          <addressOffset>0x4ac</addressOffset>
          <size>0x20</size>
        </register>
        <register>
          <name>FGCLUT.44</name>
          <addressOffset>0x4b0</addressOffset>
          <size>0x20</size>
        </register>
        <register>
          <name>FGCLUT.45</name>
          <addressOffset>0x4b4</addressOffset>
          <size>0x20</size>
        </register>
        <register>
          <name>FGCLUT.46</name>
          <addressOffset>0x4b8</addressOffset>
          <size>0x20</size>
        </register>
        <register>
          <name>FGCLUT.47</name>
          <addressOffset>0x4bc</addressOffset>
          <size>0x20</size>
        </register>
        <register>
          <name>FGCLUT.48</name>
          <addressOffset>0x4c0</addressOffset>
          <size>0x20</size>
        </register>
        <register>
          <name>FGCLUT.49</name>
          <addressOffset>0x4c4</addressOffset>
          <size>0x20</size>
        </register>
        <register>
          <name>FGCLUT.50</name>
          <addressOffset>0x4c8</addressOffset>
          <size>0x20</size>
        </register>
        <register>
          <name>FGCLUT.51</name>
          <addressOffset>0x4cc</addressOffset>
          <size>0x20</size>
        </register>
        <register>
          <name>FGCLUT.52</name>
          <addressOffset>0x4d0</addressOffset>
          <size>0x20</size>
        </register>
        <register>
          <name>FGCLUT.53</name>
          <addressOffset>0x4d4</addressOffset>
          <size>0x20</size>
        </register>
        <register>
          <name>FGCLUT.54</name>
          <addressOffset>0x4d8</addressOffset>
          <size>0x20</size>
        </register>
        <register>
          <name>FGCLUT.55</name>
          <addressOffset>0x4dc</addressOffset>
          <size>0x20</size>
        </register>
        <register>
          <name>FGCLUT.56</name>
          <addressOffset>0x4e0</addressOffset>
          <size>0x20</size>
        </register>
        <register>
          <name>FGCLUT.57</name>
          <addressOffset>0x4e4</addressOffset>
          <size>0x20</size>
        </register>
        <register>
          <name>FGCLUT.58</name>
          <addressOffset>0x4e8</addressOffset>
          <size>0x20</size>
        </register>
        <register>
          <name>FGCLUT.59</name>
          <addressOffset>0x4ec</addressOffset>
          <size>0x20</size>
        </register>
        <register>
          <name>FGCLUT.60</name>
          <addressOffset>0x4f0</addressOffset>
          <size>0x20</size>
        </register>
        <register>
          <name>FGCLUT.61</name>
          <addressOffset>0x4f4</addressOffset>
          <size>0x20</size>
        </register>
        <register>
          <name>FGCLUT.62</name>
          <addressOffset>0x4f8</addressOffset>
          <size>0x20</size>
        </register>
        <register>
          <name>FGCLUT.63</name>
          <addressOffset>0x4fc</addressOffset>
          <size>0x20</size>
        </register>
        <register>
          <name>FGCLUT.64</name>
          <addressOffset>0x500</addressOffset>
          <size>0x20</size>
        </register>
        <register>
          <name>FGCLUT.65</name>
          <addressOffset>0x504</addressOffset>
          <size>0x20</size>
        </register>
        <register>
          <name>FGCLUT.66</name>
          <addressOffset>0x508</addressOffset>
          <size>0x20</size>
        </register>
        <register>
          <name>FGCLUT.67</name>
          <addressOffset>0x50c</addressOffset>
          <size>0x20</size>
        </register>
        <register>
          <name>FGCLUT.68</name>
          <addressOffset>0x510</addressOffset>
          <size>0x20</size>
        </register>
        <register>
          <name>FGCLUT.69</name>
          <addressOffset>0x514</addressOffset>
          <size>0x20</size>
        </register>
        <register>
          <name>FGCLUT.70</name>
          <addressOffset>0x518</addressOffset>
          <size>0x20</size>
        </register>
        <register>
          <name>FGCLUT.71</name>
          <addressOffset>0x51c</addressOffset>
          <size>0x20</size>
        </register>
        <register>
          <name>FGCLUT.72</name>
          <addressOffset>0x520</addressOffset>
          <size>0x20</size>
        </register>
        <register>
          <name>FGCLUT.73</name>
          <addressOffset>0x524</addressOffset>
          <size>0x20</size>
        </register>
        <register>
          <name>FGCLUT.74</name>
          <addressOffset>0x528</addressOffset>
          <size>0x20</size>
        </register>
        <register>
          <name>FGCLUT.75</name>
          <addressOffset>0x52c</addressOffset>
          <size>0x20</size>
        </register>
        <register>
          <name>FGCLUT.76</name>
          <addressOffset>0x530</addressOffset>
          <size>0x20</size>
        </register>
        <register>
          <name>FGCLUT.77</name>
          <addressOffset>0x534</addressOffset>
          <size>0x20</size>
        </register>
        <register>
          <name>FGCLUT.78</name>
          <addressOffset>0x538</addressOffset>
          <size>0x20</size>
        </register>
        <register>
          <name>FGCLUT.79</name>
          <addressOffset>0x53c</addressOffset>
          <size>0x20</size>
        </register>
        <register>
          <name>FGCLUT.80</name>
          <addressOffset>0x540</addressOffset>
          <size>0x20</size>
        </register>
        <register>
          <name>FGCLUT.81</name>
          <addressOffset>0x544</addressOffset>
          <size>0x20</size>
        </register>
        <register>
          <name>FGCLUT.82</name>
          <addressOffset>0x548</addressOffset>
          <size>0x20</size>
        </register>
        <register>
          <name>FGCLUT.83</name>
          <addressOffset>0x54c</addressOffset>
          <size>0x20</size>
        </register>
        <register>
          <name>FGCLUT.84</name>
          <addressOffset>0x550</addressOffset>
          <size>0x20</size>
        </register>
        <register>
          <name>FGCLUT.85</name>
          <addressOffset>0x554</addressOffset>
          <size>0x20</size>
        </register>
        <register>
          <name>FGCLUT.86</name>
          <addressOffset>0x558</addressOffset>
          <size>0x20</size>
        </register>
        <register>
          <name>FGCLUT.87</name>
          <addressOffset>0x55c</addressOffset>
          <size>0x20</size>
        </register>
        <register>
          <name>FGCLUT.88</name>
          <addressOffset>0x560</addressOffset>
          <size>0x20</size>
        </register>
        <register>
          <name>FGCLUT.89</name>
          <addressOffset>0x564</addressOffset>
          <size>0x20</size>
        </register>
        <register>
          <name>FGCLUT.90</name>
          <addressOffset>0x568</addressOffset>
          <size>0x20</size>
        </register>
        <register>
          <name>FGCLUT.91</name>
          <addressOffset>0x56c</addressOffset>
          <size>0x20</size>
        </register>
        <register>
          <name>FGCLUT.92</name>
          <addressOffset>0x570</addressOffset>
          <size>0x20</size>
        </register>
        <register>
          <name>FGCLUT.93</name>
          <addressOffset>0x574</addressOffset>
          <size>0x20</size>
        </register>
        <register>
          <name>FGCLUT.94</name>
          <addressOffset>0x578</addressOffset>
          <size>0x20</size>
        </register>
        <register>
          <name>FGCLUT.95</name>
          <addressOffset>0x57c</addressOffset>
          <size>0x20</size>
        </register>
        <register>
          <name>FGCLUT.96</name>
          <addressOffset>0x580</addressOffset>
          <size>0x20</size>
        </register>
        <register>
          <name>FGCLUT.97</name>
          <addressOffset>0x584</addressOffset>
          <size>0x20</size>
        </register>
        <register>
          <name>FGCLUT.98</name>
          <addressOffset>0x588</addressOffset>
          <size>0x20</size>
        </register>
        <register>
          <name>FGCLUT.99</name>
          <addressOffset>0x58c</addressOffset>
          <size>0x20</size>
        </register>
        <register>
          <name>FGCLUT.100</name>
          <addressOffset>0x590</addressOffset>
          <size>0x20</size>
        </register>
        <register>
          <name>FGCLUT.101</name>
          <addressOffset>0x594</addressOffset>
          <size>0x20</size>
        </register>
        <register>
          <name>FGCLUT.102</name>
          <addressOffset>0x598</addressOffset>
          <size>0x20</size>
        </register>
        <register>
          <name>FGCLUT.103</name>
          <addressOffset>0x59c</addressOffset>
          <size>0x20</size>
        </register>
        <register>
          <name>FGCLUT.104</name>
          <addressOffset>0x5a0</addressOffset>
          <size>0x20</size>
        </register>
        <register>
          <name>FGCLUT.105</name>
          <addressOffset>0x5a4</addressOffset>
          <size>0x20</size>
        </register>
        <register>
          <name>FGCLUT.106</name>
          <addressOffset>0x5a8</addressOffset>
          <size>0x20</size>
        </register>
        <register>
          <name>FGCLUT.107</name>
          <addressOffset>0x5ac</addressOffset>
          <size>0x20</size>
        </register>
        <register>
          <name>FGCLUT.108</name>
          <addressOffset>0x5b0</addressOffset>
          <size>0x20</size>
        </register>
        <register>
          <name>FGCLUT.109</name>
          <addressOffset>0x5b4</addressOffset>
          <size>0x20</size>
        </register>
        <register>
          <name>FGCLUT.110</name>
          <addressOffset>0x5b8</addressOffset>
          <size>0x20</size>
        </register>
        <register>
          <name>FGCLUT.111</name>
          <addressOffset>0x5bc</addressOffset>
          <size>0x20</size>
        </register>
        <register>
          <name>FGCLUT.112</name>
          <addressOffset>0x5c0</addressOffset>
          <size>0x20</size>
        </register>
        <register>
          <name>FGCLUT.113</name>
          <addressOffset>0x5c4</addressOffset>
          <size>0x20</size>
        </register>
        <register>
          <name>FGCLUT.114</name>
          <addressOffset>0x5c8</addressOffset>
          <size>0x20</size>
        </register>
        <register>
          <name>FGCLUT.115</name>
          <addressOffset>0x5cc</addressOffset>
          <size>0x20</size>
        </register>
        <register>
          <name>FGCLUT.116</name>
          <addressOffset>0x5d0</addressOffset>
          <size>0x20</size>
        </register>
        <register>
          <name>FGCLUT.117</name>
          <addressOffset>0x5d4</addressOffset>
          <size>0x20</size>
        </register>
        <register>
          <name>FGCLUT.118</name>
          <addressOffset>0x5d8</addressOffset>
          <size>0x20</size>
        </register>
        <register>
          <name>FGCLUT.119</name>
          <addressOffset>0x5dc</addressOffset>
          <size>0x20</size>
        </register>
        <register>
          <name>FGCLUT.120</name>
          <addressOffset>0x5e0</addressOffset>
          <size>0x20</size>
        </register>
        <register>
          <name>FGCLUT.121</name>
          <addressOffset>0x5e4</addressOffset>
          <size>0x20</size>
        </register>
        <register>
          <name>FGCLUT.122</name>
          <addressOffset>0x5e8</addressOffset>
          <size>0x20</size>
        </register>
        <register>
          <name>FGCLUT.123</name>
          <addressOffset>0x5ec</addressOffset>
          <size>0x20</size>
        </register>
        <register>
          <name>FGCLUT.124</name>
          <addressOffset>0x5f0</addressOffset>
          <size>0x20</size>
        </register>
        <register>
          <name>FGCLUT.125</name>
          <addressOffset>0x5f4</addressOffset>
          <size>0x20</size>
        </register>
        <register>
          <name>FGCLUT.126</name>
          <addressOffset>0x5f8</addressOffset>
          <size>0x20</size>
        </register>
        <register>
          <name>FGCLUT.127</name>
          <addressOffset>0x5fc</addressOffset>
          <size>0x20</size>
        </register>
        <register>
          <name>FGCLUT.128</name>
          <addressOffset>0x600</addressOffset>
          <size>0x20</size>
        </register>
        <register>
          <name>FGCLUT.129</name>
          <addressOffset>0x604</addressOffset>
          <size>0x20</size>
        </register>
        <register>
          <name>FGCLUT.130</name>
          <addressOffset>0x608</addressOffset>
          <size>0x20</size>
        </register>
        <register>
          <name>FGCLUT.131</name>
          <addressOffset>0x60c</addressOffset>
          <size>0x20</size>
        </register>
        <register>
          <name>FGCLUT.132</name>
          <addressOffset>0x610</addressOffset>
          <size>0x20</size>
        </register>
        <register>
          <name>FGCLUT.133</name>
          <addressOffset>0x614</addressOffset>
          <size>0x20</size>
        </register>
        <register>
          <name>FGCLUT.134</name>
          <addressOffset>0x618</addressOffset>
          <size>0x20</size>
        </register>
        <register>
          <name>FGCLUT.135</name>
          <addressOffset>0x61c</addressOffset>
          <size>0x20</size>
        </register>
        <register>
          <name>FGCLUT.136</name>
          <addressOffset>0x620</addressOffset>
          <size>0x20</size>
        </register>
        <register>
          <name>FGCLUT.137</name>
          <addressOffset>0x624</addressOffset>
          <size>0x20</size>
        </register>
        <register>
          <name>FGCLUT.138</name>
          <addressOffset>0x628</addressOffset>
          <size>0x20</size>
        </register>
        <register>
          <name>FGCLUT.139</name>
          <addressOffset>0x62c</addressOffset>
          <size>0x20</size>
        </register>
        <register>
          <name>FGCLUT.140</name>
          <addressOffset>0x630</addressOffset>
          <size>0x20</size>
        </register>
        <register>
          <name>FGCLUT.141</name>
          <addressOffset>0x634</addressOffset>
          <size>0x20</size>
        </register>
        <register>
          <name>FGCLUT.142</name>
          <addressOffset>0x638</addressOffset>
          <size>0x20</size>
        </register>
        <register>
          <name>FGCLUT.143</name>
          <addressOffset>0x63c</addressOffset>
          <size>0x20</size>
        </register>
        <register>
          <name>FGCLUT.144</name>
          <addressOffset>0x640</addressOffset>
          <size>0x20</size>
        </register>
        <register>
          <name>FGCLUT.145</name>
          <addressOffset>0x644</addressOffset>
          <size>0x20</size>
        </register>
        <register>
          <name>FGCLUT.146</name>
          <addressOffset>0x648</addressOffset>
          <size>0x20</size>
        </register>
        <register>
          <name>FGCLUT.147</name>
          <addressOffset>0x64c</addressOffset>
          <size>0x20</size>
        </register>
        <register>
          <name>FGCLUT.148</name>
          <addressOffset>0x650</addressOffset>
          <size>0x20</size>
        </register>
        <register>
          <name>FGCLUT.149</name>
          <addressOffset>0x654</addressOffset>
          <size>0x20</size>
        </register>
        <register>
          <name>FGCLUT.150</name>
          <addressOffset>0x658</addressOffset>
          <size>0x20</size>
        </register>
        <register>
          <name>FGCLUT.151</name>
          <addressOffset>0x65c</addressOffset>
          <size>0x20</size>
        </register>
        <register>
          <name>FGCLUT.152</name>
          <addressOffset>0x660</addressOffset>
          <size>0x20</size>
        </register>
        <register>
          <name>FGCLUT.153</name>
          <addressOffset>0x664</addressOffset>
          <size>0x20</size>
        </register>
        <register>
          <name>FGCLUT.154</name>
          <addressOffset>0x668</addressOffset>
          <size>0x20</size>
        </register>
        <register>
          <name>FGCLUT.155</name>
          <addressOffset>0x66c</addressOffset>
          <size>0x20</size>
        </register>
        <register>
          <name>FGCLUT.156</name>
          <addressOffset>0x670</addressOffset>
          <size>0x20</size>
        </register>
        <register>
          <name>FGCLUT.157</name>
          <addressOffset>0x674</addressOffset>
          <size>0x20</size>
        </register>
        <register>
          <name>FGCLUT.158</name>
          <addressOffset>0x678</addressOffset>
          <size>0x20</size>
        </register>
        <register>
          <name>FGCLUT.159</name>
          <addressOffset>0x67c</addressOffset>
          <size>0x20</size>
        </register>
        <register>
          <name>FGCLUT.160</name>
          <addressOffset>0x680</addressOffset>
          <size>0x20</size>
        </register>
        <register>
          <name>FGCLUT.161</name>
          <addressOffset>0x684</addressOffset>
          <size>0x20</size>
        </register>
        <register>
          <name>FGCLUT.162</name>
          <addressOffset>0x688</addressOffset>
          <size>0x20</size>
        </register>
        <register>
          <name>FGCLUT.163</name>
          <addressOffset>0x68c</addressOffset>
          <size>0x20</size>
        </register>
        <register>
          <name>FGCLUT.164</name>
          <addressOffset>0x690</addressOffset>
          <size>0x20</size>
        </register>
        <register>
          <name>FGCLUT.165</name>
          <addressOffset>0x694</addressOffset>
          <size>0x20</size>
        </register>
        <register>
          <name>FGCLUT.166</name>
          <addressOffset>0x698</addressOffset>
          <size>0x20</size>
        </register>
        <register>
          <name>FGCLUT.167</name>
          <addressOffset>0x69c</addressOffset>
          <size>0x20</size>
        </register>
        <register>
          <name>FGCLUT.168</name>
          <addressOffset>0x6a0</addressOffset>
          <size>0x20</size>
        </register>
        <register>
          <name>FGCLUT.169</name>
          <addressOffset>0x6a4</addressOffset>
          <size>0x20</size>
        </register>
        <register>
          <name>FGCLUT.170</name>
          <addressOffset>0x6a8</addressOffset>
          <size>0x20</size>
        </register>
        <register>
          <name>FGCLUT.171</name>
          <addressOffset>0x6ac</addressOffset>
          <size>0x20</size>
        </register>
        <register>
          <name>FGCLUT.172</name>
          <addressOffset>0x6b0</addressOffset>
          <size>0x20</size>
        </register>
        <register>
          <name>FGCLUT.173</name>
          <addressOffset>0x6b4</addressOffset>
          <size>0x20</size>
        </register>
        <register>
          <name>FGCLUT.174</name>
          <addressOffset>0x6b8</addressOffset>
          <size>0x20</size>
        </register>
        <register>
          <name>FGCLUT.175</name>
          <addressOffset>0x6bc</addressOffset>
          <size>0x20</size>
        </register>
        <register>
          <name>FGCLUT.176</name>
          <addressOffset>0x6c0</addressOffset>
          <size>0x20</size>
        </register>
        <register>
          <name>FGCLUT.177</name>
          <addressOffset>0x6c4</addressOffset>
          <size>0x20</size>
        </register>
        <register>
          <name>FGCLUT.178</name>
          <addressOffset>0x6c8</addressOffset>
          <size>0x20</size>
        </register>
        <register>
          <name>FGCLUT.179</name>
          <addressOffset>0x6cc</addressOffset>
          <size>0x20</size>
        </register>
        <register>
          <name>FGCLUT.180</name>
          <addressOffset>0x6d0</addressOffset>
          <size>0x20</size>
        </register>
        <register>
          <name>FGCLUT.181</name>
          <addressOffset>0x6d4</addressOffset>
          <size>0x20</size>
        </register>
        <register>
          <name>FGCLUT.182</name>
          <addressOffset>0x6d8</addressOffset>
          <size>0x20</size>
        </register>
        <register>
          <name>FGCLUT.183</name>
          <addressOffset>0x6dc</addressOffset>
          <size>0x20</size>
        </register>
        <register>
          <name>FGCLUT.184</name>
          <addressOffset>0x6e0</addressOffset>
          <size>0x20</size>
        </register>
        <register>
          <name>FGCLUT.185</name>
          <addressOffset>0x6e4</addressOffset>
          <size>0x20</size>
        </register>
        <register>
          <name>FGCLUT.186</name>
          <addressOffset>0x6e8</addressOffset>
          <size>0x20</size>
        </register>
        <register>
          <name>FGCLUT.187</name>
          <addressOffset>0x6ec</addressOffset>
          <size>0x20</size>
        </register>
        <register>
          <name>FGCLUT.188</name>
          <addressOffset>0x6f0</addressOffset>
          <size>0x20</size>
        </register>
        <register>
          <name>FGCLUT.189</name>
          <addressOffset>0x6f4</addressOffset>
          <size>0x20</size>
        </register>
        <register>
          <name>FGCLUT.190</name>
          <addressOffset>0x6f8</addressOffset>
          <size>0x20</size>
        </register>
        <register>
          <name>FGCLUT.191</name>
          <addressOffset>0x6fc</addressOffset>
          <size>0x20</size>
        </register>
        <register>
          <name>FGCLUT.192</name>
          <addressOffset>0x700</addressOffset>
          <size>0x20</size>
        </register>
        <register>
          <name>FGCLUT.193</name>
          <addressOffset>0x704</addressOffset>
          <size>0x20</size>
        </register>
        <register>
          <name>FGCLUT.194</name>
          <addressOffset>0x708</addressOffset>
          <size>0x20</size>
        </register>
        <register>
          <name>FGCLUT.195</name>
          <addressOffset>0x70c</addressOffset>
          <size>0x20</size>
        </register>
        <register>
          <name>FGCLUT.196</name>
          <addressOffset>0x710</addressOffset>
          <size>0x20</size>
        </register>
        <register>
          <name>FGCLUT.197</name>
          <addressOffset>0x714</addressOffset>
          <size>0x20</size>
        </register>
        <register>
          <name>FGCLUT.198</name>
          <addressOffset>0x718</addressOffset>
          <size>0x20</size>
        </register>
        <register>
          <name>FGCLUT.199</name>
          <addressOffset>0x71c</addressOffset>
          <size>0x20</size>
        </register>
        <register>
          <name>FGCLUT.200</name>
          <addressOffset>0x720</addressOffset>
          <size>0x20</size>
        </register>
        <register>
          <name>FGCLUT.201</name>
          <addressOffset>0x724</addressOffset>
          <size>0x20</size>
        </register>
        <register>
          <name>FGCLUT.202</name>
          <addressOffset>0x728</addressOffset>
          <size>0x20</size>
        </register>
        <register>
          <name>FGCLUT.203</name>
          <addressOffset>0x72c</addressOffset>
          <size>0x20</size>
        </register>
        <register>
          <name>FGCLUT.204</name>
          <addressOffset>0x730</addressOffset>
          <size>0x20</size>
        </register>
        <register>
          <name>FGCLUT.205</name>
          <addressOffset>0x734</addressOffset>
          <size>0x20</size>
        </register>
        <register>
          <name>FGCLUT.206</name>
          <addressOffset>0x738</addressOffset>
          <size>0x20</size>
        </register>
        <register>
          <name>FGCLUT.207</name>
          <addressOffset>0x73c</addressOffset>
          <size>0x20</size>
        </register>
        <register>
          <name>FGCLUT.208</name>
          <addressOffset>0x740</addressOffset>
          <size>0x20</size>
        </register>
        <register>
          <name>FGCLUT.209</name>
          <addressOffset>0x744</addressOffset>
          <size>0x20</size>
        </register>
        <register>
          <name>FGCLUT.210</name>
          <addressOffset>0x748</addressOffset>
          <size>0x20</size>
        </register>
        <register>
          <name>FGCLUT.211</name>
          <addressOffset>0x74c</addressOffset>
          <size>0x20</size>
        </register>
        <register>
          <name>FGCLUT.212</name>
          <addressOffset>0x750</addressOffset>
          <size>0x20</size>
        </register>
        <register>
          <name>FGCLUT.213</name>
          <addressOffset>0x754</addressOffset>
          <size>0x20</size>
        </register>
        <register>
          <name>FGCLUT.214</name>
          <addressOffset>0x758</addressOffset>
          <size>0x20</size>
        </register>
        <register>
          <name>FGCLUT.215</name>
          <addressOffset>0x75c</addressOffset>
          <size>0x20</size>
        </register>
        <register>
          <name>FGCLUT.216</name>
          <addressOffset>0x760</addressOffset>
          <size>0x20</size>
        </register>
        <register>
          <name>FGCLUT.217</name>
          <addressOffset>0x764</addressOffset>
          <size>0x20</size>
        </register>
        <register>
          <name>FGCLUT.218</name>
          <addressOffset>0x768</addressOffset>
          <size>0x20</size>
        </register>
        <register>
          <name>FGCLUT.219</name>
          <addressOffset>0x76c</addressOffset>
          <size>0x20</size>
        </register>
        <register>
          <name>FGCLUT.220</name>
          <addressOffset>0x770</addressOffset>
          <size>0x20</size>
        </register>
        <register>
          <name>FGCLUT.221</name>
          <addressOffset>0x774</addressOffset>
          <size>0x20</size>
        </register>
        <register>
          <name>FGCLUT.222</name>
          <addressOffset>0x778</addressOffset>
          <size>0x20</size>
        </register>
        <register>
          <name>FGCLUT.223</name>
          <addressOffset>0x77c</addressOffset>
          <size>0x20</size>
        </register>
        <register>
          <name>FGCLUT.224</name>
          <addressOffset>0x780</addressOffset>
          <size>0x20</size>
        </register>
        <register>
          <name>FGCLUT.225</name>
          <addressOffset>0x784</addressOffset>
          <size>0x20</size>
        </register>
        <register>
          <name>FGCLUT.226</name>
          <addressOffset>0x788</addressOffset>
          <size>0x20</size>
        </register>
        <register>
          <name>FGCLUT.227</name>
          <addressOffset>0x78c</addressOffset>
          <size>0x20</size>
        </register>
        <register>
          <name>FGCLUT.228</name>
          <addressOffset>0x790</addressOffset>
          <size>0x20</size>
        </register>
        <register>
          <name>FGCLUT.229</name>
          <addressOffset>0x794</addressOffset>
          <size>0x20</size>
        </register>
        <register>
          <name>FGCLUT.230</name>
          <addressOffset>0x798</addressOffset>
          <size>0x20</size>
        </register>
        <register>
          <name>FGCLUT.231</name>
          <addressOffset>0x79c</addressOffset>
          <size>0x20</size>
        </register>
        <register>
          <name>FGCLUT.232</name>
          <addressOffset>0x7a0</addressOffset>
          <size>0x20</size>
        </register>
        <register>
          <name>FGCLUT.233</name>
          <addressOffset>0x7a4</addressOffset>
          <size>0x20</size>
        </register>
        <register>
          <name>FGCLUT.234</name>
          <addressOffset>0x7a8</addressOffset>
          <size>0x20</size>
        </register>
        <register>
          <name>FGCLUT.235</name>
          <addressOffset>0x7ac</addressOffset>
          <size>0x20</size>
        </register>
        <register>
          <name>FGCLUT.236</name>
          <addressOffset>0x7b0</addressOffset>
          <size>0x20</size>
        </register>
        <register>
          <name>FGCLUT.237</name>
          <addressOffset>0x7b4</addressOffset>
          <size>0x20</size>
        </register>
        <register>
          <name>FGCLUT.238</name>
          <addressOffset>0x7b8</addressOffset>
          <size>0x20</size>
        </register>
        <register>
          <name>FGCLUT.239</name>
          <addressOffset>0x7bc</addressOffset>
          <size>0x20</size>
        </register>
        <register>
          <name>FGCLUT.240</name>
          <addressOffset>0x7c0</addressOffset>
          <size>0x20</size>
        </register>
        <register>
          <name>FGCLUT.241</name>
          <addressOffset>0x7c4</addressOffset>
          <size>0x20</size>
        </register>
        <register>
          <name>FGCLUT.242</name>
          <addressOffset>0x7c8</addressOffset>
          <size>0x20</size>
        </register>
        <register>
          <name>FGCLUT.243</name>
          <addressOffset>0x7cc</addressOffset>
          <size>0x20</size>
        </register>
        <register>
          <name>FGCLUT.244</name>
          <addressOffset>0x7d0</addressOffset>
          <size>0x20</size>
        </register>
        <register>
          <name>FGCLUT.245</name>
          <addressOffset>0x7d4</addressOffset>
          <size>0x20</size>
        </register>
        <register>
          <name>FGCLUT.246</name>
          <addressOffset>0x7d8</addressOffset>
          <size>0x20</size>
        </register>
        <register>
          <name>FGCLUT.247</name>
          <addressOffset>0x7dc</addressOffset>
          <size>0x20</size>
        </register>
        <register>
          <name>FGCLUT.248</name>
          <addressOffset>0x7e0</addressOffset>
          <size>0x20</size>
        </register>
        <register>
          <name>FGCLUT.249</name>
          <addressOffset>0x7e4</addressOffset>
          <size>0x20</size>
        </register>
        <register>
          <name>FGCLUT.250</name>
          <addressOffset>0x7e8</addressOffset>
          <size>0x20</size>
        </register>
        <register>
          <name>FGCLUT.251</name>
          <addressOffset>0x7ec</addressOffset>
          <size>0x20</size>
        </register>
        <register>
          <name>FGCLUT.252</name>
          <addressOffset>0x7f0</addressOffset>
          <size>0x20</size>
        </register>
        <register>
          <name>FGCLUT.253</name>
          <addressOffset>0x7f4</addressOffset>
          <size>0x20</size>
        </register>
        <register>
          <name>FGCLUT.254</name>
          <addressOffset>0x7f8</addressOffset>
          <size>0x20</size>
        </register>
        <register>
          <name>FGCLUT.255</name>
          <addressOffset>0x7fc</addressOffset>
          <size>0x20</size>
        </register>
        <register>
          <name>BGCLUT.0</name>
          <addressOffset>0x800</addressOffset>
          <size>0x20</size>
        </register>
        <register>
          <name>BGCLUT.1</name>
          <addressOffset>0x804</addressOffset>
          <size>0x20</size>
        </register>
        <register>
          <name>BGCLUT.2</name>
          <addressOffset>0x808</addressOffset>
          <size>0x20</size>
        </register>
        <register>
          <name>BGCLUT.3</name>
          <addressOffset>0x80c</addressOffset>
          <size>0x20</size>
        </register>
        <register>
          <name>BGCLUT.4</name>
          <addressOffset>0x810</addressOffset>
          <size>0x20</size>
        </register>
        <register>
          <name>BGCLUT.5</name>
          <addressOffset>0x814</addressOffset>
          <size>0x20</size>
        </register>
        <register>
          <name>BGCLUT.6</name>
          <addressOffset>0x818</addressOffset>
          <size>0x20</size>
        </register>
        <register>
          <name>BGCLUT.7</name>
          <addressOffset>0x81c</addressOffset>
          <size>0x20</size>
        </register>
        <register>
          <name>BGCLUT.8</name>
          <addressOffset>0x820</addressOffset>
          <size>0x20</size>
        </register>
        <register>
          <name>BGCLUT.9</name>
          <addressOffset>0x824</addressOffset>
          <size>0x20</size>
        </register>
        <register>
          <name>BGCLUT.10</name>
          <addressOffset>0x828</addressOffset>
          <size>0x20</size>
        </register>
        <register>
          <name>BGCLUT.11</name>
          <addressOffset>0x82c</addressOffset>
          <size>0x20</size>
        </register>
        <register>
          <name>BGCLUT.12</name>
          <addressOffset>0x830</addressOffset>
          <size>0x20</size>
        </register>
        <register>
          <name>BGCLUT.13</name>
          <addressOffset>0x834</addressOffset>
          <size>0x20</size>
        </register>
        <register>
          <name>BGCLUT.14</name>
          <addressOffset>0x838</addressOffset>
          <size>0x20</size>
        </register>
        <register>
          <name>BGCLUT.15</name>
          <addressOffset>0x83c</addressOffset>
          <size>0x20</size>
        </register>
        <register>
          <name>BGCLUT.16</name>
          <addressOffset>0x840</addressOffset>
          <size>0x20</size>
        </register>
        <register>
          <name>BGCLUT.17</name>
          <addressOffset>0x844</addressOffset>
          <size>0x20</size>
        </register>
        <register>
          <name>BGCLUT.18</name>
          <addressOffset>0x848</addressOffset>
          <size>0x20</size>
        </register>
        <register>
          <name>BGCLUT.19</name>
          <addressOffset>0x84c</addressOffset>
          <size>0x20</size>
        </register>
        <register>
          <name>BGCLUT.20</name>
          <addressOffset>0x850</addressOffset>
          <size>0x20</size>
        </register>
        <register>
          <name>BGCLUT.21</name>
          <addressOffset>0x854</addressOffset>
          <size>0x20</size>
        </register>
        <register>
          <name>BGCLUT.22</name>
          <addressOffset>0x858</addressOffset>
          <size>0x20</size>
        </register>
        <register>
          <name>BGCLUT.23</name>
          <addressOffset>0x85c</addressOffset>
          <size>0x20</size>
        </register>
        <register>
          <name>BGCLUT.24</name>
          <addressOffset>0x860</addressOffset>
          <size>0x20</size>
        </register>
        <register>
          <name>BGCLUT.25</name>
          <addressOffset>0x864</addressOffset>
          <size>0x20</size>
        </register>
        <register>
          <name>BGCLUT.26</name>
          <addressOffset>0x868</addressOffset>
          <size>0x20</size>
        </register>
        <register>
          <name>BGCLUT.27</name>
          <addressOffset>0x86c</addressOffset>
          <size>0x20</size>
        </register>
        <register>
          <name>BGCLUT.28</name>
          <addressOffset>0x870</addressOffset>
          <size>0x20</size>
        </register>
        <register>
          <name>BGCLUT.29</name>
          <addressOffset>0x874</addressOffset>
          <size>0x20</size>
        </register>
        <register>
          <name>BGCLUT.30</name>
          <addressOffset>0x878</addressOffset>
          <size>0x20</size>
        </register>
        <register>
          <name>BGCLUT.31</name>
          <addressOffset>0x87c</addressOffset>
          <size>0x20</size>
        </register>
        <register>
          <name>BGCLUT.32</name>
          <addressOffset>0x880</addressOffset>
          <size>0x20</size>
        </register>
        <register>
          <name>BGCLUT.33</name>
          <addressOffset>0x884</addressOffset>
          <size>0x20</size>
        </register>
        <register>
          <name>BGCLUT.34</name>
          <addressOffset>0x888</addressOffset>
          <size>0x20</size>
        </register>
        <register>
          <name>BGCLUT.35</name>
          <addressOffset>0x88c</addressOffset>
          <size>0x20</size>
        </register>
        <register>
          <name>BGCLUT.36</name>
          <addressOffset>0x890</addressOffset>
          <size>0x20</size>
        </register>
        <register>
          <name>BGCLUT.37</name>
          <addressOffset>0x894</addressOffset>
          <size>0x20</size>
        </register>
        <register>
          <name>BGCLUT.38</name>
          <addressOffset>0x898</addressOffset>
          <size>0x20</size>
        </register>
        <register>
          <name>BGCLUT.39</name>
          <addressOffset>0x89c</addressOffset>
          <size>0x20</size>
        </register>
        <register>
          <name>BGCLUT.40</name>
          <addressOffset>0x8a0</addressOffset>
          <size>0x20</size>
        </register>
        <register>
          <name>BGCLUT.41</name>
          <addressOffset>0x8a4</addressOffset>
          <size>0x20</size>
        </register>
        <register>
          <name>BGCLUT.42</name>
          <addressOffset>0x8a8</addressOffset>
          <size>0x20</size>
        </register>
        <register>
          <name>BGCLUT.43</name>
          <addressOffset>0x8ac</addressOffset>
          <size>0x20</size>
        </register>
        <register>
          <name>BGCLUT.44</name>
          <addressOffset>0x8b0</addressOffset>
          <size>0x20</size>
        </register>
        <register>
          <name>BGCLUT.45</name>
          <addressOffset>0x8b4</addressOffset>
          <size>0x20</size>
        </register>
        <register>
          <name>BGCLUT.46</name>
          <addressOffset>0x8b8</addressOffset>
          <size>0x20</size>
        </register>
        <register>
          <name>BGCLUT.47</name>
          <addressOffset>0x8bc</addressOffset>
          <size>0x20</size>
        </register>
        <register>
          <name>BGCLUT.48</name>
          <addressOffset>0x8c0</addressOffset>
          <size>0x20</size>
        </register>
        <register>
          <name>BGCLUT.49</name>
          <addressOffset>0x8c4</addressOffset>
          <size>0x20</size>
        </register>
        <register>
          <name>BGCLUT.50</name>
          <addressOffset>0x8c8</addressOffset>
          <size>0x20</size>
        </register>
        <register>
          <name>BGCLUT.51</name>
          <addressOffset>0x8cc</addressOffset>
          <size>0x20</size>
        </register>
        <register>
          <name>BGCLUT.52</name>
          <addressOffset>0x8d0</addressOffset>
          <size>0x20</size>
        </register>
        <register>
          <name>BGCLUT.53</name>
          <addressOffset>0x8d4</addressOffset>
          <size>0x20</size>
        </register>
        <register>
          <name>BGCLUT.54</name>
          <addressOffset>0x8d8</addressOffset>
          <size>0x20</size>
        </register>
        <register>
          <name>BGCLUT.55</name>
          <addressOffset>0x8dc</addressOffset>
          <size>0x20</size>
        </register>
        <register>
          <name>BGCLUT.56</name>
          <addressOffset>0x8e0</addressOffset>
          <size>0x20</size>
        </register>
        <register>
          <name>BGCLUT.57</name>
          <addressOffset>0x8e4</addressOffset>
          <size>0x20</size>
        </register>
        <register>
          <name>BGCLUT.58</name>
          <addressOffset>0x8e8</addressOffset>
          <size>0x20</size>
        </register>
        <register>
          <name>BGCLUT.59</name>
          <addressOffset>0x8ec</addressOffset>
          <size>0x20</size>
        </register>
        <register>
          <name>BGCLUT.60</name>
          <addressOffset>0x8f0</addressOffset>
          <size>0x20</size>
        </register>
        <register>
          <name>BGCLUT.61</name>
          <addressOffset>0x8f4</addressOffset>
          <size>0x20</size>
        </register>
        <register>
          <name>BGCLUT.62</name>
          <addressOffset>0x8f8</addressOffset>
          <size>0x20</size>
        </register>
        <register>
          <name>BGCLUT.63</name>
          <addressOffset>0x8fc</addressOffset>
          <size>0x20</size>
        </register>
        <register>
          <name>BGCLUT.64</name>
          <addressOffset>0x900</addressOffset>
          <size>0x20</size>
        </register>
        <register>
          <name>BGCLUT.65</name>
          <addressOffset>0x904</addressOffset>
          <size>0x20</size>
        </register>
        <register>
          <name>BGCLUT.66</name>
          <addressOffset>0x908</addressOffset>
          <size>0x20</size>
        </register>
        <register>
          <name>BGCLUT.67</name>
          <addressOffset>0x90c</addressOffset>
          <size>0x20</size>
        </register>
        <register>
          <name>BGCLUT.68</name>
          <addressOffset>0x910</addressOffset>
          <size>0x20</size>
        </register>
        <register>
          <name>BGCLUT.69</name>
          <addressOffset>0x914</addressOffset>
          <size>0x20</size>
        </register>
        <register>
          <name>BGCLUT.70</name>
          <addressOffset>0x918</addressOffset>
          <size>0x20</size>
        </register>
        <register>
          <name>BGCLUT.71</name>
          <addressOffset>0x91c</addressOffset>
          <size>0x20</size>
        </register>
        <register>
          <name>BGCLUT.72</name>
          <addressOffset>0x920</addressOffset>
          <size>0x20</size>
        </register>
        <register>
          <name>BGCLUT.73</name>
          <addressOffset>0x924</addressOffset>
          <size>0x20</size>
        </register>
        <register>
          <name>BGCLUT.74</name>
          <addressOffset>0x928</addressOffset>
          <size>0x20</size>
        </register>
        <register>
          <name>BGCLUT.75</name>
          <addressOffset>0x92c</addressOffset>
          <size>0x20</size>
        </register>
        <register>
          <name>BGCLUT.76</name>
          <addressOffset>0x930</addressOffset>
          <size>0x20</size>
        </register>
        <register>
          <name>BGCLUT.77</name>
          <addressOffset>0x934</addressOffset>
          <size>0x20</size>
        </register>
        <register>
          <name>BGCLUT.78</name>
          <addressOffset>0x938</addressOffset>
          <size>0x20</size>
        </register>
        <register>
          <name>BGCLUT.79</name>
          <addressOffset>0x93c</addressOffset>
          <size>0x20</size>
        </register>
        <register>
          <name>BGCLUT.80</name>
          <addressOffset>0x940</addressOffset>
          <size>0x20</size>
        </register>
        <register>
          <name>BGCLUT.81</name>
          <addressOffset>0x944</addressOffset>
          <size>0x20</size>
        </register>
        <register>
          <name>BGCLUT.82</name>
          <addressOffset>0x948</addressOffset>
          <size>0x20</size>
        </register>
        <register>
          <name>BGCLUT.83</name>
          <addressOffset>0x94c</addressOffset>
          <size>0x20</size>
        </register>
        <register>
          <name>BGCLUT.84</name>
          <addressOffset>0x950</addressOffset>
          <size>0x20</size>
        </register>
        <register>
          <name>BGCLUT.85</name>
          <addressOffset>0x954</addressOffset>
          <size>0x20</size>
        </register>
        <register>
          <name>BGCLUT.86</name>
          <addressOffset>0x958</addressOffset>
          <size>0x20</size>
        </register>
        <register>
          <name>BGCLUT.87</name>
          <addressOffset>0x95c</addressOffset>
          <size>0x20</size>
        </register>
        <register>
          <name>BGCLUT.88</name>
          <addressOffset>0x960</addressOffset>
          <size>0x20</size>
        </register>
        <register>
          <name>BGCLUT.89</name>
          <addressOffset>0x964</addressOffset>
          <size>0x20</size>
        </register>
        <register>
          <name>BGCLUT.90</name>
          <addressOffset>0x968</addressOffset>
          <size>0x20</size>
        </register>
        <register>
          <name>BGCLUT.91</name>
          <addressOffset>0x96c</addressOffset>
          <size>0x20</size>
        </register>
        <register>
          <name>BGCLUT.92</name>
          <addressOffset>0x970</addressOffset>
          <size>0x20</size>
        </register>
        <register>
          <name>BGCLUT.93</name>
          <addressOffset>0x974</addressOffset>
          <size>0x20</size>
        </register>
        <register>
          <name>BGCLUT.94</name>
          <addressOffset>0x978</addressOffset>
          <size>0x20</size>
        </register>
        <register>
          <name>BGCLUT.95</name>
          <addressOffset>0x97c</addressOffset>
          <size>0x20</size>
        </register>
        <register>
          <name>BGCLUT.96</name>
          <addressOffset>0x980</addressOffset>
          <size>0x20</size>
        </register>
        <register>
          <name>BGCLUT.97</name>
          <addressOffset>0x984</addressOffset>
          <size>0x20</size>
        </register>
        <register>
          <name>BGCLUT.98</name>
          <addressOffset>0x988</addressOffset>
          <size>0x20</size>
        </register>
        <register>
          <name>BGCLUT.99</name>
          <addressOffset>0x98c</addressOffset>
          <size>0x20</size>
        </register>
        <register>
          <name>BGCLUT.100</name>
          <addressOffset>0x990</addressOffset>
          <size>0x20</size>
        </register>
        <register>
          <name>BGCLUT.101</name>
          <addressOffset>0x994</addressOffset>
          <size>0x20</size>
        </register>
        <register>
          <name>BGCLUT.102</name>
          <addressOffset>0x998</addressOffset>
          <size>0x20</size>
        </register>
        <register>
          <name>BGCLUT.103</name>
          <addressOffset>0x99c</addressOffset>
          <size>0x20</size>
        </register>
        <register>
          <name>BGCLUT.104</name>
          <addressOffset>0x9a0</addressOffset>
          <size>0x20</size>
        </register>
        <register>
          <name>BGCLUT.105</name>
          <addressOffset>0x9a4</addressOffset>
          <size>0x20</size>
        </register>
        <register>
          <name>BGCLUT.106</name>
          <addressOffset>0x9a8</addressOffset>
          <size>0x20</size>
        </register>
        <register>
          <name>BGCLUT.107</name>
          <addressOffset>0x9ac</addressOffset>
          <size>0x20</size>
        </register>
        <register>
          <name>BGCLUT.108</name>
          <addressOffset>0x9b0</addressOffset>
          <size>0x20</size>
        </register>
        <register>
          <name>BGCLUT.109</name>
          <addressOffset>0x9b4</addressOffset>
          <size>0x20</size>
        </register>
        <register>
          <name>BGCLUT.110</name>
          <addressOffset>0x9b8</addressOffset>
          <size>0x20</size>
        </register>
        <register>
          <name>BGCLUT.111</name>
          <addressOffset>0x9bc</addressOffset>
          <size>0x20</size>
        </register>
        <register>
          <name>BGCLUT.112</name>
          <addressOffset>0x9c0</addressOffset>
          <size>0x20</size>
        </register>
        <register>
          <name>BGCLUT.113</name>
          <addressOffset>0x9c4</addressOffset>
          <size>0x20</size>
        </register>
        <register>
          <name>BGCLUT.114</name>
          <addressOffset>0x9c8</addressOffset>
          <size>0x20</size>
        </register>
        <register>
          <name>BGCLUT.115</name>
          <addressOffset>0x9cc</addressOffset>
          <size>0x20</size>
        </register>
        <register>
          <name>BGCLUT.116</name>
          <addressOffset>0x9d0</addressOffset>
          <size>0x20</size>
        </register>
        <register>
          <name>BGCLUT.117</name>
          <addressOffset>0x9d4</addressOffset>
          <size>0x20</size>
        </register>
        <register>
          <name>BGCLUT.118</name>
          <addressOffset>0x9d8</addressOffset>
          <size>0x20</size>
        </register>
        <register>
          <name>BGCLUT.119</name>
          <addressOffset>0x9dc</addressOffset>
          <size>0x20</size>
        </register>
        <register>
          <name>BGCLUT.120</name>
          <addressOffset>0x9e0</addressOffset>
          <size>0x20</size>
        </register>
        <register>
          <name>BGCLUT.121</name>
          <addressOffset>0x9e4</addressOffset>
          <size>0x20</size>
        </register>
        <register>
          <name>BGCLUT.122</name>
          <addressOffset>0x9e8</addressOffset>
          <size>0x20</size>
        </register>
        <register>
          <name>BGCLUT.123</name>
          <addressOffset>0x9ec</addressOffset>
          <size>0x20</size>
        </register>
        <register>
          <name>BGCLUT.124</name>
          <addressOffset>0x9f0</addressOffset>
          <size>0x20</size>
        </register>
        <register>
          <name>BGCLUT.125</name>
          <addressOffset>0x9f4</addressOffset>
          <size>0x20</size>
        </register>
        <register>
          <name>BGCLUT.126</name>
          <addressOffset>0x9f8</addressOffset>
          <size>0x20</size>
        </register>
        <register>
          <name>BGCLUT.127</name>
          <addressOffset>0x9fc</addressOffset>
          <size>0x20</size>
        </register>
        <register>
          <name>BGCLUT.128</name>
          <addressOffset>0xa00</addressOffset>
          <size>0x20</size>
        </register>
        <register>
          <name>BGCLUT.129</name>
          <addressOffset>0xa04</addressOffset>
          <size>0x20</size>
        </register>
        <register>
          <name>BGCLUT.130</name>
          <addressOffset>0xa08</addressOffset>
          <size>0x20</size>
        </register>
        <register>
          <name>BGCLUT.131</name>
          <addressOffset>0xa0c</addressOffset>
          <size>0x20</size>
        </register>
        <register>
          <name>BGCLUT.132</name>
          <addressOffset>0xa10</addressOffset>
          <size>0x20</size>
        </register>
        <register>
          <name>BGCLUT.133</name>
          <addressOffset>0xa14</addressOffset>
          <size>0x20</size>
        </register>
        <register>
          <name>BGCLUT.134</name>
          <addressOffset>0xa18</addressOffset>
          <size>0x20</size>
        </register>
        <register>
          <name>BGCLUT.135</name>
          <addressOffset>0xa1c</addressOffset>
          <size>0x20</size>
        </register>
        <register>
          <name>BGCLUT.136</name>
          <addressOffset>0xa20</addressOffset>
          <size>0x20</size>
        </register>
        <register>
          <name>BGCLUT.137</name>
          <addressOffset>0xa24</addressOffset>
          <size>0x20</size>
        </register>
        <register>
          <name>BGCLUT.138</name>
          <addressOffset>0xa28</addressOffset>
          <size>0x20</size>
        </register>
        <register>
          <name>BGCLUT.139</name>
          <addressOffset>0xa2c</addressOffset>
          <size>0x20</size>
        </register>
        <register>
          <name>BGCLUT.140</name>
          <addressOffset>0xa30</addressOffset>
          <size>0x20</size>
        </register>
        <register>
          <name>BGCLUT.141</name>
          <addressOffset>0xa34</addressOffset>
          <size>0x20</size>
        </register>
        <register>
          <name>BGCLUT.142</name>
          <addressOffset>0xa38</addressOffset>
          <size>0x20</size>
        </register>
        <register>
          <name>BGCLUT.143</name>
          <addressOffset>0xa3c</addressOffset>
          <size>0x20</size>
        </register>
        <register>
          <name>BGCLUT.144</name>
          <addressOffset>0xa40</addressOffset>
          <size>0x20</size>
        </register>
        <register>
          <name>BGCLUT.145</name>
          <addressOffset>0xa44</addressOffset>
          <size>0x20</size>
        </register>
        <register>
          <name>BGCLUT.146</name>
          <addressOffset>0xa48</addressOffset>
          <size>0x20</size>
        </register>
        <register>
          <name>BGCLUT.147</name>
          <addressOffset>0xa4c</addressOffset>
          <size>0x20</size>
        </register>
        <register>
          <name>BGCLUT.148</name>
          <addressOffset>0xa50</addressOffset>
          <size>0x20</size>
        </register>
        <register>
          <name>BGCLUT.149</name>
          <addressOffset>0xa54</addressOffset>
          <size>0x20</size>
        </register>
        <register>
          <name>BGCLUT.150</name>
          <addressOffset>0xa58</addressOffset>
          <size>0x20</size>
        </register>
        <register>
          <name>BGCLUT.151</name>
          <addressOffset>0xa5c</addressOffset>
          <size>0x20</size>
        </register>
        <register>
          <name>BGCLUT.152</name>
          <addressOffset>0xa60</addressOffset>
          <size>0x20</size>
        </register>
        <register>
          <name>BGCLUT.153</name>
          <addressOffset>0xa64</addressOffset>
          <size>0x20</size>
        </register>
        <register>
          <name>BGCLUT.154</name>
          <addressOffset>0xa68</addressOffset>
          <size>0x20</size>
        </register>
        <register>
          <name>BGCLUT.155</name>
          <addressOffset>0xa6c</addressOffset>
          <size>0x20</size>
        </register>
        <register>
          <name>BGCLUT.156</name>
          <addressOffset>0xa70</addressOffset>
          <size>0x20</size>
        </register>
        <register>
          <name>BGCLUT.157</name>
          <addressOffset>0xa74</addressOffset>
          <size>0x20</size>
        </register>
        <register>
          <name>BGCLUT.158</name>
          <addressOffset>0xa78</addressOffset>
          <size>0x20</size>
        </register>
        <register>
          <name>BGCLUT.159</name>
          <addressOffset>0xa7c</addressOffset>
          <size>0x20</size>
        </register>
        <register>
          <name>BGCLUT.160</name>
          <addressOffset>0xa80</addressOffset>
          <size>0x20</size>
        </register>
        <register>
          <name>BGCLUT.161</name>
          <addressOffset>0xa84</addressOffset>
          <size>0x20</size>
        </register>
        <register>
          <name>BGCLUT.162</name>
          <addressOffset>0xa88</addressOffset>
          <size>0x20</size>
        </register>
        <register>
          <name>BGCLUT.163</name>
          <addressOffset>0xa8c</addressOffset>
          <size>0x20</size>
        </register>
        <register>
          <name>BGCLUT.164</name>
          <addressOffset>0xa90</addressOffset>
          <size>0x20</size>
        </register>
        <register>
          <name>BGCLUT.165</name>
          <addressOffset>0xa94</addressOffset>
          <size>0x20</size>
        </register>
        <register>
          <name>BGCLUT.166</name>
          <addressOffset>0xa98</addressOffset>
          <size>0x20</size>
        </register>
        <register>
          <name>BGCLUT.167</name>
          <addressOffset>0xa9c</addressOffset>
          <size>0x20</size>
        </register>
        <register>
          <name>BGCLUT.168</name>
          <addressOffset>0xaa0</addressOffset>
          <size>0x20</size>
        </register>
        <register>
          <name>BGCLUT.169</name>
          <addressOffset>0xaa4</addressOffset>
          <size>0x20</size>
        </register>
        <register>
          <name>BGCLUT.170</name>
          <addressOffset>0xaa8</addressOffset>
          <size>0x20</size>
        </register>
        <register>
          <name>BGCLUT.171</name>
          <addressOffset>0xaac</addressOffset>
          <size>0x20</size>
        </register>
        <register>
          <name>BGCLUT.172</name>
          <addressOffset>0xab0</addressOffset>
          <size>0x20</size>
        </register>
        <register>
          <name>BGCLUT.173</name>
          <addressOffset>0xab4</addressOffset>
          <size>0x20</size>
        </register>
        <register>
          <name>BGCLUT.174</name>
          <addressOffset>0xab8</addressOffset>
          <size>0x20</size>
        </register>
        <register>
          <name>BGCLUT.175</name>
          <addressOffset>0xabc</addressOffset>
          <size>0x20</size>
        </register>
        <register>
          <name>BGCLUT.176</name>
          <addressOffset>0xac0</addressOffset>
          <size>0x20</size>
        </register>
        <register>
          <name>BGCLUT.177</name>
          <addressOffset>0xac4</addressOffset>
          <size>0x20</size>
        </register>
        <register>
          <name>BGCLUT.178</name>
          <addressOffset>0xac8</addressOffset>
          <size>0x20</size>
        </register>
        <register>
          <name>BGCLUT.179</name>
          <addressOffset>0xacc</addressOffset>
          <size>0x20</size>
        </register>
        <register>
          <name>BGCLUT.180</name>
          <addressOffset>0xad0</addressOffset>
          <size>0x20</size>
        </register>
        <register>
          <name>BGCLUT.181</name>
          <addressOffset>0xad4</addressOffset>
          <size>0x20</size>
        </register>
        <register>
          <name>BGCLUT.182</name>
          <addressOffset>0xad8</addressOffset>
          <size>0x20</size>
        </register>
        <register>
          <name>BGCLUT.183</name>
          <addressOffset>0xadc</addressOffset>
          <size>0x20</size>
        </register>
        <register>
          <name>BGCLUT.184</name>
          <addressOffset>0xae0</addressOffset>
          <size>0x20</size>
        </register>
        <register>
          <name>BGCLUT.185</name>
          <addressOffset>0xae4</addressOffset>
          <size>0x20</size>
        </register>
        <register>
          <name>BGCLUT.186</name>
          <addressOffset>0xae8</addressOffset>
          <size>0x20</size>
        </register>
        <register>
          <name>BGCLUT.187</name>
          <addressOffset>0xaec</addressOffset>
          <size>0x20</size>
        </register>
        <register>
          <name>BGCLUT.188</name>
          <addressOffset>0xaf0</addressOffset>
          <size>0x20</size>
        </register>
        <register>
          <name>BGCLUT.189</name>
          <addressOffset>0xaf4</addressOffset>
          <size>0x20</size>
        </register>
        <register>
          <name>BGCLUT.190</name>
          <addressOffset>0xaf8</addressOffset>
          <size>0x20</size>
        </register>
        <register>
          <name>BGCLUT.191</name>
          <addressOffset>0xafc</addressOffset>
          <size>0x20</size>
        </register>
        <register>
          <name>BGCLUT.192</name>
          <addressOffset>0xb00</addressOffset>
          <size>0x20</size>
        </register>
        <register>
          <name>BGCLUT.193</name>
          <addressOffset>0xb04</addressOffset>
          <size>0x20</size>
        </register>
        <register>
          <name>BGCLUT.194</name>
          <addressOffset>0xb08</addressOffset>
          <size>0x20</size>
        </register>
        <register>
          <name>BGCLUT.195</name>
          <addressOffset>0xb0c</addressOffset>
          <size>0x20</size>
        </register>
        <register>
          <name>BGCLUT.196</name>
          <addressOffset>0xb10</addressOffset>
          <size>0x20</size>
        </register>
        <register>
          <name>BGCLUT.197</name>
          <addressOffset>0xb14</addressOffset>
          <size>0x20</size>
        </register>
        <register>
          <name>BGCLUT.198</name>
          <addressOffset>0xb18</addressOffset>
          <size>0x20</size>
        </register>
        <register>
          <name>BGCLUT.199</name>
          <addressOffset>0xb1c</addressOffset>
          <size>0x20</size>
        </register>
        <register>
          <name>BGCLUT.200</name>
          <addressOffset>0xb20</addressOffset>
          <size>0x20</size>
        </register>
        <register>
          <name>BGCLUT.201</name>
          <addressOffset>0xb24</addressOffset>
          <size>0x20</size>
        </register>
        <register>
          <name>BGCLUT.202</name>
          <addressOffset>0xb28</addressOffset>
          <size>0x20</size>
        </register>
        <register>
          <name>BGCLUT.203</name>
          <addressOffset>0xb2c</addressOffset>
          <size>0x20</size>
        </register>
        <register>
          <name>BGCLUT.204</name>
          <addressOffset>0xb30</addressOffset>
          <size>0x20</size>
        </register>
        <register>
          <name>BGCLUT.205</name>
          <addressOffset>0xb34</addressOffset>
          <size>0x20</size>
        </register>
        <register>
          <name>BGCLUT.206</name>
          <addressOffset>0xb38</addressOffset>
          <size>0x20</size>
        </register>
        <register>
          <name>BGCLUT.207</name>
          <addressOffset>0xb3c</addressOffset>
          <size>0x20</size>
        </register>
        <register>
          <name>BGCLUT.208</name>
          <addressOffset>0xb40</addressOffset>
          <size>0x20</size>
        </register>
        <register>
          <name>BGCLUT.209</name>
          <addressOffset>0xb44</addressOffset>
          <size>0x20</size>
        </register>
        <register>
          <name>BGCLUT.210</name>
          <addressOffset>0xb48</addressOffset>
          <size>0x20</size>
        </register>
        <register>
          <name>BGCLUT.211</name>
          <addressOffset>0xb4c</addressOffset>
          <size>0x20</size>
        </register>
        <register>
          <name>BGCLUT.212</name>
          <addressOffset>0xb50</addressOffset>
          <size>0x20</size>
        </register>
        <register>
          <name>BGCLUT.213</name>
          <addressOffset>0xb54</addressOffset>
          <size>0x20</size>
        </register>
        <register>
          <name>BGCLUT.214</name>
          <addressOffset>0xb58</addressOffset>
          <size>0x20</size>
        </register>
        <register>
          <name>BGCLUT.215</name>
          <addressOffset>0xb5c</addressOffset>
          <size>0x20</size>
        </register>
        <register>
          <name>BGCLUT.216</name>
          <addressOffset>0xb60</addressOffset>
          <size>0x20</size>
        </register>
        <register>
          <name>BGCLUT.217</name>
          <addressOffset>0xb64</addressOffset>
          <size>0x20</size>
        </register>
        <register>
          <name>BGCLUT.218</name>
          <addressOffset>0xb68</addressOffset>
          <size>0x20</size>
        </register>
        <register>
          <name>BGCLUT.219</name>
          <addressOffset>0xb6c</addressOffset>
          <size>0x20</size>
        </register>
        <register>
          <name>BGCLUT.220</name>
          <addressOffset>0xb70</addressOffset>
          <size>0x20</size>
        </register>
        <register>
          <name>BGCLUT.221</name>
          <addressOffset>0xb74</addressOffset>
          <size>0x20</size>
        </register>
        <register>
          <name>BGCLUT.222</name>
          <addressOffset>0xb78</addressOffset>
          <size>0x20</size>
        </register>
        <register>
          <name>BGCLUT.223</name>
          <addressOffset>0xb7c</addressOffset>
          <size>0x20</size>
        </register>
        <register>
          <name>BGCLUT.224</name>
          <addressOffset>0xb80</addressOffset>
          <size>0x20</size>
        </register>
        <register>
          <name>BGCLUT.225</name>
          <addressOffset>0xb84</addressOffset>
          <size>0x20</size>
        </register>
        <register>
          <name>BGCLUT.226</name>
          <addressOffset>0xb88</addressOffset>
          <size>0x20</size>
        </register>
        <register>
          <name>BGCLUT.227</name>
          <addressOffset>0xb8c</addressOffset>
          <size>0x20</size>
        </register>
        <register>
          <name>BGCLUT.228</name>
          <addressOffset>0xb90</addressOffset>
          <size>0x20</size>
        </register>
        <register>
          <name>BGCLUT.229</name>
          <addressOffset>0xb94</addressOffset>
          <size>0x20</size>
        </register>
        <register>
          <name>BGCLUT.230</name>
          <addressOffset>0xb98</addressOffset>
          <size>0x20</size>
        </register>
        <register>
          <name>BGCLUT.231</name>
          <addressOffset>0xb9c</addressOffset>
          <size>0x20</size>
        </register>
        <register>
          <name>BGCLUT.232</name>
          <addressOffset>0xba0</addressOffset>
          <size>0x20</size>
        </register>
        <register>
          <name>BGCLUT.233</name>
          <addressOffset>0xba4</addressOffset>
          <size>0x20</size>
        </register>
        <register>
          <name>BGCLUT.234</name>
          <addressOffset>0xba8</addressOffset>
          <size>0x20</size>
        </register>
        <register>
          <name>BGCLUT.235</name>
          <addressOffset>0xbac</addressOffset>
          <size>0x20</size>
        </register>
        <register>
          <name>BGCLUT.236</name>
          <addressOffset>0xbb0</addressOffset>
          <size>0x20</size>
        </register>
        <register>
          <name>BGCLUT.237</name>
          <addressOffset>0xbb4</addressOffset>
          <size>0x20</size>
        </register>
        <register>
          <name>BGCLUT.238</name>
          <addressOffset>0xbb8</addressOffset>
          <size>0x20</size>
        </register>
        <register>
          <name>BGCLUT.239</name>
          <addressOffset>0xbbc</addressOffset>
          <size>0x20</size>
        </register>
        <register>
          <name>BGCLUT.240</name>
          <addressOffset>0xbc0</addressOffset>
          <size>0x20</size>
        </register>
        <register>
          <name>BGCLUT.241</name>
          <addressOffset>0xbc4</addressOffset>
          <size>0x20</size>
        </register>
        <register>
          <name>BGCLUT.242</name>
          <addressOffset>0xbc8</addressOffset>
          <size>0x20</size>
        </register>
        <register>
          <name>BGCLUT.243</name>
          <addressOffset>0xbcc</addressOffset>
          <size>0x20</size>
        </register>
        <register>
          <name>BGCLUT.244</name>
          <addressOffset>0xbd0</addressOffset>
          <size>0x20</size>
        </register>
        <register>
          <name>BGCLUT.245</name>
          <addressOffset>0xbd4</addressOffset>
          <size>0x20</size>
        </register>
        <register>
          <name>BGCLUT.246</name>
          <addressOffset>0xbd8</addressOffset>
          <size>0x20</size>
        </register>
        <register>
          <name>BGCLUT.247</name>
          <addressOffset>0xbdc</addressOffset>
          <size>0x20</size>
        </register>
        <register>
          <name>BGCLUT.248</name>
          <addressOffset>0xbe0</addressOffset>
          <size>0x20</size>
        </register>
        <register>
          <name>BGCLUT.249</name>
          <addressOffset>0xbe4</addressOffset>
          <size>0x20</size>
        </register>
        <register>
          <name>BGCLUT.250</name>
          <addressOffset>0xbe8</addressOffset>
          <size>0x20</size>
        </register>
        <register>
          <name>BGCLUT.251</name>
          <addressOffset>0xbec</addressOffset>
          <size>0x20</size>
        </register>
        <register>
          <name>BGCLUT.252</name>
          <addressOffset>0xbf0</addressOffset>
          <size>0x20</size>
        </register>
        <register>
          <name>BGCLUT.253</name>
          <addressOffset>0xbf4</addressOffset>
          <size>0x20</size>
        </register>
        <register>
          <name>BGCLUT.254</name>
          <addressOffset>0xbf8</addressOffset>
          <size>0x20</size>
        </register>
        <register>
          <name>BGCLUT.255</name>
          <addressOffset>0xbfc</addressOffset>
          <size>0x20</size>
        </register>
      </registers>
    </peripheral>
    <peripheral>
      <name>FLASH</name>
      <baseAddress>0x52002000</baseAddress>
      <registers>
        <register>
          <name>ACR</name>
          <addressOffset>0x0</addressOffset>
          <size>0x20</size>
          <fields>
            <field>
              <name>WRHIGHFREQ</name>
              <bitOffset>4</bitOffset>
              <bitWidth>2</bitWidth>
            </field>
          </fields>
        </register>
        <register>
          <name>KEYR1</name>
          <addressOffset>0x4</addressOffset>
          <size>0x20</size>
        </register>
        <register>
          <name>OPTKEYR</name>
          <addressOffset>0x8</addressOffset>
          <size>0x20</size>
        </register>
        <register>
          <name>CR1</name>
          <addressOffset>0xc</addressOffset>
          <size>0x20</size>
        </register>
        <register>
          <name>SR1</name>
          <addressOffset>0x10</addressOffset>
          <size>0x20</size>
        </register>
        <register>
          <name>CCR1</name>
          <addressOffset>0x14</addressOffset>
          <size>0x20</size>
        </register>
        <register>
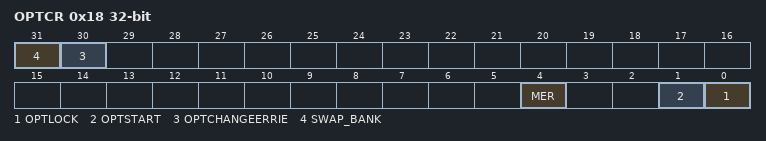
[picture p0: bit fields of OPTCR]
          <name>OPTCR</name>
          <addressOffset>0x18</addressOffset>
          <size>0x20</size>
          <fields>
            <field>
              <name>OPTLOCK</name>
              <bitOffset>0</bitOffset>
              <bitWidth>1</bitWidth>
            </field>
            <field>
              <name>OPTSTART</name>
              <bitOffset>1</bitOffset>
              <bitWidth>1</bitWidth>
            </field>
            <field>
              <name>MER</name>
              <bitOffset>4</bitOffset>
              <bitWidth>1</bitWidth>
            </field>
            <field>
              <name>OPTCHANGEERRIE</name>
              <bitOffset>30</bitOffset>
              <bitWidth>1</bitWidth>
            </field>
            <field>
              <name>SWAP_BANK</name>
              <bitOffset>31</bitOffset>
              <bitWidth>1</bitWidth>
            </field>
          </fields>
        </register>
        <register>
          <name>OPTSR_CUR</name>
          <addressOffset>0x1c</addressOffset>
          <size>0x20</size>
        </register>
        <register>
          <name>OPTSR_PRG</name>
          <addressOffset>0x20</addressOffset>
          <size>0x20</size>
        </register>
        <register>
          <name>OPTCCR</name>
          <addressOffset>0x24</addressOffset>
          <size>0x20</size>
          <fields>
            <field>
              <name>CLR_OPTCHANGEERR</name>
              <bitOffset>30</bitOffset>
              <bitWidth>1</bitWidth>
            </field>
          </fields>
        </register>
        <register>
          <name>PRAR_CUR1</name>
          <addressOffset>0x28</addressOffset>
          <size>0x20</size>
        </register>
        <register>
          <name>PRAR_PRG1</name>
          <addressOffset>0x2c</addressOffset>
          <size>0x20</size>
        </register>
        <register>
          <name>SCAR_CUR1</name>
          <addressOffset>0x30</addressOffset>
          <size>0x20</size>
        </register>
        <register>
          <name>SCAR_PRG1</name>
          <addressOffset>0x34</addressOffset>
          <size>0x20</size>
        </register>
        <register>
          <name>WPSN_CUR1</name>
          <addressOffset>0x38</addressOffset>
          <size>0x20</size>
        </register>
        <register>
          <name>WPSN_PRG1</name>
          <addressOffset>0x3c</addressOffset>
          <size>0x20</size>
        </register>
        <register>
          <name>BOOT7_CUR</name>
          <addressOffset>0x40</addressOffset>
          <size>0x20</size>
        </register>
        <register>
          <name>BOOT7_PRG</name>
          <addressOffset>0x44</addressOffset>
          <size>0x20</size>
        </register>
        <register>
          <name>BOOT4_CUR</name>
          <addressOffset>0x48</addressOffset>
          <size>0x20</size>
        </register>
        <register>
          <name>BOOT4_PRG</name>
          <addressOffset>0x4c</addressOffset>
          <size>0x20</size>
        </register>
        <register>
          <name>CRCCR1</name>
          <addressOffset>0x50</addressOffset>
          <size>0x20</size>
        </register>
        <register>
          <name>CRCSADD1</name>
          <addressOffset>0x54</addressOffset>
          <size>0x20</size>
        </register>
        <register>
          <name>CRCEADD1</name>
          <addressOffset>0x58</addressOffset>
          <size>0x20</size>
        </register>
        <register>
          <name>CRCDATA</name>
          <addressOffset>0x5c</addressOffset>
          <size>0x20</size>
          <fields>
            <field>
              <name>CRC_DATA</name>
              <bitOffset>0</bitOffset>
              <bitWidth>32</bitWidth>
            </field>
          </fields>
        </register>
        <register>
          <name>ECC_FA1</name>
          <addressOffset>0x60</addressOffset>
          <size>0x20</size>
        </register>
        <register>
          <name>KEYR2</name>
          <addressOffset>0x104</addressOffset>
          <size>0x20</size>
        </register>
        <register>
          <name>CR2</name>
          <addressOffset>0x10c</addressOffset>
          <size>0x20</size>
        </register>
        <register>
          <name>SR2</name>
          <addressOffset>0x110</addressOffset>
          <size>0x20</size>
        </register>
        <register>
          <name>CCR2</name>
          <addressOffset>0x114</addressOffset>
          <size>0x20</size>
        </register>
        <register>
          <name>PRAR_CUR2</name>
          <addressOffset>0x128</addressOffset>
          <size>0x20</size>
        </register>
        <register>
          <name>PRAR_PRG2</name>
          <addressOffset>0x12c</addressOffset>
          <size>0x20</size>
        </register>
        <register>
          <name>SCAR_CUR2</name>
          <addressOffset>0x130</addressOffset>
          <size>0x20</size>
        </register>
        <register>
          <name>SCAR_PRG2</name>
          <addressOffset>0x134</addressOffset>
          <size>0x20</size>
        </register>
        <register>
          <name>WPSN_CUR2</name>
          <addressOffset>0x138</addressOffset>
          <size>0x20</size>
        </register>
        <register>
          <name>WPSN_PRG2</name>
          <addressOffset>0x13c</addressOffset>
          <size>0x20</size>
        </register>
        <register>
          <name>CRCCR2</name>
          <addressOffset>0x150</addressOffset>
          <size>0x20</size>
        </register>
        <register>
          <name>CRCSADD2</name>
          <addressOffset>0x154</addressOffset>
          <size>0x20</size>
        </register>
        <register>
          <name>CRCEADD2</name>
          <addressOffset>0x158</addressOffset>
          <size>0x20</size>
        </register>
        <register>
          <name>CRCDATA2</name>
          <addressOffset>0x15c</addressOffset>
          <size>0x20</size>
        </register>
        <register>
          <name>ECC_FA2</name>
          <addressOffset>0x160</addressOffset>
          <size>0x20</size>
        </register>
      </registers>
    </peripheral>
    <peripheral>
      <name>JPEG</name>
      <baseAddress>0x52003000</baseAddress>
      <registers>
        <register>
          <name>CONFR0</name>
          <addressOffset>0x0</addressOffset>
          <size>0x20</size>
          <fields>
            <field>
              <name>START</name>
              <bitOffset>0</bitOffset>
              <bitWidth>1</bitWidth>
            </field>
          </fields>
        </register>
        <register>
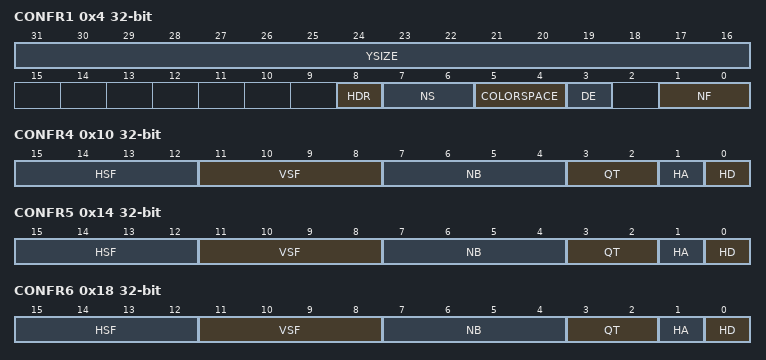
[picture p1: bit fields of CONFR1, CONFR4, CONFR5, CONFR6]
          <name>CONFR1</name>
          <addressOffset>0x4</addressOffset>
          <size>0x20</size>
          <fields>
            <field>
              <name>NF</name>
              <bitOffset>0</bitOffset>
              <bitWidth>2</bitWidth>
            </field>
            <field>
              <name>DE</name>
              <bitOffset>3</bitOffset>
              <bitWidth>1</bitWidth>
            </field>
            <field>
              <name>COLORSPACE</name>
              <bitOffset>4</bitOffset>
              <bitWidth>2</bitWidth>
            </field>
            <field>
              <name>NS</name>
              <bitOffset>6</bitOffset>
              <bitWidth>2</bitWidth>
            </field>
            <field>
              <name>HDR</name>
              <bitOffset>8</bitOffset>
              <bitWidth>1</bitWidth>
            </field>
            <field>
              <name>YSIZE</name>
              <bitOffset>16</bitOffset>
              <bitWidth>16</bitWidth>
            </field>
          </fields>
        </register>
        <register>
          <name>CONFR2</name>
          <addressOffset>0x8</addressOffset>
          <size>0x20</size>
          <fields>
            <field>
              <name>NMCU</name>
              <bitOffset>0</bitOffset>
              <bitWidth>26</bitWidth>
            </field>
          </fields>
        </register>
        <register>
          <name>CONFR3</name>
          <addressOffset>0xc</addressOffset>
          <size>0x20</size>
          <fields>
            <field>
              <name>XSIZE</name>
              <bitOffset>16</bitOffset>
              <bitWidth>16</bitWidth>
            </field>
          </fields>
        </register>
        <register>
          <name>CONFR4</name>
          <addressOffset>0x10</addressOffset>
          <size>0x20</size>
          <fields>
            <field>
              <name>HD</name>
              <bitOffset>0</bitOffset>
              <bitWidth>1</bitWidth>
            </field>
            <field>
              <name>HA</name>
              <bitOffset>1</bitOffset>
              <bitWidth>1</bitWidth>
            </field>
            <field>
              <name>QT</name>
              <bitOffset>2</bitOffset>
              <bitWidth>2</bitWidth>
            </field>
            <field>
              <name>NB</name>
              <bitOffset>4</bitOffset>
              <bitWidth>4</bitWidth>
            </field>
            <field>
              <name>VSF</name>
              <bitOffset>8</bitOffset>
              <bitWidth>4</bitWidth>
            </field>
            <field>
              <name>HSF</name>
              <bitOffset>12</bitOffset>
              <bitWidth>4</bitWidth>
            </field>
          </fields>
        </register>
        <register>
          <name>CONFR5</name>
          <addressOffset>0x14</addressOffset>
          <size>0x20</size>
          <fields>
            <field>
              <name>HD</name>
              <bitOffset>0</bitOffset>
              <bitWidth>1</bitWidth>
            </field>
            <field>
              <name>HA</name>
              <bitOffset>1</bitOffset>
              <bitWidth>1</bitWidth>
            </field>
            <field>
              <name>QT</name>
              <bitOffset>2</bitOffset>
              <bitWidth>2</bitWidth>
            </field>
            <field>
              <name>NB</name>
              <bitOffset>4</bitOffset>
              <bitWidth>4</bitWidth>
            </field>
            <field>
              <name>VSF</name>
              <bitOffset>8</bitOffset>
              <bitWidth>4</bitWidth>
            </field>
            <field>
              <name>HSF</name>
              <bitOffset>12</bitOffset>
              <bitWidth>4</bitWidth>
            </field>
          </fields>
        </register>
        <register>
          <name>CONFR6</name>
          <addressOffset>0x18</addressOffset>
          <size>0x20</size>
          <fields>
            <field>
              <name>HD</name>
              <bitOffset>0</bitOffset>
              <bitWidth>1</bitWidth>
            </field>
            <field>
              <name>HA</name>
              <bitOffset>1</bitOffset>
              <bitWidth>1</bitWidth>
            </field>
            <field>
              <name>QT</name>
              <bitOffset>2</bitOffset>
              <bitWidth>2</bitWidth>
            </field>
            <field>
              <name>NB</name>
              <bitOffset>4</bitOffset>
              <bitWidth>4</bitWidth>
            </field>
            <field>
              <name>VSF</name>
              <bitOffset>8</bitOffset>
              <bitWidth>4</bitWidth>
            </field>
            <field>
              <name>HSF</name>
              <bitOffset>12</bitOffset>
              <bitWidth>4</bitWidth>
            </field>
          </fields>
        </register>
        <register>
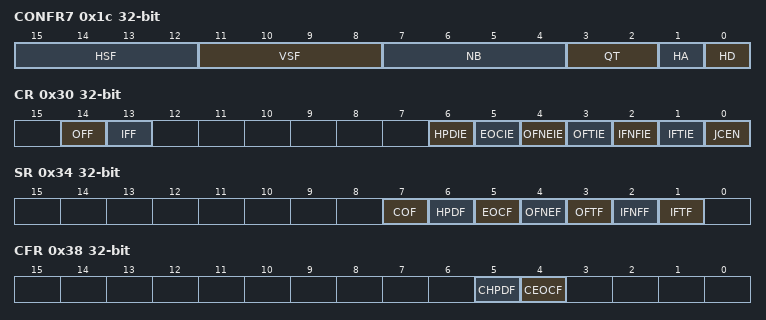
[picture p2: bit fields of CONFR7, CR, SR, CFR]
          <name>CONFR7</name>
          <addressOffset>0x1c</addressOffset>
          <size>0x20</size>
          <fields>
            <field>
              <name>HD</name>
              <bitOffset>0</bitOffset>
              <bitWidth>1</bitWidth>
            </field>
            <field>
              <name>HA</name>
              <bitOffset>1</bitOffset>
              <bitWidth>1</bitWidth>
            </field>
            <field>
              <name>QT</name>
              <bitOffset>2</bitOffset>
              <bitWidth>2</bitWidth>
            </field>
            <field>
              <name>NB</name>
              <bitOffset>4</bitOffset>
              <bitWidth>4</bitWidth>
            </field>
            <field>
              <name>VSF</name>
              <bitOffset>8</bitOffset>
              <bitWidth>4</bitWidth>
            </field>
            <field>
              <name>HSF</name>
              <bitOffset>12</bitOffset>
              <bitWidth>4</bitWidth>
            </field>
          </fields>
        </register>
        <register>
          <name>CR</name>
          <addressOffset>0x30</addressOffset>
          <size>0x20</size>
          <fields>
            <field>
              <name>JCEN</name>
              <bitOffset>0</bitOffset>
              <bitWidth>1</bitWidth>
            </field>
            <field>
              <name>IFTIE</name>
              <bitOffset>1</bitOffset>
              <bitWidth>1</bitWidth>
            </field>
            <field>
              <name>IFNFIE</name>
              <bitOffset>2</bitOffset>
              <bitWidth>1</bitWidth>
            </field>
            <field>
              <name>OFTIE</name>
              <bitOffset>3</bitOffset>
              <bitWidth>1</bitWidth>
            </field>
            <field>
              <name>OFNEIE</name>
              <bitOffset>4</bitOffset>
              <bitWidth>1</bitWidth>
            </field>
            <field>
              <name>EOCIE</name>
              <bitOffset>5</bitOffset>
              <bitWidth>1</bitWidth>
            </field>
            <field>
              <name>HPDIE</name>
              <bitOffset>6</bitOffset>
              <bitWidth>1</bitWidth>
            </field>
            <field>
              <name>IFF</name>
              <bitOffset>13</bitOffset>
              <bitWidth>1</bitWidth>
            </field>
            <field>
              <name>OFF</name>
              <bitOffset>14</bitOffset>
              <bitWidth>1</bitWidth>
            </field>
          </fields>
        </register>
        <register>
          <name>SR</name>
          <addressOffset>0x34</addressOffset>
          <size>0x20</size>
          <fields>
            <field>
              <name>IFTF</name>
              <bitOffset>1</bitOffset>
              <bitWidth>1</bitWidth>
            </field>
            <field>
              <name>IFNFF</name>
              <bitOffset>2</bitOffset>
              <bitWidth>1</bitWidth>
            </field>
            <field>
              <name>OFTF</name>
              <bitOffset>3</bitOffset>
              <bitWidth>1</bitWidth>
            </field>
            <field>
              <name>OFNEF</name>
              <bitOffset>4</bitOffset>
              <bitWidth>1</bitWidth>
            </field>
            <field>
              <name>EOCF</name>
              <bitOffset>5</bitOffset>
              <bitWidth>1</bitWidth>
            </field>
            <field>
              <name>HPDF</name>
              <bitOffset>6</bitOffset>
              <bitWidth>1</bitWidth>
            </field>
            <field>
              <name>COF</name>
              <bitOffset>7</bitOffset>
              <bitWidth>1</bitWidth>
            </field>
          </fields>
        </register>
        <register>
          <name>CFR</name>
          <addressOffset>0x38</addressOffset>
          <size>0x20</size>
          <fields>
            <field>
              <name>CEOCF</name>
              <bitOffset>4</bitOffset>
              <bitWidth>1</bitWidth>
            </field>
            <field>
              <name>CHPDF</name>
              <bitOffset>5</bitOffset>
              <bitWidth>1</bitWidth>
            </field>
          </fields>
        </register>
        <register>
          <name>DIR</name>
          <addressOffset>0x40</addressOffset>
          <size>0x20</size>
          <fields>
            <field>
              <name>DATAIN</name>
              <bitOffset>0</bitOffset>
              <bitWidth>32</bitWidth>
            </field>
          </fields>
        </register>
        <register>
          <name>DOR</name>
          <addressOffset>0x44</addressOffset>
          <size>0x20</size>
          <fields>
            <field>
              <name>DATAOUT</name>
              <bitOffset>0</bitOffset>
              <bitWidth>32</bitWidth>
            </field>
          </fields>
        </register>
        <register>
          <name>QMEM0.0</name>
          <addressOffset>0x50</addressOffset>
          <size>0x20</size>
        </register>
        <register>
          <name>QMEM0.1</name>
          <addressOffset>0x54</addressOffset>
          <size>0x20</size>
        </register>
        <register>
          <name>QMEM0.2</name>
          <addressOffset>0x58</addressOffset>
          <size>0x20</size>
        </register>
        <register>
          <name>QMEM0.3</name>
          <addressOffset>0x5c</addressOffset>
          <size>0x20</size>
        </register>
        <register>
          <name>QMEM0.4</name>
          <addressOffset>0x60</addressOffset>
          <size>0x20</size>
        </register>
        <register>
          <name>QMEM0.5</name>
          <addressOffset>0x64</addressOffset>
          <size>0x20</size>
        </register>
        <register>
          <name>QMEM0.6</name>
          <addressOffset>0x68</addressOffset>
          <size>0x20</size>
        </register>
        <register>
          <name>QMEM0.7</name>
          <addressOffset>0x6c</addressOffset>
          <size>0x20</size>
        </register>
        <register>
          <name>QMEM0.8</name>
          <addressOffset>0x70</addressOffset>
          <size>0x20</size>
        </register>
        <register>
          <name>QMEM0.9</name>
          <addressOffset>0x74</addressOffset>
          <size>0x20</size>
        </register>
        <register>
          <name>QMEM0.10</name>
          <addressOffset>0x78</addressOffset>
          <size>0x20</size>
        </register>
        <register>
          <name>QMEM0.11</name>
          <addressOffset>0x7c</addressOffset>
          <size>0x20</size>
        </register>
        <register>
          <name>QMEM0.12</name>
          <addressOffset>0x80</addressOffset>
          <size>0x20</size>
        </register>
        <register>
          <name>QMEM0.13</name>
          <addressOffset>0x84</addressOffset>
          <size>0x20</size>
        </register>
        <register>
          <name>QMEM0.14</name>
          <addressOffset>0x88</addressOffset>
          <size>0x20</size>
        </register>
        <register>
          <name>QMEM0.15</name>
          <addressOffset>0x8c</addressOffset>
          <size>0x20</size>
        </register>
        <register>
          <name>QMEM1.0</name>
          <addressOffset>0x90</addressOffset>
          <size>0x20</size>
        </register>
        <register>
          <name>QMEM1.1</name>
          <addressOffset>0x94</addressOffset>
          <size>0x20</size>
        </register>
        <register>
          <name>QMEM1.2</name>
          <addressOffset>0x98</addressOffset>
          <size>0x20</size>
        </register>
        <register>
          <name>QMEM1.3</name>
          <addressOffset>0x9c</addressOffset>
          <size>0x20</size>
        </register>
        <register>
          <name>QMEM1.4</name>
          <addressOffset>0xa0</addressOffset>
          <size>0x20</size>
        </register>
        <register>
          <name>QMEM1.5</name>
          <addressOffset>0xa4</addressOffset>
          <size>0x20</size>
        </register>
        <register>
          <name>QMEM1.6</name>
          <addressOffset>0xa8</addressOffset>
          <size>0x20</size>
        </register>
        <register>
          <name>QMEM1.7</name>
          <addressOffset>0xac</addressOffset>
          <size>0x20</size>
        </register>
        <register>
          <name>QMEM1.8</name>
          <addressOffset>0xb0</addressOffset>
          <size>0x20</size>
        </register>
        <register>
          <name>QMEM1.9</name>
          <addressOffset>0xb4</addressOffset>
          <size>0x20</size>
        </register>
        <register>
          <name>QMEM1.10</name>
          <addressOffset>0xb8</addressOffset>
          <size>0x20</size>
        </register>
        <register>
          <name>QMEM1.11</name>
          <addressOffset>0xbc</addressOffset>
          <size>0x20</size>
        </register>
        <register>
          <name>QMEM1.12</name>
          <addressOffset>0xc0</addressOffset>
          <size>0x20</size>
        </register>
        <register>
          <name>QMEM1.13</name>
          <addressOffset>0xc4</addressOffset>
          <size>0x20</size>
        </register>
        <register>
          <name>QMEM1.14</name>
          <addressOffset>0xc8</addressOffset>
          <size>0x20</size>
        </register>
        <register>
          <name>QMEM1.15</name>
          <addressOffset>0xcc</addressOffset>
          <size>0x20</size>
        </register>
        <register>
          <name>QMEM2.0</name>
          <addressOffset>0xd0</addressOffset>
          <size>0x20</size>
        </register>
        <register>
          <name>QMEM2.1</name>
          <addressOffset>0xd4</addressOffset>
          <size>0x20</size>
        </register>
        <register>
          <name>QMEM2.2</name>
          <addressOffset>0xd8</addressOffset>
          <size>0x20</size>
        </register>
        <register>
          <name>QMEM2.3</name>
          <addressOffset>0xdc</addressOffset>
          <size>0x20</size>
        </register>
        <register>
          <name>QMEM2.4</name>
          <addressOffset>0xe0</addressOffset>
          <size>0x20</size>
        </register>
        <register>
          <name>QMEM2.5</name>
          <addressOffset>0xe4</addressOffset>
          <size>0x20</size>
        </register>
        <register>
          <name>QMEM2.6</name>
          <addressOffset>0xe8</addressOffset>
          <size>0x20</size>
        </register>
        <register>
          <name>QMEM2.7</name>
          <addressOffset>0xec</addressOffset>
          <size>0x20</size>
        </register>
        <register>
          <name>QMEM2.8</name>
          <addressOffset>0xf0</addressOffset>
          <size>0x20</size>
        </register>
        <register>
          <name>QMEM2.9</name>
          <addressOffset>0xf4</addressOffset>
          <size>0x20</size>
        </register>
        <register>
          <name>QMEM2.10</name>
          <addressOffset>0xf8</addressOffset>
          <size>0x20</size>
        </register>
        <register>
          <name>QMEM2.11</name>
          <addressOffset>0xfc</addressOffset>
          <size>0x20</size>
        </register>
        <register>
          <name>QMEM2.12</name>
          <addressOffset>0x100</addressOffset>
          <size>0x20</size>
        </register>
        <register>
          <name>QMEM2.13</name>
          <addressOffset>0x104</addressOffset>
          <size>0x20</size>
        </register>
        <register>
          <name>QMEM2.14</name>
          <addressOffset>0x108</addressOffset>
          <size>0x20</size>
        </register>
        <register>
          <name>QMEM2.15</name>
          <addressOffset>0x10c</addressOffset>
          <size>0x20</size>
        </register>
        <register>
          <name>QMEM3.0</name>
          <addressOffset>0x110</addressOffset>
          <size>0x20</size>
        </register>
        <register>
          <name>QMEM3.1</name>
          <addressOffset>0x114</addressOffset>
          <size>0x20</size>
        </register>
        <register>
          <name>QMEM3.2</name>
          <addressOffset>0x118</addressOffset>
          <size>0x20</size>
        </register>
        <register>
          <name>QMEM3.3</name>
          <addressOffset>0x11c</addressOffset>
          <size>0x20</size>
        </register>
        <register>
          <name>QMEM3.4</name>
          <addressOffset>0x120</addressOffset>
          <size>0x20</size>
        </register>
        <register>
          <name>QMEM3.5</name>
          <addressOffset>0x124</addressOffset>
          <size>0x20</size>
        </register>
        <register>
          <name>QMEM3.6</name>
          <addressOffset>0x128</addressOffset>
          <size>0x20</size>
        </register>
        <register>
          <name>QMEM3.7</name>
          <addressOffset>0x12c</addressOffset>
          <size>0x20</size>
        </register>
        <register>
          <name>QMEM3.8</name>
          <addressOffset>0x130</addressOffset>
          <size>0x20</size>
        </register>
        <register>
          <name>QMEM3.9</name>
          <addressOffset>0x134</addressOffset>
          <size>0x20</size>
        </register>
        <register>
          <name>QMEM3.10</name>
          <addressOffset>0x138</addressOffset>
          <size>0x20</size>
        </register>
        <register>
          <name>QMEM3.11</name>
          <addressOffset>0x13c</addressOffset>
          <size>0x20</size>
        </register>
        <register>
          <name>QMEM3.12</name>
          <addressOffset>0x140</addressOffset>
          <size>0x20</size>
        </register>
        <register>
          <name>QMEM3.13</name>
          <addressOffset>0x144</addressOffset>
          <size>0x20</size>
        </register>
        <register>
          <name>QMEM3.14</name>
          <addressOffset>0x148</addressOffset>
          <size>0x20</size>
        </register>
        <register>
          <name>QMEM3.15</name>
          <addressOffset>0x14c</addressOffset>
          <size>0x20</size>
        </register>
        <register>
          <name>HUFFMIN.0</name>
          <addressOffset>0x150</addressOffset>
          <size>0x20</size>
        </register>
        <register>
          <name>HUFFMIN.1</name>
          <addressOffset>0x154</addressOffset>
          <size>0x20</size>
        </register>
        <register>
          <name>HUFFMIN.2</name>
          <addressOffset>0x158</addressOffset>
          <size>0x20</size>
        </register>
        <register>
          <name>HUFFMIN.3</name>
          <addressOffset>0x15c</addressOffset>
          <size>0x20</size>
        </register>
        <register>
          <name>HUFFMIN.4</name>
          <addressOffset>0x160</addressOffset>
          <size>0x20</size>
        </register>
        <register>
          <name>HUFFMIN.5</name>
          <addressOffset>0x164</addressOffset>
          <size>0x20</size>
        </register>
        <register>
          <name>HUFFMIN.6</name>
          <addressOffset>0x168</addressOffset>
          <size>0x20</size>
        </register>
        <register>
          <name>HUFFMIN.7</name>
          <addressOffset>0x16c</addressOffset>
          <size>0x20</size>
        </register>
        <register>
          <name>HUFFMIN.8</name>
          <addressOffset>0x170</addressOffset>
          <size>0x20</size>
        </register>
        <register>
          <name>HUFFMIN.9</name>
          <addressOffset>0x174</addressOffset>
          <size>0x20</size>
        </register>
        <register>
          <name>HUFFMIN.10</name>
          <addressOffset>0x178</addressOffset>
          <size>0x20</size>
        </register>
        <register>
          <name>HUFFMIN.11</name>
          <addressOffset>0x17c</addressOffset>
          <size>0x20</size>
        </register>
        <register>
          <name>HUFFMIN.12</name>
          <addressOffset>0x180</addressOffset>
          <size>0x20</size>
        </register>
        <register>
          <name>HUFFMIN.13</name>
          <addressOffset>0x184</addressOffset>
          <size>0x20</size>
        </register>
        <register>
          <name>HUFFMIN.14</name>
          <addressOffset>0x188</addressOffset>
          <size>0x20</size>
        </register>
        <register>
          <name>HUFFMIN.15</name>
          <addressOffset>0x18c</addressOffset>
          <size>0x20</size>
        </register>
        <register>
          <name>HUFFBASE.0</name>
          <addressOffset>0x190</addressOffset>
          <size>0x20</size>
        </register>
        <register>
          <name>HUFFBASE.1</name>
          <addressOffset>0x194</addressOffset>
          <size>0x20</size>
        </register>
        <register>
          <name>HUFFBASE.2</name>
          <addressOffset>0x198</addressOffset>
          <size>0x20</size>
        </register>
        <register>
          <name>HUFFBASE.3</name>
          <addressOffset>0x19c</addressOffset>
          <size>0x20</size>
        </register>
        <register>
          <name>HUFFBASE.4</name>
          <addressOffset>0x1a0</addressOffset>
          <size>0x20</size>
        </register>
        <register>
          <name>HUFFBASE.5</name>
          <addressOffset>0x1a4</addressOffset>
          <size>0x20</size>
        </register>
        <register>
          <name>HUFFBASE.6</name>
          <addressOffset>0x1a8</addressOffset>
          <size>0x20</size>
        </register>
        <register>
          <name>HUFFBASE.7</name>
          <addressOffset>0x1ac</addressOffset>
          <size>0x20</size>
        </register>
        <register>
          <name>HUFFBASE.8</name>
          <addressOffset>0x1b0</addressOffset>
          <size>0x20</size>
        </register>
        <register>
          <name>HUFFBASE.9</name>
          <addressOffset>0x1b4</addressOffset>
          <size>0x20</size>
        </register>
        <register>
          <name>HUFFBASE.10</name>
          <addressOffset>0x1b8</addressOffset>
          <size>0x20</size>
        </register>
        <register>
          <name>HUFFBASE.11</name>
          <addressOffset>0x1bc</addressOffset>
          <size>0x20</size>
        </register>
        <register>
          <name>HUFFBASE.12</name>
          <addressOffset>0x1c0</addressOffset>
          <size>0x20</size>
        </register>
        <register>
          <name>HUFFBASE.13</name>
          <addressOffset>0x1c4</addressOffset>
          <size>0x20</size>
        </register>
        <register>
          <name>HUFFBASE.14</name>
          <addressOffset>0x1c8</addressOffset>
          <size>0x20</size>
        </register>
        <register>
          <name>HUFFBASE.15</name>
          <addressOffset>0x1cc</addressOffset>
          <size>0x20</size>
        </register>
        <register>
          <name>HUFFBASE.16</name>
          <addressOffset>0x1d0</addressOffset>
          <size>0x20</size>
        </register>
        <register>
          <name>HUFFBASE.17</name>
          <addressOffset>0x1d4</addressOffset>
          <size>0x20</size>
        </register>
        <register>
          <name>HUFFBASE.18</name>
          <addressOffset>0x1d8</addressOffset>
          <size>0x20</size>
        </register>
        <register>
          <name>HUFFBASE.19</name>
          <addressOffset>0x1dc</addressOffset>
          <size>0x20</size>
        </register>
        <register>
          <name>HUFFBASE.20</name>
          <addressOffset>0x1e0</addressOffset>
          <size>0x20</size>
        </register>
        <register>
          <name>HUFFBASE.21</name>
          <addressOffset>0x1e4</addressOffset>
          <size>0x20</size>
        </register>
        <register>
          <name>HUFFBASE.22</name>
          <addressOffset>0x1e8</addressOffset>
          <size>0x20</size>
        </register>
        <register>
          <name>HUFFBASE.23</name>
          <addressOffset>0x1ec</addressOffset>
          <size>0x20</size>
        </register>
        <register>
          <name>HUFFBASE.24</name>
          <addressOffset>0x1f0</addressOffset>
          <size>0x20</size>
        </register>
        <register>
          <name>HUFFBASE.25</name>
          <addressOffset>0x1f4</addressOffset>
          <size>0x20</size>
        </register>
        <register>
          <name>HUFFBASE.26</name>
          <addressOffset>0x1f8</addressOffset>
          <size>0x20</size>
        </register>
        <register>
          <name>HUFFBASE.27</name>
          <addressOffset>0x1fc</addressOffset>
          <size>0x20</size>
        </register>
        <register>
          <name>HUFFBASE.28</name>
          <addressOffset>0x200</addressOffset>
          <size>0x20</size>
        </register>
        <register>
          <name>HUFFBASE.29</name>
          <addressOffset>0x204</addressOffset>
          <size>0x20</size>
        </register>
        <register>
          <name>HUFFBASE.30</name>
          <addressOffset>0x208</addressOffset>
          <size>0x20</size>
        </register>
        <register>
          <name>HUFFBASE.31</name>
          <addressOffset>0x20c</addressOffset>
          <size>0x20</size>
        </register>
        <register>
          <name>HUFFSYMB.0</name>
          <addressOffset>0x210</addressOffset>
          <size>0x20</size>
        </register>
        <register>
          <name>HUFFSYMB.1</name>
          <addressOffset>0x214</addressOffset>
          <size>0x20</size>
        </register>
        <register>
          <name>HUFFSYMB.2</name>
          <addressOffset>0x218</addressOffset>
          <size>0x20</size>
        </register>
        <register>
          <name>HUFFSYMB.3</name>
          <addressOffset>0x21c</addressOffset>
          <size>0x20</size>
        </register>
        <register>
          <name>HUFFSYMB.4</name>
          <addressOffset>0x220</addressOffset>
          <size>0x20</size>
        </register>
        <register>
          <name>HUFFSYMB.5</name>
          <addressOffset>0x224</addressOffset>
          <size>0x20</size>
        </register>
        <register>
          <name>HUFFSYMB.6</name>
          <addressOffset>0x228</addressOffset>
          <size>0x20</size>
        </register>
        <register>
          <name>HUFFSYMB.7</name>
          <addressOffset>0x22c</addressOffset>
          <size>0x20</size>
        </register>
        <register>
          <name>HUFFSYMB.8</name>
          <addressOffset>0x230</addressOffset>
          <size>0x20</size>
        </register>
        <register>
          <name>HUFFSYMB.9</name>
          <addressOffset>0x234</addressOffset>
          <size>0x20</size>
        </register>
        <register>
          <name>HUFFSYMB.10</name>
          <addressOffset>0x238</addressOffset>
          <size>0x20</size>
        </register>
        <register>
          <name>HUFFSYMB.11</name>
          <addressOffset>0x23c</addressOffset>
          <size>0x20</size>
        </register>
        <register>
          <name>HUFFSYMB.12</name>
          <addressOffset>0x240</addressOffset>
          <size>0x20</size>
        </register>
        <register>
          <name>HUFFSYMB.13</name>
          <addressOffset>0x244</addressOffset>
          <size>0x20</size>
        </register>
        <register>
          <name>HUFFSYMB.14</name>
          <addressOffset>0x248</addressOffset>
          <size>0x20</size>
        </register>
        <register>
          <name>HUFFSYMB.15</name>
          <addressOffset>0x24c</addressOffset>
          <size>0x20</size>
        </register>
        <register>
          <name>HUFFSYMB.16</name>
          <addressOffset>0x250</addressOffset>
          <size>0x20</size>
        </register>
        <register>
          <name>HUFFSYMB.17</name>
          <addressOffset>0x254</addressOffset>
          <size>0x20</size>
        </register>
        <register>
          <name>HUFFSYMB.18</name>
          <addressOffset>0x258</addressOffset>
          <size>0x20</size>
        </register>
        <register>
          <name>HUFFSYMB.19</name>
          <addressOffset>0x25c</addressOffset>
          <size>0x20</size>
        </register>
        <register>
          <name>HUFFSYMB.20</name>
          <addressOffset>0x260</addressOffset>
          <size>0x20</size>
        </register>
        <register>
          <name>HUFFSYMB.21</name>
          <addressOffset>0x264</addressOffset>
          <size>0x20</size>
        </register>
        <register>
          <name>HUFFSYMB.22</name>
          <addressOffset>0x268</addressOffset>
          <size>0x20</size>
        </register>
        <register>
          <name>HUFFSYMB.23</name>
          <addressOffset>0x26c</addressOffset>
          <size>0x20</size>
        </register>
        <register>
          <name>HUFFSYMB.24</name>
          <addressOffset>0x270</addressOffset>
          <size>0x20</size>
        </register>
        <register>
          <name>HUFFSYMB.25</name>
          <addressOffset>0x274</addressOffset>
          <size>0x20</size>
        </register>
        <register>
          <name>HUFFSYMB.26</name>
          <addressOffset>0x278</addressOffset>
          <size>0x20</size>
        </register>
        <register>
          <name>HUFFSYMB.27</name>
          <addressOffset>0x27c</addressOffset>
          <size>0x20</size>
        </register>
        <register>
          <name>HUFFSYMB.28</name>
          <addressOffset>0x280</addressOffset>
          <size>0x20</size>
        </register>
        <register>
          <name>HUFFSYMB.29</name>
          <addressOffset>0x284</addressOffset>
          <size>0x20</size>
        </register>
        <register>
          <name>HUFFSYMB.30</name>
          <addressOffset>0x288</addressOffset>
          <size>0x20</size>
        </register>
        <register>
          <name>HUFFSYMB.31</name>
          <addressOffset>0x28c</addressOffset>
          <size>0x20</size>
        </register>
        <register>
          <name>HUFFSYMB.32</name>
          <addressOffset>0x290</addressOffset>
          <size>0x20</size>
        </register>
        <register>
          <name>HUFFSYMB.33</name>
          <addressOffset>0x294</addressOffset>
          <size>0x20</size>
        </register>
        <register>
          <name>HUFFSYMB.34</name>
          <addressOffset>0x298</addressOffset>
          <size>0x20</size>
        </register>
        <register>
          <name>HUFFSYMB.35</name>
          <addressOffset>0x29c</addressOffset>
          <size>0x20</size>
        </register>
        <register>
          <name>HUFFSYMB.36</name>
          <addressOffset>0x2a0</addressOffset>
          <size>0x20</size>
        </register>
        <register>
          <name>HUFFSYMB.37</name>
          <addressOffset>0x2a4</addressOffset>
          <size>0x20</size>
        </register>
        <register>
          <name>HUFFSYMB.38</name>
          <addressOffset>0x2a8</addressOffset>
          <size>0x20</size>
        </register>
        <register>
          <name>HUFFSYMB.39</name>
          <addressOffset>0x2ac</addressOffset>
          <size>0x20</size>
        </register>
        <register>
          <name>HUFFSYMB.40</name>
          <addressOffset>0x2b0</addressOffset>
          <size>0x20</size>
        </register>
        <register>
          <name>HUFFSYMB.41</name>
          <addressOffset>0x2b4</addressOffset>
          <size>0x20</size>
        </register>
        <register>
          <name>HUFFSYMB.42</name>
          <addressOffset>0x2b8</addressOffset>
          <size>0x20</size>
        </register>
        <register>
          <name>HUFFSYMB.43</name>
          <addressOffset>0x2bc</addressOffset>
          <size>0x20</size>
        </register>
        <register>
          <name>HUFFSYMB.44</name>
          <addressOffset>0x2c0</addressOffset>
          <size>0x20</size>
        </register>
        <register>
          <name>HUFFSYMB.45</name>
          <addressOffset>0x2c4</addressOffset>
          <size>0x20</size>
        </register>
        <register>
          <name>HUFFSYMB.46</name>
          <addressOffset>0x2c8</addressOffset>
          <size>0x20</size>
        </register>
        <register>
          <name>HUFFSYMB.47</name>
          <addressOffset>0x2cc</addressOffset>
          <size>0x20</size>
        </register>
        <register>
          <name>HUFFSYMB.48</name>
          <addressOffset>0x2d0</addressOffset>
          <size>0x20</size>
        </register>
        <register>
          <name>HUFFSYMB.49</name>
          <addressOffset>0x2d4</addressOffset>
          <size>0x20</size>
        </register>
        <register>
          <name>HUFFSYMB.50</name>
          <addressOffset>0x2d8</addressOffset>
          <size>0x20</size>
        </register>
        <register>
          <name>HUFFSYMB.51</name>
          <addressOffset>0x2dc</addressOffset>
          <size>0x20</size>
        </register>
        <register>
          <name>HUFFSYMB.52</name>
          <addressOffset>0x2e0</addressOffset>
          <size>0x20</size>
        </register>
        <register>
          <name>HUFFSYMB.53</name>
          <addressOffset>0x2e4</addressOffset>
          <size>0x20</size>
        </register>
        <register>
          <name>HUFFSYMB.54</name>
          <addressOffset>0x2e8</addressOffset>
          <size>0x20</size>
        </register>
        <register>
          <name>HUFFSYMB.55</name>
          <addressOffset>0x2ec</addressOffset>
          <size>0x20</size>
        </register>
        <register>
          <name>HUFFSYMB.56</name>
          <addressOffset>0x2f0</addressOffset>
          <size>0x20</size>
        </register>
        <register>
          <name>HUFFSYMB.57</name>
          <addressOffset>0x2f4</addressOffset>
          <size>0x20</size>
        </register>
        <register>
          <name>HUFFSYMB.58</name>
          <addressOffset>0x2f8</addressOffset>
          <size>0x20</size>
        </register>
        <register>
          <name>HUFFSYMB.59</name>
          <addressOffset>0x2fc</addressOffset>
          <size>0x20</size>
        </register>
        <register>
          <name>HUFFSYMB.60</name>
          <addressOffset>0x300</addressOffset>
          <size>0x20</size>
        </register>
        <register>
          <name>HUFFSYMB.61</name>
          <addressOffset>0x304</addressOffset>
          <size>0x20</size>
        </register>
        <register>
          <name>HUFFSYMB.62</name>
          <addressOffset>0x308</addressOffset>
          <size>0x20</size>
        </register>
        <register>
          <name>HUFFSYMB.63</name>
          <addressOffset>0x30c</addressOffset>
          <size>0x20</size>
        </register>
        <register>
          <name>HUFFSYMB.64</name>
          <addressOffset>0x310</addressOffset>
          <size>0x20</size>
        </register>
        <register>
          <name>HUFFSYMB.65</name>
          <addressOffset>0x314</addressOffset>
          <size>0x20</size>
        </register>
        <register>
          <name>HUFFSYMB.66</name>
          <addressOffset>0x318</addressOffset>
          <size>0x20</size>
        </register>
        <register>
          <name>HUFFSYMB.67</name>
          <addressOffset>0x31c</addressOffset>
          <size>0x20</size>
        </register>
        <register>
          <name>HUFFSYMB.68</name>
          <addressOffset>0x320</addressOffset>
          <size>0x20</size>
        </register>
        <register>
          <name>HUFFSYMB.69</name>
          <addressOffset>0x324</addressOffset>
          <size>0x20</size>
        </register>
        <register>
          <name>HUFFSYMB.70</name>
          <addressOffset>0x328</addressOffset>
          <size>0x20</size>
        </register>
        <register>
          <name>HUFFSYMB.71</name>
          <addressOffset>0x32c</addressOffset>
          <size>0x20</size>
        </register>
        <register>
          <name>HUFFSYMB.72</name>
          <addressOffset>0x330</addressOffset>
          <size>0x20</size>
        </register>
        <register>
          <name>HUFFSYMB.73</name>
          <addressOffset>0x334</addressOffset>
          <size>0x20</size>
        </register>
        <register>
          <name>HUFFSYMB.74</name>
          <addressOffset>0x338</addressOffset>
          <size>0x20</size>
        </register>
        <register>
          <name>HUFFSYMB.75</name>
          <addressOffset>0x33c</addressOffset>
          <size>0x20</size>
        </register>
        <register>
          <name>HUFFSYMB.76</name>
          <addressOffset>0x340</addressOffset>
          <size>0x20</size>
        </register>
        <register>
          <name>HUFFSYMB.77</name>
          <addressOffset>0x344</addressOffset>
          <size>0x20</size>
        </register>
        <register>
          <name>HUFFSYMB.78</name>
          <addressOffset>0x348</addressOffset>
          <size>0x20</size>
        </register>
        <register>
          <name>HUFFSYMB.79</name>
          <addressOffset>0x34c</addressOffset>
          <size>0x20</size>
        </register>
        <register>
          <name>HUFFSYMB.80</name>
          <addressOffset>0x350</addressOffset>
          <size>0x20</size>
        </register>
        <register>
          <name>HUFFSYMB.81</name>
          <addressOffset>0x354</addressOffset>
          <size>0x20</size>
        </register>
        <register>
          <name>HUFFSYMB.82</name>
          <addressOffset>0x358</addressOffset>
          <size>0x20</size>
        </register>
        <register>
          <name>HUFFSYMB.83</name>
          <addressOffset>0x35c</addressOffset>
          <size>0x20</size>
        </register>
        <register>
          <name>DHTMEM.0</name>
          <addressOffset>0x360</addressOffset>
          <size>0x20</size>
        </register>
        <register>
          <name>DHTMEM.1</name>
          <addressOffset>0x364</addressOffset>
          <size>0x20</size>
        </register>
        <register>
          <name>DHTMEM.2</name>
          <addressOffset>0x368</addressOffset>
          <size>0x20</size>
        </register>
        <register>
          <name>DHTMEM.3</name>
          <addressOffset>0x36c</addressOffset>
          <size>0x20</size>
        </register>
        <register>
          <name>DHTMEM.4</name>
          <addressOffset>0x370</addressOffset>
          <size>0x20</size>
        </register>
        <register>
          <name>DHTMEM.5</name>
          <addressOffset>0x374</addressOffset>
          <size>0x20</size>
        </register>
        <register>
          <name>DHTMEM.6</name>
          <addressOffset>0x378</addressOffset>
          <size>0x20</size>
        </register>
        <register>
          <name>DHTMEM.7</name>
          <addressOffset>0x37c</addressOffset>
          <size>0x20</size>
        </register>
        <register>
          <name>DHTMEM.8</name>
          <addressOffset>0x380</addressOffset>
          <size>0x20</size>
        </register>
        <register>
          <name>DHTMEM.9</name>
          <addressOffset>0x384</addressOffset>
          <size>0x20</size>
        </register>
        <register>
          <name>DHTMEM.10</name>
          <addressOffset>0x388</addressOffset>
          <size>0x20</size>
        </register>
        <register>
          <name>DHTMEM.11</name>
          <addressOffset>0x38c</addressOffset>
          <size>0x20</size>
        </register>
        <register>
          <name>DHTMEM.12</name>
          <addressOffset>0x390</addressOffset>
          <size>0x20</size>
        </register>
        <register>
          <name>DHTMEM.13</name>
          <addressOffset>0x394</addressOffset>
          <size>0x20</size>
        </register>
        <register>
          <name>DHTMEM.14</name>
          <addressOffset>0x398</addressOffset>
          <size>0x20</size>
        </register>
        <register>
          <name>DHTMEM.15</name>
          <addressOffset>0x39c</addressOffset>
          <size>0x20</size>
        </register>
        <register>
          <name>DHTMEM.16</name>
          <addressOffset>0x3a0</addressOffset>
          <size>0x20</size>
        </register>
        <register>
          <name>DHTMEM.17</name>
          <addressOffset>0x3a4</addressOffset>
          <size>0x20</size>
        </register>
        <register>
          <name>DHTMEM.18</name>
          <addressOffset>0x3a8</addressOffset>
          <size>0x20</size>
        </register>
        <register>
          <name>DHTMEM.19</name>
          <addressOffset>0x3ac</addressOffset>
          <size>0x20</size>
        </register>
        <register>
          <name>DHTMEM.20</name>
          <addressOffset>0x3b0</addressOffset>
          <size>0x20</size>
        </register>
        <register>
          <name>DHTMEM.21</name>
          <addressOffset>0x3b4</addressOffset>
          <size>0x20</size>
        </register>
        <register>
          <name>DHTMEM.22</name>
          <addressOffset>0x3b8</addressOffset>
          <size>0x20</size>
        </register>
        <register>
          <name>DHTMEM.23</name>
          <addressOffset>0x3bc</addressOffset>
          <size>0x20</size>
        </register>
        <register>
          <name>DHTMEM.24</name>
          <addressOffset>0x3c0</addressOffset>
          <size>0x20</size>
        </register>
        <register>
          <name>DHTMEM.25</name>
          <addressOffset>0x3c4</addressOffset>
          <size>0x20</size>
        </register>
        <register>
          <name>DHTMEM.26</name>
          <addressOffset>0x3c8</addressOffset>
          <size>0x20</size>
        </register>
        <register>
          <name>DHTMEM.27</name>
          <addressOffset>0x3cc</addressOffset>
          <size>0x20</size>
        </register>
        <register>
          <name>DHTMEM.28</name>
          <addressOffset>0x3d0</addressOffset>
          <size>0x20</size>
        </register>
        <register>
          <name>DHTMEM.29</name>
          <addressOffset>0x3d4</addressOffset>
          <size>0x20</size>
        </register>
        <register>
          <name>DHTMEM.30</name>
          <addressOffset>0x3d8</addressOffset>
          <size>0x20</size>
        </register>
        <register>
          <name>DHTMEM.31</name>
          <addressOffset>0x3dc</addressOffset>
          <size>0x20</size>
        </register>
        <register>
          <name>DHTMEM.32</name>
          <addressOffset>0x3e0</addressOffset>
          <size>0x20</size>
        </register>
        <register>
          <name>DHTMEM.33</name>
          <addressOffset>0x3e4</addressOffset>
          <size>0x20</size>
        </register>
        <register>
          <name>DHTMEM.34</name>
          <addressOffset>0x3e8</addressOffset>
          <size>0x20</size>
        </register>
        <register>
          <name>DHTMEM.35</name>
          <addressOffset>0x3ec</addressOffset>
          <size>0x20</size>
        </register>
        <register>
          <name>DHTMEM.36</name>
          <addressOffset>0x3f0</addressOffset>
          <size>0x20</size>
        </register>
        <register>
          <name>DHTMEM.37</name>
          <addressOffset>0x3f4</addressOffset>
          <size>0x20</size>
        </register>
        <register>
          <name>DHTMEM.38</name>
          <addressOffset>0x3f8</addressOffset>
          <size>0x20</size>
        </register>
        <register>
          <name>DHTMEM.39</name>
          <addressOffset>0x3fc</addressOffset>
          <size>0x20</size>
        </register>
        <register>
          <name>DHTMEM.40</name>
          <addressOffset>0x400</addressOffset>
          <size>0x20</size>
        </register>
        <register>
          <name>DHTMEM.41</name>
          <addressOffset>0x404</addressOffset>
          <size>0x20</size>
        </register>
        <register>
          <name>DHTMEM.42</name>
          <addressOffset>0x408</addressOffset>
          <size>0x20</size>
        </register>
        <register>
          <name>DHTMEM.43</name>
          <addressOffset>0x40c</addressOffset>
          <size>0x20</size>
        </register>
        <register>
          <name>DHTMEM.44</name>
          <addressOffset>0x410</addressOffset>
          <size>0x20</size>
        </register>
        <register>
          <name>DHTMEM.45</name>
          <addressOffset>0x414</addressOffset>
          <size>0x20</size>
        </register>
        <register>
          <name>DHTMEM.46</name>
          <addressOffset>0x418</addressOffset>
          <size>0x20</size>
        </register>
        <register>
          <name>DHTMEM.47</name>
          <addressOffset>0x41c</addressOffset>
          <size>0x20</size>
        </register>
        <register>
          <name>DHTMEM.48</name>
          <addressOffset>0x420</addressOffset>
          <size>0x20</size>
        </register>
        <register>
          <name>DHTMEM.49</name>
          <addressOffset>0x424</addressOffset>
          <size>0x20</size>
        </register>
        <register>
          <name>DHTMEM.50</name>
          <addressOffset>0x428</addressOffset>
          <size>0x20</size>
        </register>
        <register>
          <name>DHTMEM.51</name>
          <addressOffset>0x42c</addressOffset>
          <size>0x20</size>
        </register>
        <register>
          <name>DHTMEM.52</name>
          <addressOffset>0x430</addressOffset>
          <size>0x20</size>
        </register>
        <register>
          <name>DHTMEM.53</name>
          <addressOffset>0x434</addressOffset>
          <size>0x20</size>
        </register>
        <register>
          <name>DHTMEM.54</name>
          <addressOffset>0x438</addressOffset>
          <size>0x20</size>
        </register>
        <register>
          <name>DHTMEM.55</name>
          <addressOffset>0x43c</addressOffset>
          <size>0x20</size>
        </register>
        <register>
          <name>DHTMEM.56</name>
          <addressOffset>0x440</addressOffset>
          <size>0x20</size>
        </register>
        <register>
          <name>DHTMEM.57</name>
          <addressOffset>0x444</addressOffset>
          <size>0x20</size>
        </register>
        <register>
          <name>DHTMEM.58</name>
          <addressOffset>0x448</addressOffset>
          <size>0x20</size>
        </register>
        <register>
          <name>DHTMEM.59</name>
          <addressOffset>0x44c</addressOffset>
          <size>0x20</size>
        </register>
        <register>
          <name>DHTMEM.60</name>
          <addressOffset>0x450</addressOffset>
          <size>0x20</size>
        </register>
        <register>
          <name>DHTMEM.61</name>
          <addressOffset>0x454</addressOffset>
          <size>0x20</size>
        </register>
        <register>
          <name>DHTMEM.62</name>
          <addressOffset>0x458</addressOffset>
          <size>0x20</size>
        </register>
        <register>
          <name>DHTMEM.63</name>
          <addressOffset>0x45c</addressOffset>
          <size>0x20</size>
        </register>
        <register>
          <name>DHTMEM.64</name>
          <addressOffset>0x460</addressOffset>
          <size>0x20</size>
        </register>
        <register>
          <name>DHTMEM.65</name>
          <addressOffset>0x464</addressOffset>
          <size>0x20</size>
        </register>
        <register>
          <name>DHTMEM.66</name>
          <addressOffset>0x468</addressOffset>
          <size>0x20</size>
        </register>
        <register>
          <name>DHTMEM.67</name>
          <addressOffset>0x46c</addressOffset>
          <size>0x20</size>
        </register>
        <register>
          <name>DHTMEM.68</name>
          <addressOffset>0x470</addressOffset>
          <size>0x20</size>
        </register>
        <register>
          <name>DHTMEM.69</name>
          <addressOffset>0x474</addressOffset>
          <size>0x20</size>
        </register>
        <register>
          <name>DHTMEM.70</name>
          <addressOffset>0x478</addressOffset>
          <size>0x20</size>
        </register>
        <register>
          <name>DHTMEM.71</name>
          <addressOffset>0x47c</addressOffset>
          <size>0x20</size>
        </register>
        <register>
          <name>DHTMEM.72</name>
          <addressOffset>0x480</addressOffset>
          <size>0x20</size>
        </register>
        <register>
          <name>DHTMEM.73</name>
          <addressOffset>0x484</addressOffset>
          <size>0x20</size>
        </register>
        <register>
          <name>DHTMEM.74</name>
          <addressOffset>0x488</addressOffset>
          <size>0x20</size>
        </register>
        <register>
          <name>DHTMEM.75</name>
          <addressOffset>0x48c</addressOffset>
          <size>0x20</size>
        </register>
        <register>
          <name>DHTMEM.76</name>
          <addressOffset>0x490</addressOffset>
          <size>0x20</size>
        </register>
        <register>
          <name>DHTMEM.77</name>
          <addressOffset>0x494</addressOffset>
          <size>0x20</size>
        </register>
        <register>
          <name>DHTMEM.78</name>
          <addressOffset>0x498</addressOffset>
          <size>0x20</size>
        </register>
        <register>
          <name>DHTMEM.79</name>
          <addressOffset>0x49c</addressOffset>
          <size>0x20</size>
        </register>
        <register>
          <name>DHTMEM.80</name>
          <addressOffset>0x4a0</addressOffset>
          <size>0x20</size>
        </register>
        <register>
          <name>DHTMEM.81</name>
          <addressOffset>0x4a4</addressOffset>
          <size>0x20</size>
        </register>
        <register>
          <name>DHTMEM.82</name>
          <addressOffset>0x4a8</addressOffset>
          <size>0x20</size>
        </register>
        <register>
          <name>DHTMEM.83</name>
          <addressOffset>0x4ac</addressOffset>
          <size>0x20</size>
        </register>
        <register>
          <name>DHTMEM.84</name>
          <addressOffset>0x4b0</addressOffset>
          <size>0x20</size>
        </register>
        <register>
          <name>DHTMEM.85</name>
          <addressOffset>0x4b4</addressOffset>
          <size>0x20</size>
        </register>
        <register>
          <name>DHTMEM.86</name>
          <addressOffset>0x4b8</addressOffset>
          <size>0x20</size>
        </register>
        <register>
          <name>DHTMEM.87</name>
          <addressOffset>0x4bc</addressOffset>
          <size>0x20</size>
        </register>
        <register>
          <name>DHTMEM.88</name>
          <addressOffset>0x4c0</addressOffset>
          <size>0x20</size>
        </register>
        <register>
          <name>DHTMEM.89</name>
          <addressOffset>0x4c4</addressOffset>
          <size>0x20</size>
        </register>
        <register>
          <name>DHTMEM.90</name>
          <addressOffset>0x4c8</addressOffset>
          <size>0x20</size>
        </register>
        <register>
          <name>DHTMEM.91</name>
          <addressOffset>0x4cc</addressOffset>
          <size>0x20</size>
        </register>
        <register>
          <name>DHTMEM.92</name>
          <addressOffset>0x4d0</addressOffset>
          <size>0x20</size>
        </register>
        <register>
          <name>DHTMEM.93</name>
          <addressOffset>0x4d4</addressOffset>
          <size>0x20</size>
        </register>
        <register>
          <name>DHTMEM.94</name>
          <addressOffset>0x4d8</addressOffset>
          <size>0x20</size>
        </register>
        <register>
          <name>DHTMEM.95</name>
          <addressOffset>0x4dc</addressOffset>
          <size>0x20</size>
        </register>
        <register>
          <name>DHTMEM.96</name>
          <addressOffset>0x4e0</addressOffset>
          <size>0x20</size>
        </register>
        <register>
          <name>DHTMEM.97</name>
          <addressOffset>0x4e4</addressOffset>
          <size>0x20</size>
        </register>
        <register>
          <name>DHTMEM.98</name>
          <addressOffset>0x4e8</addressOffset>
          <size>0x20</size>
        </register>
        <register>
          <name>DHTMEM.99</name>
          <addressOffset>0x4ec</addressOffset>
          <size>0x20</size>
        </register>
        <register>
          <name>DHTMEM.100</name>
          <addressOffset>0x4f0</addressOffset>
          <size>0x20</size>
        </register>
        <register>
          <name>DHTMEM.101</name>
          <addressOffset>0x4f4</addressOffset>
          <size>0x20</size>
        </register>
        <register>
          <name>DHTMEM.102</name>
          <addressOffset>0x4f8</addressOffset>
          <size>0x20</size>
        </register>
        <register>
          <name>HUFFENC_AC0.0</name>
          <addressOffset>0x500</addressOffset>
          <size>0x20</size>
        </register>
        <register>
          <name>HUFFENC_AC0.1</name>
          <addressOffset>0x504</addressOffset>
          <size>0x20</size>
        </register>
        <register>
          <name>HUFFENC_AC0.2</name>
          <addressOffset>0x508</addressOffset>
          <size>0x20</size>
        </register>
        <register>
          <name>HUFFENC_AC0.3</name>
          <addressOffset>0x50c</addressOffset>
          <size>0x20</size>
        </register>
        <register>
          <name>HUFFENC_AC0.4</name>
          <addressOffset>0x510</addressOffset>
          <size>0x20</size>
        </register>
        <register>
          <name>HUFFENC_AC0.5</name>
          <addressOffset>0x514</addressOffset>
          <size>0x20</size>
        </register>
        <register>
          <name>HUFFENC_AC0.6</name>
          <addressOffset>0x518</addressOffset>
          <size>0x20</size>
        </register>
        <register>
          <name>HUFFENC_AC0.7</name>
          <addressOffset>0x51c</addressOffset>
          <size>0x20</size>
        </register>
        <register>
          <name>HUFFENC_AC0.8</name>
          <addressOffset>0x520</addressOffset>
          <size>0x20</size>
        </register>
        <register>
          <name>HUFFENC_AC0.9</name>
          <addressOffset>0x524</addressOffset>
          <size>0x20</size>
        </register>
        <register>
          <name>HUFFENC_AC0.10</name>
          <addressOffset>0x528</addressOffset>
          <size>0x20</size>
        </register>
        <register>
          <name>HUFFENC_AC0.11</name>
          <addressOffset>0x52c</addressOffset>
          <size>0x20</size>
        </register>
        <register>
          <name>HUFFENC_AC0.12</name>
          <addressOffset>0x530</addressOffset>
          <size>0x20</size>
        </register>
        <register>
          <name>HUFFENC_AC0.13</name>
          <addressOffset>0x534</addressOffset>
          <size>0x20</size>
        </register>
        <register>
          <name>HUFFENC_AC0.14</name>
          <addressOffset>0x538</addressOffset>
          <size>0x20</size>
        </register>
        <register>
          <name>HUFFENC_AC0.15</name>
          <addressOffset>0x53c</addressOffset>
          <size>0x20</size>
        </register>
        <register>
          <name>HUFFENC_AC0.16</name>
          <addressOffset>0x540</addressOffset>
          <size>0x20</size>
        </register>
        <register>
          <name>HUFFENC_AC0.17</name>
          <addressOffset>0x544</addressOffset>
          <size>0x20</size>
        </register>
        <register>
          <name>HUFFENC_AC0.18</name>
          <addressOffset>0x548</addressOffset>
          <size>0x20</size>
        </register>
        <register>
          <name>HUFFENC_AC0.19</name>
          <addressOffset>0x54c</addressOffset>
          <size>0x20</size>
        </register>
        <register>
          <name>HUFFENC_AC0.20</name>
          <addressOffset>0x550</addressOffset>
          <size>0x20</size>
        </register>
        <register>
          <name>HUFFENC_AC0.21</name>
          <addressOffset>0x554</addressOffset>
          <size>0x20</size>
        </register>
        <register>
          <name>HUFFENC_AC0.22</name>
          <addressOffset>0x558</addressOffset>
          <size>0x20</size>
        </register>
        <register>
          <name>HUFFENC_AC0.23</name>
          <addressOffset>0x55c</addressOffset>
          <size>0x20</size>
        </register>
        <register>
          <name>HUFFENC_AC0.24</name>
          <addressOffset>0x560</addressOffset>
          <size>0x20</size>
        </register>
        <register>
          <name>HUFFENC_AC0.25</name>
          <addressOffset>0x564</addressOffset>
          <size>0x20</size>
        </register>
        <register>
          <name>HUFFENC_AC0.26</name>
          <addressOffset>0x568</addressOffset>
          <size>0x20</size>
        </register>
        <register>
          <name>HUFFENC_AC0.27</name>
          <addressOffset>0x56c</addressOffset>
          <size>0x20</size>
        </register>
        <register>
          <name>HUFFENC_AC0.28</name>
          <addressOffset>0x570</addressOffset>
          <size>0x20</size>
        </register>
        <register>
          <name>HUFFENC_AC0.29</name>
          <addressOffset>0x574</addressOffset>
          <size>0x20</size>
        </register>
        <register>
          <name>HUFFENC_AC0.30</name>
          <addressOffset>0x578</addressOffset>
          <size>0x20</size>
        </register>
        <register>
          <name>HUFFENC_AC0.31</name>
          <addressOffset>0x57c</addressOffset>
          <size>0x20</size>
        </register>
        <register>
          <name>HUFFENC_AC0.32</name>
          <addressOffset>0x580</addressOffset>
          <size>0x20</size>
        </register>
        <register>
          <name>HUFFENC_AC0.33</name>
          <addressOffset>0x584</addressOffset>
          <size>0x20</size>
        </register>
        <register>
          <name>HUFFENC_AC0.34</name>
          <addressOffset>0x588</addressOffset>
          <size>0x20</size>
        </register>
        <register>
          <name>HUFFENC_AC0.35</name>
          <addressOffset>0x58c</addressOffset>
          <size>0x20</size>
        </register>
        <register>
          <name>HUFFENC_AC0.36</name>
          <addressOffset>0x590</addressOffset>
          <size>0x20</size>
        </register>
        <register>
          <name>HUFFENC_AC0.37</name>
          <addressOffset>0x594</addressOffset>
          <size>0x20</size>
        </register>
        <register>
          <name>HUFFENC_AC0.38</name>
          <addressOffset>0x598</addressOffset>
          <size>0x20</size>
        </register>
        <register>
          <name>HUFFENC_AC0.39</name>
          <addressOffset>0x59c</addressOffset>
          <size>0x20</size>
        </register>
        <register>
          <name>HUFFENC_AC0.40</name>
          <addressOffset>0x5a0</addressOffset>
          <size>0x20</size>
        </register>
        <register>
          <name>HUFFENC_AC0.41</name>
          <addressOffset>0x5a4</addressOffset>
          <size>0x20</size>
        </register>
        <register>
          <name>HUFFENC_AC0.42</name>
          <addressOffset>0x5a8</addressOffset>
          <size>0x20</size>
        </register>
        <register>
          <name>HUFFENC_AC0.43</name>
          <addressOffset>0x5ac</addressOffset>
          <size>0x20</size>
        </register>
        <register>
          <name>HUFFENC_AC0.44</name>
          <addressOffset>0x5b0</addressOffset>
          <size>0x20</size>
        </register>
        <register>
          <name>HUFFENC_AC0.45</name>
          <addressOffset>0x5b4</addressOffset>
          <size>0x20</size>
        </register>
        <register>
          <name>HUFFENC_AC0.46</name>
          <addressOffset>0x5b8</addressOffset>
          <size>0x20</size>
        </register>
        <register>
          <name>HUFFENC_AC0.47</name>
          <addressOffset>0x5bc</addressOffset>
          <size>0x20</size>
        </register>
        <register>
          <name>HUFFENC_AC0.48</name>
          <addressOffset>0x5c0</addressOffset>
          <size>0x20</size>
        </register>
        <register>
          <name>HUFFENC_AC0.49</name>
          <addressOffset>0x5c4</addressOffset>
          <size>0x20</size>
        </register>
        <register>
          <name>HUFFENC_AC0.50</name>
          <addressOffset>0x5c8</addressOffset>
          <size>0x20</size>
        </register>
        <register>
          <name>HUFFENC_AC0.51</name>
          <addressOffset>0x5cc</addressOffset>
          <size>0x20</size>
        </register>
        <register>
          <name>HUFFENC_AC0.52</name>
          <addressOffset>0x5d0</addressOffset>
          <size>0x20</size>
        </register>
        <register>
          <name>HUFFENC_AC0.53</name>
          <addressOffset>0x5d4</addressOffset>
          <size>0x20</size>
        </register>
        <register>
          <name>HUFFENC_AC0.54</name>
          <addressOffset>0x5d8</addressOffset>
          <size>0x20</size>
        </register>
        <register>
          <name>HUFFENC_AC0.55</name>
          <addressOffset>0x5dc</addressOffset>
          <size>0x20</size>
        </register>
        <register>
          <name>HUFFENC_AC0.56</name>
          <addressOffset>0x5e0</addressOffset>
          <size>0x20</size>
        </register>
        <register>
          <name>HUFFENC_AC0.57</name>
          <addressOffset>0x5e4</addressOffset>
          <size>0x20</size>
        </register>
        <register>
          <name>HUFFENC_AC0.58</name>
          <addressOffset>0x5e8</addressOffset>
          <size>0x20</size>
        </register>
        <register>
          <name>HUFFENC_AC0.59</name>
          <addressOffset>0x5ec</addressOffset>
          <size>0x20</size>
        </register>
        <register>
          <name>HUFFENC_AC0.60</name>
          <addressOffset>0x5f0</addressOffset>
          <size>0x20</size>
        </register>
        <register>
          <name>HUFFENC_AC0.61</name>
          <addressOffset>0x5f4</addressOffset>
          <size>0x20</size>
        </register>
        <register>
          <name>HUFFENC_AC0.62</name>
          <addressOffset>0x5f8</addressOffset>
          <size>0x20</size>
        </register>
        <register>
          <name>HUFFENC_AC0.63</name>
          <addressOffset>0x5fc</addressOffset>
          <size>0x20</size>
        </register>
        <register>
          <name>HUFFENC_AC0.64</name>
          <addressOffset>0x600</addressOffset>
          <size>0x20</size>
        </register>
        <register>
          <name>HUFFENC_AC0.65</name>
          <addressOffset>0x604</addressOffset>
          <size>0x20</size>
        </register>
        <register>
          <name>HUFFENC_AC0.66</name>
          <addressOffset>0x608</addressOffset>
          <size>0x20</size>
        </register>
        <register>
          <name>HUFFENC_AC0.67</name>
          <addressOffset>0x60c</addressOffset>
          <size>0x20</size>
        </register>
        <register>
          <name>HUFFENC_AC0.68</name>
          <addressOffset>0x610</addressOffset>
          <size>0x20</size>
        </register>
        <register>
          <name>HUFFENC_AC0.69</name>
          <addressOffset>0x614</addressOffset>
          <size>0x20</size>
        </register>
        <register>
          <name>HUFFENC_AC0.70</name>
          <addressOffset>0x618</addressOffset>
          <size>0x20</size>
        </register>
        <register>
          <name>HUFFENC_AC0.71</name>
          <addressOffset>0x61c</addressOffset>
          <size>0x20</size>
        </register>
        <register>
          <name>HUFFENC_AC0.72</name>
          <addressOffset>0x620</addressOffset>
          <size>0x20</size>
        </register>
        <register>
          <name>HUFFENC_AC0.73</name>
          <addressOffset>0x624</addressOffset>
          <size>0x20</size>
        </register>
        <register>
          <name>HUFFENC_AC0.74</name>
          <addressOffset>0x628</addressOffset>
          <size>0x20</size>
        </register>
        <register>
          <name>HUFFENC_AC0.75</name>
          <addressOffset>0x62c</addressOffset>
          <size>0x20</size>
        </register>
        <register>
          <name>HUFFENC_AC0.76</name>
          <addressOffset>0x630</addressOffset>
          <size>0x20</size>
        </register>
        <register>
          <name>HUFFENC_AC0.77</name>
          <addressOffset>0x634</addressOffset>
          <size>0x20</size>
        </register>
        <register>
          <name>HUFFENC_AC0.78</name>
          <addressOffset>0x638</addressOffset>
          <size>0x20</size>
        </register>
        <register>
          <name>HUFFENC_AC0.79</name>
          <addressOffset>0x63c</addressOffset>
          <size>0x20</size>
        </register>
        <register>
          <name>HUFFENC_AC0.80</name>
          <addressOffset>0x640</addressOffset>
          <size>0x20</size>
        </register>
        <register>
          <name>HUFFENC_AC0.81</name>
          <addressOffset>0x644</addressOffset>
          <size>0x20</size>
        </register>
        <register>
          <name>HUFFENC_AC0.82</name>
          <addressOffset>0x648</addressOffset>
          <size>0x20</size>
        </register>
        <register>
          <name>HUFFENC_AC0.83</name>
          <addressOffset>0x64c</addressOffset>
          <size>0x20</size>
        </register>
        <register>
          <name>HUFFENC_AC0.84</name>
          <addressOffset>0x650</addressOffset>
          <size>0x20</size>
        </register>
        <register>
          <name>HUFFENC_AC0.85</name>
          <addressOffset>0x654</addressOffset>
          <size>0x20</size>
        </register>
        <register>
          <name>HUFFENC_AC0.86</name>
          <addressOffset>0x658</addressOffset>
          <size>0x20</size>
        </register>
        <register>
          <name>HUFFENC_AC0.87</name>
          <addressOffset>0x65c</addressOffset>
          <size>0x20</size>
        </register>
        <register>
          <name>HUFFENC_AC1.0</name>
          <addressOffset>0x660</addressOffset>
          <size>0x20</size>
        </register>
        <register>
          <name>HUFFENC_AC1.1</name>
          <addressOffset>0x664</addressOffset>
          <size>0x20</size>
        </register>
        <register>
          <name>HUFFENC_AC1.2</name>
          <addressOffset>0x668</addressOffset>
          <size>0x20</size>
        </register>
        <register>
          <name>HUFFENC_AC1.3</name>
          <addressOffset>0x66c</addressOffset>
          <size>0x20</size>
        </register>
        <register>
          <name>HUFFENC_AC1.4</name>
          <addressOffset>0x670</addressOffset>
          <size>0x20</size>
        </register>
        <register>
          <name>HUFFENC_AC1.5</name>
          <addressOffset>0x674</addressOffset>
          <size>0x20</size>
        </register>
        <register>
          <name>HUFFENC_AC1.6</name>
          <addressOffset>0x678</addressOffset>
          <size>0x20</size>
        </register>
        <register>
          <name>HUFFENC_AC1.7</name>
          <addressOffset>0x67c</addressOffset>
          <size>0x20</size>
        </register>
        <register>
          <name>HUFFENC_AC1.8</name>
          <addressOffset>0x680</addressOffset>
          <size>0x20</size>
        </register>
        <register>
          <name>HUFFENC_AC1.9</name>
          <addressOffset>0x684</addressOffset>
          <size>0x20</size>
        </register>
        <register>
          <name>HUFFENC_AC1.10</name>
          <addressOffset>0x688</addressOffset>
          <size>0x20</size>
        </register>
        <register>
          <name>HUFFENC_AC1.11</name>
          <addressOffset>0x68c</addressOffset>
          <size>0x20</size>
        </register>
        <register>
          <name>HUFFENC_AC1.12</name>
          <addressOffset>0x690</addressOffset>
          <size>0x20</size>
        </register>
        <register>
          <name>HUFFENC_AC1.13</name>
          <addressOffset>0x694</addressOffset>
          <size>0x20</size>
        </register>
        <register>
          <name>HUFFENC_AC1.14</name>
          <addressOffset>0x698</addressOffset>
          <size>0x20</size>
        </register>
        <register>
          <name>HUFFENC_AC1.15</name>
          <addressOffset>0x69c</addressOffset>
          <size>0x20</size>
        </register>
        <register>
          <name>HUFFENC_AC1.16</name>
          <addressOffset>0x6a0</addressOffset>
          <size>0x20</size>
        </register>
        <register>
          <name>HUFFENC_AC1.17</name>
          <addressOffset>0x6a4</addressOffset>
          <size>0x20</size>
        </register>
        <register>
          <name>HUFFENC_AC1.18</name>
          <addressOffset>0x6a8</addressOffset>
          <size>0x20</size>
        </register>
        <register>
          <name>HUFFENC_AC1.19</name>
          <addressOffset>0x6ac</addressOffset>
          <size>0x20</size>
        </register>
        <register>
          <name>HUFFENC_AC1.20</name>
          <addressOffset>0x6b0</addressOffset>
          <size>0x20</size>
        </register>
        <register>
          <name>HUFFENC_AC1.21</name>
          <addressOffset>0x6b4</addressOffset>
          <size>0x20</size>
        </register>
        <register>
          <name>HUFFENC_AC1.22</name>
          <addressOffset>0x6b8</addressOffset>
          <size>0x20</size>
        </register>
        <register>
          <name>HUFFENC_AC1.23</name>
          <addressOffset>0x6bc</addressOffset>
          <size>0x20</size>
        </register>
        <register>
          <name>HUFFENC_AC1.24</name>
          <addressOffset>0x6c0</addressOffset>
          <size>0x20</size>
        </register>
        <register>
          <name>HUFFENC_AC1.25</name>
          <addressOffset>0x6c4</addressOffset>
          <size>0x20</size>
        </register>
        <register>
          <name>HUFFENC_AC1.26</name>
          <addressOffset>0x6c8</addressOffset>
          <size>0x20</size>
        </register>
        <register>
          <name>HUFFENC_AC1.27</name>
          <addressOffset>0x6cc</addressOffset>
          <size>0x20</size>
        </register>
        <register>
          <name>HUFFENC_AC1.28</name>
          <addressOffset>0x6d0</addressOffset>
          <size>0x20</size>
        </register>
        <register>
          <name>HUFFENC_AC1.29</name>
          <addressOffset>0x6d4</addressOffset>
          <size>0x20</size>
        </register>
        <register>
          <name>HUFFENC_AC1.30</name>
          <addressOffset>0x6d8</addressOffset>
          <size>0x20</size>
        </register>
        <register>
          <name>HUFFENC_AC1.31</name>
          <addressOffset>0x6dc</addressOffset>
          <size>0x20</size>
        </register>
        <register>
          <name>HUFFENC_AC1.32</name>
          <addressOffset>0x6e0</addressOffset>
          <size>0x20</size>
        </register>
        <register>
          <name>HUFFENC_AC1.33</name>
          <addressOffset>0x6e4</addressOffset>
          <size>0x20</size>
        </register>
        <register>
          <name>HUFFENC_AC1.34</name>
          <addressOffset>0x6e8</addressOffset>
          <size>0x20</size>
        </register>
        <register>
          <name>HUFFENC_AC1.35</name>
          <addressOffset>0x6ec</addressOffset>
          <size>0x20</size>
        </register>
        <register>
          <name>HUFFENC_AC1.36</name>
          <addressOffset>0x6f0</addressOffset>
          <size>0x20</size>
        </register>
        <register>
          <name>HUFFENC_AC1.37</name>
          <addressOffset>0x6f4</addressOffset>
          <size>0x20</size>
        </register>
        <register>
          <name>HUFFENC_AC1.38</name>
          <addressOffset>0x6f8</addressOffset>
          <size>0x20</size>
        </register>
        <register>
          <name>HUFFENC_AC1.39</name>
          <addressOffset>0x6fc</addressOffset>
          <size>0x20</size>
        </register>
        <register>
          <name>HUFFENC_AC1.40</name>
          <addressOffset>0x700</addressOffset>
          <size>0x20</size>
        </register>
        <register>
          <name>HUFFENC_AC1.41</name>
          <addressOffset>0x704</addressOffset>
          <size>0x20</size>
        </register>
        <register>
          <name>HUFFENC_AC1.42</name>
          <addressOffset>0x708</addressOffset>
          <size>0x20</size>
        </register>
        <register>
          <name>HUFFENC_AC1.43</name>
          <addressOffset>0x70c</addressOffset>
          <size>0x20</size>
        </register>
        <register>
          <name>HUFFENC_AC1.44</name>
          <addressOffset>0x710</addressOffset>
          <size>0x20</size>
        </register>
        <register>
          <name>HUFFENC_AC1.45</name>
          <addressOffset>0x714</addressOffset>
          <size>0x20</size>
        </register>
        <register>
          <name>HUFFENC_AC1.46</name>
          <addressOffset>0x718</addressOffset>
          <size>0x20</size>
        </register>
        <register>
          <name>HUFFENC_AC1.47</name>
          <addressOffset>0x71c</addressOffset>
          <size>0x20</size>
        </register>
        <register>
          <name>HUFFENC_AC1.48</name>
          <addressOffset>0x720</addressOffset>
          <size>0x20</size>
        </register>
        <register>
          <name>HUFFENC_AC1.49</name>
          <addressOffset>0x724</addressOffset>
          <size>0x20</size>
        </register>
        <register>
          <name>HUFFENC_AC1.50</name>
          <addressOffset>0x728</addressOffset>
          <size>0x20</size>
        </register>
        <register>
          <name>HUFFENC_AC1.51</name>
          <addressOffset>0x72c</addressOffset>
          <size>0x20</size>
        </register>
        <register>
          <name>HUFFENC_AC1.52</name>
          <addressOffset>0x730</addressOffset>
          <size>0x20</size>
        </register>
        <register>
          <name>HUFFENC_AC1.53</name>
          <addressOffset>0x734</addressOffset>
          <size>0x20</size>
        </register>
        <register>
          <name>HUFFENC_AC1.54</name>
          <addressOffset>0x738</addressOffset>
          <size>0x20</size>
        </register>
        <register>
          <name>HUFFENC_AC1.55</name>
          <addressOffset>0x73c</addressOffset>
          <size>0x20</size>
        </register>
        <register>
          <name>HUFFENC_AC1.56</name>
          <addressOffset>0x740</addressOffset>
          <size>0x20</size>
        </register>
        <register>
          <name>HUFFENC_AC1.57</name>
          <addressOffset>0x744</addressOffset>
          <size>0x20</size>
        </register>
        <register>
          <name>HUFFENC_AC1.58</name>
          <addressOffset>0x748</addressOffset>
          <size>0x20</size>
        </register>
        <register>
          <name>HUFFENC_AC1.59</name>
          <addressOffset>0x74c</addressOffset>
          <size>0x20</size>
        </register>
        <register>
          <name>HUFFENC_AC1.60</name>
          <addressOffset>0x750</addressOffset>
          <size>0x20</size>
        </register>
        <register>
          <name>HUFFENC_AC1.61</name>
          <addressOffset>0x754</addressOffset>
          <size>0x20</size>
        </register>
        <register>
          <name>HUFFENC_AC1.62</name>
          <addressOffset>0x758</addressOffset>
          <size>0x20</size>
        </register>
        <register>
          <name>HUFFENC_AC1.63</name>
          <addressOffset>0x75c</addressOffset>
          <size>0x20</size>
        </register>
        <register>
          <name>HUFFENC_AC1.64</name>
          <addressOffset>0x760</addressOffset>
          <size>0x20</size>
        </register>
        <register>
          <name>HUFFENC_AC1.65</name>
          <addressOffset>0x764</addressOffset>
          <size>0x20</size>
        </register>
        <register>
          <name>HUFFENC_AC1.66</name>
          <addressOffset>0x768</addressOffset>
          <size>0x20</size>
        </register>
        <register>
          <name>HUFFENC_AC1.67</name>
          <addressOffset>0x76c</addressOffset>
          <size>0x20</size>
        </register>
        <register>
          <name>HUFFENC_AC1.68</name>
          <addressOffset>0x770</addressOffset>
          <size>0x20</size>
        </register>
        <register>
          <name>HUFFENC_AC1.69</name>
          <addressOffset>0x774</addressOffset>
          <size>0x20</size>
        </register>
        <register>
          <name>HUFFENC_AC1.70</name>
          <addressOffset>0x778</addressOffset>
          <size>0x20</size>
        </register>
        <register>
          <name>HUFFENC_AC1.71</name>
          <addressOffset>0x77c</addressOffset>
          <size>0x20</size>
        </register>
        <register>
          <name>HUFFENC_AC1.72</name>
          <addressOffset>0x780</addressOffset>
          <size>0x20</size>
        </register>
        <register>
          <name>HUFFENC_AC1.73</name>
          <addressOffset>0x784</addressOffset>
          <size>0x20</size>
        </register>
        <register>
          <name>HUFFENC_AC1.74</name>
          <addressOffset>0x788</addressOffset>
          <size>0x20</size>
        </register>
        <register>
          <name>HUFFENC_AC1.75</name>
          <addressOffset>0x78c</addressOffset>
          <size>0x20</size>
        </register>
        <register>
          <name>HUFFENC_AC1.76</name>
          <addressOffset>0x790</addressOffset>
          <size>0x20</size>
        </register>
        <register>
          <name>HUFFENC_AC1.77</name>
          <addressOffset>0x794</addressOffset>
          <size>0x20</size>
        </register>
        <register>
          <name>HUFFENC_AC1.78</name>
          <addressOffset>0x798</addressOffset>
          <size>0x20</size>
        </register>
        <register>
          <name>HUFFENC_AC1.79</name>
          <addressOffset>0x79c</addressOffset>
          <size>0x20</size>
        </register>
        <register>
          <name>HUFFENC_AC1.80</name>
          <addressOffset>0x7a0</addressOffset>
          <size>0x20</size>
        </register>
        <register>
          <name>HUFFENC_AC1.81</name>
          <addressOffset>0x7a4</addressOffset>
          <size>0x20</size>
        </register>
        <register>
          <name>HUFFENC_AC1.82</name>
          <addressOffset>0x7a8</addressOffset>
          <size>0x20</size>
        </register>
        <register>
          <name>HUFFENC_AC1.83</name>
          <addressOffset>0x7ac</addressOffset>
          <size>0x20</size>
        </register>
        <register>
          <name>HUFFENC_AC1.84</name>
          <addressOffset>0x7b0</addressOffset>
          <size>0x20</size>
        </register>
        <register>
          <name>HUFFENC_AC1.85</name>
          <addressOffset>0x7b4</addressOffset>
          <size>0x20</size>
        </register>
        <register>
          <name>HUFFENC_AC1.86</name>
          <addressOffset>0x7b8</addressOffset>
          <size>0x20</size>
        </register>
        <register>
          <name>HUFFENC_AC1.87</name>
          <addressOffset>0x7bc</addressOffset>
          <size>0x20</size>
        </register>
        <register>
          <name>HUFFENC_DC0.0</name>
          <addressOffset>0x7c0</addressOffset>
          <size>0x20</size>
        </register>
        <register>
          <name>HUFFENC_DC0.1</name>
          <addressOffset>0x7c4</addressOffset>
          <size>0x20</size>
        </register>
        <register>
          <name>HUFFENC_DC0.2</name>
          <addressOffset>0x7c8</addressOffset>
          <size>0x20</size>
        </register>
        <register>
          <name>HUFFENC_DC0.3</name>
          <addressOffset>0x7cc</addressOffset>
          <size>0x20</size>
        </register>
        <register>
          <name>HUFFENC_DC0.4</name>
          <addressOffset>0x7d0</addressOffset>
          <size>0x20</size>
        </register>
        <register>
          <name>HUFFENC_DC0.5</name>
          <addressOffset>0x7d4</addressOffset>
          <size>0x20</size>
        </register>
        <register>
          <name>HUFFENC_DC0.6</name>
          <addressOffset>0x7d8</addressOffset>
          <size>0x20</size>
        </register>
        <register>
          <name>HUFFENC_DC0.7</name>
          <addressOffset>0x7dc</addressOffset>
          <size>0x20</size>
        </register>
        <register>
          <name>HUFFENC_DC1.0</name>
          <addressOffset>0x7e0</addressOffset>
          <size>0x20</size>
        </register>
        <register>
          <name>HUFFENC_DC1.1</name>
          <addressOffset>0x7e4</addressOffset>
          <size>0x20</size>
        </register>
        <register>
          <name>HUFFENC_DC1.2</name>
          <addressOffset>0x7e8</addressOffset>
          <size>0x20</size>
        </register>
        <register>
          <name>HUFFENC_DC1.3</name>
          <addressOffset>0x7ec</addressOffset>
          <size>0x20</size>
        </register>
        <register>
          <name>HUFFENC_DC1.4</name>
          <addressOffset>0x7f0</addressOffset>
          <size>0x20</size>
        </register>
        <register>
          <name>HUFFENC_DC1.5</name>
          <addressOffset>0x7f4</addressOffset>
          <size>0x20</size>
        </register>
        <register>
          <name>HUFFENC_DC1.6</name>
          <addressOffset>0x7f8</addressOffset>
          <size>0x20</size>
        </register>
        <register>
          <name>HUFFENC_DC1.7</name>
          <addressOffset>0x7fc</addressOffset>
          <size>0x20</size>
        </register>
      </registers>
    </peripheral>
    <peripheral>
      <name>FMC_Bank1_R</name>
      <baseAddress>0x52004000</baseAddress>
      <registers>
        <register>
          <name>BTCR.0</name>
          <addressOffset>0x0</addressOffset>
          <size>0x20</size>
        </register>
        <register>
          <name>BTCR.1</name>
          <addressOffset>0x4</addressOffset>
          <size>0x20</size>
        </register>
        <register>
          <name>BTCR.2</name>
          <addressOffset>0x8</addressOffset>
          <size>0x20</size>
        </register>
        <register>
          <name>BTCR.3</name>
          <addressOffset>0xc</addressOffset>
          <size>0x20</size>
        </register>
        <register>
          <name>BTCR.4</name>
          <addressOffset>0x10</addressOffset>
          <size>0x20</size>
        </register>
        <register>
          <name>BTCR.5</name>
          <addressOffset>0x14</addressOffset>
          <size>0x20</size>
        </register>
        <register>
          <name>BTCR.6</name>
          <addressOffset>0x18</addressOffset>
          <size>0x20</size>
        </register>
        <register>
          <name>BTCR.7</name>
          <addressOffset>0x1c</addressOffset>
          <size>0x20</size>
        </register>
      </registers>
    </peripheral>
    <peripheral>
      <name>FMC_Bank2_R</name>
      <baseAddress>0x52004060</baseAddress>
      <registers>
        <register>
          <name>PCR2</name>
          <addressOffset>0x0</addressOffset>
          <size>0x20</size>
        </register>
        <register>
          <name>SR2</name>
          <addressOffset>0x4</addressOffset>
          <size>0x20</size>
        </register>
        <register>
          <name>PMEM2</name>
          <addressOffset>0x8</addressOffset>
          <size>0x20</size>
        </register>
        <register>
          <name>PATT2</name>
          <addressOffset>0xc</addressOffset>
          <size>0x20</size>
        </register>
        <register>
          <name>ECCR2</name>
          <addressOffset>0x14</addressOffset>
          <size>0x20</size>
        </register>
      </registers>
    </peripheral>
    <peripheral>
      <name>FMC_Bank3_R</name>
      <baseAddress>0x52004080</baseAddress>
      <registers>
        <register>
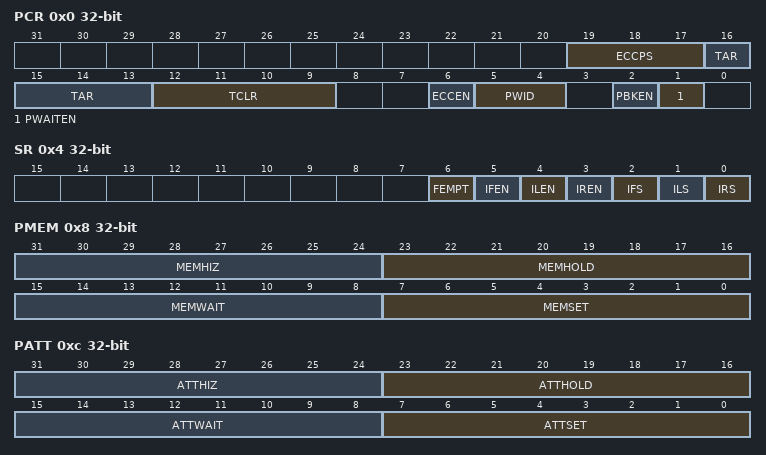
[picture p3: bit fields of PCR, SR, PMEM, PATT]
          <name>PCR</name>
          <addressOffset>0x0</addressOffset>
          <size>0x20</size>
          <fields>
            <field>
              <name>PWAITEN</name>
              <bitOffset>1</bitOffset>
              <bitWidth>1</bitWidth>
            </field>
            <field>
              <name>PBKEN</name>
              <bitOffset>2</bitOffset>
              <bitWidth>1</bitWidth>
            </field>
            <field>
              <name>PWID</name>
              <bitOffset>4</bitOffset>
              <bitWidth>2</bitWidth>
            </field>
            <field>
              <name>ECCEN</name>
              <bitOffset>6</bitOffset>
              <bitWidth>1</bitWidth>
            </field>
            <field>
              <name>TCLR</name>
              <bitOffset>9</bitOffset>
              <bitWidth>4</bitWidth>
            </field>
            <field>
              <name>TAR</name>
              <bitOffset>13</bitOffset>
              <bitWidth>4</bitWidth>
            </field>
            <field>
              <name>ECCPS</name>
              <bitOffset>17</bitOffset>
              <bitWidth>3</bitWidth>
            </field>
          </fields>
        </register>
        <register>
          <name>SR</name>
          <addressOffset>0x4</addressOffset>
          <size>0x20</size>
          <fields>
            <field>
              <name>IRS</name>
              <bitOffset>0</bitOffset>
              <bitWidth>1</bitWidth>
            </field>
            <field>
              <name>ILS</name>
              <bitOffset>1</bitOffset>
              <bitWidth>1</bitWidth>
            </field>
            <field>
              <name>IFS</name>
              <bitOffset>2</bitOffset>
              <bitWidth>1</bitWidth>
            </field>
            <field>
              <name>IREN</name>
              <bitOffset>3</bitOffset>
              <bitWidth>1</bitWidth>
            </field>
            <field>
              <name>ILEN</name>
              <bitOffset>4</bitOffset>
              <bitWidth>1</bitWidth>
            </field>
            <field>
              <name>IFEN</name>
              <bitOffset>5</bitOffset>
              <bitWidth>1</bitWidth>
            </field>
            <field>
              <name>FEMPT</name>
              <bitOffset>6</bitOffset>
              <bitWidth>1</bitWidth>
            </field>
          </fields>
        </register>
        <register>
          <name>PMEM</name>
          <addressOffset>0x8</addressOffset>
          <size>0x20</size>
          <fields>
            <field>
              <name>MEMSET</name>
              <bitOffset>0</bitOffset>
              <bitWidth>8</bitWidth>
            </field>
            <field>
              <name>MEMWAIT</name>
              <bitOffset>8</bitOffset>
              <bitWidth>8</bitWidth>
            </field>
            <field>
              <name>MEMHOLD</name>
              <bitOffset>16</bitOffset>
              <bitWidth>8</bitWidth>
            </field>
            <field>
              <name>MEMHIZ</name>
              <bitOffset>24</bitOffset>
              <bitWidth>8</bitWidth>
            </field>
          </fields>
        </register>
        <register>
          <name>PATT</name>
          <addressOffset>0xc</addressOffset>
          <size>0x20</size>
          <fields>
            <field>
              <name>ATTSET</name>
              <bitOffset>0</bitOffset>
              <bitWidth>8</bitWidth>
            </field>
            <field>
              <name>ATTWAIT</name>
              <bitOffset>8</bitOffset>
              <bitWidth>8</bitWidth>
            </field>
            <field>
              <name>ATTHOLD</name>
              <bitOffset>16</bitOffset>
              <bitWidth>8</bitWidth>
            </field>
            <field>
              <name>ATTHIZ</name>
              <bitOffset>24</bitOffset>
              <bitWidth>8</bitWidth>
            </field>
          </fields>
        </register>
        <register>
          <name>ECCR</name>
          <addressOffset>0x14</addressOffset>
          <size>0x20</size>
        </register>
      </registers>
    </peripheral>
    <peripheral>
      <name>FMC_Bank1E_R</name>
      <baseAddress>0x52004104</baseAddress>
      <registers>
        <register>
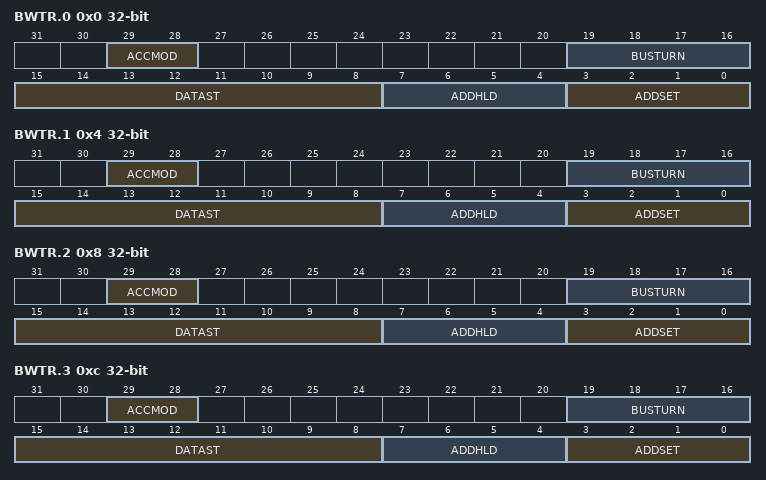
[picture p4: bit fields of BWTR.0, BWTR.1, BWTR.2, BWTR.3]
          <name>BWTR.0</name>
          <addressOffset>0x0</addressOffset>
          <size>0x20</size>
          <fields>
            <field>
              <name>ADDSET</name>
              <bitOffset>0</bitOffset>
              <bitWidth>4</bitWidth>
            </field>
            <field>
              <name>ADDHLD</name>
              <bitOffset>4</bitOffset>
              <bitWidth>4</bitWidth>
            </field>
            <field>
              <name>DATAST</name>
              <bitOffset>8</bitOffset>
              <bitWidth>8</bitWidth>
            </field>
            <field>
              <name>BUSTURN</name>
              <bitOffset>16</bitOffset>
              <bitWidth>4</bitWidth>
            </field>
            <field>
              <name>ACCMOD</name>
              <bitOffset>28</bitOffset>
              <bitWidth>2</bitWidth>
            </field>
          </fields>
        </register>
        <register>
          <name>BWTR.1</name>
          <addressOffset>0x4</addressOffset>
          <size>0x20</size>
          <fields>
            <field>
              <name>ADDSET</name>
              <bitOffset>0</bitOffset>
              <bitWidth>4</bitWidth>
            </field>
            <field>
              <name>ADDHLD</name>
              <bitOffset>4</bitOffset>
              <bitWidth>4</bitWidth>
            </field>
            <field>
              <name>DATAST</name>
              <bitOffset>8</bitOffset>
              <bitWidth>8</bitWidth>
            </field>
            <field>
              <name>BUSTURN</name>
              <bitOffset>16</bitOffset>
              <bitWidth>4</bitWidth>
            </field>
            <field>
              <name>ACCMOD</name>
              <bitOffset>28</bitOffset>
              <bitWidth>2</bitWidth>
            </field>
          </fields>
        </register>
        <register>
          <name>BWTR.2</name>
          <addressOffset>0x8</addressOffset>
          <size>0x20</size>
          <fields>
            <field>
              <name>ADDSET</name>
              <bitOffset>0</bitOffset>
              <bitWidth>4</bitWidth>
            </field>
            <field>
              <name>ADDHLD</name>
              <bitOffset>4</bitOffset>
              <bitWidth>4</bitWidth>
            </field>
            <field>
              <name>DATAST</name>
              <bitOffset>8</bitOffset>
              <bitWidth>8</bitWidth>
            </field>
            <field>
              <name>BUSTURN</name>
              <bitOffset>16</bitOffset>
              <bitWidth>4</bitWidth>
            </field>
            <field>
              <name>ACCMOD</name>
              <bitOffset>28</bitOffset>
              <bitWidth>2</bitWidth>
            </field>
          </fields>
        </register>
        <register>
          <name>BWTR.3</name>
          <addressOffset>0xc</addressOffset>
          <size>0x20</size>
          <fields>
            <field>
              <name>ADDSET</name>
              <bitOffset>0</bitOffset>
              <bitWidth>4</bitWidth>
            </field>
            <field>
              <name>ADDHLD</name>
              <bitOffset>4</bitOffset>
              <bitWidth>4</bitWidth>
            </field>
            <field>
              <name>DATAST</name>
              <bitOffset>8</bitOffset>
              <bitWidth>8</bitWidth>
            </field>
            <field>
              <name>BUSTURN</name>
              <bitOffset>16</bitOffset>
              <bitWidth>4</bitWidth>
            </field>
            <field>
              <name>ACCMOD</name>
              <bitOffset>28</bitOffset>
              <bitWidth>2</bitWidth>
            </field>
          </fields>
        </register>
        <register>
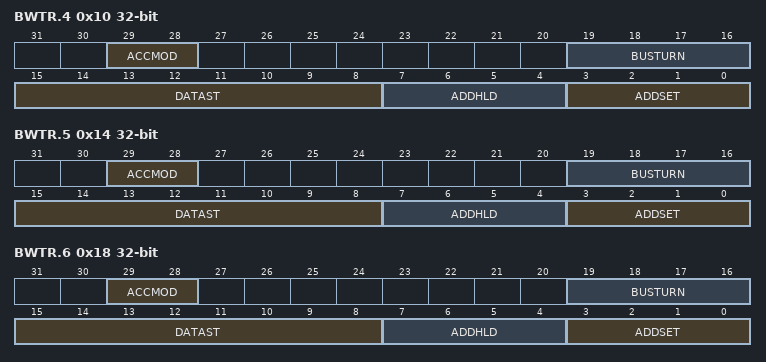
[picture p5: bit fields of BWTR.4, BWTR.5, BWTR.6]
          <name>BWTR.4</name>
          <addressOffset>0x10</addressOffset>
          <size>0x20</size>
          <fields>
            <field>
              <name>ADDSET</name>
              <bitOffset>0</bitOffset>
              <bitWidth>4</bitWidth>
            </field>
            <field>
              <name>ADDHLD</name>
              <bitOffset>4</bitOffset>
              <bitWidth>4</bitWidth>
            </field>
            <field>
              <name>DATAST</name>
              <bitOffset>8</bitOffset>
              <bitWidth>8</bitWidth>
            </field>
            <field>
              <name>BUSTURN</name>
              <bitOffset>16</bitOffset>
              <bitWidth>4</bitWidth>
            </field>
            <field>
              <name>ACCMOD</name>
              <bitOffset>28</bitOffset>
              <bitWidth>2</bitWidth>
            </field>
          </fields>
        </register>
        <register>
          <name>BWTR.5</name>
          <addressOffset>0x14</addressOffset>
          <size>0x20</size>
          <fields>
            <field>
              <name>ADDSET</name>
              <bitOffset>0</bitOffset>
              <bitWidth>4</bitWidth>
            </field>
            <field>
              <name>ADDHLD</name>
              <bitOffset>4</bitOffset>
              <bitWidth>4</bitWidth>
            </field>
            <field>
              <name>DATAST</name>
              <bitOffset>8</bitOffset>
              <bitWidth>8</bitWidth>
            </field>
            <field>
              <name>BUSTURN</name>
              <bitOffset>16</bitOffset>
              <bitWidth>4</bitWidth>
            </field>
            <field>
              <name>ACCMOD</name>
              <bitOffset>28</bitOffset>
              <bitWidth>2</bitWidth>
            </field>
          </fields>
        </register>
        <register>
          <name>BWTR.6</name>
          <addressOffset>0x18</addressOffset>
          <size>0x20</size>
          <fields>
            <field>
              <name>ADDSET</name>
              <bitOffset>0</bitOffset>
              <bitWidth>4</bitWidth>
            </field>
            <field>
              <name>ADDHLD</name>
              <bitOffset>4</bitOffset>
              <bitWidth>4</bitWidth>
            </field>
            <field>
              <name>DATAST</name>
              <bitOffset>8</bitOffset>
              <bitWidth>8</bitWidth>
            </field>
            <field>
              <name>BUSTURN</name>
              <bitOffset>16</bitOffset>
              <bitWidth>4</bitWidth>
            </field>
            <field>
              <name>ACCMOD</name>
              <bitOffset>28</bitOffset>
              <bitWidth>2</bitWidth>
            </field>
          </fields>
        </register>
      </registers>
    </peripheral>
    <peripheral>
      <name>FMC_Bank5_6_R</name>
      <baseAddress>0x52004140</baseAddress>
      <registers>
        <register>
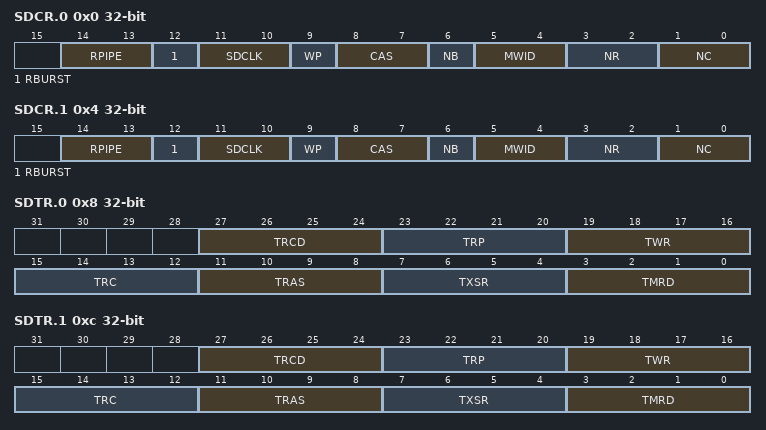
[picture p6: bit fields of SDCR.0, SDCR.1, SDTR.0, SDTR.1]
          <name>SDCR.0</name>
          <addressOffset>0x0</addressOffset>
          <size>0x20</size>
          <fields>
            <field>
              <name>NC</name>
              <bitOffset>0</bitOffset>
              <bitWidth>2</bitWidth>
            </field>
            <field>
              <name>NR</name>
              <bitOffset>2</bitOffset>
              <bitWidth>2</bitWidth>
            </field>
            <field>
              <name>MWID</name>
              <bitOffset>4</bitOffset>
              <bitWidth>2</bitWidth>
            </field>
            <field>
              <name>NB</name>
              <bitOffset>6</bitOffset>
              <bitWidth>1</bitWidth>
            </field>
            <field>
              <name>CAS</name>
              <bitOffset>7</bitOffset>
              <bitWidth>2</bitWidth>
            </field>
            <field>
              <name>WP</name>
              <bitOffset>9</bitOffset>
              <bitWidth>1</bitWidth>
            </field>
            <field>
              <name>SDCLK</name>
              <bitOffset>10</bitOffset>
              <bitWidth>2</bitWidth>
            </field>
            <field>
              <name>RBURST</name>
              <bitOffset>12</bitOffset>
              <bitWidth>1</bitWidth>
            </field>
            <field>
              <name>RPIPE</name>
              <bitOffset>13</bitOffset>
              <bitWidth>2</bitWidth>
            </field>
          </fields>
        </register>
        <register>
          <name>SDCR.1</name>
          <addressOffset>0x4</addressOffset>
          <size>0x20</size>
          <fields>
            <field>
              <name>NC</name>
              <bitOffset>0</bitOffset>
              <bitWidth>2</bitWidth>
            </field>
            <field>
              <name>NR</name>
              <bitOffset>2</bitOffset>
              <bitWidth>2</bitWidth>
            </field>
            <field>
              <name>MWID</name>
              <bitOffset>4</bitOffset>
              <bitWidth>2</bitWidth>
            </field>
            <field>
              <name>NB</name>
              <bitOffset>6</bitOffset>
              <bitWidth>1</bitWidth>
            </field>
            <field>
              <name>CAS</name>
              <bitOffset>7</bitOffset>
              <bitWidth>2</bitWidth>
            </field>
            <field>
              <name>WP</name>
              <bitOffset>9</bitOffset>
              <bitWidth>1</bitWidth>
            </field>
            <field>
              <name>SDCLK</name>
              <bitOffset>10</bitOffset>
              <bitWidth>2</bitWidth>
            </field>
            <field>
              <name>RBURST</name>
              <bitOffset>12</bitOffset>
              <bitWidth>1</bitWidth>
            </field>
            <field>
              <name>RPIPE</name>
              <bitOffset>13</bitOffset>
              <bitWidth>2</bitWidth>
            </field>
          </fields>
        </register>
        <register>
          <name>SDTR.0</name>
          <addressOffset>0x8</addressOffset>
          <size>0x20</size>
          <fields>
            <field>
              <name>TMRD</name>
              <bitOffset>0</bitOffset>
              <bitWidth>4</bitWidth>
            </field>
            <field>
              <name>TXSR</name>
              <bitOffset>4</bitOffset>
              <bitWidth>4</bitWidth>
            </field>
            <field>
              <name>TRAS</name>
              <bitOffset>8</bitOffset>
              <bitWidth>4</bitWidth>
            </field>
            <field>
              <name>TRC</name>
              <bitOffset>12</bitOffset>
              <bitWidth>4</bitWidth>
            </field>
            <field>
              <name>TWR</name>
              <bitOffset>16</bitOffset>
              <bitWidth>4</bitWidth>
            </field>
            <field>
              <name>TRP</name>
              <bitOffset>20</bitOffset>
              <bitWidth>4</bitWidth>
            </field>
            <field>
              <name>TRCD</name>
              <bitOffset>24</bitOffset>
              <bitWidth>4</bitWidth>
            </field>
          </fields>
        </register>
        <register>
          <name>SDTR.1</name>
          <addressOffset>0xc</addressOffset>
          <size>0x20</size>
          <fields>
            <field>
              <name>TMRD</name>
              <bitOffset>0</bitOffset>
              <bitWidth>4</bitWidth>
            </field>
            <field>
              <name>TXSR</name>
              <bitOffset>4</bitOffset>
              <bitWidth>4</bitWidth>
            </field>
            <field>
              <name>TRAS</name>
              <bitOffset>8</bitOffset>
              <bitWidth>4</bitWidth>
            </field>
            <field>
              <name>TRC</name>
              <bitOffset>12</bitOffset>
              <bitWidth>4</bitWidth>
            </field>
            <field>
              <name>TWR</name>
              <bitOffset>16</bitOffset>
              <bitWidth>4</bitWidth>
            </field>
            <field>
              <name>TRP</name>
              <bitOffset>20</bitOffset>
              <bitWidth>4</bitWidth>
            </field>
            <field>
              <name>TRCD</name>
              <bitOffset>24</bitOffset>
              <bitWidth>4</bitWidth>
            </field>
          </fields>
        </register>
        <register>
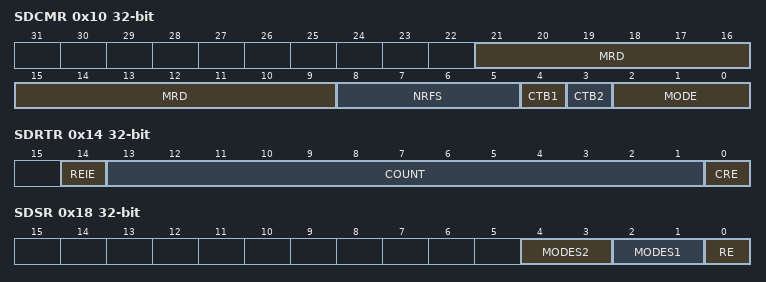
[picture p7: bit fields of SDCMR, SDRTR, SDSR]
          <name>SDCMR</name>
          <addressOffset>0x10</addressOffset>
          <size>0x20</size>
          <fields>
            <field>
              <name>MODE</name>
              <bitOffset>0</bitOffset>
              <bitWidth>3</bitWidth>
            </field>
            <field>
              <name>CTB2</name>
              <bitOffset>3</bitOffset>
              <bitWidth>1</bitWidth>
            </field>
            <field>
              <name>CTB1</name>
              <bitOffset>4</bitOffset>
              <bitWidth>1</bitWidth>
            </field>
            <field>
              <name>NRFS</name>
              <bitOffset>5</bitOffset>
              <bitWidth>4</bitWidth>
            </field>
            <field>
              <name>MRD</name>
              <bitOffset>9</bitOffset>
              <bitWidth>13</bitWidth>
            </field>
          </fields>
        </register>
        <register>
          <name>SDRTR</name>
          <addressOffset>0x14</addressOffset>
          <size>0x20</size>
          <fields>
            <field>
              <name>CRE</name>
              <bitOffset>0</bitOffset>
              <bitWidth>1</bitWidth>
            </field>
            <field>
              <name>COUNT</name>
              <bitOffset>1</bitOffset>
              <bitWidth>13</bitWidth>
            </field>
            <field>
              <name>REIE</name>
              <bitOffset>14</bitOffset>
              <bitWidth>1</bitWidth>
            </field>
          </fields>
        </register>
        <register>
          <name>SDSR</name>
          <addressOffset>0x18</addressOffset>
          <size>0x20</size>
          <fields>
            <field>
              <name>RE</name>
              <bitOffset>0</bitOffset>
              <bitWidth>1</bitWidth>
            </field>
            <field>
              <name>MODES1</name>
              <bitOffset>1</bitOffset>
              <bitWidth>2</bitWidth>
            </field>
            <field>
              <name>MODES2</name>
              <bitOffset>3</bitOffset>
              <bitWidth>2</bitWidth>
            </field>
          </fields>
        </register>
      </registers>
    </peripheral>
    <peripheral>
      <name>QUADSPI</name>
      <baseAddress>0x52005000</baseAddress>
      <registers>
        <register>
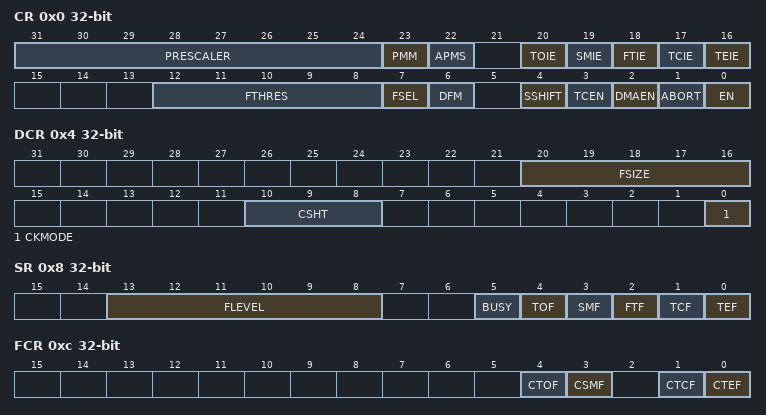
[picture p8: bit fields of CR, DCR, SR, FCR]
          <name>CR</name>
          <addressOffset>0x0</addressOffset>
          <size>0x20</size>
          <fields>
            <field>
              <name>EN</name>
              <bitOffset>0</bitOffset>
              <bitWidth>1</bitWidth>
            </field>
            <field>
              <name>ABORT</name>
              <bitOffset>1</bitOffset>
              <bitWidth>1</bitWidth>
            </field>
            <field>
              <name>DMAEN</name>
              <bitOffset>2</bitOffset>
              <bitWidth>1</bitWidth>
            </field>
            <field>
              <name>TCEN</name>
              <bitOffset>3</bitOffset>
              <bitWidth>1</bitWidth>
            </field>
            <field>
              <name>SSHIFT</name>
              <bitOffset>4</bitOffset>
              <bitWidth>1</bitWidth>
            </field>
            <field>
              <name>DFM</name>
              <bitOffset>6</bitOffset>
              <bitWidth>1</bitWidth>
            </field>
            <field>
              <name>FSEL</name>
              <bitOffset>7</bitOffset>
              <bitWidth>1</bitWidth>
            </field>
            <field>
              <name>FTHRES</name>
              <bitOffset>8</bitOffset>
              <bitWidth>5</bitWidth>
            </field>
            <field>
              <name>TEIE</name>
              <bitOffset>16</bitOffset>
              <bitWidth>1</bitWidth>
            </field>
            <field>
              <name>TCIE</name>
              <bitOffset>17</bitOffset>
              <bitWidth>1</bitWidth>
            </field>
            <field>
              <name>FTIE</name>
              <bitOffset>18</bitOffset>
              <bitWidth>1</bitWidth>
            </field>
            <field>
              <name>SMIE</name>
              <bitOffset>19</bitOffset>
              <bitWidth>1</bitWidth>
            </field>
            <field>
              <name>TOIE</name>
              <bitOffset>20</bitOffset>
              <bitWidth>1</bitWidth>
            </field>
            <field>
              <name>APMS</name>
              <bitOffset>22</bitOffset>
              <bitWidth>1</bitWidth>
            </field>
            <field>
              <name>PMM</name>
              <bitOffset>23</bitOffset>
              <bitWidth>1</bitWidth>
            </field>
            <field>
              <name>PRESCALER</name>
              <bitOffset>24</bitOffset>
              <bitWidth>8</bitWidth>
            </field>
          </fields>
        </register>
        <register>
          <name>DCR</name>
          <addressOffset>0x4</addressOffset>
          <size>0x20</size>
          <fields>
            <field>
              <name>CKMODE</name>
              <bitOffset>0</bitOffset>
              <bitWidth>1</bitWidth>
            </field>
            <field>
              <name>CSHT</name>
              <bitOffset>8</bitOffset>
              <bitWidth>3</bitWidth>
            </field>
            <field>
              <name>FSIZE</name>
              <bitOffset>16</bitOffset>
              <bitWidth>5</bitWidth>
            </field>
          </fields>
        </register>
        <register>
          <name>SR</name>
          <addressOffset>0x8</addressOffset>
          <size>0x20</size>
          <fields>
            <field>
              <name>TEF</name>
              <bitOffset>0</bitOffset>
              <bitWidth>1</bitWidth>
            </field>
            <field>
              <name>TCF</name>
              <bitOffset>1</bitOffset>
              <bitWidth>1</bitWidth>
            </field>
            <field>
              <name>FTF</name>
              <bitOffset>2</bitOffset>
              <bitWidth>1</bitWidth>
            </field>
            <field>
              <name>SMF</name>
              <bitOffset>3</bitOffset>
              <bitWidth>1</bitWidth>
            </field>
            <field>
              <name>TOF</name>
              <bitOffset>4</bitOffset>
              <bitWidth>1</bitWidth>
            </field>
            <field>
              <name>BUSY</name>
              <bitOffset>5</bitOffset>
              <bitWidth>1</bitWidth>
            </field>
            <field>
              <name>FLEVEL</name>
              <bitOffset>8</bitOffset>
              <bitWidth>6</bitWidth>
            </field>
          </fields>
        </register>
        <register>
          <name>FCR</name>
          <addressOffset>0xc</addressOffset>
          <size>0x20</size>
          <fields>
            <field>
              <name>CTEF</name>
              <bitOffset>0</bitOffset>
              <bitWidth>1</bitWidth>
            </field>
            <field>
              <name>CTCF</name>
              <bitOffset>1</bitOffset>
              <bitWidth>1</bitWidth>
            </field>
            <field>
              <name>CSMF</name>
              <bitOffset>3</bitOffset>
              <bitWidth>1</bitWidth>
            </field>
            <field>
              <name>CTOF</name>
              <bitOffset>4</bitOffset>
              <bitWidth>1</bitWidth>
            </field>
          </fields>
        </register>
        <register>
          <name>DLR</name>
          <addressOffset>0x10</addressOffset>
          <size>0x20</size>
          <fields>
            <field>
              <name>DL</name>
              <bitOffset>0</bitOffset>
              <bitWidth>32</bitWidth>
            </field>
          </fields>
        </register>
        <register>
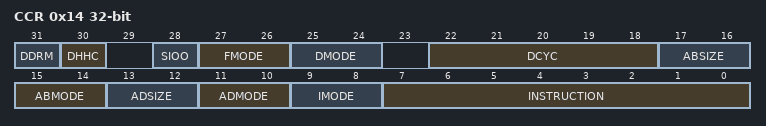
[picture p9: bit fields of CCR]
          <name>CCR</name>
          <addressOffset>0x14</addressOffset>
          <size>0x20</size>
          <fields>
            <field>
              <name>INSTRUCTION</name>
              <bitOffset>0</bitOffset>
              <bitWidth>8</bitWidth>
            </field>
            <field>
              <name>IMODE</name>
              <bitOffset>8</bitOffset>
              <bitWidth>2</bitWidth>
            </field>
            <field>
              <name>ADMODE</name>
              <bitOffset>10</bitOffset>
              <bitWidth>2</bitWidth>
            </field>
            <field>
              <name>ADSIZE</name>
              <bitOffset>12</bitOffset>
              <bitWidth>2</bitWidth>
            </field>
            <field>
              <name>ABMODE</name>
              <bitOffset>14</bitOffset>
              <bitWidth>2</bitWidth>
            </field>
            <field>
              <name>ABSIZE</name>
              <bitOffset>16</bitOffset>
              <bitWidth>2</bitWidth>
            </field>
            <field>
              <name>DCYC</name>
              <bitOffset>18</bitOffset>
              <bitWidth>5</bitWidth>
            </field>
            <field>
              <name>DMODE</name>
              <bitOffset>24</bitOffset>
              <bitWidth>2</bitWidth>
            </field>
            <field>
              <name>FMODE</name>
              <bitOffset>26</bitOffset>
              <bitWidth>2</bitWidth>
            </field>
            <field>
              <name>SIOO</name>
              <bitOffset>28</bitOffset>
              <bitWidth>1</bitWidth>
            </field>
            <field>
              <name>DHHC</name>
              <bitOffset>30</bitOffset>
              <bitWidth>1</bitWidth>
            </field>
            <field>
              <name>DDRM</name>
              <bitOffset>31</bitOffset>
              <bitWidth>1</bitWidth>
            </field>
          </fields>
        </register>
        <register>
          <name>AR</name>
          <addressOffset>0x18</addressOffset>
          <size>0x20</size>
          <fields>
            <field>
              <name>ADDRESS</name>
              <bitOffset>0</bitOffset>
              <bitWidth>32</bitWidth>
            </field>
          </fields>
        </register>
        <register>
          <name>ABR</name>
          <addressOffset>0x1c</addressOffset>
          <size>0x20</size>
          <fields>
            <field>
              <name>ALTERNATE</name>
              <bitOffset>0</bitOffset>
              <bitWidth>32</bitWidth>
            </field>
          </fields>
        </register>
        <register>
          <name>DR</name>
          <addressOffset>0x20</addressOffset>
          <size>0x20</size>
          <fields>
            <field>
              <name>DATA</name>
              <bitOffset>0</bitOffset>
              <bitWidth>32</bitWidth>
            </field>
          </fields>
        </register>
        <register>
          <name>PSMKR</name>
          <addressOffset>0x24</addressOffset>
          <size>0x20</size>
          <fields>
            <field>
              <name>MASK</name>
              <bitOffset>0</bitOffset>
              <bitWidth>32</bitWidth>
            </field>
          </fields>
        </register>
        <register>
          <name>PSMAR</name>
          <addressOffset>0x28</addressOffset>
          <size>0x20</size>
          <fields>
            <field>
              <name>MATCH</name>
              <bitOffset>0</bitOffset>
              <bitWidth>32</bitWidth>
            </field>
          </fields>
        </register>
        <register>
          <name>PIR</name>
          <addressOffset>0x2c</addressOffset>
          <size>0x20</size>
          <fields>
            <field>
              <name>INTERVAL</name>
              <bitOffset>0</bitOffset>
              <bitWidth>16</bitWidth>
            </field>
          </fields>
        </register>
        <register>
          <name>LPTR</name>
          <addressOffset>0x30</addressOffset>
          <size>0x20</size>
          <fields>
            <field>
              <name>TIMEOUT</name>
              <bitOffset>0</bitOffset>
              <bitWidth>16</bitWidth>
            </field>
          </fields>
        </register>
      </registers>
    </peripheral>
    <peripheral>
      <name>DLYB_QUADSPI</name>
      <baseAddress>0x52006000</baseAddress>
      <registers>
        <register>
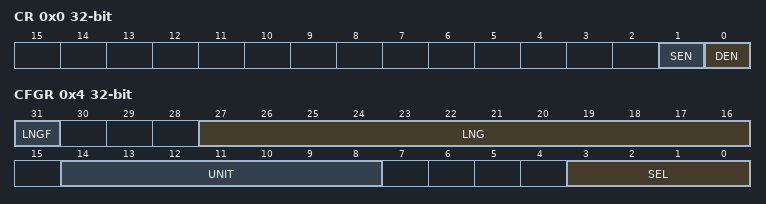
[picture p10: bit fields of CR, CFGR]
          <name>CR</name>
          <addressOffset>0x0</addressOffset>
          <size>0x20</size>
          <fields>
            <field>
              <name>DEN</name>
              <bitOffset>0</bitOffset>
              <bitWidth>1</bitWidth>
            </field>
            <field>
              <name>SEN</name>
              <bitOffset>1</bitOffset>
              <bitWidth>1</bitWidth>
            </field>
          </fields>
        </register>
        <register>
          <name>CFGR</name>
          <addressOffset>0x4</addressOffset>
          <size>0x20</size>
          <fields>
            <field>
              <name>SEL</name>
              <bitOffset>0</bitOffset>
              <bitWidth>4</bitWidth>
            </field>
            <field>
              <name>UNIT</name>
              <bitOffset>8</bitOffset>
              <bitWidth>7</bitWidth>
            </field>
            <field>
              <name>LNG</name>
              <bitOffset>16</bitOffset>
              <bitWidth>12</bitWidth>
            </field>
            <field>
              <name>LNGF</name>
              <bitOffset>31</bitOffset>
              <bitWidth>1</bitWidth>
            </field>
          </fields>
        </register>
      </registers>
    </peripheral>
    <peripheral>
      <name>SDMMC1</name>
      <baseAddress>0x52007000</baseAddress>
      <registers>
        <register>
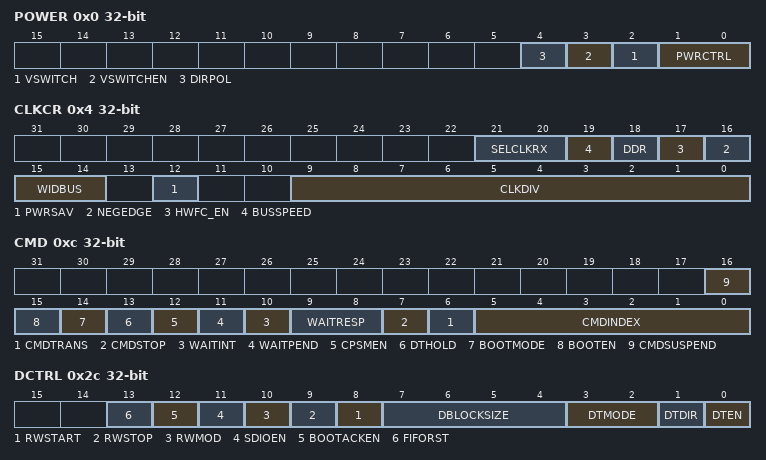
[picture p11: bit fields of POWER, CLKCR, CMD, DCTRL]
          <name>POWER</name>
          <addressOffset>0x0</addressOffset>
          <size>0x20</size>
          <fields>
            <field>
              <name>PWRCTRL</name>
              <bitOffset>0</bitOffset>
              <bitWidth>2</bitWidth>
            </field>
            <field>
              <name>VSWITCH</name>
              <bitOffset>2</bitOffset>
              <bitWidth>1</bitWidth>
            </field>
            <field>
              <name>VSWITCHEN</name>
              <bitOffset>3</bitOffset>
              <bitWidth>1</bitWidth>
            </field>
            <field>
              <name>DIRPOL</name>
              <bitOffset>4</bitOffset>
              <bitWidth>1</bitWidth>
            </field>
          </fields>
        </register>
        <register>
          <name>CLKCR</name>
          <addressOffset>0x4</addressOffset>
          <size>0x20</size>
          <fields>
            <field>
              <name>CLKDIV</name>
              <bitOffset>0</bitOffset>
              <bitWidth>10</bitWidth>
            </field>
            <field>
              <name>PWRSAV</name>
              <bitOffset>12</bitOffset>
              <bitWidth>1</bitWidth>
            </field>
            <field>
              <name>WIDBUS</name>
              <bitOffset>14</bitOffset>
              <bitWidth>2</bitWidth>
            </field>
            <field>
              <name>NEGEDGE</name>
              <bitOffset>16</bitOffset>
              <bitWidth>1</bitWidth>
            </field>
            <field>
              <name>HWFC_EN</name>
              <bitOffset>17</bitOffset>
              <bitWidth>1</bitWidth>
            </field>
            <field>
              <name>DDR</name>
              <bitOffset>18</bitOffset>
              <bitWidth>1</bitWidth>
            </field>
            <field>
              <name>BUSSPEED</name>
              <bitOffset>19</bitOffset>
              <bitWidth>1</bitWidth>
            </field>
            <field>
              <name>SELCLKRX</name>
              <bitOffset>20</bitOffset>
              <bitWidth>2</bitWidth>
            </field>
          </fields>
        </register>
        <register>
          <name>ARG</name>
          <addressOffset>0x8</addressOffset>
          <size>0x20</size>
          <fields>
            <field>
              <name>CMDARG</name>
              <bitOffset>0</bitOffset>
              <bitWidth>32</bitWidth>
            </field>
          </fields>
        </register>
        <register>
          <name>CMD</name>
          <addressOffset>0xc</addressOffset>
          <size>0x20</size>
          <fields>
            <field>
              <name>CMDINDEX</name>
              <bitOffset>0</bitOffset>
              <bitWidth>6</bitWidth>
            </field>
            <field>
              <name>CMDTRANS</name>
              <bitOffset>6</bitOffset>
              <bitWidth>1</bitWidth>
            </field>
            <field>
              <name>CMDSTOP</name>
              <bitOffset>7</bitOffset>
              <bitWidth>1</bitWidth>
            </field>
            <field>
              <name>WAITRESP</name>
              <bitOffset>8</bitOffset>
              <bitWidth>2</bitWidth>
            </field>
            <field>
              <name>WAITINT</name>
              <bitOffset>10</bitOffset>
              <bitWidth>1</bitWidth>
            </field>
            <field>
              <name>WAITPEND</name>
              <bitOffset>11</bitOffset>
              <bitWidth>1</bitWidth>
            </field>
            <field>
              <name>CPSMEN</name>
              <bitOffset>12</bitOffset>
              <bitWidth>1</bitWidth>
            </field>
            <field>
              <name>DTHOLD</name>
              <bitOffset>13</bitOffset>
              <bitWidth>1</bitWidth>
            </field>
            <field>
              <name>BOOTMODE</name>
              <bitOffset>14</bitOffset>
              <bitWidth>1</bitWidth>
            </field>
            <field>
              <name>BOOTEN</name>
              <bitOffset>15</bitOffset>
              <bitWidth>1</bitWidth>
            </field>
            <field>
              <name>CMDSUSPEND</name>
              <bitOffset>16</bitOffset>
              <bitWidth>1</bitWidth>
            </field>
          </fields>
        </register>
        <register>
          <name>RESPCMD</name>
          <addressOffset>0x10</addressOffset>
          <size>0x20</size>
          <fields>
            <field>
              <name>RESPCMD</name>
              <bitOffset>0</bitOffset>
              <bitWidth>6</bitWidth>
            </field>
          </fields>
        </register>
        <register>
          <name>RESP1</name>
          <addressOffset>0x14</addressOffset>
          <size>0x20</size>
          <fields>
            <field>
              <name>CARDSTATUS1</name>
              <bitOffset>0</bitOffset>
              <bitWidth>32</bitWidth>
            </field>
          </fields>
        </register>
        <register>
          <name>RESP2</name>
          <addressOffset>0x18</addressOffset>
          <size>0x20</size>
          <fields>
            <field>
              <name>CARDSTATUS2</name>
              <bitOffset>0</bitOffset>
              <bitWidth>32</bitWidth>
            </field>
          </fields>
        </register>
        <register>
          <name>RESP3</name>
          <addressOffset>0x1c</addressOffset>
          <size>0x20</size>
          <fields>
            <field>
              <name>CARDSTATUS3</name>
              <bitOffset>0</bitOffset>
              <bitWidth>32</bitWidth>
            </field>
          </fields>
        </register>
        <register>
          <name>RESP4</name>
          <addressOffset>0x20</addressOffset>
          <size>0x20</size>
          <fields>
            <field>
              <name>CARDSTATUS4</name>
              <bitOffset>0</bitOffset>
              <bitWidth>32</bitWidth>
            </field>
          </fields>
        </register>
        <register>
          <name>DTIMER</name>
          <addressOffset>0x24</addressOffset>
          <size>0x20</size>
          <fields>
            <field>
              <name>DATATIME</name>
              <bitOffset>0</bitOffset>
              <bitWidth>32</bitWidth>
            </field>
          </fields>
        </register>
        <register>
          <name>DLEN</name>
          <addressOffset>0x28</addressOffset>
          <size>0x20</size>
          <fields>
            <field>
              <name>DATALENGTH</name>
              <bitOffset>0</bitOffset>
              <bitWidth>25</bitWidth>
            </field>
          </fields>
        </register>
        <register>
          <name>DCTRL</name>
          <addressOffset>0x2c</addressOffset>
          <size>0x20</size>
          <fields>
            <field>
              <name>DTEN</name>
              <bitOffset>0</bitOffset>
              <bitWidth>1</bitWidth>
            </field>
            <field>
              <name>DTDIR</name>
              <bitOffset>1</bitOffset>
              <bitWidth>1</bitWidth>
            </field>
            <field>
              <name>DTMODE</name>
              <bitOffset>2</bitOffset>
              <bitWidth>2</bitWidth>
            </field>
            <field>
              <name>DBLOCKSIZE</name>
              <bitOffset>4</bitOffset>
              <bitWidth>4</bitWidth>
            </field>
            <field>
              <name>RWSTART</name>
              <bitOffset>8</bitOffset>
              <bitWidth>1</bitWidth>
            </field>
            <field>
              <name>RWSTOP</name>
              <bitOffset>9</bitOffset>
              <bitWidth>1</bitWidth>
            </field>
            <field>
              <name>RWMOD</name>
              <bitOffset>10</bitOffset>
              <bitWidth>1</bitWidth>
            </field>
            <field>
              <name>SDIOEN</name>
              <bitOffset>11</bitOffset>
              <bitWidth>1</bitWidth>
            </field>
            <field>
              <name>BOOTACKEN</name>
              <bitOffset>12</bitOffset>
              <bitWidth>1</bitWidth>
            </field>
            <field>
              <name>FIFORST</name>
              <bitOffset>13</bitOffset>
              <bitWidth>1</bitWidth>
            </field>
          </fields>
        </register>
        <register>
          <name>DCOUNT</name>
          <addressOffset>0x30</addressOffset>
          <size>0x20</size>
          <fields>
            <field>
              <name>DATACOUNT</name>
              <bitOffset>0</bitOffset>
              <bitWidth>25</bitWidth>
            </field>
          </fields>
        </register>
        <register>
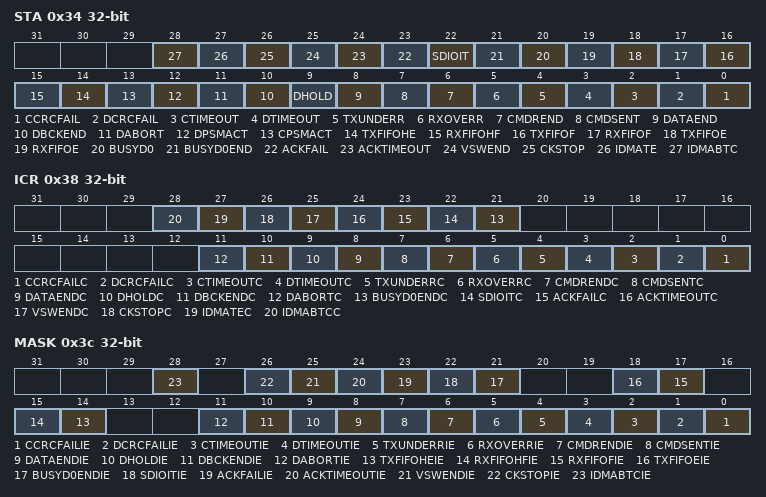
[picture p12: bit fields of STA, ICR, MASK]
          <name>STA</name>
          <addressOffset>0x34</addressOffset>
          <size>0x20</size>
          <fields>
            <field>
              <name>CCRCFAIL</name>
              <bitOffset>0</bitOffset>
              <bitWidth>1</bitWidth>
            </field>
            <field>
              <name>DCRCFAIL</name>
              <bitOffset>1</bitOffset>
              <bitWidth>1</bitWidth>
            </field>
            <field>
              <name>CTIMEOUT</name>
              <bitOffset>2</bitOffset>
              <bitWidth>1</bitWidth>
            </field>
            <field>
              <name>DTIMEOUT</name>
              <bitOffset>3</bitOffset>
              <bitWidth>1</bitWidth>
            </field>
            <field>
              <name>TXUNDERR</name>
              <bitOffset>4</bitOffset>
              <bitWidth>1</bitWidth>
            </field>
            <field>
              <name>RXOVERR</name>
              <bitOffset>5</bitOffset>
              <bitWidth>1</bitWidth>
            </field>
            <field>
              <name>CMDREND</name>
              <bitOffset>6</bitOffset>
              <bitWidth>1</bitWidth>
            </field>
            <field>
              <name>CMDSENT</name>
              <bitOffset>7</bitOffset>
              <bitWidth>1</bitWidth>
            </field>
            <field>
              <name>DATAEND</name>
              <bitOffset>8</bitOffset>
              <bitWidth>1</bitWidth>
            </field>
            <field>
              <name>DHOLD</name>
              <bitOffset>9</bitOffset>
              <bitWidth>1</bitWidth>
            </field>
            <field>
              <name>DBCKEND</name>
              <bitOffset>10</bitOffset>
              <bitWidth>1</bitWidth>
            </field>
            <field>
              <name>DABORT</name>
              <bitOffset>11</bitOffset>
              <bitWidth>1</bitWidth>
            </field>
            <field>
              <name>DPSMACT</name>
              <bitOffset>12</bitOffset>
              <bitWidth>1</bitWidth>
            </field>
            <field>
              <name>CPSMACT</name>
              <bitOffset>13</bitOffset>
              <bitWidth>1</bitWidth>
            </field>
            <field>
              <name>TXFIFOHE</name>
              <bitOffset>14</bitOffset>
              <bitWidth>1</bitWidth>
            </field>
            <field>
              <name>RXFIFOHF</name>
              <bitOffset>15</bitOffset>
              <bitWidth>1</bitWidth>
            </field>
            <field>
              <name>TXFIFOF</name>
              <bitOffset>16</bitOffset>
              <bitWidth>1</bitWidth>
            </field>
            <field>
              <name>RXFIFOF</name>
              <bitOffset>17</bitOffset>
              <bitWidth>1</bitWidth>
            </field>
            <field>
              <name>TXFIFOE</name>
              <bitOffset>18</bitOffset>
              <bitWidth>1</bitWidth>
            </field>
            <field>
              <name>RXFIFOE</name>
              <bitOffset>19</bitOffset>
              <bitWidth>1</bitWidth>
            </field>
            <field>
              <name>BUSYD0</name>
              <bitOffset>20</bitOffset>
              <bitWidth>1</bitWidth>
            </field>
            <field>
              <name>BUSYD0END</name>
              <bitOffset>21</bitOffset>
              <bitWidth>1</bitWidth>
            </field>
            <field>
              <name>SDIOIT</name>
              <bitOffset>22</bitOffset>
              <bitWidth>1</bitWidth>
            </field>
            <field>
              <name>ACKFAIL</name>
              <bitOffset>23</bitOffset>
              <bitWidth>1</bitWidth>
            </field>
            <field>
              <name>ACKTIMEOUT</name>
              <bitOffset>24</bitOffset>
              <bitWidth>1</bitWidth>
            </field>
            <field>
              <name>VSWEND</name>
              <bitOffset>25</bitOffset>
              <bitWidth>1</bitWidth>
            </field>
            <field>
              <name>CKSTOP</name>
              <bitOffset>26</bitOffset>
              <bitWidth>1</bitWidth>
            </field>
            <field>
              <name>IDMATE</name>
              <bitOffset>27</bitOffset>
              <bitWidth>1</bitWidth>
            </field>
            <field>
              <name>IDMABTC</name>
              <bitOffset>28</bitOffset>
              <bitWidth>1</bitWidth>
            </field>
          </fields>
        </register>
        <register>
          <name>ICR</name>
          <addressOffset>0x38</addressOffset>
          <size>0x20</size>
          <fields>
            <field>
              <name>CCRCFAILC</name>
              <bitOffset>0</bitOffset>
              <bitWidth>1</bitWidth>
            </field>
            <field>
              <name>DCRCFAILC</name>
              <bitOffset>1</bitOffset>
              <bitWidth>1</bitWidth>
            </field>
            <field>
              <name>CTIMEOUTC</name>
              <bitOffset>2</bitOffset>
              <bitWidth>1</bitWidth>
            </field>
            <field>
              <name>DTIMEOUTC</name>
              <bitOffset>3</bitOffset>
              <bitWidth>1</bitWidth>
            </field>
            <field>
              <name>TXUNDERRC</name>
              <bitOffset>4</bitOffset>
              <bitWidth>1</bitWidth>
            </field>
            <field>
              <name>RXOVERRC</name>
              <bitOffset>5</bitOffset>
              <bitWidth>1</bitWidth>
            </field>
            <field>
              <name>CMDRENDC</name>
              <bitOffset>6</bitOffset>
              <bitWidth>1</bitWidth>
            </field>
            <field>
              <name>CMDSENTC</name>
              <bitOffset>7</bitOffset>
              <bitWidth>1</bitWidth>
            </field>
            <field>
              <name>DATAENDC</name>
              <bitOffset>8</bitOffset>
              <bitWidth>1</bitWidth>
            </field>
            <field>
              <name>DHOLDC</name>
              <bitOffset>9</bitOffset>
              <bitWidth>1</bitWidth>
            </field>
            <field>
              <name>DBCKENDC</name>
              <bitOffset>10</bitOffset>
              <bitWidth>1</bitWidth>
            </field>
            <field>
              <name>DABORTC</name>
              <bitOffset>11</bitOffset>
              <bitWidth>1</bitWidth>
            </field>
            <field>
              <name>BUSYD0ENDC</name>
              <bitOffset>21</bitOffset>
              <bitWidth>1</bitWidth>
            </field>
            <field>
              <name>SDIOITC</name>
              <bitOffset>22</bitOffset>
              <bitWidth>1</bitWidth>
            </field>
            <field>
              <name>ACKFAILC</name>
              <bitOffset>23</bitOffset>
              <bitWidth>1</bitWidth>
            </field>
            <field>
              <name>ACKTIMEOUTC</name>
              <bitOffset>24</bitOffset>
              <bitWidth>1</bitWidth>
            </field>
            <field>
              <name>VSWENDC</name>
              <bitOffset>25</bitOffset>
              <bitWidth>1</bitWidth>
            </field>
            <field>
              <name>CKSTOPC</name>
              <bitOffset>26</bitOffset>
              <bitWidth>1</bitWidth>
            </field>
            <field>
              <name>IDMATEC</name>
              <bitOffset>27</bitOffset>
              <bitWidth>1</bitWidth>
            </field>
            <field>
              <name>IDMABTCC</name>
              <bitOffset>28</bitOffset>
              <bitWidth>1</bitWidth>
            </field>
          </fields>
        </register>
        <register>
          <name>MASK</name>
          <addressOffset>0x3c</addressOffset>
          <size>0x20</size>
          <fields>
            <field>
              <name>CCRCFAILIE</name>
              <bitOffset>0</bitOffset>
              <bitWidth>1</bitWidth>
            </field>
            <field>
              <name>DCRCFAILIE</name>
              <bitOffset>1</bitOffset>
              <bitWidth>1</bitWidth>
            </field>
            <field>
              <name>CTIMEOUTIE</name>
              <bitOffset>2</bitOffset>
              <bitWidth>1</bitWidth>
            </field>
            <field>
              <name>DTIMEOUTIE</name>
              <bitOffset>3</bitOffset>
              <bitWidth>1</bitWidth>
            </field>
            <field>
              <name>TXUNDERRIE</name>
              <bitOffset>4</bitOffset>
              <bitWidth>1</bitWidth>
            </field>
            <field>
              <name>RXOVERRIE</name>
              <bitOffset>5</bitOffset>
              <bitWidth>1</bitWidth>
            </field>
            <field>
              <name>CMDRENDIE</name>
              <bitOffset>6</bitOffset>
              <bitWidth>1</bitWidth>
            </field>
            <field>
              <name>CMDSENTIE</name>
              <bitOffset>7</bitOffset>
              <bitWidth>1</bitWidth>
            </field>
            <field>
              <name>DATAENDIE</name>
              <bitOffset>8</bitOffset>
              <bitWidth>1</bitWidth>
            </field>
            <field>
              <name>DHOLDIE</name>
              <bitOffset>9</bitOffset>
              <bitWidth>1</bitWidth>
            </field>
            <field>
              <name>DBCKENDIE</name>
              <bitOffset>10</bitOffset>
              <bitWidth>1</bitWidth>
            </field>
            <field>
              <name>DABORTIE</name>
              <bitOffset>11</bitOffset>
              <bitWidth>1</bitWidth>
            </field>
            <field>
              <name>TXFIFOHEIE</name>
              <bitOffset>14</bitOffset>
              <bitWidth>1</bitWidth>
            </field>
            <field>
              <name>RXFIFOHFIE</name>
              <bitOffset>15</bitOffset>
              <bitWidth>1</bitWidth>
            </field>
            <field>
              <name>RXFIFOFIE</name>
              <bitOffset>17</bitOffset>
              <bitWidth>1</bitWidth>
            </field>
            <field>
              <name>TXFIFOEIE</name>
              <bitOffset>18</bitOffset>
              <bitWidth>1</bitWidth>
            </field>
            <field>
              <name>BUSYD0ENDIE</name>
              <bitOffset>21</bitOffset>
              <bitWidth>1</bitWidth>
            </field>
            <field>
              <name>SDIOITIE</name>
              <bitOffset>22</bitOffset>
              <bitWidth>1</bitWidth>
            </field>
            <field>
              <name>ACKFAILIE</name>
              <bitOffset>23</bitOffset>
              <bitWidth>1</bitWidth>
            </field>
            <field>
              <name>ACKTIMEOUTIE</name>
              <bitOffset>24</bitOffset>
              <bitWidth>1</bitWidth>
            </field>
            <field>
              <name>VSWENDIE</name>
              <bitOffset>25</bitOffset>
              <bitWidth>1</bitWidth>
            </field>
            <field>
              <name>CKSTOPIE</name>
              <bitOffset>26</bitOffset>
              <bitWidth>1</bitWidth>
            </field>
            <field>
              <name>IDMABTCIE</name>
              <bitOffset>28</bitOffset>
              <bitWidth>1</bitWidth>
            </field>
          </fields>
        </register>
        <register>
          <name>ACKTIME</name>
          <addressOffset>0x40</addressOffset>
          <size>0x20</size>
          <fields>
            <field>
              <name>ACKTIME</name>
              <bitOffset>0</bitOffset>
              <bitWidth>25</bitWidth>
            </field>
          </fields>
        </register>
        <register>
          <name>IDMACTRL</name>
          <addressOffset>0x50</addressOffset>
          <size>0x20</size>
        </register>
        <register>
          <name>IDMABSIZE</name>
          <addressOffset>0x54</addressOffset>
          <size>0x20</size>
          <fields>
            <field>
              <name>IDMABNDT</name>
              <bitOffset>5</bitOffset>
              <bitWidth>8</bitWidth>
            </field>
          </fields>
        </register>
        <register>
          <name>IDMABASE0</name>
          <addressOffset>0x58</addressOffset>
          <size>0x20</size>
        </register>
        <register>
          <name>IDMABASE1</name>
          <addressOffset>0x5c</addressOffset>
          <size>0x20</size>
        </register>
        <register>
          <name>FIFO</name>
          <addressOffset>0x80</addressOffset>
          <size>0x20</size>
          <fields>
            <field>
              <name>FIFODATA</name>
              <bitOffset>0</bitOffset>
              <bitWidth>32</bitWidth>
            </field>
          </fields>
        </register>
        <register>
          <name>IPVR</name>
          <addressOffset>0x3fc</addressOffset>
          <size>0x20</size>
        </register>
      </registers>
    </peripheral>
    <peripheral>
      <name>DLYB_SDMMC1</name>
      <baseAddress>0x52008000</baseAddress>
      <registers>
        <register>
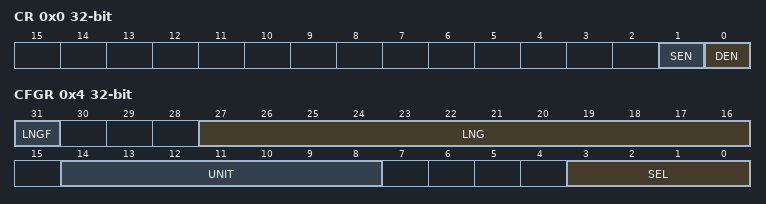
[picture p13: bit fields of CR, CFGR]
          <name>CR</name>
          <addressOffset>0x0</addressOffset>
          <size>0x20</size>
          <fields>
            <field>
              <name>DEN</name>
              <bitOffset>0</bitOffset>
              <bitWidth>1</bitWidth>
            </field>
            <field>
              <name>SEN</name>
              <bitOffset>1</bitOffset>
              <bitWidth>1</bitWidth>
            </field>
          </fields>
        </register>
        <register>
          <name>CFGR</name>
          <addressOffset>0x4</addressOffset>
          <size>0x20</size>
          <fields>
            <field>
              <name>SEL</name>
              <bitOffset>0</bitOffset>
              <bitWidth>4</bitWidth>
            </field>
            <field>
              <name>UNIT</name>
              <bitOffset>8</bitOffset>
              <bitWidth>7</bitWidth>
            </field>
            <field>
              <name>LNG</name>
              <bitOffset>16</bitOffset>
              <bitWidth>12</bitWidth>
            </field>
            <field>
              <name>LNGF</name>
              <bitOffset>31</bitOffset>
              <bitWidth>1</bitWidth>
            </field>
          </fields>
        </register>
      </registers>
    </peripheral>
    <peripheral>
      <name>RAMECC1</name>
      <baseAddress>0x52009000</baseAddress>
      <registers>
        <register>
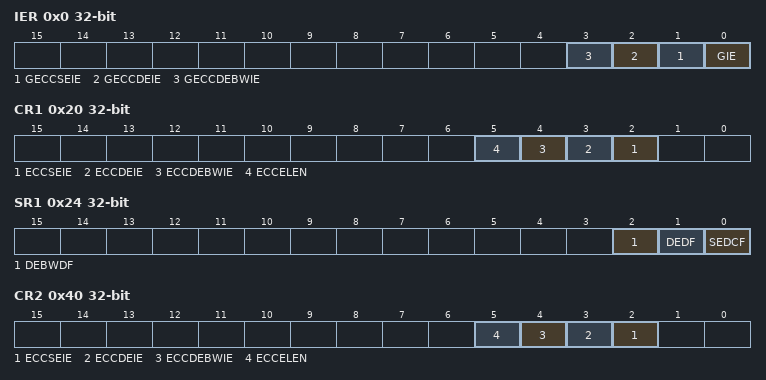
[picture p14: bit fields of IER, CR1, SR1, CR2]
          <name>IER</name>
          <addressOffset>0x0</addressOffset>
          <size>0x20</size>
          <fields>
            <field>
              <name>GIE</name>
              <bitOffset>0</bitOffset>
              <bitWidth>1</bitWidth>
            </field>
            <field>
              <name>GECCSEIE</name>
              <bitOffset>1</bitOffset>
              <bitWidth>1</bitWidth>
            </field>
            <field>
              <name>GECCDEIE</name>
              <bitOffset>2</bitOffset>
              <bitWidth>1</bitWidth>
            </field>
            <field>
              <name>GECCDEBWIE</name>
              <bitOffset>3</bitOffset>
              <bitWidth>1</bitWidth>
            </field>
          </fields>
        </register>
        <register>
          <name>CR1</name>
          <addressOffset>0x20</addressOffset>
          <size>0x20</size>
          <fields>
            <field>
              <name>ECCSEIE</name>
              <bitOffset>2</bitOffset>
              <bitWidth>1</bitWidth>
            </field>
            <field>
              <name>ECCDEIE</name>
              <bitOffset>3</bitOffset>
              <bitWidth>1</bitWidth>
            </field>
            <field>
              <name>ECCDEBWIE</name>
              <bitOffset>4</bitOffset>
              <bitWidth>1</bitWidth>
            </field>
            <field>
              <name>ECCELEN</name>
              <bitOffset>5</bitOffset>
              <bitWidth>1</bitWidth>
            </field>
          </fields>
        </register>
        <register>
          <name>CR1</name>
          <addressOffset>0x20</addressOffset>
          <size>0x20</size>
          <fields>
            <field>
              <name>ECCSEIE</name>
              <bitOffset>2</bitOffset>
              <bitWidth>1</bitWidth>
            </field>
            <field>
              <name>ECCDEIE</name>
              <bitOffset>3</bitOffset>
              <bitWidth>1</bitWidth>
            </field>
            <field>
              <name>ECCDEBWIE</name>
              <bitOffset>4</bitOffset>
              <bitWidth>1</bitWidth>
            </field>
            <field>
              <name>ECCELEN</name>
              <bitOffset>5</bitOffset>
              <bitWidth>1</bitWidth>
            </field>
          </fields>
        </register>
        <register>
          <name>CR1</name>
          <addressOffset>0x20</addressOffset>
          <size>0x20</size>
          <fields>
            <field>
              <name>ECCSEIE</name>
              <bitOffset>2</bitOffset>
              <bitWidth>1</bitWidth>
            </field>
            <field>
              <name>ECCDEIE</name>
              <bitOffset>3</bitOffset>
              <bitWidth>1</bitWidth>
            </field>
            <field>
              <name>ECCDEBWIE</name>
              <bitOffset>4</bitOffset>
              <bitWidth>1</bitWidth>
            </field>
            <field>
              <name>ECCELEN</name>
              <bitOffset>5</bitOffset>
              <bitWidth>1</bitWidth>
            </field>
          </fields>
        </register>
        <register>
          <name>SR1</name>
          <addressOffset>0x24</addressOffset>
          <size>0x20</size>
          <fields>
            <field>
              <name>SEDCF</name>
              <bitOffset>0</bitOffset>
              <bitWidth>1</bitWidth>
            </field>
            <field>
              <name>DEDF</name>
              <bitOffset>1</bitOffset>
              <bitWidth>1</bitWidth>
            </field>
            <field>
              <name>DEBWDF</name>
              <bitOffset>2</bitOffset>
              <bitWidth>1</bitWidth>
            </field>
          </fields>
        </register>
        <register>
          <name>SR1</name>
          <addressOffset>0x24</addressOffset>
          <size>0x20</size>
          <fields>
            <field>
              <name>SEDCF</name>
              <bitOffset>0</bitOffset>
              <bitWidth>1</bitWidth>
            </field>
            <field>
              <name>DEDF</name>
              <bitOffset>1</bitOffset>
              <bitWidth>1</bitWidth>
            </field>
            <field>
              <name>DEBWDF</name>
              <bitOffset>2</bitOffset>
              <bitWidth>1</bitWidth>
            </field>
          </fields>
        </register>
        <register>
          <name>SR1</name>
          <addressOffset>0x24</addressOffset>
          <size>0x20</size>
          <fields>
            <field>
              <name>SEDCF</name>
              <bitOffset>0</bitOffset>
              <bitWidth>1</bitWidth>
            </field>
            <field>
              <name>DEDF</name>
              <bitOffset>1</bitOffset>
              <bitWidth>1</bitWidth>
            </field>
            <field>
              <name>DEBWDF</name>
              <bitOffset>2</bitOffset>
              <bitWidth>1</bitWidth>
            </field>
          </fields>
        </register>
        <register>
          <name>FAR1</name>
          <addressOffset>0x28</addressOffset>
          <size>0x20</size>
          <fields>
            <field>
              <name>FDATAL</name>
              <bitOffset>0</bitOffset>
              <bitWidth>32</bitWidth>
            </field>
          </fields>
        </register>
        <register>
          <name>FAR1</name>
          <addressOffset>0x28</addressOffset>
          <size>0x20</size>
          <fields>
            <field>
              <name>FDATAL</name>
              <bitOffset>0</bitOffset>
              <bitWidth>32</bitWidth>
            </field>
          </fields>
        </register>
        <register>
          <name>FAR1</name>
          <addressOffset>0x28</addressOffset>
          <size>0x20</size>
          <fields>
            <field>
              <name>FDATAL</name>
              <bitOffset>0</bitOffset>
              <bitWidth>32</bitWidth>
            </field>
          </fields>
        </register>
        <register>
          <name>FDRL1</name>
          <addressOffset>0x2c</addressOffset>
          <size>0x20</size>
        </register>
        <register>
          <name>FDRL1</name>
          <addressOffset>0x2c</addressOffset>
          <size>0x20</size>
        </register>
        <register>
          <name>FDRL1</name>
          <addressOffset>0x2c</addressOffset>
          <size>0x20</size>
        </register>
        <register>
          <name>FDRH1</name>
          <addressOffset>0x30</addressOffset>
          <size>0x20</size>
        </register>
        <register>
          <name>FDRH1</name>
          <addressOffset>0x30</addressOffset>
          <size>0x20</size>
        </register>
        <register>
          <name>FDRH1</name>
          <addressOffset>0x30</addressOffset>
          <size>0x20</size>
        </register>
        <register>
          <name>FECR1</name>
          <addressOffset>0x34</addressOffset>
          <size>0x20</size>
          <fields>
            <field>
              <name>FEC</name>
              <bitOffset>0</bitOffset>
              <bitWidth>32</bitWidth>
            </field>
          </fields>
        </register>
        <register>
          <name>FECR1</name>
          <addressOffset>0x34</addressOffset>
          <size>0x20</size>
          <fields>
            <field>
              <name>FEC</name>
              <bitOffset>0</bitOffset>
              <bitWidth>32</bitWidth>
            </field>
          </fields>
        </register>
        <register>
          <name>FECR1</name>
          <addressOffset>0x34</addressOffset>
          <size>0x20</size>
          <fields>
            <field>
              <name>FEC</name>
              <bitOffset>0</bitOffset>
              <bitWidth>32</bitWidth>
            </field>
          </fields>
        </register>
        <register>
          <name>CR2</name>
          <addressOffset>0x40</addressOffset>
          <size>0x20</size>
          <fields>
            <field>
              <name>ECCSEIE</name>
              <bitOffset>2</bitOffset>
              <bitWidth>1</bitWidth>
            </field>
            <field>
              <name>ECCDEIE</name>
              <bitOffset>3</bitOffset>
              <bitWidth>1</bitWidth>
            </field>
            <field>
              <name>ECCDEBWIE</name>
              <bitOffset>4</bitOffset>
              <bitWidth>1</bitWidth>
            </field>
            <field>
              <name>ECCELEN</name>
              <bitOffset>5</bitOffset>
              <bitWidth>1</bitWidth>
            </field>
          </fields>
        </register>
        <register>
          <name>CR2</name>
          <addressOffset>0x40</addressOffset>
          <size>0x20</size>
          <fields>
            <field>
              <name>ECCSEIE</name>
              <bitOffset>2</bitOffset>
              <bitWidth>1</bitWidth>
            </field>
            <field>
              <name>ECCDEIE</name>
              <bitOffset>3</bitOffset>
              <bitWidth>1</bitWidth>
            </field>
            <field>
              <name>ECCDEBWIE</name>
              <bitOffset>4</bitOffset>
              <bitWidth>1</bitWidth>
            </field>
            <field>
              <name>ECCELEN</name>
              <bitOffset>5</bitOffset>
              <bitWidth>1</bitWidth>
            </field>
          </fields>
        </register>
        <register>
          <name>CR2</name>
          <addressOffset>0x40</addressOffset>
          <size>0x20</size>
          <fields>
            <field>
              <name>ECCSEIE</name>
              <bitOffset>2</bitOffset>
              <bitWidth>1</bitWidth>
            </field>
            <field>
              <name>ECCDEIE</name>
              <bitOffset>3</bitOffset>
              <bitWidth>1</bitWidth>
            </field>
            <field>
              <name>ECCDEBWIE</name>
              <bitOffset>4</bitOffset>
              <bitWidth>1</bitWidth>
            </field>
            <field>
              <name>ECCELEN</name>
              <bitOffset>5</bitOffset>
              <bitWidth>1</bitWidth>
            </field>
          </fields>
        </register>
        <register>
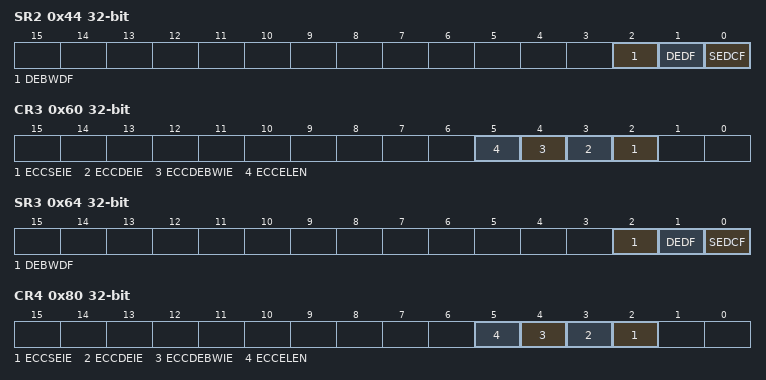
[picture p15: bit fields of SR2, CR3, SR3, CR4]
          <name>SR2</name>
          <addressOffset>0x44</addressOffset>
          <size>0x20</size>
          <fields>
            <field>
              <name>SEDCF</name>
              <bitOffset>0</bitOffset>
              <bitWidth>1</bitWidth>
            </field>
            <field>
              <name>DEDF</name>
              <bitOffset>1</bitOffset>
              <bitWidth>1</bitWidth>
            </field>
            <field>
              <name>DEBWDF</name>
              <bitOffset>2</bitOffset>
              <bitWidth>1</bitWidth>
            </field>
          </fields>
        </register>
        <register>
          <name>SR2</name>
          <addressOffset>0x44</addressOffset>
          <size>0x20</size>
          <fields>
            <field>
              <name>SEDCF</name>
              <bitOffset>0</bitOffset>
              <bitWidth>1</bitWidth>
            </field>
            <field>
              <name>DEDF</name>
              <bitOffset>1</bitOffset>
              <bitWidth>1</bitWidth>
            </field>
            <field>
              <name>DEBWDF</name>
              <bitOffset>2</bitOffset>
              <bitWidth>1</bitWidth>
            </field>
          </fields>
        </register>
        <register>
          <name>SR2</name>
          <addressOffset>0x44</addressOffset>
          <size>0x20</size>
          <fields>
            <field>
              <name>SEDCF</name>
              <bitOffset>0</bitOffset>
              <bitWidth>1</bitWidth>
            </field>
            <field>
              <name>DEDF</name>
              <bitOffset>1</bitOffset>
              <bitWidth>1</bitWidth>
            </field>
            <field>
              <name>DEBWDF</name>
              <bitOffset>2</bitOffset>
              <bitWidth>1</bitWidth>
            </field>
          </fields>
        </register>
        <register>
          <name>FAR2</name>
          <addressOffset>0x48</addressOffset>
          <size>0x20</size>
          <fields>
            <field>
              <name>FDATAL</name>
              <bitOffset>0</bitOffset>
              <bitWidth>32</bitWidth>
            </field>
          </fields>
        </register>
        <register>
          <name>FAR2</name>
          <addressOffset>0x48</addressOffset>
          <size>0x20</size>
          <fields>
            <field>
              <name>FDATAL</name>
              <bitOffset>0</bitOffset>
              <bitWidth>32</bitWidth>
            </field>
          </fields>
        </register>
        <register>
          <name>FAR2</name>
          <addressOffset>0x48</addressOffset>
          <size>0x20</size>
          <fields>
            <field>
              <name>FDATAL</name>
              <bitOffset>0</bitOffset>
              <bitWidth>32</bitWidth>
            </field>
          </fields>
        </register>
        <register>
          <name>FDRL2</name>
          <addressOffset>0x4c</addressOffset>
          <size>0x20</size>
        </register>
        <register>
          <name>FDRL2</name>
          <addressOffset>0x4c</addressOffset>
          <size>0x20</size>
        </register>
        <register>
          <name>FDRL2</name>
          <addressOffset>0x4c</addressOffset>
          <size>0x20</size>
        </register>
        <register>
          <name>FDRH2</name>
          <addressOffset>0x50</addressOffset>
          <size>0x20</size>
        </register>
        <register>
          <name>FDRH2</name>
          <addressOffset>0x50</addressOffset>
          <size>0x20</size>
        </register>
        <register>
          <name>FDRH2</name>
          <addressOffset>0x50</addressOffset>
          <size>0x20</size>
        </register>
        <register>
          <name>FECR2</name>
          <addressOffset>0x54</addressOffset>
          <size>0x20</size>
          <fields>
            <field>
              <name>FEC</name>
              <bitOffset>0</bitOffset>
              <bitWidth>32</bitWidth>
            </field>
          </fields>
        </register>
        <register>
          <name>FECR2</name>
          <addressOffset>0x54</addressOffset>
          <size>0x20</size>
          <fields>
            <field>
              <name>FEC</name>
              <bitOffset>0</bitOffset>
              <bitWidth>32</bitWidth>
            </field>
          </fields>
        </register>
        <register>
          <name>FECR2</name>
          <addressOffset>0x54</addressOffset>
          <size>0x20</size>
          <fields>
            <field>
              <name>FEC</name>
              <bitOffset>0</bitOffset>
              <bitWidth>32</bitWidth>
            </field>
          </fields>
        </register>
        <register>
          <name>CR3</name>
          <addressOffset>0x60</addressOffset>
          <size>0x20</size>
          <fields>
            <field>
              <name>ECCSEIE</name>
              <bitOffset>2</bitOffset>
              <bitWidth>1</bitWidth>
            </field>
            <field>
              <name>ECCDEIE</name>
              <bitOffset>3</bitOffset>
              <bitWidth>1</bitWidth>
            </field>
            <field>
              <name>ECCDEBWIE</name>
              <bitOffset>4</bitOffset>
              <bitWidth>1</bitWidth>
            </field>
            <field>
              <name>ECCELEN</name>
              <bitOffset>5</bitOffset>
              <bitWidth>1</bitWidth>
            </field>
          </fields>
        </register>
        <register>
          <name>CR3</name>
          <addressOffset>0x60</addressOffset>
          <size>0x20</size>
          <fields>
            <field>
              <name>ECCSEIE</name>
              <bitOffset>2</bitOffset>
              <bitWidth>1</bitWidth>
            </field>
            <field>
              <name>ECCDEIE</name>
              <bitOffset>3</bitOffset>
              <bitWidth>1</bitWidth>
            </field>
            <field>
              <name>ECCDEBWIE</name>
              <bitOffset>4</bitOffset>
              <bitWidth>1</bitWidth>
            </field>
            <field>
              <name>ECCELEN</name>
              <bitOffset>5</bitOffset>
              <bitWidth>1</bitWidth>
            </field>
          </fields>
        </register>
        <register>
          <name>SR3</name>
          <addressOffset>0x64</addressOffset>
          <size>0x20</size>
          <fields>
            <field>
              <name>SEDCF</name>
              <bitOffset>0</bitOffset>
              <bitWidth>1</bitWidth>
            </field>
            <field>
              <name>DEDF</name>
              <bitOffset>1</bitOffset>
              <bitWidth>1</bitWidth>
            </field>
            <field>
              <name>DEBWDF</name>
              <bitOffset>2</bitOffset>
              <bitWidth>1</bitWidth>
            </field>
          </fields>
        </register>
        <register>
          <name>SR3</name>
          <addressOffset>0x64</addressOffset>
          <size>0x20</size>
          <fields>
            <field>
              <name>SEDCF</name>
              <bitOffset>0</bitOffset>
              <bitWidth>1</bitWidth>
            </field>
            <field>
              <name>DEDF</name>
              <bitOffset>1</bitOffset>
              <bitWidth>1</bitWidth>
            </field>
            <field>
              <name>DEBWDF</name>
              <bitOffset>2</bitOffset>
              <bitWidth>1</bitWidth>
            </field>
          </fields>
        </register>
        <register>
          <name>FAR3</name>
          <addressOffset>0x68</addressOffset>
          <size>0x20</size>
          <fields>
            <field>
              <name>FDATAL</name>
              <bitOffset>0</bitOffset>
              <bitWidth>32</bitWidth>
            </field>
          </fields>
        </register>
        <register>
          <name>FAR3</name>
          <addressOffset>0x68</addressOffset>
          <size>0x20</size>
          <fields>
            <field>
              <name>FDATAL</name>
              <bitOffset>0</bitOffset>
              <bitWidth>32</bitWidth>
            </field>
          </fields>
        </register>
        <register>
          <name>FDRL3</name>
          <addressOffset>0x6c</addressOffset>
          <size>0x20</size>
        </register>
        <register>
          <name>FDRL3</name>
          <addressOffset>0x6c</addressOffset>
          <size>0x20</size>
        </register>
        <register>
          <name>FDRH3</name>
          <addressOffset>0x70</addressOffset>
          <size>0x20</size>
        </register>
        <register>
          <name>FDRH3</name>
          <addressOffset>0x70</addressOffset>
          <size>0x20</size>
        </register>
        <register>
          <name>FECR3</name>
          <addressOffset>0x74</addressOffset>
          <size>0x20</size>
          <fields>
            <field>
              <name>FEC</name>
              <bitOffset>0</bitOffset>
              <bitWidth>32</bitWidth>
            </field>
          </fields>
        </register>
        <register>
          <name>FECR3</name>
          <addressOffset>0x74</addressOffset>
          <size>0x20</size>
          <fields>
            <field>
              <name>FEC</name>
              <bitOffset>0</bitOffset>
              <bitWidth>32</bitWidth>
            </field>
          </fields>
        </register>
        <register>
          <name>CR4</name>
          <addressOffset>0x80</addressOffset>
          <size>0x20</size>
          <fields>
            <field>
              <name>ECCSEIE</name>
              <bitOffset>2</bitOffset>
              <bitWidth>1</bitWidth>
            </field>
            <field>
              <name>ECCDEIE</name>
              <bitOffset>3</bitOffset>
              <bitWidth>1</bitWidth>
            </field>
            <field>
              <name>ECCDEBWIE</name>
              <bitOffset>4</bitOffset>
              <bitWidth>1</bitWidth>
            </field>
            <field>
              <name>ECCELEN</name>
              <bitOffset>5</bitOffset>
              <bitWidth>1</bitWidth>
            </field>
          </fields>
        </register>
        <register>
          <name>CR4</name>
          <addressOffset>0x80</addressOffset>
          <size>0x20</size>
          <fields>
            <field>
              <name>ECCSEIE</name>
              <bitOffset>2</bitOffset>
              <bitWidth>1</bitWidth>
            </field>
            <field>
              <name>ECCDEIE</name>
              <bitOffset>3</bitOffset>
              <bitWidth>1</bitWidth>
            </field>
            <field>
              <name>ECCDEBWIE</name>
              <bitOffset>4</bitOffset>
              <bitWidth>1</bitWidth>
            </field>
            <field>
              <name>ECCELEN</name>
              <bitOffset>5</bitOffset>
              <bitWidth>1</bitWidth>
            </field>
          </fields>
        </register>
        <register>
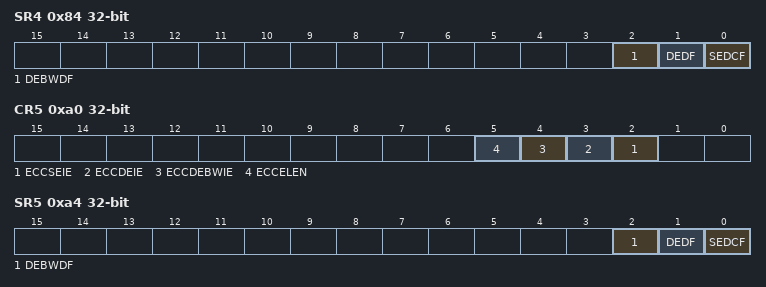
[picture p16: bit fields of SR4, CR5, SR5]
          <name>SR4</name>
          <addressOffset>0x84</addressOffset>
          <size>0x20</size>
          <fields>
            <field>
              <name>SEDCF</name>
              <bitOffset>0</bitOffset>
              <bitWidth>1</bitWidth>
            </field>
            <field>
              <name>DEDF</name>
              <bitOffset>1</bitOffset>
              <bitWidth>1</bitWidth>
            </field>
            <field>
              <name>DEBWDF</name>
              <bitOffset>2</bitOffset>
              <bitWidth>1</bitWidth>
            </field>
          </fields>
        </register>
        <register>
          <name>SR4</name>
          <addressOffset>0x84</addressOffset>
          <size>0x20</size>
          <fields>
            <field>
              <name>SEDCF</name>
              <bitOffset>0</bitOffset>
              <bitWidth>1</bitWidth>
            </field>
            <field>
              <name>DEDF</name>
              <bitOffset>1</bitOffset>
              <bitWidth>1</bitWidth>
            </field>
            <field>
              <name>DEBWDF</name>
              <bitOffset>2</bitOffset>
              <bitWidth>1</bitWidth>
            </field>
          </fields>
        </register>
        <register>
          <name>FAR4</name>
          <addressOffset>0x88</addressOffset>
          <size>0x20</size>
          <fields>
            <field>
              <name>FDATAL</name>
              <bitOffset>0</bitOffset>
              <bitWidth>32</bitWidth>
            </field>
          </fields>
        </register>
        <register>
          <name>FAR4</name>
          <addressOffset>0x88</addressOffset>
          <size>0x20</size>
          <fields>
            <field>
              <name>FDATAL</name>
              <bitOffset>0</bitOffset>
              <bitWidth>32</bitWidth>
            </field>
          </fields>
        </register>
        <register>
          <name>FDRL4</name>
          <addressOffset>0x8c</addressOffset>
          <size>0x20</size>
        </register>
        <register>
          <name>FDRL4</name>
          <addressOffset>0x8c</addressOffset>
          <size>0x20</size>
        </register>
        <register>
          <name>FDRH4</name>
          <addressOffset>0x90</addressOffset>
          <size>0x20</size>
        </register>
        <register>
          <name>FDRH4</name>
          <addressOffset>0x90</addressOffset>
          <size>0x20</size>
        </register>
        <register>
          <name>FECR4</name>
          <addressOffset>0x94</addressOffset>
          <size>0x20</size>
          <fields>
            <field>
              <name>FEC</name>
              <bitOffset>0</bitOffset>
              <bitWidth>32</bitWidth>
            </field>
          </fields>
        </register>
        <register>
          <name>FECR4</name>
          <addressOffset>0x94</addressOffset>
          <size>0x20</size>
          <fields>
            <field>
              <name>FEC</name>
              <bitOffset>0</bitOffset>
              <bitWidth>32</bitWidth>
            </field>
          </fields>
        </register>
        <register>
          <name>CR5</name>
          <addressOffset>0xa0</addressOffset>
          <size>0x20</size>
          <fields>
            <field>
              <name>ECCSEIE</name>
              <bitOffset>2</bitOffset>
              <bitWidth>1</bitWidth>
            </field>
            <field>
              <name>ECCDEIE</name>
              <bitOffset>3</bitOffset>
              <bitWidth>1</bitWidth>
            </field>
            <field>
              <name>ECCDEBWIE</name>
              <bitOffset>4</bitOffset>
              <bitWidth>1</bitWidth>
            </field>
            <field>
              <name>ECCELEN</name>
              <bitOffset>5</bitOffset>
              <bitWidth>1</bitWidth>
            </field>
          </fields>
        </register>
        <register>
          <name>CR5</name>
          <addressOffset>0xa0</addressOffset>
          <size>0x20</size>
          <fields>
            <field>
              <name>ECCSEIE</name>
              <bitOffset>2</bitOffset>
              <bitWidth>1</bitWidth>
            </field>
            <field>
              <name>ECCDEIE</name>
              <bitOffset>3</bitOffset>
              <bitWidth>1</bitWidth>
            </field>
            <field>
              <name>ECCDEBWIE</name>
              <bitOffset>4</bitOffset>
              <bitWidth>1</bitWidth>
            </field>
            <field>
              <name>ECCELEN</name>
              <bitOffset>5</bitOffset>
              <bitWidth>1</bitWidth>
            </field>
          </fields>
        </register>
        <register>
          <name>SR5</name>
          <addressOffset>0xa4</addressOffset>
          <size>0x20</size>
          <fields>
            <field>
              <name>SEDCF</name>
              <bitOffset>0</bitOffset>
              <bitWidth>1</bitWidth>
            </field>
            <field>
              <name>DEDF</name>
              <bitOffset>1</bitOffset>
              <bitWidth>1</bitWidth>
            </field>
            <field>
              <name>DEBWDF</name>
              <bitOffset>2</bitOffset>
              <bitWidth>1</bitWidth>
            </field>
          </fields>
        </register>
        <register>
          <name>SR5</name>
          <addressOffset>0xa4</addressOffset>
          <size>0x20</size>
          <fields>
            <field>
              <name>SEDCF</name>
              <bitOffset>0</bitOffset>
              <bitWidth>1</bitWidth>
            </field>
            <field>
              <name>DEDF</name>
              <bitOffset>1</bitOffset>
              <bitWidth>1</bitWidth>
            </field>
            <field>
              <name>DEBWDF</name>
              <bitOffset>2</bitOffset>
              <bitWidth>1</bitWidth>
            </field>
          </fields>
        </register>
        <register>
          <name>FAR5</name>
          <addressOffset>0xa8</addressOffset>
          <size>0x20</size>
          <fields>
            <field>
              <name>FDATAL</name>
              <bitOffset>0</bitOffset>
              <bitWidth>32</bitWidth>
            </field>
          </fields>
        </register>
        <register>
          <name>FAR5</name>
          <addressOffset>0xa8</addressOffset>
          <size>0x20</size>
          <fields>
            <field>
              <name>FDATAL</name>
              <bitOffset>0</bitOffset>
              <bitWidth>32</bitWidth>
            </field>
          </fields>
        </register>
        <register>
          <name>FDRL5</name>
          <addressOffset>0xac</addressOffset>
          <size>0x20</size>
        </register>
        <register>
          <name>FDRL5</name>
          <addressOffset>0xac</addressOffset>
          <size>0x20</size>
        </register>
        <register>
          <name>FDRH5</name>
          <addressOffset>0xb0</addressOffset>
          <size>0x20</size>
        </register>
        <register>
          <name>FDRH5</name>
          <addressOffset>0xb0</addressOffset>
          <size>0x20</size>
        </register>
        <register>
          <name>FECR5</name>
          <addressOffset>0xb4</addressOffset>
          <size>0x20</size>
          <fields>
            <field>
              <name>FEC</name>
              <bitOffset>0</bitOffset>
              <bitWidth>32</bitWidth>
            </field>
          </fields>
        </register>
        <register>
          <name>FECR5</name>
          <addressOffset>0xb4</addressOffset>
          <size>0x20</size>
          <fields>
            <field>
              <name>FEC</name>
              <bitOffset>0</bitOffset>
              <bitWidth>32</bitWidth>
            </field>
          </fields>
        </register>
      </registers>
    </peripheral>
    <peripheral>
      <name>EXTI</name>
      <baseAddress>0x58000000</baseAddress>
      <registers>
        <register>
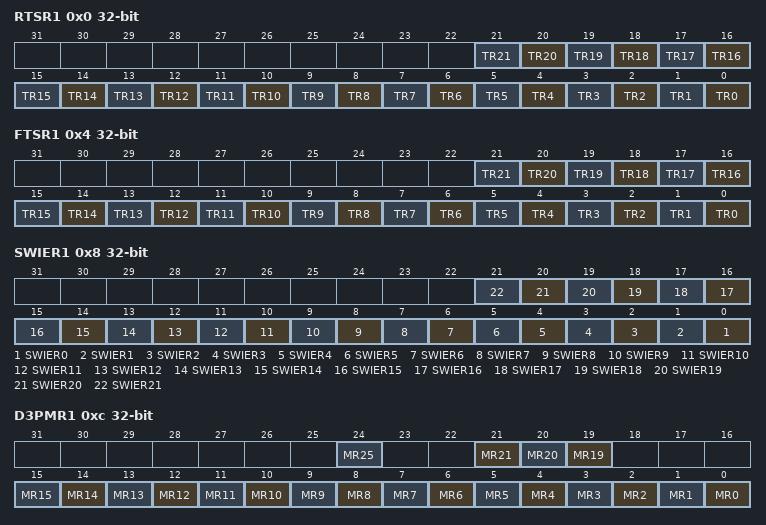
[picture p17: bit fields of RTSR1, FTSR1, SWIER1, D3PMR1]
          <name>RTSR1</name>
          <addressOffset>0x0</addressOffset>
          <size>0x20</size>
          <fields>
            <field>
              <name>TR0</name>
              <bitOffset>0</bitOffset>
              <bitWidth>1</bitWidth>
            </field>
            <field>
              <name>TR1</name>
              <bitOffset>1</bitOffset>
              <bitWidth>1</bitWidth>
            </field>
            <field>
              <name>TR2</name>
              <bitOffset>2</bitOffset>
              <bitWidth>1</bitWidth>
            </field>
            <field>
              <name>TR3</name>
              <bitOffset>3</bitOffset>
              <bitWidth>1</bitWidth>
            </field>
            <field>
              <name>TR4</name>
              <bitOffset>4</bitOffset>
              <bitWidth>1</bitWidth>
            </field>
            <field>
              <name>TR5</name>
              <bitOffset>5</bitOffset>
              <bitWidth>1</bitWidth>
            </field>
            <field>
              <name>TR6</name>
              <bitOffset>6</bitOffset>
              <bitWidth>1</bitWidth>
            </field>
            <field>
              <name>TR7</name>
              <bitOffset>7</bitOffset>
              <bitWidth>1</bitWidth>
            </field>
            <field>
              <name>TR8</name>
              <bitOffset>8</bitOffset>
              <bitWidth>1</bitWidth>
            </field>
            <field>
              <name>TR9</name>
              <bitOffset>9</bitOffset>
              <bitWidth>1</bitWidth>
            </field>
            <field>
              <name>TR10</name>
              <bitOffset>10</bitOffset>
              <bitWidth>1</bitWidth>
            </field>
            <field>
              <name>TR11</name>
              <bitOffset>11</bitOffset>
              <bitWidth>1</bitWidth>
            </field>
            <field>
              <name>TR12</name>
              <bitOffset>12</bitOffset>
              <bitWidth>1</bitWidth>
            </field>
            <field>
              <name>TR13</name>
              <bitOffset>13</bitOffset>
              <bitWidth>1</bitWidth>
            </field>
            <field>
              <name>TR14</name>
              <bitOffset>14</bitOffset>
              <bitWidth>1</bitWidth>
            </field>
            <field>
              <name>TR15</name>
              <bitOffset>15</bitOffset>
              <bitWidth>1</bitWidth>
            </field>
            <field>
              <name>TR16</name>
              <bitOffset>16</bitOffset>
              <bitWidth>1</bitWidth>
            </field>
            <field>
              <name>TR17</name>
              <bitOffset>17</bitOffset>
              <bitWidth>1</bitWidth>
            </field>
            <field>
              <name>TR18</name>
              <bitOffset>18</bitOffset>
              <bitWidth>1</bitWidth>
            </field>
            <field>
              <name>TR19</name>
              <bitOffset>19</bitOffset>
              <bitWidth>1</bitWidth>
            </field>
            <field>
              <name>TR20</name>
              <bitOffset>20</bitOffset>
              <bitWidth>1</bitWidth>
            </field>
            <field>
              <name>TR21</name>
              <bitOffset>21</bitOffset>
              <bitWidth>1</bitWidth>
            </field>
          </fields>
        </register>
        <register>
          <name>FTSR1</name>
          <addressOffset>0x4</addressOffset>
          <size>0x20</size>
          <fields>
            <field>
              <name>TR0</name>
              <bitOffset>0</bitOffset>
              <bitWidth>1</bitWidth>
            </field>
            <field>
              <name>TR1</name>
              <bitOffset>1</bitOffset>
              <bitWidth>1</bitWidth>
            </field>
            <field>
              <name>TR2</name>
              <bitOffset>2</bitOffset>
              <bitWidth>1</bitWidth>
            </field>
            <field>
              <name>TR3</name>
              <bitOffset>3</bitOffset>
              <bitWidth>1</bitWidth>
            </field>
            <field>
              <name>TR4</name>
              <bitOffset>4</bitOffset>
              <bitWidth>1</bitWidth>
            </field>
            <field>
              <name>TR5</name>
              <bitOffset>5</bitOffset>
              <bitWidth>1</bitWidth>
            </field>
            <field>
              <name>TR6</name>
              <bitOffset>6</bitOffset>
              <bitWidth>1</bitWidth>
            </field>
            <field>
              <name>TR7</name>
              <bitOffset>7</bitOffset>
              <bitWidth>1</bitWidth>
            </field>
            <field>
              <name>TR8</name>
              <bitOffset>8</bitOffset>
              <bitWidth>1</bitWidth>
            </field>
            <field>
              <name>TR9</name>
              <bitOffset>9</bitOffset>
              <bitWidth>1</bitWidth>
            </field>
            <field>
              <name>TR10</name>
              <bitOffset>10</bitOffset>
              <bitWidth>1</bitWidth>
            </field>
            <field>
              <name>TR11</name>
              <bitOffset>11</bitOffset>
              <bitWidth>1</bitWidth>
            </field>
            <field>
              <name>TR12</name>
              <bitOffset>12</bitOffset>
              <bitWidth>1</bitWidth>
            </field>
            <field>
              <name>TR13</name>
              <bitOffset>13</bitOffset>
              <bitWidth>1</bitWidth>
            </field>
            <field>
              <name>TR14</name>
              <bitOffset>14</bitOffset>
              <bitWidth>1</bitWidth>
            </field>
            <field>
              <name>TR15</name>
              <bitOffset>15</bitOffset>
              <bitWidth>1</bitWidth>
            </field>
            <field>
              <name>TR16</name>
              <bitOffset>16</bitOffset>
              <bitWidth>1</bitWidth>
            </field>
            <field>
              <name>TR17</name>
              <bitOffset>17</bitOffset>
              <bitWidth>1</bitWidth>
            </field>
            <field>
              <name>TR18</name>
              <bitOffset>18</bitOffset>
              <bitWidth>1</bitWidth>
            </field>
            <field>
              <name>TR19</name>
              <bitOffset>19</bitOffset>
              <bitWidth>1</bitWidth>
            </field>
            <field>
              <name>TR20</name>
              <bitOffset>20</bitOffset>
              <bitWidth>1</bitWidth>
            </field>
            <field>
              <name>TR21</name>
              <bitOffset>21</bitOffset>
              <bitWidth>1</bitWidth>
            </field>
          </fields>
        </register>
        <register>
          <name>SWIER1</name>
          <addressOffset>0x8</addressOffset>
          <size>0x20</size>
          <fields>
            <field>
              <name>SWIER0</name>
              <bitOffset>0</bitOffset>
              <bitWidth>1</bitWidth>
            </field>
            <field>
              <name>SWIER1</name>
              <bitOffset>1</bitOffset>
              <bitWidth>1</bitWidth>
            </field>
            <field>
              <name>SWIER2</name>
              <bitOffset>2</bitOffset>
              <bitWidth>1</bitWidth>
            </field>
            <field>
              <name>SWIER3</name>
              <bitOffset>3</bitOffset>
              <bitWidth>1</bitWidth>
            </field>
            <field>
              <name>SWIER4</name>
              <bitOffset>4</bitOffset>
              <bitWidth>1</bitWidth>
            </field>
            <field>
              <name>SWIER5</name>
              <bitOffset>5</bitOffset>
              <bitWidth>1</bitWidth>
            </field>
            <field>
              <name>SWIER6</name>
              <bitOffset>6</bitOffset>
              <bitWidth>1</bitWidth>
            </field>
            <field>
              <name>SWIER7</name>
              <bitOffset>7</bitOffset>
              <bitWidth>1</bitWidth>
            </field>
            <field>
              <name>SWIER8</name>
              <bitOffset>8</bitOffset>
              <bitWidth>1</bitWidth>
            </field>
            <field>
              <name>SWIER9</name>
              <bitOffset>9</bitOffset>
              <bitWidth>1</bitWidth>
            </field>
            <field>
              <name>SWIER10</name>
              <bitOffset>10</bitOffset>
              <bitWidth>1</bitWidth>
            </field>
            <field>
              <name>SWIER11</name>
              <bitOffset>11</bitOffset>
              <bitWidth>1</bitWidth>
            </field>
            <field>
              <name>SWIER12</name>
              <bitOffset>12</bitOffset>
              <bitWidth>1</bitWidth>
            </field>
            <field>
              <name>SWIER13</name>
              <bitOffset>13</bitOffset>
              <bitWidth>1</bitWidth>
            </field>
            <field>
              <name>SWIER14</name>
              <bitOffset>14</bitOffset>
              <bitWidth>1</bitWidth>
            </field>
            <field>
              <name>SWIER15</name>
              <bitOffset>15</bitOffset>
              <bitWidth>1</bitWidth>
            </field>
            <field>
              <name>SWIER16</name>
              <bitOffset>16</bitOffset>
              <bitWidth>1</bitWidth>
            </field>
            <field>
              <name>SWIER17</name>
              <bitOffset>17</bitOffset>
              <bitWidth>1</bitWidth>
            </field>
            <field>
              <name>SWIER18</name>
              <bitOffset>18</bitOffset>
              <bitWidth>1</bitWidth>
            </field>
            <field>
              <name>SWIER19</name>
              <bitOffset>19</bitOffset>
              <bitWidth>1</bitWidth>
            </field>
            <field>
              <name>SWIER20</name>
              <bitOffset>20</bitOffset>
              <bitWidth>1</bitWidth>
            </field>
            <field>
              <name>SWIER21</name>
              <bitOffset>21</bitOffset>
              <bitWidth>1</bitWidth>
            </field>
          </fields>
        </register>
        <register>
          <name>D3PMR1</name>
          <addressOffset>0xc</addressOffset>
          <size>0x20</size>
          <fields>
            <field>
              <name>MR0</name>
              <bitOffset>0</bitOffset>
              <bitWidth>1</bitWidth>
            </field>
            <field>
              <name>MR1</name>
              <bitOffset>1</bitOffset>
              <bitWidth>1</bitWidth>
            </field>
            <field>
              <name>MR2</name>
              <bitOffset>2</bitOffset>
              <bitWidth>1</bitWidth>
            </field>
            <field>
              <name>MR3</name>
              <bitOffset>3</bitOffset>
              <bitWidth>1</bitWidth>
            </field>
            <field>
              <name>MR4</name>
              <bitOffset>4</bitOffset>
              <bitWidth>1</bitWidth>
            </field>
            <field>
              <name>MR5</name>
              <bitOffset>5</bitOffset>
              <bitWidth>1</bitWidth>
            </field>
            <field>
              <name>MR6</name>
              <bitOffset>6</bitOffset>
              <bitWidth>1</bitWidth>
            </field>
            <field>
              <name>MR7</name>
              <bitOffset>7</bitOffset>
              <bitWidth>1</bitWidth>
            </field>
            <field>
              <name>MR8</name>
              <bitOffset>8</bitOffset>
              <bitWidth>1</bitWidth>
            </field>
            <field>
              <name>MR9</name>
              <bitOffset>9</bitOffset>
              <bitWidth>1</bitWidth>
            </field>
            <field>
              <name>MR10</name>
              <bitOffset>10</bitOffset>
              <bitWidth>1</bitWidth>
            </field>
            <field>
              <name>MR11</name>
              <bitOffset>11</bitOffset>
              <bitWidth>1</bitWidth>
            </field>
            <field>
              <name>MR12</name>
              <bitOffset>12</bitOffset>
              <bitWidth>1</bitWidth>
            </field>
            <field>
              <name>MR13</name>
              <bitOffset>13</bitOffset>
              <bitWidth>1</bitWidth>
            </field>
            <field>
              <name>MR14</name>
              <bitOffset>14</bitOffset>
              <bitWidth>1</bitWidth>
            </field>
            <field>
              <name>MR15</name>
              <bitOffset>15</bitOffset>
              <bitWidth>1</bitWidth>
            </field>
            <field>
              <name>MR19</name>
              <bitOffset>19</bitOffset>
              <bitWidth>1</bitWidth>
            </field>
            <field>
              <name>MR20</name>
              <bitOffset>20</bitOffset>
              <bitWidth>1</bitWidth>
            </field>
            <field>
              <name>MR21</name>
              <bitOffset>21</bitOffset>
              <bitWidth>1</bitWidth>
            </field>
            <field>
              <name>MR25</name>
              <bitOffset>24</bitOffset>
              <bitWidth>1</bitWidth>
            </field>
          </fields>
        </register>
        <register>
          <name>D3PCR1L</name>
          <addressOffset>0x10</addressOffset>
          <size>0x20</size>
          <fields>
            <field>
              <name>PCS0</name>
              <bitOffset>0</bitOffset>
              <bitWidth>2</bitWidth>
            </field>
            <field>
              <name>PCS1</name>
              <bitOffset>2</bitOffset>
              <bitWidth>2</bitWidth>
            </field>
            <field>
              <name>PCS2</name>
              <bitOffset>4</bitOffset>
              <bitWidth>2</bitWidth>
            </field>
            <field>
              <name>PCS3</name>
              <bitOffset>6</bitOffset>
              <bitWidth>2</bitWidth>
            </field>
            <field>
              <name>PCS4</name>
              <bitOffset>8</bitOffset>
              <bitWidth>2</bitWidth>
            </field>
            <field>
              <name>PCS5</name>
              <bitOffset>10</bitOffset>
              <bitWidth>2</bitWidth>
            </field>
            <field>
              <name>PCS6</name>
              <bitOffset>12</bitOffset>
              <bitWidth>2</bitWidth>
            </field>
            <field>
              <name>PCS7</name>
              <bitOffset>14</bitOffset>
              <bitWidth>2</bitWidth>
            </field>
            <field>
              <name>PCS8</name>
              <bitOffset>16</bitOffset>
              <bitWidth>2</bitWidth>
            </field>
            <field>
              <name>PCS9</name>
              <bitOffset>18</bitOffset>
              <bitWidth>2</bitWidth>
            </field>
            <field>
              <name>PCS10</name>
              <bitOffset>20</bitOffset>
              <bitWidth>2</bitWidth>
            </field>
            <field>
              <name>PCS11</name>
              <bitOffset>22</bitOffset>
              <bitWidth>2</bitWidth>
            </field>
            <field>
              <name>PCS12</name>
              <bitOffset>24</bitOffset>
              <bitWidth>2</bitWidth>
            </field>
            <field>
              <name>PCS13</name>
              <bitOffset>26</bitOffset>
              <bitWidth>2</bitWidth>
            </field>
            <field>
              <name>PCS14</name>
              <bitOffset>28</bitOffset>
              <bitWidth>2</bitWidth>
            </field>
            <field>
              <name>PCS15</name>
              <bitOffset>30</bitOffset>
              <bitWidth>2</bitWidth>
            </field>
          </fields>
        </register>
        <register>
          <name>D3PCR1H</name>
          <addressOffset>0x14</addressOffset>
          <size>0x20</size>
          <fields>
            <field>
              <name>PCS19</name>
              <bitOffset>6</bitOffset>
              <bitWidth>2</bitWidth>
            </field>
            <field>
              <name>PCS20</name>
              <bitOffset>8</bitOffset>
              <bitWidth>2</bitWidth>
            </field>
            <field>
              <name>PCS21</name>
              <bitOffset>10</bitOffset>
              <bitWidth>2</bitWidth>
            </field>
            <field>
              <name>PCS25</name>
              <bitOffset>18</bitOffset>
              <bitWidth>2</bitWidth>
            </field>
          </fields>
        </register>
        <register>
          <name>RTSR2</name>
          <addressOffset>0x20</addressOffset>
          <size>0x20</size>
          <fields>
            <field>
              <name>TR49</name>
              <bitOffset>17</bitOffset>
              <bitWidth>1</bitWidth>
            </field>
            <field>
              <name>TR51</name>
              <bitOffset>19</bitOffset>
              <bitWidth>1</bitWidth>
            </field>
          </fields>
        </register>
        <register>
          <name>FTSR2</name>
          <addressOffset>0x24</addressOffset>
          <size>0x20</size>
          <fields>
            <field>
              <name>TR49</name>
              <bitOffset>17</bitOffset>
              <bitWidth>1</bitWidth>
            </field>
            <field>
              <name>TR51</name>
              <bitOffset>19</bitOffset>
              <bitWidth>1</bitWidth>
            </field>
          </fields>
        </register>
        <register>
          <name>SWIER2</name>
          <addressOffset>0x28</addressOffset>
          <size>0x20</size>
          <fields>
            <field>
              <name>SWIER49</name>
              <bitOffset>17</bitOffset>
              <bitWidth>1</bitWidth>
            </field>
            <field>
              <name>SWIER51</name>
              <bitOffset>19</bitOffset>
              <bitWidth>1</bitWidth>
            </field>
          </fields>
        </register>
        <register>
          <name>D3PMR2</name>
          <addressOffset>0x2c</addressOffset>
          <size>0x20</size>
          <fields>
            <field>
              <name>MR34</name>
              <bitOffset>2</bitOffset>
              <bitWidth>1</bitWidth>
            </field>
            <field>
              <name>MR35</name>
              <bitOffset>3</bitOffset>
              <bitWidth>1</bitWidth>
            </field>
            <field>
              <name>MR41</name>
              <bitOffset>9</bitOffset>
              <bitWidth>1</bitWidth>
            </field>
            <field>
              <name>MR48</name>
              <bitOffset>16</bitOffset>
              <bitWidth>1</bitWidth>
            </field>
            <field>
              <name>MR49</name>
              <bitOffset>17</bitOffset>
              <bitWidth>1</bitWidth>
            </field>
            <field>
              <name>MR50</name>
              <bitOffset>18</bitOffset>
              <bitWidth>1</bitWidth>
            </field>
            <field>
              <name>MR51</name>
              <bitOffset>19</bitOffset>
              <bitWidth>1</bitWidth>
            </field>
            <field>
              <name>MR52</name>
              <bitOffset>20</bitOffset>
              <bitWidth>1</bitWidth>
            </field>
            <field>
              <name>MR53</name>
              <bitOffset>21</bitOffset>
              <bitWidth>1</bitWidth>
            </field>
          </fields>
        </register>
        <register>
          <name>D3PCR2L</name>
          <addressOffset>0x30</addressOffset>
          <size>0x20</size>
          <fields>
            <field>
              <name>PCS34</name>
              <bitOffset>4</bitOffset>
              <bitWidth>2</bitWidth>
            </field>
            <field>
              <name>PCS35</name>
              <bitOffset>6</bitOffset>
              <bitWidth>2</bitWidth>
            </field>
            <field>
              <name>PCS41</name>
              <bitOffset>18</bitOffset>
              <bitWidth>2</bitWidth>
            </field>
          </fields>
        </register>
        <register>
          <name>D3PCR2H</name>
          <addressOffset>0x34</addressOffset>
          <size>0x20</size>
          <fields>
            <field>
              <name>PCS48</name>
              <bitOffset>0</bitOffset>
              <bitWidth>2</bitWidth>
            </field>
            <field>
              <name>PCS49</name>
              <bitOffset>2</bitOffset>
              <bitWidth>2</bitWidth>
            </field>
            <field>
              <name>PCS50</name>
              <bitOffset>4</bitOffset>
              <bitWidth>2</bitWidth>
            </field>
            <field>
              <name>PCS51</name>
              <bitOffset>6</bitOffset>
              <bitWidth>2</bitWidth>
            </field>
            <field>
              <name>PCS52</name>
              <bitOffset>8</bitOffset>
              <bitWidth>2</bitWidth>
            </field>
            <field>
              <name>PCS53</name>
              <bitOffset>10</bitOffset>
              <bitWidth>2</bitWidth>
            </field>
          </fields>
        </register>
        <register>
          <name>RTSR3</name>
          <addressOffset>0x40</addressOffset>
          <size>0x20</size>
          <fields>
            <field>
              <name>TR82</name>
              <bitOffset>18</bitOffset>
              <bitWidth>1</bitWidth>
            </field>
            <field>
              <name>TR84</name>
              <bitOffset>20</bitOffset>
              <bitWidth>1</bitWidth>
            </field>
            <field>
              <name>TR85</name>
              <bitOffset>21</bitOffset>
              <bitWidth>1</bitWidth>
            </field>
            <field>
              <name>TR86</name>
              <bitOffset>22</bitOffset>
              <bitWidth>1</bitWidth>
            </field>
          </fields>
        </register>
        <register>
          <name>FTSR3</name>
          <addressOffset>0x44</addressOffset>
          <size>0x20</size>
          <fields>
            <field>
              <name>TR82</name>
              <bitOffset>18</bitOffset>
              <bitWidth>1</bitWidth>
            </field>
            <field>
              <name>TR84</name>
              <bitOffset>20</bitOffset>
              <bitWidth>1</bitWidth>
            </field>
            <field>
              <name>TR85</name>
              <bitOffset>21</bitOffset>
              <bitWidth>1</bitWidth>
            </field>
            <field>
              <name>TR86</name>
              <bitOffset>22</bitOffset>
              <bitWidth>1</bitWidth>
            </field>
          </fields>
        </register>
        <register>
          <name>SWIER3</name>
          <addressOffset>0x48</addressOffset>
          <size>0x20</size>
          <fields>
            <field>
              <name>SWIER82</name>
              <bitOffset>18</bitOffset>
              <bitWidth>1</bitWidth>
            </field>
            <field>
              <name>SWIER84</name>
              <bitOffset>20</bitOffset>
              <bitWidth>1</bitWidth>
            </field>
            <field>
              <name>SWIER85</name>
              <bitOffset>21</bitOffset>
              <bitWidth>1</bitWidth>
            </field>
            <field>
              <name>SWIER86</name>
              <bitOffset>22</bitOffset>
              <bitWidth>1</bitWidth>
            </field>
          </fields>
        </register>
        <register>
          <name>D3PMR3</name>
          <addressOffset>0x4c</addressOffset>
          <size>0x20</size>
        </register>
        <register>
          <name>D3PCR3L</name>
          <addressOffset>0x50</addressOffset>
          <size>0x20</size>
        </register>
        <register>
          <name>D3PCR3H</name>
          <addressOffset>0x54</addressOffset>
          <size>0x20</size>
        </register>
        <register>
          <name>IMR1</name>
          <addressOffset>0x80</addressOffset>
          <size>0x20</size>
          <fields>
            <field>
              <name>IM0</name>
              <bitOffset>0</bitOffset>
              <bitWidth>1</bitWidth>
            </field>
            <field>
              <name>IM1</name>
              <bitOffset>1</bitOffset>
              <bitWidth>1</bitWidth>
            </field>
            <field>
              <name>IM2</name>
              <bitOffset>2</bitOffset>
              <bitWidth>1</bitWidth>
            </field>
            <field>
              <name>IM3</name>
              <bitOffset>3</bitOffset>
              <bitWidth>1</bitWidth>
            </field>
            <field>
              <name>IM4</name>
              <bitOffset>4</bitOffset>
              <bitWidth>1</bitWidth>
            </field>
            <field>
              <name>IM5</name>
              <bitOffset>5</bitOffset>
              <bitWidth>1</bitWidth>
            </field>
            <field>
              <name>IM6</name>
              <bitOffset>6</bitOffset>
              <bitWidth>1</bitWidth>
            </field>
            <field>
              <name>IM7</name>
              <bitOffset>7</bitOffset>
              <bitWidth>1</bitWidth>
            </field>
            <field>
              <name>IM8</name>
              <bitOffset>8</bitOffset>
              <bitWidth>1</bitWidth>
            </field>
            <field>
              <name>IM9</name>
              <bitOffset>9</bitOffset>
              <bitWidth>1</bitWidth>
            </field>
            <field>
              <name>IM10</name>
              <bitOffset>10</bitOffset>
              <bitWidth>1</bitWidth>
            </field>
            <field>
              <name>IM11</name>
              <bitOffset>11</bitOffset>
              <bitWidth>1</bitWidth>
            </field>
            <field>
              <name>IM12</name>
              <bitOffset>12</bitOffset>
              <bitWidth>1</bitWidth>
            </field>
            <field>
              <name>IM13</name>
              <bitOffset>13</bitOffset>
              <bitWidth>1</bitWidth>
            </field>
            <field>
              <name>IM14</name>
              <bitOffset>14</bitOffset>
              <bitWidth>1</bitWidth>
            </field>
            <field>
              <name>IM15</name>
              <bitOffset>15</bitOffset>
              <bitWidth>1</bitWidth>
            </field>
            <field>
              <name>IM16</name>
              <bitOffset>16</bitOffset>
              <bitWidth>1</bitWidth>
            </field>
            <field>
              <name>IM17</name>
              <bitOffset>17</bitOffset>
              <bitWidth>1</bitWidth>
            </field>
            <field>
              <name>IM18</name>
              <bitOffset>18</bitOffset>
              <bitWidth>1</bitWidth>
            </field>
            <field>
              <name>IM19</name>
              <bitOffset>19</bitOffset>
              <bitWidth>1</bitWidth>
            </field>
            <field>
              <name>IM20</name>
              <bitOffset>20</bitOffset>
              <bitWidth>1</bitWidth>
            </field>
            <field>
              <name>IM21</name>
              <bitOffset>21</bitOffset>
              <bitWidth>1</bitWidth>
            </field>
            <field>
              <name>IM22</name>
              <bitOffset>22</bitOffset>
              <bitWidth>1</bitWidth>
            </field>
            <field>
              <name>IM23</name>
              <bitOffset>23</bitOffset>
              <bitWidth>1</bitWidth>
            </field>
            <field>
              <name>IM24</name>
              <bitOffset>24</bitOffset>
              <bitWidth>1</bitWidth>
            </field>
            <field>
              <name>IM25</name>
              <bitOffset>25</bitOffset>
              <bitWidth>1</bitWidth>
            </field>
            <field>
              <name>IM26</name>
              <bitOffset>26</bitOffset>
              <bitWidth>1</bitWidth>
            </field>
            <field>
              <name>IM27</name>
              <bitOffset>27</bitOffset>
              <bitWidth>1</bitWidth>
            </field>
            <field>
              <name>IM28</name>
              <bitOffset>28</bitOffset>
              <bitWidth>1</bitWidth>
            </field>
            <field>
              <name>IM29</name>
              <bitOffset>29</bitOffset>
              <bitWidth>1</bitWidth>
            </field>
            <field>
              <name>IM30</name>
              <bitOffset>30</bitOffset>
              <bitWidth>1</bitWidth>
            </field>
            <field>
              <name>IM31</name>
              <bitOffset>31</bitOffset>
              <bitWidth>1</bitWidth>
            </field>
          </fields>
        </register>
        <register>
          <name>EMR1</name>
          <addressOffset>0x84</addressOffset>
          <size>0x20</size>
          <fields>
            <field>
              <name>EM0</name>
              <bitOffset>0</bitOffset>
              <bitWidth>1</bitWidth>
            </field>
            <field>
              <name>EM1</name>
              <bitOffset>1</bitOffset>
              <bitWidth>1</bitWidth>
            </field>
            <field>
              <name>EM2</name>
              <bitOffset>2</bitOffset>
              <bitWidth>1</bitWidth>
            </field>
            <field>
              <name>EM3</name>
              <bitOffset>3</bitOffset>
              <bitWidth>1</bitWidth>
            </field>
            <field>
              <name>EM4</name>
              <bitOffset>4</bitOffset>
              <bitWidth>1</bitWidth>
            </field>
            <field>
              <name>EM5</name>
              <bitOffset>5</bitOffset>
              <bitWidth>1</bitWidth>
            </field>
            <field>
              <name>EM6</name>
              <bitOffset>6</bitOffset>
              <bitWidth>1</bitWidth>
            </field>
            <field>
              <name>EM7</name>
              <bitOffset>7</bitOffset>
              <bitWidth>1</bitWidth>
            </field>
            <field>
              <name>EM8</name>
              <bitOffset>8</bitOffset>
              <bitWidth>1</bitWidth>
            </field>
            <field>
              <name>EM9</name>
              <bitOffset>9</bitOffset>
              <bitWidth>1</bitWidth>
            </field>
            <field>
              <name>EM10</name>
              <bitOffset>10</bitOffset>
              <bitWidth>1</bitWidth>
            </field>
            <field>
              <name>EM11</name>
              <bitOffset>11</bitOffset>
              <bitWidth>1</bitWidth>
            </field>
            <field>
              <name>EM12</name>
              <bitOffset>12</bitOffset>
              <bitWidth>1</bitWidth>
            </field>
            <field>
              <name>EM13</name>
              <bitOffset>13</bitOffset>
              <bitWidth>1</bitWidth>
            </field>
            <field>
              <name>EM14</name>
              <bitOffset>14</bitOffset>
              <bitWidth>1</bitWidth>
            </field>
            <field>
              <name>EM15</name>
              <bitOffset>15</bitOffset>
              <bitWidth>1</bitWidth>
            </field>
            <field>
              <name>EM16</name>
              <bitOffset>16</bitOffset>
              <bitWidth>1</bitWidth>
            </field>
            <field>
              <name>EM17</name>
              <bitOffset>17</bitOffset>
              <bitWidth>1</bitWidth>
            </field>
            <field>
              <name>EM18</name>
              <bitOffset>18</bitOffset>
              <bitWidth>1</bitWidth>
            </field>
            <field>
              <name>EM20</name>
              <bitOffset>20</bitOffset>
              <bitWidth>1</bitWidth>
            </field>
            <field>
              <name>EM21</name>
              <bitOffset>21</bitOffset>
              <bitWidth>1</bitWidth>
            </field>
            <field>
              <name>EM22</name>
              <bitOffset>22</bitOffset>
              <bitWidth>1</bitWidth>
            </field>
            <field>
              <name>EM23</name>
              <bitOffset>23</bitOffset>
              <bitWidth>1</bitWidth>
            </field>
            <field>
              <name>EM24</name>
              <bitOffset>24</bitOffset>
              <bitWidth>1</bitWidth>
            </field>
            <field>
              <name>EM25</name>
              <bitOffset>25</bitOffset>
              <bitWidth>1</bitWidth>
            </field>
            <field>
              <name>EM26</name>
              <bitOffset>26</bitOffset>
              <bitWidth>1</bitWidth>
            </field>
            <field>
              <name>EM27</name>
              <bitOffset>27</bitOffset>
              <bitWidth>1</bitWidth>
            </field>
            <field>
              <name>EM28</name>
              <bitOffset>28</bitOffset>
              <bitWidth>1</bitWidth>
            </field>
            <field>
              <name>EM29</name>
              <bitOffset>29</bitOffset>
              <bitWidth>1</bitWidth>
            </field>
            <field>
              <name>EM30</name>
              <bitOffset>30</bitOffset>
              <bitWidth>1</bitWidth>
            </field>
            <field>
              <name>EM31</name>
              <bitOffset>31</bitOffset>
              <bitWidth>1</bitWidth>
            </field>
          </fields>
        </register>
        <register>
          <name>PR1</name>
          <addressOffset>0x88</addressOffset>
          <size>0x20</size>
          <fields>
            <field>
              <name>PR0</name>
              <bitOffset>0</bitOffset>
              <bitWidth>1</bitWidth>
            </field>
            <field>
              <name>PR1</name>
              <bitOffset>1</bitOffset>
              <bitWidth>1</bitWidth>
            </field>
            <field>
              <name>PR2</name>
              <bitOffset>2</bitOffset>
              <bitWidth>1</bitWidth>
            </field>
            <field>
              <name>PR3</name>
              <bitOffset>3</bitOffset>
              <bitWidth>1</bitWidth>
            </field>
            <field>
              <name>PR4</name>
              <bitOffset>4</bitOffset>
              <bitWidth>1</bitWidth>
            </field>
            <field>
              <name>PR5</name>
              <bitOffset>5</bitOffset>
              <bitWidth>1</bitWidth>
            </field>
            <field>
              <name>PR6</name>
              <bitOffset>6</bitOffset>
              <bitWidth>1</bitWidth>
            </field>
            <field>
              <name>PR7</name>
              <bitOffset>7</bitOffset>
              <bitWidth>1</bitWidth>
            </field>
            <field>
              <name>PR8</name>
              <bitOffset>8</bitOffset>
              <bitWidth>1</bitWidth>
            </field>
            <field>
              <name>PR9</name>
              <bitOffset>9</bitOffset>
              <bitWidth>1</bitWidth>
            </field>
            <field>
              <name>PR10</name>
              <bitOffset>10</bitOffset>
              <bitWidth>1</bitWidth>
            </field>
            <field>
              <name>PR11</name>
              <bitOffset>11</bitOffset>
              <bitWidth>1</bitWidth>
            </field>
            <field>
              <name>PR12</name>
              <bitOffset>12</bitOffset>
              <bitWidth>1</bitWidth>
            </field>
            <field>
              <name>PR13</name>
              <bitOffset>13</bitOffset>
              <bitWidth>1</bitWidth>
            </field>
            <field>
              <name>PR14</name>
              <bitOffset>14</bitOffset>
              <bitWidth>1</bitWidth>
            </field>
            <field>
              <name>PR15</name>
              <bitOffset>15</bitOffset>
              <bitWidth>1</bitWidth>
            </field>
            <field>
              <name>PR16</name>
              <bitOffset>16</bitOffset>
              <bitWidth>1</bitWidth>
            </field>
            <field>
              <name>PR17</name>
              <bitOffset>17</bitOffset>
              <bitWidth>1</bitWidth>
            </field>
            <field>
              <name>PR18</name>
              <bitOffset>18</bitOffset>
              <bitWidth>1</bitWidth>
            </field>
            <field>
              <name>PR19</name>
              <bitOffset>19</bitOffset>
              <bitWidth>1</bitWidth>
            </field>
            <field>
              <name>PR20</name>
              <bitOffset>20</bitOffset>
              <bitWidth>1</bitWidth>
            </field>
            <field>
              <name>PR21</name>
              <bitOffset>21</bitOffset>
              <bitWidth>1</bitWidth>
            </field>
          </fields>
        </register>
        <register>
          <name>IMR2</name>
          <addressOffset>0x90</addressOffset>
          <size>0x20</size>
          <fields>
            <field>
              <name>IM32</name>
              <bitOffset>0</bitOffset>
              <bitWidth>1</bitWidth>
            </field>
            <field>
              <name>IM33</name>
              <bitOffset>1</bitOffset>
              <bitWidth>1</bitWidth>
            </field>
            <field>
              <name>IM34</name>
              <bitOffset>2</bitOffset>
              <bitWidth>1</bitWidth>
            </field>
            <field>
              <name>IM35</name>
              <bitOffset>3</bitOffset>
              <bitWidth>1</bitWidth>
            </field>
            <field>
              <name>IM36</name>
              <bitOffset>4</bitOffset>
              <bitWidth>1</bitWidth>
            </field>
            <field>
              <name>IM37</name>
              <bitOffset>5</bitOffset>
              <bitWidth>1</bitWidth>
            </field>
            <field>
              <name>IM38</name>
              <bitOffset>6</bitOffset>
              <bitWidth>1</bitWidth>
            </field>
            <field>
              <name>IM39</name>
              <bitOffset>7</bitOffset>
              <bitWidth>1</bitWidth>
            </field>
            <field>
              <name>IM40</name>
              <bitOffset>8</bitOffset>
              <bitWidth>1</bitWidth>
            </field>
            <field>
              <name>IM41</name>
              <bitOffset>9</bitOffset>
              <bitWidth>1</bitWidth>
            </field>
            <field>
              <name>IM42</name>
              <bitOffset>10</bitOffset>
              <bitWidth>1</bitWidth>
            </field>
            <field>
              <name>IM43</name>
              <bitOffset>11</bitOffset>
              <bitWidth>1</bitWidth>
            </field>
            <field>
              <name>IM44</name>
              <bitOffset>12</bitOffset>
              <bitWidth>1</bitWidth>
            </field>
            <field>
              <name>IM46</name>
              <bitOffset>14</bitOffset>
              <bitWidth>1</bitWidth>
            </field>
            <field>
              <name>IM47</name>
              <bitOffset>15</bitOffset>
              <bitWidth>1</bitWidth>
            </field>
            <field>
              <name>IM48</name>
              <bitOffset>16</bitOffset>
              <bitWidth>1</bitWidth>
            </field>
            <field>
              <name>IM49</name>
              <bitOffset>17</bitOffset>
              <bitWidth>1</bitWidth>
            </field>
            <field>
              <name>IM50</name>
              <bitOffset>18</bitOffset>
              <bitWidth>1</bitWidth>
            </field>
            <field>
              <name>IM51</name>
              <bitOffset>19</bitOffset>
              <bitWidth>1</bitWidth>
            </field>
            <field>
              <name>IM52</name>
              <bitOffset>20</bitOffset>
              <bitWidth>1</bitWidth>
            </field>
            <field>
              <name>IM53</name>
              <bitOffset>21</bitOffset>
              <bitWidth>1</bitWidth>
            </field>
            <field>
              <name>IM54</name>
              <bitOffset>22</bitOffset>
              <bitWidth>1</bitWidth>
            </field>
            <field>
              <name>IM55</name>
              <bitOffset>23</bitOffset>
              <bitWidth>1</bitWidth>
            </field>
            <field>
              <name>IM56</name>
              <bitOffset>24</bitOffset>
              <bitWidth>1</bitWidth>
            </field>
            <field>
              <name>IM57</name>
              <bitOffset>25</bitOffset>
              <bitWidth>1</bitWidth>
            </field>
            <field>
              <name>IM58</name>
              <bitOffset>26</bitOffset>
              <bitWidth>1</bitWidth>
            </field>
            <field>
              <name>IM59</name>
              <bitOffset>27</bitOffset>
              <bitWidth>1</bitWidth>
            </field>
            <field>
              <name>IM60</name>
              <bitOffset>28</bitOffset>
              <bitWidth>1</bitWidth>
            </field>
            <field>
              <name>IM61</name>
              <bitOffset>29</bitOffset>
              <bitWidth>1</bitWidth>
            </field>
            <field>
              <name>IM62</name>
              <bitOffset>30</bitOffset>
              <bitWidth>1</bitWidth>
            </field>
            <field>
              <name>IM63</name>
              <bitOffset>31</bitOffset>
              <bitWidth>1</bitWidth>
            </field>
          </fields>
        </register>
        <register>
          <name>EMR2</name>
          <addressOffset>0x94</addressOffset>
          <size>0x20</size>
          <fields>
            <field>
              <name>EM32</name>
              <bitOffset>0</bitOffset>
              <bitWidth>1</bitWidth>
            </field>
            <field>
              <name>EM33</name>
              <bitOffset>1</bitOffset>
              <bitWidth>1</bitWidth>
            </field>
            <field>
              <name>EM34</name>
              <bitOffset>2</bitOffset>
              <bitWidth>1</bitWidth>
            </field>
            <field>
              <name>EM35</name>
              <bitOffset>3</bitOffset>
              <bitWidth>1</bitWidth>
            </field>
            <field>
              <name>EM36</name>
              <bitOffset>4</bitOffset>
              <bitWidth>1</bitWidth>
            </field>
            <field>
              <name>EM37</name>
              <bitOffset>5</bitOffset>
              <bitWidth>1</bitWidth>
            </field>
            <field>
              <name>EM38</name>
              <bitOffset>6</bitOffset>
              <bitWidth>1</bitWidth>
            </field>
            <field>
              <name>EM39</name>
              <bitOffset>7</bitOffset>
              <bitWidth>1</bitWidth>
            </field>
            <field>
              <name>EM40</name>
              <bitOffset>8</bitOffset>
              <bitWidth>1</bitWidth>
            </field>
            <field>
              <name>EM41</name>
              <bitOffset>9</bitOffset>
              <bitWidth>1</bitWidth>
            </field>
            <field>
              <name>EM42</name>
              <bitOffset>10</bitOffset>
              <bitWidth>1</bitWidth>
            </field>
            <field>
              <name>EM43</name>
              <bitOffset>11</bitOffset>
              <bitWidth>1</bitWidth>
            </field>
            <field>
              <name>EM44</name>
              <bitOffset>12</bitOffset>
              <bitWidth>1</bitWidth>
            </field>
            <field>
              <name>EM46</name>
              <bitOffset>14</bitOffset>
              <bitWidth>1</bitWidth>
            </field>
            <field>
              <name>EM47</name>
              <bitOffset>15</bitOffset>
              <bitWidth>1</bitWidth>
            </field>
            <field>
              <name>EM48</name>
              <bitOffset>16</bitOffset>
              <bitWidth>1</bitWidth>
            </field>
            <field>
              <name>EM49</name>
              <bitOffset>17</bitOffset>
              <bitWidth>1</bitWidth>
            </field>
            <field>
              <name>EM50</name>
              <bitOffset>18</bitOffset>
              <bitWidth>1</bitWidth>
            </field>
            <field>
              <name>EM51</name>
              <bitOffset>19</bitOffset>
              <bitWidth>1</bitWidth>
            </field>
            <field>
              <name>EM52</name>
              <bitOffset>20</bitOffset>
              <bitWidth>1</bitWidth>
            </field>
            <field>
              <name>EM53</name>
              <bitOffset>21</bitOffset>
              <bitWidth>1</bitWidth>
            </field>
            <field>
              <name>EM54</name>
              <bitOffset>22</bitOffset>
              <bitWidth>1</bitWidth>
            </field>
            <field>
              <name>EM55</name>
              <bitOffset>23</bitOffset>
              <bitWidth>1</bitWidth>
            </field>
            <field>
              <name>EM56</name>
              <bitOffset>24</bitOffset>
              <bitWidth>1</bitWidth>
            </field>
            <field>
              <name>EM57</name>
              <bitOffset>25</bitOffset>
              <bitWidth>1</bitWidth>
            </field>
            <field>
              <name>EM58</name>
              <bitOffset>26</bitOffset>
              <bitWidth>1</bitWidth>
            </field>
            <field>
              <name>EM59</name>
              <bitOffset>27</bitOffset>
              <bitWidth>1</bitWidth>
            </field>
            <field>
              <name>EM60</name>
              <bitOffset>28</bitOffset>
              <bitWidth>1</bitWidth>
            </field>
            <field>
              <name>EM61</name>
              <bitOffset>29</bitOffset>
              <bitWidth>1</bitWidth>
            </field>
            <field>
              <name>EM62</name>
              <bitOffset>30</bitOffset>
              <bitWidth>1</bitWidth>
            </field>
            <field>
              <name>EM63</name>
              <bitOffset>31</bitOffset>
              <bitWidth>1</bitWidth>
            </field>
          </fields>
        </register>
        <register>
          <name>PR2</name>
          <addressOffset>0x98</addressOffset>
          <size>0x20</size>
          <fields>
            <field>
              <name>PR49</name>
              <bitOffset>17</bitOffset>
              <bitWidth>1</bitWidth>
            </field>
            <field>
              <name>PR51</name>
              <bitOffset>19</bitOffset>
              <bitWidth>1</bitWidth>
            </field>
          </fields>
        </register>
        <register>
          <name>IMR3</name>
          <addressOffset>0xa0</addressOffset>
          <size>0x20</size>
          <fields>
            <field>
              <name>IM64</name>
              <bitOffset>0</bitOffset>
              <bitWidth>1</bitWidth>
            </field>
            <field>
              <name>IM65</name>
              <bitOffset>1</bitOffset>
              <bitWidth>1</bitWidth>
            </field>
            <field>
              <name>IM66</name>
              <bitOffset>2</bitOffset>
              <bitWidth>1</bitWidth>
            </field>
            <field>
              <name>IM67</name>
              <bitOffset>3</bitOffset>
              <bitWidth>1</bitWidth>
            </field>
            <field>
              <name>IM68</name>
              <bitOffset>4</bitOffset>
              <bitWidth>1</bitWidth>
            </field>
            <field>
              <name>IM69</name>
              <bitOffset>5</bitOffset>
              <bitWidth>1</bitWidth>
            </field>
            <field>
              <name>IM70</name>
              <bitOffset>6</bitOffset>
              <bitWidth>1</bitWidth>
            </field>
            <field>
              <name>IM71</name>
              <bitOffset>7</bitOffset>
              <bitWidth>1</bitWidth>
            </field>
            <field>
              <name>IM72</name>
              <bitOffset>8</bitOffset>
              <bitWidth>1</bitWidth>
            </field>
            <field>
              <name>IM73</name>
              <bitOffset>9</bitOffset>
              <bitWidth>1</bitWidth>
            </field>
            <field>
              <name>IM74</name>
              <bitOffset>10</bitOffset>
              <bitWidth>1</bitWidth>
            </field>
            <field>
              <name>IM75</name>
              <bitOffset>11</bitOffset>
              <bitWidth>1</bitWidth>
            </field>
            <field>
              <name>IM76</name>
              <bitOffset>12</bitOffset>
              <bitWidth>1</bitWidth>
            </field>
            <field>
              <name>IM77</name>
              <bitOffset>13</bitOffset>
              <bitWidth>1</bitWidth>
            </field>
            <field>
              <name>IM78</name>
              <bitOffset>14</bitOffset>
              <bitWidth>1</bitWidth>
            </field>
            <field>
              <name>IM79</name>
              <bitOffset>15</bitOffset>
              <bitWidth>1</bitWidth>
            </field>
            <field>
              <name>IM80</name>
              <bitOffset>16</bitOffset>
              <bitWidth>1</bitWidth>
            </field>
            <field>
              <name>IM82</name>
              <bitOffset>18</bitOffset>
              <bitWidth>1</bitWidth>
            </field>
            <field>
              <name>IM84</name>
              <bitOffset>20</bitOffset>
              <bitWidth>1</bitWidth>
            </field>
            <field>
              <name>IM85</name>
              <bitOffset>21</bitOffset>
              <bitWidth>1</bitWidth>
            </field>
            <field>
              <name>IM86</name>
              <bitOffset>22</bitOffset>
              <bitWidth>1</bitWidth>
            </field>
            <field>
              <name>IM87</name>
              <bitOffset>23</bitOffset>
              <bitWidth>1</bitWidth>
            </field>
          </fields>
        </register>
        <register>
          <name>EMR3</name>
          <addressOffset>0xa4</addressOffset>
          <size>0x20</size>
          <fields>
            <field>
              <name>EM64</name>
              <bitOffset>0</bitOffset>
              <bitWidth>1</bitWidth>
            </field>
            <field>
              <name>EM65</name>
              <bitOffset>1</bitOffset>
              <bitWidth>1</bitWidth>
            </field>
            <field>
              <name>EM66</name>
              <bitOffset>2</bitOffset>
              <bitWidth>1</bitWidth>
            </field>
            <field>
              <name>EM67</name>
              <bitOffset>3</bitOffset>
              <bitWidth>1</bitWidth>
            </field>
            <field>
              <name>EM68</name>
              <bitOffset>4</bitOffset>
              <bitWidth>1</bitWidth>
            </field>
            <field>
              <name>EM69</name>
              <bitOffset>5</bitOffset>
              <bitWidth>1</bitWidth>
            </field>
            <field>
              <name>EM70</name>
              <bitOffset>6</bitOffset>
              <bitWidth>1</bitWidth>
            </field>
            <field>
              <name>EM71</name>
              <bitOffset>7</bitOffset>
              <bitWidth>1</bitWidth>
            </field>
            <field>
              <name>EM72</name>
              <bitOffset>8</bitOffset>
              <bitWidth>1</bitWidth>
            </field>
            <field>
              <name>EM73</name>
              <bitOffset>9</bitOffset>
              <bitWidth>1</bitWidth>
            </field>
            <field>
              <name>EM74</name>
              <bitOffset>10</bitOffset>
              <bitWidth>1</bitWidth>
            </field>
            <field>
              <name>EM75</name>
              <bitOffset>11</bitOffset>
              <bitWidth>1</bitWidth>
            </field>
            <field>
              <name>EM76</name>
              <bitOffset>12</bitOffset>
              <bitWidth>1</bitWidth>
            </field>
            <field>
              <name>EM77</name>
              <bitOffset>13</bitOffset>
              <bitWidth>1</bitWidth>
            </field>
            <field>
              <name>EM78</name>
              <bitOffset>14</bitOffset>
              <bitWidth>1</bitWidth>
            </field>
            <field>
              <name>EM79</name>
              <bitOffset>15</bitOffset>
              <bitWidth>1</bitWidth>
            </field>
            <field>
              <name>EM80</name>
              <bitOffset>16</bitOffset>
              <bitWidth>1</bitWidth>
            </field>
            <field>
              <name>EM81</name>
              <bitOffset>17</bitOffset>
              <bitWidth>1</bitWidth>
            </field>
            <field>
              <name>EM82</name>
              <bitOffset>18</bitOffset>
              <bitWidth>1</bitWidth>
            </field>
            <field>
              <name>EM84</name>
              <bitOffset>20</bitOffset>
              <bitWidth>1</bitWidth>
            </field>
            <field>
              <name>EM85</name>
              <bitOffset>21</bitOffset>
              <bitWidth>1</bitWidth>
            </field>
            <field>
              <name>EM86</name>
              <bitOffset>22</bitOffset>
              <bitWidth>1</bitWidth>
            </field>
            <field>
              <name>EM87</name>
              <bitOffset>23</bitOffset>
              <bitWidth>1</bitWidth>
            </field>
          </fields>
        </register>
        <register>
          <name>PR3</name>
          <addressOffset>0xa8</addressOffset>
          <size>0x20</size>
          <fields>
            <field>
              <name>PR82</name>
              <bitOffset>18</bitOffset>
              <bitWidth>1</bitWidth>
            </field>
            <field>
              <name>PR84</name>
              <bitOffset>20</bitOffset>
              <bitWidth>1</bitWidth>
            </field>
            <field>
              <name>PR85</name>
              <bitOffset>21</bitOffset>
              <bitWidth>1</bitWidth>
            </field>
            <field>
              <name>PR86</name>
              <bitOffset>22</bitOffset>
              <bitWidth>1</bitWidth>
            </field>
          </fields>
        </register>
        <register>
          <name>C2IMR1</name>
          <addressOffset>0xc0</addressOffset>
          <size>0x20</size>
        </register>
        <register>
          <name>C2EMR1</name>
          <addressOffset>0xc4</addressOffset>
          <size>0x20</size>
        </register>
        <register>
          <name>C2PR1</name>
          <addressOffset>0xc8</addressOffset>
          <size>0x20</size>
        </register>
        <register>
          <name>C2IMR2</name>
          <addressOffset>0xd0</addressOffset>
          <size>0x20</size>
        </register>
        <register>
          <name>C2EMR2</name>
          <addressOffset>0xd4</addressOffset>
          <size>0x20</size>
        </register>
        <register>
          <name>C2PR2</name>
          <addressOffset>0xd8</addressOffset>
          <size>0x20</size>
        </register>
        <register>
          <name>C2IMR3</name>
          <addressOffset>0xe0</addressOffset>
          <size>0x20</size>
        </register>
        <register>
          <name>C2EMR3</name>
          <addressOffset>0xe4</addressOffset>
          <size>0x20</size>
        </register>
        <register>
          <name>C2PR3</name>
          <addressOffset>0xe8</addressOffset>
          <size>0x20</size>
        </register>
      </registers>
    </peripheral>
    <peripheral>
      <name>EXTI_D1</name>
      <baseAddress>0x58000080</baseAddress>
      <registers>
        <register>
          <name>IMR1</name>
          <addressOffset>0x0</addressOffset>
          <size>0x20</size>
          <fields>
            <field>
              <name>IM0</name>
              <bitOffset>0</bitOffset>
              <bitWidth>1</bitWidth>
            </field>
            <field>
              <name>IM1</name>
              <bitOffset>1</bitOffset>
              <bitWidth>1</bitWidth>
            </field>
            <field>
              <name>IM2</name>
              <bitOffset>2</bitOffset>
              <bitWidth>1</bitWidth>
            </field>
            <field>
              <name>IM3</name>
              <bitOffset>3</bitOffset>
              <bitWidth>1</bitWidth>
            </field>
            <field>
              <name>IM4</name>
              <bitOffset>4</bitOffset>
              <bitWidth>1</bitWidth>
            </field>
            <field>
              <name>IM5</name>
              <bitOffset>5</bitOffset>
              <bitWidth>1</bitWidth>
            </field>
            <field>
              <name>IM6</name>
              <bitOffset>6</bitOffset>
              <bitWidth>1</bitWidth>
            </field>
            <field>
              <name>IM7</name>
              <bitOffset>7</bitOffset>
              <bitWidth>1</bitWidth>
            </field>
            <field>
              <name>IM8</name>
              <bitOffset>8</bitOffset>
              <bitWidth>1</bitWidth>
            </field>
            <field>
              <name>IM9</name>
              <bitOffset>9</bitOffset>
              <bitWidth>1</bitWidth>
            </field>
            <field>
              <name>IM10</name>
              <bitOffset>10</bitOffset>
              <bitWidth>1</bitWidth>
            </field>
            <field>
              <name>IM11</name>
              <bitOffset>11</bitOffset>
              <bitWidth>1</bitWidth>
            </field>
            <field>
              <name>IM12</name>
              <bitOffset>12</bitOffset>
              <bitWidth>1</bitWidth>
            </field>
            <field>
              <name>IM13</name>
              <bitOffset>13</bitOffset>
              <bitWidth>1</bitWidth>
            </field>
            <field>
              <name>IM14</name>
              <bitOffset>14</bitOffset>
              <bitWidth>1</bitWidth>
            </field>
            <field>
              <name>IM15</name>
              <bitOffset>15</bitOffset>
              <bitWidth>1</bitWidth>
            </field>
            <field>
              <name>IM16</name>
              <bitOffset>16</bitOffset>
              <bitWidth>1</bitWidth>
            </field>
            <field>
              <name>IM17</name>
              <bitOffset>17</bitOffset>
              <bitWidth>1</bitWidth>
            </field>
            <field>
              <name>IM18</name>
              <bitOffset>18</bitOffset>
              <bitWidth>1</bitWidth>
            </field>
            <field>
              <name>IM19</name>
              <bitOffset>19</bitOffset>
              <bitWidth>1</bitWidth>
            </field>
            <field>
              <name>IM20</name>
              <bitOffset>20</bitOffset>
              <bitWidth>1</bitWidth>
            </field>
            <field>
              <name>IM21</name>
              <bitOffset>21</bitOffset>
              <bitWidth>1</bitWidth>
            </field>
            <field>
              <name>IM22</name>
              <bitOffset>22</bitOffset>
              <bitWidth>1</bitWidth>
            </field>
            <field>
              <name>IM23</name>
              <bitOffset>23</bitOffset>
              <bitWidth>1</bitWidth>
            </field>
            <field>
              <name>IM24</name>
              <bitOffset>24</bitOffset>
              <bitWidth>1</bitWidth>
            </field>
            <field>
              <name>IM25</name>
              <bitOffset>25</bitOffset>
              <bitWidth>1</bitWidth>
            </field>
            <field>
              <name>IM26</name>
              <bitOffset>26</bitOffset>
              <bitWidth>1</bitWidth>
            </field>
            <field>
              <name>IM27</name>
              <bitOffset>27</bitOffset>
              <bitWidth>1</bitWidth>
            </field>
            <field>
              <name>IM28</name>
              <bitOffset>28</bitOffset>
              <bitWidth>1</bitWidth>
            </field>
            <field>
              <name>IM29</name>
              <bitOffset>29</bitOffset>
              <bitWidth>1</bitWidth>
            </field>
            <field>
              <name>IM30</name>
              <bitOffset>30</bitOffset>
              <bitWidth>1</bitWidth>
            </field>
            <field>
              <name>IM31</name>
              <bitOffset>31</bitOffset>
              <bitWidth>1</bitWidth>
            </field>
          </fields>
        </register>
        <register>
          <name>EMR1</name>
          <addressOffset>0x4</addressOffset>
          <size>0x20</size>
          <fields>
            <field>
              <name>EM0</name>
              <bitOffset>0</bitOffset>
              <bitWidth>1</bitWidth>
            </field>
            <field>
              <name>EM1</name>
              <bitOffset>1</bitOffset>
              <bitWidth>1</bitWidth>
            </field>
            <field>
              <name>EM2</name>
              <bitOffset>2</bitOffset>
              <bitWidth>1</bitWidth>
            </field>
            <field>
              <name>EM3</name>
              <bitOffset>3</bitOffset>
              <bitWidth>1</bitWidth>
            </field>
            <field>
              <name>EM4</name>
              <bitOffset>4</bitOffset>
              <bitWidth>1</bitWidth>
            </field>
            <field>
              <name>EM5</name>
              <bitOffset>5</bitOffset>
              <bitWidth>1</bitWidth>
            </field>
            <field>
              <name>EM6</name>
              <bitOffset>6</bitOffset>
              <bitWidth>1</bitWidth>
            </field>
            <field>
              <name>EM7</name>
              <bitOffset>7</bitOffset>
              <bitWidth>1</bitWidth>
            </field>
            <field>
              <name>EM8</name>
              <bitOffset>8</bitOffset>
              <bitWidth>1</bitWidth>
            </field>
            <field>
              <name>EM9</name>
              <bitOffset>9</bitOffset>
              <bitWidth>1</bitWidth>
            </field>
            <field>
              <name>EM10</name>
              <bitOffset>10</bitOffset>
              <bitWidth>1</bitWidth>
            </field>
            <field>
              <name>EM11</name>
              <bitOffset>11</bitOffset>
              <bitWidth>1</bitWidth>
            </field>
            <field>
              <name>EM12</name>
              <bitOffset>12</bitOffset>
              <bitWidth>1</bitWidth>
            </field>
            <field>
              <name>EM13</name>
              <bitOffset>13</bitOffset>
              <bitWidth>1</bitWidth>
            </field>
            <field>
              <name>EM14</name>
              <bitOffset>14</bitOffset>
              <bitWidth>1</bitWidth>
            </field>
            <field>
              <name>EM15</name>
              <bitOffset>15</bitOffset>
              <bitWidth>1</bitWidth>
            </field>
            <field>
              <name>EM16</name>
              <bitOffset>16</bitOffset>
              <bitWidth>1</bitWidth>
            </field>
            <field>
              <name>EM17</name>
              <bitOffset>17</bitOffset>
              <bitWidth>1</bitWidth>
            </field>
            <field>
              <name>EM18</name>
              <bitOffset>18</bitOffset>
              <bitWidth>1</bitWidth>
            </field>
            <field>
              <name>EM20</name>
              <bitOffset>20</bitOffset>
              <bitWidth>1</bitWidth>
            </field>
            <field>
              <name>EM21</name>
              <bitOffset>21</bitOffset>
              <bitWidth>1</bitWidth>
            </field>
            <field>
              <name>EM22</name>
              <bitOffset>22</bitOffset>
              <bitWidth>1</bitWidth>
            </field>
            <field>
              <name>EM23</name>
              <bitOffset>23</bitOffset>
              <bitWidth>1</bitWidth>
            </field>
            <field>
              <name>EM24</name>
              <bitOffset>24</bitOffset>
              <bitWidth>1</bitWidth>
            </field>
            <field>
              <name>EM25</name>
              <bitOffset>25</bitOffset>
              <bitWidth>1</bitWidth>
            </field>
            <field>
              <name>EM26</name>
              <bitOffset>26</bitOffset>
              <bitWidth>1</bitWidth>
            </field>
            <field>
              <name>EM27</name>
              <bitOffset>27</bitOffset>
              <bitWidth>1</bitWidth>
            </field>
            <field>
              <name>EM28</name>
              <bitOffset>28</bitOffset>
              <bitWidth>1</bitWidth>
            </field>
            <field>
              <name>EM29</name>
              <bitOffset>29</bitOffset>
              <bitWidth>1</bitWidth>
            </field>
            <field>
              <name>EM30</name>
              <bitOffset>30</bitOffset>
              <bitWidth>1</bitWidth>
            </field>
            <field>
              <name>EM31</name>
              <bitOffset>31</bitOffset>
              <bitWidth>1</bitWidth>
            </field>
          </fields>
        </register>
        <register>
          <name>PR1</name>
          <addressOffset>0x8</addressOffset>
          <size>0x20</size>
          <fields>
            <field>
              <name>PR0</name>
              <bitOffset>0</bitOffset>
              <bitWidth>1</bitWidth>
            </field>
            <field>
              <name>PR1</name>
              <bitOffset>1</bitOffset>
              <bitWidth>1</bitWidth>
            </field>
            <field>
              <name>PR2</name>
              <bitOffset>2</bitOffset>
              <bitWidth>1</bitWidth>
            </field>
            <field>
              <name>PR3</name>
              <bitOffset>3</bitOffset>
              <bitWidth>1</bitWidth>
            </field>
            <field>
              <name>PR4</name>
              <bitOffset>4</bitOffset>
              <bitWidth>1</bitWidth>
            </field>
            <field>
              <name>PR5</name>
              <bitOffset>5</bitOffset>
              <bitWidth>1</bitWidth>
            </field>
            <field>
              <name>PR6</name>
              <bitOffset>6</bitOffset>
              <bitWidth>1</bitWidth>
            </field>
            <field>
              <name>PR7</name>
              <bitOffset>7</bitOffset>
              <bitWidth>1</bitWidth>
            </field>
            <field>
              <name>PR8</name>
              <bitOffset>8</bitOffset>
              <bitWidth>1</bitWidth>
            </field>
            <field>
              <name>PR9</name>
              <bitOffset>9</bitOffset>
              <bitWidth>1</bitWidth>
            </field>
            <field>
              <name>PR10</name>
              <bitOffset>10</bitOffset>
              <bitWidth>1</bitWidth>
            </field>
            <field>
              <name>PR11</name>
              <bitOffset>11</bitOffset>
              <bitWidth>1</bitWidth>
            </field>
            <field>
              <name>PR12</name>
              <bitOffset>12</bitOffset>
              <bitWidth>1</bitWidth>
            </field>
            <field>
              <name>PR13</name>
              <bitOffset>13</bitOffset>
              <bitWidth>1</bitWidth>
            </field>
            <field>
              <name>PR14</name>
              <bitOffset>14</bitOffset>
              <bitWidth>1</bitWidth>
            </field>
            <field>
              <name>PR15</name>
              <bitOffset>15</bitOffset>
              <bitWidth>1</bitWidth>
            </field>
            <field>
              <name>PR16</name>
              <bitOffset>16</bitOffset>
              <bitWidth>1</bitWidth>
            </field>
            <field>
              <name>PR17</name>
              <bitOffset>17</bitOffset>
              <bitWidth>1</bitWidth>
            </field>
            <field>
              <name>PR18</name>
              <bitOffset>18</bitOffset>
              <bitWidth>1</bitWidth>
            </field>
            <field>
              <name>PR19</name>
              <bitOffset>19</bitOffset>
              <bitWidth>1</bitWidth>
            </field>
            <field>
              <name>PR20</name>
              <bitOffset>20</bitOffset>
              <bitWidth>1</bitWidth>
            </field>
            <field>
              <name>PR21</name>
              <bitOffset>21</bitOffset>
              <bitWidth>1</bitWidth>
            </field>
          </fields>
        </register>
        <register>
          <name>IMR2</name>
          <addressOffset>0x10</addressOffset>
          <size>0x20</size>
          <fields>
            <field>
              <name>IM32</name>
              <bitOffset>0</bitOffset>
              <bitWidth>1</bitWidth>
            </field>
            <field>
              <name>IM33</name>
              <bitOffset>1</bitOffset>
              <bitWidth>1</bitWidth>
            </field>
            <field>
              <name>IM34</name>
              <bitOffset>2</bitOffset>
              <bitWidth>1</bitWidth>
            </field>
            <field>
              <name>IM35</name>
              <bitOffset>3</bitOffset>
              <bitWidth>1</bitWidth>
            </field>
            <field>
              <name>IM36</name>
              <bitOffset>4</bitOffset>
              <bitWidth>1</bitWidth>
            </field>
            <field>
              <name>IM37</name>
              <bitOffset>5</bitOffset>
              <bitWidth>1</bitWidth>
            </field>
            <field>
              <name>IM38</name>
              <bitOffset>6</bitOffset>
              <bitWidth>1</bitWidth>
            </field>
            <field>
              <name>IM39</name>
              <bitOffset>7</bitOffset>
              <bitWidth>1</bitWidth>
            </field>
            <field>
              <name>IM40</name>
              <bitOffset>8</bitOffset>
              <bitWidth>1</bitWidth>
            </field>
            <field>
              <name>IM41</name>
              <bitOffset>9</bitOffset>
              <bitWidth>1</bitWidth>
            </field>
            <field>
              <name>IM42</name>
              <bitOffset>10</bitOffset>
              <bitWidth>1</bitWidth>
            </field>
            <field>
              <name>IM43</name>
              <bitOffset>11</bitOffset>
              <bitWidth>1</bitWidth>
            </field>
            <field>
              <name>IM44</name>
              <bitOffset>12</bitOffset>
              <bitWidth>1</bitWidth>
            </field>
            <field>
              <name>IM46</name>
              <bitOffset>14</bitOffset>
              <bitWidth>1</bitWidth>
            </field>
            <field>
              <name>IM47</name>
              <bitOffset>15</bitOffset>
              <bitWidth>1</bitWidth>
            </field>
            <field>
              <name>IM48</name>
              <bitOffset>16</bitOffset>
              <bitWidth>1</bitWidth>
            </field>
            <field>
              <name>IM49</name>
              <bitOffset>17</bitOffset>
              <bitWidth>1</bitWidth>
            </field>
            <field>
              <name>IM50</name>
              <bitOffset>18</bitOffset>
              <bitWidth>1</bitWidth>
            </field>
            <field>
              <name>IM51</name>
              <bitOffset>19</bitOffset>
              <bitWidth>1</bitWidth>
            </field>
            <field>
              <name>IM52</name>
              <bitOffset>20</bitOffset>
              <bitWidth>1</bitWidth>
            </field>
            <field>
              <name>IM53</name>
              <bitOffset>21</bitOffset>
              <bitWidth>1</bitWidth>
            </field>
            <field>
              <name>IM54</name>
              <bitOffset>22</bitOffset>
              <bitWidth>1</bitWidth>
            </field>
            <field>
              <name>IM55</name>
              <bitOffset>23</bitOffset>
              <bitWidth>1</bitWidth>
            </field>
            <field>
              <name>IM56</name>
              <bitOffset>24</bitOffset>
              <bitWidth>1</bitWidth>
            </field>
            <field>
              <name>IM57</name>
              <bitOffset>25</bitOffset>
              <bitWidth>1</bitWidth>
            </field>
            <field>
              <name>IM58</name>
              <bitOffset>26</bitOffset>
              <bitWidth>1</bitWidth>
            </field>
            <field>
              <name>IM59</name>
              <bitOffset>27</bitOffset>
              <bitWidth>1</bitWidth>
            </field>
            <field>
              <name>IM60</name>
              <bitOffset>28</bitOffset>
              <bitWidth>1</bitWidth>
            </field>
            <field>
              <name>IM61</name>
              <bitOffset>29</bitOffset>
              <bitWidth>1</bitWidth>
            </field>
            <field>
              <name>IM62</name>
              <bitOffset>30</bitOffset>
              <bitWidth>1</bitWidth>
            </field>
            <field>
              <name>IM63</name>
              <bitOffset>31</bitOffset>
              <bitWidth>1</bitWidth>
            </field>
          </fields>
        </register>
        <register>
          <name>EMR2</name>
          <addressOffset>0x14</addressOffset>
          <size>0x20</size>
          <fields>
            <field>
              <name>EM32</name>
              <bitOffset>0</bitOffset>
              <bitWidth>1</bitWidth>
            </field>
            <field>
              <name>EM33</name>
              <bitOffset>1</bitOffset>
              <bitWidth>1</bitWidth>
            </field>
            <field>
              <name>EM34</name>
              <bitOffset>2</bitOffset>
              <bitWidth>1</bitWidth>
            </field>
            <field>
              <name>EM35</name>
              <bitOffset>3</bitOffset>
              <bitWidth>1</bitWidth>
            </field>
            <field>
              <name>EM36</name>
              <bitOffset>4</bitOffset>
              <bitWidth>1</bitWidth>
            </field>
            <field>
              <name>EM37</name>
              <bitOffset>5</bitOffset>
              <bitWidth>1</bitWidth>
            </field>
            <field>
              <name>EM38</name>
              <bitOffset>6</bitOffset>
              <bitWidth>1</bitWidth>
            </field>
            <field>
              <name>EM39</name>
              <bitOffset>7</bitOffset>
              <bitWidth>1</bitWidth>
            </field>
            <field>
              <name>EM40</name>
              <bitOffset>8</bitOffset>
              <bitWidth>1</bitWidth>
            </field>
            <field>
              <name>EM41</name>
              <bitOffset>9</bitOffset>
              <bitWidth>1</bitWidth>
            </field>
            <field>
              <name>EM42</name>
              <bitOffset>10</bitOffset>
              <bitWidth>1</bitWidth>
            </field>
            <field>
              <name>EM43</name>
              <bitOffset>11</bitOffset>
              <bitWidth>1</bitWidth>
            </field>
            <field>
              <name>EM44</name>
              <bitOffset>12</bitOffset>
              <bitWidth>1</bitWidth>
            </field>
            <field>
              <name>EM46</name>
              <bitOffset>14</bitOffset>
              <bitWidth>1</bitWidth>
            </field>
            <field>
              <name>EM47</name>
              <bitOffset>15</bitOffset>
              <bitWidth>1</bitWidth>
            </field>
            <field>
              <name>EM48</name>
              <bitOffset>16</bitOffset>
              <bitWidth>1</bitWidth>
            </field>
            <field>
              <name>EM49</name>
              <bitOffset>17</bitOffset>
              <bitWidth>1</bitWidth>
            </field>
            <field>
              <name>EM50</name>
              <bitOffset>18</bitOffset>
              <bitWidth>1</bitWidth>
            </field>
            <field>
              <name>EM51</name>
              <bitOffset>19</bitOffset>
              <bitWidth>1</bitWidth>
            </field>
            <field>
              <name>EM52</name>
              <bitOffset>20</bitOffset>
              <bitWidth>1</bitWidth>
            </field>
            <field>
              <name>EM53</name>
              <bitOffset>21</bitOffset>
              <bitWidth>1</bitWidth>
            </field>
            <field>
              <name>EM54</name>
              <bitOffset>22</bitOffset>
              <bitWidth>1</bitWidth>
            </field>
            <field>
              <name>EM55</name>
              <bitOffset>23</bitOffset>
              <bitWidth>1</bitWidth>
            </field>
            <field>
              <name>EM56</name>
              <bitOffset>24</bitOffset>
              <bitWidth>1</bitWidth>
            </field>
            <field>
              <name>EM57</name>
              <bitOffset>25</bitOffset>
              <bitWidth>1</bitWidth>
            </field>
            <field>
              <name>EM58</name>
              <bitOffset>26</bitOffset>
              <bitWidth>1</bitWidth>
            </field>
            <field>
              <name>EM59</name>
              <bitOffset>27</bitOffset>
              <bitWidth>1</bitWidth>
            </field>
            <field>
              <name>EM60</name>
              <bitOffset>28</bitOffset>
              <bitWidth>1</bitWidth>
            </field>
            <field>
              <name>EM61</name>
              <bitOffset>29</bitOffset>
              <bitWidth>1</bitWidth>
            </field>
            <field>
              <name>EM62</name>
              <bitOffset>30</bitOffset>
              <bitWidth>1</bitWidth>
            </field>
            <field>
              <name>EM63</name>
              <bitOffset>31</bitOffset>
              <bitWidth>1</bitWidth>
            </field>
          </fields>
        </register>
        <register>
          <name>PR2</name>
          <addressOffset>0x18</addressOffset>
          <size>0x20</size>
          <fields>
            <field>
              <name>PR49</name>
              <bitOffset>17</bitOffset>
              <bitWidth>1</bitWidth>
            </field>
            <field>
              <name>PR51</name>
              <bitOffset>19</bitOffset>
              <bitWidth>1</bitWidth>
            </field>
          </fields>
        </register>
        <register>
          <name>IMR3</name>
          <addressOffset>0x20</addressOffset>
          <size>0x20</size>
          <fields>
            <field>
              <name>IM64</name>
              <bitOffset>0</bitOffset>
              <bitWidth>1</bitWidth>
            </field>
            <field>
              <name>IM65</name>
              <bitOffset>1</bitOffset>
              <bitWidth>1</bitWidth>
            </field>
            <field>
              <name>IM66</name>
              <bitOffset>2</bitOffset>
              <bitWidth>1</bitWidth>
            </field>
            <field>
              <name>IM67</name>
              <bitOffset>3</bitOffset>
              <bitWidth>1</bitWidth>
            </field>
            <field>
              <name>IM68</name>
              <bitOffset>4</bitOffset>
              <bitWidth>1</bitWidth>
            </field>
            <field>
              <name>IM69</name>
              <bitOffset>5</bitOffset>
              <bitWidth>1</bitWidth>
            </field>
            <field>
              <name>IM70</name>
              <bitOffset>6</bitOffset>
              <bitWidth>1</bitWidth>
            </field>
            <field>
              <name>IM71</name>
              <bitOffset>7</bitOffset>
              <bitWidth>1</bitWidth>
            </field>
            <field>
              <name>IM72</name>
              <bitOffset>8</bitOffset>
              <bitWidth>1</bitWidth>
            </field>
            <field>
              <name>IM73</name>
              <bitOffset>9</bitOffset>
              <bitWidth>1</bitWidth>
            </field>
            <field>
              <name>IM74</name>
              <bitOffset>10</bitOffset>
              <bitWidth>1</bitWidth>
            </field>
            <field>
              <name>IM75</name>
              <bitOffset>11</bitOffset>
              <bitWidth>1</bitWidth>
            </field>
            <field>
              <name>IM76</name>
              <bitOffset>12</bitOffset>
              <bitWidth>1</bitWidth>
            </field>
            <field>
              <name>IM77</name>
              <bitOffset>13</bitOffset>
              <bitWidth>1</bitWidth>
            </field>
            <field>
              <name>IM78</name>
              <bitOffset>14</bitOffset>
              <bitWidth>1</bitWidth>
            </field>
            <field>
              <name>IM79</name>
              <bitOffset>15</bitOffset>
              <bitWidth>1</bitWidth>
            </field>
            <field>
              <name>IM80</name>
              <bitOffset>16</bitOffset>
              <bitWidth>1</bitWidth>
            </field>
            <field>
              <name>IM82</name>
              <bitOffset>18</bitOffset>
              <bitWidth>1</bitWidth>
            </field>
            <field>
              <name>IM84</name>
              <bitOffset>20</bitOffset>
              <bitWidth>1</bitWidth>
            </field>
            <field>
              <name>IM85</name>
              <bitOffset>21</bitOffset>
              <bitWidth>1</bitWidth>
            </field>
            <field>
              <name>IM86</name>
              <bitOffset>22</bitOffset>
              <bitWidth>1</bitWidth>
            </field>
            <field>
              <name>IM87</name>
              <bitOffset>23</bitOffset>
              <bitWidth>1</bitWidth>
            </field>
          </fields>
        </register>
        <register>
          <name>EMR3</name>
          <addressOffset>0x24</addressOffset>
          <size>0x20</size>
          <fields>
            <field>
              <name>EM64</name>
              <bitOffset>0</bitOffset>
              <bitWidth>1</bitWidth>
            </field>
            <field>
              <name>EM65</name>
              <bitOffset>1</bitOffset>
              <bitWidth>1</bitWidth>
            </field>
            <field>
              <name>EM66</name>
              <bitOffset>2</bitOffset>
              <bitWidth>1</bitWidth>
            </field>
            <field>
              <name>EM67</name>
              <bitOffset>3</bitOffset>
              <bitWidth>1</bitWidth>
            </field>
            <field>
              <name>EM68</name>
              <bitOffset>4</bitOffset>
              <bitWidth>1</bitWidth>
            </field>
            <field>
              <name>EM69</name>
              <bitOffset>5</bitOffset>
              <bitWidth>1</bitWidth>
            </field>
            <field>
              <name>EM70</name>
              <bitOffset>6</bitOffset>
              <bitWidth>1</bitWidth>
            </field>
            <field>
              <name>EM71</name>
              <bitOffset>7</bitOffset>
              <bitWidth>1</bitWidth>
            </field>
            <field>
              <name>EM72</name>
              <bitOffset>8</bitOffset>
              <bitWidth>1</bitWidth>
            </field>
            <field>
              <name>EM73</name>
              <bitOffset>9</bitOffset>
              <bitWidth>1</bitWidth>
            </field>
            <field>
              <name>EM74</name>
              <bitOffset>10</bitOffset>
              <bitWidth>1</bitWidth>
            </field>
            <field>
              <name>EM75</name>
              <bitOffset>11</bitOffset>
              <bitWidth>1</bitWidth>
            </field>
            <field>
              <name>EM76</name>
              <bitOffset>12</bitOffset>
              <bitWidth>1</bitWidth>
            </field>
            <field>
              <name>EM77</name>
              <bitOffset>13</bitOffset>
              <bitWidth>1</bitWidth>
            </field>
            <field>
              <name>EM78</name>
              <bitOffset>14</bitOffset>
              <bitWidth>1</bitWidth>
            </field>
            <field>
              <name>EM79</name>
              <bitOffset>15</bitOffset>
              <bitWidth>1</bitWidth>
            </field>
            <field>
              <name>EM80</name>
              <bitOffset>16</bitOffset>
              <bitWidth>1</bitWidth>
            </field>
            <field>
              <name>EM81</name>
              <bitOffset>17</bitOffset>
              <bitWidth>1</bitWidth>
            </field>
            <field>
              <name>EM82</name>
              <bitOffset>18</bitOffset>
              <bitWidth>1</bitWidth>
            </field>
            <field>
              <name>EM84</name>
              <bitOffset>20</bitOffset>
              <bitWidth>1</bitWidth>
            </field>
            <field>
              <name>EM85</name>
              <bitOffset>21</bitOffset>
              <bitWidth>1</bitWidth>
            </field>
            <field>
              <name>EM86</name>
              <bitOffset>22</bitOffset>
              <bitWidth>1</bitWidth>
            </field>
            <field>
              <name>EM87</name>
              <bitOffset>23</bitOffset>
              <bitWidth>1</bitWidth>
            </field>
          </fields>
        </register>
        <register>
          <name>PR3</name>
          <addressOffset>0x28</addressOffset>
          <size>0x20</size>
          <fields>
            <field>
              <name>PR82</name>
              <bitOffset>18</bitOffset>
              <bitWidth>1</bitWidth>
            </field>
            <field>
              <name>PR84</name>
              <bitOffset>20</bitOffset>
              <bitWidth>1</bitWidth>
            </field>
            <field>
              <name>PR85</name>
              <bitOffset>21</bitOffset>
              <bitWidth>1</bitWidth>
            </field>
            <field>
              <name>PR86</name>
              <bitOffset>22</bitOffset>
              <bitWidth>1</bitWidth>
            </field>
          </fields>
        </register>
      </registers>
    </peripheral>
    <peripheral>
      <name>EXTI_D2</name>
      <baseAddress>0x580000c0</baseAddress>
      <registers>
        <register>
          <name>IMR1</name>
          <addressOffset>0x0</addressOffset>
          <size>0x20</size>
          <fields>
            <field>
              <name>IM0</name>
              <bitOffset>0</bitOffset>
              <bitWidth>1</bitWidth>
            </field>
            <field>
              <name>IM1</name>
              <bitOffset>1</bitOffset>
              <bitWidth>1</bitWidth>
            </field>
            <field>
              <name>IM2</name>
              <bitOffset>2</bitOffset>
              <bitWidth>1</bitWidth>
            </field>
            <field>
              <name>IM3</name>
              <bitOffset>3</bitOffset>
              <bitWidth>1</bitWidth>
            </field>
            <field>
              <name>IM4</name>
              <bitOffset>4</bitOffset>
              <bitWidth>1</bitWidth>
            </field>
            <field>
              <name>IM5</name>
              <bitOffset>5</bitOffset>
              <bitWidth>1</bitWidth>
            </field>
            <field>
              <name>IM6</name>
              <bitOffset>6</bitOffset>
              <bitWidth>1</bitWidth>
            </field>
            <field>
              <name>IM7</name>
              <bitOffset>7</bitOffset>
              <bitWidth>1</bitWidth>
            </field>
            <field>
              <name>IM8</name>
              <bitOffset>8</bitOffset>
              <bitWidth>1</bitWidth>
            </field>
            <field>
              <name>IM9</name>
              <bitOffset>9</bitOffset>
              <bitWidth>1</bitWidth>
            </field>
            <field>
              <name>IM10</name>
              <bitOffset>10</bitOffset>
              <bitWidth>1</bitWidth>
            </field>
            <field>
              <name>IM11</name>
              <bitOffset>11</bitOffset>
              <bitWidth>1</bitWidth>
            </field>
            <field>
              <name>IM12</name>
              <bitOffset>12</bitOffset>
              <bitWidth>1</bitWidth>
            </field>
            <field>
              <name>IM13</name>
              <bitOffset>13</bitOffset>
              <bitWidth>1</bitWidth>
            </field>
            <field>
              <name>IM14</name>
              <bitOffset>14</bitOffset>
              <bitWidth>1</bitWidth>
            </field>
            <field>
              <name>IM15</name>
              <bitOffset>15</bitOffset>
              <bitWidth>1</bitWidth>
            </field>
            <field>
              <name>IM16</name>
              <bitOffset>16</bitOffset>
              <bitWidth>1</bitWidth>
            </field>
            <field>
              <name>IM17</name>
              <bitOffset>17</bitOffset>
              <bitWidth>1</bitWidth>
            </field>
            <field>
              <name>IM18</name>
              <bitOffset>18</bitOffset>
              <bitWidth>1</bitWidth>
            </field>
            <field>
              <name>IM19</name>
              <bitOffset>19</bitOffset>
              <bitWidth>1</bitWidth>
            </field>
            <field>
              <name>IM20</name>
              <bitOffset>20</bitOffset>
              <bitWidth>1</bitWidth>
            </field>
            <field>
              <name>IM21</name>
              <bitOffset>21</bitOffset>
              <bitWidth>1</bitWidth>
            </field>
            <field>
              <name>IM22</name>
              <bitOffset>22</bitOffset>
              <bitWidth>1</bitWidth>
            </field>
            <field>
              <name>IM23</name>
              <bitOffset>23</bitOffset>
              <bitWidth>1</bitWidth>
            </field>
            <field>
              <name>IM24</name>
              <bitOffset>24</bitOffset>
              <bitWidth>1</bitWidth>
            </field>
            <field>
              <name>IM25</name>
              <bitOffset>25</bitOffset>
              <bitWidth>1</bitWidth>
            </field>
            <field>
              <name>IM26</name>
              <bitOffset>26</bitOffset>
              <bitWidth>1</bitWidth>
            </field>
            <field>
              <name>IM27</name>
              <bitOffset>27</bitOffset>
              <bitWidth>1</bitWidth>
            </field>
            <field>
              <name>IM28</name>
              <bitOffset>28</bitOffset>
              <bitWidth>1</bitWidth>
            </field>
            <field>
              <name>IM29</name>
              <bitOffset>29</bitOffset>
              <bitWidth>1</bitWidth>
            </field>
            <field>
              <name>IM30</name>
              <bitOffset>30</bitOffset>
              <bitWidth>1</bitWidth>
            </field>
            <field>
              <name>IM31</name>
              <bitOffset>31</bitOffset>
              <bitWidth>1</bitWidth>
            </field>
          </fields>
        </register>
        <register>
          <name>EMR1</name>
          <addressOffset>0x4</addressOffset>
          <size>0x20</size>
          <fields>
            <field>
              <name>EM0</name>
              <bitOffset>0</bitOffset>
              <bitWidth>1</bitWidth>
            </field>
            <field>
              <name>EM1</name>
              <bitOffset>1</bitOffset>
              <bitWidth>1</bitWidth>
            </field>
            <field>
              <name>EM2</name>
              <bitOffset>2</bitOffset>
              <bitWidth>1</bitWidth>
            </field>
            <field>
              <name>EM3</name>
              <bitOffset>3</bitOffset>
              <bitWidth>1</bitWidth>
            </field>
            <field>
              <name>EM4</name>
              <bitOffset>4</bitOffset>
              <bitWidth>1</bitWidth>
            </field>
            <field>
              <name>EM5</name>
              <bitOffset>5</bitOffset>
              <bitWidth>1</bitWidth>
            </field>
            <field>
              <name>EM6</name>
              <bitOffset>6</bitOffset>
              <bitWidth>1</bitWidth>
            </field>
            <field>
              <name>EM7</name>
              <bitOffset>7</bitOffset>
              <bitWidth>1</bitWidth>
            </field>
            <field>
              <name>EM8</name>
              <bitOffset>8</bitOffset>
              <bitWidth>1</bitWidth>
            </field>
            <field>
              <name>EM9</name>
              <bitOffset>9</bitOffset>
              <bitWidth>1</bitWidth>
            </field>
            <field>
              <name>EM10</name>
              <bitOffset>10</bitOffset>
              <bitWidth>1</bitWidth>
            </field>
            <field>
              <name>EM11</name>
              <bitOffset>11</bitOffset>
              <bitWidth>1</bitWidth>
            </field>
            <field>
              <name>EM12</name>
              <bitOffset>12</bitOffset>
              <bitWidth>1</bitWidth>
            </field>
            <field>
              <name>EM13</name>
              <bitOffset>13</bitOffset>
              <bitWidth>1</bitWidth>
            </field>
            <field>
              <name>EM14</name>
              <bitOffset>14</bitOffset>
              <bitWidth>1</bitWidth>
            </field>
            <field>
              <name>EM15</name>
              <bitOffset>15</bitOffset>
              <bitWidth>1</bitWidth>
            </field>
            <field>
              <name>EM16</name>
              <bitOffset>16</bitOffset>
              <bitWidth>1</bitWidth>
            </field>
            <field>
              <name>EM17</name>
              <bitOffset>17</bitOffset>
              <bitWidth>1</bitWidth>
            </field>
            <field>
              <name>EM18</name>
              <bitOffset>18</bitOffset>
              <bitWidth>1</bitWidth>
            </field>
            <field>
              <name>EM20</name>
              <bitOffset>20</bitOffset>
              <bitWidth>1</bitWidth>
            </field>
            <field>
              <name>EM21</name>
              <bitOffset>21</bitOffset>
              <bitWidth>1</bitWidth>
            </field>
            <field>
              <name>EM22</name>
              <bitOffset>22</bitOffset>
              <bitWidth>1</bitWidth>
            </field>
            <field>
              <name>EM23</name>
              <bitOffset>23</bitOffset>
              <bitWidth>1</bitWidth>
            </field>
            <field>
              <name>EM24</name>
              <bitOffset>24</bitOffset>
              <bitWidth>1</bitWidth>
            </field>
            <field>
              <name>EM25</name>
              <bitOffset>25</bitOffset>
              <bitWidth>1</bitWidth>
            </field>
            <field>
              <name>EM26</name>
              <bitOffset>26</bitOffset>
              <bitWidth>1</bitWidth>
            </field>
            <field>
              <name>EM27</name>
              <bitOffset>27</bitOffset>
              <bitWidth>1</bitWidth>
            </field>
            <field>
              <name>EM28</name>
              <bitOffset>28</bitOffset>
              <bitWidth>1</bitWidth>
            </field>
            <field>
              <name>EM29</name>
              <bitOffset>29</bitOffset>
              <bitWidth>1</bitWidth>
            </field>
            <field>
              <name>EM30</name>
              <bitOffset>30</bitOffset>
              <bitWidth>1</bitWidth>
            </field>
            <field>
              <name>EM31</name>
              <bitOffset>31</bitOffset>
              <bitWidth>1</bitWidth>
            </field>
          </fields>
        </register>
        <register>
          <name>PR1</name>
          <addressOffset>0x8</addressOffset>
          <size>0x20</size>
          <fields>
            <field>
              <name>PR0</name>
              <bitOffset>0</bitOffset>
              <bitWidth>1</bitWidth>
            </field>
            <field>
              <name>PR1</name>
              <bitOffset>1</bitOffset>
              <bitWidth>1</bitWidth>
            </field>
            <field>
              <name>PR2</name>
              <bitOffset>2</bitOffset>
              <bitWidth>1</bitWidth>
            </field>
            <field>
              <name>PR3</name>
              <bitOffset>3</bitOffset>
              <bitWidth>1</bitWidth>
            </field>
            <field>
              <name>PR4</name>
              <bitOffset>4</bitOffset>
              <bitWidth>1</bitWidth>
            </field>
            <field>
              <name>PR5</name>
              <bitOffset>5</bitOffset>
              <bitWidth>1</bitWidth>
            </field>
            <field>
              <name>PR6</name>
              <bitOffset>6</bitOffset>
              <bitWidth>1</bitWidth>
            </field>
            <field>
              <name>PR7</name>
              <bitOffset>7</bitOffset>
              <bitWidth>1</bitWidth>
            </field>
            <field>
              <name>PR8</name>
              <bitOffset>8</bitOffset>
              <bitWidth>1</bitWidth>
            </field>
            <field>
              <name>PR9</name>
              <bitOffset>9</bitOffset>
              <bitWidth>1</bitWidth>
            </field>
            <field>
              <name>PR10</name>
              <bitOffset>10</bitOffset>
              <bitWidth>1</bitWidth>
            </field>
            <field>
              <name>PR11</name>
              <bitOffset>11</bitOffset>
              <bitWidth>1</bitWidth>
            </field>
            <field>
              <name>PR12</name>
              <bitOffset>12</bitOffset>
              <bitWidth>1</bitWidth>
            </field>
            <field>
              <name>PR13</name>
              <bitOffset>13</bitOffset>
              <bitWidth>1</bitWidth>
            </field>
            <field>
              <name>PR14</name>
              <bitOffset>14</bitOffset>
              <bitWidth>1</bitWidth>
            </field>
            <field>
              <name>PR15</name>
              <bitOffset>15</bitOffset>
              <bitWidth>1</bitWidth>
            </field>
            <field>
              <name>PR16</name>
              <bitOffset>16</bitOffset>
              <bitWidth>1</bitWidth>
            </field>
            <field>
              <name>PR17</name>
              <bitOffset>17</bitOffset>
              <bitWidth>1</bitWidth>
            </field>
            <field>
              <name>PR18</name>
              <bitOffset>18</bitOffset>
              <bitWidth>1</bitWidth>
            </field>
            <field>
              <name>PR19</name>
              <bitOffset>19</bitOffset>
              <bitWidth>1</bitWidth>
            </field>
            <field>
              <name>PR20</name>
              <bitOffset>20</bitOffset>
              <bitWidth>1</bitWidth>
            </field>
            <field>
              <name>PR21</name>
              <bitOffset>21</bitOffset>
              <bitWidth>1</bitWidth>
            </field>
          </fields>
        </register>
        <register>
          <name>IMR2</name>
          <addressOffset>0x10</addressOffset>
          <size>0x20</size>
          <fields>
            <field>
              <name>IM32</name>
              <bitOffset>0</bitOffset>
              <bitWidth>1</bitWidth>
            </field>
            <field>
              <name>IM33</name>
              <bitOffset>1</bitOffset>
              <bitWidth>1</bitWidth>
            </field>
            <field>
              <name>IM34</name>
              <bitOffset>2</bitOffset>
              <bitWidth>1</bitWidth>
            </field>
            <field>
              <name>IM35</name>
              <bitOffset>3</bitOffset>
              <bitWidth>1</bitWidth>
            </field>
            <field>
              <name>IM36</name>
              <bitOffset>4</bitOffset>
              <bitWidth>1</bitWidth>
            </field>
            <field>
              <name>IM37</name>
              <bitOffset>5</bitOffset>
              <bitWidth>1</bitWidth>
            </field>
            <field>
              <name>IM38</name>
              <bitOffset>6</bitOffset>
              <bitWidth>1</bitWidth>
            </field>
            <field>
              <name>IM39</name>
              <bitOffset>7</bitOffset>
              <bitWidth>1</bitWidth>
            </field>
            <field>
              <name>IM40</name>
              <bitOffset>8</bitOffset>
              <bitWidth>1</bitWidth>
            </field>
            <field>
              <name>IM41</name>
              <bitOffset>9</bitOffset>
              <bitWidth>1</bitWidth>
            </field>
            <field>
              <name>IM42</name>
              <bitOffset>10</bitOffset>
              <bitWidth>1</bitWidth>
            </field>
            <field>
              <name>IM43</name>
              <bitOffset>11</bitOffset>
              <bitWidth>1</bitWidth>
            </field>
            <field>
              <name>IM44</name>
              <bitOffset>12</bitOffset>
              <bitWidth>1</bitWidth>
            </field>
            <field>
              <name>IM46</name>
              <bitOffset>14</bitOffset>
              <bitWidth>1</bitWidth>
            </field>
            <field>
              <name>IM47</name>
              <bitOffset>15</bitOffset>
              <bitWidth>1</bitWidth>
            </field>
            <field>
              <name>IM48</name>
              <bitOffset>16</bitOffset>
              <bitWidth>1</bitWidth>
            </field>
            <field>
              <name>IM49</name>
              <bitOffset>17</bitOffset>
              <bitWidth>1</bitWidth>
            </field>
            <field>
              <name>IM50</name>
              <bitOffset>18</bitOffset>
              <bitWidth>1</bitWidth>
            </field>
            <field>
              <name>IM51</name>
              <bitOffset>19</bitOffset>
              <bitWidth>1</bitWidth>
            </field>
            <field>
              <name>IM52</name>
              <bitOffset>20</bitOffset>
              <bitWidth>1</bitWidth>
            </field>
            <field>
              <name>IM53</name>
              <bitOffset>21</bitOffset>
              <bitWidth>1</bitWidth>
            </field>
            <field>
              <name>IM54</name>
              <bitOffset>22</bitOffset>
              <bitWidth>1</bitWidth>
            </field>
            <field>
              <name>IM55</name>
              <bitOffset>23</bitOffset>
              <bitWidth>1</bitWidth>
            </field>
            <field>
              <name>IM56</name>
              <bitOffset>24</bitOffset>
              <bitWidth>1</bitWidth>
            </field>
            <field>
              <name>IM57</name>
              <bitOffset>25</bitOffset>
              <bitWidth>1</bitWidth>
            </field>
            <field>
              <name>IM58</name>
              <bitOffset>26</bitOffset>
              <bitWidth>1</bitWidth>
            </field>
            <field>
              <name>IM59</name>
              <bitOffset>27</bitOffset>
              <bitWidth>1</bitWidth>
            </field>
            <field>
              <name>IM60</name>
              <bitOffset>28</bitOffset>
              <bitWidth>1</bitWidth>
            </field>
            <field>
              <name>IM61</name>
              <bitOffset>29</bitOffset>
              <bitWidth>1</bitWidth>
            </field>
            <field>
              <name>IM62</name>
              <bitOffset>30</bitOffset>
              <bitWidth>1</bitWidth>
            </field>
            <field>
              <name>IM63</name>
              <bitOffset>31</bitOffset>
              <bitWidth>1</bitWidth>
            </field>
          </fields>
        </register>
        <register>
          <name>EMR2</name>
          <addressOffset>0x14</addressOffset>
          <size>0x20</size>
          <fields>
            <field>
              <name>EM32</name>
              <bitOffset>0</bitOffset>
              <bitWidth>1</bitWidth>
            </field>
            <field>
              <name>EM33</name>
              <bitOffset>1</bitOffset>
              <bitWidth>1</bitWidth>
            </field>
            <field>
              <name>EM34</name>
              <bitOffset>2</bitOffset>
              <bitWidth>1</bitWidth>
            </field>
            <field>
              <name>EM35</name>
              <bitOffset>3</bitOffset>
              <bitWidth>1</bitWidth>
            </field>
            <field>
              <name>EM36</name>
              <bitOffset>4</bitOffset>
              <bitWidth>1</bitWidth>
            </field>
            <field>
              <name>EM37</name>
              <bitOffset>5</bitOffset>
              <bitWidth>1</bitWidth>
            </field>
            <field>
              <name>EM38</name>
              <bitOffset>6</bitOffset>
              <bitWidth>1</bitWidth>
            </field>
            <field>
              <name>EM39</name>
              <bitOffset>7</bitOffset>
              <bitWidth>1</bitWidth>
            </field>
            <field>
              <name>EM40</name>
              <bitOffset>8</bitOffset>
              <bitWidth>1</bitWidth>
            </field>
            <field>
              <name>EM41</name>
              <bitOffset>9</bitOffset>
              <bitWidth>1</bitWidth>
            </field>
            <field>
              <name>EM42</name>
              <bitOffset>10</bitOffset>
              <bitWidth>1</bitWidth>
            </field>
            <field>
              <name>EM43</name>
              <bitOffset>11</bitOffset>
              <bitWidth>1</bitWidth>
            </field>
            <field>
              <name>EM44</name>
              <bitOffset>12</bitOffset>
              <bitWidth>1</bitWidth>
            </field>
            <field>
              <name>EM46</name>
              <bitOffset>14</bitOffset>
              <bitWidth>1</bitWidth>
            </field>
            <field>
              <name>EM47</name>
              <bitOffset>15</bitOffset>
              <bitWidth>1</bitWidth>
            </field>
            <field>
              <name>EM48</name>
              <bitOffset>16</bitOffset>
              <bitWidth>1</bitWidth>
            </field>
            <field>
              <name>EM49</name>
              <bitOffset>17</bitOffset>
              <bitWidth>1</bitWidth>
            </field>
            <field>
              <name>EM50</name>
              <bitOffset>18</bitOffset>
              <bitWidth>1</bitWidth>
            </field>
            <field>
              <name>EM51</name>
              <bitOffset>19</bitOffset>
              <bitWidth>1</bitWidth>
            </field>
            <field>
              <name>EM52</name>
              <bitOffset>20</bitOffset>
              <bitWidth>1</bitWidth>
            </field>
            <field>
              <name>EM53</name>
              <bitOffset>21</bitOffset>
              <bitWidth>1</bitWidth>
            </field>
            <field>
              <name>EM54</name>
              <bitOffset>22</bitOffset>
              <bitWidth>1</bitWidth>
            </field>
            <field>
              <name>EM55</name>
              <bitOffset>23</bitOffset>
              <bitWidth>1</bitWidth>
            </field>
            <field>
              <name>EM56</name>
              <bitOffset>24</bitOffset>
              <bitWidth>1</bitWidth>
            </field>
            <field>
              <name>EM57</name>
              <bitOffset>25</bitOffset>
              <bitWidth>1</bitWidth>
            </field>
            <field>
              <name>EM58</name>
              <bitOffset>26</bitOffset>
              <bitWidth>1</bitWidth>
            </field>
            <field>
              <name>EM59</name>
              <bitOffset>27</bitOffset>
              <bitWidth>1</bitWidth>
            </field>
            <field>
              <name>EM60</name>
              <bitOffset>28</bitOffset>
              <bitWidth>1</bitWidth>
            </field>
            <field>
              <name>EM61</name>
              <bitOffset>29</bitOffset>
              <bitWidth>1</bitWidth>
            </field>
            <field>
              <name>EM62</name>
              <bitOffset>30</bitOffset>
              <bitWidth>1</bitWidth>
            </field>
            <field>
              <name>EM63</name>
              <bitOffset>31</bitOffset>
              <bitWidth>1</bitWidth>
            </field>
          </fields>
        </register>
        <register>
          <name>PR2</name>
          <addressOffset>0x18</addressOffset>
          <size>0x20</size>
          <fields>
            <field>
              <name>PR49</name>
              <bitOffset>17</bitOffset>
              <bitWidth>1</bitWidth>
            </field>
            <field>
              <name>PR51</name>
              <bitOffset>19</bitOffset>
              <bitWidth>1</bitWidth>
            </field>
          </fields>
        </register>
        <register>
          <name>IMR3</name>
          <addressOffset>0x20</addressOffset>
          <size>0x20</size>
          <fields>
            <field>
              <name>IM64</name>
              <bitOffset>0</bitOffset>
              <bitWidth>1</bitWidth>
            </field>
            <field>
              <name>IM65</name>
              <bitOffset>1</bitOffset>
              <bitWidth>1</bitWidth>
            </field>
            <field>
              <name>IM66</name>
              <bitOffset>2</bitOffset>
              <bitWidth>1</bitWidth>
            </field>
            <field>
              <name>IM67</name>
              <bitOffset>3</bitOffset>
              <bitWidth>1</bitWidth>
            </field>
            <field>
              <name>IM68</name>
              <bitOffset>4</bitOffset>
              <bitWidth>1</bitWidth>
            </field>
            <field>
              <name>IM69</name>
              <bitOffset>5</bitOffset>
              <bitWidth>1</bitWidth>
            </field>
            <field>
              <name>IM70</name>
              <bitOffset>6</bitOffset>
              <bitWidth>1</bitWidth>
            </field>
            <field>
              <name>IM71</name>
              <bitOffset>7</bitOffset>
              <bitWidth>1</bitWidth>
            </field>
            <field>
              <name>IM72</name>
              <bitOffset>8</bitOffset>
              <bitWidth>1</bitWidth>
            </field>
            <field>
              <name>IM73</name>
              <bitOffset>9</bitOffset>
              <bitWidth>1</bitWidth>
            </field>
            <field>
              <name>IM74</name>
              <bitOffset>10</bitOffset>
              <bitWidth>1</bitWidth>
            </field>
            <field>
              <name>IM75</name>
              <bitOffset>11</bitOffset>
              <bitWidth>1</bitWidth>
            </field>
            <field>
              <name>IM76</name>
              <bitOffset>12</bitOffset>
              <bitWidth>1</bitWidth>
            </field>
            <field>
              <name>IM77</name>
              <bitOffset>13</bitOffset>
              <bitWidth>1</bitWidth>
            </field>
            <field>
              <name>IM78</name>
              <bitOffset>14</bitOffset>
              <bitWidth>1</bitWidth>
            </field>
            <field>
              <name>IM79</name>
              <bitOffset>15</bitOffset>
              <bitWidth>1</bitWidth>
            </field>
            <field>
              <name>IM80</name>
              <bitOffset>16</bitOffset>
              <bitWidth>1</bitWidth>
            </field>
            <field>
              <name>IM82</name>
              <bitOffset>18</bitOffset>
              <bitWidth>1</bitWidth>
            </field>
            <field>
              <name>IM84</name>
              <bitOffset>20</bitOffset>
              <bitWidth>1</bitWidth>
            </field>
            <field>
              <name>IM85</name>
              <bitOffset>21</bitOffset>
              <bitWidth>1</bitWidth>
            </field>
            <field>
              <name>IM86</name>
              <bitOffset>22</bitOffset>
              <bitWidth>1</bitWidth>
            </field>
            <field>
              <name>IM87</name>
              <bitOffset>23</bitOffset>
              <bitWidth>1</bitWidth>
            </field>
          </fields>
        </register>
        <register>
          <name>EMR3</name>
          <addressOffset>0x24</addressOffset>
          <size>0x20</size>
          <fields>
            <field>
              <name>EM64</name>
              <bitOffset>0</bitOffset>
              <bitWidth>1</bitWidth>
            </field>
            <field>
              <name>EM65</name>
              <bitOffset>1</bitOffset>
              <bitWidth>1</bitWidth>
            </field>
            <field>
              <name>EM66</name>
              <bitOffset>2</bitOffset>
              <bitWidth>1</bitWidth>
            </field>
            <field>
              <name>EM67</name>
              <bitOffset>3</bitOffset>
              <bitWidth>1</bitWidth>
            </field>
            <field>
              <name>EM68</name>
              <bitOffset>4</bitOffset>
              <bitWidth>1</bitWidth>
            </field>
            <field>
              <name>EM69</name>
              <bitOffset>5</bitOffset>
              <bitWidth>1</bitWidth>
            </field>
            <field>
              <name>EM70</name>
              <bitOffset>6</bitOffset>
              <bitWidth>1</bitWidth>
            </field>
            <field>
              <name>EM71</name>
              <bitOffset>7</bitOffset>
              <bitWidth>1</bitWidth>
            </field>
            <field>
              <name>EM72</name>
              <bitOffset>8</bitOffset>
              <bitWidth>1</bitWidth>
            </field>
            <field>
              <name>EM73</name>
              <bitOffset>9</bitOffset>
              <bitWidth>1</bitWidth>
            </field>
            <field>
              <name>EM74</name>
              <bitOffset>10</bitOffset>
              <bitWidth>1</bitWidth>
            </field>
            <field>
              <name>EM75</name>
              <bitOffset>11</bitOffset>
              <bitWidth>1</bitWidth>
            </field>
            <field>
              <name>EM76</name>
              <bitOffset>12</bitOffset>
              <bitWidth>1</bitWidth>
            </field>
            <field>
              <name>EM77</name>
              <bitOffset>13</bitOffset>
              <bitWidth>1</bitWidth>
            </field>
            <field>
              <name>EM78</name>
              <bitOffset>14</bitOffset>
              <bitWidth>1</bitWidth>
            </field>
            <field>
              <name>EM79</name>
              <bitOffset>15</bitOffset>
              <bitWidth>1</bitWidth>
            </field>
            <field>
              <name>EM80</name>
              <bitOffset>16</bitOffset>
              <bitWidth>1</bitWidth>
            </field>
            <field>
              <name>EM81</name>
              <bitOffset>17</bitOffset>
              <bitWidth>1</bitWidth>
            </field>
            <field>
              <name>EM82</name>
              <bitOffset>18</bitOffset>
              <bitWidth>1</bitWidth>
            </field>
            <field>
              <name>EM84</name>
              <bitOffset>20</bitOffset>
              <bitWidth>1</bitWidth>
            </field>
            <field>
              <name>EM85</name>
              <bitOffset>21</bitOffset>
              <bitWidth>1</bitWidth>
            </field>
            <field>
              <name>EM86</name>
              <bitOffset>22</bitOffset>
              <bitWidth>1</bitWidth>
            </field>
            <field>
              <name>EM87</name>
              <bitOffset>23</bitOffset>
              <bitWidth>1</bitWidth>
            </field>
          </fields>
        </register>
        <register>
          <name>PR3</name>
          <addressOffset>0x28</addressOffset>
          <size>0x20</size>
          <fields>
            <field>
              <name>PR82</name>
              <bitOffset>18</bitOffset>
              <bitWidth>1</bitWidth>
            </field>
            <field>
              <name>PR84</name>
              <bitOffset>20</bitOffset>
              <bitWidth>1</bitWidth>
            </field>
            <field>
              <name>PR85</name>
              <bitOffset>21</bitOffset>
              <bitWidth>1</bitWidth>
            </field>
            <field>
              <name>PR86</name>
              <bitOffset>22</bitOffset>
              <bitWidth>1</bitWidth>
            </field>
          </fields>
        </register>
      </registers>
    </peripheral>
    <peripheral>
      <name>SYSCFG</name>
      <baseAddress>0x58000400</baseAddress>
      <registers>
        <register>
          <name>PMCR</name>
          <addressOffset>0x4</addressOffset>
          <size>0x20</size>
          <fields>
            <field>
              <name>I2C1_FMP</name>
              <bitOffset>0</bitOffset>
              <bitWidth>1</bitWidth>
            </field>
            <field>
              <name>I2C2_FMP</name>
              <bitOffset>1</bitOffset>
              <bitWidth>1</bitWidth>
            </field>
            <field>
              <name>I2C3_FMP</name>
              <bitOffset>2</bitOffset>
              <bitWidth>1</bitWidth>
            </field>
            <field>
              <name>I2C4_FMP</name>
              <bitOffset>3</bitOffset>
              <bitWidth>1</bitWidth>
            </field>
            <field>
              <name>I2C_PB6_FMP</name>
              <bitOffset>4</bitOffset>
              <bitWidth>1</bitWidth>
            </field>
            <field>
              <name>I2C_PB7_FMP</name>
              <bitOffset>5</bitOffset>
              <bitWidth>1</bitWidth>
            </field>
            <field>
              <name>I2C_PB8_FMP</name>
              <bitOffset>6</bitOffset>
              <bitWidth>1</bitWidth>
            </field>
            <field>
              <name>I2C_PB9_FMP</name>
              <bitOffset>7</bitOffset>
              <bitWidth>1</bitWidth>
            </field>
            <field>
              <name>BOOSTEN</name>
              <bitOffset>8</bitOffset>
              <bitWidth>1</bitWidth>
            </field>
            <field>
              <name>BOOSTVDDSEL</name>
              <bitOffset>9</bitOffset>
              <bitWidth>1</bitWidth>
            </field>
            <field>
              <name>EPIS_SEL</name>
              <bitOffset>21</bitOffset>
              <bitWidth>3</bitWidth>
            </field>
            <field>
              <name>PA0SO</name>
              <bitOffset>24</bitOffset>
              <bitWidth>1</bitWidth>
            </field>
            <field>
              <name>PA1SO</name>
              <bitOffset>25</bitOffset>
              <bitWidth>1</bitWidth>
            </field>
            <field>
              <name>PC2SO</name>
              <bitOffset>26</bitOffset>
              <bitWidth>1</bitWidth>
            </field>
            <field>
              <name>PC3SO</name>
              <bitOffset>27</bitOffset>
              <bitWidth>1</bitWidth>
            </field>
          </fields>
        </register>
        <register>
          <name>EXTICR.0</name>
          <addressOffset>0x8</addressOffset>
          <size>0x20</size>
          <fields>
            <field>
              <name>EXTI0</name>
              <bitOffset>0</bitOffset>
              <bitWidth>4</bitWidth>
            </field>
            <field>
              <name>EXTI1</name>
              <bitOffset>4</bitOffset>
              <bitWidth>4</bitWidth>
            </field>
            <field>
              <name>EXTI2</name>
              <bitOffset>8</bitOffset>
              <bitWidth>4</bitWidth>
            </field>
            <field>
              <name>EXTI3</name>
              <bitOffset>12</bitOffset>
              <bitWidth>4</bitWidth>
            </field>
          </fields>
        </register>
        <register>
          <name>EXTICR.1</name>
          <addressOffset>0xc</addressOffset>
          <size>0x20</size>
          <fields>
            <field>
              <name>EXTI4</name>
              <bitOffset>0</bitOffset>
              <bitWidth>4</bitWidth>
            </field>
            <field>
              <name>EXTI5</name>
              <bitOffset>4</bitOffset>
              <bitWidth>4</bitWidth>
            </field>
            <field>
              <name>EXTI6</name>
              <bitOffset>8</bitOffset>
              <bitWidth>4</bitWidth>
            </field>
            <field>
              <name>EXTI7</name>
              <bitOffset>12</bitOffset>
              <bitWidth>4</bitWidth>
            </field>
          </fields>
        </register>
        <register>
          <name>EXTICR.2</name>
          <addressOffset>0x10</addressOffset>
          <size>0x20</size>
          <fields>
            <field>
              <name>EXTI8</name>
              <bitOffset>0</bitOffset>
              <bitWidth>4</bitWidth>
            </field>
            <field>
              <name>EXTI9</name>
              <bitOffset>4</bitOffset>
              <bitWidth>4</bitWidth>
            </field>
            <field>
              <name>EXTI10</name>
              <bitOffset>8</bitOffset>
              <bitWidth>4</bitWidth>
            </field>
            <field>
              <name>EXTI11</name>
              <bitOffset>12</bitOffset>
              <bitWidth>4</bitWidth>
            </field>
          </fields>
        </register>
        <register>
          <name>EXTICR.3</name>
          <addressOffset>0x14</addressOffset>
          <size>0x20</size>
          <fields>
            <field>
              <name>EXTI12</name>
              <bitOffset>0</bitOffset>
              <bitWidth>4</bitWidth>
            </field>
            <field>
              <name>EXTI13</name>
              <bitOffset>4</bitOffset>
              <bitWidth>4</bitWidth>
            </field>
            <field>
              <name>EXTI14</name>
              <bitOffset>8</bitOffset>
              <bitWidth>4</bitWidth>
            </field>
            <field>
              <name>EXTI15</name>
              <bitOffset>12</bitOffset>
              <bitWidth>4</bitWidth>
            </field>
          </fields>
        </register>
        <register>
          <name>CFGR</name>
          <addressOffset>0x18</addressOffset>
          <size>0x20</size>
          <fields>
            <field>
              <name>CM4L</name>
              <bitOffset>0</bitOffset>
              <bitWidth>1</bitWidth>
            </field>
            <field>
              <name>PVDL</name>
              <bitOffset>2</bitOffset>
              <bitWidth>1</bitWidth>
            </field>
            <field>
              <name>FLASHL</name>
              <bitOffset>3</bitOffset>
              <bitWidth>1</bitWidth>
            </field>
            <field>
              <name>CM7L</name>
              <bitOffset>6</bitOffset>
              <bitWidth>1</bitWidth>
            </field>
            <field>
              <name>BKRAML</name>
              <bitOffset>7</bitOffset>
              <bitWidth>1</bitWidth>
            </field>
            <field>
              <name>SRAM4L</name>
              <bitOffset>9</bitOffset>
              <bitWidth>1</bitWidth>
            </field>
            <field>
              <name>SRAM3L</name>
              <bitOffset>10</bitOffset>
              <bitWidth>1</bitWidth>
            </field>
            <field>
              <name>SRAM2L</name>
              <bitOffset>11</bitOffset>
              <bitWidth>1</bitWidth>
            </field>
            <field>
              <name>SRAM1L</name>
              <bitOffset>12</bitOffset>
              <bitWidth>1</bitWidth>
            </field>
            <field>
              <name>DTCML</name>
              <bitOffset>13</bitOffset>
              <bitWidth>1</bitWidth>
            </field>
            <field>
              <name>ITCML</name>
              <bitOffset>14</bitOffset>
              <bitWidth>1</bitWidth>
            </field>
            <field>
              <name>AXISRAML</name>
              <bitOffset>15</bitOffset>
              <bitWidth>1</bitWidth>
            </field>
          </fields>
        </register>
        <register>
          <name>CCCSR</name>
          <addressOffset>0x20</addressOffset>
          <size>0x20</size>
          <fields>
            <field>
              <name>EN</name>
              <bitOffset>0</bitOffset>
              <bitWidth>1</bitWidth>
            </field>
            <field>
              <name>CS</name>
              <bitOffset>1</bitOffset>
              <bitWidth>1</bitWidth>
            </field>
            <field>
              <name>READY</name>
              <bitOffset>8</bitOffset>
              <bitWidth>1</bitWidth>
            </field>
            <field>
              <name>HSLV</name>
              <bitOffset>16</bitOffset>
              <bitWidth>1</bitWidth>
            </field>
          </fields>
        </register>
        <register>
          <name>CCVR</name>
          <addressOffset>0x24</addressOffset>
          <size>0x20</size>
          <fields>
            <field>
              <name>NCV</name>
              <bitOffset>0</bitOffset>
              <bitWidth>4</bitWidth>
            </field>
            <field>
              <name>PCV</name>
              <bitOffset>4</bitOffset>
              <bitWidth>4</bitWidth>
            </field>
          </fields>
        </register>
        <register>
          <name>CCCR</name>
          <addressOffset>0x28</addressOffset>
          <size>0x20</size>
          <fields>
            <field>
              <name>NCC</name>
              <bitOffset>0</bitOffset>
              <bitWidth>4</bitWidth>
            </field>
            <field>
              <name>PCC</name>
              <bitOffset>4</bitOffset>
              <bitWidth>4</bitWidth>
            </field>
          </fields>
        </register>
        <register>
          <name>PWRCR</name>
          <addressOffset>0x2c</addressOffset>
          <size>0x20</size>
          <fields>
            <field>
              <name>ODEN</name>
              <bitOffset>0</bitOffset>
              <bitWidth>1</bitWidth>
            </field>
          </fields>
        </register>
        <register>
          <name>PKGR</name>
          <addressOffset>0x124</addressOffset>
          <size>0x20</size>
          <fields>
            <field>
              <name>PKG</name>
              <bitOffset>0</bitOffset>
              <bitWidth>4</bitWidth>
            </field>
          </fields>
        </register>
        <register>
          <name>UR0</name>
          <addressOffset>0x300</addressOffset>
          <size>0x20</size>
          <fields>
            <field>
              <name>BKS</name>
              <bitOffset>0</bitOffset>
              <bitWidth>1</bitWidth>
            </field>
            <field>
              <name>RDP</name>
              <bitOffset>16</bitOffset>
              <bitWidth>8</bitWidth>
            </field>
          </fields>
        </register>
        <register>
          <name>UR1</name>
          <addressOffset>0x304</addressOffset>
          <size>0x20</size>
          <fields>
            <field>
              <name>BCM4</name>
              <bitOffset>0</bitOffset>
              <bitWidth>1</bitWidth>
            </field>
            <field>
              <name>BCM7</name>
              <bitOffset>16</bitOffset>
              <bitWidth>1</bitWidth>
            </field>
          </fields>
        </register>
        <register>
          <name>UR2</name>
          <addressOffset>0x308</addressOffset>
          <size>0x20</size>
          <fields>
            <field>
              <name>BORH</name>
              <bitOffset>0</bitOffset>
              <bitWidth>2</bitWidth>
            </field>
            <field>
              <name>BCM7_ADD0</name>
              <bitOffset>16</bitOffset>
              <bitWidth>16</bitWidth>
            </field>
          </fields>
        </register>
        <register>
          <name>UR3</name>
          <addressOffset>0x30c</addressOffset>
          <size>0x20</size>
          <fields>
            <field>
              <name>BCM7_ADD1</name>
              <bitOffset>0</bitOffset>
              <bitWidth>16</bitWidth>
            </field>
            <field>
              <name>BCM4_ADD0</name>
              <bitOffset>16</bitOffset>
              <bitWidth>16</bitWidth>
            </field>
          </fields>
        </register>
        <register>
          <name>UR4</name>
          <addressOffset>0x310</addressOffset>
          <size>0x20</size>
          <fields>
            <field>
              <name>BCM4_ADD1</name>
              <bitOffset>0</bitOffset>
              <bitWidth>16</bitWidth>
            </field>
            <field>
              <name>MEPAD_BANK1</name>
              <bitOffset>16</bitOffset>
              <bitWidth>1</bitWidth>
            </field>
          </fields>
        </register>
        <register>
          <name>UR5</name>
          <addressOffset>0x314</addressOffset>
          <size>0x20</size>
          <fields>
            <field>
              <name>MESAD_BANK1</name>
              <bitOffset>0</bitOffset>
              <bitWidth>1</bitWidth>
            </field>
            <field>
              <name>WRPN_BANK1</name>
              <bitOffset>16</bitOffset>
              <bitWidth>8</bitWidth>
            </field>
          </fields>
        </register>
        <register>
          <name>UR6</name>
          <addressOffset>0x318</addressOffset>
          <size>0x20</size>
          <fields>
            <field>
              <name>PABEG_BANK1</name>
              <bitOffset>0</bitOffset>
              <bitWidth>12</bitWidth>
            </field>
            <field>
              <name>PAEND_BANK1</name>
              <bitOffset>16</bitOffset>
              <bitWidth>12</bitWidth>
            </field>
          </fields>
        </register>
        <register>
          <name>UR7</name>
          <addressOffset>0x31c</addressOffset>
          <size>0x20</size>
          <fields>
            <field>
              <name>SABEG_BANK1</name>
              <bitOffset>0</bitOffset>
              <bitWidth>12</bitWidth>
            </field>
            <field>
              <name>SAEND_BANK1</name>
              <bitOffset>16</bitOffset>
              <bitWidth>12</bitWidth>
            </field>
          </fields>
        </register>
        <register>
          <name>UR8</name>
          <addressOffset>0x320</addressOffset>
          <size>0x20</size>
          <fields>
            <field>
              <name>MEPAD_BANK2</name>
              <bitOffset>0</bitOffset>
              <bitWidth>1</bitWidth>
            </field>
            <field>
              <name>MESAD_BANK2</name>
              <bitOffset>16</bitOffset>
              <bitWidth>1</bitWidth>
            </field>
          </fields>
        </register>
        <register>
          <name>UR9</name>
          <addressOffset>0x324</addressOffset>
          <size>0x20</size>
          <fields>
            <field>
              <name>WRPN_BANK2</name>
              <bitOffset>0</bitOffset>
              <bitWidth>8</bitWidth>
            </field>
            <field>
              <name>PABEG_BANK2</name>
              <bitOffset>16</bitOffset>
              <bitWidth>12</bitWidth>
            </field>
          </fields>
        </register>
        <register>
          <name>UR10</name>
          <addressOffset>0x328</addressOffset>
          <size>0x20</size>
          <fields>
            <field>
              <name>PAEND_BANK2</name>
              <bitOffset>0</bitOffset>
              <bitWidth>12</bitWidth>
            </field>
            <field>
              <name>SABEG_BANK2</name>
              <bitOffset>16</bitOffset>
              <bitWidth>12</bitWidth>
            </field>
          </fields>
        </register>
        <register>
          <name>UR11</name>
          <addressOffset>0x32c</addressOffset>
          <size>0x20</size>
          <fields>
            <field>
              <name>SAEND_BANK2</name>
              <bitOffset>0</bitOffset>
              <bitWidth>12</bitWidth>
            </field>
            <field>
              <name>IWDG1M</name>
              <bitOffset>16</bitOffset>
              <bitWidth>1</bitWidth>
            </field>
          </fields>
        </register>
        <register>
          <name>UR12</name>
          <addressOffset>0x330</addressOffset>
          <size>0x20</size>
          <fields>
            <field>
              <name>IWDG2M</name>
              <bitOffset>0</bitOffset>
              <bitWidth>1</bitWidth>
            </field>
            <field>
              <name>SECURE</name>
              <bitOffset>16</bitOffset>
              <bitWidth>1</bitWidth>
            </field>
          </fields>
        </register>
        <register>
          <name>UR13</name>
          <addressOffset>0x334</addressOffset>
          <size>0x20</size>
          <fields>
            <field>
              <name>SDRS</name>
              <bitOffset>0</bitOffset>
              <bitWidth>2</bitWidth>
            </field>
            <field>
              <name>D1SBRST</name>
              <bitOffset>16</bitOffset>
              <bitWidth>1</bitWidth>
            </field>
          </fields>
        </register>
        <register>
          <name>UR14</name>
          <addressOffset>0x338</addressOffset>
          <size>0x20</size>
          <fields>
            <field>
              <name>D1STPRST</name>
              <bitOffset>0</bitOffset>
              <bitWidth>1</bitWidth>
            </field>
            <field>
              <name>D2SBRST</name>
              <bitOffset>16</bitOffset>
              <bitWidth>1</bitWidth>
            </field>
          </fields>
        </register>
        <register>
          <name>UR15</name>
          <addressOffset>0x33c</addressOffset>
          <size>0x20</size>
          <fields>
            <field>
              <name>D2STPRST</name>
              <bitOffset>0</bitOffset>
              <bitWidth>1</bitWidth>
            </field>
            <field>
              <name>FZIWDGSTB</name>
              <bitOffset>16</bitOffset>
              <bitWidth>1</bitWidth>
            </field>
          </fields>
        </register>
        <register>
          <name>UR16</name>
          <addressOffset>0x340</addressOffset>
          <size>0x20</size>
          <fields>
            <field>
              <name>FZIWDGSTP</name>
              <bitOffset>0</bitOffset>
              <bitWidth>1</bitWidth>
            </field>
            <field>
              <name>PKP</name>
              <bitOffset>16</bitOffset>
              <bitWidth>1</bitWidth>
            </field>
          </fields>
        </register>
        <register>
          <name>UR17</name>
          <addressOffset>0x344</addressOffset>
          <size>0x20</size>
          <fields>
            <field>
              <name>IOHSLV</name>
              <bitOffset>0</bitOffset>
              <bitWidth>1</bitWidth>
            </field>
          </fields>
        </register>
      </registers>
    </peripheral>
    <peripheral>
      <name>LPUART1</name>
      <baseAddress>0x58000c00</baseAddress>
      <registers>
        <register>
          <name>CR1</name>
          <addressOffset>0x0</addressOffset>
          <size>0x20</size>
          <fields>
            <field>
              <name>UE</name>
              <bitOffset>0</bitOffset>
              <bitWidth>1</bitWidth>
            </field>
            <field>
              <name>UESM</name>
              <bitOffset>1</bitOffset>
              <bitWidth>1</bitWidth>
            </field>
            <field>
              <name>RE</name>
              <bitOffset>2</bitOffset>
              <bitWidth>1</bitWidth>
            </field>
            <field>
              <name>TE</name>
              <bitOffset>3</bitOffset>
              <bitWidth>1</bitWidth>
            </field>
            <field>
              <name>IDLEIE</name>
              <bitOffset>4</bitOffset>
              <bitWidth>1</bitWidth>
            </field>
            <field>
              <name>RXNEIE_RXFNEIE</name>
              <bitOffset>5</bitOffset>
              <bitWidth>1</bitWidth>
            </field>
            <field>
              <name>TCIE</name>
              <bitOffset>6</bitOffset>
              <bitWidth>1</bitWidth>
            </field>
            <field>
              <name>TXEIE_TXFNFIE</name>
              <bitOffset>7</bitOffset>
              <bitWidth>1</bitWidth>
            </field>
            <field>
              <name>PEIE</name>
              <bitOffset>8</bitOffset>
              <bitWidth>1</bitWidth>
            </field>
            <field>
              <name>PS</name>
              <bitOffset>9</bitOffset>
              <bitWidth>1</bitWidth>
            </field>
            <field>
              <name>PCE</name>
              <bitOffset>10</bitOffset>
              <bitWidth>1</bitWidth>
            </field>
            <field>
              <name>WAKE</name>
              <bitOffset>11</bitOffset>
              <bitWidth>1</bitWidth>
            </field>
            <field>
              <name>M0</name>
              <bitOffset>12</bitOffset>
              <bitWidth>1</bitWidth>
            </field>
            <field>
              <name>MME</name>
              <bitOffset>13</bitOffset>
              <bitWidth>1</bitWidth>
            </field>
            <field>
              <name>CMIE</name>
              <bitOffset>14</bitOffset>
              <bitWidth>1</bitWidth>
            </field>
            <field>
              <name>OVER8</name>
              <bitOffset>15</bitOffset>
              <bitWidth>1</bitWidth>
            </field>
            <field>
              <name>DEDT</name>
              <bitOffset>16</bitOffset>
              <bitWidth>5</bitWidth>
            </field>
            <field>
              <name>DEAT</name>
              <bitOffset>21</bitOffset>
              <bitWidth>5</bitWidth>
            </field>
            <field>
              <name>RTOIE</name>
              <bitOffset>26</bitOffset>
              <bitWidth>1</bitWidth>
            </field>
            <field>
              <name>EOBIE</name>
              <bitOffset>27</bitOffset>
              <bitWidth>1</bitWidth>
            </field>
            <field>
              <name>M1</name>
              <bitOffset>28</bitOffset>
              <bitWidth>1</bitWidth>
            </field>
            <field>
              <name>FIFOEN</name>
              <bitOffset>29</bitOffset>
              <bitWidth>1</bitWidth>
            </field>
            <field>
              <name>TXFEIE</name>
              <bitOffset>30</bitOffset>
              <bitWidth>1</bitWidth>
            </field>
            <field>
              <name>RXFFIE</name>
              <bitOffset>31</bitOffset>
              <bitWidth>1</bitWidth>
            </field>
          </fields>
        </register>
        <register>
          <name>CR2</name>
          <addressOffset>0x4</addressOffset>
          <size>0x20</size>
          <fields>
            <field>
              <name>SLVEN</name>
              <bitOffset>0</bitOffset>
              <bitWidth>1</bitWidth>
            </field>
            <field>
              <name>DIS_NSS</name>
              <bitOffset>3</bitOffset>
              <bitWidth>1</bitWidth>
            </field>
            <field>
              <name>ADDM7</name>
              <bitOffset>4</bitOffset>
              <bitWidth>1</bitWidth>
            </field>
            <field>
              <name>LBDL</name>
              <bitOffset>5</bitOffset>
              <bitWidth>1</bitWidth>
            </field>
            <field>
              <name>LBDIE</name>
              <bitOffset>6</bitOffset>
              <bitWidth>1</bitWidth>
            </field>
            <field>
              <name>LBCL</name>
              <bitOffset>8</bitOffset>
              <bitWidth>1</bitWidth>
            </field>
            <field>
              <name>CPHA</name>
              <bitOffset>9</bitOffset>
              <bitWidth>1</bitWidth>
            </field>
            <field>
              <name>CPOL</name>
              <bitOffset>10</bitOffset>
              <bitWidth>1</bitWidth>
            </field>
            <field>
              <name>CLKEN</name>
              <bitOffset>11</bitOffset>
              <bitWidth>1</bitWidth>
            </field>
            <field>
              <name>STOP</name>
              <bitOffset>12</bitOffset>
              <bitWidth>2</bitWidth>
            </field>
            <field>
              <name>LINEN</name>
              <bitOffset>14</bitOffset>
              <bitWidth>1</bitWidth>
            </field>
            <field>
              <name>SWAP</name>
              <bitOffset>15</bitOffset>
              <bitWidth>1</bitWidth>
            </field>
            <field>
              <name>RXINV</name>
              <bitOffset>16</bitOffset>
              <bitWidth>1</bitWidth>
            </field>
            <field>
              <name>TXINV</name>
              <bitOffset>17</bitOffset>
              <bitWidth>1</bitWidth>
            </field>
            <field>
              <name>DATAINV</name>
              <bitOffset>18</bitOffset>
              <bitWidth>1</bitWidth>
            </field>
            <field>
              <name>MSBFIRST</name>
              <bitOffset>19</bitOffset>
              <bitWidth>1</bitWidth>
            </field>
            <field>
              <name>ABREN</name>
              <bitOffset>20</bitOffset>
              <bitWidth>1</bitWidth>
            </field>
            <field>
              <name>ABRMODE</name>
              <bitOffset>21</bitOffset>
              <bitWidth>2</bitWidth>
            </field>
            <field>
              <name>RTOEN</name>
              <bitOffset>23</bitOffset>
              <bitWidth>1</bitWidth>
            </field>
            <field>
              <name>ADD</name>
              <bitOffset>24</bitOffset>
              <bitWidth>8</bitWidth>
            </field>
          </fields>
        </register>
        <register>
          <name>CR3</name>
          <addressOffset>0x8</addressOffset>
          <size>0x20</size>
          <fields>
            <field>
              <name>EIE</name>
              <bitOffset>0</bitOffset>
              <bitWidth>1</bitWidth>
            </field>
            <field>
              <name>IREN</name>
              <bitOffset>1</bitOffset>
              <bitWidth>1</bitWidth>
            </field>
            <field>
              <name>IRLP</name>
              <bitOffset>2</bitOffset>
              <bitWidth>1</bitWidth>
            </field>
            <field>
              <name>HDSEL</name>
              <bitOffset>3</bitOffset>
              <bitWidth>1</bitWidth>
            </field>
            <field>
              <name>NACK</name>
              <bitOffset>4</bitOffset>
              <bitWidth>1</bitWidth>
            </field>
            <field>
              <name>SCEN</name>
              <bitOffset>5</bitOffset>
              <bitWidth>1</bitWidth>
            </field>
            <field>
              <name>DMAR</name>
              <bitOffset>6</bitOffset>
              <bitWidth>1</bitWidth>
            </field>
            <field>
              <name>DMAT</name>
              <bitOffset>7</bitOffset>
              <bitWidth>1</bitWidth>
            </field>
            <field>
              <name>RTSE</name>
              <bitOffset>8</bitOffset>
              <bitWidth>1</bitWidth>
            </field>
            <field>
              <name>CTSE</name>
              <bitOffset>9</bitOffset>
              <bitWidth>1</bitWidth>
            </field>
            <field>
              <name>CTSIE</name>
              <bitOffset>10</bitOffset>
              <bitWidth>1</bitWidth>
            </field>
            <field>
              <name>ONEBIT</name>
              <bitOffset>11</bitOffset>
              <bitWidth>1</bitWidth>
            </field>
            <field>
              <name>OVRDIS</name>
              <bitOffset>12</bitOffset>
              <bitWidth>1</bitWidth>
            </field>
            <field>
              <name>DDRE</name>
              <bitOffset>13</bitOffset>
              <bitWidth>1</bitWidth>
            </field>
            <field>
              <name>DEM</name>
              <bitOffset>14</bitOffset>
              <bitWidth>1</bitWidth>
            </field>
            <field>
              <name>DEP</name>
              <bitOffset>15</bitOffset>
              <bitWidth>1</bitWidth>
            </field>
            <field>
              <name>SCARCNT</name>
              <bitOffset>17</bitOffset>
              <bitWidth>3</bitWidth>
            </field>
            <field>
              <name>WUS</name>
              <bitOffset>20</bitOffset>
              <bitWidth>2</bitWidth>
            </field>
            <field>
              <name>WUFIE</name>
              <bitOffset>22</bitOffset>
              <bitWidth>1</bitWidth>
            </field>
            <field>
              <name>TXFTIE</name>
              <bitOffset>23</bitOffset>
              <bitWidth>1</bitWidth>
            </field>
            <field>
              <name>TCBGTIE</name>
              <bitOffset>24</bitOffset>
              <bitWidth>1</bitWidth>
            </field>
            <field>
              <name>RXFTCFG</name>
              <bitOffset>25</bitOffset>
              <bitWidth>3</bitWidth>
            </field>
            <field>
              <name>RXFTIE</name>
              <bitOffset>28</bitOffset>
              <bitWidth>1</bitWidth>
            </field>
            <field>
              <name>TXFTCFG</name>
              <bitOffset>29</bitOffset>
              <bitWidth>3</bitWidth>
            </field>
          </fields>
        </register>
        <register>
          <name>BRR</name>
          <addressOffset>0xc</addressOffset>
          <size>0x20</size>
          <fields>
            <field>
              <name>DIV_FRACTION</name>
              <bitOffset>0</bitOffset>
              <bitWidth>4</bitWidth>
            </field>
            <field>
              <name>DIV_MANTISSA</name>
              <bitOffset>4</bitOffset>
              <bitWidth>12</bitWidth>
            </field>
          </fields>
        </register>
        <register>
          <name>GTPR</name>
          <addressOffset>0x10</addressOffset>
          <size>0x20</size>
          <fields>
            <field>
              <name>PSC</name>
              <bitOffset>0</bitOffset>
              <bitWidth>8</bitWidth>
            </field>
            <field>
              <name>GT</name>
              <bitOffset>8</bitOffset>
              <bitWidth>8</bitWidth>
            </field>
          </fields>
        </register>
        <register>
          <name>RTOR</name>
          <addressOffset>0x14</addressOffset>
          <size>0x20</size>
          <fields>
            <field>
              <name>RTO</name>
              <bitOffset>0</bitOffset>
              <bitWidth>24</bitWidth>
            </field>
            <field>
              <name>BLEN</name>
              <bitOffset>24</bitOffset>
              <bitWidth>8</bitWidth>
            </field>
          </fields>
        </register>
        <register>
          <name>RQR</name>
          <addressOffset>0x18</addressOffset>
          <size>0x20</size>
          <fields>
            <field>
              <name>ABRRQ</name>
              <bitOffset>0</bitOffset>
              <bitWidth>1</bitWidth>
            </field>
            <field>
              <name>SBKRQ</name>
              <bitOffset>1</bitOffset>
              <bitWidth>1</bitWidth>
            </field>
            <field>
              <name>MMRQ</name>
              <bitOffset>2</bitOffset>
              <bitWidth>1</bitWidth>
            </field>
            <field>
              <name>RXFRQ</name>
              <bitOffset>3</bitOffset>
              <bitWidth>1</bitWidth>
            </field>
            <field>
              <name>TXFRQ</name>
              <bitOffset>4</bitOffset>
              <bitWidth>1</bitWidth>
            </field>
          </fields>
        </register>
        <register>
          <name>ISR</name>
          <addressOffset>0x1c</addressOffset>
          <size>0x20</size>
          <fields>
            <field>
              <name>PE</name>
              <bitOffset>0</bitOffset>
              <bitWidth>1</bitWidth>
            </field>
            <field>
              <name>FE</name>
              <bitOffset>1</bitOffset>
              <bitWidth>1</bitWidth>
            </field>
            <field>
              <name>NE</name>
              <bitOffset>2</bitOffset>
              <bitWidth>1</bitWidth>
            </field>
            <field>
              <name>ORE</name>
              <bitOffset>3</bitOffset>
              <bitWidth>1</bitWidth>
            </field>
            <field>
              <name>IDLE</name>
              <bitOffset>4</bitOffset>
              <bitWidth>1</bitWidth>
            </field>
            <field>
              <name>RXNE_RXFNE</name>
              <bitOffset>5</bitOffset>
              <bitWidth>1</bitWidth>
            </field>
            <field>
              <name>TC</name>
              <bitOffset>6</bitOffset>
              <bitWidth>1</bitWidth>
            </field>
            <field>
              <name>TXE_TXFNF</name>
              <bitOffset>7</bitOffset>
              <bitWidth>1</bitWidth>
            </field>
            <field>
              <name>LBDF</name>
              <bitOffset>8</bitOffset>
              <bitWidth>1</bitWidth>
            </field>
            <field>
              <name>CTSIF</name>
              <bitOffset>9</bitOffset>
              <bitWidth>1</bitWidth>
            </field>
            <field>
              <name>CTS</name>
              <bitOffset>10</bitOffset>
              <bitWidth>1</bitWidth>
            </field>
            <field>
              <name>RTOF</name>
              <bitOffset>11</bitOffset>
              <bitWidth>1</bitWidth>
            </field>
            <field>
              <name>EOBF</name>
              <bitOffset>12</bitOffset>
              <bitWidth>1</bitWidth>
            </field>
            <field>
              <name>UDR</name>
              <bitOffset>13</bitOffset>
              <bitWidth>1</bitWidth>
            </field>
            <field>
              <name>ABRE</name>
              <bitOffset>14</bitOffset>
              <bitWidth>1</bitWidth>
            </field>
            <field>
              <name>ABRF</name>
              <bitOffset>15</bitOffset>
              <bitWidth>1</bitWidth>
            </field>
            <field>
              <name>BUSY</name>
              <bitOffset>16</bitOffset>
              <bitWidth>1</bitWidth>
            </field>
            <field>
              <name>CMF</name>
              <bitOffset>17</bitOffset>
              <bitWidth>1</bitWidth>
            </field>
            <field>
              <name>SBKF</name>
              <bitOffset>18</bitOffset>
              <bitWidth>1</bitWidth>
            </field>
            <field>
              <name>RWU</name>
              <bitOffset>19</bitOffset>
              <bitWidth>1</bitWidth>
            </field>
            <field>
              <name>WUF</name>
              <bitOffset>20</bitOffset>
              <bitWidth>1</bitWidth>
            </field>
            <field>
              <name>TEACK</name>
              <bitOffset>21</bitOffset>
              <bitWidth>1</bitWidth>
            </field>
            <field>
              <name>REACK</name>
              <bitOffset>22</bitOffset>
              <bitWidth>1</bitWidth>
            </field>
            <field>
              <name>TXFE</name>
              <bitOffset>23</bitOffset>
              <bitWidth>1</bitWidth>
            </field>
            <field>
              <name>RXFF</name>
              <bitOffset>24</bitOffset>
              <bitWidth>1</bitWidth>
            </field>
            <field>
              <name>TCBGT</name>
              <bitOffset>25</bitOffset>
              <bitWidth>1</bitWidth>
            </field>
            <field>
              <name>RXFT</name>
              <bitOffset>26</bitOffset>
              <bitWidth>1</bitWidth>
            </field>
            <field>
              <name>TXFT</name>
              <bitOffset>27</bitOffset>
              <bitWidth>1</bitWidth>
            </field>
          </fields>
        </register>
        <register>
          <name>ICR</name>
          <addressOffset>0x20</addressOffset>
          <size>0x20</size>
          <fields>
            <field>
              <name>PECF</name>
              <bitOffset>0</bitOffset>
              <bitWidth>1</bitWidth>
            </field>
            <field>
              <name>FECF</name>
              <bitOffset>1</bitOffset>
              <bitWidth>1</bitWidth>
            </field>
            <field>
              <name>NECF</name>
              <bitOffset>2</bitOffset>
              <bitWidth>1</bitWidth>
            </field>
            <field>
              <name>ORECF</name>
              <bitOffset>3</bitOffset>
              <bitWidth>1</bitWidth>
            </field>
            <field>
              <name>IDLECF</name>
              <bitOffset>4</bitOffset>
              <bitWidth>1</bitWidth>
            </field>
            <field>
              <name>TXFECF</name>
              <bitOffset>5</bitOffset>
              <bitWidth>1</bitWidth>
            </field>
            <field>
              <name>TCCF</name>
              <bitOffset>6</bitOffset>
              <bitWidth>1</bitWidth>
            </field>
            <field>
              <name>TCBGTCF</name>
              <bitOffset>7</bitOffset>
              <bitWidth>1</bitWidth>
            </field>
            <field>
              <name>LBDCF</name>
              <bitOffset>8</bitOffset>
              <bitWidth>1</bitWidth>
            </field>
            <field>
              <name>CTSCF</name>
              <bitOffset>9</bitOffset>
              <bitWidth>1</bitWidth>
            </field>
            <field>
              <name>RTOCF</name>
              <bitOffset>11</bitOffset>
              <bitWidth>1</bitWidth>
            </field>
            <field>
              <name>EOBCF</name>
              <bitOffset>12</bitOffset>
              <bitWidth>1</bitWidth>
            </field>
            <field>
              <name>UDRCF</name>
              <bitOffset>13</bitOffset>
              <bitWidth>1</bitWidth>
            </field>
            <field>
              <name>CMCF</name>
              <bitOffset>17</bitOffset>
              <bitWidth>1</bitWidth>
            </field>
            <field>
              <name>WUCF</name>
              <bitOffset>20</bitOffset>
              <bitWidth>1</bitWidth>
            </field>
          </fields>
        </register>
        <register>
          <name>RDR</name>
          <addressOffset>0x24</addressOffset>
          <size>0x20</size>
          <fields>
            <field>
              <name>RDR</name>
              <bitOffset>0</bitOffset>
              <bitWidth>9</bitWidth>
            </field>
          </fields>
        </register>
        <register>
          <name>TDR</name>
          <addressOffset>0x28</addressOffset>
          <size>0x20</size>
          <fields>
            <field>
              <name>TDR</name>
              <bitOffset>0</bitOffset>
              <bitWidth>9</bitWidth>
            </field>
          </fields>
        </register>
        <register>
          <name>PRESC</name>
          <addressOffset>0x2c</addressOffset>
          <size>0x20</size>
          <fields>
            <field>
              <name>PRESCALER</name>
              <bitOffset>0</bitOffset>
              <bitWidth>4</bitWidth>
            </field>
          </fields>
        </register>
      </registers>
    </peripheral>
    <peripheral>
      <name>SPI6</name>
      <baseAddress>0x58001400</baseAddress>
      <registers>
        <register>
          <name>CR1</name>
          <addressOffset>0x0</addressOffset>
          <size>0x20</size>
          <fields>
            <field>
              <name>SPE</name>
              <bitOffset>0</bitOffset>
              <bitWidth>1</bitWidth>
            </field>
            <field>
              <name>MASRX</name>
              <bitOffset>8</bitOffset>
              <bitWidth>1</bitWidth>
            </field>
            <field>
              <name>CSTART</name>
              <bitOffset>9</bitOffset>
              <bitWidth>1</bitWidth>
            </field>
            <field>
              <name>CSUSP</name>
              <bitOffset>10</bitOffset>
              <bitWidth>1</bitWidth>
            </field>
            <field>
              <name>HDDIR</name>
              <bitOffset>11</bitOffset>
              <bitWidth>1</bitWidth>
            </field>
            <field>
              <name>SSI</name>
              <bitOffset>12</bitOffset>
              <bitWidth>1</bitWidth>
            </field>
            <field>
              <name>CRC33_17</name>
              <bitOffset>13</bitOffset>
              <bitWidth>1</bitWidth>
            </field>
            <field>
              <name>RCRCINI</name>
              <bitOffset>14</bitOffset>
              <bitWidth>1</bitWidth>
            </field>
            <field>
              <name>TCRCINI</name>
              <bitOffset>15</bitOffset>
              <bitWidth>1</bitWidth>
            </field>
            <field>
              <name>IOLOCK</name>
              <bitOffset>16</bitOffset>
              <bitWidth>1</bitWidth>
            </field>
          </fields>
        </register>
        <register>
          <name>CR2</name>
          <addressOffset>0x4</addressOffset>
          <size>0x20</size>
          <fields>
            <field>
              <name>TSIZE</name>
              <bitOffset>0</bitOffset>
              <bitWidth>16</bitWidth>
            </field>
            <field>
              <name>TSER</name>
              <bitOffset>16</bitOffset>
              <bitWidth>16</bitWidth>
            </field>
          </fields>
        </register>
        <register>
          <name>CFG1</name>
          <addressOffset>0x8</addressOffset>
          <size>0x20</size>
          <fields>
            <field>
              <name>DSIZE</name>
              <bitOffset>0</bitOffset>
              <bitWidth>5</bitWidth>
            </field>
            <field>
              <name>FTHLV</name>
              <bitOffset>5</bitOffset>
              <bitWidth>4</bitWidth>
            </field>
            <field>
              <name>UDRCFG</name>
              <bitOffset>9</bitOffset>
              <bitWidth>2</bitWidth>
            </field>
            <field>
              <name>UDRDET</name>
              <bitOffset>11</bitOffset>
              <bitWidth>2</bitWidth>
            </field>
            <field>
              <name>RXDMAEN</name>
              <bitOffset>14</bitOffset>
              <bitWidth>1</bitWidth>
            </field>
            <field>
              <name>TXDMAEN</name>
              <bitOffset>15</bitOffset>
              <bitWidth>1</bitWidth>
            </field>
            <field>
              <name>CRCSIZE</name>
              <bitOffset>16</bitOffset>
              <bitWidth>5</bitWidth>
            </field>
            <field>
              <name>CRCEN</name>
              <bitOffset>22</bitOffset>
              <bitWidth>1</bitWidth>
            </field>
            <field>
              <name>MBR</name>
              <bitOffset>28</bitOffset>
              <bitWidth>3</bitWidth>
            </field>
          </fields>
        </register>
        <register>
          <name>CFG2</name>
          <addressOffset>0xc</addressOffset>
          <size>0x20</size>
          <fields>
            <field>
              <name>MSSI</name>
              <bitOffset>0</bitOffset>
              <bitWidth>4</bitWidth>
            </field>
            <field>
              <name>MIDI</name>
              <bitOffset>4</bitOffset>
              <bitWidth>4</bitWidth>
            </field>
            <field>
              <name>IOSWP</name>
              <bitOffset>15</bitOffset>
              <bitWidth>1</bitWidth>
            </field>
            <field>
              <name>COMM</name>
              <bitOffset>17</bitOffset>
              <bitWidth>2</bitWidth>
            </field>
            <field>
              <name>SP</name>
              <bitOffset>19</bitOffset>
              <bitWidth>3</bitWidth>
            </field>
            <field>
              <name>MASTER</name>
              <bitOffset>22</bitOffset>
              <bitWidth>1</bitWidth>
            </field>
            <field>
              <name>LSBFRST</name>
              <bitOffset>23</bitOffset>
              <bitWidth>1</bitWidth>
            </field>
            <field>
              <name>CPHA</name>
              <bitOffset>24</bitOffset>
              <bitWidth>1</bitWidth>
            </field>
            <field>
              <name>CPOL</name>
              <bitOffset>25</bitOffset>
              <bitWidth>1</bitWidth>
            </field>
            <field>
              <name>SSM</name>
              <bitOffset>26</bitOffset>
              <bitWidth>1</bitWidth>
            </field>
            <field>
              <name>SSIOP</name>
              <bitOffset>28</bitOffset>
              <bitWidth>1</bitWidth>
            </field>
            <field>
              <name>SSOE</name>
              <bitOffset>29</bitOffset>
              <bitWidth>1</bitWidth>
            </field>
            <field>
              <name>SSOM</name>
              <bitOffset>30</bitOffset>
              <bitWidth>1</bitWidth>
            </field>
            <field>
              <name>AFCNTR</name>
              <bitOffset>31</bitOffset>
              <bitWidth>1</bitWidth>
            </field>
          </fields>
        </register>
        <register>
          <name>IER</name>
          <addressOffset>0x10</addressOffset>
          <size>0x20</size>
          <fields>
            <field>
              <name>RXPIE</name>
              <bitOffset>0</bitOffset>
              <bitWidth>1</bitWidth>
            </field>
            <field>
              <name>TXPIE</name>
              <bitOffset>1</bitOffset>
              <bitWidth>1</bitWidth>
            </field>
            <field>
              <name>DXPIE</name>
              <bitOffset>2</bitOffset>
              <bitWidth>1</bitWidth>
            </field>
            <field>
              <name>EOTIE</name>
              <bitOffset>3</bitOffset>
              <bitWidth>1</bitWidth>
            </field>
            <field>
              <name>TXTFIE</name>
              <bitOffset>4</bitOffset>
              <bitWidth>1</bitWidth>
            </field>
            <field>
              <name>UDRIE</name>
              <bitOffset>5</bitOffset>
              <bitWidth>1</bitWidth>
            </field>
            <field>
              <name>OVRIE</name>
              <bitOffset>6</bitOffset>
              <bitWidth>1</bitWidth>
            </field>
            <field>
              <name>CRCEIE</name>
              <bitOffset>7</bitOffset>
              <bitWidth>1</bitWidth>
            </field>
            <field>
              <name>TIFREIE</name>
              <bitOffset>8</bitOffset>
              <bitWidth>1</bitWidth>
            </field>
            <field>
              <name>MODFIE</name>
              <bitOffset>9</bitOffset>
              <bitWidth>1</bitWidth>
            </field>
            <field>
              <name>TSERFIE</name>
              <bitOffset>10</bitOffset>
              <bitWidth>1</bitWidth>
            </field>
          </fields>
        </register>
        <register>
          <name>SR</name>
          <addressOffset>0x14</addressOffset>
          <size>0x20</size>
          <fields>
            <field>
              <name>RXP</name>
              <bitOffset>0</bitOffset>
              <bitWidth>1</bitWidth>
            </field>
            <field>
              <name>TXP</name>
              <bitOffset>1</bitOffset>
              <bitWidth>1</bitWidth>
            </field>
            <field>
              <name>DXP</name>
              <bitOffset>2</bitOffset>
              <bitWidth>1</bitWidth>
            </field>
            <field>
              <name>EOT</name>
              <bitOffset>3</bitOffset>
              <bitWidth>1</bitWidth>
            </field>
            <field>
              <name>TXTF</name>
              <bitOffset>4</bitOffset>
              <bitWidth>1</bitWidth>
            </field>
            <field>
              <name>UDR</name>
              <bitOffset>5</bitOffset>
              <bitWidth>1</bitWidth>
            </field>
            <field>
              <name>OVR</name>
              <bitOffset>6</bitOffset>
              <bitWidth>1</bitWidth>
            </field>
            <field>
              <name>CRCE</name>
              <bitOffset>7</bitOffset>
              <bitWidth>1</bitWidth>
            </field>
            <field>
              <name>TIFRE</name>
              <bitOffset>8</bitOffset>
              <bitWidth>1</bitWidth>
            </field>
            <field>
              <name>MODF</name>
              <bitOffset>9</bitOffset>
              <bitWidth>1</bitWidth>
            </field>
            <field>
              <name>TSERF</name>
              <bitOffset>10</bitOffset>
              <bitWidth>1</bitWidth>
            </field>
            <field>
              <name>SUSP</name>
              <bitOffset>11</bitOffset>
              <bitWidth>1</bitWidth>
            </field>
            <field>
              <name>TXC</name>
              <bitOffset>12</bitOffset>
              <bitWidth>1</bitWidth>
            </field>
            <field>
              <name>RXPLVL</name>
              <bitOffset>13</bitOffset>
              <bitWidth>2</bitWidth>
            </field>
            <field>
              <name>RXWNE</name>
              <bitOffset>15</bitOffset>
              <bitWidth>1</bitWidth>
            </field>
            <field>
              <name>CTSIZE</name>
              <bitOffset>16</bitOffset>
              <bitWidth>16</bitWidth>
            </field>
          </fields>
        </register>
        <register>
          <name>IFCR</name>
          <addressOffset>0x18</addressOffset>
          <size>0x20</size>
          <fields>
            <field>
              <name>EOTC</name>
              <bitOffset>3</bitOffset>
              <bitWidth>1</bitWidth>
            </field>
            <field>
              <name>TXTFC</name>
              <bitOffset>4</bitOffset>
              <bitWidth>1</bitWidth>
            </field>
            <field>
              <name>UDRC</name>
              <bitOffset>5</bitOffset>
              <bitWidth>1</bitWidth>
            </field>
            <field>
              <name>OVRC</name>
              <bitOffset>6</bitOffset>
              <bitWidth>1</bitWidth>
            </field>
            <field>
              <name>CRCEC</name>
              <bitOffset>7</bitOffset>
              <bitWidth>1</bitWidth>
            </field>
            <field>
              <name>TIFREC</name>
              <bitOffset>8</bitOffset>
              <bitWidth>1</bitWidth>
            </field>
            <field>
              <name>MODFC</name>
              <bitOffset>9</bitOffset>
              <bitWidth>1</bitWidth>
            </field>
            <field>
              <name>TSERFC</name>
              <bitOffset>10</bitOffset>
              <bitWidth>1</bitWidth>
            </field>
            <field>
              <name>SUSPC</name>
              <bitOffset>11</bitOffset>
              <bitWidth>1</bitWidth>
            </field>
          </fields>
        </register>
        <register>
          <name>TXDR</name>
          <addressOffset>0x20</addressOffset>
          <size>0x20</size>
          <fields>
            <field>
              <name>TXDR</name>
              <bitOffset>0</bitOffset>
              <bitWidth>32</bitWidth>
            </field>
          </fields>
        </register>
        <register>
          <name>RXDR</name>
          <addressOffset>0x30</addressOffset>
          <size>0x20</size>
          <fields>
            <field>
              <name>RXDR</name>
              <bitOffset>0</bitOffset>
              <bitWidth>32</bitWidth>
            </field>
          </fields>
        </register>
        <register>
          <name>CRCPOLY</name>
          <addressOffset>0x40</addressOffset>
          <size>0x20</size>
          <fields>
            <field>
              <name>CRCPOLY</name>
              <bitOffset>0</bitOffset>
              <bitWidth>32</bitWidth>
            </field>
          </fields>
        </register>
        <register>
          <name>TXCRC</name>
          <addressOffset>0x44</addressOffset>
          <size>0x20</size>
          <fields>
            <field>
              <name>TXCRC</name>
              <bitOffset>0</bitOffset>
              <bitWidth>32</bitWidth>
            </field>
          </fields>
        </register>
        <register>
          <name>RXCRC</name>
          <addressOffset>0x48</addressOffset>
          <size>0x20</size>
          <fields>
            <field>
              <name>RXCRC</name>
              <bitOffset>0</bitOffset>
              <bitWidth>32</bitWidth>
            </field>
          </fields>
        </register>
        <register>
          <name>UDRDR</name>
          <addressOffset>0x4c</addressOffset>
          <size>0x20</size>
          <fields>
            <field>
              <name>UDRDR</name>
              <bitOffset>0</bitOffset>
              <bitWidth>32</bitWidth>
            </field>
          </fields>
        </register>
        <register>
          <name>I2SCFGR</name>
          <addressOffset>0x50</addressOffset>
          <size>0x20</size>
          <fields>
            <field>
              <name>I2SMOD</name>
              <bitOffset>0</bitOffset>
              <bitWidth>1</bitWidth>
            </field>
            <field>
              <name>I2SCFG</name>
              <bitOffset>1</bitOffset>
              <bitWidth>3</bitWidth>
            </field>
            <field>
              <name>I2SSTD</name>
              <bitOffset>4</bitOffset>
              <bitWidth>2</bitWidth>
            </field>
            <field>
              <name>PCMSYNC</name>
              <bitOffset>7</bitOffset>
              <bitWidth>1</bitWidth>
            </field>
            <field>
              <name>DATLEN</name>
              <bitOffset>8</bitOffset>
              <bitWidth>2</bitWidth>
            </field>
            <field>
              <name>CHLEN</name>
              <bitOffset>10</bitOffset>
              <bitWidth>1</bitWidth>
            </field>
            <field>
              <name>CKPOL</name>
              <bitOffset>11</bitOffset>
              <bitWidth>1</bitWidth>
            </field>
            <field>
              <name>FIXCH</name>
              <bitOffset>12</bitOffset>
              <bitWidth>1</bitWidth>
            </field>
            <field>
              <name>WSINV</name>
              <bitOffset>13</bitOffset>
              <bitWidth>1</bitWidth>
            </field>
            <field>
              <name>DATFMT</name>
              <bitOffset>14</bitOffset>
              <bitWidth>1</bitWidth>
            </field>
            <field>
              <name>I2SDIV</name>
              <bitOffset>16</bitOffset>
              <bitWidth>8</bitWidth>
            </field>
            <field>
              <name>ODD</name>
              <bitOffset>24</bitOffset>
              <bitWidth>1</bitWidth>
            </field>
            <field>
              <name>MCKOE</name>
              <bitOffset>25</bitOffset>
              <bitWidth>1</bitWidth>
            </field>
          </fields>
        </register>
      </registers>
    </peripheral>
    <peripheral>
      <name>I2C4</name>
      <baseAddress>0x58001c00</baseAddress>
      <registers>
        <register>
          <name>CR1</name>
          <addressOffset>0x0</addressOffset>
          <size>0x20</size>
          <fields>
            <field>
              <name>PE</name>
              <bitOffset>0</bitOffset>
              <bitWidth>1</bitWidth>
            </field>
            <field>
              <name>TXIE</name>
              <bitOffset>1</bitOffset>
              <bitWidth>1</bitWidth>
            </field>
            <field>
              <name>RXIE</name>
              <bitOffset>2</bitOffset>
              <bitWidth>1</bitWidth>
            </field>
            <field>
              <name>ADDRIE</name>
              <bitOffset>3</bitOffset>
              <bitWidth>1</bitWidth>
            </field>
            <field>
              <name>NACKIE</name>
              <bitOffset>4</bitOffset>
              <bitWidth>1</bitWidth>
            </field>
            <field>
              <name>STOPIE</name>
              <bitOffset>5</bitOffset>
              <bitWidth>1</bitWidth>
            </field>
            <field>
              <name>TCIE</name>
              <bitOffset>6</bitOffset>
              <bitWidth>1</bitWidth>
            </field>
            <field>
              <name>ERRIE</name>
              <bitOffset>7</bitOffset>
              <bitWidth>1</bitWidth>
            </field>
            <field>
              <name>DNF</name>
              <bitOffset>8</bitOffset>
              <bitWidth>4</bitWidth>
            </field>
            <field>
              <name>ANFOFF</name>
              <bitOffset>12</bitOffset>
              <bitWidth>1</bitWidth>
            </field>
            <field>
              <name>TXDMAEN</name>
              <bitOffset>14</bitOffset>
              <bitWidth>1</bitWidth>
            </field>
            <field>
              <name>RXDMAEN</name>
              <bitOffset>15</bitOffset>
              <bitWidth>1</bitWidth>
            </field>
            <field>
              <name>SBC</name>
              <bitOffset>16</bitOffset>
              <bitWidth>1</bitWidth>
            </field>
            <field>
              <name>NOSTRETCH</name>
              <bitOffset>17</bitOffset>
              <bitWidth>1</bitWidth>
            </field>
            <field>
              <name>WUPEN</name>
              <bitOffset>18</bitOffset>
              <bitWidth>1</bitWidth>
            </field>
            <field>
              <name>GCEN</name>
              <bitOffset>19</bitOffset>
              <bitWidth>1</bitWidth>
            </field>
            <field>
              <name>SMBHEN</name>
              <bitOffset>20</bitOffset>
              <bitWidth>1</bitWidth>
            </field>
            <field>
              <name>SMBDEN</name>
              <bitOffset>21</bitOffset>
              <bitWidth>1</bitWidth>
            </field>
            <field>
              <name>ALERTEN</name>
              <bitOffset>22</bitOffset>
              <bitWidth>1</bitWidth>
            </field>
            <field>
              <name>PECEN</name>
              <bitOffset>23</bitOffset>
              <bitWidth>1</bitWidth>
            </field>
          </fields>
        </register>
        <register>
          <name>CR2</name>
          <addressOffset>0x4</addressOffset>
          <size>0x20</size>
          <fields>
            <field>
              <name>SADD</name>
              <bitOffset>0</bitOffset>
              <bitWidth>10</bitWidth>
            </field>
            <field>
              <name>RD_WRN</name>
              <bitOffset>10</bitOffset>
              <bitWidth>1</bitWidth>
            </field>
            <field>
              <name>ADD10</name>
              <bitOffset>11</bitOffset>
              <bitWidth>1</bitWidth>
            </field>
            <field>
              <name>HEAD10R</name>
              <bitOffset>12</bitOffset>
              <bitWidth>1</bitWidth>
            </field>
            <field>
              <name>START</name>
              <bitOffset>13</bitOffset>
              <bitWidth>1</bitWidth>
            </field>
            <field>
              <name>STOP</name>
              <bitOffset>14</bitOffset>
              <bitWidth>1</bitWidth>
            </field>
            <field>
              <name>NACK</name>
              <bitOffset>15</bitOffset>
              <bitWidth>1</bitWidth>
            </field>
            <field>
              <name>NBYTES</name>
              <bitOffset>16</bitOffset>
              <bitWidth>8</bitWidth>
            </field>
            <field>
              <name>RELOAD</name>
              <bitOffset>24</bitOffset>
              <bitWidth>1</bitWidth>
            </field>
            <field>
              <name>AUTOEND</name>
              <bitOffset>25</bitOffset>
              <bitWidth>1</bitWidth>
            </field>
            <field>
              <name>PECBYTE</name>
              <bitOffset>26</bitOffset>
              <bitWidth>1</bitWidth>
            </field>
          </fields>
        </register>
        <register>
          <name>OAR1</name>
          <addressOffset>0x8</addressOffset>
          <size>0x20</size>
          <fields>
            <field>
              <name>OA1</name>
              <bitOffset>0</bitOffset>
              <bitWidth>10</bitWidth>
            </field>
            <field>
              <name>OA1MODE</name>
              <bitOffset>10</bitOffset>
              <bitWidth>1</bitWidth>
            </field>
            <field>
              <name>OA1EN</name>
              <bitOffset>15</bitOffset>
              <bitWidth>1</bitWidth>
            </field>
          </fields>
        </register>
        <register>
          <name>OAR2</name>
          <addressOffset>0xc</addressOffset>
          <size>0x20</size>
          <fields>
            <field>
              <name>OA2</name>
              <bitOffset>1</bitOffset>
              <bitWidth>7</bitWidth>
            </field>
            <field>
              <name>OA2MSK</name>
              <bitOffset>8</bitOffset>
              <bitWidth>3</bitWidth>
            </field>
            <field>
              <name>OA2MASK06</name>
              <bitOffset>9</bitOffset>
              <bitWidth>2</bitWidth>
            </field>
            <field>
              <name>OA2MASK04</name>
              <bitOffset>10</bitOffset>
              <bitWidth>1</bitWidth>
            </field>
            <field>
              <name>OA2EN</name>
              <bitOffset>15</bitOffset>
              <bitWidth>1</bitWidth>
            </field>
          </fields>
        </register>
        <register>
          <name>TIMINGR</name>
          <addressOffset>0x10</addressOffset>
          <size>0x20</size>
          <fields>
            <field>
              <name>SCLL</name>
              <bitOffset>0</bitOffset>
              <bitWidth>8</bitWidth>
            </field>
            <field>
              <name>SCLH</name>
              <bitOffset>8</bitOffset>
              <bitWidth>8</bitWidth>
            </field>
            <field>
              <name>SDADEL</name>
              <bitOffset>16</bitOffset>
              <bitWidth>4</bitWidth>
            </field>
            <field>
              <name>SCLDEL</name>
              <bitOffset>20</bitOffset>
              <bitWidth>4</bitWidth>
            </field>
            <field>
              <name>PRESC</name>
              <bitOffset>28</bitOffset>
              <bitWidth>4</bitWidth>
            </field>
          </fields>
        </register>
        <register>
          <name>TIMEOUTR</name>
          <addressOffset>0x14</addressOffset>
          <size>0x20</size>
          <fields>
            <field>
              <name>TIMEOUTA</name>
              <bitOffset>0</bitOffset>
              <bitWidth>12</bitWidth>
            </field>
            <field>
              <name>TIDLE</name>
              <bitOffset>12</bitOffset>
              <bitWidth>1</bitWidth>
            </field>
            <field>
              <name>TIMOUTEN</name>
              <bitOffset>15</bitOffset>
              <bitWidth>1</bitWidth>
            </field>
            <field>
              <name>TIMEOUTB</name>
              <bitOffset>16</bitOffset>
              <bitWidth>12</bitWidth>
            </field>
            <field>
              <name>TEXTEN</name>
              <bitOffset>31</bitOffset>
              <bitWidth>1</bitWidth>
            </field>
          </fields>
        </register>
        <register>
          <name>ISR</name>
          <addressOffset>0x18</addressOffset>
          <size>0x20</size>
          <fields>
            <field>
              <name>TXE</name>
              <bitOffset>0</bitOffset>
              <bitWidth>1</bitWidth>
            </field>
            <field>
              <name>TXIS</name>
              <bitOffset>1</bitOffset>
              <bitWidth>1</bitWidth>
            </field>
            <field>
              <name>RXNE</name>
              <bitOffset>2</bitOffset>
              <bitWidth>1</bitWidth>
            </field>
            <field>
              <name>ADDR</name>
              <bitOffset>3</bitOffset>
              <bitWidth>1</bitWidth>
            </field>
            <field>
              <name>NACKF</name>
              <bitOffset>4</bitOffset>
              <bitWidth>1</bitWidth>
            </field>
            <field>
              <name>STOPF</name>
              <bitOffset>5</bitOffset>
              <bitWidth>1</bitWidth>
            </field>
            <field>
              <name>TC</name>
              <bitOffset>6</bitOffset>
              <bitWidth>1</bitWidth>
            </field>
            <field>
              <name>TCR</name>
              <bitOffset>7</bitOffset>
              <bitWidth>1</bitWidth>
            </field>
            <field>
              <name>BERR</name>
              <bitOffset>8</bitOffset>
              <bitWidth>1</bitWidth>
            </field>
            <field>
              <name>ARLO</name>
              <bitOffset>9</bitOffset>
              <bitWidth>1</bitWidth>
            </field>
            <field>
              <name>OVR</name>
              <bitOffset>10</bitOffset>
              <bitWidth>1</bitWidth>
            </field>
            <field>
              <name>PECERR</name>
              <bitOffset>11</bitOffset>
              <bitWidth>1</bitWidth>
            </field>
            <field>
              <name>TIMEOUT</name>
              <bitOffset>12</bitOffset>
              <bitWidth>1</bitWidth>
            </field>
            <field>
              <name>ALERT</name>
              <bitOffset>13</bitOffset>
              <bitWidth>1</bitWidth>
            </field>
            <field>
              <name>BUSY</name>
              <bitOffset>15</bitOffset>
              <bitWidth>1</bitWidth>
            </field>
            <field>
              <name>DIR</name>
              <bitOffset>16</bitOffset>
              <bitWidth>1</bitWidth>
            </field>
            <field>
              <name>ADDCODE</name>
              <bitOffset>17</bitOffset>
              <bitWidth>7</bitWidth>
            </field>
          </fields>
        </register>
        <register>
          <name>ICR</name>
          <addressOffset>0x1c</addressOffset>
          <size>0x20</size>
          <fields>
            <field>
              <name>ADDRCF</name>
              <bitOffset>3</bitOffset>
              <bitWidth>1</bitWidth>
            </field>
            <field>
              <name>NACKCF</name>
              <bitOffset>4</bitOffset>
              <bitWidth>1</bitWidth>
            </field>
            <field>
              <name>STOPCF</name>
              <bitOffset>5</bitOffset>
              <bitWidth>1</bitWidth>
            </field>
            <field>
              <name>BERRCF</name>
              <bitOffset>8</bitOffset>
              <bitWidth>1</bitWidth>
            </field>
            <field>
              <name>ARLOCF</name>
              <bitOffset>9</bitOffset>
              <bitWidth>1</bitWidth>
            </field>
            <field>
              <name>OVRCF</name>
              <bitOffset>10</bitOffset>
              <bitWidth>1</bitWidth>
            </field>
            <field>
              <name>PECCF</name>
              <bitOffset>11</bitOffset>
              <bitWidth>1</bitWidth>
            </field>
            <field>
              <name>TIMOUTCF</name>
              <bitOffset>12</bitOffset>
              <bitWidth>1</bitWidth>
            </field>
            <field>
              <name>ALERTCF</name>
              <bitOffset>13</bitOffset>
              <bitWidth>1</bitWidth>
            </field>
          </fields>
        </register>
        <register>
          <name>PECR</name>
          <addressOffset>0x20</addressOffset>
          <size>0x20</size>
          <fields>
            <field>
              <name>PEC</name>
              <bitOffset>0</bitOffset>
              <bitWidth>8</bitWidth>
            </field>
          </fields>
        </register>
        <register>
          <name>RXDR</name>
          <addressOffset>0x24</addressOffset>
          <size>0x20</size>
          <fields>
            <field>
              <name>RXDATA</name>
              <bitOffset>0</bitOffset>
              <bitWidth>8</bitWidth>
            </field>
          </fields>
        </register>
        <register>
          <name>TXDR</name>
          <addressOffset>0x28</addressOffset>
          <size>0x20</size>
          <fields>
            <field>
              <name>TXDATA</name>
              <bitOffset>0</bitOffset>
              <bitWidth>8</bitWidth>
            </field>
          </fields>
        </register>
      </registers>
    </peripheral>
    <peripheral>
      <name>LPTIM2</name>
      <baseAddress>0x58002400</baseAddress>
      <registers>
        <register>
          <name>ISR</name>
          <addressOffset>0x0</addressOffset>
          <size>0x20</size>
          <fields>
            <field>
              <name>CMPM</name>
              <bitOffset>0</bitOffset>
              <bitWidth>1</bitWidth>
            </field>
            <field>
              <name>ARRM</name>
              <bitOffset>1</bitOffset>
              <bitWidth>1</bitWidth>
            </field>
            <field>
              <name>EXTTRIG</name>
              <bitOffset>2</bitOffset>
              <bitWidth>1</bitWidth>
            </field>
            <field>
              <name>CMPOK</name>
              <bitOffset>3</bitOffset>
              <bitWidth>1</bitWidth>
            </field>
            <field>
              <name>ARROK</name>
              <bitOffset>4</bitOffset>
              <bitWidth>1</bitWidth>
            </field>
            <field>
              <name>UP</name>
              <bitOffset>5</bitOffset>
              <bitWidth>1</bitWidth>
            </field>
            <field>
              <name>DOWN</name>
              <bitOffset>6</bitOffset>
              <bitWidth>1</bitWidth>
            </field>
          </fields>
        </register>
        <register>
          <name>ICR</name>
          <addressOffset>0x4</addressOffset>
          <size>0x20</size>
          <fields>
            <field>
              <name>CMPMCF</name>
              <bitOffset>0</bitOffset>
              <bitWidth>1</bitWidth>
            </field>
            <field>
              <name>ARRMCF</name>
              <bitOffset>1</bitOffset>
              <bitWidth>1</bitWidth>
            </field>
            <field>
              <name>EXTTRIGCF</name>
              <bitOffset>2</bitOffset>
              <bitWidth>1</bitWidth>
            </field>
            <field>
              <name>CMPOKCF</name>
              <bitOffset>3</bitOffset>
              <bitWidth>1</bitWidth>
            </field>
            <field>
              <name>ARROKCF</name>
              <bitOffset>4</bitOffset>
              <bitWidth>1</bitWidth>
            </field>
            <field>
              <name>UPCF</name>
              <bitOffset>5</bitOffset>
              <bitWidth>1</bitWidth>
            </field>
            <field>
              <name>DOWNCF</name>
              <bitOffset>6</bitOffset>
              <bitWidth>1</bitWidth>
            </field>
          </fields>
        </register>
        <register>
          <name>IER</name>
          <addressOffset>0x8</addressOffset>
          <size>0x20</size>
          <fields>
            <field>
              <name>CMPMIE</name>
              <bitOffset>0</bitOffset>
              <bitWidth>1</bitWidth>
            </field>
            <field>
              <name>ARRMIE</name>
              <bitOffset>1</bitOffset>
              <bitWidth>1</bitWidth>
            </field>
            <field>
              <name>EXTTRIGIE</name>
              <bitOffset>2</bitOffset>
              <bitWidth>1</bitWidth>
            </field>
            <field>
              <name>CMPOKIE</name>
              <bitOffset>3</bitOffset>
              <bitWidth>1</bitWidth>
            </field>
            <field>
              <name>ARROKIE</name>
              <bitOffset>4</bitOffset>
              <bitWidth>1</bitWidth>
            </field>
            <field>
              <name>UPIE</name>
              <bitOffset>5</bitOffset>
              <bitWidth>1</bitWidth>
            </field>
            <field>
              <name>DOWNIE</name>
              <bitOffset>6</bitOffset>
              <bitWidth>1</bitWidth>
            </field>
          </fields>
        </register>
        <register>
          <name>CFGR</name>
          <addressOffset>0xc</addressOffset>
          <size>0x20</size>
          <fields>
            <field>
              <name>CKSEL</name>
              <bitOffset>0</bitOffset>
              <bitWidth>1</bitWidth>
            </field>
            <field>
              <name>CKPOL</name>
              <bitOffset>1</bitOffset>
              <bitWidth>2</bitWidth>
            </field>
            <field>
              <name>CKFLT</name>
              <bitOffset>3</bitOffset>
              <bitWidth>2</bitWidth>
            </field>
            <field>
              <name>TRGFLT</name>
              <bitOffset>6</bitOffset>
              <bitWidth>2</bitWidth>
            </field>
            <field>
              <name>PRESC</name>
              <bitOffset>9</bitOffset>
              <bitWidth>3</bitWidth>
            </field>
            <field>
              <name>TRIGSEL</name>
              <bitOffset>13</bitOffset>
              <bitWidth>3</bitWidth>
            </field>
            <field>
              <name>TRIGEN</name>
              <bitOffset>17</bitOffset>
              <bitWidth>2</bitWidth>
            </field>
            <field>
              <name>TIMOUT</name>
              <bitOffset>19</bitOffset>
              <bitWidth>1</bitWidth>
            </field>
            <field>
              <name>WAVE</name>
              <bitOffset>20</bitOffset>
              <bitWidth>1</bitWidth>
            </field>
            <field>
              <name>WAVPOL</name>
              <bitOffset>21</bitOffset>
              <bitWidth>1</bitWidth>
            </field>
            <field>
              <name>PRELOAD</name>
              <bitOffset>22</bitOffset>
              <bitWidth>1</bitWidth>
            </field>
            <field>
              <name>COUNTMODE</name>
              <bitOffset>23</bitOffset>
              <bitWidth>1</bitWidth>
            </field>
            <field>
              <name>ENC</name>
              <bitOffset>24</bitOffset>
              <bitWidth>1</bitWidth>
            </field>
          </fields>
        </register>
        <register>
          <name>CR</name>
          <addressOffset>0x10</addressOffset>
          <size>0x20</size>
          <fields>
            <field>
              <name>ENABLE</name>
              <bitOffset>0</bitOffset>
              <bitWidth>1</bitWidth>
            </field>
            <field>
              <name>SNGSTRT</name>
              <bitOffset>1</bitOffset>
              <bitWidth>19</bitWidth>
            </field>
            <field>
              <name>CNTSTRT</name>
              <bitOffset>2</bitOffset>
              <bitWidth>1</bitWidth>
            </field>
            <field>
              <name>COUNTRST</name>
              <bitOffset>3</bitOffset>
              <bitWidth>1</bitWidth>
            </field>
            <field>
              <name>RSTARE</name>
              <bitOffset>4</bitOffset>
              <bitWidth>1</bitWidth>
            </field>
          </fields>
        </register>
        <register>
          <name>CMP</name>
          <addressOffset>0x14</addressOffset>
          <size>0x20</size>
          <fields>
            <field>
              <name>CMP</name>
              <bitOffset>0</bitOffset>
              <bitWidth>16</bitWidth>
            </field>
          </fields>
        </register>
        <register>
          <name>ARR</name>
          <addressOffset>0x18</addressOffset>
          <size>0x20</size>
          <fields>
            <field>
              <name>ARR</name>
              <bitOffset>0</bitOffset>
              <bitWidth>16</bitWidth>
            </field>
          </fields>
        </register>
        <register>
          <name>CNT</name>
          <addressOffset>0x1c</addressOffset>
          <size>0x20</size>
          <fields>
            <field>
              <name>CNT</name>
              <bitOffset>0</bitOffset>
              <bitWidth>16</bitWidth>
            </field>
          </fields>
        </register>
        <register>
          <name>CFGR2</name>
          <addressOffset>0x24</addressOffset>
          <size>0x20</size>
          <fields>
            <field>
              <name>IN1SEL</name>
              <bitOffset>0</bitOffset>
              <bitWidth>2</bitWidth>
            </field>
            <field>
              <name>IN2SEL</name>
              <bitOffset>4</bitOffset>
              <bitWidth>2</bitWidth>
            </field>
          </fields>
        </register>
      </registers>
    </peripheral>
    <peripheral>
      <name>LPTIM3</name>
      <baseAddress>0x58002800</baseAddress>
      <registers>
        <register>
          <name>ISR</name>
          <addressOffset>0x0</addressOffset>
          <size>0x20</size>
          <fields>
            <field>
              <name>CMPM</name>
              <bitOffset>0</bitOffset>
              <bitWidth>1</bitWidth>
            </field>
            <field>
              <name>ARRM</name>
              <bitOffset>1</bitOffset>
              <bitWidth>1</bitWidth>
            </field>
            <field>
              <name>EXTTRIG</name>
              <bitOffset>2</bitOffset>
              <bitWidth>1</bitWidth>
            </field>
            <field>
              <name>CMPOK</name>
              <bitOffset>3</bitOffset>
              <bitWidth>1</bitWidth>
            </field>
            <field>
              <name>ARROK</name>
              <bitOffset>4</bitOffset>
              <bitWidth>1</bitWidth>
            </field>
            <field>
              <name>UP</name>
              <bitOffset>5</bitOffset>
              <bitWidth>1</bitWidth>
            </field>
            <field>
              <name>DOWN</name>
              <bitOffset>6</bitOffset>
              <bitWidth>1</bitWidth>
            </field>
          </fields>
        </register>
        <register>
          <name>ICR</name>
          <addressOffset>0x4</addressOffset>
          <size>0x20</size>
          <fields>
            <field>
              <name>CMPMCF</name>
              <bitOffset>0</bitOffset>
              <bitWidth>1</bitWidth>
            </field>
            <field>
              <name>ARRMCF</name>
              <bitOffset>1</bitOffset>
              <bitWidth>1</bitWidth>
            </field>
            <field>
              <name>EXTTRIGCF</name>
              <bitOffset>2</bitOffset>
              <bitWidth>1</bitWidth>
            </field>
            <field>
              <name>CMPOKCF</name>
              <bitOffset>3</bitOffset>
              <bitWidth>1</bitWidth>
            </field>
            <field>
              <name>ARROKCF</name>
              <bitOffset>4</bitOffset>
              <bitWidth>1</bitWidth>
            </field>
            <field>
              <name>UPCF</name>
              <bitOffset>5</bitOffset>
              <bitWidth>1</bitWidth>
            </field>
            <field>
              <name>DOWNCF</name>
              <bitOffset>6</bitOffset>
              <bitWidth>1</bitWidth>
            </field>
          </fields>
        </register>
        <register>
          <name>IER</name>
          <addressOffset>0x8</addressOffset>
          <size>0x20</size>
          <fields>
            <field>
              <name>CMPMIE</name>
              <bitOffset>0</bitOffset>
              <bitWidth>1</bitWidth>
            </field>
            <field>
              <name>ARRMIE</name>
              <bitOffset>1</bitOffset>
              <bitWidth>1</bitWidth>
            </field>
            <field>
              <name>EXTTRIGIE</name>
              <bitOffset>2</bitOffset>
              <bitWidth>1</bitWidth>
            </field>
            <field>
              <name>CMPOKIE</name>
              <bitOffset>3</bitOffset>
              <bitWidth>1</bitWidth>
            </field>
            <field>
              <name>ARROKIE</name>
              <bitOffset>4</bitOffset>
              <bitWidth>1</bitWidth>
            </field>
            <field>
              <name>UPIE</name>
              <bitOffset>5</bitOffset>
              <bitWidth>1</bitWidth>
            </field>
            <field>
              <name>DOWNIE</name>
              <bitOffset>6</bitOffset>
              <bitWidth>1</bitWidth>
            </field>
          </fields>
        </register>
        <register>
          <name>CFGR</name>
          <addressOffset>0xc</addressOffset>
          <size>0x20</size>
          <fields>
            <field>
              <name>CKSEL</name>
              <bitOffset>0</bitOffset>
              <bitWidth>1</bitWidth>
            </field>
            <field>
              <name>CKPOL</name>
              <bitOffset>1</bitOffset>
              <bitWidth>2</bitWidth>
            </field>
            <field>
              <name>CKFLT</name>
              <bitOffset>3</bitOffset>
              <bitWidth>2</bitWidth>
            </field>
            <field>
              <name>TRGFLT</name>
              <bitOffset>6</bitOffset>
              <bitWidth>2</bitWidth>
            </field>
            <field>
              <name>PRESC</name>
              <bitOffset>9</bitOffset>
              <bitWidth>3</bitWidth>
            </field>
            <field>
              <name>TRIGSEL</name>
              <bitOffset>13</bitOffset>
              <bitWidth>3</bitWidth>
            </field>
            <field>
              <name>TRIGEN</name>
              <bitOffset>17</bitOffset>
              <bitWidth>2</bitWidth>
            </field>
            <field>
              <name>TIMOUT</name>
              <bitOffset>19</bitOffset>
              <bitWidth>1</bitWidth>
            </field>
            <field>
              <name>WAVE</name>
              <bitOffset>20</bitOffset>
              <bitWidth>1</bitWidth>
            </field>
            <field>
              <name>WAVPOL</name>
              <bitOffset>21</bitOffset>
              <bitWidth>1</bitWidth>
            </field>
            <field>
              <name>PRELOAD</name>
              <bitOffset>22</bitOffset>
              <bitWidth>1</bitWidth>
            </field>
            <field>
              <name>COUNTMODE</name>
              <bitOffset>23</bitOffset>
              <bitWidth>1</bitWidth>
            </field>
            <field>
              <name>ENC</name>
              <bitOffset>24</bitOffset>
              <bitWidth>1</bitWidth>
            </field>
          </fields>
        </register>
        <register>
          <name>CR</name>
          <addressOffset>0x10</addressOffset>
          <size>0x20</size>
          <fields>
            <field>
              <name>ENABLE</name>
              <bitOffset>0</bitOffset>
              <bitWidth>1</bitWidth>
            </field>
            <field>
              <name>SNGSTRT</name>
              <bitOffset>1</bitOffset>
              <bitWidth>19</bitWidth>
            </field>
            <field>
              <name>CNTSTRT</name>
              <bitOffset>2</bitOffset>
              <bitWidth>1</bitWidth>
            </field>
            <field>
              <name>COUNTRST</name>
              <bitOffset>3</bitOffset>
              <bitWidth>1</bitWidth>
            </field>
            <field>
              <name>RSTARE</name>
              <bitOffset>4</bitOffset>
              <bitWidth>1</bitWidth>
            </field>
          </fields>
        </register>
        <register>
          <name>CMP</name>
          <addressOffset>0x14</addressOffset>
          <size>0x20</size>
          <fields>
            <field>
              <name>CMP</name>
              <bitOffset>0</bitOffset>
              <bitWidth>16</bitWidth>
            </field>
          </fields>
        </register>
        <register>
          <name>ARR</name>
          <addressOffset>0x18</addressOffset>
          <size>0x20</size>
          <fields>
            <field>
              <name>ARR</name>
              <bitOffset>0</bitOffset>
              <bitWidth>16</bitWidth>
            </field>
          </fields>
        </register>
        <register>
          <name>CNT</name>
          <addressOffset>0x1c</addressOffset>
          <size>0x20</size>
          <fields>
            <field>
              <name>CNT</name>
              <bitOffset>0</bitOffset>
              <bitWidth>16</bitWidth>
            </field>
          </fields>
        </register>
        <register>
          <name>CFGR2</name>
          <addressOffset>0x24</addressOffset>
          <size>0x20</size>
          <fields>
            <field>
              <name>IN1SEL</name>
              <bitOffset>0</bitOffset>
              <bitWidth>2</bitWidth>
            </field>
            <field>
              <name>IN2SEL</name>
              <bitOffset>4</bitOffset>
              <bitWidth>2</bitWidth>
            </field>
          </fields>
        </register>
      </registers>
    </peripheral>
    <peripheral>
      <name>LPTIM4</name>
      <baseAddress>0x58002c00</baseAddress>
      <registers>
        <register>
          <name>ISR</name>
          <addressOffset>0x0</addressOffset>
          <size>0x20</size>
          <fields>
            <field>
              <name>CMPM</name>
              <bitOffset>0</bitOffset>
              <bitWidth>1</bitWidth>
            </field>
            <field>
              <name>ARRM</name>
              <bitOffset>1</bitOffset>
              <bitWidth>1</bitWidth>
            </field>
            <field>
              <name>EXTTRIG</name>
              <bitOffset>2</bitOffset>
              <bitWidth>1</bitWidth>
            </field>
            <field>
              <name>CMPOK</name>
              <bitOffset>3</bitOffset>
              <bitWidth>1</bitWidth>
            </field>
            <field>
              <name>ARROK</name>
              <bitOffset>4</bitOffset>
              <bitWidth>1</bitWidth>
            </field>
            <field>
              <name>UP</name>
              <bitOffset>5</bitOffset>
              <bitWidth>1</bitWidth>
            </field>
            <field>
              <name>DOWN</name>
              <bitOffset>6</bitOffset>
              <bitWidth>1</bitWidth>
            </field>
          </fields>
        </register>
        <register>
          <name>ICR</name>
          <addressOffset>0x4</addressOffset>
          <size>0x20</size>
          <fields>
            <field>
              <name>CMPMCF</name>
              <bitOffset>0</bitOffset>
              <bitWidth>1</bitWidth>
            </field>
            <field>
              <name>ARRMCF</name>
              <bitOffset>1</bitOffset>
              <bitWidth>1</bitWidth>
            </field>
            <field>
              <name>EXTTRIGCF</name>
              <bitOffset>2</bitOffset>
              <bitWidth>1</bitWidth>
            </field>
            <field>
              <name>CMPOKCF</name>
              <bitOffset>3</bitOffset>
              <bitWidth>1</bitWidth>
            </field>
            <field>
              <name>ARROKCF</name>
              <bitOffset>4</bitOffset>
              <bitWidth>1</bitWidth>
            </field>
            <field>
              <name>UPCF</name>
              <bitOffset>5</bitOffset>
              <bitWidth>1</bitWidth>
            </field>
            <field>
              <name>DOWNCF</name>
              <bitOffset>6</bitOffset>
              <bitWidth>1</bitWidth>
            </field>
          </fields>
        </register>
        <register>
          <name>IER</name>
          <addressOffset>0x8</addressOffset>
          <size>0x20</size>
          <fields>
            <field>
              <name>CMPMIE</name>
              <bitOffset>0</bitOffset>
              <bitWidth>1</bitWidth>
            </field>
            <field>
              <name>ARRMIE</name>
              <bitOffset>1</bitOffset>
              <bitWidth>1</bitWidth>
            </field>
            <field>
              <name>EXTTRIGIE</name>
              <bitOffset>2</bitOffset>
              <bitWidth>1</bitWidth>
            </field>
            <field>
              <name>CMPOKIE</name>
              <bitOffset>3</bitOffset>
              <bitWidth>1</bitWidth>
            </field>
            <field>
              <name>ARROKIE</name>
              <bitOffset>4</bitOffset>
              <bitWidth>1</bitWidth>
            </field>
            <field>
              <name>UPIE</name>
              <bitOffset>5</bitOffset>
              <bitWidth>1</bitWidth>
            </field>
            <field>
              <name>DOWNIE</name>
              <bitOffset>6</bitOffset>
              <bitWidth>1</bitWidth>
            </field>
          </fields>
        </register>
        <register>
          <name>CFGR</name>
          <addressOffset>0xc</addressOffset>
          <size>0x20</size>
          <fields>
            <field>
              <name>CKSEL</name>
              <bitOffset>0</bitOffset>
              <bitWidth>1</bitWidth>
            </field>
            <field>
              <name>CKPOL</name>
              <bitOffset>1</bitOffset>
              <bitWidth>2</bitWidth>
            </field>
            <field>
              <name>CKFLT</name>
              <bitOffset>3</bitOffset>
              <bitWidth>2</bitWidth>
            </field>
            <field>
              <name>TRGFLT</name>
              <bitOffset>6</bitOffset>
              <bitWidth>2</bitWidth>
            </field>
            <field>
              <name>PRESC</name>
              <bitOffset>9</bitOffset>
              <bitWidth>3</bitWidth>
            </field>
            <field>
              <name>TRIGSEL</name>
              <bitOffset>13</bitOffset>
              <bitWidth>3</bitWidth>
            </field>
            <field>
              <name>TRIGEN</name>
              <bitOffset>17</bitOffset>
              <bitWidth>2</bitWidth>
            </field>
            <field>
              <name>TIMOUT</name>
              <bitOffset>19</bitOffset>
              <bitWidth>1</bitWidth>
            </field>
            <field>
              <name>WAVE</name>
              <bitOffset>20</bitOffset>
              <bitWidth>1</bitWidth>
            </field>
            <field>
              <name>WAVPOL</name>
              <bitOffset>21</bitOffset>
              <bitWidth>1</bitWidth>
            </field>
            <field>
              <name>PRELOAD</name>
              <bitOffset>22</bitOffset>
              <bitWidth>1</bitWidth>
            </field>
            <field>
              <name>COUNTMODE</name>
              <bitOffset>23</bitOffset>
              <bitWidth>1</bitWidth>
            </field>
            <field>
              <name>ENC</name>
              <bitOffset>24</bitOffset>
              <bitWidth>1</bitWidth>
            </field>
          </fields>
        </register>
        <register>
          <name>CR</name>
          <addressOffset>0x10</addressOffset>
          <size>0x20</size>
          <fields>
            <field>
              <name>ENABLE</name>
              <bitOffset>0</bitOffset>
              <bitWidth>1</bitWidth>
            </field>
            <field>
              <name>SNGSTRT</name>
              <bitOffset>1</bitOffset>
              <bitWidth>19</bitWidth>
            </field>
            <field>
              <name>CNTSTRT</name>
              <bitOffset>2</bitOffset>
              <bitWidth>1</bitWidth>
            </field>
            <field>
              <name>COUNTRST</name>
              <bitOffset>3</bitOffset>
              <bitWidth>1</bitWidth>
            </field>
            <field>
              <name>RSTARE</name>
              <bitOffset>4</bitOffset>
              <bitWidth>1</bitWidth>
            </field>
          </fields>
        </register>
        <register>
          <name>CMP</name>
          <addressOffset>0x14</addressOffset>
          <size>0x20</size>
          <fields>
            <field>
              <name>CMP</name>
              <bitOffset>0</bitOffset>
              <bitWidth>16</bitWidth>
            </field>
          </fields>
        </register>
        <register>
          <name>ARR</name>
          <addressOffset>0x18</addressOffset>
          <size>0x20</size>
          <fields>
            <field>
              <name>ARR</name>
              <bitOffset>0</bitOffset>
              <bitWidth>16</bitWidth>
            </field>
          </fields>
        </register>
        <register>
          <name>CNT</name>
          <addressOffset>0x1c</addressOffset>
          <size>0x20</size>
          <fields>
            <field>
              <name>CNT</name>
              <bitOffset>0</bitOffset>
              <bitWidth>16</bitWidth>
            </field>
          </fields>
        </register>
        <register>
          <name>CFGR2</name>
          <addressOffset>0x24</addressOffset>
          <size>0x20</size>
          <fields>
            <field>
              <name>IN1SEL</name>
              <bitOffset>0</bitOffset>
              <bitWidth>2</bitWidth>
            </field>
            <field>
              <name>IN2SEL</name>
              <bitOffset>4</bitOffset>
              <bitWidth>2</bitWidth>
            </field>
          </fields>
        </register>
      </registers>
    </peripheral>
    <peripheral>
      <name>LPTIM5</name>
      <baseAddress>0x58003000</baseAddress>
      <registers>
        <register>
          <name>ISR</name>
          <addressOffset>0x0</addressOffset>
          <size>0x20</size>
          <fields>
            <field>
              <name>CMPM</name>
              <bitOffset>0</bitOffset>
              <bitWidth>1</bitWidth>
            </field>
            <field>
              <name>ARRM</name>
              <bitOffset>1</bitOffset>
              <bitWidth>1</bitWidth>
            </field>
            <field>
              <name>EXTTRIG</name>
              <bitOffset>2</bitOffset>
              <bitWidth>1</bitWidth>
            </field>
            <field>
              <name>CMPOK</name>
              <bitOffset>3</bitOffset>
              <bitWidth>1</bitWidth>
            </field>
            <field>
              <name>ARROK</name>
              <bitOffset>4</bitOffset>
              <bitWidth>1</bitWidth>
            </field>
            <field>
              <name>UP</name>
              <bitOffset>5</bitOffset>
              <bitWidth>1</bitWidth>
            </field>
            <field>
              <name>DOWN</name>
              <bitOffset>6</bitOffset>
              <bitWidth>1</bitWidth>
            </field>
          </fields>
        </register>
        <register>
          <name>ICR</name>
          <addressOffset>0x4</addressOffset>
          <size>0x20</size>
          <fields>
            <field>
              <name>CMPMCF</name>
              <bitOffset>0</bitOffset>
              <bitWidth>1</bitWidth>
            </field>
            <field>
              <name>ARRMCF</name>
              <bitOffset>1</bitOffset>
              <bitWidth>1</bitWidth>
            </field>
            <field>
              <name>EXTTRIGCF</name>
              <bitOffset>2</bitOffset>
              <bitWidth>1</bitWidth>
            </field>
            <field>
              <name>CMPOKCF</name>
              <bitOffset>3</bitOffset>
              <bitWidth>1</bitWidth>
            </field>
            <field>
              <name>ARROKCF</name>
              <bitOffset>4</bitOffset>
              <bitWidth>1</bitWidth>
            </field>
            <field>
              <name>UPCF</name>
              <bitOffset>5</bitOffset>
              <bitWidth>1</bitWidth>
            </field>
            <field>
              <name>DOWNCF</name>
              <bitOffset>6</bitOffset>
              <bitWidth>1</bitWidth>
            </field>
          </fields>
        </register>
        <register>
          <name>IER</name>
          <addressOffset>0x8</addressOffset>
          <size>0x20</size>
          <fields>
            <field>
              <name>CMPMIE</name>
              <bitOffset>0</bitOffset>
              <bitWidth>1</bitWidth>
            </field>
            <field>
              <name>ARRMIE</name>
              <bitOffset>1</bitOffset>
              <bitWidth>1</bitWidth>
            </field>
            <field>
              <name>EXTTRIGIE</name>
              <bitOffset>2</bitOffset>
              <bitWidth>1</bitWidth>
            </field>
            <field>
              <name>CMPOKIE</name>
              <bitOffset>3</bitOffset>
              <bitWidth>1</bitWidth>
            </field>
            <field>
              <name>ARROKIE</name>
              <bitOffset>4</bitOffset>
              <bitWidth>1</bitWidth>
            </field>
            <field>
              <name>UPIE</name>
              <bitOffset>5</bitOffset>
              <bitWidth>1</bitWidth>
            </field>
            <field>
              <name>DOWNIE</name>
              <bitOffset>6</bitOffset>
              <bitWidth>1</bitWidth>
            </field>
          </fields>
        </register>
        <register>
          <name>CFGR</name>
          <addressOffset>0xc</addressOffset>
          <size>0x20</size>
          <fields>
            <field>
              <name>CKSEL</name>
              <bitOffset>0</bitOffset>
              <bitWidth>1</bitWidth>
            </field>
            <field>
              <name>CKPOL</name>
              <bitOffset>1</bitOffset>
              <bitWidth>2</bitWidth>
            </field>
            <field>
              <name>CKFLT</name>
              <bitOffset>3</bitOffset>
              <bitWidth>2</bitWidth>
            </field>
            <field>
              <name>TRGFLT</name>
              <bitOffset>6</bitOffset>
              <bitWidth>2</bitWidth>
            </field>
            <field>
              <name>PRESC</name>
              <bitOffset>9</bitOffset>
              <bitWidth>3</bitWidth>
            </field>
            <field>
              <name>TRIGSEL</name>
              <bitOffset>13</bitOffset>
              <bitWidth>3</bitWidth>
            </field>
            <field>
              <name>TRIGEN</name>
              <bitOffset>17</bitOffset>
              <bitWidth>2</bitWidth>
            </field>
            <field>
              <name>TIMOUT</name>
              <bitOffset>19</bitOffset>
              <bitWidth>1</bitWidth>
            </field>
            <field>
              <name>WAVE</name>
              <bitOffset>20</bitOffset>
              <bitWidth>1</bitWidth>
            </field>
            <field>
              <name>WAVPOL</name>
              <bitOffset>21</bitOffset>
              <bitWidth>1</bitWidth>
            </field>
            <field>
              <name>PRELOAD</name>
              <bitOffset>22</bitOffset>
              <bitWidth>1</bitWidth>
            </field>
            <field>
              <name>COUNTMODE</name>
              <bitOffset>23</bitOffset>
              <bitWidth>1</bitWidth>
            </field>
            <field>
              <name>ENC</name>
              <bitOffset>24</bitOffset>
              <bitWidth>1</bitWidth>
            </field>
          </fields>
        </register>
        <register>
          <name>CR</name>
          <addressOffset>0x10</addressOffset>
          <size>0x20</size>
          <fields>
            <field>
              <name>ENABLE</name>
              <bitOffset>0</bitOffset>
              <bitWidth>1</bitWidth>
            </field>
            <field>
              <name>SNGSTRT</name>
              <bitOffset>1</bitOffset>
              <bitWidth>19</bitWidth>
            </field>
            <field>
              <name>CNTSTRT</name>
              <bitOffset>2</bitOffset>
              <bitWidth>1</bitWidth>
            </field>
            <field>
              <name>COUNTRST</name>
              <bitOffset>3</bitOffset>
              <bitWidth>1</bitWidth>
            </field>
            <field>
              <name>RSTARE</name>
              <bitOffset>4</bitOffset>
              <bitWidth>1</bitWidth>
            </field>
          </fields>
        </register>
        <register>
          <name>CMP</name>
          <addressOffset>0x14</addressOffset>
          <size>0x20</size>
          <fields>
            <field>
              <name>CMP</name>
              <bitOffset>0</bitOffset>
              <bitWidth>16</bitWidth>
            </field>
          </fields>
        </register>
        <register>
          <name>ARR</name>
          <addressOffset>0x18</addressOffset>
          <size>0x20</size>
          <fields>
            <field>
              <name>ARR</name>
              <bitOffset>0</bitOffset>
              <bitWidth>16</bitWidth>
            </field>
          </fields>
        </register>
        <register>
          <name>CNT</name>
          <addressOffset>0x1c</addressOffset>
          <size>0x20</size>
          <fields>
            <field>
              <name>CNT</name>
              <bitOffset>0</bitOffset>
              <bitWidth>16</bitWidth>
            </field>
          </fields>
        </register>
        <register>
          <name>CFGR2</name>
          <addressOffset>0x24</addressOffset>
          <size>0x20</size>
          <fields>
            <field>
              <name>IN1SEL</name>
              <bitOffset>0</bitOffset>
              <bitWidth>2</bitWidth>
            </field>
            <field>
              <name>IN2SEL</name>
              <bitOffset>4</bitOffset>
              <bitWidth>2</bitWidth>
            </field>
          </fields>
        </register>
      </registers>
    </peripheral>
    <peripheral>
      <name>COMP12</name>
      <baseAddress>0x58003800</baseAddress>
      <registers>
        <register>
          <name>SR</name>
          <addressOffset>0x0</addressOffset>
          <size>0x20</size>
        </register>
        <register>
          <name>ICFR</name>
          <addressOffset>0x4</addressOffset>
          <size>0x20</size>
        </register>
        <register>
          <name>OR</name>
          <addressOffset>0x8</addressOffset>
          <size>0x20</size>
        </register>
      </registers>
    </peripheral>
    <peripheral>
      <name>COMP1</name>
      <baseAddress>0x5800380c</baseAddress>
      <registers>
        <register>
          <name>CFGR</name>
          <addressOffset>0x0</addressOffset>
          <size>0x20</size>
        </register>
      </registers>
    </peripheral>
    <peripheral>
      <name>COMP2</name>
      <baseAddress>0x58003810</baseAddress>
      <registers>
        <register>
          <name>CFGR</name>
          <addressOffset>0x0</addressOffset>
          <size>0x20</size>
        </register>
      </registers>
    </peripheral>
    <peripheral>
      <name>COMP12_COMMON</name>
      <baseAddress>0x58003810</baseAddress>
      <registers>
        <register>
          <name>CFGR</name>
          <addressOffset>0x0</addressOffset>
          <size>0x20</size>
        </register>
      </registers>
    </peripheral>
    <peripheral>
      <name>VREFBUF</name>
      <baseAddress>0x58003c00</baseAddress>
      <registers>
        <register>
          <name>CSR</name>
          <addressOffset>0x0</addressOffset>
          <size>0x20</size>
          <fields>
            <field>
              <name>ENVR</name>
              <bitOffset>0</bitOffset>
              <bitWidth>1</bitWidth>
            </field>
            <field>
              <name>HIZ</name>
              <bitOffset>1</bitOffset>
              <bitWidth>1</bitWidth>
            </field>
            <field>
              <name>VRR</name>
              <bitOffset>3</bitOffset>
              <bitWidth>1</bitWidth>
            </field>
            <field>
              <name>VRS_OUT4</name>
              <bitOffset>4</bitOffset>
              <bitWidth>2</bitWidth>
            </field>
            <field>
              <name>VRS_OUT3</name>
              <bitOffset>5</bitOffset>
              <bitWidth>1</bitWidth>
            </field>
          </fields>
        </register>
        <register>
          <name>CCR</name>
          <addressOffset>0x4</addressOffset>
          <size>0x20</size>
          <fields>
            <field>
              <name>TRIM</name>
              <bitOffset>0</bitOffset>
              <bitWidth>6</bitWidth>
            </field>
          </fields>
        </register>
      </registers>
    </peripheral>
    <peripheral>
      <name>RTC</name>
      <baseAddress>0x58004000</baseAddress>
      <registers>
        <register>
          <name>TR</name>
          <addressOffset>0x0</addressOffset>
          <size>0x20</size>
          <fields>
            <field>
              <name>SU</name>
              <bitOffset>0</bitOffset>
              <bitWidth>4</bitWidth>
            </field>
            <field>
              <name>ST</name>
              <bitOffset>4</bitOffset>
              <bitWidth>3</bitWidth>
            </field>
            <field>
              <name>MNU</name>
              <bitOffset>8</bitOffset>
              <bitWidth>4</bitWidth>
            </field>
            <field>
              <name>MNT</name>
              <bitOffset>12</bitOffset>
              <bitWidth>3</bitWidth>
            </field>
            <field>
              <name>HU</name>
              <bitOffset>16</bitOffset>
              <bitWidth>4</bitWidth>
            </field>
            <field>
              <name>HT</name>
              <bitOffset>20</bitOffset>
              <bitWidth>2</bitWidth>
            </field>
            <field>
              <name>PM</name>
              <bitOffset>22</bitOffset>
              <bitWidth>1</bitWidth>
            </field>
          </fields>
        </register>
        <register>
          <name>DR</name>
          <addressOffset>0x4</addressOffset>
          <size>0x20</size>
          <fields>
            <field>
              <name>DU</name>
              <bitOffset>0</bitOffset>
              <bitWidth>4</bitWidth>
            </field>
            <field>
              <name>DT</name>
              <bitOffset>4</bitOffset>
              <bitWidth>2</bitWidth>
            </field>
            <field>
              <name>MU</name>
              <bitOffset>8</bitOffset>
              <bitWidth>4</bitWidth>
            </field>
            <field>
              <name>MT</name>
              <bitOffset>12</bitOffset>
              <bitWidth>1</bitWidth>
            </field>
            <field>
              <name>WDU</name>
              <bitOffset>13</bitOffset>
              <bitWidth>3</bitWidth>
            </field>
            <field>
              <name>YU</name>
              <bitOffset>16</bitOffset>
              <bitWidth>4</bitWidth>
            </field>
            <field>
              <name>YT</name>
              <bitOffset>20</bitOffset>
              <bitWidth>4</bitWidth>
            </field>
          </fields>
        </register>
        <register>
          <name>CR</name>
          <addressOffset>0x8</addressOffset>
          <size>0x20</size>
          <fields>
            <field>
              <name>WUCKSEL</name>
              <bitOffset>0</bitOffset>
              <bitWidth>3</bitWidth>
            </field>
            <field>
              <name>TSEDGE</name>
              <bitOffset>3</bitOffset>
              <bitWidth>1</bitWidth>
            </field>
            <field>
              <name>REFCKON</name>
              <bitOffset>4</bitOffset>
              <bitWidth>1</bitWidth>
            </field>
            <field>
              <name>BYPSHAD</name>
              <bitOffset>5</bitOffset>
              <bitWidth>1</bitWidth>
            </field>
            <field>
              <name>FMT</name>
              <bitOffset>6</bitOffset>
              <bitWidth>1</bitWidth>
            </field>
            <field>
              <name>ALRAE</name>
              <bitOffset>8</bitOffset>
              <bitWidth>1</bitWidth>
            </field>
            <field>
              <name>ALRBE</name>
              <bitOffset>9</bitOffset>
              <bitWidth>1</bitWidth>
            </field>
            <field>
              <name>WUTE</name>
              <bitOffset>10</bitOffset>
              <bitWidth>1</bitWidth>
            </field>
            <field>
              <name>TSE</name>
              <bitOffset>11</bitOffset>
              <bitWidth>1</bitWidth>
            </field>
            <field>
              <name>ALRAIE</name>
              <bitOffset>12</bitOffset>
              <bitWidth>1</bitWidth>
            </field>
            <field>
              <name>ALRBIE</name>
              <bitOffset>13</bitOffset>
              <bitWidth>1</bitWidth>
            </field>
            <field>
              <name>WUTIE</name>
              <bitOffset>14</bitOffset>
              <bitWidth>1</bitWidth>
            </field>
            <field>
              <name>TSIE</name>
              <bitOffset>15</bitOffset>
              <bitWidth>1</bitWidth>
            </field>
            <field>
              <name>ADD1H</name>
              <bitOffset>16</bitOffset>
              <bitWidth>1</bitWidth>
            </field>
            <field>
              <name>SUB1H</name>
              <bitOffset>17</bitOffset>
              <bitWidth>1</bitWidth>
            </field>
            <field>
              <name>BKP</name>
              <bitOffset>18</bitOffset>
              <bitWidth>1</bitWidth>
            </field>
            <field>
              <name>COSEL</name>
              <bitOffset>19</bitOffset>
              <bitWidth>1</bitWidth>
            </field>
            <field>
              <name>POL</name>
              <bitOffset>20</bitOffset>
              <bitWidth>1</bitWidth>
            </field>
            <field>
              <name>OSEL</name>
              <bitOffset>21</bitOffset>
              <bitWidth>2</bitWidth>
            </field>
            <field>
              <name>COE</name>
              <bitOffset>23</bitOffset>
              <bitWidth>1</bitWidth>
            </field>
            <field>
              <name>ITSE</name>
              <bitOffset>24</bitOffset>
              <bitWidth>1</bitWidth>
            </field>
          </fields>
        </register>
        <register>
          <name>ISR</name>
          <addressOffset>0xc</addressOffset>
          <size>0x20</size>
          <fields>
            <field>
              <name>ALRAWF</name>
              <bitOffset>0</bitOffset>
              <bitWidth>1</bitWidth>
            </field>
            <field>
              <name>ALRBWF</name>
              <bitOffset>1</bitOffset>
              <bitWidth>1</bitWidth>
            </field>
            <field>
              <name>WUTWF</name>
              <bitOffset>2</bitOffset>
              <bitWidth>1</bitWidth>
            </field>
            <field>
              <name>SHPF</name>
              <bitOffset>3</bitOffset>
              <bitWidth>1</bitWidth>
            </field>
            <field>
              <name>INITS</name>
              <bitOffset>4</bitOffset>
              <bitWidth>1</bitWidth>
            </field>
            <field>
              <name>RSF</name>
              <bitOffset>5</bitOffset>
              <bitWidth>1</bitWidth>
            </field>
            <field>
              <name>INITF</name>
              <bitOffset>6</bitOffset>
              <bitWidth>1</bitWidth>
            </field>
            <field>
              <name>INIT</name>
              <bitOffset>7</bitOffset>
              <bitWidth>1</bitWidth>
            </field>
            <field>
              <name>ALRAF</name>
              <bitOffset>8</bitOffset>
              <bitWidth>1</bitWidth>
            </field>
            <field>
              <name>ALRBF</name>
              <bitOffset>9</bitOffset>
              <bitWidth>1</bitWidth>
            </field>
            <field>
              <name>WUTF</name>
              <bitOffset>10</bitOffset>
              <bitWidth>1</bitWidth>
            </field>
            <field>
              <name>TSF</name>
              <bitOffset>11</bitOffset>
              <bitWidth>1</bitWidth>
            </field>
            <field>
              <name>TSOVF</name>
              <bitOffset>12</bitOffset>
              <bitWidth>1</bitWidth>
            </field>
            <field>
              <name>TAMP1F</name>
              <bitOffset>13</bitOffset>
              <bitWidth>1</bitWidth>
            </field>
            <field>
              <name>TAMP2F</name>
              <bitOffset>14</bitOffset>
              <bitWidth>1</bitWidth>
            </field>
            <field>
              <name>TAMP3F</name>
              <bitOffset>15</bitOffset>
              <bitWidth>1</bitWidth>
            </field>
            <field>
              <name>RECALPF</name>
              <bitOffset>16</bitOffset>
              <bitWidth>1</bitWidth>
            </field>
            <field>
              <name>ITSF</name>
              <bitOffset>17</bitOffset>
              <bitWidth>1</bitWidth>
            </field>
          </fields>
        </register>
        <register>
          <name>PRER</name>
          <addressOffset>0x10</addressOffset>
          <size>0x20</size>
          <fields>
            <field>
              <name>PREDIV_S</name>
              <bitOffset>0</bitOffset>
              <bitWidth>15</bitWidth>
            </field>
            <field>
              <name>PREDIV_A</name>
              <bitOffset>16</bitOffset>
              <bitWidth>7</bitWidth>
            </field>
          </fields>
        </register>
        <register>
          <name>WUTR</name>
          <addressOffset>0x14</addressOffset>
          <size>0x20</size>
          <fields>
            <field>
              <name>WUT</name>
              <bitOffset>0</bitOffset>
              <bitWidth>16</bitWidth>
            </field>
          </fields>
        </register>
        <register>
          <name>ALRMAR</name>
          <addressOffset>0x1c</addressOffset>
          <size>0x20</size>
          <fields>
            <field>
              <name>SU</name>
              <bitOffset>0</bitOffset>
              <bitWidth>4</bitWidth>
            </field>
            <field>
              <name>ST</name>
              <bitOffset>4</bitOffset>
              <bitWidth>3</bitWidth>
            </field>
            <field>
              <name>MSK1</name>
              <bitOffset>7</bitOffset>
              <bitWidth>1</bitWidth>
            </field>
            <field>
              <name>MNU</name>
              <bitOffset>8</bitOffset>
              <bitWidth>4</bitWidth>
            </field>
            <field>
              <name>MNT</name>
              <bitOffset>12</bitOffset>
              <bitWidth>3</bitWidth>
            </field>
            <field>
              <name>MSK2</name>
              <bitOffset>15</bitOffset>
              <bitWidth>1</bitWidth>
            </field>
            <field>
              <name>HU</name>
              <bitOffset>16</bitOffset>
              <bitWidth>4</bitWidth>
            </field>
            <field>
              <name>HT</name>
              <bitOffset>20</bitOffset>
              <bitWidth>2</bitWidth>
            </field>
            <field>
              <name>PM</name>
              <bitOffset>22</bitOffset>
              <bitWidth>1</bitWidth>
            </field>
            <field>
              <name>MSK3</name>
              <bitOffset>23</bitOffset>
              <bitWidth>1</bitWidth>
            </field>
            <field>
              <name>DU</name>
              <bitOffset>24</bitOffset>
              <bitWidth>4</bitWidth>
            </field>
            <field>
              <name>DT</name>
              <bitOffset>28</bitOffset>
              <bitWidth>2</bitWidth>
            </field>
            <field>
              <name>WDSEL</name>
              <bitOffset>30</bitOffset>
              <bitWidth>1</bitWidth>
            </field>
            <field>
              <name>MSK4</name>
              <bitOffset>31</bitOffset>
              <bitWidth>1</bitWidth>
            </field>
          </fields>
        </register>
        <register>
          <name>ALRMBR</name>
          <addressOffset>0x20</addressOffset>
          <size>0x20</size>
          <fields>
            <field>
              <name>SU</name>
              <bitOffset>0</bitOffset>
              <bitWidth>4</bitWidth>
            </field>
            <field>
              <name>ST</name>
              <bitOffset>4</bitOffset>
              <bitWidth>3</bitWidth>
            </field>
            <field>
              <name>MSK1</name>
              <bitOffset>7</bitOffset>
              <bitWidth>1</bitWidth>
            </field>
            <field>
              <name>MNU</name>
              <bitOffset>8</bitOffset>
              <bitWidth>4</bitWidth>
            </field>
            <field>
              <name>MNT</name>
              <bitOffset>12</bitOffset>
              <bitWidth>3</bitWidth>
            </field>
            <field>
              <name>MSK2</name>
              <bitOffset>15</bitOffset>
              <bitWidth>1</bitWidth>
            </field>
            <field>
              <name>HU</name>
              <bitOffset>16</bitOffset>
              <bitWidth>4</bitWidth>
            </field>
            <field>
              <name>HT</name>
              <bitOffset>20</bitOffset>
              <bitWidth>2</bitWidth>
            </field>
            <field>
              <name>PM</name>
              <bitOffset>22</bitOffset>
              <bitWidth>1</bitWidth>
            </field>
            <field>
              <name>MSK3</name>
              <bitOffset>23</bitOffset>
              <bitWidth>1</bitWidth>
            </field>
            <field>
              <name>DU</name>
              <bitOffset>24</bitOffset>
              <bitWidth>4</bitWidth>
            </field>
            <field>
              <name>DT</name>
              <bitOffset>28</bitOffset>
              <bitWidth>2</bitWidth>
            </field>
            <field>
              <name>WDSEL</name>
              <bitOffset>30</bitOffset>
              <bitWidth>1</bitWidth>
            </field>
            <field>
              <name>MSK4</name>
              <bitOffset>31</bitOffset>
              <bitWidth>1</bitWidth>
            </field>
          </fields>
        </register>
        <register>
          <name>WPR</name>
          <addressOffset>0x24</addressOffset>
          <size>0x20</size>
          <fields>
            <field>
              <name>KEY</name>
              <bitOffset>0</bitOffset>
              <bitWidth>8</bitWidth>
            </field>
          </fields>
        </register>
        <register>
          <name>SSR</name>
          <addressOffset>0x28</addressOffset>
          <size>0x20</size>
          <fields>
            <field>
              <name>SS</name>
              <bitOffset>0</bitOffset>
              <bitWidth>16</bitWidth>
            </field>
          </fields>
        </register>
        <register>
          <name>SHIFTR</name>
          <addressOffset>0x2c</addressOffset>
          <size>0x20</size>
          <fields>
            <field>
              <name>SUBFS</name>
              <bitOffset>0</bitOffset>
              <bitWidth>15</bitWidth>
            </field>
            <field>
              <name>ADD1S</name>
              <bitOffset>31</bitOffset>
              <bitWidth>1</bitWidth>
            </field>
          </fields>
        </register>
        <register>
          <name>TSTR</name>
          <addressOffset>0x30</addressOffset>
          <size>0x20</size>
          <fields>
            <field>
              <name>SU</name>
              <bitOffset>0</bitOffset>
              <bitWidth>4</bitWidth>
            </field>
            <field>
              <name>ST</name>
              <bitOffset>4</bitOffset>
              <bitWidth>3</bitWidth>
            </field>
            <field>
              <name>MNU</name>
              <bitOffset>8</bitOffset>
              <bitWidth>4</bitWidth>
            </field>
            <field>
              <name>MNT</name>
              <bitOffset>12</bitOffset>
              <bitWidth>3</bitWidth>
            </field>
            <field>
              <name>HU</name>
              <bitOffset>16</bitOffset>
              <bitWidth>4</bitWidth>
            </field>
            <field>
              <name>HT</name>
              <bitOffset>20</bitOffset>
              <bitWidth>2</bitWidth>
            </field>
            <field>
              <name>PM</name>
              <bitOffset>22</bitOffset>
              <bitWidth>1</bitWidth>
            </field>
          </fields>
        </register>
        <register>
          <name>TSDR</name>
          <addressOffset>0x34</addressOffset>
          <size>0x20</size>
          <fields>
            <field>
              <name>DU</name>
              <bitOffset>0</bitOffset>
              <bitWidth>4</bitWidth>
            </field>
            <field>
              <name>DT</name>
              <bitOffset>4</bitOffset>
              <bitWidth>2</bitWidth>
            </field>
            <field>
              <name>MU</name>
              <bitOffset>8</bitOffset>
              <bitWidth>4</bitWidth>
            </field>
            <field>
              <name>MT</name>
              <bitOffset>12</bitOffset>
              <bitWidth>1</bitWidth>
            </field>
            <field>
              <name>WDU</name>
              <bitOffset>13</bitOffset>
              <bitWidth>3</bitWidth>
            </field>
          </fields>
        </register>
        <register>
          <name>TSSSR</name>
          <addressOffset>0x38</addressOffset>
          <size>0x20</size>
          <fields>
            <field>
              <name>SS</name>
              <bitOffset>0</bitOffset>
              <bitWidth>16</bitWidth>
            </field>
          </fields>
        </register>
        <register>
          <name>CALR</name>
          <addressOffset>0x3c</addressOffset>
          <size>0x20</size>
          <fields>
            <field>
              <name>CALM</name>
              <bitOffset>0</bitOffset>
              <bitWidth>9</bitWidth>
            </field>
            <field>
              <name>CALW16</name>
              <bitOffset>13</bitOffset>
              <bitWidth>1</bitWidth>
            </field>
            <field>
              <name>CALW8</name>
              <bitOffset>14</bitOffset>
              <bitWidth>1</bitWidth>
            </field>
            <field>
              <name>CALP</name>
              <bitOffset>15</bitOffset>
              <bitWidth>1</bitWidth>
            </field>
          </fields>
        </register>
        <register>
          <name>TAMPCR</name>
          <addressOffset>0x40</addressOffset>
          <size>0x20</size>
          <fields>
            <field>
              <name>TAMP1E</name>
              <bitOffset>0</bitOffset>
              <bitWidth>1</bitWidth>
            </field>
            <field>
              <name>TAMP1TRG</name>
              <bitOffset>1</bitOffset>
              <bitWidth>1</bitWidth>
            </field>
            <field>
              <name>TAMPIE</name>
              <bitOffset>2</bitOffset>
              <bitWidth>1</bitWidth>
            </field>
            <field>
              <name>TAMP2E</name>
              <bitOffset>3</bitOffset>
              <bitWidth>1</bitWidth>
            </field>
            <field>
              <name>TAMP2TRG</name>
              <bitOffset>4</bitOffset>
              <bitWidth>1</bitWidth>
            </field>
            <field>
              <name>TAMP3E</name>
              <bitOffset>5</bitOffset>
              <bitWidth>1</bitWidth>
            </field>
            <field>
              <name>TAMP3TRG</name>
              <bitOffset>6</bitOffset>
              <bitWidth>1</bitWidth>
            </field>
            <field>
              <name>TAMPTS</name>
              <bitOffset>7</bitOffset>
              <bitWidth>1</bitWidth>
            </field>
            <field>
              <name>TAMPFREQ</name>
              <bitOffset>8</bitOffset>
              <bitWidth>3</bitWidth>
            </field>
            <field>
              <name>TAMPFLT</name>
              <bitOffset>11</bitOffset>
              <bitWidth>2</bitWidth>
            </field>
            <field>
              <name>TAMPPRCH</name>
              <bitOffset>13</bitOffset>
              <bitWidth>2</bitWidth>
            </field>
            <field>
              <name>TAMPPUDIS</name>
              <bitOffset>15</bitOffset>
              <bitWidth>1</bitWidth>
            </field>
            <field>
              <name>TAMP1IE</name>
              <bitOffset>16</bitOffset>
              <bitWidth>1</bitWidth>
            </field>
            <field>
              <name>TAMP1NOERASE</name>
              <bitOffset>17</bitOffset>
              <bitWidth>1</bitWidth>
            </field>
            <field>
              <name>TAMP1MF</name>
              <bitOffset>18</bitOffset>
              <bitWidth>1</bitWidth>
            </field>
            <field>
              <name>TAMP2IE</name>
              <bitOffset>19</bitOffset>
              <bitWidth>1</bitWidth>
            </field>
            <field>
              <name>TAMP2NOERASE</name>
              <bitOffset>20</bitOffset>
              <bitWidth>1</bitWidth>
            </field>
            <field>
              <name>TAMP2MF</name>
              <bitOffset>21</bitOffset>
              <bitWidth>1</bitWidth>
            </field>
            <field>
              <name>TAMP3IE</name>
              <bitOffset>22</bitOffset>
              <bitWidth>1</bitWidth>
            </field>
            <field>
              <name>TAMP3NOERASE</name>
              <bitOffset>23</bitOffset>
              <bitWidth>1</bitWidth>
            </field>
            <field>
              <name>TAMP3MF</name>
              <bitOffset>24</bitOffset>
              <bitWidth>1</bitWidth>
            </field>
          </fields>
        </register>
        <register>
          <name>ALRMASSR</name>
          <addressOffset>0x44</addressOffset>
          <size>0x20</size>
          <fields>
            <field>
              <name>SS</name>
              <bitOffset>0</bitOffset>
              <bitWidth>15</bitWidth>
            </field>
            <field>
              <name>MASKSS</name>
              <bitOffset>24</bitOffset>
              <bitWidth>4</bitWidth>
            </field>
          </fields>
        </register>
        <register>
          <name>ALRMBSSR</name>
          <addressOffset>0x48</addressOffset>
          <size>0x20</size>
          <fields>
            <field>
              <name>SS</name>
              <bitOffset>0</bitOffset>
              <bitWidth>15</bitWidth>
            </field>
            <field>
              <name>MASKSS</name>
              <bitOffset>24</bitOffset>
              <bitWidth>4</bitWidth>
            </field>
          </fields>
        </register>
        <register>
          <name>OR</name>
          <addressOffset>0x4c</addressOffset>
          <size>0x20</size>
          <fields>
            <field>
              <name>ALARMOUTTYPE</name>
              <bitOffset>0</bitOffset>
              <bitWidth>1</bitWidth>
            </field>
            <field>
              <name>OUT_RMP</name>
              <bitOffset>1</bitOffset>
              <bitWidth>1</bitWidth>
            </field>
          </fields>
        </register>
        <register>
          <name>BKP0R</name>
          <addressOffset>0x50</addressOffset>
          <size>0x20</size>
        </register>
        <register>
          <name>BKP1R</name>
          <addressOffset>0x54</addressOffset>
          <size>0x20</size>
        </register>
        <register>
          <name>BKP2R</name>
          <addressOffset>0x58</addressOffset>
          <size>0x20</size>
        </register>
        <register>
          <name>BKP3R</name>
          <addressOffset>0x5c</addressOffset>
          <size>0x20</size>
        </register>
        <register>
          <name>BKP4R</name>
          <addressOffset>0x60</addressOffset>
          <size>0x20</size>
        </register>
        <register>
          <name>BKP5R</name>
          <addressOffset>0x64</addressOffset>
          <size>0x20</size>
        </register>
        <register>
          <name>BKP6R</name>
          <addressOffset>0x68</addressOffset>
          <size>0x20</size>
        </register>
        <register>
          <name>BKP7R</name>
          <addressOffset>0x6c</addressOffset>
          <size>0x20</size>
        </register>
        <register>
          <name>BKP8R</name>
          <addressOffset>0x70</addressOffset>
          <size>0x20</size>
        </register>
        <register>
          <name>BKP9R</name>
          <addressOffset>0x74</addressOffset>
          <size>0x20</size>
        </register>
        <register>
          <name>BKP10R</name>
          <addressOffset>0x78</addressOffset>
          <size>0x20</size>
        </register>
        <register>
          <name>BKP11R</name>
          <addressOffset>0x7c</addressOffset>
          <size>0x20</size>
        </register>
        <register>
          <name>BKP12R</name>
          <addressOffset>0x80</addressOffset>
          <size>0x20</size>
        </register>
        <register>
          <name>BKP13R</name>
          <addressOffset>0x84</addressOffset>
          <size>0x20</size>
        </register>
        <register>
          <name>BKP14R</name>
          <addressOffset>0x88</addressOffset>
          <size>0x20</size>
        </register>
        <register>
          <name>BKP15R</name>
          <addressOffset>0x8c</addressOffset>
          <size>0x20</size>
        </register>
        <register>
          <name>BKP16R</name>
          <addressOffset>0x90</addressOffset>
          <size>0x20</size>
        </register>
        <register>
          <name>BKP17R</name>
          <addressOffset>0x94</addressOffset>
          <size>0x20</size>
        </register>
        <register>
          <name>BKP18R</name>
          <addressOffset>0x98</addressOffset>
          <size>0x20</size>
        </register>
        <register>
          <name>BKP19R</name>
          <addressOffset>0x9c</addressOffset>
          <size>0x20</size>
        </register>
        <register>
          <name>BKP20R</name>
          <addressOffset>0xa0</addressOffset>
          <size>0x20</size>
        </register>
        <register>
          <name>BKP21R</name>
          <addressOffset>0xa4</addressOffset>
          <size>0x20</size>
        </register>
        <register>
          <name>BKP22R</name>
          <addressOffset>0xa8</addressOffset>
          <size>0x20</size>
        </register>
        <register>
          <name>BKP23R</name>
          <addressOffset>0xac</addressOffset>
          <size>0x20</size>
        </register>
        <register>
          <name>BKP24R</name>
          <addressOffset>0xb0</addressOffset>
          <size>0x20</size>
        </register>
        <register>
          <name>BKP25R</name>
          <addressOffset>0xb4</addressOffset>
          <size>0x20</size>
        </register>
        <register>
          <name>BKP26R</name>
          <addressOffset>0xb8</addressOffset>
          <size>0x20</size>
        </register>
        <register>
          <name>BKP27R</name>
          <addressOffset>0xbc</addressOffset>
          <size>0x20</size>
        </register>
        <register>
          <name>BKP28R</name>
          <addressOffset>0xc0</addressOffset>
          <size>0x20</size>
        </register>
        <register>
          <name>BKP29R</name>
          <addressOffset>0xc4</addressOffset>
          <size>0x20</size>
        </register>
        <register>
          <name>BKP30R</name>
          <addressOffset>0xc8</addressOffset>
          <size>0x20</size>
        </register>
        <register>
          <name>BKP31R</name>
          <addressOffset>0xcc</addressOffset>
          <size>0x20</size>
        </register>
      </registers>
    </peripheral>
    <peripheral>
      <name>IWDG1</name>
      <baseAddress>0x58004800</baseAddress>
      <registers>
        <register>
          <name>KR</name>
          <addressOffset>0x0</addressOffset>
          <size>0x20</size>
          <fields>
            <field>
              <name>KEY</name>
              <bitOffset>0</bitOffset>
              <bitWidth>16</bitWidth>
            </field>
          </fields>
        </register>
        <register>
          <name>PR</name>
          <addressOffset>0x4</addressOffset>
          <size>0x20</size>
          <fields>
            <field>
              <name>PR</name>
              <bitOffset>0</bitOffset>
              <bitWidth>3</bitWidth>
            </field>
          </fields>
        </register>
        <register>
          <name>RLR</name>
          <addressOffset>0x8</addressOffset>
          <size>0x20</size>
          <fields>
            <field>
              <name>RL</name>
              <bitOffset>0</bitOffset>
              <bitWidth>12</bitWidth>
            </field>
          </fields>
        </register>
        <register>
          <name>SR</name>
          <addressOffset>0xc</addressOffset>
          <size>0x20</size>
          <fields>
            <field>
              <name>PVU</name>
              <bitOffset>0</bitOffset>
              <bitWidth>1</bitWidth>
            </field>
            <field>
              <name>RVU</name>
              <bitOffset>1</bitOffset>
              <bitWidth>1</bitWidth>
            </field>
            <field>
              <name>WVU</name>
              <bitOffset>2</bitOffset>
              <bitWidth>1</bitWidth>
            </field>
          </fields>
        </register>
        <register>
          <name>WINR</name>
          <addressOffset>0x10</addressOffset>
          <size>0x20</size>
          <fields>
            <field>
              <name>WIN</name>
              <bitOffset>0</bitOffset>
              <bitWidth>12</bitWidth>
            </field>
          </fields>
        </register>
      </registers>
    </peripheral>
    <peripheral>
      <name>IWDG2</name>
      <baseAddress>0x58004c00</baseAddress>
      <registers>
        <register>
          <name>KR</name>
          <addressOffset>0x0</addressOffset>
          <size>0x20</size>
          <fields>
            <field>
              <name>KEY</name>
              <bitOffset>0</bitOffset>
              <bitWidth>16</bitWidth>
            </field>
          </fields>
        </register>
        <register>
          <name>PR</name>
          <addressOffset>0x4</addressOffset>
          <size>0x20</size>
          <fields>
            <field>
              <name>PR</name>
              <bitOffset>0</bitOffset>
              <bitWidth>3</bitWidth>
            </field>
          </fields>
        </register>
        <register>
          <name>RLR</name>
          <addressOffset>0x8</addressOffset>
          <size>0x20</size>
          <fields>
            <field>
              <name>RL</name>
              <bitOffset>0</bitOffset>
              <bitWidth>12</bitWidth>
            </field>
          </fields>
        </register>
        <register>
          <name>SR</name>
          <addressOffset>0xc</addressOffset>
          <size>0x20</size>
          <fields>
            <field>
              <name>PVU</name>
              <bitOffset>0</bitOffset>
              <bitWidth>1</bitWidth>
            </field>
            <field>
              <name>RVU</name>
              <bitOffset>1</bitOffset>
              <bitWidth>1</bitWidth>
            </field>
            <field>
              <name>WVU</name>
              <bitOffset>2</bitOffset>
              <bitWidth>1</bitWidth>
            </field>
          </fields>
        </register>
        <register>
          <name>WINR</name>
          <addressOffset>0x10</addressOffset>
          <size>0x20</size>
          <fields>
            <field>
              <name>WIN</name>
              <bitOffset>0</bitOffset>
              <bitWidth>12</bitWidth>
            </field>
          </fields>
        </register>
      </registers>
    </peripheral>
    <peripheral>
      <name>SAI4</name>
      <baseAddress>0x58005400</baseAddress>
      <registers>
        <register>
          <name>GCR</name>
          <addressOffset>0x0</addressOffset>
          <size>0x20</size>
          <fields>
            <field>
              <name>SYNCIN</name>
              <bitOffset>0</bitOffset>
              <bitWidth>2</bitWidth>
            </field>
            <field>
              <name>SYNCOUT</name>
              <bitOffset>4</bitOffset>
              <bitWidth>2</bitWidth>
            </field>
          </fields>
        </register>
        <register>
          <name>CR1A</name>
          <addressOffset>0x4</addressOffset>
          <size>0x20</size>
          <fields>
            <field>
              <name>MODE</name>
              <bitOffset>0</bitOffset>
              <bitWidth>2</bitWidth>
            </field>
            <field>
              <name>PRTCFG</name>
              <bitOffset>2</bitOffset>
              <bitWidth>2</bitWidth>
            </field>
            <field>
              <name>DS</name>
              <bitOffset>5</bitOffset>
              <bitWidth>3</bitWidth>
            </field>
            <field>
              <name>LSBFIRST</name>
              <bitOffset>8</bitOffset>
              <bitWidth>1</bitWidth>
            </field>
            <field>
              <name>CKSTR</name>
              <bitOffset>9</bitOffset>
              <bitWidth>1</bitWidth>
            </field>
            <field>
              <name>SYNCEN</name>
              <bitOffset>10</bitOffset>
              <bitWidth>2</bitWidth>
            </field>
            <field>
              <name>MONO</name>
              <bitOffset>12</bitOffset>
              <bitWidth>1</bitWidth>
            </field>
            <field>
              <name>OUTDRIV</name>
              <bitOffset>13</bitOffset>
              <bitWidth>1</bitWidth>
            </field>
            <field>
              <name>SAIEN</name>
              <bitOffset>16</bitOffset>
              <bitWidth>1</bitWidth>
            </field>
            <field>
              <name>DMAEN</name>
              <bitOffset>17</bitOffset>
              <bitWidth>1</bitWidth>
            </field>
            <field>
              <name>NODIV</name>
              <bitOffset>19</bitOffset>
              <bitWidth>1</bitWidth>
            </field>
            <field>
              <name>MCKDIV</name>
              <bitOffset>20</bitOffset>
              <bitWidth>6</bitWidth>
            </field>
            <field>
              <name>OSR</name>
              <bitOffset>26</bitOffset>
              <bitWidth>1</bitWidth>
            </field>
            <field>
              <name>MCKEN</name>
              <bitOffset>27</bitOffset>
              <bitWidth>1</bitWidth>
            </field>
          </fields>
        </register>
        <register>
          <name>CR1A</name>
          <addressOffset>0x4</addressOffset>
          <size>0x20</size>
          <fields>
            <field>
              <name>MODE</name>
              <bitOffset>0</bitOffset>
              <bitWidth>2</bitWidth>
            </field>
            <field>
              <name>PRTCFG</name>
              <bitOffset>2</bitOffset>
              <bitWidth>2</bitWidth>
            </field>
            <field>
              <name>DS</name>
              <bitOffset>5</bitOffset>
              <bitWidth>3</bitWidth>
            </field>
            <field>
              <name>LSBFIRST</name>
              <bitOffset>8</bitOffset>
              <bitWidth>1</bitWidth>
            </field>
            <field>
              <name>CKSTR</name>
              <bitOffset>9</bitOffset>
              <bitWidth>1</bitWidth>
            </field>
            <field>
              <name>SYNCEN</name>
              <bitOffset>10</bitOffset>
              <bitWidth>2</bitWidth>
            </field>
            <field>
              <name>MONO</name>
              <bitOffset>12</bitOffset>
              <bitWidth>1</bitWidth>
            </field>
            <field>
              <name>OUTDRIV</name>
              <bitOffset>13</bitOffset>
              <bitWidth>1</bitWidth>
            </field>
            <field>
              <name>SAIEN</name>
              <bitOffset>16</bitOffset>
              <bitWidth>1</bitWidth>
            </field>
            <field>
              <name>DMAEN</name>
              <bitOffset>17</bitOffset>
              <bitWidth>1</bitWidth>
            </field>
            <field>
              <name>NODIV</name>
              <bitOffset>19</bitOffset>
              <bitWidth>1</bitWidth>
            </field>
            <field>
              <name>MCKDIV</name>
              <bitOffset>20</bitOffset>
              <bitWidth>6</bitWidth>
            </field>
            <field>
              <name>OSR</name>
              <bitOffset>26</bitOffset>
              <bitWidth>1</bitWidth>
            </field>
            <field>
              <name>MCKEN</name>
              <bitOffset>27</bitOffset>
              <bitWidth>1</bitWidth>
            </field>
          </fields>
        </register>
        <register>
          <name>CR1A</name>
          <addressOffset>0x4</addressOffset>
          <size>0x20</size>
          <fields>
            <field>
              <name>MODE</name>
              <bitOffset>0</bitOffset>
              <bitWidth>2</bitWidth>
            </field>
            <field>
              <name>PRTCFG</name>
              <bitOffset>2</bitOffset>
              <bitWidth>2</bitWidth>
            </field>
            <field>
              <name>DS</name>
              <bitOffset>5</bitOffset>
              <bitWidth>3</bitWidth>
            </field>
            <field>
              <name>LSBFIRST</name>
              <bitOffset>8</bitOffset>
              <bitWidth>1</bitWidth>
            </field>
            <field>
              <name>CKSTR</name>
              <bitOffset>9</bitOffset>
              <bitWidth>1</bitWidth>
            </field>
            <field>
              <name>SYNCEN</name>
              <bitOffset>10</bitOffset>
              <bitWidth>2</bitWidth>
            </field>
            <field>
              <name>MONO</name>
              <bitOffset>12</bitOffset>
              <bitWidth>1</bitWidth>
            </field>
            <field>
              <name>OUTDRIV</name>
              <bitOffset>13</bitOffset>
              <bitWidth>1</bitWidth>
            </field>
            <field>
              <name>SAIEN</name>
              <bitOffset>16</bitOffset>
              <bitWidth>1</bitWidth>
            </field>
            <field>
              <name>DMAEN</name>
              <bitOffset>17</bitOffset>
              <bitWidth>1</bitWidth>
            </field>
            <field>
              <name>NODIV</name>
              <bitOffset>19</bitOffset>
              <bitWidth>1</bitWidth>
            </field>
            <field>
              <name>MCKDIV</name>
              <bitOffset>20</bitOffset>
              <bitWidth>6</bitWidth>
            </field>
            <field>
              <name>OSR</name>
              <bitOffset>26</bitOffset>
              <bitWidth>1</bitWidth>
            </field>
            <field>
              <name>MCKEN</name>
              <bitOffset>27</bitOffset>
              <bitWidth>1</bitWidth>
            </field>
          </fields>
        </register>
        <register>
          <name>CR1A</name>
          <addressOffset>0x4</addressOffset>
          <size>0x20</size>
          <fields>
            <field>
              <name>MODE</name>
              <bitOffset>0</bitOffset>
              <bitWidth>2</bitWidth>
            </field>
            <field>
              <name>PRTCFG</name>
              <bitOffset>2</bitOffset>
              <bitWidth>2</bitWidth>
            </field>
            <field>
              <name>DS</name>
              <bitOffset>5</bitOffset>
              <bitWidth>3</bitWidth>
            </field>
            <field>
              <name>LSBFIRST</name>
              <bitOffset>8</bitOffset>
              <bitWidth>1</bitWidth>
            </field>
            <field>
              <name>CKSTR</name>
              <bitOffset>9</bitOffset>
              <bitWidth>1</bitWidth>
            </field>
            <field>
              <name>SYNCEN</name>
              <bitOffset>10</bitOffset>
              <bitWidth>2</bitWidth>
            </field>
            <field>
              <name>MONO</name>
              <bitOffset>12</bitOffset>
              <bitWidth>1</bitWidth>
            </field>
            <field>
              <name>OUTDRIV</name>
              <bitOffset>13</bitOffset>
              <bitWidth>1</bitWidth>
            </field>
            <field>
              <name>SAIEN</name>
              <bitOffset>16</bitOffset>
              <bitWidth>1</bitWidth>
            </field>
            <field>
              <name>DMAEN</name>
              <bitOffset>17</bitOffset>
              <bitWidth>1</bitWidth>
            </field>
            <field>
              <name>NODIV</name>
              <bitOffset>19</bitOffset>
              <bitWidth>1</bitWidth>
            </field>
            <field>
              <name>MCKDIV</name>
              <bitOffset>20</bitOffset>
              <bitWidth>6</bitWidth>
            </field>
            <field>
              <name>OSR</name>
              <bitOffset>26</bitOffset>
              <bitWidth>1</bitWidth>
            </field>
            <field>
              <name>MCKEN</name>
              <bitOffset>27</bitOffset>
              <bitWidth>1</bitWidth>
            </field>
          </fields>
        </register>
        <register>
          <name>CR2A</name>
          <addressOffset>0x8</addressOffset>
          <size>0x20</size>
          <fields>
            <field>
              <name>FTH</name>
              <bitOffset>0</bitOffset>
              <bitWidth>3</bitWidth>
            </field>
            <field>
              <name>FFLUSH</name>
              <bitOffset>3</bitOffset>
              <bitWidth>1</bitWidth>
            </field>
            <field>
              <name>TRIS</name>
              <bitOffset>4</bitOffset>
              <bitWidth>1</bitWidth>
            </field>
            <field>
              <name>MUTE</name>
              <bitOffset>5</bitOffset>
              <bitWidth>1</bitWidth>
            </field>
            <field>
              <name>MUTEVAL</name>
              <bitOffset>6</bitOffset>
              <bitWidth>1</bitWidth>
            </field>
            <field>
              <name>MUTECNT</name>
              <bitOffset>7</bitOffset>
              <bitWidth>6</bitWidth>
            </field>
            <field>
              <name>CPL</name>
              <bitOffset>13</bitOffset>
              <bitWidth>1</bitWidth>
            </field>
            <field>
              <name>COMP</name>
              <bitOffset>14</bitOffset>
              <bitWidth>2</bitWidth>
            </field>
          </fields>
        </register>
        <register>
          <name>CR2A</name>
          <addressOffset>0x8</addressOffset>
          <size>0x20</size>
          <fields>
            <field>
              <name>FTH</name>
              <bitOffset>0</bitOffset>
              <bitWidth>3</bitWidth>
            </field>
            <field>
              <name>FFLUSH</name>
              <bitOffset>3</bitOffset>
              <bitWidth>1</bitWidth>
            </field>
            <field>
              <name>TRIS</name>
              <bitOffset>4</bitOffset>
              <bitWidth>1</bitWidth>
            </field>
            <field>
              <name>MUTE</name>
              <bitOffset>5</bitOffset>
              <bitWidth>1</bitWidth>
            </field>
            <field>
              <name>MUTEVAL</name>
              <bitOffset>6</bitOffset>
              <bitWidth>1</bitWidth>
            </field>
            <field>
              <name>MUTECNT</name>
              <bitOffset>7</bitOffset>
              <bitWidth>6</bitWidth>
            </field>
            <field>
              <name>CPL</name>
              <bitOffset>13</bitOffset>
              <bitWidth>1</bitWidth>
            </field>
            <field>
              <name>COMP</name>
              <bitOffset>14</bitOffset>
              <bitWidth>2</bitWidth>
            </field>
          </fields>
        </register>
        <register>
          <name>CR2A</name>
          <addressOffset>0x8</addressOffset>
          <size>0x20</size>
          <fields>
            <field>
              <name>FTH</name>
              <bitOffset>0</bitOffset>
              <bitWidth>3</bitWidth>
            </field>
            <field>
              <name>FFLUSH</name>
              <bitOffset>3</bitOffset>
              <bitWidth>1</bitWidth>
            </field>
            <field>
              <name>TRIS</name>
              <bitOffset>4</bitOffset>
              <bitWidth>1</bitWidth>
            </field>
            <field>
              <name>MUTE</name>
              <bitOffset>5</bitOffset>
              <bitWidth>1</bitWidth>
            </field>
            <field>
              <name>MUTEVAL</name>
              <bitOffset>6</bitOffset>
              <bitWidth>1</bitWidth>
            </field>
            <field>
              <name>MUTECNT</name>
              <bitOffset>7</bitOffset>
              <bitWidth>6</bitWidth>
            </field>
            <field>
              <name>CPL</name>
              <bitOffset>13</bitOffset>
              <bitWidth>1</bitWidth>
            </field>
            <field>
              <name>COMP</name>
              <bitOffset>14</bitOffset>
              <bitWidth>2</bitWidth>
            </field>
          </fields>
        </register>
        <register>
          <name>CR2A</name>
          <addressOffset>0x8</addressOffset>
          <size>0x20</size>
          <fields>
            <field>
              <name>FTH</name>
              <bitOffset>0</bitOffset>
              <bitWidth>3</bitWidth>
            </field>
            <field>
              <name>FFLUSH</name>
              <bitOffset>3</bitOffset>
              <bitWidth>1</bitWidth>
            </field>
            <field>
              <name>TRIS</name>
              <bitOffset>4</bitOffset>
              <bitWidth>1</bitWidth>
            </field>
            <field>
              <name>MUTE</name>
              <bitOffset>5</bitOffset>
              <bitWidth>1</bitWidth>
            </field>
            <field>
              <name>MUTEVAL</name>
              <bitOffset>6</bitOffset>
              <bitWidth>1</bitWidth>
            </field>
            <field>
              <name>MUTECNT</name>
              <bitOffset>7</bitOffset>
              <bitWidth>6</bitWidth>
            </field>
            <field>
              <name>CPL</name>
              <bitOffset>13</bitOffset>
              <bitWidth>1</bitWidth>
            </field>
            <field>
              <name>COMP</name>
              <bitOffset>14</bitOffset>
              <bitWidth>2</bitWidth>
            </field>
          </fields>
        </register>
        <register>
          <name>FRCRA</name>
          <addressOffset>0xc</addressOffset>
          <size>0x20</size>
          <fields>
            <field>
              <name>FRL</name>
              <bitOffset>0</bitOffset>
              <bitWidth>8</bitWidth>
            </field>
            <field>
              <name>FSALL</name>
              <bitOffset>8</bitOffset>
              <bitWidth>7</bitWidth>
            </field>
            <field>
              <name>FSDEF</name>
              <bitOffset>16</bitOffset>
              <bitWidth>1</bitWidth>
            </field>
            <field>
              <name>FSPOL</name>
              <bitOffset>17</bitOffset>
              <bitWidth>1</bitWidth>
            </field>
            <field>
              <name>FSOFF</name>
              <bitOffset>18</bitOffset>
              <bitWidth>1</bitWidth>
            </field>
          </fields>
        </register>
        <register>
          <name>FRCRA</name>
          <addressOffset>0xc</addressOffset>
          <size>0x20</size>
          <fields>
            <field>
              <name>FRL</name>
              <bitOffset>0</bitOffset>
              <bitWidth>8</bitWidth>
            </field>
            <field>
              <name>FSALL</name>
              <bitOffset>8</bitOffset>
              <bitWidth>7</bitWidth>
            </field>
            <field>
              <name>FSDEF</name>
              <bitOffset>16</bitOffset>
              <bitWidth>1</bitWidth>
            </field>
            <field>
              <name>FSPOL</name>
              <bitOffset>17</bitOffset>
              <bitWidth>1</bitWidth>
            </field>
            <field>
              <name>FSOFF</name>
              <bitOffset>18</bitOffset>
              <bitWidth>1</bitWidth>
            </field>
          </fields>
        </register>
        <register>
          <name>FRCRA</name>
          <addressOffset>0xc</addressOffset>
          <size>0x20</size>
          <fields>
            <field>
              <name>FRL</name>
              <bitOffset>0</bitOffset>
              <bitWidth>8</bitWidth>
            </field>
            <field>
              <name>FSALL</name>
              <bitOffset>8</bitOffset>
              <bitWidth>7</bitWidth>
            </field>
            <field>
              <name>FSDEF</name>
              <bitOffset>16</bitOffset>
              <bitWidth>1</bitWidth>
            </field>
            <field>
              <name>FSPOL</name>
              <bitOffset>17</bitOffset>
              <bitWidth>1</bitWidth>
            </field>
            <field>
              <name>FSOFF</name>
              <bitOffset>18</bitOffset>
              <bitWidth>1</bitWidth>
            </field>
          </fields>
        </register>
        <register>
          <name>FRCRA</name>
          <addressOffset>0xc</addressOffset>
          <size>0x20</size>
          <fields>
            <field>
              <name>FRL</name>
              <bitOffset>0</bitOffset>
              <bitWidth>8</bitWidth>
            </field>
            <field>
              <name>FSALL</name>
              <bitOffset>8</bitOffset>
              <bitWidth>7</bitWidth>
            </field>
            <field>
              <name>FSDEF</name>
              <bitOffset>16</bitOffset>
              <bitWidth>1</bitWidth>
            </field>
            <field>
              <name>FSPOL</name>
              <bitOffset>17</bitOffset>
              <bitWidth>1</bitWidth>
            </field>
            <field>
              <name>FSOFF</name>
              <bitOffset>18</bitOffset>
              <bitWidth>1</bitWidth>
            </field>
          </fields>
        </register>
        <register>
          <name>SLOTRA</name>
          <addressOffset>0x10</addressOffset>
          <size>0x20</size>
          <fields>
            <field>
              <name>FBOFF</name>
              <bitOffset>0</bitOffset>
              <bitWidth>5</bitWidth>
            </field>
            <field>
              <name>SLOTSZ</name>
              <bitOffset>6</bitOffset>
              <bitWidth>2</bitWidth>
            </field>
            <field>
              <name>NBSLOT</name>
              <bitOffset>8</bitOffset>
              <bitWidth>4</bitWidth>
            </field>
            <field>
              <name>SLOTEN</name>
              <bitOffset>16</bitOffset>
              <bitWidth>16</bitWidth>
            </field>
          </fields>
        </register>
        <register>
          <name>SLOTRA</name>
          <addressOffset>0x10</addressOffset>
          <size>0x20</size>
          <fields>
            <field>
              <name>FBOFF</name>
              <bitOffset>0</bitOffset>
              <bitWidth>5</bitWidth>
            </field>
            <field>
              <name>SLOTSZ</name>
              <bitOffset>6</bitOffset>
              <bitWidth>2</bitWidth>
            </field>
            <field>
              <name>NBSLOT</name>
              <bitOffset>8</bitOffset>
              <bitWidth>4</bitWidth>
            </field>
            <field>
              <name>SLOTEN</name>
              <bitOffset>16</bitOffset>
              <bitWidth>16</bitWidth>
            </field>
          </fields>
        </register>
        <register>
          <name>SLOTRA</name>
          <addressOffset>0x10</addressOffset>
          <size>0x20</size>
          <fields>
            <field>
              <name>FBOFF</name>
              <bitOffset>0</bitOffset>
              <bitWidth>5</bitWidth>
            </field>
            <field>
              <name>SLOTSZ</name>
              <bitOffset>6</bitOffset>
              <bitWidth>2</bitWidth>
            </field>
            <field>
              <name>NBSLOT</name>
              <bitOffset>8</bitOffset>
              <bitWidth>4</bitWidth>
            </field>
            <field>
              <name>SLOTEN</name>
              <bitOffset>16</bitOffset>
              <bitWidth>16</bitWidth>
            </field>
          </fields>
        </register>
        <register>
          <name>SLOTRA</name>
          <addressOffset>0x10</addressOffset>
          <size>0x20</size>
          <fields>
            <field>
              <name>FBOFF</name>
              <bitOffset>0</bitOffset>
              <bitWidth>5</bitWidth>
            </field>
            <field>
              <name>SLOTSZ</name>
              <bitOffset>6</bitOffset>
              <bitWidth>2</bitWidth>
            </field>
            <field>
              <name>NBSLOT</name>
              <bitOffset>8</bitOffset>
              <bitWidth>4</bitWidth>
            </field>
            <field>
              <name>SLOTEN</name>
              <bitOffset>16</bitOffset>
              <bitWidth>16</bitWidth>
            </field>
          </fields>
        </register>
        <register>
          <name>IMRA</name>
          <addressOffset>0x14</addressOffset>
          <size>0x20</size>
          <fields>
            <field>
              <name>OVRUDRIE</name>
              <bitOffset>0</bitOffset>
              <bitWidth>1</bitWidth>
            </field>
            <field>
              <name>MUTEDETIE</name>
              <bitOffset>1</bitOffset>
              <bitWidth>1</bitWidth>
            </field>
            <field>
              <name>WCKCFGIE</name>
              <bitOffset>2</bitOffset>
              <bitWidth>1</bitWidth>
            </field>
            <field>
              <name>FREQIE</name>
              <bitOffset>3</bitOffset>
              <bitWidth>1</bitWidth>
            </field>
            <field>
              <name>CNRDYIE</name>
              <bitOffset>4</bitOffset>
              <bitWidth>1</bitWidth>
            </field>
            <field>
              <name>AFSDETIE</name>
              <bitOffset>5</bitOffset>
              <bitWidth>1</bitWidth>
            </field>
            <field>
              <name>LFSDETIE</name>
              <bitOffset>6</bitOffset>
              <bitWidth>1</bitWidth>
            </field>
          </fields>
        </register>
        <register>
          <name>IMRA</name>
          <addressOffset>0x14</addressOffset>
          <size>0x20</size>
          <fields>
            <field>
              <name>OVRUDRIE</name>
              <bitOffset>0</bitOffset>
              <bitWidth>1</bitWidth>
            </field>
            <field>
              <name>MUTEDETIE</name>
              <bitOffset>1</bitOffset>
              <bitWidth>1</bitWidth>
            </field>
            <field>
              <name>WCKCFGIE</name>
              <bitOffset>2</bitOffset>
              <bitWidth>1</bitWidth>
            </field>
            <field>
              <name>FREQIE</name>
              <bitOffset>3</bitOffset>
              <bitWidth>1</bitWidth>
            </field>
            <field>
              <name>CNRDYIE</name>
              <bitOffset>4</bitOffset>
              <bitWidth>1</bitWidth>
            </field>
            <field>
              <name>AFSDETIE</name>
              <bitOffset>5</bitOffset>
              <bitWidth>1</bitWidth>
            </field>
            <field>
              <name>LFSDETIE</name>
              <bitOffset>6</bitOffset>
              <bitWidth>1</bitWidth>
            </field>
          </fields>
        </register>
        <register>
          <name>IMRA</name>
          <addressOffset>0x14</addressOffset>
          <size>0x20</size>
          <fields>
            <field>
              <name>OVRUDRIE</name>
              <bitOffset>0</bitOffset>
              <bitWidth>1</bitWidth>
            </field>
            <field>
              <name>MUTEDETIE</name>
              <bitOffset>1</bitOffset>
              <bitWidth>1</bitWidth>
            </field>
            <field>
              <name>WCKCFGIE</name>
              <bitOffset>2</bitOffset>
              <bitWidth>1</bitWidth>
            </field>
            <field>
              <name>FREQIE</name>
              <bitOffset>3</bitOffset>
              <bitWidth>1</bitWidth>
            </field>
            <field>
              <name>CNRDYIE</name>
              <bitOffset>4</bitOffset>
              <bitWidth>1</bitWidth>
            </field>
            <field>
              <name>AFSDETIE</name>
              <bitOffset>5</bitOffset>
              <bitWidth>1</bitWidth>
            </field>
            <field>
              <name>LFSDETIE</name>
              <bitOffset>6</bitOffset>
              <bitWidth>1</bitWidth>
            </field>
          </fields>
        </register>
        <register>
          <name>IMRA</name>
          <addressOffset>0x14</addressOffset>
          <size>0x20</size>
          <fields>
            <field>
              <name>OVRUDRIE</name>
              <bitOffset>0</bitOffset>
              <bitWidth>1</bitWidth>
            </field>
            <field>
              <name>MUTEDETIE</name>
              <bitOffset>1</bitOffset>
              <bitWidth>1</bitWidth>
            </field>
            <field>
              <name>WCKCFGIE</name>
              <bitOffset>2</bitOffset>
              <bitWidth>1</bitWidth>
            </field>
            <field>
              <name>FREQIE</name>
              <bitOffset>3</bitOffset>
              <bitWidth>1</bitWidth>
            </field>
            <field>
              <name>CNRDYIE</name>
              <bitOffset>4</bitOffset>
              <bitWidth>1</bitWidth>
            </field>
            <field>
              <name>AFSDETIE</name>
              <bitOffset>5</bitOffset>
              <bitWidth>1</bitWidth>
            </field>
            <field>
              <name>LFSDETIE</name>
              <bitOffset>6</bitOffset>
              <bitWidth>1</bitWidth>
            </field>
          </fields>
        </register>
        <register>
          <name>SRA</name>
          <addressOffset>0x18</addressOffset>
          <size>0x20</size>
          <fields>
            <field>
              <name>OVRUDR</name>
              <bitOffset>0</bitOffset>
              <bitWidth>1</bitWidth>
            </field>
            <field>
              <name>MUTEDET</name>
              <bitOffset>1</bitOffset>
              <bitWidth>1</bitWidth>
            </field>
            <field>
              <name>WCKCFG</name>
              <bitOffset>2</bitOffset>
              <bitWidth>1</bitWidth>
            </field>
            <field>
              <name>FREQ</name>
              <bitOffset>3</bitOffset>
              <bitWidth>1</bitWidth>
            </field>
            <field>
              <name>CNRDY</name>
              <bitOffset>4</bitOffset>
              <bitWidth>1</bitWidth>
            </field>
            <field>
              <name>AFSDET</name>
              <bitOffset>5</bitOffset>
              <bitWidth>1</bitWidth>
            </field>
            <field>
              <name>LFSDET</name>
              <bitOffset>6</bitOffset>
              <bitWidth>1</bitWidth>
            </field>
            <field>
              <name>FLVL</name>
              <bitOffset>16</bitOffset>
              <bitWidth>3</bitWidth>
            </field>
          </fields>
        </register>
        <register>
          <name>SRA</name>
          <addressOffset>0x18</addressOffset>
          <size>0x20</size>
          <fields>
            <field>
              <name>OVRUDR</name>
              <bitOffset>0</bitOffset>
              <bitWidth>1</bitWidth>
            </field>
            <field>
              <name>MUTEDET</name>
              <bitOffset>1</bitOffset>
              <bitWidth>1</bitWidth>
            </field>
            <field>
              <name>WCKCFG</name>
              <bitOffset>2</bitOffset>
              <bitWidth>1</bitWidth>
            </field>
            <field>
              <name>FREQ</name>
              <bitOffset>3</bitOffset>
              <bitWidth>1</bitWidth>
            </field>
            <field>
              <name>CNRDY</name>
              <bitOffset>4</bitOffset>
              <bitWidth>1</bitWidth>
            </field>
            <field>
              <name>AFSDET</name>
              <bitOffset>5</bitOffset>
              <bitWidth>1</bitWidth>
            </field>
            <field>
              <name>LFSDET</name>
              <bitOffset>6</bitOffset>
              <bitWidth>1</bitWidth>
            </field>
            <field>
              <name>FLVL</name>
              <bitOffset>16</bitOffset>
              <bitWidth>3</bitWidth>
            </field>
          </fields>
        </register>
        <register>
          <name>SRA</name>
          <addressOffset>0x18</addressOffset>
          <size>0x20</size>
          <fields>
            <field>
              <name>OVRUDR</name>
              <bitOffset>0</bitOffset>
              <bitWidth>1</bitWidth>
            </field>
            <field>
              <name>MUTEDET</name>
              <bitOffset>1</bitOffset>
              <bitWidth>1</bitWidth>
            </field>
            <field>
              <name>WCKCFG</name>
              <bitOffset>2</bitOffset>
              <bitWidth>1</bitWidth>
            </field>
            <field>
              <name>FREQ</name>
              <bitOffset>3</bitOffset>
              <bitWidth>1</bitWidth>
            </field>
            <field>
              <name>CNRDY</name>
              <bitOffset>4</bitOffset>
              <bitWidth>1</bitWidth>
            </field>
            <field>
              <name>AFSDET</name>
              <bitOffset>5</bitOffset>
              <bitWidth>1</bitWidth>
            </field>
            <field>
              <name>LFSDET</name>
              <bitOffset>6</bitOffset>
              <bitWidth>1</bitWidth>
            </field>
            <field>
              <name>FLVL</name>
              <bitOffset>16</bitOffset>
              <bitWidth>3</bitWidth>
            </field>
          </fields>
        </register>
        <register>
          <name>SRA</name>
          <addressOffset>0x18</addressOffset>
          <size>0x20</size>
          <fields>
            <field>
              <name>OVRUDR</name>
              <bitOffset>0</bitOffset>
              <bitWidth>1</bitWidth>
            </field>
            <field>
              <name>MUTEDET</name>
              <bitOffset>1</bitOffset>
              <bitWidth>1</bitWidth>
            </field>
            <field>
              <name>WCKCFG</name>
              <bitOffset>2</bitOffset>
              <bitWidth>1</bitWidth>
            </field>
            <field>
              <name>FREQ</name>
              <bitOffset>3</bitOffset>
              <bitWidth>1</bitWidth>
            </field>
            <field>
              <name>CNRDY</name>
              <bitOffset>4</bitOffset>
              <bitWidth>1</bitWidth>
            </field>
            <field>
              <name>AFSDET</name>
              <bitOffset>5</bitOffset>
              <bitWidth>1</bitWidth>
            </field>
            <field>
              <name>LFSDET</name>
              <bitOffset>6</bitOffset>
              <bitWidth>1</bitWidth>
            </field>
            <field>
              <name>FLVL</name>
              <bitOffset>16</bitOffset>
              <bitWidth>3</bitWidth>
            </field>
          </fields>
        </register>
        <register>
          <name>CLRFRA</name>
          <addressOffset>0x1c</addressOffset>
          <size>0x20</size>
          <fields>
            <field>
              <name>COVRUDR</name>
              <bitOffset>0</bitOffset>
              <bitWidth>1</bitWidth>
            </field>
            <field>
              <name>CMUTEDET</name>
              <bitOffset>1</bitOffset>
              <bitWidth>1</bitWidth>
            </field>
            <field>
              <name>CWCKCFG</name>
              <bitOffset>2</bitOffset>
              <bitWidth>1</bitWidth>
            </field>
            <field>
              <name>CFREQ</name>
              <bitOffset>3</bitOffset>
              <bitWidth>1</bitWidth>
            </field>
            <field>
              <name>CCNRDY</name>
              <bitOffset>4</bitOffset>
              <bitWidth>1</bitWidth>
            </field>
            <field>
              <name>CAFSDET</name>
              <bitOffset>5</bitOffset>
              <bitWidth>1</bitWidth>
            </field>
            <field>
              <name>CLFSDET</name>
              <bitOffset>6</bitOffset>
              <bitWidth>1</bitWidth>
            </field>
          </fields>
        </register>
        <register>
          <name>CLRFRA</name>
          <addressOffset>0x1c</addressOffset>
          <size>0x20</size>
          <fields>
            <field>
              <name>COVRUDR</name>
              <bitOffset>0</bitOffset>
              <bitWidth>1</bitWidth>
            </field>
            <field>
              <name>CMUTEDET</name>
              <bitOffset>1</bitOffset>
              <bitWidth>1</bitWidth>
            </field>
            <field>
              <name>CWCKCFG</name>
              <bitOffset>2</bitOffset>
              <bitWidth>1</bitWidth>
            </field>
            <field>
              <name>CFREQ</name>
              <bitOffset>3</bitOffset>
              <bitWidth>1</bitWidth>
            </field>
            <field>
              <name>CCNRDY</name>
              <bitOffset>4</bitOffset>
              <bitWidth>1</bitWidth>
            </field>
            <field>
              <name>CAFSDET</name>
              <bitOffset>5</bitOffset>
              <bitWidth>1</bitWidth>
            </field>
            <field>
              <name>CLFSDET</name>
              <bitOffset>6</bitOffset>
              <bitWidth>1</bitWidth>
            </field>
          </fields>
        </register>
        <register>
          <name>CLRFRA</name>
          <addressOffset>0x1c</addressOffset>
          <size>0x20</size>
          <fields>
            <field>
              <name>COVRUDR</name>
              <bitOffset>0</bitOffset>
              <bitWidth>1</bitWidth>
            </field>
            <field>
              <name>CMUTEDET</name>
              <bitOffset>1</bitOffset>
              <bitWidth>1</bitWidth>
            </field>
            <field>
              <name>CWCKCFG</name>
              <bitOffset>2</bitOffset>
              <bitWidth>1</bitWidth>
            </field>
            <field>
              <name>CFREQ</name>
              <bitOffset>3</bitOffset>
              <bitWidth>1</bitWidth>
            </field>
            <field>
              <name>CCNRDY</name>
              <bitOffset>4</bitOffset>
              <bitWidth>1</bitWidth>
            </field>
            <field>
              <name>CAFSDET</name>
              <bitOffset>5</bitOffset>
              <bitWidth>1</bitWidth>
            </field>
            <field>
              <name>CLFSDET</name>
              <bitOffset>6</bitOffset>
              <bitWidth>1</bitWidth>
            </field>
          </fields>
        </register>
        <register>
          <name>CLRFRA</name>
          <addressOffset>0x1c</addressOffset>
          <size>0x20</size>
          <fields>
            <field>
              <name>COVRUDR</name>
              <bitOffset>0</bitOffset>
              <bitWidth>1</bitWidth>
            </field>
            <field>
              <name>CMUTEDET</name>
              <bitOffset>1</bitOffset>
              <bitWidth>1</bitWidth>
            </field>
            <field>
              <name>CWCKCFG</name>
              <bitOffset>2</bitOffset>
              <bitWidth>1</bitWidth>
            </field>
            <field>
              <name>CFREQ</name>
              <bitOffset>3</bitOffset>
              <bitWidth>1</bitWidth>
            </field>
            <field>
              <name>CCNRDY</name>
              <bitOffset>4</bitOffset>
              <bitWidth>1</bitWidth>
            </field>
            <field>
              <name>CAFSDET</name>
              <bitOffset>5</bitOffset>
              <bitWidth>1</bitWidth>
            </field>
            <field>
              <name>CLFSDET</name>
              <bitOffset>6</bitOffset>
              <bitWidth>1</bitWidth>
            </field>
          </fields>
        </register>
        <register>
          <name>DRA</name>
          <addressOffset>0x20</addressOffset>
          <size>0x20</size>
          <fields>
            <field>
              <name>DATA</name>
              <bitOffset>0</bitOffset>
              <bitWidth>32</bitWidth>
            </field>
          </fields>
        </register>
        <register>
          <name>DRA</name>
          <addressOffset>0x20</addressOffset>
          <size>0x20</size>
          <fields>
            <field>
              <name>DATA</name>
              <bitOffset>0</bitOffset>
              <bitWidth>32</bitWidth>
            </field>
          </fields>
        </register>
        <register>
          <name>DRA</name>
          <addressOffset>0x20</addressOffset>
          <size>0x20</size>
          <fields>
            <field>
              <name>DATA</name>
              <bitOffset>0</bitOffset>
              <bitWidth>32</bitWidth>
            </field>
          </fields>
        </register>
        <register>
          <name>DRA</name>
          <addressOffset>0x20</addressOffset>
          <size>0x20</size>
          <fields>
            <field>
              <name>DATA</name>
              <bitOffset>0</bitOffset>
              <bitWidth>32</bitWidth>
            </field>
          </fields>
        </register>
        <register>
          <name>CR1B</name>
          <addressOffset>0x24</addressOffset>
          <size>0x20</size>
          <fields>
            <field>
              <name>MODE</name>
              <bitOffset>0</bitOffset>
              <bitWidth>2</bitWidth>
            </field>
            <field>
              <name>PRTCFG</name>
              <bitOffset>2</bitOffset>
              <bitWidth>2</bitWidth>
            </field>
            <field>
              <name>DS</name>
              <bitOffset>5</bitOffset>
              <bitWidth>3</bitWidth>
            </field>
            <field>
              <name>LSBFIRST</name>
              <bitOffset>8</bitOffset>
              <bitWidth>1</bitWidth>
            </field>
            <field>
              <name>CKSTR</name>
              <bitOffset>9</bitOffset>
              <bitWidth>1</bitWidth>
            </field>
            <field>
              <name>SYNCEN</name>
              <bitOffset>10</bitOffset>
              <bitWidth>2</bitWidth>
            </field>
            <field>
              <name>MONO</name>
              <bitOffset>12</bitOffset>
              <bitWidth>1</bitWidth>
            </field>
            <field>
              <name>OUTDRIV</name>
              <bitOffset>13</bitOffset>
              <bitWidth>1</bitWidth>
            </field>
            <field>
              <name>SAIEN</name>
              <bitOffset>16</bitOffset>
              <bitWidth>1</bitWidth>
            </field>
            <field>
              <name>DMAEN</name>
              <bitOffset>17</bitOffset>
              <bitWidth>1</bitWidth>
            </field>
            <field>
              <name>NODIV</name>
              <bitOffset>19</bitOffset>
              <bitWidth>1</bitWidth>
            </field>
            <field>
              <name>MCKDIV</name>
              <bitOffset>20</bitOffset>
              <bitWidth>6</bitWidth>
            </field>
            <field>
              <name>OSR</name>
              <bitOffset>26</bitOffset>
              <bitWidth>1</bitWidth>
            </field>
            <field>
              <name>MCKEN</name>
              <bitOffset>27</bitOffset>
              <bitWidth>1</bitWidth>
            </field>
          </fields>
        </register>
        <register>
          <name>CR1B</name>
          <addressOffset>0x24</addressOffset>
          <size>0x20</size>
          <fields>
            <field>
              <name>MODE</name>
              <bitOffset>0</bitOffset>
              <bitWidth>2</bitWidth>
            </field>
            <field>
              <name>PRTCFG</name>
              <bitOffset>2</bitOffset>
              <bitWidth>2</bitWidth>
            </field>
            <field>
              <name>DS</name>
              <bitOffset>5</bitOffset>
              <bitWidth>3</bitWidth>
            </field>
            <field>
              <name>LSBFIRST</name>
              <bitOffset>8</bitOffset>
              <bitWidth>1</bitWidth>
            </field>
            <field>
              <name>CKSTR</name>
              <bitOffset>9</bitOffset>
              <bitWidth>1</bitWidth>
            </field>
            <field>
              <name>SYNCEN</name>
              <bitOffset>10</bitOffset>
              <bitWidth>2</bitWidth>
            </field>
            <field>
              <name>MONO</name>
              <bitOffset>12</bitOffset>
              <bitWidth>1</bitWidth>
            </field>
            <field>
              <name>OUTDRIV</name>
              <bitOffset>13</bitOffset>
              <bitWidth>1</bitWidth>
            </field>
            <field>
              <name>SAIEN</name>
              <bitOffset>16</bitOffset>
              <bitWidth>1</bitWidth>
            </field>
            <field>
              <name>DMAEN</name>
              <bitOffset>17</bitOffset>
              <bitWidth>1</bitWidth>
            </field>
            <field>
              <name>NODIV</name>
              <bitOffset>19</bitOffset>
              <bitWidth>1</bitWidth>
            </field>
            <field>
              <name>MCKDIV</name>
              <bitOffset>20</bitOffset>
              <bitWidth>6</bitWidth>
            </field>
            <field>
              <name>OSR</name>
              <bitOffset>26</bitOffset>
              <bitWidth>1</bitWidth>
            </field>
            <field>
              <name>MCKEN</name>
              <bitOffset>27</bitOffset>
              <bitWidth>1</bitWidth>
            </field>
          </fields>
        </register>
        <register>
          <name>CR1B</name>
          <addressOffset>0x24</addressOffset>
          <size>0x20</size>
          <fields>
            <field>
              <name>MODE</name>
              <bitOffset>0</bitOffset>
              <bitWidth>2</bitWidth>
            </field>
            <field>
              <name>PRTCFG</name>
              <bitOffset>2</bitOffset>
              <bitWidth>2</bitWidth>
            </field>
            <field>
              <name>DS</name>
              <bitOffset>5</bitOffset>
              <bitWidth>3</bitWidth>
            </field>
            <field>
              <name>LSBFIRST</name>
              <bitOffset>8</bitOffset>
              <bitWidth>1</bitWidth>
            </field>
            <field>
              <name>CKSTR</name>
              <bitOffset>9</bitOffset>
              <bitWidth>1</bitWidth>
            </field>
            <field>
              <name>SYNCEN</name>
              <bitOffset>10</bitOffset>
              <bitWidth>2</bitWidth>
            </field>
            <field>
              <name>MONO</name>
              <bitOffset>12</bitOffset>
              <bitWidth>1</bitWidth>
            </field>
            <field>
              <name>OUTDRIV</name>
              <bitOffset>13</bitOffset>
              <bitWidth>1</bitWidth>
            </field>
            <field>
              <name>SAIEN</name>
              <bitOffset>16</bitOffset>
              <bitWidth>1</bitWidth>
            </field>
            <field>
              <name>DMAEN</name>
              <bitOffset>17</bitOffset>
              <bitWidth>1</bitWidth>
            </field>
            <field>
              <name>NODIV</name>
              <bitOffset>19</bitOffset>
              <bitWidth>1</bitWidth>
            </field>
            <field>
              <name>MCKDIV</name>
              <bitOffset>20</bitOffset>
              <bitWidth>6</bitWidth>
            </field>
            <field>
              <name>OSR</name>
              <bitOffset>26</bitOffset>
              <bitWidth>1</bitWidth>
            </field>
            <field>
              <name>MCKEN</name>
              <bitOffset>27</bitOffset>
              <bitWidth>1</bitWidth>
            </field>
          </fields>
        </register>
        <register>
          <name>CR1B</name>
          <addressOffset>0x24</addressOffset>
          <size>0x20</size>
          <fields>
            <field>
              <name>MODE</name>
              <bitOffset>0</bitOffset>
              <bitWidth>2</bitWidth>
            </field>
            <field>
              <name>PRTCFG</name>
              <bitOffset>2</bitOffset>
              <bitWidth>2</bitWidth>
            </field>
            <field>
              <name>DS</name>
              <bitOffset>5</bitOffset>
              <bitWidth>3</bitWidth>
            </field>
            <field>
              <name>LSBFIRST</name>
              <bitOffset>8</bitOffset>
              <bitWidth>1</bitWidth>
            </field>
            <field>
              <name>CKSTR</name>
              <bitOffset>9</bitOffset>
              <bitWidth>1</bitWidth>
            </field>
            <field>
              <name>SYNCEN</name>
              <bitOffset>10</bitOffset>
              <bitWidth>2</bitWidth>
            </field>
            <field>
              <name>MONO</name>
              <bitOffset>12</bitOffset>
              <bitWidth>1</bitWidth>
            </field>
            <field>
              <name>OUTDRIV</name>
              <bitOffset>13</bitOffset>
              <bitWidth>1</bitWidth>
            </field>
            <field>
              <name>SAIEN</name>
              <bitOffset>16</bitOffset>
              <bitWidth>1</bitWidth>
            </field>
            <field>
              <name>DMAEN</name>
              <bitOffset>17</bitOffset>
              <bitWidth>1</bitWidth>
            </field>
            <field>
              <name>NODIV</name>
              <bitOffset>19</bitOffset>
              <bitWidth>1</bitWidth>
            </field>
            <field>
              <name>MCKDIV</name>
              <bitOffset>20</bitOffset>
              <bitWidth>6</bitWidth>
            </field>
            <field>
              <name>OSR</name>
              <bitOffset>26</bitOffset>
              <bitWidth>1</bitWidth>
            </field>
            <field>
              <name>MCKEN</name>
              <bitOffset>27</bitOffset>
              <bitWidth>1</bitWidth>
            </field>
          </fields>
        </register>
        <register>
          <name>CR2B</name>
          <addressOffset>0x28</addressOffset>
          <size>0x20</size>
          <fields>
            <field>
              <name>FTH</name>
              <bitOffset>0</bitOffset>
              <bitWidth>3</bitWidth>
            </field>
            <field>
              <name>FFLUSH</name>
              <bitOffset>3</bitOffset>
              <bitWidth>1</bitWidth>
            </field>
            <field>
              <name>TRIS</name>
              <bitOffset>4</bitOffset>
              <bitWidth>1</bitWidth>
            </field>
            <field>
              <name>MUTE</name>
              <bitOffset>5</bitOffset>
              <bitWidth>1</bitWidth>
            </field>
            <field>
              <name>MUTEVAL</name>
              <bitOffset>6</bitOffset>
              <bitWidth>1</bitWidth>
            </field>
            <field>
              <name>MUTECNT</name>
              <bitOffset>7</bitOffset>
              <bitWidth>6</bitWidth>
            </field>
            <field>
              <name>CPL</name>
              <bitOffset>13</bitOffset>
              <bitWidth>1</bitWidth>
            </field>
            <field>
              <name>COMP</name>
              <bitOffset>14</bitOffset>
              <bitWidth>2</bitWidth>
            </field>
          </fields>
        </register>
        <register>
          <name>CR2B</name>
          <addressOffset>0x28</addressOffset>
          <size>0x20</size>
          <fields>
            <field>
              <name>FTH</name>
              <bitOffset>0</bitOffset>
              <bitWidth>3</bitWidth>
            </field>
            <field>
              <name>FFLUSH</name>
              <bitOffset>3</bitOffset>
              <bitWidth>1</bitWidth>
            </field>
            <field>
              <name>TRIS</name>
              <bitOffset>4</bitOffset>
              <bitWidth>1</bitWidth>
            </field>
            <field>
              <name>MUTE</name>
              <bitOffset>5</bitOffset>
              <bitWidth>1</bitWidth>
            </field>
            <field>
              <name>MUTEVAL</name>
              <bitOffset>6</bitOffset>
              <bitWidth>1</bitWidth>
            </field>
            <field>
              <name>MUTECNT</name>
              <bitOffset>7</bitOffset>
              <bitWidth>6</bitWidth>
            </field>
            <field>
              <name>CPL</name>
              <bitOffset>13</bitOffset>
              <bitWidth>1</bitWidth>
            </field>
            <field>
              <name>COMP</name>
              <bitOffset>14</bitOffset>
              <bitWidth>2</bitWidth>
            </field>
          </fields>
        </register>
        <register>
          <name>CR2B</name>
          <addressOffset>0x28</addressOffset>
          <size>0x20</size>
          <fields>
            <field>
              <name>FTH</name>
              <bitOffset>0</bitOffset>
              <bitWidth>3</bitWidth>
            </field>
            <field>
              <name>FFLUSH</name>
              <bitOffset>3</bitOffset>
              <bitWidth>1</bitWidth>
            </field>
            <field>
              <name>TRIS</name>
              <bitOffset>4</bitOffset>
              <bitWidth>1</bitWidth>
            </field>
            <field>
              <name>MUTE</name>
              <bitOffset>5</bitOffset>
              <bitWidth>1</bitWidth>
            </field>
            <field>
              <name>MUTEVAL</name>
              <bitOffset>6</bitOffset>
              <bitWidth>1</bitWidth>
            </field>
            <field>
              <name>MUTECNT</name>
              <bitOffset>7</bitOffset>
              <bitWidth>6</bitWidth>
            </field>
            <field>
              <name>CPL</name>
              <bitOffset>13</bitOffset>
              <bitWidth>1</bitWidth>
            </field>
            <field>
              <name>COMP</name>
              <bitOffset>14</bitOffset>
              <bitWidth>2</bitWidth>
            </field>
          </fields>
        </register>
        <register>
          <name>CR2B</name>
          <addressOffset>0x28</addressOffset>
          <size>0x20</size>
          <fields>
            <field>
              <name>FTH</name>
              <bitOffset>0</bitOffset>
              <bitWidth>3</bitWidth>
            </field>
            <field>
              <name>FFLUSH</name>
              <bitOffset>3</bitOffset>
              <bitWidth>1</bitWidth>
            </field>
            <field>
              <name>TRIS</name>
              <bitOffset>4</bitOffset>
              <bitWidth>1</bitWidth>
            </field>
            <field>
              <name>MUTE</name>
              <bitOffset>5</bitOffset>
              <bitWidth>1</bitWidth>
            </field>
            <field>
              <name>MUTEVAL</name>
              <bitOffset>6</bitOffset>
              <bitWidth>1</bitWidth>
            </field>
            <field>
              <name>MUTECNT</name>
              <bitOffset>7</bitOffset>
              <bitWidth>6</bitWidth>
            </field>
            <field>
              <name>CPL</name>
              <bitOffset>13</bitOffset>
              <bitWidth>1</bitWidth>
            </field>
            <field>
              <name>COMP</name>
              <bitOffset>14</bitOffset>
              <bitWidth>2</bitWidth>
            </field>
          </fields>
        </register>
        <register>
          <name>FRCRB</name>
          <addressOffset>0x2c</addressOffset>
          <size>0x20</size>
          <fields>
            <field>
              <name>FRL</name>
              <bitOffset>0</bitOffset>
              <bitWidth>8</bitWidth>
            </field>
            <field>
              <name>FSALL</name>
              <bitOffset>8</bitOffset>
              <bitWidth>7</bitWidth>
            </field>
            <field>
              <name>FSDEF</name>
              <bitOffset>16</bitOffset>
              <bitWidth>1</bitWidth>
            </field>
            <field>
              <name>FSPOL</name>
              <bitOffset>17</bitOffset>
              <bitWidth>1</bitWidth>
            </field>
            <field>
              <name>FSOFF</name>
              <bitOffset>18</bitOffset>
              <bitWidth>1</bitWidth>
            </field>
          </fields>
        </register>
        <register>
          <name>FRCRB</name>
          <addressOffset>0x2c</addressOffset>
          <size>0x20</size>
          <fields>
            <field>
              <name>FRL</name>
              <bitOffset>0</bitOffset>
              <bitWidth>8</bitWidth>
            </field>
            <field>
              <name>FSALL</name>
              <bitOffset>8</bitOffset>
              <bitWidth>7</bitWidth>
            </field>
            <field>
              <name>FSDEF</name>
              <bitOffset>16</bitOffset>
              <bitWidth>1</bitWidth>
            </field>
            <field>
              <name>FSPOL</name>
              <bitOffset>17</bitOffset>
              <bitWidth>1</bitWidth>
            </field>
            <field>
              <name>FSOFF</name>
              <bitOffset>18</bitOffset>
              <bitWidth>1</bitWidth>
            </field>
          </fields>
        </register>
        <register>
          <name>FRCRB</name>
          <addressOffset>0x2c</addressOffset>
          <size>0x20</size>
          <fields>
            <field>
              <name>FRL</name>
              <bitOffset>0</bitOffset>
              <bitWidth>8</bitWidth>
            </field>
            <field>
              <name>FSALL</name>
              <bitOffset>8</bitOffset>
              <bitWidth>7</bitWidth>
            </field>
            <field>
              <name>FSDEF</name>
              <bitOffset>16</bitOffset>
              <bitWidth>1</bitWidth>
            </field>
            <field>
              <name>FSPOL</name>
              <bitOffset>17</bitOffset>
              <bitWidth>1</bitWidth>
            </field>
            <field>
              <name>FSOFF</name>
              <bitOffset>18</bitOffset>
              <bitWidth>1</bitWidth>
            </field>
          </fields>
        </register>
        <register>
          <name>FRCRB</name>
          <addressOffset>0x2c</addressOffset>
          <size>0x20</size>
          <fields>
            <field>
              <name>FRL</name>
              <bitOffset>0</bitOffset>
              <bitWidth>8</bitWidth>
            </field>
            <field>
              <name>FSALL</name>
              <bitOffset>8</bitOffset>
              <bitWidth>7</bitWidth>
            </field>
            <field>
              <name>FSDEF</name>
              <bitOffset>16</bitOffset>
              <bitWidth>1</bitWidth>
            </field>
            <field>
              <name>FSPOL</name>
              <bitOffset>17</bitOffset>
              <bitWidth>1</bitWidth>
            </field>
            <field>
              <name>FSOFF</name>
              <bitOffset>18</bitOffset>
              <bitWidth>1</bitWidth>
            </field>
          </fields>
        </register>
        <register>
          <name>SLOTRB</name>
          <addressOffset>0x30</addressOffset>
          <size>0x20</size>
          <fields>
            <field>
              <name>FBOFF</name>
              <bitOffset>0</bitOffset>
              <bitWidth>5</bitWidth>
            </field>
            <field>
              <name>SLOTSZ</name>
              <bitOffset>6</bitOffset>
              <bitWidth>2</bitWidth>
            </field>
            <field>
              <name>NBSLOT</name>
              <bitOffset>8</bitOffset>
              <bitWidth>4</bitWidth>
            </field>
            <field>
              <name>SLOTEN</name>
              <bitOffset>16</bitOffset>
              <bitWidth>16</bitWidth>
            </field>
          </fields>
        </register>
        <register>
          <name>SLOTRB</name>
          <addressOffset>0x30</addressOffset>
          <size>0x20</size>
          <fields>
            <field>
              <name>FBOFF</name>
              <bitOffset>0</bitOffset>
              <bitWidth>5</bitWidth>
            </field>
            <field>
              <name>SLOTSZ</name>
              <bitOffset>6</bitOffset>
              <bitWidth>2</bitWidth>
            </field>
            <field>
              <name>NBSLOT</name>
              <bitOffset>8</bitOffset>
              <bitWidth>4</bitWidth>
            </field>
            <field>
              <name>SLOTEN</name>
              <bitOffset>16</bitOffset>
              <bitWidth>16</bitWidth>
            </field>
          </fields>
        </register>
        <register>
          <name>SLOTRB</name>
          <addressOffset>0x30</addressOffset>
          <size>0x20</size>
          <fields>
            <field>
              <name>FBOFF</name>
              <bitOffset>0</bitOffset>
              <bitWidth>5</bitWidth>
            </field>
            <field>
              <name>SLOTSZ</name>
              <bitOffset>6</bitOffset>
              <bitWidth>2</bitWidth>
            </field>
            <field>
              <name>NBSLOT</name>
              <bitOffset>8</bitOffset>
              <bitWidth>4</bitWidth>
            </field>
            <field>
              <name>SLOTEN</name>
              <bitOffset>16</bitOffset>
              <bitWidth>16</bitWidth>
            </field>
          </fields>
        </register>
        <register>
          <name>SLOTRB</name>
          <addressOffset>0x30</addressOffset>
          <size>0x20</size>
          <fields>
            <field>
              <name>FBOFF</name>
              <bitOffset>0</bitOffset>
              <bitWidth>5</bitWidth>
            </field>
            <field>
              <name>SLOTSZ</name>
              <bitOffset>6</bitOffset>
              <bitWidth>2</bitWidth>
            </field>
            <field>
              <name>NBSLOT</name>
              <bitOffset>8</bitOffset>
              <bitWidth>4</bitWidth>
            </field>
            <field>
              <name>SLOTEN</name>
              <bitOffset>16</bitOffset>
              <bitWidth>16</bitWidth>
            </field>
          </fields>
        </register>
        <register>
          <name>IMRB</name>
          <addressOffset>0x34</addressOffset>
          <size>0x20</size>
          <fields>
            <field>
              <name>OVRUDRIE</name>
              <bitOffset>0</bitOffset>
              <bitWidth>1</bitWidth>
            </field>
            <field>
              <name>MUTEDETIE</name>
              <bitOffset>1</bitOffset>
              <bitWidth>1</bitWidth>
            </field>
            <field>
              <name>WCKCFGIE</name>
              <bitOffset>2</bitOffset>
              <bitWidth>1</bitWidth>
            </field>
            <field>
              <name>FREQIE</name>
              <bitOffset>3</bitOffset>
              <bitWidth>1</bitWidth>
            </field>
            <field>
              <name>CNRDYIE</name>
              <bitOffset>4</bitOffset>
              <bitWidth>1</bitWidth>
            </field>
            <field>
              <name>AFSDETIE</name>
              <bitOffset>5</bitOffset>
              <bitWidth>1</bitWidth>
            </field>
            <field>
              <name>LFSDETIE</name>
              <bitOffset>6</bitOffset>
              <bitWidth>1</bitWidth>
            </field>
          </fields>
        </register>
        <register>
          <name>IMRB</name>
          <addressOffset>0x34</addressOffset>
          <size>0x20</size>
          <fields>
            <field>
              <name>OVRUDRIE</name>
              <bitOffset>0</bitOffset>
              <bitWidth>1</bitWidth>
            </field>
            <field>
              <name>MUTEDETIE</name>
              <bitOffset>1</bitOffset>
              <bitWidth>1</bitWidth>
            </field>
            <field>
              <name>WCKCFGIE</name>
              <bitOffset>2</bitOffset>
              <bitWidth>1</bitWidth>
            </field>
            <field>
              <name>FREQIE</name>
              <bitOffset>3</bitOffset>
              <bitWidth>1</bitWidth>
            </field>
            <field>
              <name>CNRDYIE</name>
              <bitOffset>4</bitOffset>
              <bitWidth>1</bitWidth>
            </field>
            <field>
              <name>AFSDETIE</name>
              <bitOffset>5</bitOffset>
              <bitWidth>1</bitWidth>
            </field>
            <field>
              <name>LFSDETIE</name>
              <bitOffset>6</bitOffset>
              <bitWidth>1</bitWidth>
            </field>
          </fields>
        </register>
        <register>
          <name>IMRB</name>
          <addressOffset>0x34</addressOffset>
          <size>0x20</size>
          <fields>
            <field>
              <name>OVRUDRIE</name>
              <bitOffset>0</bitOffset>
              <bitWidth>1</bitWidth>
            </field>
            <field>
              <name>MUTEDETIE</name>
              <bitOffset>1</bitOffset>
              <bitWidth>1</bitWidth>
            </field>
            <field>
              <name>WCKCFGIE</name>
              <bitOffset>2</bitOffset>
              <bitWidth>1</bitWidth>
            </field>
            <field>
              <name>FREQIE</name>
              <bitOffset>3</bitOffset>
              <bitWidth>1</bitWidth>
            </field>
            <field>
              <name>CNRDYIE</name>
              <bitOffset>4</bitOffset>
              <bitWidth>1</bitWidth>
            </field>
            <field>
              <name>AFSDETIE</name>
              <bitOffset>5</bitOffset>
              <bitWidth>1</bitWidth>
            </field>
            <field>
              <name>LFSDETIE</name>
              <bitOffset>6</bitOffset>
              <bitWidth>1</bitWidth>
            </field>
          </fields>
        </register>
        <register>
          <name>IMRB</name>
          <addressOffset>0x34</addressOffset>
          <size>0x20</size>
          <fields>
            <field>
              <name>OVRUDRIE</name>
              <bitOffset>0</bitOffset>
              <bitWidth>1</bitWidth>
            </field>
            <field>
              <name>MUTEDETIE</name>
              <bitOffset>1</bitOffset>
              <bitWidth>1</bitWidth>
            </field>
            <field>
              <name>WCKCFGIE</name>
              <bitOffset>2</bitOffset>
              <bitWidth>1</bitWidth>
            </field>
            <field>
              <name>FREQIE</name>
              <bitOffset>3</bitOffset>
              <bitWidth>1</bitWidth>
            </field>
            <field>
              <name>CNRDYIE</name>
              <bitOffset>4</bitOffset>
              <bitWidth>1</bitWidth>
            </field>
            <field>
              <name>AFSDETIE</name>
              <bitOffset>5</bitOffset>
              <bitWidth>1</bitWidth>
            </field>
            <field>
              <name>LFSDETIE</name>
              <bitOffset>6</bitOffset>
              <bitWidth>1</bitWidth>
            </field>
          </fields>
        </register>
        <register>
          <name>SRB</name>
          <addressOffset>0x38</addressOffset>
          <size>0x20</size>
          <fields>
            <field>
              <name>OVRUDR</name>
              <bitOffset>0</bitOffset>
              <bitWidth>1</bitWidth>
            </field>
            <field>
              <name>MUTEDET</name>
              <bitOffset>1</bitOffset>
              <bitWidth>1</bitWidth>
            </field>
            <field>
              <name>WCKCFG</name>
              <bitOffset>2</bitOffset>
              <bitWidth>1</bitWidth>
            </field>
            <field>
              <name>FREQ</name>
              <bitOffset>3</bitOffset>
              <bitWidth>1</bitWidth>
            </field>
            <field>
              <name>CNRDY</name>
              <bitOffset>4</bitOffset>
              <bitWidth>1</bitWidth>
            </field>
            <field>
              <name>AFSDET</name>
              <bitOffset>5</bitOffset>
              <bitWidth>1</bitWidth>
            </field>
            <field>
              <name>LFSDET</name>
              <bitOffset>6</bitOffset>
              <bitWidth>1</bitWidth>
            </field>
            <field>
              <name>FLVL</name>
              <bitOffset>16</bitOffset>
              <bitWidth>3</bitWidth>
            </field>
          </fields>
        </register>
        <register>
          <name>SRB</name>
          <addressOffset>0x38</addressOffset>
          <size>0x20</size>
          <fields>
            <field>
              <name>OVRUDR</name>
              <bitOffset>0</bitOffset>
              <bitWidth>1</bitWidth>
            </field>
            <field>
              <name>MUTEDET</name>
              <bitOffset>1</bitOffset>
              <bitWidth>1</bitWidth>
            </field>
            <field>
              <name>WCKCFG</name>
              <bitOffset>2</bitOffset>
              <bitWidth>1</bitWidth>
            </field>
            <field>
              <name>FREQ</name>
              <bitOffset>3</bitOffset>
              <bitWidth>1</bitWidth>
            </field>
            <field>
              <name>CNRDY</name>
              <bitOffset>4</bitOffset>
              <bitWidth>1</bitWidth>
            </field>
            <field>
              <name>AFSDET</name>
              <bitOffset>5</bitOffset>
              <bitWidth>1</bitWidth>
            </field>
            <field>
              <name>LFSDET</name>
              <bitOffset>6</bitOffset>
              <bitWidth>1</bitWidth>
            </field>
            <field>
              <name>FLVL</name>
              <bitOffset>16</bitOffset>
              <bitWidth>3</bitWidth>
            </field>
          </fields>
        </register>
        <register>
          <name>SRB</name>
          <addressOffset>0x38</addressOffset>
          <size>0x20</size>
          <fields>
            <field>
              <name>OVRUDR</name>
              <bitOffset>0</bitOffset>
              <bitWidth>1</bitWidth>
            </field>
            <field>
              <name>MUTEDET</name>
              <bitOffset>1</bitOffset>
              <bitWidth>1</bitWidth>
            </field>
            <field>
              <name>WCKCFG</name>
              <bitOffset>2</bitOffset>
              <bitWidth>1</bitWidth>
            </field>
            <field>
              <name>FREQ</name>
              <bitOffset>3</bitOffset>
              <bitWidth>1</bitWidth>
            </field>
            <field>
              <name>CNRDY</name>
              <bitOffset>4</bitOffset>
              <bitWidth>1</bitWidth>
            </field>
            <field>
              <name>AFSDET</name>
              <bitOffset>5</bitOffset>
              <bitWidth>1</bitWidth>
            </field>
            <field>
              <name>LFSDET</name>
              <bitOffset>6</bitOffset>
              <bitWidth>1</bitWidth>
            </field>
            <field>
              <name>FLVL</name>
              <bitOffset>16</bitOffset>
              <bitWidth>3</bitWidth>
            </field>
          </fields>
        </register>
        <register>
          <name>SRB</name>
          <addressOffset>0x38</addressOffset>
          <size>0x20</size>
          <fields>
            <field>
              <name>OVRUDR</name>
              <bitOffset>0</bitOffset>
              <bitWidth>1</bitWidth>
            </field>
            <field>
              <name>MUTEDET</name>
              <bitOffset>1</bitOffset>
              <bitWidth>1</bitWidth>
            </field>
            <field>
              <name>WCKCFG</name>
              <bitOffset>2</bitOffset>
              <bitWidth>1</bitWidth>
            </field>
            <field>
              <name>FREQ</name>
              <bitOffset>3</bitOffset>
              <bitWidth>1</bitWidth>
            </field>
            <field>
              <name>CNRDY</name>
              <bitOffset>4</bitOffset>
              <bitWidth>1</bitWidth>
            </field>
            <field>
              <name>AFSDET</name>
              <bitOffset>5</bitOffset>
              <bitWidth>1</bitWidth>
            </field>
            <field>
              <name>LFSDET</name>
              <bitOffset>6</bitOffset>
              <bitWidth>1</bitWidth>
            </field>
            <field>
              <name>FLVL</name>
              <bitOffset>16</bitOffset>
              <bitWidth>3</bitWidth>
            </field>
          </fields>
        </register>
        <register>
          <name>CLRFRB</name>
          <addressOffset>0x3c</addressOffset>
          <size>0x20</size>
          <fields>
            <field>
              <name>COVRUDR</name>
              <bitOffset>0</bitOffset>
              <bitWidth>1</bitWidth>
            </field>
            <field>
              <name>CMUTEDET</name>
              <bitOffset>1</bitOffset>
              <bitWidth>1</bitWidth>
            </field>
            <field>
              <name>CWCKCFG</name>
              <bitOffset>2</bitOffset>
              <bitWidth>1</bitWidth>
            </field>
            <field>
              <name>CFREQ</name>
              <bitOffset>3</bitOffset>
              <bitWidth>1</bitWidth>
            </field>
            <field>
              <name>CCNRDY</name>
              <bitOffset>4</bitOffset>
              <bitWidth>1</bitWidth>
            </field>
            <field>
              <name>CAFSDET</name>
              <bitOffset>5</bitOffset>
              <bitWidth>1</bitWidth>
            </field>
            <field>
              <name>CLFSDET</name>
              <bitOffset>6</bitOffset>
              <bitWidth>1</bitWidth>
            </field>
          </fields>
        </register>
        <register>
          <name>CLRFRB</name>
          <addressOffset>0x3c</addressOffset>
          <size>0x20</size>
          <fields>
            <field>
              <name>COVRUDR</name>
              <bitOffset>0</bitOffset>
              <bitWidth>1</bitWidth>
            </field>
            <field>
              <name>CMUTEDET</name>
              <bitOffset>1</bitOffset>
              <bitWidth>1</bitWidth>
            </field>
            <field>
              <name>CWCKCFG</name>
              <bitOffset>2</bitOffset>
              <bitWidth>1</bitWidth>
            </field>
            <field>
              <name>CFREQ</name>
              <bitOffset>3</bitOffset>
              <bitWidth>1</bitWidth>
            </field>
            <field>
              <name>CCNRDY</name>
              <bitOffset>4</bitOffset>
              <bitWidth>1</bitWidth>
            </field>
            <field>
              <name>CAFSDET</name>
              <bitOffset>5</bitOffset>
              <bitWidth>1</bitWidth>
            </field>
            <field>
              <name>CLFSDET</name>
              <bitOffset>6</bitOffset>
              <bitWidth>1</bitWidth>
            </field>
          </fields>
        </register>
        <register>
          <name>CLRFRB</name>
          <addressOffset>0x3c</addressOffset>
          <size>0x20</size>
          <fields>
            <field>
              <name>COVRUDR</name>
              <bitOffset>0</bitOffset>
              <bitWidth>1</bitWidth>
            </field>
            <field>
              <name>CMUTEDET</name>
              <bitOffset>1</bitOffset>
              <bitWidth>1</bitWidth>
            </field>
            <field>
              <name>CWCKCFG</name>
              <bitOffset>2</bitOffset>
              <bitWidth>1</bitWidth>
            </field>
            <field>
              <name>CFREQ</name>
              <bitOffset>3</bitOffset>
              <bitWidth>1</bitWidth>
            </field>
            <field>
              <name>CCNRDY</name>
              <bitOffset>4</bitOffset>
              <bitWidth>1</bitWidth>
            </field>
            <field>
              <name>CAFSDET</name>
              <bitOffset>5</bitOffset>
              <bitWidth>1</bitWidth>
            </field>
            <field>
              <name>CLFSDET</name>
              <bitOffset>6</bitOffset>
              <bitWidth>1</bitWidth>
            </field>
          </fields>
        </register>
        <register>
          <name>CLRFRB</name>
          <addressOffset>0x3c</addressOffset>
          <size>0x20</size>
          <fields>
            <field>
              <name>COVRUDR</name>
              <bitOffset>0</bitOffset>
              <bitWidth>1</bitWidth>
            </field>
            <field>
              <name>CMUTEDET</name>
              <bitOffset>1</bitOffset>
              <bitWidth>1</bitWidth>
            </field>
            <field>
              <name>CWCKCFG</name>
              <bitOffset>2</bitOffset>
              <bitWidth>1</bitWidth>
            </field>
            <field>
              <name>CFREQ</name>
              <bitOffset>3</bitOffset>
              <bitWidth>1</bitWidth>
            </field>
            <field>
              <name>CCNRDY</name>
              <bitOffset>4</bitOffset>
              <bitWidth>1</bitWidth>
            </field>
            <field>
              <name>CAFSDET</name>
              <bitOffset>5</bitOffset>
              <bitWidth>1</bitWidth>
            </field>
            <field>
              <name>CLFSDET</name>
              <bitOffset>6</bitOffset>
              <bitWidth>1</bitWidth>
            </field>
          </fields>
        </register>
        <register>
          <name>DRB</name>
          <addressOffset>0x40</addressOffset>
          <size>0x20</size>
          <fields>
            <field>
              <name>DATA</name>
              <bitOffset>0</bitOffset>
              <bitWidth>32</bitWidth>
            </field>
          </fields>
        </register>
        <register>
          <name>DRB</name>
          <addressOffset>0x40</addressOffset>
          <size>0x20</size>
          <fields>
            <field>
              <name>DATA</name>
              <bitOffset>0</bitOffset>
              <bitWidth>32</bitWidth>
            </field>
          </fields>
        </register>
        <register>
          <name>DRB</name>
          <addressOffset>0x40</addressOffset>
          <size>0x20</size>
          <fields>
            <field>
              <name>DATA</name>
              <bitOffset>0</bitOffset>
              <bitWidth>32</bitWidth>
            </field>
          </fields>
        </register>
        <register>
          <name>DRB</name>
          <addressOffset>0x40</addressOffset>
          <size>0x20</size>
          <fields>
            <field>
              <name>DATA</name>
              <bitOffset>0</bitOffset>
              <bitWidth>32</bitWidth>
            </field>
          </fields>
        </register>
        <register>
          <name>PDMCR</name>
          <addressOffset>0x44</addressOffset>
          <size>0x20</size>
          <fields>
            <field>
              <name>PDMEN</name>
              <bitOffset>0</bitOffset>
              <bitWidth>1</bitWidth>
            </field>
            <field>
              <name>MICNBR</name>
              <bitOffset>4</bitOffset>
              <bitWidth>2</bitWidth>
            </field>
            <field>
              <name>CKEN1</name>
              <bitOffset>8</bitOffset>
              <bitWidth>1</bitWidth>
            </field>
            <field>
              <name>CKEN2</name>
              <bitOffset>9</bitOffset>
              <bitWidth>1</bitWidth>
            </field>
            <field>
              <name>CKEN3</name>
              <bitOffset>10</bitOffset>
              <bitWidth>1</bitWidth>
            </field>
            <field>
              <name>CKEN4</name>
              <bitOffset>11</bitOffset>
              <bitWidth>1</bitWidth>
            </field>
          </fields>
        </register>
        <register>
          <name>PDMDLY</name>
          <addressOffset>0x48</addressOffset>
          <size>0x20</size>
          <fields>
            <field>
              <name>DLYM1L</name>
              <bitOffset>0</bitOffset>
              <bitWidth>3</bitWidth>
            </field>
            <field>
              <name>DLYM1R</name>
              <bitOffset>4</bitOffset>
              <bitWidth>3</bitWidth>
            </field>
            <field>
              <name>DLYM2L</name>
              <bitOffset>8</bitOffset>
              <bitWidth>3</bitWidth>
            </field>
            <field>
              <name>DLYM2R</name>
              <bitOffset>12</bitOffset>
              <bitWidth>3</bitWidth>
            </field>
            <field>
              <name>DLYM3L</name>
              <bitOffset>16</bitOffset>
              <bitWidth>3</bitWidth>
            </field>
            <field>
              <name>DLYM3R</name>
              <bitOffset>20</bitOffset>
              <bitWidth>3</bitWidth>
            </field>
            <field>
              <name>DLYM4L</name>
              <bitOffset>24</bitOffset>
              <bitWidth>3</bitWidth>
            </field>
            <field>
              <name>DLYM4R</name>
              <bitOffset>28</bitOffset>
              <bitWidth>3</bitWidth>
            </field>
          </fields>
        </register>
      </registers>
    </peripheral>
    <peripheral>
      <name>GPIOA</name>
      <baseAddress>0x58020000</baseAddress>
      <registers>
        <register>
          <name>MODER</name>
          <addressOffset>0x0</addressOffset>
          <size>0x20</size>
          <fields>
            <field>
              <name>MODE0</name>
              <bitOffset>0</bitOffset>
              <bitWidth>2</bitWidth>
            </field>
            <field>
              <name>MODE1</name>
              <bitOffset>2</bitOffset>
              <bitWidth>2</bitWidth>
            </field>
            <field>
              <name>MODE2</name>
              <bitOffset>4</bitOffset>
              <bitWidth>2</bitWidth>
            </field>
            <field>
              <name>MODE3</name>
              <bitOffset>6</bitOffset>
              <bitWidth>2</bitWidth>
            </field>
            <field>
              <name>MODE4</name>
              <bitOffset>8</bitOffset>
              <bitWidth>2</bitWidth>
            </field>
            <field>
              <name>MODE5</name>
              <bitOffset>10</bitOffset>
              <bitWidth>2</bitWidth>
            </field>
            <field>
              <name>MODE6</name>
              <bitOffset>12</bitOffset>
              <bitWidth>2</bitWidth>
            </field>
            <field>
              <name>MODE7</name>
              <bitOffset>14</bitOffset>
              <bitWidth>2</bitWidth>
            </field>
            <field>
              <name>MODE8</name>
              <bitOffset>16</bitOffset>
              <bitWidth>2</bitWidth>
            </field>
            <field>
              <name>MODE9</name>
              <bitOffset>18</bitOffset>
              <bitWidth>2</bitWidth>
            </field>
            <field>
              <name>MODE10</name>
              <bitOffset>20</bitOffset>
              <bitWidth>2</bitWidth>
            </field>
            <field>
              <name>MODE11</name>
              <bitOffset>22</bitOffset>
              <bitWidth>2</bitWidth>
            </field>
            <field>
              <name>MODE12</name>
              <bitOffset>24</bitOffset>
              <bitWidth>2</bitWidth>
            </field>
            <field>
              <name>MODE13</name>
              <bitOffset>26</bitOffset>
              <bitWidth>2</bitWidth>
            </field>
            <field>
              <name>MODE14</name>
              <bitOffset>28</bitOffset>
              <bitWidth>2</bitWidth>
            </field>
            <field>
              <name>MODE15</name>
              <bitOffset>30</bitOffset>
              <bitWidth>2</bitWidth>
            </field>
          </fields>
        </register>
        <register>
          <name>OTYPER</name>
          <addressOffset>0x4</addressOffset>
          <size>0x20</size>
          <fields>
            <field>
              <name>OT0</name>
              <bitOffset>0</bitOffset>
              <bitWidth>1</bitWidth>
            </field>
            <field>
              <name>OT1</name>
              <bitOffset>1</bitOffset>
              <bitWidth>1</bitWidth>
            </field>
            <field>
              <name>OT2</name>
              <bitOffset>2</bitOffset>
              <bitWidth>1</bitWidth>
            </field>
            <field>
              <name>OT3</name>
              <bitOffset>3</bitOffset>
              <bitWidth>1</bitWidth>
            </field>
            <field>
              <name>OT4</name>
              <bitOffset>4</bitOffset>
              <bitWidth>1</bitWidth>
            </field>
            <field>
              <name>OT5</name>
              <bitOffset>5</bitOffset>
              <bitWidth>1</bitWidth>
            </field>
            <field>
              <name>OT6</name>
              <bitOffset>6</bitOffset>
              <bitWidth>1</bitWidth>
            </field>
            <field>
              <name>OT7</name>
              <bitOffset>7</bitOffset>
              <bitWidth>1</bitWidth>
            </field>
            <field>
              <name>OT8</name>
              <bitOffset>8</bitOffset>
              <bitWidth>1</bitWidth>
            </field>
            <field>
              <name>OT9</name>
              <bitOffset>9</bitOffset>
              <bitWidth>1</bitWidth>
            </field>
            <field>
              <name>OT10</name>
              <bitOffset>10</bitOffset>
              <bitWidth>1</bitWidth>
            </field>
            <field>
              <name>OT11</name>
              <bitOffset>11</bitOffset>
              <bitWidth>1</bitWidth>
            </field>
            <field>
              <name>OT12</name>
              <bitOffset>12</bitOffset>
              <bitWidth>1</bitWidth>
            </field>
            <field>
              <name>OT13</name>
              <bitOffset>13</bitOffset>
              <bitWidth>1</bitWidth>
            </field>
            <field>
              <name>OT14</name>
              <bitOffset>14</bitOffset>
              <bitWidth>1</bitWidth>
            </field>
            <field>
              <name>OT15</name>
              <bitOffset>15</bitOffset>
              <bitWidth>1</bitWidth>
            </field>
          </fields>
        </register>
        <register>
          <name>OSPEEDR</name>
          <addressOffset>0x8</addressOffset>
          <size>0x20</size>
          <fields>
            <field>
              <name>OSPEED0</name>
              <bitOffset>0</bitOffset>
              <bitWidth>2</bitWidth>
            </field>
            <field>
              <name>OSPEED1</name>
              <bitOffset>2</bitOffset>
              <bitWidth>2</bitWidth>
            </field>
            <field>
              <name>OSPEED2</name>
              <bitOffset>4</bitOffset>
              <bitWidth>2</bitWidth>
            </field>
            <field>
              <name>OSPEED3</name>
              <bitOffset>6</bitOffset>
              <bitWidth>2</bitWidth>
            </field>
            <field>
              <name>OSPEED4</name>
              <bitOffset>8</bitOffset>
              <bitWidth>2</bitWidth>
            </field>
            <field>
              <name>OSPEED5</name>
              <bitOffset>10</bitOffset>
              <bitWidth>2</bitWidth>
            </field>
            <field>
              <name>OSPEED6</name>
              <bitOffset>12</bitOffset>
              <bitWidth>2</bitWidth>
            </field>
            <field>
              <name>OSPEED7</name>
              <bitOffset>14</bitOffset>
              <bitWidth>2</bitWidth>
            </field>
            <field>
              <name>OSPEED8</name>
              <bitOffset>16</bitOffset>
              <bitWidth>2</bitWidth>
            </field>
            <field>
              <name>OSPEED9</name>
              <bitOffset>18</bitOffset>
              <bitWidth>2</bitWidth>
            </field>
            <field>
              <name>OSPEED10</name>
              <bitOffset>20</bitOffset>
              <bitWidth>2</bitWidth>
            </field>
            <field>
              <name>OSPEED11</name>
              <bitOffset>22</bitOffset>
              <bitWidth>2</bitWidth>
            </field>
            <field>
              <name>OSPEED12</name>
              <bitOffset>24</bitOffset>
              <bitWidth>2</bitWidth>
            </field>
            <field>
              <name>OSPEED13</name>
              <bitOffset>26</bitOffset>
              <bitWidth>2</bitWidth>
            </field>
            <field>
              <name>OSPEED14</name>
              <bitOffset>28</bitOffset>
              <bitWidth>2</bitWidth>
            </field>
            <field>
              <name>OSPEED15</name>
              <bitOffset>30</bitOffset>
              <bitWidth>2</bitWidth>
            </field>
          </fields>
        </register>
        <register>
          <name>PUPDR</name>
          <addressOffset>0xc</addressOffset>
          <size>0x20</size>
          <fields>
            <field>
              <name>PUPD0</name>
              <bitOffset>0</bitOffset>
              <bitWidth>2</bitWidth>
            </field>
            <field>
              <name>PUPD1</name>
              <bitOffset>2</bitOffset>
              <bitWidth>2</bitWidth>
            </field>
            <field>
              <name>PUPD2</name>
              <bitOffset>4</bitOffset>
              <bitWidth>2</bitWidth>
            </field>
            <field>
              <name>PUPD3</name>
              <bitOffset>6</bitOffset>
              <bitWidth>2</bitWidth>
            </field>
            <field>
              <name>PUPD4</name>
              <bitOffset>8</bitOffset>
              <bitWidth>2</bitWidth>
            </field>
            <field>
              <name>PUPD5</name>
              <bitOffset>10</bitOffset>
              <bitWidth>2</bitWidth>
            </field>
            <field>
              <name>PUPD6</name>
              <bitOffset>12</bitOffset>
              <bitWidth>2</bitWidth>
            </field>
            <field>
              <name>PUPD7</name>
              <bitOffset>14</bitOffset>
              <bitWidth>2</bitWidth>
            </field>
            <field>
              <name>PUPD8</name>
              <bitOffset>16</bitOffset>
              <bitWidth>2</bitWidth>
            </field>
            <field>
              <name>PUPD9</name>
              <bitOffset>18</bitOffset>
              <bitWidth>2</bitWidth>
            </field>
            <field>
              <name>PUPD10</name>
              <bitOffset>20</bitOffset>
              <bitWidth>2</bitWidth>
            </field>
            <field>
              <name>PUPD11</name>
              <bitOffset>22</bitOffset>
              <bitWidth>2</bitWidth>
            </field>
            <field>
              <name>PUPD12</name>
              <bitOffset>24</bitOffset>
              <bitWidth>2</bitWidth>
            </field>
            <field>
              <name>PUPD13</name>
              <bitOffset>26</bitOffset>
              <bitWidth>2</bitWidth>
            </field>
            <field>
              <name>PUPD14</name>
              <bitOffset>28</bitOffset>
              <bitWidth>2</bitWidth>
            </field>
            <field>
              <name>PUPD15</name>
              <bitOffset>30</bitOffset>
              <bitWidth>2</bitWidth>
            </field>
          </fields>
        </register>
        <register>
          <name>IDR</name>
          <addressOffset>0x10</addressOffset>
          <size>0x20</size>
          <fields>
            <field>
              <name>ID0</name>
              <bitOffset>0</bitOffset>
              <bitWidth>1</bitWidth>
            </field>
            <field>
              <name>ID1</name>
              <bitOffset>1</bitOffset>
              <bitWidth>1</bitWidth>
            </field>
            <field>
              <name>ID2</name>
              <bitOffset>2</bitOffset>
              <bitWidth>1</bitWidth>
            </field>
            <field>
              <name>ID3</name>
              <bitOffset>3</bitOffset>
              <bitWidth>1</bitWidth>
            </field>
            <field>
              <name>ID4</name>
              <bitOffset>4</bitOffset>
              <bitWidth>1</bitWidth>
            </field>
            <field>
              <name>ID5</name>
              <bitOffset>5</bitOffset>
              <bitWidth>1</bitWidth>
            </field>
            <field>
              <name>ID6</name>
              <bitOffset>6</bitOffset>
              <bitWidth>1</bitWidth>
            </field>
            <field>
              <name>ID7</name>
              <bitOffset>7</bitOffset>
              <bitWidth>1</bitWidth>
            </field>
            <field>
              <name>ID8</name>
              <bitOffset>8</bitOffset>
              <bitWidth>1</bitWidth>
            </field>
            <field>
              <name>ID9</name>
              <bitOffset>9</bitOffset>
              <bitWidth>1</bitWidth>
            </field>
            <field>
              <name>ID10</name>
              <bitOffset>10</bitOffset>
              <bitWidth>1</bitWidth>
            </field>
            <field>
              <name>ID11</name>
              <bitOffset>11</bitOffset>
              <bitWidth>1</bitWidth>
            </field>
            <field>
              <name>ID12</name>
              <bitOffset>12</bitOffset>
              <bitWidth>1</bitWidth>
            </field>
            <field>
              <name>ID13</name>
              <bitOffset>13</bitOffset>
              <bitWidth>1</bitWidth>
            </field>
            <field>
              <name>ID14</name>
              <bitOffset>14</bitOffset>
              <bitWidth>1</bitWidth>
            </field>
            <field>
              <name>ID15</name>
              <bitOffset>15</bitOffset>
              <bitWidth>1</bitWidth>
            </field>
          </fields>
        </register>
        <register>
          <name>ODR</name>
          <addressOffset>0x14</addressOffset>
          <size>0x20</size>
          <fields>
            <field>
              <name>OD0</name>
              <bitOffset>0</bitOffset>
              <bitWidth>1</bitWidth>
            </field>
            <field>
              <name>OD1</name>
              <bitOffset>1</bitOffset>
              <bitWidth>1</bitWidth>
            </field>
            <field>
              <name>OD2</name>
              <bitOffset>2</bitOffset>
              <bitWidth>1</bitWidth>
            </field>
            <field>
              <name>OD3</name>
              <bitOffset>3</bitOffset>
              <bitWidth>1</bitWidth>
            </field>
            <field>
              <name>OD4</name>
              <bitOffset>4</bitOffset>
              <bitWidth>1</bitWidth>
            </field>
            <field>
              <name>OD5</name>
              <bitOffset>5</bitOffset>
              <bitWidth>1</bitWidth>
            </field>
            <field>
              <name>OD6</name>
              <bitOffset>6</bitOffset>
              <bitWidth>1</bitWidth>
            </field>
            <field>
              <name>OD7</name>
              <bitOffset>7</bitOffset>
              <bitWidth>1</bitWidth>
            </field>
            <field>
              <name>OD8</name>
              <bitOffset>8</bitOffset>
              <bitWidth>1</bitWidth>
            </field>
            <field>
              <name>OD9</name>
              <bitOffset>9</bitOffset>
              <bitWidth>1</bitWidth>
            </field>
            <field>
              <name>OD10</name>
              <bitOffset>10</bitOffset>
              <bitWidth>1</bitWidth>
            </field>
            <field>
              <name>OD11</name>
              <bitOffset>11</bitOffset>
              <bitWidth>1</bitWidth>
            </field>
            <field>
              <name>OD12</name>
              <bitOffset>12</bitOffset>
              <bitWidth>1</bitWidth>
            </field>
            <field>
              <name>OD13</name>
              <bitOffset>13</bitOffset>
              <bitWidth>1</bitWidth>
            </field>
            <field>
              <name>OD14</name>
              <bitOffset>14</bitOffset>
              <bitWidth>1</bitWidth>
            </field>
            <field>
              <name>OD15</name>
              <bitOffset>15</bitOffset>
              <bitWidth>1</bitWidth>
            </field>
          </fields>
        </register>
        <register>
          <name>BSRR</name>
          <addressOffset>0x18</addressOffset>
          <size>0x20</size>
          <fields>
            <field>
              <name>BS0</name>
              <bitOffset>0</bitOffset>
              <bitWidth>1</bitWidth>
            </field>
            <field>
              <name>BS1</name>
              <bitOffset>1</bitOffset>
              <bitWidth>1</bitWidth>
            </field>
            <field>
              <name>BS2</name>
              <bitOffset>2</bitOffset>
              <bitWidth>1</bitWidth>
            </field>
            <field>
              <name>BS3</name>
              <bitOffset>3</bitOffset>
              <bitWidth>1</bitWidth>
            </field>
            <field>
              <name>BS4</name>
              <bitOffset>4</bitOffset>
              <bitWidth>1</bitWidth>
            </field>
            <field>
              <name>BS5</name>
              <bitOffset>5</bitOffset>
              <bitWidth>1</bitWidth>
            </field>
            <field>
              <name>BS6</name>
              <bitOffset>6</bitOffset>
              <bitWidth>1</bitWidth>
            </field>
            <field>
              <name>BS7</name>
              <bitOffset>7</bitOffset>
              <bitWidth>1</bitWidth>
            </field>
            <field>
              <name>BS8</name>
              <bitOffset>8</bitOffset>
              <bitWidth>1</bitWidth>
            </field>
            <field>
              <name>BS9</name>
              <bitOffset>9</bitOffset>
              <bitWidth>1</bitWidth>
            </field>
            <field>
              <name>BS10</name>
              <bitOffset>10</bitOffset>
              <bitWidth>1</bitWidth>
            </field>
            <field>
              <name>BS11</name>
              <bitOffset>11</bitOffset>
              <bitWidth>1</bitWidth>
            </field>
            <field>
              <name>BS12</name>
              <bitOffset>12</bitOffset>
              <bitWidth>1</bitWidth>
            </field>
            <field>
              <name>BS13</name>
              <bitOffset>13</bitOffset>
              <bitWidth>1</bitWidth>
            </field>
            <field>
              <name>BS14</name>
              <bitOffset>14</bitOffset>
              <bitWidth>1</bitWidth>
            </field>
            <field>
              <name>BS15</name>
              <bitOffset>15</bitOffset>
              <bitWidth>1</bitWidth>
            </field>
            <field>
              <name>BR0</name>
              <bitOffset>16</bitOffset>
              <bitWidth>1</bitWidth>
            </field>
            <field>
              <name>BR1</name>
              <bitOffset>17</bitOffset>
              <bitWidth>1</bitWidth>
            </field>
            <field>
              <name>BR2</name>
              <bitOffset>18</bitOffset>
              <bitWidth>1</bitWidth>
            </field>
            <field>
              <name>BR3</name>
              <bitOffset>19</bitOffset>
              <bitWidth>1</bitWidth>
            </field>
            <field>
              <name>BR4</name>
              <bitOffset>20</bitOffset>
              <bitWidth>1</bitWidth>
            </field>
            <field>
              <name>BR5</name>
              <bitOffset>21</bitOffset>
              <bitWidth>1</bitWidth>
            </field>
            <field>
              <name>BR6</name>
              <bitOffset>22</bitOffset>
              <bitWidth>1</bitWidth>
            </field>
            <field>
              <name>BR7</name>
              <bitOffset>23</bitOffset>
              <bitWidth>1</bitWidth>
            </field>
            <field>
              <name>BR8</name>
              <bitOffset>24</bitOffset>
              <bitWidth>1</bitWidth>
            </field>
            <field>
              <name>BR9</name>
              <bitOffset>25</bitOffset>
              <bitWidth>1</bitWidth>
            </field>
            <field>
              <name>BR10</name>
              <bitOffset>26</bitOffset>
              <bitWidth>1</bitWidth>
            </field>
            <field>
              <name>BR11</name>
              <bitOffset>27</bitOffset>
              <bitWidth>1</bitWidth>
            </field>
            <field>
              <name>BR12</name>
              <bitOffset>28</bitOffset>
              <bitWidth>1</bitWidth>
            </field>
            <field>
              <name>BR13</name>
              <bitOffset>29</bitOffset>
              <bitWidth>1</bitWidth>
            </field>
            <field>
              <name>BR14</name>
              <bitOffset>30</bitOffset>
              <bitWidth>1</bitWidth>
            </field>
            <field>
              <name>BR15</name>
              <bitOffset>31</bitOffset>
              <bitWidth>1</bitWidth>
            </field>
          </fields>
        </register>
        <register>
          <name>LCKR</name>
          <addressOffset>0x1c</addressOffset>
          <size>0x20</size>
          <fields>
            <field>
              <name>LCK0</name>
              <bitOffset>0</bitOffset>
              <bitWidth>1</bitWidth>
            </field>
            <field>
              <name>LCK1</name>
              <bitOffset>1</bitOffset>
              <bitWidth>1</bitWidth>
            </field>
            <field>
              <name>LCK2</name>
              <bitOffset>2</bitOffset>
              <bitWidth>1</bitWidth>
            </field>
            <field>
              <name>LCK3</name>
              <bitOffset>3</bitOffset>
              <bitWidth>1</bitWidth>
            </field>
            <field>
              <name>LCK4</name>
              <bitOffset>4</bitOffset>
              <bitWidth>1</bitWidth>
            </field>
            <field>
              <name>LCK5</name>
              <bitOffset>5</bitOffset>
              <bitWidth>1</bitWidth>
            </field>
            <field>
              <name>LCK6</name>
              <bitOffset>6</bitOffset>
              <bitWidth>1</bitWidth>
            </field>
            <field>
              <name>LCK7</name>
              <bitOffset>7</bitOffset>
              <bitWidth>1</bitWidth>
            </field>
            <field>
              <name>LCK8</name>
              <bitOffset>8</bitOffset>
              <bitWidth>1</bitWidth>
            </field>
            <field>
              <name>LCK9</name>
              <bitOffset>9</bitOffset>
              <bitWidth>1</bitWidth>
            </field>
            <field>
              <name>LCK10</name>
              <bitOffset>10</bitOffset>
              <bitWidth>1</bitWidth>
            </field>
            <field>
              <name>LCK11</name>
              <bitOffset>11</bitOffset>
              <bitWidth>1</bitWidth>
            </field>
            <field>
              <name>LCK12</name>
              <bitOffset>12</bitOffset>
              <bitWidth>1</bitWidth>
            </field>
            <field>
              <name>LCK13</name>
              <bitOffset>13</bitOffset>
              <bitWidth>1</bitWidth>
            </field>
            <field>
              <name>LCK14</name>
              <bitOffset>14</bitOffset>
              <bitWidth>1</bitWidth>
            </field>
            <field>
              <name>LCK15</name>
              <bitOffset>15</bitOffset>
              <bitWidth>1</bitWidth>
            </field>
            <field>
              <name>LCKK</name>
              <bitOffset>16</bitOffset>
              <bitWidth>1</bitWidth>
            </field>
          </fields>
        </register>
        <register>
          <name>AFR.0</name>
          <addressOffset>0x20</addressOffset>
          <size>0x20</size>
          <fields>
            <field>
              <name>AFSEL0</name>
              <bitOffset>0</bitOffset>
              <bitWidth>4</bitWidth>
            </field>
            <field>
              <name>AFSEL1</name>
              <bitOffset>4</bitOffset>
              <bitWidth>4</bitWidth>
            </field>
            <field>
              <name>AFSEL2</name>
              <bitOffset>8</bitOffset>
              <bitWidth>4</bitWidth>
            </field>
            <field>
              <name>AFSEL3</name>
              <bitOffset>12</bitOffset>
              <bitWidth>4</bitWidth>
            </field>
            <field>
              <name>AFSEL4</name>
              <bitOffset>16</bitOffset>
              <bitWidth>4</bitWidth>
            </field>
            <field>
              <name>AFSEL5</name>
              <bitOffset>20</bitOffset>
              <bitWidth>4</bitWidth>
            </field>
            <field>
              <name>AFSEL6</name>
              <bitOffset>24</bitOffset>
              <bitWidth>4</bitWidth>
            </field>
            <field>
              <name>AFSEL7</name>
              <bitOffset>28</bitOffset>
              <bitWidth>4</bitWidth>
            </field>
          </fields>
        </register>
        <register>
          <name>AFR.1</name>
          <addressOffset>0x24</addressOffset>
          <size>0x20</size>
          <fields>
            <field>
              <name>AFSEL8</name>
              <bitOffset>0</bitOffset>
              <bitWidth>4</bitWidth>
            </field>
            <field>
              <name>AFSEL9</name>
              <bitOffset>4</bitOffset>
              <bitWidth>4</bitWidth>
            </field>
            <field>
              <name>AFSEL10</name>
              <bitOffset>8</bitOffset>
              <bitWidth>4</bitWidth>
            </field>
            <field>
              <name>AFSEL11</name>
              <bitOffset>12</bitOffset>
              <bitWidth>4</bitWidth>
            </field>
            <field>
              <name>AFSEL12</name>
              <bitOffset>16</bitOffset>
              <bitWidth>4</bitWidth>
            </field>
            <field>
              <name>AFSEL13</name>
              <bitOffset>20</bitOffset>
              <bitWidth>4</bitWidth>
            </field>
            <field>
              <name>AFSEL14</name>
              <bitOffset>24</bitOffset>
              <bitWidth>4</bitWidth>
            </field>
            <field>
              <name>AFSEL15</name>
              <bitOffset>28</bitOffset>
              <bitWidth>4</bitWidth>
            </field>
          </fields>
        </register>
      </registers>
    </peripheral>
    <peripheral>
      <name>GPIOB</name>
      <baseAddress>0x58020400</baseAddress>
      <registers>
        <register>
          <name>MODER</name>
          <addressOffset>0x0</addressOffset>
          <size>0x20</size>
          <fields>
            <field>
              <name>MODE0</name>
              <bitOffset>0</bitOffset>
              <bitWidth>2</bitWidth>
            </field>
            <field>
              <name>MODE1</name>
              <bitOffset>2</bitOffset>
              <bitWidth>2</bitWidth>
            </field>
            <field>
              <name>MODE2</name>
              <bitOffset>4</bitOffset>
              <bitWidth>2</bitWidth>
            </field>
            <field>
              <name>MODE3</name>
              <bitOffset>6</bitOffset>
              <bitWidth>2</bitWidth>
            </field>
            <field>
              <name>MODE4</name>
              <bitOffset>8</bitOffset>
              <bitWidth>2</bitWidth>
            </field>
            <field>
              <name>MODE5</name>
              <bitOffset>10</bitOffset>
              <bitWidth>2</bitWidth>
            </field>
            <field>
              <name>MODE6</name>
              <bitOffset>12</bitOffset>
              <bitWidth>2</bitWidth>
            </field>
            <field>
              <name>MODE7</name>
              <bitOffset>14</bitOffset>
              <bitWidth>2</bitWidth>
            </field>
            <field>
              <name>MODE8</name>
              <bitOffset>16</bitOffset>
              <bitWidth>2</bitWidth>
            </field>
            <field>
              <name>MODE9</name>
              <bitOffset>18</bitOffset>
              <bitWidth>2</bitWidth>
            </field>
            <field>
              <name>MODE10</name>
              <bitOffset>20</bitOffset>
              <bitWidth>2</bitWidth>
            </field>
            <field>
              <name>MODE11</name>
              <bitOffset>22</bitOffset>
              <bitWidth>2</bitWidth>
            </field>
            <field>
              <name>MODE12</name>
              <bitOffset>24</bitOffset>
              <bitWidth>2</bitWidth>
            </field>
            <field>
              <name>MODE13</name>
              <bitOffset>26</bitOffset>
              <bitWidth>2</bitWidth>
            </field>
            <field>
              <name>MODE14</name>
              <bitOffset>28</bitOffset>
              <bitWidth>2</bitWidth>
            </field>
            <field>
              <name>MODE15</name>
              <bitOffset>30</bitOffset>
              <bitWidth>2</bitWidth>
            </field>
          </fields>
        </register>
        <register>
          <name>OTYPER</name>
          <addressOffset>0x4</addressOffset>
          <size>0x20</size>
          <fields>
            <field>
              <name>OT0</name>
              <bitOffset>0</bitOffset>
              <bitWidth>1</bitWidth>
            </field>
            <field>
              <name>OT1</name>
              <bitOffset>1</bitOffset>
              <bitWidth>1</bitWidth>
            </field>
            <field>
              <name>OT2</name>
              <bitOffset>2</bitOffset>
              <bitWidth>1</bitWidth>
            </field>
            <field>
              <name>OT3</name>
              <bitOffset>3</bitOffset>
              <bitWidth>1</bitWidth>
            </field>
            <field>
              <name>OT4</name>
              <bitOffset>4</bitOffset>
              <bitWidth>1</bitWidth>
            </field>
            <field>
              <name>OT5</name>
              <bitOffset>5</bitOffset>
              <bitWidth>1</bitWidth>
            </field>
            <field>
              <name>OT6</name>
              <bitOffset>6</bitOffset>
              <bitWidth>1</bitWidth>
            </field>
            <field>
              <name>OT7</name>
              <bitOffset>7</bitOffset>
              <bitWidth>1</bitWidth>
            </field>
            <field>
              <name>OT8</name>
              <bitOffset>8</bitOffset>
              <bitWidth>1</bitWidth>
            </field>
            <field>
              <name>OT9</name>
              <bitOffset>9</bitOffset>
              <bitWidth>1</bitWidth>
            </field>
            <field>
              <name>OT10</name>
              <bitOffset>10</bitOffset>
              <bitWidth>1</bitWidth>
            </field>
            <field>
              <name>OT11</name>
              <bitOffset>11</bitOffset>
              <bitWidth>1</bitWidth>
            </field>
            <field>
              <name>OT12</name>
              <bitOffset>12</bitOffset>
              <bitWidth>1</bitWidth>
            </field>
            <field>
              <name>OT13</name>
              <bitOffset>13</bitOffset>
              <bitWidth>1</bitWidth>
            </field>
            <field>
              <name>OT14</name>
              <bitOffset>14</bitOffset>
              <bitWidth>1</bitWidth>
            </field>
            <field>
              <name>OT15</name>
              <bitOffset>15</bitOffset>
              <bitWidth>1</bitWidth>
            </field>
          </fields>
        </register>
        <register>
          <name>OSPEEDR</name>
          <addressOffset>0x8</addressOffset>
          <size>0x20</size>
          <fields>
            <field>
              <name>OSPEED0</name>
              <bitOffset>0</bitOffset>
              <bitWidth>2</bitWidth>
            </field>
            <field>
              <name>OSPEED1</name>
              <bitOffset>2</bitOffset>
              <bitWidth>2</bitWidth>
            </field>
            <field>
              <name>OSPEED2</name>
              <bitOffset>4</bitOffset>
              <bitWidth>2</bitWidth>
            </field>
            <field>
              <name>OSPEED3</name>
              <bitOffset>6</bitOffset>
              <bitWidth>2</bitWidth>
            </field>
            <field>
              <name>OSPEED4</name>
              <bitOffset>8</bitOffset>
              <bitWidth>2</bitWidth>
            </field>
            <field>
              <name>OSPEED5</name>
              <bitOffset>10</bitOffset>
              <bitWidth>2</bitWidth>
            </field>
            <field>
              <name>OSPEED6</name>
              <bitOffset>12</bitOffset>
              <bitWidth>2</bitWidth>
            </field>
            <field>
              <name>OSPEED7</name>
              <bitOffset>14</bitOffset>
              <bitWidth>2</bitWidth>
            </field>
            <field>
              <name>OSPEED8</name>
              <bitOffset>16</bitOffset>
              <bitWidth>2</bitWidth>
            </field>
            <field>
              <name>OSPEED9</name>
              <bitOffset>18</bitOffset>
              <bitWidth>2</bitWidth>
            </field>
            <field>
              <name>OSPEED10</name>
              <bitOffset>20</bitOffset>
              <bitWidth>2</bitWidth>
            </field>
            <field>
              <name>OSPEED11</name>
              <bitOffset>22</bitOffset>
              <bitWidth>2</bitWidth>
            </field>
            <field>
              <name>OSPEED12</name>
              <bitOffset>24</bitOffset>
              <bitWidth>2</bitWidth>
            </field>
            <field>
              <name>OSPEED13</name>
              <bitOffset>26</bitOffset>
              <bitWidth>2</bitWidth>
            </field>
            <field>
              <name>OSPEED14</name>
              <bitOffset>28</bitOffset>
              <bitWidth>2</bitWidth>
            </field>
            <field>
              <name>OSPEED15</name>
              <bitOffset>30</bitOffset>
              <bitWidth>2</bitWidth>
            </field>
          </fields>
        </register>
        <register>
          <name>PUPDR</name>
          <addressOffset>0xc</addressOffset>
          <size>0x20</size>
          <fields>
            <field>
              <name>PUPD0</name>
              <bitOffset>0</bitOffset>
              <bitWidth>2</bitWidth>
            </field>
            <field>
              <name>PUPD1</name>
              <bitOffset>2</bitOffset>
              <bitWidth>2</bitWidth>
            </field>
            <field>
              <name>PUPD2</name>
              <bitOffset>4</bitOffset>
              <bitWidth>2</bitWidth>
            </field>
            <field>
              <name>PUPD3</name>
              <bitOffset>6</bitOffset>
              <bitWidth>2</bitWidth>
            </field>
            <field>
              <name>PUPD4</name>
              <bitOffset>8</bitOffset>
              <bitWidth>2</bitWidth>
            </field>
            <field>
              <name>PUPD5</name>
              <bitOffset>10</bitOffset>
              <bitWidth>2</bitWidth>
            </field>
            <field>
              <name>PUPD6</name>
              <bitOffset>12</bitOffset>
              <bitWidth>2</bitWidth>
            </field>
            <field>
              <name>PUPD7</name>
              <bitOffset>14</bitOffset>
              <bitWidth>2</bitWidth>
            </field>
            <field>
              <name>PUPD8</name>
              <bitOffset>16</bitOffset>
              <bitWidth>2</bitWidth>
            </field>
            <field>
              <name>PUPD9</name>
              <bitOffset>18</bitOffset>
              <bitWidth>2</bitWidth>
            </field>
            <field>
              <name>PUPD10</name>
              <bitOffset>20</bitOffset>
              <bitWidth>2</bitWidth>
            </field>
            <field>
              <name>PUPD11</name>
              <bitOffset>22</bitOffset>
              <bitWidth>2</bitWidth>
            </field>
            <field>
              <name>PUPD12</name>
              <bitOffset>24</bitOffset>
              <bitWidth>2</bitWidth>
            </field>
            <field>
              <name>PUPD13</name>
              <bitOffset>26</bitOffset>
              <bitWidth>2</bitWidth>
            </field>
            <field>
              <name>PUPD14</name>
              <bitOffset>28</bitOffset>
              <bitWidth>2</bitWidth>
            </field>
            <field>
              <name>PUPD15</name>
              <bitOffset>30</bitOffset>
              <bitWidth>2</bitWidth>
            </field>
          </fields>
        </register>
        <register>
          <name>IDR</name>
          <addressOffset>0x10</addressOffset>
          <size>0x20</size>
          <fields>
            <field>
              <name>ID0</name>
              <bitOffset>0</bitOffset>
              <bitWidth>1</bitWidth>
            </field>
            <field>
              <name>ID1</name>
              <bitOffset>1</bitOffset>
              <bitWidth>1</bitWidth>
            </field>
            <field>
              <name>ID2</name>
              <bitOffset>2</bitOffset>
              <bitWidth>1</bitWidth>
            </field>
            <field>
              <name>ID3</name>
              <bitOffset>3</bitOffset>
              <bitWidth>1</bitWidth>
            </field>
            <field>
              <name>ID4</name>
              <bitOffset>4</bitOffset>
              <bitWidth>1</bitWidth>
            </field>
            <field>
              <name>ID5</name>
              <bitOffset>5</bitOffset>
              <bitWidth>1</bitWidth>
            </field>
            <field>
              <name>ID6</name>
              <bitOffset>6</bitOffset>
              <bitWidth>1</bitWidth>
            </field>
            <field>
              <name>ID7</name>
              <bitOffset>7</bitOffset>
              <bitWidth>1</bitWidth>
            </field>
            <field>
              <name>ID8</name>
              <bitOffset>8</bitOffset>
              <bitWidth>1</bitWidth>
            </field>
            <field>
              <name>ID9</name>
              <bitOffset>9</bitOffset>
              <bitWidth>1</bitWidth>
            </field>
            <field>
              <name>ID10</name>
              <bitOffset>10</bitOffset>
              <bitWidth>1</bitWidth>
            </field>
            <field>
              <name>ID11</name>
              <bitOffset>11</bitOffset>
              <bitWidth>1</bitWidth>
            </field>
            <field>
              <name>ID12</name>
              <bitOffset>12</bitOffset>
              <bitWidth>1</bitWidth>
            </field>
            <field>
              <name>ID13</name>
              <bitOffset>13</bitOffset>
              <bitWidth>1</bitWidth>
            </field>
            <field>
              <name>ID14</name>
              <bitOffset>14</bitOffset>
              <bitWidth>1</bitWidth>
            </field>
            <field>
              <name>ID15</name>
              <bitOffset>15</bitOffset>
              <bitWidth>1</bitWidth>
            </field>
          </fields>
        </register>
        <register>
          <name>ODR</name>
          <addressOffset>0x14</addressOffset>
          <size>0x20</size>
          <fields>
            <field>
              <name>OD0</name>
              <bitOffset>0</bitOffset>
              <bitWidth>1</bitWidth>
            </field>
            <field>
              <name>OD1</name>
              <bitOffset>1</bitOffset>
              <bitWidth>1</bitWidth>
            </field>
            <field>
              <name>OD2</name>
              <bitOffset>2</bitOffset>
              <bitWidth>1</bitWidth>
            </field>
            <field>
              <name>OD3</name>
              <bitOffset>3</bitOffset>
              <bitWidth>1</bitWidth>
            </field>
            <field>
              <name>OD4</name>
              <bitOffset>4</bitOffset>
              <bitWidth>1</bitWidth>
            </field>
            <field>
              <name>OD5</name>
              <bitOffset>5</bitOffset>
              <bitWidth>1</bitWidth>
            </field>
            <field>
              <name>OD6</name>
              <bitOffset>6</bitOffset>
              <bitWidth>1</bitWidth>
            </field>
            <field>
              <name>OD7</name>
              <bitOffset>7</bitOffset>
              <bitWidth>1</bitWidth>
            </field>
            <field>
              <name>OD8</name>
              <bitOffset>8</bitOffset>
              <bitWidth>1</bitWidth>
            </field>
            <field>
              <name>OD9</name>
              <bitOffset>9</bitOffset>
              <bitWidth>1</bitWidth>
            </field>
            <field>
              <name>OD10</name>
              <bitOffset>10</bitOffset>
              <bitWidth>1</bitWidth>
            </field>
            <field>
              <name>OD11</name>
              <bitOffset>11</bitOffset>
              <bitWidth>1</bitWidth>
            </field>
            <field>
              <name>OD12</name>
              <bitOffset>12</bitOffset>
              <bitWidth>1</bitWidth>
            </field>
            <field>
              <name>OD13</name>
              <bitOffset>13</bitOffset>
              <bitWidth>1</bitWidth>
            </field>
            <field>
              <name>OD14</name>
              <bitOffset>14</bitOffset>
              <bitWidth>1</bitWidth>
            </field>
            <field>
              <name>OD15</name>
              <bitOffset>15</bitOffset>
              <bitWidth>1</bitWidth>
            </field>
          </fields>
        </register>
        <register>
          <name>BSRR</name>
          <addressOffset>0x18</addressOffset>
          <size>0x20</size>
          <fields>
            <field>
              <name>BS0</name>
              <bitOffset>0</bitOffset>
              <bitWidth>1</bitWidth>
            </field>
            <field>
              <name>BS1</name>
              <bitOffset>1</bitOffset>
              <bitWidth>1</bitWidth>
            </field>
            <field>
              <name>BS2</name>
              <bitOffset>2</bitOffset>
              <bitWidth>1</bitWidth>
            </field>
            <field>
              <name>BS3</name>
              <bitOffset>3</bitOffset>
              <bitWidth>1</bitWidth>
            </field>
            <field>
              <name>BS4</name>
              <bitOffset>4</bitOffset>
              <bitWidth>1</bitWidth>
            </field>
            <field>
              <name>BS5</name>
              <bitOffset>5</bitOffset>
              <bitWidth>1</bitWidth>
            </field>
            <field>
              <name>BS6</name>
              <bitOffset>6</bitOffset>
              <bitWidth>1</bitWidth>
            </field>
            <field>
              <name>BS7</name>
              <bitOffset>7</bitOffset>
              <bitWidth>1</bitWidth>
            </field>
            <field>
              <name>BS8</name>
              <bitOffset>8</bitOffset>
              <bitWidth>1</bitWidth>
            </field>
            <field>
              <name>BS9</name>
              <bitOffset>9</bitOffset>
              <bitWidth>1</bitWidth>
            </field>
            <field>
              <name>BS10</name>
              <bitOffset>10</bitOffset>
              <bitWidth>1</bitWidth>
            </field>
            <field>
              <name>BS11</name>
              <bitOffset>11</bitOffset>
              <bitWidth>1</bitWidth>
            </field>
            <field>
              <name>BS12</name>
              <bitOffset>12</bitOffset>
              <bitWidth>1</bitWidth>
            </field>
            <field>
              <name>BS13</name>
              <bitOffset>13</bitOffset>
              <bitWidth>1</bitWidth>
            </field>
            <field>
              <name>BS14</name>
              <bitOffset>14</bitOffset>
              <bitWidth>1</bitWidth>
            </field>
            <field>
              <name>BS15</name>
              <bitOffset>15</bitOffset>
              <bitWidth>1</bitWidth>
            </field>
            <field>
              <name>BR0</name>
              <bitOffset>16</bitOffset>
              <bitWidth>1</bitWidth>
            </field>
            <field>
              <name>BR1</name>
              <bitOffset>17</bitOffset>
              <bitWidth>1</bitWidth>
            </field>
            <field>
              <name>BR2</name>
              <bitOffset>18</bitOffset>
              <bitWidth>1</bitWidth>
            </field>
            <field>
              <name>BR3</name>
              <bitOffset>19</bitOffset>
              <bitWidth>1</bitWidth>
            </field>
            <field>
              <name>BR4</name>
              <bitOffset>20</bitOffset>
              <bitWidth>1</bitWidth>
            </field>
            <field>
              <name>BR5</name>
              <bitOffset>21</bitOffset>
              <bitWidth>1</bitWidth>
            </field>
            <field>
              <name>BR6</name>
              <bitOffset>22</bitOffset>
              <bitWidth>1</bitWidth>
            </field>
            <field>
              <name>BR7</name>
              <bitOffset>23</bitOffset>
              <bitWidth>1</bitWidth>
            </field>
            <field>
              <name>BR8</name>
              <bitOffset>24</bitOffset>
              <bitWidth>1</bitWidth>
            </field>
            <field>
              <name>BR9</name>
              <bitOffset>25</bitOffset>
              <bitWidth>1</bitWidth>
            </field>
            <field>
              <name>BR10</name>
              <bitOffset>26</bitOffset>
              <bitWidth>1</bitWidth>
            </field>
            <field>
              <name>BR11</name>
              <bitOffset>27</bitOffset>
              <bitWidth>1</bitWidth>
            </field>
            <field>
              <name>BR12</name>
              <bitOffset>28</bitOffset>
              <bitWidth>1</bitWidth>
            </field>
            <field>
              <name>BR13</name>
              <bitOffset>29</bitOffset>
              <bitWidth>1</bitWidth>
            </field>
            <field>
              <name>BR14</name>
              <bitOffset>30</bitOffset>
              <bitWidth>1</bitWidth>
            </field>
            <field>
              <name>BR15</name>
              <bitOffset>31</bitOffset>
              <bitWidth>1</bitWidth>
            </field>
          </fields>
        </register>
        <register>
          <name>LCKR</name>
          <addressOffset>0x1c</addressOffset>
          <size>0x20</size>
          <fields>
            <field>
              <name>LCK0</name>
              <bitOffset>0</bitOffset>
              <bitWidth>1</bitWidth>
            </field>
            <field>
              <name>LCK1</name>
              <bitOffset>1</bitOffset>
              <bitWidth>1</bitWidth>
            </field>
            <field>
              <name>LCK2</name>
              <bitOffset>2</bitOffset>
              <bitWidth>1</bitWidth>
            </field>
            <field>
              <name>LCK3</name>
              <bitOffset>3</bitOffset>
              <bitWidth>1</bitWidth>
            </field>
            <field>
              <name>LCK4</name>
              <bitOffset>4</bitOffset>
              <bitWidth>1</bitWidth>
            </field>
            <field>
              <name>LCK5</name>
              <bitOffset>5</bitOffset>
              <bitWidth>1</bitWidth>
            </field>
            <field>
              <name>LCK6</name>
              <bitOffset>6</bitOffset>
              <bitWidth>1</bitWidth>
            </field>
            <field>
              <name>LCK7</name>
              <bitOffset>7</bitOffset>
              <bitWidth>1</bitWidth>
            </field>
            <field>
              <name>LCK8</name>
              <bitOffset>8</bitOffset>
              <bitWidth>1</bitWidth>
            </field>
            <field>
              <name>LCK9</name>
              <bitOffset>9</bitOffset>
              <bitWidth>1</bitWidth>
            </field>
            <field>
              <name>LCK10</name>
              <bitOffset>10</bitOffset>
              <bitWidth>1</bitWidth>
            </field>
            <field>
              <name>LCK11</name>
              <bitOffset>11</bitOffset>
              <bitWidth>1</bitWidth>
            </field>
            <field>
              <name>LCK12</name>
              <bitOffset>12</bitOffset>
              <bitWidth>1</bitWidth>
            </field>
            <field>
              <name>LCK13</name>
              <bitOffset>13</bitOffset>
              <bitWidth>1</bitWidth>
            </field>
            <field>
              <name>LCK14</name>
              <bitOffset>14</bitOffset>
              <bitWidth>1</bitWidth>
            </field>
            <field>
              <name>LCK15</name>
              <bitOffset>15</bitOffset>
              <bitWidth>1</bitWidth>
            </field>
            <field>
              <name>LCKK</name>
              <bitOffset>16</bitOffset>
              <bitWidth>1</bitWidth>
            </field>
          </fields>
        </register>
        <register>
          <name>AFR.0</name>
          <addressOffset>0x20</addressOffset>
          <size>0x20</size>
          <fields>
            <field>
              <name>AFSEL0</name>
              <bitOffset>0</bitOffset>
              <bitWidth>4</bitWidth>
            </field>
            <field>
              <name>AFSEL1</name>
              <bitOffset>4</bitOffset>
              <bitWidth>4</bitWidth>
            </field>
            <field>
              <name>AFSEL2</name>
              <bitOffset>8</bitOffset>
              <bitWidth>4</bitWidth>
            </field>
            <field>
              <name>AFSEL3</name>
              <bitOffset>12</bitOffset>
              <bitWidth>4</bitWidth>
            </field>
            <field>
              <name>AFSEL4</name>
              <bitOffset>16</bitOffset>
              <bitWidth>4</bitWidth>
            </field>
            <field>
              <name>AFSEL5</name>
              <bitOffset>20</bitOffset>
              <bitWidth>4</bitWidth>
            </field>
            <field>
              <name>AFSEL6</name>
              <bitOffset>24</bitOffset>
              <bitWidth>4</bitWidth>
            </field>
            <field>
              <name>AFSEL7</name>
              <bitOffset>28</bitOffset>
              <bitWidth>4</bitWidth>
            </field>
          </fields>
        </register>
        <register>
          <name>AFR.1</name>
          <addressOffset>0x24</addressOffset>
          <size>0x20</size>
          <fields>
            <field>
              <name>AFSEL8</name>
              <bitOffset>0</bitOffset>
              <bitWidth>4</bitWidth>
            </field>
            <field>
              <name>AFSEL9</name>
              <bitOffset>4</bitOffset>
              <bitWidth>4</bitWidth>
            </field>
            <field>
              <name>AFSEL10</name>
              <bitOffset>8</bitOffset>
              <bitWidth>4</bitWidth>
            </field>
            <field>
              <name>AFSEL11</name>
              <bitOffset>12</bitOffset>
              <bitWidth>4</bitWidth>
            </field>
            <field>
              <name>AFSEL12</name>
              <bitOffset>16</bitOffset>
              <bitWidth>4</bitWidth>
            </field>
            <field>
              <name>AFSEL13</name>
              <bitOffset>20</bitOffset>
              <bitWidth>4</bitWidth>
            </field>
            <field>
              <name>AFSEL14</name>
              <bitOffset>24</bitOffset>
              <bitWidth>4</bitWidth>
            </field>
            <field>
              <name>AFSEL15</name>
              <bitOffset>28</bitOffset>
              <bitWidth>4</bitWidth>
            </field>
          </fields>
        </register>
      </registers>
    </peripheral>
    <peripheral>
      <name>GPIOC</name>
      <baseAddress>0x58020800</baseAddress>
      <registers>
        <register>
          <name>MODER</name>
          <addressOffset>0x0</addressOffset>
          <size>0x20</size>
          <fields>
            <field>
              <name>MODE0</name>
              <bitOffset>0</bitOffset>
              <bitWidth>2</bitWidth>
            </field>
            <field>
              <name>MODE1</name>
              <bitOffset>2</bitOffset>
              <bitWidth>2</bitWidth>
            </field>
            <field>
              <name>MODE2</name>
              <bitOffset>4</bitOffset>
              <bitWidth>2</bitWidth>
            </field>
            <field>
              <name>MODE3</name>
              <bitOffset>6</bitOffset>
              <bitWidth>2</bitWidth>
            </field>
            <field>
              <name>MODE4</name>
              <bitOffset>8</bitOffset>
              <bitWidth>2</bitWidth>
            </field>
            <field>
              <name>MODE5</name>
              <bitOffset>10</bitOffset>
              <bitWidth>2</bitWidth>
            </field>
            <field>
              <name>MODE6</name>
              <bitOffset>12</bitOffset>
              <bitWidth>2</bitWidth>
            </field>
            <field>
              <name>MODE7</name>
              <bitOffset>14</bitOffset>
              <bitWidth>2</bitWidth>
            </field>
            <field>
              <name>MODE8</name>
              <bitOffset>16</bitOffset>
              <bitWidth>2</bitWidth>
            </field>
            <field>
              <name>MODE9</name>
              <bitOffset>18</bitOffset>
              <bitWidth>2</bitWidth>
            </field>
            <field>
              <name>MODE10</name>
              <bitOffset>20</bitOffset>
              <bitWidth>2</bitWidth>
            </field>
            <field>
              <name>MODE11</name>
              <bitOffset>22</bitOffset>
              <bitWidth>2</bitWidth>
            </field>
            <field>
              <name>MODE12</name>
              <bitOffset>24</bitOffset>
              <bitWidth>2</bitWidth>
            </field>
            <field>
              <name>MODE13</name>
              <bitOffset>26</bitOffset>
              <bitWidth>2</bitWidth>
            </field>
            <field>
              <name>MODE14</name>
              <bitOffset>28</bitOffset>
              <bitWidth>2</bitWidth>
            </field>
            <field>
              <name>MODE15</name>
              <bitOffset>30</bitOffset>
              <bitWidth>2</bitWidth>
            </field>
          </fields>
        </register>
        <register>
          <name>OTYPER</name>
          <addressOffset>0x4</addressOffset>
          <size>0x20</size>
          <fields>
            <field>
              <name>OT0</name>
              <bitOffset>0</bitOffset>
              <bitWidth>1</bitWidth>
            </field>
            <field>
              <name>OT1</name>
              <bitOffset>1</bitOffset>
              <bitWidth>1</bitWidth>
            </field>
            <field>
              <name>OT2</name>
              <bitOffset>2</bitOffset>
              <bitWidth>1</bitWidth>
            </field>
            <field>
              <name>OT3</name>
              <bitOffset>3</bitOffset>
              <bitWidth>1</bitWidth>
            </field>
            <field>
              <name>OT4</name>
              <bitOffset>4</bitOffset>
              <bitWidth>1</bitWidth>
            </field>
            <field>
              <name>OT5</name>
              <bitOffset>5</bitOffset>
              <bitWidth>1</bitWidth>
            </field>
            <field>
              <name>OT6</name>
              <bitOffset>6</bitOffset>
              <bitWidth>1</bitWidth>
            </field>
            <field>
              <name>OT7</name>
              <bitOffset>7</bitOffset>
              <bitWidth>1</bitWidth>
            </field>
            <field>
              <name>OT8</name>
              <bitOffset>8</bitOffset>
              <bitWidth>1</bitWidth>
            </field>
            <field>
              <name>OT9</name>
              <bitOffset>9</bitOffset>
              <bitWidth>1</bitWidth>
            </field>
            <field>
              <name>OT10</name>
              <bitOffset>10</bitOffset>
              <bitWidth>1</bitWidth>
            </field>
            <field>
              <name>OT11</name>
              <bitOffset>11</bitOffset>
              <bitWidth>1</bitWidth>
            </field>
            <field>
              <name>OT12</name>
              <bitOffset>12</bitOffset>
              <bitWidth>1</bitWidth>
            </field>
            <field>
              <name>OT13</name>
              <bitOffset>13</bitOffset>
              <bitWidth>1</bitWidth>
            </field>
            <field>
              <name>OT14</name>
              <bitOffset>14</bitOffset>
              <bitWidth>1</bitWidth>
            </field>
            <field>
              <name>OT15</name>
              <bitOffset>15</bitOffset>
              <bitWidth>1</bitWidth>
            </field>
          </fields>
        </register>
        <register>
          <name>OSPEEDR</name>
          <addressOffset>0x8</addressOffset>
          <size>0x20</size>
          <fields>
            <field>
              <name>OSPEED0</name>
              <bitOffset>0</bitOffset>
              <bitWidth>2</bitWidth>
            </field>
            <field>
              <name>OSPEED1</name>
              <bitOffset>2</bitOffset>
              <bitWidth>2</bitWidth>
            </field>
            <field>
              <name>OSPEED2</name>
              <bitOffset>4</bitOffset>
              <bitWidth>2</bitWidth>
            </field>
            <field>
              <name>OSPEED3</name>
              <bitOffset>6</bitOffset>
              <bitWidth>2</bitWidth>
            </field>
            <field>
              <name>OSPEED4</name>
              <bitOffset>8</bitOffset>
              <bitWidth>2</bitWidth>
            </field>
            <field>
              <name>OSPEED5</name>
              <bitOffset>10</bitOffset>
              <bitWidth>2</bitWidth>
            </field>
            <field>
              <name>OSPEED6</name>
              <bitOffset>12</bitOffset>
              <bitWidth>2</bitWidth>
            </field>
            <field>
              <name>OSPEED7</name>
              <bitOffset>14</bitOffset>
              <bitWidth>2</bitWidth>
            </field>
            <field>
              <name>OSPEED8</name>
              <bitOffset>16</bitOffset>
              <bitWidth>2</bitWidth>
            </field>
            <field>
              <name>OSPEED9</name>
              <bitOffset>18</bitOffset>
              <bitWidth>2</bitWidth>
            </field>
            <field>
              <name>OSPEED10</name>
              <bitOffset>20</bitOffset>
              <bitWidth>2</bitWidth>
            </field>
            <field>
              <name>OSPEED11</name>
              <bitOffset>22</bitOffset>
              <bitWidth>2</bitWidth>
            </field>
            <field>
              <name>OSPEED12</name>
              <bitOffset>24</bitOffset>
              <bitWidth>2</bitWidth>
            </field>
            <field>
              <name>OSPEED13</name>
              <bitOffset>26</bitOffset>
              <bitWidth>2</bitWidth>
            </field>
            <field>
              <name>OSPEED14</name>
              <bitOffset>28</bitOffset>
              <bitWidth>2</bitWidth>
            </field>
            <field>
              <name>OSPEED15</name>
              <bitOffset>30</bitOffset>
              <bitWidth>2</bitWidth>
            </field>
          </fields>
        </register>
        <register>
          <name>PUPDR</name>
          <addressOffset>0xc</addressOffset>
          <size>0x20</size>
          <fields>
            <field>
              <name>PUPD0</name>
              <bitOffset>0</bitOffset>
              <bitWidth>2</bitWidth>
            </field>
            <field>
              <name>PUPD1</name>
              <bitOffset>2</bitOffset>
              <bitWidth>2</bitWidth>
            </field>
            <field>
              <name>PUPD2</name>
              <bitOffset>4</bitOffset>
              <bitWidth>2</bitWidth>
            </field>
            <field>
              <name>PUPD3</name>
              <bitOffset>6</bitOffset>
              <bitWidth>2</bitWidth>
            </field>
            <field>
              <name>PUPD4</name>
              <bitOffset>8</bitOffset>
              <bitWidth>2</bitWidth>
            </field>
            <field>
              <name>PUPD5</name>
              <bitOffset>10</bitOffset>
              <bitWidth>2</bitWidth>
            </field>
            <field>
              <name>PUPD6</name>
              <bitOffset>12</bitOffset>
              <bitWidth>2</bitWidth>
            </field>
            <field>
              <name>PUPD7</name>
              <bitOffset>14</bitOffset>
              <bitWidth>2</bitWidth>
            </field>
            <field>
              <name>PUPD8</name>
              <bitOffset>16</bitOffset>
              <bitWidth>2</bitWidth>
            </field>
            <field>
              <name>PUPD9</name>
              <bitOffset>18</bitOffset>
              <bitWidth>2</bitWidth>
            </field>
            <field>
              <name>PUPD10</name>
              <bitOffset>20</bitOffset>
              <bitWidth>2</bitWidth>
            </field>
            <field>
              <name>PUPD11</name>
              <bitOffset>22</bitOffset>
              <bitWidth>2</bitWidth>
            </field>
            <field>
              <name>PUPD12</name>
              <bitOffset>24</bitOffset>
              <bitWidth>2</bitWidth>
            </field>
            <field>
              <name>PUPD13</name>
              <bitOffset>26</bitOffset>
              <bitWidth>2</bitWidth>
            </field>
            <field>
              <name>PUPD14</name>
              <bitOffset>28</bitOffset>
              <bitWidth>2</bitWidth>
            </field>
            <field>
              <name>PUPD15</name>
              <bitOffset>30</bitOffset>
              <bitWidth>2</bitWidth>
            </field>
          </fields>
        </register>
        <register>
          <name>IDR</name>
          <addressOffset>0x10</addressOffset>
          <size>0x20</size>
          <fields>
            <field>
              <name>ID0</name>
              <bitOffset>0</bitOffset>
              <bitWidth>1</bitWidth>
            </field>
            <field>
              <name>ID1</name>
              <bitOffset>1</bitOffset>
              <bitWidth>1</bitWidth>
            </field>
            <field>
              <name>ID2</name>
              <bitOffset>2</bitOffset>
              <bitWidth>1</bitWidth>
            </field>
            <field>
              <name>ID3</name>
              <bitOffset>3</bitOffset>
              <bitWidth>1</bitWidth>
            </field>
            <field>
              <name>ID4</name>
              <bitOffset>4</bitOffset>
              <bitWidth>1</bitWidth>
            </field>
            <field>
              <name>ID5</name>
              <bitOffset>5</bitOffset>
              <bitWidth>1</bitWidth>
            </field>
            <field>
              <name>ID6</name>
              <bitOffset>6</bitOffset>
              <bitWidth>1</bitWidth>
            </field>
            <field>
              <name>ID7</name>
              <bitOffset>7</bitOffset>
              <bitWidth>1</bitWidth>
            </field>
            <field>
              <name>ID8</name>
              <bitOffset>8</bitOffset>
              <bitWidth>1</bitWidth>
            </field>
            <field>
              <name>ID9</name>
              <bitOffset>9</bitOffset>
              <bitWidth>1</bitWidth>
            </field>
            <field>
              <name>ID10</name>
              <bitOffset>10</bitOffset>
              <bitWidth>1</bitWidth>
            </field>
            <field>
              <name>ID11</name>
              <bitOffset>11</bitOffset>
              <bitWidth>1</bitWidth>
            </field>
            <field>
              <name>ID12</name>
              <bitOffset>12</bitOffset>
              <bitWidth>1</bitWidth>
            </field>
            <field>
              <name>ID13</name>
              <bitOffset>13</bitOffset>
              <bitWidth>1</bitWidth>
            </field>
            <field>
              <name>ID14</name>
              <bitOffset>14</bitOffset>
              <bitWidth>1</bitWidth>
            </field>
            <field>
              <name>ID15</name>
              <bitOffset>15</bitOffset>
              <bitWidth>1</bitWidth>
            </field>
          </fields>
        </register>
        <register>
          <name>ODR</name>
          <addressOffset>0x14</addressOffset>
          <size>0x20</size>
          <fields>
            <field>
              <name>OD0</name>
              <bitOffset>0</bitOffset>
              <bitWidth>1</bitWidth>
            </field>
            <field>
              <name>OD1</name>
              <bitOffset>1</bitOffset>
              <bitWidth>1</bitWidth>
            </field>
            <field>
              <name>OD2</name>
              <bitOffset>2</bitOffset>
              <bitWidth>1</bitWidth>
            </field>
            <field>
              <name>OD3</name>
              <bitOffset>3</bitOffset>
              <bitWidth>1</bitWidth>
            </field>
            <field>
              <name>OD4</name>
              <bitOffset>4</bitOffset>
              <bitWidth>1</bitWidth>
            </field>
            <field>
              <name>OD5</name>
              <bitOffset>5</bitOffset>
              <bitWidth>1</bitWidth>
            </field>
            <field>
              <name>OD6</name>
              <bitOffset>6</bitOffset>
              <bitWidth>1</bitWidth>
            </field>
            <field>
              <name>OD7</name>
              <bitOffset>7</bitOffset>
              <bitWidth>1</bitWidth>
            </field>
            <field>
              <name>OD8</name>
              <bitOffset>8</bitOffset>
              <bitWidth>1</bitWidth>
            </field>
            <field>
              <name>OD9</name>
              <bitOffset>9</bitOffset>
              <bitWidth>1</bitWidth>
            </field>
            <field>
              <name>OD10</name>
              <bitOffset>10</bitOffset>
              <bitWidth>1</bitWidth>
            </field>
            <field>
              <name>OD11</name>
              <bitOffset>11</bitOffset>
              <bitWidth>1</bitWidth>
            </field>
            <field>
              <name>OD12</name>
              <bitOffset>12</bitOffset>
              <bitWidth>1</bitWidth>
            </field>
            <field>
              <name>OD13</name>
              <bitOffset>13</bitOffset>
              <bitWidth>1</bitWidth>
            </field>
            <field>
              <name>OD14</name>
              <bitOffset>14</bitOffset>
              <bitWidth>1</bitWidth>
            </field>
            <field>
              <name>OD15</name>
              <bitOffset>15</bitOffset>
              <bitWidth>1</bitWidth>
            </field>
          </fields>
        </register>
        <register>
          <name>BSRR</name>
          <addressOffset>0x18</addressOffset>
          <size>0x20</size>
          <fields>
            <field>
              <name>BS0</name>
              <bitOffset>0</bitOffset>
              <bitWidth>1</bitWidth>
            </field>
            <field>
              <name>BS1</name>
              <bitOffset>1</bitOffset>
              <bitWidth>1</bitWidth>
            </field>
            <field>
              <name>BS2</name>
              <bitOffset>2</bitOffset>
              <bitWidth>1</bitWidth>
            </field>
            <field>
              <name>BS3</name>
              <bitOffset>3</bitOffset>
              <bitWidth>1</bitWidth>
            </field>
            <field>
              <name>BS4</name>
              <bitOffset>4</bitOffset>
              <bitWidth>1</bitWidth>
            </field>
            <field>
              <name>BS5</name>
              <bitOffset>5</bitOffset>
              <bitWidth>1</bitWidth>
            </field>
            <field>
              <name>BS6</name>
              <bitOffset>6</bitOffset>
              <bitWidth>1</bitWidth>
            </field>
            <field>
              <name>BS7</name>
              <bitOffset>7</bitOffset>
              <bitWidth>1</bitWidth>
            </field>
            <field>
              <name>BS8</name>
              <bitOffset>8</bitOffset>
              <bitWidth>1</bitWidth>
            </field>
            <field>
              <name>BS9</name>
              <bitOffset>9</bitOffset>
              <bitWidth>1</bitWidth>
            </field>
            <field>
              <name>BS10</name>
              <bitOffset>10</bitOffset>
              <bitWidth>1</bitWidth>
            </field>
            <field>
              <name>BS11</name>
              <bitOffset>11</bitOffset>
              <bitWidth>1</bitWidth>
            </field>
            <field>
              <name>BS12</name>
              <bitOffset>12</bitOffset>
              <bitWidth>1</bitWidth>
            </field>
            <field>
              <name>BS13</name>
              <bitOffset>13</bitOffset>
              <bitWidth>1</bitWidth>
            </field>
            <field>
              <name>BS14</name>
              <bitOffset>14</bitOffset>
              <bitWidth>1</bitWidth>
            </field>
            <field>
              <name>BS15</name>
              <bitOffset>15</bitOffset>
              <bitWidth>1</bitWidth>
            </field>
            <field>
              <name>BR0</name>
              <bitOffset>16</bitOffset>
              <bitWidth>1</bitWidth>
            </field>
            <field>
              <name>BR1</name>
              <bitOffset>17</bitOffset>
              <bitWidth>1</bitWidth>
            </field>
            <field>
              <name>BR2</name>
              <bitOffset>18</bitOffset>
              <bitWidth>1</bitWidth>
            </field>
            <field>
              <name>BR3</name>
              <bitOffset>19</bitOffset>
              <bitWidth>1</bitWidth>
            </field>
            <field>
              <name>BR4</name>
              <bitOffset>20</bitOffset>
              <bitWidth>1</bitWidth>
            </field>
            <field>
              <name>BR5</name>
              <bitOffset>21</bitOffset>
              <bitWidth>1</bitWidth>
            </field>
            <field>
              <name>BR6</name>
              <bitOffset>22</bitOffset>
              <bitWidth>1</bitWidth>
            </field>
            <field>
              <name>BR7</name>
              <bitOffset>23</bitOffset>
              <bitWidth>1</bitWidth>
            </field>
            <field>
              <name>BR8</name>
              <bitOffset>24</bitOffset>
              <bitWidth>1</bitWidth>
            </field>
            <field>
              <name>BR9</name>
              <bitOffset>25</bitOffset>
              <bitWidth>1</bitWidth>
            </field>
            <field>
              <name>BR10</name>
              <bitOffset>26</bitOffset>
              <bitWidth>1</bitWidth>
            </field>
            <field>
              <name>BR11</name>
              <bitOffset>27</bitOffset>
              <bitWidth>1</bitWidth>
            </field>
            <field>
              <name>BR12</name>
              <bitOffset>28</bitOffset>
              <bitWidth>1</bitWidth>
            </field>
            <field>
              <name>BR13</name>
              <bitOffset>29</bitOffset>
              <bitWidth>1</bitWidth>
            </field>
            <field>
              <name>BR14</name>
              <bitOffset>30</bitOffset>
              <bitWidth>1</bitWidth>
            </field>
            <field>
              <name>BR15</name>
              <bitOffset>31</bitOffset>
              <bitWidth>1</bitWidth>
            </field>
          </fields>
        </register>
        <register>
          <name>LCKR</name>
          <addressOffset>0x1c</addressOffset>
          <size>0x20</size>
          <fields>
            <field>
              <name>LCK0</name>
              <bitOffset>0</bitOffset>
              <bitWidth>1</bitWidth>
            </field>
            <field>
              <name>LCK1</name>
              <bitOffset>1</bitOffset>
              <bitWidth>1</bitWidth>
            </field>
            <field>
              <name>LCK2</name>
              <bitOffset>2</bitOffset>
              <bitWidth>1</bitWidth>
            </field>
            <field>
              <name>LCK3</name>
              <bitOffset>3</bitOffset>
              <bitWidth>1</bitWidth>
            </field>
            <field>
              <name>LCK4</name>
              <bitOffset>4</bitOffset>
              <bitWidth>1</bitWidth>
            </field>
            <field>
              <name>LCK5</name>
              <bitOffset>5</bitOffset>
              <bitWidth>1</bitWidth>
            </field>
            <field>
              <name>LCK6</name>
              <bitOffset>6</bitOffset>
              <bitWidth>1</bitWidth>
            </field>
            <field>
              <name>LCK7</name>
              <bitOffset>7</bitOffset>
              <bitWidth>1</bitWidth>
            </field>
            <field>
              <name>LCK8</name>
              <bitOffset>8</bitOffset>
              <bitWidth>1</bitWidth>
            </field>
            <field>
              <name>LCK9</name>
              <bitOffset>9</bitOffset>
              <bitWidth>1</bitWidth>
            </field>
            <field>
              <name>LCK10</name>
              <bitOffset>10</bitOffset>
              <bitWidth>1</bitWidth>
            </field>
            <field>
              <name>LCK11</name>
              <bitOffset>11</bitOffset>
              <bitWidth>1</bitWidth>
            </field>
            <field>
              <name>LCK12</name>
              <bitOffset>12</bitOffset>
              <bitWidth>1</bitWidth>
            </field>
            <field>
              <name>LCK13</name>
              <bitOffset>13</bitOffset>
              <bitWidth>1</bitWidth>
            </field>
            <field>
              <name>LCK14</name>
              <bitOffset>14</bitOffset>
              <bitWidth>1</bitWidth>
            </field>
            <field>
              <name>LCK15</name>
              <bitOffset>15</bitOffset>
              <bitWidth>1</bitWidth>
            </field>
            <field>
              <name>LCKK</name>
              <bitOffset>16</bitOffset>
              <bitWidth>1</bitWidth>
            </field>
          </fields>
        </register>
        <register>
          <name>AFR.0</name>
          <addressOffset>0x20</addressOffset>
          <size>0x20</size>
          <fields>
            <field>
              <name>AFSEL0</name>
              <bitOffset>0</bitOffset>
              <bitWidth>4</bitWidth>
            </field>
            <field>
              <name>AFSEL1</name>
              <bitOffset>4</bitOffset>
              <bitWidth>4</bitWidth>
            </field>
            <field>
              <name>AFSEL2</name>
              <bitOffset>8</bitOffset>
              <bitWidth>4</bitWidth>
            </field>
            <field>
              <name>AFSEL3</name>
              <bitOffset>12</bitOffset>
              <bitWidth>4</bitWidth>
            </field>
            <field>
              <name>AFSEL4</name>
              <bitOffset>16</bitOffset>
              <bitWidth>4</bitWidth>
            </field>
            <field>
              <name>AFSEL5</name>
              <bitOffset>20</bitOffset>
              <bitWidth>4</bitWidth>
            </field>
            <field>
              <name>AFSEL6</name>
              <bitOffset>24</bitOffset>
              <bitWidth>4</bitWidth>
            </field>
            <field>
              <name>AFSEL7</name>
              <bitOffset>28</bitOffset>
              <bitWidth>4</bitWidth>
            </field>
          </fields>
        </register>
        <register>
          <name>AFR.1</name>
          <addressOffset>0x24</addressOffset>
          <size>0x20</size>
          <fields>
            <field>
              <name>AFSEL8</name>
              <bitOffset>0</bitOffset>
              <bitWidth>4</bitWidth>
            </field>
            <field>
              <name>AFSEL9</name>
              <bitOffset>4</bitOffset>
              <bitWidth>4</bitWidth>
            </field>
            <field>
              <name>AFSEL10</name>
              <bitOffset>8</bitOffset>
              <bitWidth>4</bitWidth>
            </field>
            <field>
              <name>AFSEL11</name>
              <bitOffset>12</bitOffset>
              <bitWidth>4</bitWidth>
            </field>
            <field>
              <name>AFSEL12</name>
              <bitOffset>16</bitOffset>
              <bitWidth>4</bitWidth>
            </field>
            <field>
              <name>AFSEL13</name>
              <bitOffset>20</bitOffset>
              <bitWidth>4</bitWidth>
            </field>
            <field>
              <name>AFSEL14</name>
              <bitOffset>24</bitOffset>
              <bitWidth>4</bitWidth>
            </field>
            <field>
              <name>AFSEL15</name>
              <bitOffset>28</bitOffset>
              <bitWidth>4</bitWidth>
            </field>
          </fields>
        </register>
      </registers>
    </peripheral>
    <peripheral>
      <name>GPIOD</name>
      <baseAddress>0x58020c00</baseAddress>
      <registers>
        <register>
          <name>MODER</name>
          <addressOffset>0x0</addressOffset>
          <size>0x20</size>
          <fields>
            <field>
              <name>MODE0</name>
              <bitOffset>0</bitOffset>
              <bitWidth>2</bitWidth>
            </field>
            <field>
              <name>MODE1</name>
              <bitOffset>2</bitOffset>
              <bitWidth>2</bitWidth>
            </field>
            <field>
              <name>MODE2</name>
              <bitOffset>4</bitOffset>
              <bitWidth>2</bitWidth>
            </field>
            <field>
              <name>MODE3</name>
              <bitOffset>6</bitOffset>
              <bitWidth>2</bitWidth>
            </field>
            <field>
              <name>MODE4</name>
              <bitOffset>8</bitOffset>
              <bitWidth>2</bitWidth>
            </field>
            <field>
              <name>MODE5</name>
              <bitOffset>10</bitOffset>
              <bitWidth>2</bitWidth>
            </field>
            <field>
              <name>MODE6</name>
              <bitOffset>12</bitOffset>
              <bitWidth>2</bitWidth>
            </field>
            <field>
              <name>MODE7</name>
              <bitOffset>14</bitOffset>
              <bitWidth>2</bitWidth>
            </field>
            <field>
              <name>MODE8</name>
              <bitOffset>16</bitOffset>
              <bitWidth>2</bitWidth>
            </field>
            <field>
              <name>MODE9</name>
              <bitOffset>18</bitOffset>
              <bitWidth>2</bitWidth>
            </field>
            <field>
              <name>MODE10</name>
              <bitOffset>20</bitOffset>
              <bitWidth>2</bitWidth>
            </field>
            <field>
              <name>MODE11</name>
              <bitOffset>22</bitOffset>
              <bitWidth>2</bitWidth>
            </field>
            <field>
              <name>MODE12</name>
              <bitOffset>24</bitOffset>
              <bitWidth>2</bitWidth>
            </field>
            <field>
              <name>MODE13</name>
              <bitOffset>26</bitOffset>
              <bitWidth>2</bitWidth>
            </field>
            <field>
              <name>MODE14</name>
              <bitOffset>28</bitOffset>
              <bitWidth>2</bitWidth>
            </field>
            <field>
              <name>MODE15</name>
              <bitOffset>30</bitOffset>
              <bitWidth>2</bitWidth>
            </field>
          </fields>
        </register>
        <register>
          <name>OTYPER</name>
          <addressOffset>0x4</addressOffset>
          <size>0x20</size>
          <fields>
            <field>
              <name>OT0</name>
              <bitOffset>0</bitOffset>
              <bitWidth>1</bitWidth>
            </field>
            <field>
              <name>OT1</name>
              <bitOffset>1</bitOffset>
              <bitWidth>1</bitWidth>
            </field>
            <field>
              <name>OT2</name>
              <bitOffset>2</bitOffset>
              <bitWidth>1</bitWidth>
            </field>
            <field>
              <name>OT3</name>
              <bitOffset>3</bitOffset>
              <bitWidth>1</bitWidth>
            </field>
            <field>
              <name>OT4</name>
              <bitOffset>4</bitOffset>
              <bitWidth>1</bitWidth>
            </field>
            <field>
              <name>OT5</name>
              <bitOffset>5</bitOffset>
              <bitWidth>1</bitWidth>
            </field>
            <field>
              <name>OT6</name>
              <bitOffset>6</bitOffset>
              <bitWidth>1</bitWidth>
            </field>
            <field>
              <name>OT7</name>
              <bitOffset>7</bitOffset>
              <bitWidth>1</bitWidth>
            </field>
            <field>
              <name>OT8</name>
              <bitOffset>8</bitOffset>
              <bitWidth>1</bitWidth>
            </field>
            <field>
              <name>OT9</name>
              <bitOffset>9</bitOffset>
              <bitWidth>1</bitWidth>
            </field>
            <field>
              <name>OT10</name>
              <bitOffset>10</bitOffset>
              <bitWidth>1</bitWidth>
            </field>
            <field>
              <name>OT11</name>
              <bitOffset>11</bitOffset>
              <bitWidth>1</bitWidth>
            </field>
            <field>
              <name>OT12</name>
              <bitOffset>12</bitOffset>
              <bitWidth>1</bitWidth>
            </field>
            <field>
              <name>OT13</name>
              <bitOffset>13</bitOffset>
              <bitWidth>1</bitWidth>
            </field>
            <field>
              <name>OT14</name>
              <bitOffset>14</bitOffset>
              <bitWidth>1</bitWidth>
            </field>
            <field>
              <name>OT15</name>
              <bitOffset>15</bitOffset>
              <bitWidth>1</bitWidth>
            </field>
          </fields>
        </register>
        <register>
          <name>OSPEEDR</name>
          <addressOffset>0x8</addressOffset>
          <size>0x20</size>
          <fields>
            <field>
              <name>OSPEED0</name>
              <bitOffset>0</bitOffset>
              <bitWidth>2</bitWidth>
            </field>
            <field>
              <name>OSPEED1</name>
              <bitOffset>2</bitOffset>
              <bitWidth>2</bitWidth>
            </field>
            <field>
              <name>OSPEED2</name>
              <bitOffset>4</bitOffset>
              <bitWidth>2</bitWidth>
            </field>
            <field>
              <name>OSPEED3</name>
              <bitOffset>6</bitOffset>
              <bitWidth>2</bitWidth>
            </field>
            <field>
              <name>OSPEED4</name>
              <bitOffset>8</bitOffset>
              <bitWidth>2</bitWidth>
            </field>
            <field>
              <name>OSPEED5</name>
              <bitOffset>10</bitOffset>
              <bitWidth>2</bitWidth>
            </field>
            <field>
              <name>OSPEED6</name>
              <bitOffset>12</bitOffset>
              <bitWidth>2</bitWidth>
            </field>
            <field>
              <name>OSPEED7</name>
              <bitOffset>14</bitOffset>
              <bitWidth>2</bitWidth>
            </field>
            <field>
              <name>OSPEED8</name>
              <bitOffset>16</bitOffset>
              <bitWidth>2</bitWidth>
            </field>
            <field>
              <name>OSPEED9</name>
              <bitOffset>18</bitOffset>
              <bitWidth>2</bitWidth>
            </field>
            <field>
              <name>OSPEED10</name>
              <bitOffset>20</bitOffset>
              <bitWidth>2</bitWidth>
            </field>
            <field>
              <name>OSPEED11</name>
              <bitOffset>22</bitOffset>
              <bitWidth>2</bitWidth>
            </field>
            <field>
              <name>OSPEED12</name>
              <bitOffset>24</bitOffset>
              <bitWidth>2</bitWidth>
            </field>
            <field>
              <name>OSPEED13</name>
              <bitOffset>26</bitOffset>
              <bitWidth>2</bitWidth>
            </field>
            <field>
              <name>OSPEED14</name>
              <bitOffset>28</bitOffset>
              <bitWidth>2</bitWidth>
            </field>
            <field>
              <name>OSPEED15</name>
              <bitOffset>30</bitOffset>
              <bitWidth>2</bitWidth>
            </field>
          </fields>
        </register>
        <register>
          <name>PUPDR</name>
          <addressOffset>0xc</addressOffset>
          <size>0x20</size>
          <fields>
            <field>
              <name>PUPD0</name>
              <bitOffset>0</bitOffset>
              <bitWidth>2</bitWidth>
            </field>
            <field>
              <name>PUPD1</name>
              <bitOffset>2</bitOffset>
              <bitWidth>2</bitWidth>
            </field>
            <field>
              <name>PUPD2</name>
              <bitOffset>4</bitOffset>
              <bitWidth>2</bitWidth>
            </field>
            <field>
              <name>PUPD3</name>
              <bitOffset>6</bitOffset>
              <bitWidth>2</bitWidth>
            </field>
            <field>
              <name>PUPD4</name>
              <bitOffset>8</bitOffset>
              <bitWidth>2</bitWidth>
            </field>
            <field>
              <name>PUPD5</name>
              <bitOffset>10</bitOffset>
              <bitWidth>2</bitWidth>
            </field>
            <field>
              <name>PUPD6</name>
              <bitOffset>12</bitOffset>
              <bitWidth>2</bitWidth>
            </field>
            <field>
              <name>PUPD7</name>
              <bitOffset>14</bitOffset>
              <bitWidth>2</bitWidth>
            </field>
            <field>
              <name>PUPD8</name>
              <bitOffset>16</bitOffset>
              <bitWidth>2</bitWidth>
            </field>
            <field>
              <name>PUPD9</name>
              <bitOffset>18</bitOffset>
              <bitWidth>2</bitWidth>
            </field>
            <field>
              <name>PUPD10</name>
              <bitOffset>20</bitOffset>
              <bitWidth>2</bitWidth>
            </field>
            <field>
              <name>PUPD11</name>
              <bitOffset>22</bitOffset>
              <bitWidth>2</bitWidth>
            </field>
            <field>
              <name>PUPD12</name>
              <bitOffset>24</bitOffset>
              <bitWidth>2</bitWidth>
            </field>
            <field>
              <name>PUPD13</name>
              <bitOffset>26</bitOffset>
              <bitWidth>2</bitWidth>
            </field>
            <field>
              <name>PUPD14</name>
              <bitOffset>28</bitOffset>
              <bitWidth>2</bitWidth>
            </field>
            <field>
              <name>PUPD15</name>
              <bitOffset>30</bitOffset>
              <bitWidth>2</bitWidth>
            </field>
          </fields>
        </register>
        <register>
          <name>IDR</name>
          <addressOffset>0x10</addressOffset>
          <size>0x20</size>
          <fields>
            <field>
              <name>ID0</name>
              <bitOffset>0</bitOffset>
              <bitWidth>1</bitWidth>
            </field>
            <field>
              <name>ID1</name>
              <bitOffset>1</bitOffset>
              <bitWidth>1</bitWidth>
            </field>
            <field>
              <name>ID2</name>
              <bitOffset>2</bitOffset>
              <bitWidth>1</bitWidth>
            </field>
            <field>
              <name>ID3</name>
              <bitOffset>3</bitOffset>
              <bitWidth>1</bitWidth>
            </field>
            <field>
              <name>ID4</name>
              <bitOffset>4</bitOffset>
              <bitWidth>1</bitWidth>
            </field>
            <field>
              <name>ID5</name>
              <bitOffset>5</bitOffset>
              <bitWidth>1</bitWidth>
            </field>
            <field>
              <name>ID6</name>
              <bitOffset>6</bitOffset>
              <bitWidth>1</bitWidth>
            </field>
            <field>
              <name>ID7</name>
              <bitOffset>7</bitOffset>
              <bitWidth>1</bitWidth>
            </field>
            <field>
              <name>ID8</name>
              <bitOffset>8</bitOffset>
              <bitWidth>1</bitWidth>
            </field>
            <field>
              <name>ID9</name>
              <bitOffset>9</bitOffset>
              <bitWidth>1</bitWidth>
            </field>
            <field>
              <name>ID10</name>
              <bitOffset>10</bitOffset>
              <bitWidth>1</bitWidth>
            </field>
            <field>
              <name>ID11</name>
              <bitOffset>11</bitOffset>
              <bitWidth>1</bitWidth>
            </field>
            <field>
              <name>ID12</name>
              <bitOffset>12</bitOffset>
              <bitWidth>1</bitWidth>
            </field>
            <field>
              <name>ID13</name>
              <bitOffset>13</bitOffset>
              <bitWidth>1</bitWidth>
            </field>
            <field>
              <name>ID14</name>
              <bitOffset>14</bitOffset>
              <bitWidth>1</bitWidth>
            </field>
            <field>
              <name>ID15</name>
              <bitOffset>15</bitOffset>
              <bitWidth>1</bitWidth>
            </field>
          </fields>
        </register>
        <register>
          <name>ODR</name>
          <addressOffset>0x14</addressOffset>
          <size>0x20</size>
          <fields>
            <field>
              <name>OD0</name>
              <bitOffset>0</bitOffset>
              <bitWidth>1</bitWidth>
            </field>
            <field>
              <name>OD1</name>
              <bitOffset>1</bitOffset>
              <bitWidth>1</bitWidth>
            </field>
            <field>
              <name>OD2</name>
              <bitOffset>2</bitOffset>
              <bitWidth>1</bitWidth>
            </field>
            <field>
              <name>OD3</name>
              <bitOffset>3</bitOffset>
              <bitWidth>1</bitWidth>
            </field>
            <field>
              <name>OD4</name>
              <bitOffset>4</bitOffset>
              <bitWidth>1</bitWidth>
            </field>
            <field>
              <name>OD5</name>
              <bitOffset>5</bitOffset>
              <bitWidth>1</bitWidth>
            </field>
            <field>
              <name>OD6</name>
              <bitOffset>6</bitOffset>
              <bitWidth>1</bitWidth>
            </field>
            <field>
              <name>OD7</name>
              <bitOffset>7</bitOffset>
              <bitWidth>1</bitWidth>
            </field>
            <field>
              <name>OD8</name>
              <bitOffset>8</bitOffset>
              <bitWidth>1</bitWidth>
            </field>
            <field>
              <name>OD9</name>
              <bitOffset>9</bitOffset>
              <bitWidth>1</bitWidth>
            </field>
            <field>
              <name>OD10</name>
              <bitOffset>10</bitOffset>
              <bitWidth>1</bitWidth>
            </field>
            <field>
              <name>OD11</name>
              <bitOffset>11</bitOffset>
              <bitWidth>1</bitWidth>
            </field>
            <field>
              <name>OD12</name>
              <bitOffset>12</bitOffset>
              <bitWidth>1</bitWidth>
            </field>
            <field>
              <name>OD13</name>
              <bitOffset>13</bitOffset>
              <bitWidth>1</bitWidth>
            </field>
            <field>
              <name>OD14</name>
              <bitOffset>14</bitOffset>
              <bitWidth>1</bitWidth>
            </field>
            <field>
              <name>OD15</name>
              <bitOffset>15</bitOffset>
              <bitWidth>1</bitWidth>
            </field>
          </fields>
        </register>
        <register>
          <name>BSRR</name>
          <addressOffset>0x18</addressOffset>
          <size>0x20</size>
          <fields>
            <field>
              <name>BS0</name>
              <bitOffset>0</bitOffset>
              <bitWidth>1</bitWidth>
            </field>
            <field>
              <name>BS1</name>
              <bitOffset>1</bitOffset>
              <bitWidth>1</bitWidth>
            </field>
            <field>
              <name>BS2</name>
              <bitOffset>2</bitOffset>
              <bitWidth>1</bitWidth>
            </field>
            <field>
              <name>BS3</name>
              <bitOffset>3</bitOffset>
              <bitWidth>1</bitWidth>
            </field>
            <field>
              <name>BS4</name>
              <bitOffset>4</bitOffset>
              <bitWidth>1</bitWidth>
            </field>
            <field>
              <name>BS5</name>
              <bitOffset>5</bitOffset>
              <bitWidth>1</bitWidth>
            </field>
            <field>
              <name>BS6</name>
              <bitOffset>6</bitOffset>
              <bitWidth>1</bitWidth>
            </field>
            <field>
              <name>BS7</name>
              <bitOffset>7</bitOffset>
              <bitWidth>1</bitWidth>
            </field>
            <field>
              <name>BS8</name>
              <bitOffset>8</bitOffset>
              <bitWidth>1</bitWidth>
            </field>
            <field>
              <name>BS9</name>
              <bitOffset>9</bitOffset>
              <bitWidth>1</bitWidth>
            </field>
            <field>
              <name>BS10</name>
              <bitOffset>10</bitOffset>
              <bitWidth>1</bitWidth>
            </field>
            <field>
              <name>BS11</name>
              <bitOffset>11</bitOffset>
              <bitWidth>1</bitWidth>
            </field>
            <field>
              <name>BS12</name>
              <bitOffset>12</bitOffset>
              <bitWidth>1</bitWidth>
            </field>
            <field>
              <name>BS13</name>
              <bitOffset>13</bitOffset>
              <bitWidth>1</bitWidth>
            </field>
            <field>
              <name>BS14</name>
              <bitOffset>14</bitOffset>
              <bitWidth>1</bitWidth>
            </field>
            <field>
              <name>BS15</name>
              <bitOffset>15</bitOffset>
              <bitWidth>1</bitWidth>
            </field>
            <field>
              <name>BR0</name>
              <bitOffset>16</bitOffset>
              <bitWidth>1</bitWidth>
            </field>
            <field>
              <name>BR1</name>
              <bitOffset>17</bitOffset>
              <bitWidth>1</bitWidth>
            </field>
            <field>
              <name>BR2</name>
              <bitOffset>18</bitOffset>
              <bitWidth>1</bitWidth>
            </field>
            <field>
              <name>BR3</name>
              <bitOffset>19</bitOffset>
              <bitWidth>1</bitWidth>
            </field>
            <field>
              <name>BR4</name>
              <bitOffset>20</bitOffset>
              <bitWidth>1</bitWidth>
            </field>
            <field>
              <name>BR5</name>
              <bitOffset>21</bitOffset>
              <bitWidth>1</bitWidth>
            </field>
            <field>
              <name>BR6</name>
              <bitOffset>22</bitOffset>
              <bitWidth>1</bitWidth>
            </field>
            <field>
              <name>BR7</name>
              <bitOffset>23</bitOffset>
              <bitWidth>1</bitWidth>
            </field>
            <field>
              <name>BR8</name>
              <bitOffset>24</bitOffset>
              <bitWidth>1</bitWidth>
            </field>
            <field>
              <name>BR9</name>
              <bitOffset>25</bitOffset>
              <bitWidth>1</bitWidth>
            </field>
            <field>
              <name>BR10</name>
              <bitOffset>26</bitOffset>
              <bitWidth>1</bitWidth>
            </field>
            <field>
              <name>BR11</name>
              <bitOffset>27</bitOffset>
              <bitWidth>1</bitWidth>
            </field>
            <field>
              <name>BR12</name>
              <bitOffset>28</bitOffset>
              <bitWidth>1</bitWidth>
            </field>
            <field>
              <name>BR13</name>
              <bitOffset>29</bitOffset>
              <bitWidth>1</bitWidth>
            </field>
            <field>
              <name>BR14</name>
              <bitOffset>30</bitOffset>
              <bitWidth>1</bitWidth>
            </field>
            <field>
              <name>BR15</name>
              <bitOffset>31</bitOffset>
              <bitWidth>1</bitWidth>
            </field>
          </fields>
        </register>
        <register>
          <name>LCKR</name>
          <addressOffset>0x1c</addressOffset>
          <size>0x20</size>
          <fields>
            <field>
              <name>LCK0</name>
              <bitOffset>0</bitOffset>
              <bitWidth>1</bitWidth>
            </field>
            <field>
              <name>LCK1</name>
              <bitOffset>1</bitOffset>
              <bitWidth>1</bitWidth>
            </field>
            <field>
              <name>LCK2</name>
              <bitOffset>2</bitOffset>
              <bitWidth>1</bitWidth>
            </field>
            <field>
              <name>LCK3</name>
              <bitOffset>3</bitOffset>
              <bitWidth>1</bitWidth>
            </field>
            <field>
              <name>LCK4</name>
              <bitOffset>4</bitOffset>
              <bitWidth>1</bitWidth>
            </field>
            <field>
              <name>LCK5</name>
              <bitOffset>5</bitOffset>
              <bitWidth>1</bitWidth>
            </field>
            <field>
              <name>LCK6</name>
              <bitOffset>6</bitOffset>
              <bitWidth>1</bitWidth>
            </field>
            <field>
              <name>LCK7</name>
              <bitOffset>7</bitOffset>
              <bitWidth>1</bitWidth>
            </field>
            <field>
              <name>LCK8</name>
              <bitOffset>8</bitOffset>
              <bitWidth>1</bitWidth>
            </field>
            <field>
              <name>LCK9</name>
              <bitOffset>9</bitOffset>
              <bitWidth>1</bitWidth>
            </field>
            <field>
              <name>LCK10</name>
              <bitOffset>10</bitOffset>
              <bitWidth>1</bitWidth>
            </field>
            <field>
              <name>LCK11</name>
              <bitOffset>11</bitOffset>
              <bitWidth>1</bitWidth>
            </field>
            <field>
              <name>LCK12</name>
              <bitOffset>12</bitOffset>
              <bitWidth>1</bitWidth>
            </field>
            <field>
              <name>LCK13</name>
              <bitOffset>13</bitOffset>
              <bitWidth>1</bitWidth>
            </field>
            <field>
              <name>LCK14</name>
              <bitOffset>14</bitOffset>
              <bitWidth>1</bitWidth>
            </field>
            <field>
              <name>LCK15</name>
              <bitOffset>15</bitOffset>
              <bitWidth>1</bitWidth>
            </field>
            <field>
              <name>LCKK</name>
              <bitOffset>16</bitOffset>
              <bitWidth>1</bitWidth>
            </field>
          </fields>
        </register>
        <register>
          <name>AFR.0</name>
          <addressOffset>0x20</addressOffset>
          <size>0x20</size>
          <fields>
            <field>
              <name>AFSEL0</name>
              <bitOffset>0</bitOffset>
              <bitWidth>4</bitWidth>
            </field>
            <field>
              <name>AFSEL1</name>
              <bitOffset>4</bitOffset>
              <bitWidth>4</bitWidth>
            </field>
            <field>
              <name>AFSEL2</name>
              <bitOffset>8</bitOffset>
              <bitWidth>4</bitWidth>
            </field>
            <field>
              <name>AFSEL3</name>
              <bitOffset>12</bitOffset>
              <bitWidth>4</bitWidth>
            </field>
            <field>
              <name>AFSEL4</name>
              <bitOffset>16</bitOffset>
              <bitWidth>4</bitWidth>
            </field>
            <field>
              <name>AFSEL5</name>
              <bitOffset>20</bitOffset>
              <bitWidth>4</bitWidth>
            </field>
            <field>
              <name>AFSEL6</name>
              <bitOffset>24</bitOffset>
              <bitWidth>4</bitWidth>
            </field>
            <field>
              <name>AFSEL7</name>
              <bitOffset>28</bitOffset>
              <bitWidth>4</bitWidth>
            </field>
          </fields>
        </register>
        <register>
          <name>AFR.1</name>
          <addressOffset>0x24</addressOffset>
          <size>0x20</size>
          <fields>
            <field>
              <name>AFSEL8</name>
              <bitOffset>0</bitOffset>
              <bitWidth>4</bitWidth>
            </field>
            <field>
              <name>AFSEL9</name>
              <bitOffset>4</bitOffset>
              <bitWidth>4</bitWidth>
            </field>
            <field>
              <name>AFSEL10</name>
              <bitOffset>8</bitOffset>
              <bitWidth>4</bitWidth>
            </field>
            <field>
              <name>AFSEL11</name>
              <bitOffset>12</bitOffset>
              <bitWidth>4</bitWidth>
            </field>
            <field>
              <name>AFSEL12</name>
              <bitOffset>16</bitOffset>
              <bitWidth>4</bitWidth>
            </field>
            <field>
              <name>AFSEL13</name>
              <bitOffset>20</bitOffset>
              <bitWidth>4</bitWidth>
            </field>
            <field>
              <name>AFSEL14</name>
              <bitOffset>24</bitOffset>
              <bitWidth>4</bitWidth>
            </field>
            <field>
              <name>AFSEL15</name>
              <bitOffset>28</bitOffset>
              <bitWidth>4</bitWidth>
            </field>
          </fields>
        </register>
      </registers>
    </peripheral>
    <peripheral>
      <name>GPIOE</name>
      <baseAddress>0x58021000</baseAddress>
      <registers>
        <register>
          <name>MODER</name>
          <addressOffset>0x0</addressOffset>
          <size>0x20</size>
          <fields>
            <field>
              <name>MODE0</name>
              <bitOffset>0</bitOffset>
              <bitWidth>2</bitWidth>
            </field>
            <field>
              <name>MODE1</name>
              <bitOffset>2</bitOffset>
              <bitWidth>2</bitWidth>
            </field>
            <field>
              <name>MODE2</name>
              <bitOffset>4</bitOffset>
              <bitWidth>2</bitWidth>
            </field>
            <field>
              <name>MODE3</name>
              <bitOffset>6</bitOffset>
              <bitWidth>2</bitWidth>
            </field>
            <field>
              <name>MODE4</name>
              <bitOffset>8</bitOffset>
              <bitWidth>2</bitWidth>
            </field>
            <field>
              <name>MODE5</name>
              <bitOffset>10</bitOffset>
              <bitWidth>2</bitWidth>
            </field>
            <field>
              <name>MODE6</name>
              <bitOffset>12</bitOffset>
              <bitWidth>2</bitWidth>
            </field>
            <field>
              <name>MODE7</name>
              <bitOffset>14</bitOffset>
              <bitWidth>2</bitWidth>
            </field>
            <field>
              <name>MODE8</name>
              <bitOffset>16</bitOffset>
              <bitWidth>2</bitWidth>
            </field>
            <field>
              <name>MODE9</name>
              <bitOffset>18</bitOffset>
              <bitWidth>2</bitWidth>
            </field>
            <field>
              <name>MODE10</name>
              <bitOffset>20</bitOffset>
              <bitWidth>2</bitWidth>
            </field>
            <field>
              <name>MODE11</name>
              <bitOffset>22</bitOffset>
              <bitWidth>2</bitWidth>
            </field>
            <field>
              <name>MODE12</name>
              <bitOffset>24</bitOffset>
              <bitWidth>2</bitWidth>
            </field>
            <field>
              <name>MODE13</name>
              <bitOffset>26</bitOffset>
              <bitWidth>2</bitWidth>
            </field>
            <field>
              <name>MODE14</name>
              <bitOffset>28</bitOffset>
              <bitWidth>2</bitWidth>
            </field>
            <field>
              <name>MODE15</name>
              <bitOffset>30</bitOffset>
              <bitWidth>2</bitWidth>
            </field>
          </fields>
        </register>
        <register>
          <name>OTYPER</name>
          <addressOffset>0x4</addressOffset>
          <size>0x20</size>
          <fields>
            <field>
              <name>OT0</name>
              <bitOffset>0</bitOffset>
              <bitWidth>1</bitWidth>
            </field>
            <field>
              <name>OT1</name>
              <bitOffset>1</bitOffset>
              <bitWidth>1</bitWidth>
            </field>
            <field>
              <name>OT2</name>
              <bitOffset>2</bitOffset>
              <bitWidth>1</bitWidth>
            </field>
            <field>
              <name>OT3</name>
              <bitOffset>3</bitOffset>
              <bitWidth>1</bitWidth>
            </field>
            <field>
              <name>OT4</name>
              <bitOffset>4</bitOffset>
              <bitWidth>1</bitWidth>
            </field>
            <field>
              <name>OT5</name>
              <bitOffset>5</bitOffset>
              <bitWidth>1</bitWidth>
            </field>
            <field>
              <name>OT6</name>
              <bitOffset>6</bitOffset>
              <bitWidth>1</bitWidth>
            </field>
            <field>
              <name>OT7</name>
              <bitOffset>7</bitOffset>
              <bitWidth>1</bitWidth>
            </field>
            <field>
              <name>OT8</name>
              <bitOffset>8</bitOffset>
              <bitWidth>1</bitWidth>
            </field>
            <field>
              <name>OT9</name>
              <bitOffset>9</bitOffset>
              <bitWidth>1</bitWidth>
            </field>
            <field>
              <name>OT10</name>
              <bitOffset>10</bitOffset>
              <bitWidth>1</bitWidth>
            </field>
            <field>
              <name>OT11</name>
              <bitOffset>11</bitOffset>
              <bitWidth>1</bitWidth>
            </field>
            <field>
              <name>OT12</name>
              <bitOffset>12</bitOffset>
              <bitWidth>1</bitWidth>
            </field>
            <field>
              <name>OT13</name>
              <bitOffset>13</bitOffset>
              <bitWidth>1</bitWidth>
            </field>
            <field>
              <name>OT14</name>
              <bitOffset>14</bitOffset>
              <bitWidth>1</bitWidth>
            </field>
            <field>
              <name>OT15</name>
              <bitOffset>15</bitOffset>
              <bitWidth>1</bitWidth>
            </field>
          </fields>
        </register>
        <register>
          <name>OSPEEDR</name>
          <addressOffset>0x8</addressOffset>
          <size>0x20</size>
          <fields>
            <field>
              <name>OSPEED0</name>
              <bitOffset>0</bitOffset>
              <bitWidth>2</bitWidth>
            </field>
            <field>
              <name>OSPEED1</name>
              <bitOffset>2</bitOffset>
              <bitWidth>2</bitWidth>
            </field>
            <field>
              <name>OSPEED2</name>
              <bitOffset>4</bitOffset>
              <bitWidth>2</bitWidth>
            </field>
            <field>
              <name>OSPEED3</name>
              <bitOffset>6</bitOffset>
              <bitWidth>2</bitWidth>
            </field>
            <field>
              <name>OSPEED4</name>
              <bitOffset>8</bitOffset>
              <bitWidth>2</bitWidth>
            </field>
            <field>
              <name>OSPEED5</name>
              <bitOffset>10</bitOffset>
              <bitWidth>2</bitWidth>
            </field>
            <field>
              <name>OSPEED6</name>
              <bitOffset>12</bitOffset>
              <bitWidth>2</bitWidth>
            </field>
            <field>
              <name>OSPEED7</name>
              <bitOffset>14</bitOffset>
              <bitWidth>2</bitWidth>
            </field>
            <field>
              <name>OSPEED8</name>
              <bitOffset>16</bitOffset>
              <bitWidth>2</bitWidth>
            </field>
            <field>
              <name>OSPEED9</name>
              <bitOffset>18</bitOffset>
              <bitWidth>2</bitWidth>
            </field>
            <field>
              <name>OSPEED10</name>
              <bitOffset>20</bitOffset>
              <bitWidth>2</bitWidth>
            </field>
            <field>
              <name>OSPEED11</name>
              <bitOffset>22</bitOffset>
              <bitWidth>2</bitWidth>
            </field>
            <field>
              <name>OSPEED12</name>
              <bitOffset>24</bitOffset>
              <bitWidth>2</bitWidth>
            </field>
            <field>
              <name>OSPEED13</name>
              <bitOffset>26</bitOffset>
              <bitWidth>2</bitWidth>
            </field>
            <field>
              <name>OSPEED14</name>
              <bitOffset>28</bitOffset>
              <bitWidth>2</bitWidth>
            </field>
            <field>
              <name>OSPEED15</name>
              <bitOffset>30</bitOffset>
              <bitWidth>2</bitWidth>
            </field>
          </fields>
        </register>
        <register>
          <name>PUPDR</name>
          <addressOffset>0xc</addressOffset>
          <size>0x20</size>
          <fields>
            <field>
              <name>PUPD0</name>
              <bitOffset>0</bitOffset>
              <bitWidth>2</bitWidth>
            </field>
            <field>
              <name>PUPD1</name>
              <bitOffset>2</bitOffset>
              <bitWidth>2</bitWidth>
            </field>
            <field>
              <name>PUPD2</name>
              <bitOffset>4</bitOffset>
              <bitWidth>2</bitWidth>
            </field>
            <field>
              <name>PUPD3</name>
              <bitOffset>6</bitOffset>
              <bitWidth>2</bitWidth>
            </field>
            <field>
              <name>PUPD4</name>
              <bitOffset>8</bitOffset>
              <bitWidth>2</bitWidth>
            </field>
            <field>
              <name>PUPD5</name>
              <bitOffset>10</bitOffset>
              <bitWidth>2</bitWidth>
            </field>
            <field>
              <name>PUPD6</name>
              <bitOffset>12</bitOffset>
              <bitWidth>2</bitWidth>
            </field>
            <field>
              <name>PUPD7</name>
              <bitOffset>14</bitOffset>
              <bitWidth>2</bitWidth>
            </field>
            <field>
              <name>PUPD8</name>
              <bitOffset>16</bitOffset>
              <bitWidth>2</bitWidth>
            </field>
            <field>
              <name>PUPD9</name>
              <bitOffset>18</bitOffset>
              <bitWidth>2</bitWidth>
            </field>
            <field>
              <name>PUPD10</name>
              <bitOffset>20</bitOffset>
              <bitWidth>2</bitWidth>
            </field>
            <field>
              <name>PUPD11</name>
              <bitOffset>22</bitOffset>
              <bitWidth>2</bitWidth>
            </field>
            <field>
              <name>PUPD12</name>
              <bitOffset>24</bitOffset>
              <bitWidth>2</bitWidth>
            </field>
            <field>
              <name>PUPD13</name>
              <bitOffset>26</bitOffset>
              <bitWidth>2</bitWidth>
            </field>
            <field>
              <name>PUPD14</name>
              <bitOffset>28</bitOffset>
              <bitWidth>2</bitWidth>
            </field>
            <field>
              <name>PUPD15</name>
              <bitOffset>30</bitOffset>
              <bitWidth>2</bitWidth>
            </field>
          </fields>
        </register>
        <register>
          <name>IDR</name>
          <addressOffset>0x10</addressOffset>
          <size>0x20</size>
          <fields>
            <field>
              <name>ID0</name>
              <bitOffset>0</bitOffset>
              <bitWidth>1</bitWidth>
            </field>
            <field>
              <name>ID1</name>
              <bitOffset>1</bitOffset>
              <bitWidth>1</bitWidth>
            </field>
            <field>
              <name>ID2</name>
              <bitOffset>2</bitOffset>
              <bitWidth>1</bitWidth>
            </field>
            <field>
              <name>ID3</name>
              <bitOffset>3</bitOffset>
              <bitWidth>1</bitWidth>
            </field>
            <field>
              <name>ID4</name>
              <bitOffset>4</bitOffset>
              <bitWidth>1</bitWidth>
            </field>
            <field>
              <name>ID5</name>
              <bitOffset>5</bitOffset>
              <bitWidth>1</bitWidth>
            </field>
            <field>
              <name>ID6</name>
              <bitOffset>6</bitOffset>
              <bitWidth>1</bitWidth>
            </field>
            <field>
              <name>ID7</name>
              <bitOffset>7</bitOffset>
              <bitWidth>1</bitWidth>
            </field>
            <field>
              <name>ID8</name>
              <bitOffset>8</bitOffset>
              <bitWidth>1</bitWidth>
            </field>
            <field>
              <name>ID9</name>
              <bitOffset>9</bitOffset>
              <bitWidth>1</bitWidth>
            </field>
            <field>
              <name>ID10</name>
              <bitOffset>10</bitOffset>
              <bitWidth>1</bitWidth>
            </field>
            <field>
              <name>ID11</name>
              <bitOffset>11</bitOffset>
              <bitWidth>1</bitWidth>
            </field>
            <field>
              <name>ID12</name>
              <bitOffset>12</bitOffset>
              <bitWidth>1</bitWidth>
            </field>
            <field>
              <name>ID13</name>
              <bitOffset>13</bitOffset>
              <bitWidth>1</bitWidth>
            </field>
            <field>
              <name>ID14</name>
              <bitOffset>14</bitOffset>
              <bitWidth>1</bitWidth>
            </field>
            <field>
              <name>ID15</name>
              <bitOffset>15</bitOffset>
              <bitWidth>1</bitWidth>
            </field>
          </fields>
        </register>
        <register>
          <name>ODR</name>
          <addressOffset>0x14</addressOffset>
          <size>0x20</size>
          <fields>
            <field>
              <name>OD0</name>
              <bitOffset>0</bitOffset>
              <bitWidth>1</bitWidth>
            </field>
            <field>
              <name>OD1</name>
              <bitOffset>1</bitOffset>
              <bitWidth>1</bitWidth>
            </field>
            <field>
              <name>OD2</name>
              <bitOffset>2</bitOffset>
              <bitWidth>1</bitWidth>
            </field>
            <field>
              <name>OD3</name>
              <bitOffset>3</bitOffset>
              <bitWidth>1</bitWidth>
            </field>
            <field>
              <name>OD4</name>
              <bitOffset>4</bitOffset>
              <bitWidth>1</bitWidth>
            </field>
            <field>
              <name>OD5</name>
              <bitOffset>5</bitOffset>
              <bitWidth>1</bitWidth>
            </field>
            <field>
              <name>OD6</name>
              <bitOffset>6</bitOffset>
              <bitWidth>1</bitWidth>
            </field>
            <field>
              <name>OD7</name>
              <bitOffset>7</bitOffset>
              <bitWidth>1</bitWidth>
            </field>
            <field>
              <name>OD8</name>
              <bitOffset>8</bitOffset>
              <bitWidth>1</bitWidth>
            </field>
            <field>
              <name>OD9</name>
              <bitOffset>9</bitOffset>
              <bitWidth>1</bitWidth>
            </field>
            <field>
              <name>OD10</name>
              <bitOffset>10</bitOffset>
              <bitWidth>1</bitWidth>
            </field>
            <field>
              <name>OD11</name>
              <bitOffset>11</bitOffset>
              <bitWidth>1</bitWidth>
            </field>
            <field>
              <name>OD12</name>
              <bitOffset>12</bitOffset>
              <bitWidth>1</bitWidth>
            </field>
            <field>
              <name>OD13</name>
              <bitOffset>13</bitOffset>
              <bitWidth>1</bitWidth>
            </field>
            <field>
              <name>OD14</name>
              <bitOffset>14</bitOffset>
              <bitWidth>1</bitWidth>
            </field>
            <field>
              <name>OD15</name>
              <bitOffset>15</bitOffset>
              <bitWidth>1</bitWidth>
            </field>
          </fields>
        </register>
        <register>
          <name>BSRR</name>
          <addressOffset>0x18</addressOffset>
          <size>0x20</size>
          <fields>
            <field>
              <name>BS0</name>
              <bitOffset>0</bitOffset>
              <bitWidth>1</bitWidth>
            </field>
            <field>
              <name>BS1</name>
              <bitOffset>1</bitOffset>
              <bitWidth>1</bitWidth>
            </field>
            <field>
              <name>BS2</name>
              <bitOffset>2</bitOffset>
              <bitWidth>1</bitWidth>
            </field>
            <field>
              <name>BS3</name>
              <bitOffset>3</bitOffset>
              <bitWidth>1</bitWidth>
            </field>
            <field>
              <name>BS4</name>
              <bitOffset>4</bitOffset>
              <bitWidth>1</bitWidth>
            </field>
            <field>
              <name>BS5</name>
              <bitOffset>5</bitOffset>
              <bitWidth>1</bitWidth>
            </field>
            <field>
              <name>BS6</name>
              <bitOffset>6</bitOffset>
              <bitWidth>1</bitWidth>
            </field>
            <field>
              <name>BS7</name>
              <bitOffset>7</bitOffset>
              <bitWidth>1</bitWidth>
            </field>
            <field>
              <name>BS8</name>
              <bitOffset>8</bitOffset>
              <bitWidth>1</bitWidth>
            </field>
            <field>
              <name>BS9</name>
              <bitOffset>9</bitOffset>
              <bitWidth>1</bitWidth>
            </field>
            <field>
              <name>BS10</name>
              <bitOffset>10</bitOffset>
              <bitWidth>1</bitWidth>
            </field>
            <field>
              <name>BS11</name>
              <bitOffset>11</bitOffset>
              <bitWidth>1</bitWidth>
            </field>
            <field>
              <name>BS12</name>
              <bitOffset>12</bitOffset>
              <bitWidth>1</bitWidth>
            </field>
            <field>
              <name>BS13</name>
              <bitOffset>13</bitOffset>
              <bitWidth>1</bitWidth>
            </field>
            <field>
              <name>BS14</name>
              <bitOffset>14</bitOffset>
              <bitWidth>1</bitWidth>
            </field>
            <field>
              <name>BS15</name>
              <bitOffset>15</bitOffset>
              <bitWidth>1</bitWidth>
            </field>
            <field>
              <name>BR0</name>
              <bitOffset>16</bitOffset>
              <bitWidth>1</bitWidth>
            </field>
            <field>
              <name>BR1</name>
              <bitOffset>17</bitOffset>
              <bitWidth>1</bitWidth>
            </field>
            <field>
              <name>BR2</name>
              <bitOffset>18</bitOffset>
              <bitWidth>1</bitWidth>
            </field>
            <field>
              <name>BR3</name>
              <bitOffset>19</bitOffset>
              <bitWidth>1</bitWidth>
            </field>
            <field>
              <name>BR4</name>
              <bitOffset>20</bitOffset>
              <bitWidth>1</bitWidth>
            </field>
            <field>
              <name>BR5</name>
              <bitOffset>21</bitOffset>
              <bitWidth>1</bitWidth>
            </field>
            <field>
              <name>BR6</name>
              <bitOffset>22</bitOffset>
              <bitWidth>1</bitWidth>
            </field>
            <field>
              <name>BR7</name>
              <bitOffset>23</bitOffset>
              <bitWidth>1</bitWidth>
            </field>
            <field>
              <name>BR8</name>
              <bitOffset>24</bitOffset>
              <bitWidth>1</bitWidth>
            </field>
            <field>
              <name>BR9</name>
              <bitOffset>25</bitOffset>
              <bitWidth>1</bitWidth>
            </field>
            <field>
              <name>BR10</name>
              <bitOffset>26</bitOffset>
              <bitWidth>1</bitWidth>
            </field>
            <field>
              <name>BR11</name>
              <bitOffset>27</bitOffset>
              <bitWidth>1</bitWidth>
            </field>
            <field>
              <name>BR12</name>
              <bitOffset>28</bitOffset>
              <bitWidth>1</bitWidth>
            </field>
            <field>
              <name>BR13</name>
              <bitOffset>29</bitOffset>
              <bitWidth>1</bitWidth>
            </field>
            <field>
              <name>BR14</name>
              <bitOffset>30</bitOffset>
              <bitWidth>1</bitWidth>
            </field>
            <field>
              <name>BR15</name>
              <bitOffset>31</bitOffset>
              <bitWidth>1</bitWidth>
            </field>
          </fields>
        </register>
        <register>
          <name>LCKR</name>
          <addressOffset>0x1c</addressOffset>
          <size>0x20</size>
          <fields>
            <field>
              <name>LCK0</name>
              <bitOffset>0</bitOffset>
              <bitWidth>1</bitWidth>
            </field>
            <field>
              <name>LCK1</name>
              <bitOffset>1</bitOffset>
              <bitWidth>1</bitWidth>
            </field>
            <field>
              <name>LCK2</name>
              <bitOffset>2</bitOffset>
              <bitWidth>1</bitWidth>
            </field>
            <field>
              <name>LCK3</name>
              <bitOffset>3</bitOffset>
              <bitWidth>1</bitWidth>
            </field>
            <field>
              <name>LCK4</name>
              <bitOffset>4</bitOffset>
              <bitWidth>1</bitWidth>
            </field>
            <field>
              <name>LCK5</name>
              <bitOffset>5</bitOffset>
              <bitWidth>1</bitWidth>
            </field>
            <field>
              <name>LCK6</name>
              <bitOffset>6</bitOffset>
              <bitWidth>1</bitWidth>
            </field>
            <field>
              <name>LCK7</name>
              <bitOffset>7</bitOffset>
              <bitWidth>1</bitWidth>
            </field>
            <field>
              <name>LCK8</name>
              <bitOffset>8</bitOffset>
              <bitWidth>1</bitWidth>
            </field>
            <field>
              <name>LCK9</name>
              <bitOffset>9</bitOffset>
              <bitWidth>1</bitWidth>
            </field>
            <field>
              <name>LCK10</name>
              <bitOffset>10</bitOffset>
              <bitWidth>1</bitWidth>
            </field>
            <field>
              <name>LCK11</name>
              <bitOffset>11</bitOffset>
              <bitWidth>1</bitWidth>
            </field>
            <field>
              <name>LCK12</name>
              <bitOffset>12</bitOffset>
              <bitWidth>1</bitWidth>
            </field>
            <field>
              <name>LCK13</name>
              <bitOffset>13</bitOffset>
              <bitWidth>1</bitWidth>
            </field>
            <field>
              <name>LCK14</name>
              <bitOffset>14</bitOffset>
              <bitWidth>1</bitWidth>
            </field>
            <field>
              <name>LCK15</name>
              <bitOffset>15</bitOffset>
              <bitWidth>1</bitWidth>
            </field>
            <field>
              <name>LCKK</name>
              <bitOffset>16</bitOffset>
              <bitWidth>1</bitWidth>
            </field>
          </fields>
        </register>
        <register>
          <name>AFR.0</name>
          <addressOffset>0x20</addressOffset>
          <size>0x20</size>
          <fields>
            <field>
              <name>AFSEL0</name>
              <bitOffset>0</bitOffset>
              <bitWidth>4</bitWidth>
            </field>
            <field>
              <name>AFSEL1</name>
              <bitOffset>4</bitOffset>
              <bitWidth>4</bitWidth>
            </field>
            <field>
              <name>AFSEL2</name>
              <bitOffset>8</bitOffset>
              <bitWidth>4</bitWidth>
            </field>
            <field>
              <name>AFSEL3</name>
              <bitOffset>12</bitOffset>
              <bitWidth>4</bitWidth>
            </field>
            <field>
              <name>AFSEL4</name>
              <bitOffset>16</bitOffset>
              <bitWidth>4</bitWidth>
            </field>
            <field>
              <name>AFSEL5</name>
              <bitOffset>20</bitOffset>
              <bitWidth>4</bitWidth>
            </field>
            <field>
              <name>AFSEL6</name>
              <bitOffset>24</bitOffset>
              <bitWidth>4</bitWidth>
            </field>
            <field>
              <name>AFSEL7</name>
              <bitOffset>28</bitOffset>
              <bitWidth>4</bitWidth>
            </field>
          </fields>
        </register>
        <register>
          <name>AFR.1</name>
          <addressOffset>0x24</addressOffset>
          <size>0x20</size>
          <fields>
            <field>
              <name>AFSEL8</name>
              <bitOffset>0</bitOffset>
              <bitWidth>4</bitWidth>
            </field>
            <field>
              <name>AFSEL9</name>
              <bitOffset>4</bitOffset>
              <bitWidth>4</bitWidth>
            </field>
            <field>
              <name>AFSEL10</name>
              <bitOffset>8</bitOffset>
              <bitWidth>4</bitWidth>
            </field>
            <field>
              <name>AFSEL11</name>
              <bitOffset>12</bitOffset>
              <bitWidth>4</bitWidth>
            </field>
            <field>
              <name>AFSEL12</name>
              <bitOffset>16</bitOffset>
              <bitWidth>4</bitWidth>
            </field>
            <field>
              <name>AFSEL13</name>
              <bitOffset>20</bitOffset>
              <bitWidth>4</bitWidth>
            </field>
            <field>
              <name>AFSEL14</name>
              <bitOffset>24</bitOffset>
              <bitWidth>4</bitWidth>
            </field>
            <field>
              <name>AFSEL15</name>
              <bitOffset>28</bitOffset>
              <bitWidth>4</bitWidth>
            </field>
          </fields>
        </register>
      </registers>
    </peripheral>
    <peripheral>
      <name>GPIOF</name>
      <baseAddress>0x58021400</baseAddress>
      <registers>
        <register>
          <name>MODER</name>
          <addressOffset>0x0</addressOffset>
          <size>0x20</size>
          <fields>
            <field>
              <name>MODE0</name>
              <bitOffset>0</bitOffset>
              <bitWidth>2</bitWidth>
            </field>
            <field>
              <name>MODE1</name>
              <bitOffset>2</bitOffset>
              <bitWidth>2</bitWidth>
            </field>
            <field>
              <name>MODE2</name>
              <bitOffset>4</bitOffset>
              <bitWidth>2</bitWidth>
            </field>
            <field>
              <name>MODE3</name>
              <bitOffset>6</bitOffset>
              <bitWidth>2</bitWidth>
            </field>
            <field>
              <name>MODE4</name>
              <bitOffset>8</bitOffset>
              <bitWidth>2</bitWidth>
            </field>
            <field>
              <name>MODE5</name>
              <bitOffset>10</bitOffset>
              <bitWidth>2</bitWidth>
            </field>
            <field>
              <name>MODE6</name>
              <bitOffset>12</bitOffset>
              <bitWidth>2</bitWidth>
            </field>
            <field>
              <name>MODE7</name>
              <bitOffset>14</bitOffset>
              <bitWidth>2</bitWidth>
            </field>
            <field>
              <name>MODE8</name>
              <bitOffset>16</bitOffset>
              <bitWidth>2</bitWidth>
            </field>
            <field>
              <name>MODE9</name>
              <bitOffset>18</bitOffset>
              <bitWidth>2</bitWidth>
            </field>
            <field>
              <name>MODE10</name>
              <bitOffset>20</bitOffset>
              <bitWidth>2</bitWidth>
            </field>
            <field>
              <name>MODE11</name>
              <bitOffset>22</bitOffset>
              <bitWidth>2</bitWidth>
            </field>
            <field>
              <name>MODE12</name>
              <bitOffset>24</bitOffset>
              <bitWidth>2</bitWidth>
            </field>
            <field>
              <name>MODE13</name>
              <bitOffset>26</bitOffset>
              <bitWidth>2</bitWidth>
            </field>
            <field>
              <name>MODE14</name>
              <bitOffset>28</bitOffset>
              <bitWidth>2</bitWidth>
            </field>
            <field>
              <name>MODE15</name>
              <bitOffset>30</bitOffset>
              <bitWidth>2</bitWidth>
            </field>
          </fields>
        </register>
        <register>
          <name>OTYPER</name>
          <addressOffset>0x4</addressOffset>
          <size>0x20</size>
          <fields>
            <field>
              <name>OT0</name>
              <bitOffset>0</bitOffset>
              <bitWidth>1</bitWidth>
            </field>
            <field>
              <name>OT1</name>
              <bitOffset>1</bitOffset>
              <bitWidth>1</bitWidth>
            </field>
            <field>
              <name>OT2</name>
              <bitOffset>2</bitOffset>
              <bitWidth>1</bitWidth>
            </field>
            <field>
              <name>OT3</name>
              <bitOffset>3</bitOffset>
              <bitWidth>1</bitWidth>
            </field>
            <field>
              <name>OT4</name>
              <bitOffset>4</bitOffset>
              <bitWidth>1</bitWidth>
            </field>
            <field>
              <name>OT5</name>
              <bitOffset>5</bitOffset>
              <bitWidth>1</bitWidth>
            </field>
            <field>
              <name>OT6</name>
              <bitOffset>6</bitOffset>
              <bitWidth>1</bitWidth>
            </field>
            <field>
              <name>OT7</name>
              <bitOffset>7</bitOffset>
              <bitWidth>1</bitWidth>
            </field>
            <field>
              <name>OT8</name>
              <bitOffset>8</bitOffset>
              <bitWidth>1</bitWidth>
            </field>
            <field>
              <name>OT9</name>
              <bitOffset>9</bitOffset>
              <bitWidth>1</bitWidth>
            </field>
            <field>
              <name>OT10</name>
              <bitOffset>10</bitOffset>
              <bitWidth>1</bitWidth>
            </field>
            <field>
              <name>OT11</name>
              <bitOffset>11</bitOffset>
              <bitWidth>1</bitWidth>
            </field>
            <field>
              <name>OT12</name>
              <bitOffset>12</bitOffset>
              <bitWidth>1</bitWidth>
            </field>
            <field>
              <name>OT13</name>
              <bitOffset>13</bitOffset>
              <bitWidth>1</bitWidth>
            </field>
            <field>
              <name>OT14</name>
              <bitOffset>14</bitOffset>
              <bitWidth>1</bitWidth>
            </field>
            <field>
              <name>OT15</name>
              <bitOffset>15</bitOffset>
              <bitWidth>1</bitWidth>
            </field>
          </fields>
        </register>
        <register>
          <name>OSPEEDR</name>
          <addressOffset>0x8</addressOffset>
          <size>0x20</size>
          <fields>
            <field>
              <name>OSPEED0</name>
              <bitOffset>0</bitOffset>
              <bitWidth>2</bitWidth>
            </field>
            <field>
              <name>OSPEED1</name>
              <bitOffset>2</bitOffset>
              <bitWidth>2</bitWidth>
            </field>
            <field>
              <name>OSPEED2</name>
              <bitOffset>4</bitOffset>
              <bitWidth>2</bitWidth>
            </field>
            <field>
              <name>OSPEED3</name>
              <bitOffset>6</bitOffset>
              <bitWidth>2</bitWidth>
            </field>
            <field>
              <name>OSPEED4</name>
              <bitOffset>8</bitOffset>
              <bitWidth>2</bitWidth>
            </field>
            <field>
              <name>OSPEED5</name>
              <bitOffset>10</bitOffset>
              <bitWidth>2</bitWidth>
            </field>
            <field>
              <name>OSPEED6</name>
              <bitOffset>12</bitOffset>
              <bitWidth>2</bitWidth>
            </field>
            <field>
              <name>OSPEED7</name>
              <bitOffset>14</bitOffset>
              <bitWidth>2</bitWidth>
            </field>
            <field>
              <name>OSPEED8</name>
              <bitOffset>16</bitOffset>
              <bitWidth>2</bitWidth>
            </field>
            <field>
              <name>OSPEED9</name>
              <bitOffset>18</bitOffset>
              <bitWidth>2</bitWidth>
            </field>
            <field>
              <name>OSPEED10</name>
              <bitOffset>20</bitOffset>
              <bitWidth>2</bitWidth>
            </field>
            <field>
              <name>OSPEED11</name>
              <bitOffset>22</bitOffset>
              <bitWidth>2</bitWidth>
            </field>
            <field>
              <name>OSPEED12</name>
              <bitOffset>24</bitOffset>
              <bitWidth>2</bitWidth>
            </field>
            <field>
              <name>OSPEED13</name>
              <bitOffset>26</bitOffset>
              <bitWidth>2</bitWidth>
            </field>
            <field>
              <name>OSPEED14</name>
              <bitOffset>28</bitOffset>
              <bitWidth>2</bitWidth>
            </field>
            <field>
              <name>OSPEED15</name>
              <bitOffset>30</bitOffset>
              <bitWidth>2</bitWidth>
            </field>
          </fields>
        </register>
        <register>
          <name>PUPDR</name>
          <addressOffset>0xc</addressOffset>
          <size>0x20</size>
          <fields>
            <field>
              <name>PUPD0</name>
              <bitOffset>0</bitOffset>
              <bitWidth>2</bitWidth>
            </field>
            <field>
              <name>PUPD1</name>
              <bitOffset>2</bitOffset>
              <bitWidth>2</bitWidth>
            </field>
            <field>
              <name>PUPD2</name>
              <bitOffset>4</bitOffset>
              <bitWidth>2</bitWidth>
            </field>
            <field>
              <name>PUPD3</name>
              <bitOffset>6</bitOffset>
              <bitWidth>2</bitWidth>
            </field>
            <field>
              <name>PUPD4</name>
              <bitOffset>8</bitOffset>
              <bitWidth>2</bitWidth>
            </field>
            <field>
              <name>PUPD5</name>
              <bitOffset>10</bitOffset>
              <bitWidth>2</bitWidth>
            </field>
            <field>
              <name>PUPD6</name>
              <bitOffset>12</bitOffset>
              <bitWidth>2</bitWidth>
            </field>
            <field>
              <name>PUPD7</name>
              <bitOffset>14</bitOffset>
              <bitWidth>2</bitWidth>
            </field>
            <field>
              <name>PUPD8</name>
              <bitOffset>16</bitOffset>
              <bitWidth>2</bitWidth>
            </field>
            <field>
              <name>PUPD9</name>
              <bitOffset>18</bitOffset>
              <bitWidth>2</bitWidth>
            </field>
            <field>
              <name>PUPD10</name>
              <bitOffset>20</bitOffset>
              <bitWidth>2</bitWidth>
            </field>
            <field>
              <name>PUPD11</name>
              <bitOffset>22</bitOffset>
              <bitWidth>2</bitWidth>
            </field>
            <field>
              <name>PUPD12</name>
              <bitOffset>24</bitOffset>
              <bitWidth>2</bitWidth>
            </field>
            <field>
              <name>PUPD13</name>
              <bitOffset>26</bitOffset>
              <bitWidth>2</bitWidth>
            </field>
            <field>
              <name>PUPD14</name>
              <bitOffset>28</bitOffset>
              <bitWidth>2</bitWidth>
            </field>
            <field>
              <name>PUPD15</name>
              <bitOffset>30</bitOffset>
              <bitWidth>2</bitWidth>
            </field>
          </fields>
        </register>
        <register>
          <name>IDR</name>
          <addressOffset>0x10</addressOffset>
          <size>0x20</size>
          <fields>
            <field>
              <name>ID0</name>
              <bitOffset>0</bitOffset>
              <bitWidth>1</bitWidth>
            </field>
            <field>
              <name>ID1</name>
              <bitOffset>1</bitOffset>
              <bitWidth>1</bitWidth>
            </field>
            <field>
              <name>ID2</name>
              <bitOffset>2</bitOffset>
              <bitWidth>1</bitWidth>
            </field>
            <field>
              <name>ID3</name>
              <bitOffset>3</bitOffset>
              <bitWidth>1</bitWidth>
            </field>
            <field>
              <name>ID4</name>
              <bitOffset>4</bitOffset>
              <bitWidth>1</bitWidth>
            </field>
            <field>
              <name>ID5</name>
              <bitOffset>5</bitOffset>
              <bitWidth>1</bitWidth>
            </field>
            <field>
              <name>ID6</name>
              <bitOffset>6</bitOffset>
              <bitWidth>1</bitWidth>
            </field>
            <field>
              <name>ID7</name>
              <bitOffset>7</bitOffset>
              <bitWidth>1</bitWidth>
            </field>
            <field>
              <name>ID8</name>
              <bitOffset>8</bitOffset>
              <bitWidth>1</bitWidth>
            </field>
            <field>
              <name>ID9</name>
              <bitOffset>9</bitOffset>
              <bitWidth>1</bitWidth>
            </field>
            <field>
              <name>ID10</name>
              <bitOffset>10</bitOffset>
              <bitWidth>1</bitWidth>
            </field>
            <field>
              <name>ID11</name>
              <bitOffset>11</bitOffset>
              <bitWidth>1</bitWidth>
            </field>
            <field>
              <name>ID12</name>
              <bitOffset>12</bitOffset>
              <bitWidth>1</bitWidth>
            </field>
            <field>
              <name>ID13</name>
              <bitOffset>13</bitOffset>
              <bitWidth>1</bitWidth>
            </field>
            <field>
              <name>ID14</name>
              <bitOffset>14</bitOffset>
              <bitWidth>1</bitWidth>
            </field>
            <field>
              <name>ID15</name>
              <bitOffset>15</bitOffset>
              <bitWidth>1</bitWidth>
            </field>
          </fields>
        </register>
        <register>
          <name>ODR</name>
          <addressOffset>0x14</addressOffset>
          <size>0x20</size>
          <fields>
            <field>
              <name>OD0</name>
              <bitOffset>0</bitOffset>
              <bitWidth>1</bitWidth>
            </field>
            <field>
              <name>OD1</name>
              <bitOffset>1</bitOffset>
              <bitWidth>1</bitWidth>
            </field>
            <field>
              <name>OD2</name>
              <bitOffset>2</bitOffset>
              <bitWidth>1</bitWidth>
            </field>
            <field>
              <name>OD3</name>
              <bitOffset>3</bitOffset>
              <bitWidth>1</bitWidth>
            </field>
            <field>
              <name>OD4</name>
              <bitOffset>4</bitOffset>
              <bitWidth>1</bitWidth>
            </field>
            <field>
              <name>OD5</name>
              <bitOffset>5</bitOffset>
              <bitWidth>1</bitWidth>
            </field>
            <field>
              <name>OD6</name>
              <bitOffset>6</bitOffset>
              <bitWidth>1</bitWidth>
            </field>
            <field>
              <name>OD7</name>
              <bitOffset>7</bitOffset>
              <bitWidth>1</bitWidth>
            </field>
            <field>
              <name>OD8</name>
              <bitOffset>8</bitOffset>
              <bitWidth>1</bitWidth>
            </field>
            <field>
              <name>OD9</name>
              <bitOffset>9</bitOffset>
              <bitWidth>1</bitWidth>
            </field>
            <field>
              <name>OD10</name>
              <bitOffset>10</bitOffset>
              <bitWidth>1</bitWidth>
            </field>
            <field>
              <name>OD11</name>
              <bitOffset>11</bitOffset>
              <bitWidth>1</bitWidth>
            </field>
            <field>
              <name>OD12</name>
              <bitOffset>12</bitOffset>
              <bitWidth>1</bitWidth>
            </field>
            <field>
              <name>OD13</name>
              <bitOffset>13</bitOffset>
              <bitWidth>1</bitWidth>
            </field>
            <field>
              <name>OD14</name>
              <bitOffset>14</bitOffset>
              <bitWidth>1</bitWidth>
            </field>
            <field>
              <name>OD15</name>
              <bitOffset>15</bitOffset>
              <bitWidth>1</bitWidth>
            </field>
          </fields>
        </register>
        <register>
          <name>BSRR</name>
          <addressOffset>0x18</addressOffset>
          <size>0x20</size>
          <fields>
            <field>
              <name>BS0</name>
              <bitOffset>0</bitOffset>
              <bitWidth>1</bitWidth>
            </field>
            <field>
              <name>BS1</name>
              <bitOffset>1</bitOffset>
              <bitWidth>1</bitWidth>
            </field>
            <field>
              <name>BS2</name>
              <bitOffset>2</bitOffset>
              <bitWidth>1</bitWidth>
            </field>
            <field>
              <name>BS3</name>
              <bitOffset>3</bitOffset>
              <bitWidth>1</bitWidth>
            </field>
            <field>
              <name>BS4</name>
              <bitOffset>4</bitOffset>
              <bitWidth>1</bitWidth>
            </field>
            <field>
              <name>BS5</name>
              <bitOffset>5</bitOffset>
              <bitWidth>1</bitWidth>
            </field>
            <field>
              <name>BS6</name>
              <bitOffset>6</bitOffset>
              <bitWidth>1</bitWidth>
            </field>
            <field>
              <name>BS7</name>
              <bitOffset>7</bitOffset>
              <bitWidth>1</bitWidth>
            </field>
            <field>
              <name>BS8</name>
              <bitOffset>8</bitOffset>
              <bitWidth>1</bitWidth>
            </field>
            <field>
              <name>BS9</name>
              <bitOffset>9</bitOffset>
              <bitWidth>1</bitWidth>
            </field>
            <field>
              <name>BS10</name>
              <bitOffset>10</bitOffset>
              <bitWidth>1</bitWidth>
            </field>
            <field>
              <name>BS11</name>
              <bitOffset>11</bitOffset>
              <bitWidth>1</bitWidth>
            </field>
            <field>
              <name>BS12</name>
              <bitOffset>12</bitOffset>
              <bitWidth>1</bitWidth>
            </field>
            <field>
              <name>BS13</name>
              <bitOffset>13</bitOffset>
              <bitWidth>1</bitWidth>
            </field>
            <field>
              <name>BS14</name>
              <bitOffset>14</bitOffset>
              <bitWidth>1</bitWidth>
            </field>
            <field>
              <name>BS15</name>
              <bitOffset>15</bitOffset>
              <bitWidth>1</bitWidth>
            </field>
            <field>
              <name>BR0</name>
              <bitOffset>16</bitOffset>
              <bitWidth>1</bitWidth>
            </field>
            <field>
              <name>BR1</name>
              <bitOffset>17</bitOffset>
              <bitWidth>1</bitWidth>
            </field>
            <field>
              <name>BR2</name>
              <bitOffset>18</bitOffset>
              <bitWidth>1</bitWidth>
            </field>
            <field>
              <name>BR3</name>
              <bitOffset>19</bitOffset>
              <bitWidth>1</bitWidth>
            </field>
            <field>
              <name>BR4</name>
              <bitOffset>20</bitOffset>
              <bitWidth>1</bitWidth>
            </field>
            <field>
              <name>BR5</name>
              <bitOffset>21</bitOffset>
              <bitWidth>1</bitWidth>
            </field>
            <field>
              <name>BR6</name>
              <bitOffset>22</bitOffset>
              <bitWidth>1</bitWidth>
            </field>
            <field>
              <name>BR7</name>
              <bitOffset>23</bitOffset>
              <bitWidth>1</bitWidth>
            </field>
            <field>
              <name>BR8</name>
              <bitOffset>24</bitOffset>
              <bitWidth>1</bitWidth>
            </field>
            <field>
              <name>BR9</name>
              <bitOffset>25</bitOffset>
              <bitWidth>1</bitWidth>
            </field>
            <field>
              <name>BR10</name>
              <bitOffset>26</bitOffset>
              <bitWidth>1</bitWidth>
            </field>
            <field>
              <name>BR11</name>
              <bitOffset>27</bitOffset>
              <bitWidth>1</bitWidth>
            </field>
            <field>
              <name>BR12</name>
              <bitOffset>28</bitOffset>
              <bitWidth>1</bitWidth>
            </field>
            <field>
              <name>BR13</name>
              <bitOffset>29</bitOffset>
              <bitWidth>1</bitWidth>
            </field>
            <field>
              <name>BR14</name>
              <bitOffset>30</bitOffset>
              <bitWidth>1</bitWidth>
            </field>
            <field>
              <name>BR15</name>
              <bitOffset>31</bitOffset>
              <bitWidth>1</bitWidth>
            </field>
          </fields>
        </register>
        <register>
          <name>LCKR</name>
          <addressOffset>0x1c</addressOffset>
          <size>0x20</size>
          <fields>
            <field>
              <name>LCK0</name>
              <bitOffset>0</bitOffset>
              <bitWidth>1</bitWidth>
            </field>
            <field>
              <name>LCK1</name>
              <bitOffset>1</bitOffset>
              <bitWidth>1</bitWidth>
            </field>
            <field>
              <name>LCK2</name>
              <bitOffset>2</bitOffset>
              <bitWidth>1</bitWidth>
            </field>
            <field>
              <name>LCK3</name>
              <bitOffset>3</bitOffset>
              <bitWidth>1</bitWidth>
            </field>
            <field>
              <name>LCK4</name>
              <bitOffset>4</bitOffset>
              <bitWidth>1</bitWidth>
            </field>
            <field>
              <name>LCK5</name>
              <bitOffset>5</bitOffset>
              <bitWidth>1</bitWidth>
            </field>
            <field>
              <name>LCK6</name>
              <bitOffset>6</bitOffset>
              <bitWidth>1</bitWidth>
            </field>
            <field>
              <name>LCK7</name>
              <bitOffset>7</bitOffset>
              <bitWidth>1</bitWidth>
            </field>
            <field>
              <name>LCK8</name>
              <bitOffset>8</bitOffset>
              <bitWidth>1</bitWidth>
            </field>
            <field>
              <name>LCK9</name>
              <bitOffset>9</bitOffset>
              <bitWidth>1</bitWidth>
            </field>
            <field>
              <name>LCK10</name>
              <bitOffset>10</bitOffset>
              <bitWidth>1</bitWidth>
            </field>
            <field>
              <name>LCK11</name>
              <bitOffset>11</bitOffset>
              <bitWidth>1</bitWidth>
            </field>
            <field>
              <name>LCK12</name>
              <bitOffset>12</bitOffset>
              <bitWidth>1</bitWidth>
            </field>
            <field>
              <name>LCK13</name>
              <bitOffset>13</bitOffset>
              <bitWidth>1</bitWidth>
            </field>
            <field>
              <name>LCK14</name>
              <bitOffset>14</bitOffset>
              <bitWidth>1</bitWidth>
            </field>
            <field>
              <name>LCK15</name>
              <bitOffset>15</bitOffset>
              <bitWidth>1</bitWidth>
            </field>
            <field>
              <name>LCKK</name>
              <bitOffset>16</bitOffset>
              <bitWidth>1</bitWidth>
            </field>
          </fields>
        </register>
        <register>
          <name>AFR.0</name>
          <addressOffset>0x20</addressOffset>
          <size>0x20</size>
          <fields>
            <field>
              <name>AFSEL0</name>
              <bitOffset>0</bitOffset>
              <bitWidth>4</bitWidth>
            </field>
            <field>
              <name>AFSEL1</name>
              <bitOffset>4</bitOffset>
              <bitWidth>4</bitWidth>
            </field>
            <field>
              <name>AFSEL2</name>
              <bitOffset>8</bitOffset>
              <bitWidth>4</bitWidth>
            </field>
            <field>
              <name>AFSEL3</name>
              <bitOffset>12</bitOffset>
              <bitWidth>4</bitWidth>
            </field>
            <field>
              <name>AFSEL4</name>
              <bitOffset>16</bitOffset>
              <bitWidth>4</bitWidth>
            </field>
            <field>
              <name>AFSEL5</name>
              <bitOffset>20</bitOffset>
              <bitWidth>4</bitWidth>
            </field>
            <field>
              <name>AFSEL6</name>
              <bitOffset>24</bitOffset>
              <bitWidth>4</bitWidth>
            </field>
            <field>
              <name>AFSEL7</name>
              <bitOffset>28</bitOffset>
              <bitWidth>4</bitWidth>
            </field>
          </fields>
        </register>
        <register>
          <name>AFR.1</name>
          <addressOffset>0x24</addressOffset>
          <size>0x20</size>
          <fields>
            <field>
              <name>AFSEL8</name>
              <bitOffset>0</bitOffset>
              <bitWidth>4</bitWidth>
            </field>
            <field>
              <name>AFSEL9</name>
              <bitOffset>4</bitOffset>
              <bitWidth>4</bitWidth>
            </field>
            <field>
              <name>AFSEL10</name>
              <bitOffset>8</bitOffset>
              <bitWidth>4</bitWidth>
            </field>
            <field>
              <name>AFSEL11</name>
              <bitOffset>12</bitOffset>
              <bitWidth>4</bitWidth>
            </field>
            <field>
              <name>AFSEL12</name>
              <bitOffset>16</bitOffset>
              <bitWidth>4</bitWidth>
            </field>
            <field>
              <name>AFSEL13</name>
              <bitOffset>20</bitOffset>
              <bitWidth>4</bitWidth>
            </field>
            <field>
              <name>AFSEL14</name>
              <bitOffset>24</bitOffset>
              <bitWidth>4</bitWidth>
            </field>
            <field>
              <name>AFSEL15</name>
              <bitOffset>28</bitOffset>
              <bitWidth>4</bitWidth>
            </field>
          </fields>
        </register>
      </registers>
    </peripheral>
    <peripheral>
      <name>GPIOG</name>
      <baseAddress>0x58021800</baseAddress>
      <registers>
        <register>
          <name>MODER</name>
          <addressOffset>0x0</addressOffset>
          <size>0x20</size>
          <fields>
            <field>
              <name>MODE0</name>
              <bitOffset>0</bitOffset>
              <bitWidth>2</bitWidth>
            </field>
            <field>
              <name>MODE1</name>
              <bitOffset>2</bitOffset>
              <bitWidth>2</bitWidth>
            </field>
            <field>
              <name>MODE2</name>
              <bitOffset>4</bitOffset>
              <bitWidth>2</bitWidth>
            </field>
            <field>
              <name>MODE3</name>
              <bitOffset>6</bitOffset>
              <bitWidth>2</bitWidth>
            </field>
            <field>
              <name>MODE4</name>
              <bitOffset>8</bitOffset>
              <bitWidth>2</bitWidth>
            </field>
            <field>
              <name>MODE5</name>
              <bitOffset>10</bitOffset>
              <bitWidth>2</bitWidth>
            </field>
            <field>
              <name>MODE6</name>
              <bitOffset>12</bitOffset>
              <bitWidth>2</bitWidth>
            </field>
            <field>
              <name>MODE7</name>
              <bitOffset>14</bitOffset>
              <bitWidth>2</bitWidth>
            </field>
            <field>
              <name>MODE8</name>
              <bitOffset>16</bitOffset>
              <bitWidth>2</bitWidth>
            </field>
            <field>
              <name>MODE9</name>
              <bitOffset>18</bitOffset>
              <bitWidth>2</bitWidth>
            </field>
            <field>
              <name>MODE10</name>
              <bitOffset>20</bitOffset>
              <bitWidth>2</bitWidth>
            </field>
            <field>
              <name>MODE11</name>
              <bitOffset>22</bitOffset>
              <bitWidth>2</bitWidth>
            </field>
            <field>
              <name>MODE12</name>
              <bitOffset>24</bitOffset>
              <bitWidth>2</bitWidth>
            </field>
            <field>
              <name>MODE13</name>
              <bitOffset>26</bitOffset>
              <bitWidth>2</bitWidth>
            </field>
            <field>
              <name>MODE14</name>
              <bitOffset>28</bitOffset>
              <bitWidth>2</bitWidth>
            </field>
            <field>
              <name>MODE15</name>
              <bitOffset>30</bitOffset>
              <bitWidth>2</bitWidth>
            </field>
          </fields>
        </register>
        <register>
          <name>OTYPER</name>
          <addressOffset>0x4</addressOffset>
          <size>0x20</size>
          <fields>
            <field>
              <name>OT0</name>
              <bitOffset>0</bitOffset>
              <bitWidth>1</bitWidth>
            </field>
            <field>
              <name>OT1</name>
              <bitOffset>1</bitOffset>
              <bitWidth>1</bitWidth>
            </field>
            <field>
              <name>OT2</name>
              <bitOffset>2</bitOffset>
              <bitWidth>1</bitWidth>
            </field>
            <field>
              <name>OT3</name>
              <bitOffset>3</bitOffset>
              <bitWidth>1</bitWidth>
            </field>
            <field>
              <name>OT4</name>
              <bitOffset>4</bitOffset>
              <bitWidth>1</bitWidth>
            </field>
            <field>
              <name>OT5</name>
              <bitOffset>5</bitOffset>
              <bitWidth>1</bitWidth>
            </field>
            <field>
              <name>OT6</name>
              <bitOffset>6</bitOffset>
              <bitWidth>1</bitWidth>
            </field>
            <field>
              <name>OT7</name>
              <bitOffset>7</bitOffset>
              <bitWidth>1</bitWidth>
            </field>
            <field>
              <name>OT8</name>
              <bitOffset>8</bitOffset>
              <bitWidth>1</bitWidth>
            </field>
            <field>
              <name>OT9</name>
              <bitOffset>9</bitOffset>
              <bitWidth>1</bitWidth>
            </field>
            <field>
              <name>OT10</name>
              <bitOffset>10</bitOffset>
              <bitWidth>1</bitWidth>
            </field>
            <field>
              <name>OT11</name>
              <bitOffset>11</bitOffset>
              <bitWidth>1</bitWidth>
            </field>
            <field>
              <name>OT12</name>
              <bitOffset>12</bitOffset>
              <bitWidth>1</bitWidth>
            </field>
            <field>
              <name>OT13</name>
              <bitOffset>13</bitOffset>
              <bitWidth>1</bitWidth>
            </field>
            <field>
              <name>OT14</name>
              <bitOffset>14</bitOffset>
              <bitWidth>1</bitWidth>
            </field>
            <field>
              <name>OT15</name>
              <bitOffset>15</bitOffset>
              <bitWidth>1</bitWidth>
            </field>
          </fields>
        </register>
        <register>
          <name>OSPEEDR</name>
          <addressOffset>0x8</addressOffset>
          <size>0x20</size>
          <fields>
            <field>
              <name>OSPEED0</name>
              <bitOffset>0</bitOffset>
              <bitWidth>2</bitWidth>
            </field>
            <field>
              <name>OSPEED1</name>
              <bitOffset>2</bitOffset>
              <bitWidth>2</bitWidth>
            </field>
            <field>
              <name>OSPEED2</name>
              <bitOffset>4</bitOffset>
              <bitWidth>2</bitWidth>
            </field>
            <field>
              <name>OSPEED3</name>
              <bitOffset>6</bitOffset>
              <bitWidth>2</bitWidth>
            </field>
            <field>
              <name>OSPEED4</name>
              <bitOffset>8</bitOffset>
              <bitWidth>2</bitWidth>
            </field>
            <field>
              <name>OSPEED5</name>
              <bitOffset>10</bitOffset>
              <bitWidth>2</bitWidth>
            </field>
            <field>
              <name>OSPEED6</name>
              <bitOffset>12</bitOffset>
              <bitWidth>2</bitWidth>
            </field>
            <field>
              <name>OSPEED7</name>
              <bitOffset>14</bitOffset>
              <bitWidth>2</bitWidth>
            </field>
            <field>
              <name>OSPEED8</name>
              <bitOffset>16</bitOffset>
              <bitWidth>2</bitWidth>
            </field>
            <field>
              <name>OSPEED9</name>
              <bitOffset>18</bitOffset>
              <bitWidth>2</bitWidth>
            </field>
            <field>
              <name>OSPEED10</name>
              <bitOffset>20</bitOffset>
              <bitWidth>2</bitWidth>
            </field>
            <field>
              <name>OSPEED11</name>
              <bitOffset>22</bitOffset>
              <bitWidth>2</bitWidth>
            </field>
            <field>
              <name>OSPEED12</name>
              <bitOffset>24</bitOffset>
              <bitWidth>2</bitWidth>
            </field>
            <field>
              <name>OSPEED13</name>
              <bitOffset>26</bitOffset>
              <bitWidth>2</bitWidth>
            </field>
            <field>
              <name>OSPEED14</name>
              <bitOffset>28</bitOffset>
              <bitWidth>2</bitWidth>
            </field>
            <field>
              <name>OSPEED15</name>
              <bitOffset>30</bitOffset>
              <bitWidth>2</bitWidth>
            </field>
          </fields>
        </register>
        <register>
          <name>PUPDR</name>
          <addressOffset>0xc</addressOffset>
          <size>0x20</size>
          <fields>
            <field>
              <name>PUPD0</name>
              <bitOffset>0</bitOffset>
              <bitWidth>2</bitWidth>
            </field>
            <field>
              <name>PUPD1</name>
              <bitOffset>2</bitOffset>
              <bitWidth>2</bitWidth>
            </field>
            <field>
              <name>PUPD2</name>
              <bitOffset>4</bitOffset>
              <bitWidth>2</bitWidth>
            </field>
            <field>
              <name>PUPD3</name>
              <bitOffset>6</bitOffset>
              <bitWidth>2</bitWidth>
            </field>
            <field>
              <name>PUPD4</name>
              <bitOffset>8</bitOffset>
              <bitWidth>2</bitWidth>
            </field>
            <field>
              <name>PUPD5</name>
              <bitOffset>10</bitOffset>
              <bitWidth>2</bitWidth>
            </field>
            <field>
              <name>PUPD6</name>
              <bitOffset>12</bitOffset>
              <bitWidth>2</bitWidth>
            </field>
            <field>
              <name>PUPD7</name>
              <bitOffset>14</bitOffset>
              <bitWidth>2</bitWidth>
            </field>
            <field>
              <name>PUPD8</name>
              <bitOffset>16</bitOffset>
              <bitWidth>2</bitWidth>
            </field>
            <field>
              <name>PUPD9</name>
              <bitOffset>18</bitOffset>
              <bitWidth>2</bitWidth>
            </field>
            <field>
              <name>PUPD10</name>
              <bitOffset>20</bitOffset>
              <bitWidth>2</bitWidth>
            </field>
            <field>
              <name>PUPD11</name>
              <bitOffset>22</bitOffset>
              <bitWidth>2</bitWidth>
            </field>
            <field>
              <name>PUPD12</name>
              <bitOffset>24</bitOffset>
              <bitWidth>2</bitWidth>
            </field>
            <field>
              <name>PUPD13</name>
              <bitOffset>26</bitOffset>
              <bitWidth>2</bitWidth>
            </field>
            <field>
              <name>PUPD14</name>
              <bitOffset>28</bitOffset>
              <bitWidth>2</bitWidth>
            </field>
            <field>
              <name>PUPD15</name>
              <bitOffset>30</bitOffset>
              <bitWidth>2</bitWidth>
            </field>
          </fields>
        </register>
        <register>
          <name>IDR</name>
          <addressOffset>0x10</addressOffset>
          <size>0x20</size>
          <fields>
            <field>
              <name>ID0</name>
              <bitOffset>0</bitOffset>
              <bitWidth>1</bitWidth>
            </field>
            <field>
              <name>ID1</name>
              <bitOffset>1</bitOffset>
              <bitWidth>1</bitWidth>
            </field>
            <field>
              <name>ID2</name>
              <bitOffset>2</bitOffset>
              <bitWidth>1</bitWidth>
            </field>
            <field>
              <name>ID3</name>
              <bitOffset>3</bitOffset>
              <bitWidth>1</bitWidth>
            </field>
            <field>
              <name>ID4</name>
              <bitOffset>4</bitOffset>
              <bitWidth>1</bitWidth>
            </field>
            <field>
              <name>ID5</name>
              <bitOffset>5</bitOffset>
              <bitWidth>1</bitWidth>
            </field>
            <field>
              <name>ID6</name>
              <bitOffset>6</bitOffset>
              <bitWidth>1</bitWidth>
            </field>
            <field>
              <name>ID7</name>
              <bitOffset>7</bitOffset>
              <bitWidth>1</bitWidth>
            </field>
            <field>
              <name>ID8</name>
              <bitOffset>8</bitOffset>
              <bitWidth>1</bitWidth>
            </field>
            <field>
              <name>ID9</name>
              <bitOffset>9</bitOffset>
              <bitWidth>1</bitWidth>
            </field>
            <field>
              <name>ID10</name>
              <bitOffset>10</bitOffset>
              <bitWidth>1</bitWidth>
            </field>
            <field>
              <name>ID11</name>
              <bitOffset>11</bitOffset>
              <bitWidth>1</bitWidth>
            </field>
            <field>
              <name>ID12</name>
              <bitOffset>12</bitOffset>
              <bitWidth>1</bitWidth>
            </field>
            <field>
              <name>ID13</name>
              <bitOffset>13</bitOffset>
              <bitWidth>1</bitWidth>
            </field>
            <field>
              <name>ID14</name>
              <bitOffset>14</bitOffset>
              <bitWidth>1</bitWidth>
            </field>
            <field>
              <name>ID15</name>
              <bitOffset>15</bitOffset>
              <bitWidth>1</bitWidth>
            </field>
          </fields>
        </register>
        <register>
          <name>ODR</name>
          <addressOffset>0x14</addressOffset>
          <size>0x20</size>
          <fields>
            <field>
              <name>OD0</name>
              <bitOffset>0</bitOffset>
              <bitWidth>1</bitWidth>
            </field>
            <field>
              <name>OD1</name>
              <bitOffset>1</bitOffset>
              <bitWidth>1</bitWidth>
            </field>
            <field>
              <name>OD2</name>
              <bitOffset>2</bitOffset>
              <bitWidth>1</bitWidth>
            </field>
            <field>
              <name>OD3</name>
              <bitOffset>3</bitOffset>
              <bitWidth>1</bitWidth>
            </field>
            <field>
              <name>OD4</name>
              <bitOffset>4</bitOffset>
              <bitWidth>1</bitWidth>
            </field>
            <field>
              <name>OD5</name>
              <bitOffset>5</bitOffset>
              <bitWidth>1</bitWidth>
            </field>
            <field>
              <name>OD6</name>
              <bitOffset>6</bitOffset>
              <bitWidth>1</bitWidth>
            </field>
            <field>
              <name>OD7</name>
              <bitOffset>7</bitOffset>
              <bitWidth>1</bitWidth>
            </field>
            <field>
              <name>OD8</name>
              <bitOffset>8</bitOffset>
              <bitWidth>1</bitWidth>
            </field>
            <field>
              <name>OD9</name>
              <bitOffset>9</bitOffset>
              <bitWidth>1</bitWidth>
            </field>
            <field>
              <name>OD10</name>
              <bitOffset>10</bitOffset>
              <bitWidth>1</bitWidth>
            </field>
            <field>
              <name>OD11</name>
              <bitOffset>11</bitOffset>
              <bitWidth>1</bitWidth>
            </field>
            <field>
              <name>OD12</name>
              <bitOffset>12</bitOffset>
              <bitWidth>1</bitWidth>
            </field>
            <field>
              <name>OD13</name>
              <bitOffset>13</bitOffset>
              <bitWidth>1</bitWidth>
            </field>
            <field>
              <name>OD14</name>
              <bitOffset>14</bitOffset>
              <bitWidth>1</bitWidth>
            </field>
            <field>
              <name>OD15</name>
              <bitOffset>15</bitOffset>
              <bitWidth>1</bitWidth>
            </field>
          </fields>
        </register>
        <register>
          <name>BSRR</name>
          <addressOffset>0x18</addressOffset>
          <size>0x20</size>
          <fields>
            <field>
              <name>BS0</name>
              <bitOffset>0</bitOffset>
              <bitWidth>1</bitWidth>
            </field>
            <field>
              <name>BS1</name>
              <bitOffset>1</bitOffset>
              <bitWidth>1</bitWidth>
            </field>
            <field>
              <name>BS2</name>
              <bitOffset>2</bitOffset>
              <bitWidth>1</bitWidth>
            </field>
            <field>
              <name>BS3</name>
              <bitOffset>3</bitOffset>
              <bitWidth>1</bitWidth>
            </field>
            <field>
              <name>BS4</name>
              <bitOffset>4</bitOffset>
              <bitWidth>1</bitWidth>
            </field>
            <field>
              <name>BS5</name>
              <bitOffset>5</bitOffset>
              <bitWidth>1</bitWidth>
            </field>
            <field>
              <name>BS6</name>
              <bitOffset>6</bitOffset>
              <bitWidth>1</bitWidth>
            </field>
            <field>
              <name>BS7</name>
              <bitOffset>7</bitOffset>
              <bitWidth>1</bitWidth>
            </field>
            <field>
              <name>BS8</name>
              <bitOffset>8</bitOffset>
              <bitWidth>1</bitWidth>
            </field>
            <field>
              <name>BS9</name>
              <bitOffset>9</bitOffset>
              <bitWidth>1</bitWidth>
            </field>
            <field>
              <name>BS10</name>
              <bitOffset>10</bitOffset>
              <bitWidth>1</bitWidth>
            </field>
            <field>
              <name>BS11</name>
              <bitOffset>11</bitOffset>
              <bitWidth>1</bitWidth>
            </field>
            <field>
              <name>BS12</name>
              <bitOffset>12</bitOffset>
              <bitWidth>1</bitWidth>
            </field>
            <field>
              <name>BS13</name>
              <bitOffset>13</bitOffset>
              <bitWidth>1</bitWidth>
            </field>
            <field>
              <name>BS14</name>
              <bitOffset>14</bitOffset>
              <bitWidth>1</bitWidth>
            </field>
            <field>
              <name>BS15</name>
              <bitOffset>15</bitOffset>
              <bitWidth>1</bitWidth>
            </field>
            <field>
              <name>BR0</name>
              <bitOffset>16</bitOffset>
              <bitWidth>1</bitWidth>
            </field>
            <field>
              <name>BR1</name>
              <bitOffset>17</bitOffset>
              <bitWidth>1</bitWidth>
            </field>
            <field>
              <name>BR2</name>
              <bitOffset>18</bitOffset>
              <bitWidth>1</bitWidth>
            </field>
            <field>
              <name>BR3</name>
              <bitOffset>19</bitOffset>
              <bitWidth>1</bitWidth>
            </field>
            <field>
              <name>BR4</name>
              <bitOffset>20</bitOffset>
              <bitWidth>1</bitWidth>
            </field>
            <field>
              <name>BR5</name>
              <bitOffset>21</bitOffset>
              <bitWidth>1</bitWidth>
            </field>
            <field>
              <name>BR6</name>
              <bitOffset>22</bitOffset>
              <bitWidth>1</bitWidth>
            </field>
            <field>
              <name>BR7</name>
              <bitOffset>23</bitOffset>
              <bitWidth>1</bitWidth>
            </field>
            <field>
              <name>BR8</name>
              <bitOffset>24</bitOffset>
              <bitWidth>1</bitWidth>
            </field>
            <field>
              <name>BR9</name>
              <bitOffset>25</bitOffset>
              <bitWidth>1</bitWidth>
            </field>
            <field>
              <name>BR10</name>
              <bitOffset>26</bitOffset>
              <bitWidth>1</bitWidth>
            </field>
            <field>
              <name>BR11</name>
              <bitOffset>27</bitOffset>
              <bitWidth>1</bitWidth>
            </field>
            <field>
              <name>BR12</name>
              <bitOffset>28</bitOffset>
              <bitWidth>1</bitWidth>
            </field>
            <field>
              <name>BR13</name>
              <bitOffset>29</bitOffset>
              <bitWidth>1</bitWidth>
            </field>
            <field>
              <name>BR14</name>
              <bitOffset>30</bitOffset>
              <bitWidth>1</bitWidth>
            </field>
            <field>
              <name>BR15</name>
              <bitOffset>31</bitOffset>
              <bitWidth>1</bitWidth>
            </field>
          </fields>
        </register>
        <register>
          <name>LCKR</name>
          <addressOffset>0x1c</addressOffset>
          <size>0x20</size>
          <fields>
            <field>
              <name>LCK0</name>
              <bitOffset>0</bitOffset>
              <bitWidth>1</bitWidth>
            </field>
            <field>
              <name>LCK1</name>
              <bitOffset>1</bitOffset>
              <bitWidth>1</bitWidth>
            </field>
            <field>
              <name>LCK2</name>
              <bitOffset>2</bitOffset>
              <bitWidth>1</bitWidth>
            </field>
            <field>
              <name>LCK3</name>
              <bitOffset>3</bitOffset>
              <bitWidth>1</bitWidth>
            </field>
            <field>
              <name>LCK4</name>
              <bitOffset>4</bitOffset>
              <bitWidth>1</bitWidth>
            </field>
            <field>
              <name>LCK5</name>
              <bitOffset>5</bitOffset>
              <bitWidth>1</bitWidth>
            </field>
            <field>
              <name>LCK6</name>
              <bitOffset>6</bitOffset>
              <bitWidth>1</bitWidth>
            </field>
            <field>
              <name>LCK7</name>
              <bitOffset>7</bitOffset>
              <bitWidth>1</bitWidth>
            </field>
            <field>
              <name>LCK8</name>
              <bitOffset>8</bitOffset>
              <bitWidth>1</bitWidth>
            </field>
            <field>
              <name>LCK9</name>
              <bitOffset>9</bitOffset>
              <bitWidth>1</bitWidth>
            </field>
            <field>
              <name>LCK10</name>
              <bitOffset>10</bitOffset>
              <bitWidth>1</bitWidth>
            </field>
            <field>
              <name>LCK11</name>
              <bitOffset>11</bitOffset>
              <bitWidth>1</bitWidth>
            </field>
            <field>
              <name>LCK12</name>
              <bitOffset>12</bitOffset>
              <bitWidth>1</bitWidth>
            </field>
            <field>
              <name>LCK13</name>
              <bitOffset>13</bitOffset>
              <bitWidth>1</bitWidth>
            </field>
            <field>
              <name>LCK14</name>
              <bitOffset>14</bitOffset>
              <bitWidth>1</bitWidth>
            </field>
            <field>
              <name>LCK15</name>
              <bitOffset>15</bitOffset>
              <bitWidth>1</bitWidth>
            </field>
            <field>
              <name>LCKK</name>
              <bitOffset>16</bitOffset>
              <bitWidth>1</bitWidth>
            </field>
          </fields>
        </register>
        <register>
          <name>AFR.0</name>
          <addressOffset>0x20</addressOffset>
          <size>0x20</size>
          <fields>
            <field>
              <name>AFSEL0</name>
              <bitOffset>0</bitOffset>
              <bitWidth>4</bitWidth>
            </field>
            <field>
              <name>AFSEL1</name>
              <bitOffset>4</bitOffset>
              <bitWidth>4</bitWidth>
            </field>
            <field>
              <name>AFSEL2</name>
              <bitOffset>8</bitOffset>
              <bitWidth>4</bitWidth>
            </field>
            <field>
              <name>AFSEL3</name>
              <bitOffset>12</bitOffset>
              <bitWidth>4</bitWidth>
            </field>
            <field>
              <name>AFSEL4</name>
              <bitOffset>16</bitOffset>
              <bitWidth>4</bitWidth>
            </field>
            <field>
              <name>AFSEL5</name>
              <bitOffset>20</bitOffset>
              <bitWidth>4</bitWidth>
            </field>
            <field>
              <name>AFSEL6</name>
              <bitOffset>24</bitOffset>
              <bitWidth>4</bitWidth>
            </field>
            <field>
              <name>AFSEL7</name>
              <bitOffset>28</bitOffset>
              <bitWidth>4</bitWidth>
            </field>
          </fields>
        </register>
        <register>
          <name>AFR.1</name>
          <addressOffset>0x24</addressOffset>
          <size>0x20</size>
          <fields>
            <field>
              <name>AFSEL8</name>
              <bitOffset>0</bitOffset>
              <bitWidth>4</bitWidth>
            </field>
            <field>
              <name>AFSEL9</name>
              <bitOffset>4</bitOffset>
              <bitWidth>4</bitWidth>
            </field>
            <field>
              <name>AFSEL10</name>
              <bitOffset>8</bitOffset>
              <bitWidth>4</bitWidth>
            </field>
            <field>
              <name>AFSEL11</name>
              <bitOffset>12</bitOffset>
              <bitWidth>4</bitWidth>
            </field>
            <field>
              <name>AFSEL12</name>
              <bitOffset>16</bitOffset>
              <bitWidth>4</bitWidth>
            </field>
            <field>
              <name>AFSEL13</name>
              <bitOffset>20</bitOffset>
              <bitWidth>4</bitWidth>
            </field>
            <field>
              <name>AFSEL14</name>
              <bitOffset>24</bitOffset>
              <bitWidth>4</bitWidth>
            </field>
            <field>
              <name>AFSEL15</name>
              <bitOffset>28</bitOffset>
              <bitWidth>4</bitWidth>
            </field>
          </fields>
        </register>
      </registers>
    </peripheral>
    <peripheral>
      <name>GPIOH</name>
      <baseAddress>0x58021c00</baseAddress>
      <registers>
        <register>
          <name>MODER</name>
          <addressOffset>0x0</addressOffset>
          <size>0x20</size>
          <fields>
            <field>
              <name>MODE0</name>
              <bitOffset>0</bitOffset>
              <bitWidth>2</bitWidth>
            </field>
            <field>
              <name>MODE1</name>
              <bitOffset>2</bitOffset>
              <bitWidth>2</bitWidth>
            </field>
            <field>
              <name>MODE2</name>
              <bitOffset>4</bitOffset>
              <bitWidth>2</bitWidth>
            </field>
            <field>
              <name>MODE3</name>
              <bitOffset>6</bitOffset>
              <bitWidth>2</bitWidth>
            </field>
            <field>
              <name>MODE4</name>
              <bitOffset>8</bitOffset>
              <bitWidth>2</bitWidth>
            </field>
            <field>
              <name>MODE5</name>
              <bitOffset>10</bitOffset>
              <bitWidth>2</bitWidth>
            </field>
            <field>
              <name>MODE6</name>
              <bitOffset>12</bitOffset>
              <bitWidth>2</bitWidth>
            </field>
            <field>
              <name>MODE7</name>
              <bitOffset>14</bitOffset>
              <bitWidth>2</bitWidth>
            </field>
            <field>
              <name>MODE8</name>
              <bitOffset>16</bitOffset>
              <bitWidth>2</bitWidth>
            </field>
            <field>
              <name>MODE9</name>
              <bitOffset>18</bitOffset>
              <bitWidth>2</bitWidth>
            </field>
            <field>
              <name>MODE10</name>
              <bitOffset>20</bitOffset>
              <bitWidth>2</bitWidth>
            </field>
            <field>
              <name>MODE11</name>
              <bitOffset>22</bitOffset>
              <bitWidth>2</bitWidth>
            </field>
            <field>
              <name>MODE12</name>
              <bitOffset>24</bitOffset>
              <bitWidth>2</bitWidth>
            </field>
            <field>
              <name>MODE13</name>
              <bitOffset>26</bitOffset>
              <bitWidth>2</bitWidth>
            </field>
            <field>
              <name>MODE14</name>
              <bitOffset>28</bitOffset>
              <bitWidth>2</bitWidth>
            </field>
            <field>
              <name>MODE15</name>
              <bitOffset>30</bitOffset>
              <bitWidth>2</bitWidth>
            </field>
          </fields>
        </register>
        <register>
          <name>OTYPER</name>
          <addressOffset>0x4</addressOffset>
          <size>0x20</size>
          <fields>
            <field>
              <name>OT0</name>
              <bitOffset>0</bitOffset>
              <bitWidth>1</bitWidth>
            </field>
            <field>
              <name>OT1</name>
              <bitOffset>1</bitOffset>
              <bitWidth>1</bitWidth>
            </field>
            <field>
              <name>OT2</name>
              <bitOffset>2</bitOffset>
              <bitWidth>1</bitWidth>
            </field>
            <field>
              <name>OT3</name>
              <bitOffset>3</bitOffset>
              <bitWidth>1</bitWidth>
            </field>
            <field>
              <name>OT4</name>
              <bitOffset>4</bitOffset>
              <bitWidth>1</bitWidth>
            </field>
            <field>
              <name>OT5</name>
              <bitOffset>5</bitOffset>
              <bitWidth>1</bitWidth>
            </field>
            <field>
              <name>OT6</name>
              <bitOffset>6</bitOffset>
              <bitWidth>1</bitWidth>
            </field>
            <field>
              <name>OT7</name>
              <bitOffset>7</bitOffset>
              <bitWidth>1</bitWidth>
            </field>
            <field>
              <name>OT8</name>
              <bitOffset>8</bitOffset>
              <bitWidth>1</bitWidth>
            </field>
            <field>
              <name>OT9</name>
              <bitOffset>9</bitOffset>
              <bitWidth>1</bitWidth>
            </field>
            <field>
              <name>OT10</name>
              <bitOffset>10</bitOffset>
              <bitWidth>1</bitWidth>
            </field>
            <field>
              <name>OT11</name>
              <bitOffset>11</bitOffset>
              <bitWidth>1</bitWidth>
            </field>
            <field>
              <name>OT12</name>
              <bitOffset>12</bitOffset>
              <bitWidth>1</bitWidth>
            </field>
            <field>
              <name>OT13</name>
              <bitOffset>13</bitOffset>
              <bitWidth>1</bitWidth>
            </field>
            <field>
              <name>OT14</name>
              <bitOffset>14</bitOffset>
              <bitWidth>1</bitWidth>
            </field>
            <field>
              <name>OT15</name>
              <bitOffset>15</bitOffset>
              <bitWidth>1</bitWidth>
            </field>
          </fields>
        </register>
        <register>
          <name>OSPEEDR</name>
          <addressOffset>0x8</addressOffset>
          <size>0x20</size>
          <fields>
            <field>
              <name>OSPEED0</name>
              <bitOffset>0</bitOffset>
              <bitWidth>2</bitWidth>
            </field>
            <field>
              <name>OSPEED1</name>
              <bitOffset>2</bitOffset>
              <bitWidth>2</bitWidth>
            </field>
            <field>
              <name>OSPEED2</name>
              <bitOffset>4</bitOffset>
              <bitWidth>2</bitWidth>
            </field>
            <field>
              <name>OSPEED3</name>
              <bitOffset>6</bitOffset>
              <bitWidth>2</bitWidth>
            </field>
            <field>
              <name>OSPEED4</name>
              <bitOffset>8</bitOffset>
              <bitWidth>2</bitWidth>
            </field>
            <field>
              <name>OSPEED5</name>
              <bitOffset>10</bitOffset>
              <bitWidth>2</bitWidth>
            </field>
            <field>
              <name>OSPEED6</name>
              <bitOffset>12</bitOffset>
              <bitWidth>2</bitWidth>
            </field>
            <field>
              <name>OSPEED7</name>
              <bitOffset>14</bitOffset>
              <bitWidth>2</bitWidth>
            </field>
            <field>
              <name>OSPEED8</name>
              <bitOffset>16</bitOffset>
              <bitWidth>2</bitWidth>
            </field>
            <field>
              <name>OSPEED9</name>
              <bitOffset>18</bitOffset>
              <bitWidth>2</bitWidth>
            </field>
            <field>
              <name>OSPEED10</name>
              <bitOffset>20</bitOffset>
              <bitWidth>2</bitWidth>
            </field>
            <field>
              <name>OSPEED11</name>
              <bitOffset>22</bitOffset>
              <bitWidth>2</bitWidth>
            </field>
            <field>
              <name>OSPEED12</name>
              <bitOffset>24</bitOffset>
              <bitWidth>2</bitWidth>
            </field>
            <field>
              <name>OSPEED13</name>
              <bitOffset>26</bitOffset>
              <bitWidth>2</bitWidth>
            </field>
            <field>
              <name>OSPEED14</name>
              <bitOffset>28</bitOffset>
              <bitWidth>2</bitWidth>
            </field>
            <field>
              <name>OSPEED15</name>
              <bitOffset>30</bitOffset>
              <bitWidth>2</bitWidth>
            </field>
          </fields>
        </register>
        <register>
          <name>PUPDR</name>
          <addressOffset>0xc</addressOffset>
          <size>0x20</size>
          <fields>
            <field>
              <name>PUPD0</name>
              <bitOffset>0</bitOffset>
              <bitWidth>2</bitWidth>
            </field>
            <field>
              <name>PUPD1</name>
              <bitOffset>2</bitOffset>
              <bitWidth>2</bitWidth>
            </field>
            <field>
              <name>PUPD2</name>
              <bitOffset>4</bitOffset>
              <bitWidth>2</bitWidth>
            </field>
            <field>
              <name>PUPD3</name>
              <bitOffset>6</bitOffset>
              <bitWidth>2</bitWidth>
            </field>
            <field>
              <name>PUPD4</name>
              <bitOffset>8</bitOffset>
              <bitWidth>2</bitWidth>
            </field>
            <field>
              <name>PUPD5</name>
              <bitOffset>10</bitOffset>
              <bitWidth>2</bitWidth>
            </field>
            <field>
              <name>PUPD6</name>
              <bitOffset>12</bitOffset>
              <bitWidth>2</bitWidth>
            </field>
            <field>
              <name>PUPD7</name>
              <bitOffset>14</bitOffset>
              <bitWidth>2</bitWidth>
            </field>
            <field>
              <name>PUPD8</name>
              <bitOffset>16</bitOffset>
              <bitWidth>2</bitWidth>
            </field>
            <field>
              <name>PUPD9</name>
              <bitOffset>18</bitOffset>
              <bitWidth>2</bitWidth>
            </field>
            <field>
              <name>PUPD10</name>
              <bitOffset>20</bitOffset>
              <bitWidth>2</bitWidth>
            </field>
            <field>
              <name>PUPD11</name>
              <bitOffset>22</bitOffset>
              <bitWidth>2</bitWidth>
            </field>
            <field>
              <name>PUPD12</name>
              <bitOffset>24</bitOffset>
              <bitWidth>2</bitWidth>
            </field>
            <field>
              <name>PUPD13</name>
              <bitOffset>26</bitOffset>
              <bitWidth>2</bitWidth>
            </field>
            <field>
              <name>PUPD14</name>
              <bitOffset>28</bitOffset>
              <bitWidth>2</bitWidth>
            </field>
            <field>
              <name>PUPD15</name>
              <bitOffset>30</bitOffset>
              <bitWidth>2</bitWidth>
            </field>
          </fields>
        </register>
        <register>
          <name>IDR</name>
          <addressOffset>0x10</addressOffset>
          <size>0x20</size>
          <fields>
            <field>
              <name>ID0</name>
              <bitOffset>0</bitOffset>
              <bitWidth>1</bitWidth>
            </field>
            <field>
              <name>ID1</name>
              <bitOffset>1</bitOffset>
              <bitWidth>1</bitWidth>
            </field>
            <field>
              <name>ID2</name>
              <bitOffset>2</bitOffset>
              <bitWidth>1</bitWidth>
            </field>
            <field>
              <name>ID3</name>
              <bitOffset>3</bitOffset>
              <bitWidth>1</bitWidth>
            </field>
            <field>
              <name>ID4</name>
              <bitOffset>4</bitOffset>
              <bitWidth>1</bitWidth>
            </field>
            <field>
              <name>ID5</name>
              <bitOffset>5</bitOffset>
              <bitWidth>1</bitWidth>
            </field>
            <field>
              <name>ID6</name>
              <bitOffset>6</bitOffset>
              <bitWidth>1</bitWidth>
            </field>
            <field>
              <name>ID7</name>
              <bitOffset>7</bitOffset>
              <bitWidth>1</bitWidth>
            </field>
            <field>
              <name>ID8</name>
              <bitOffset>8</bitOffset>
              <bitWidth>1</bitWidth>
            </field>
            <field>
              <name>ID9</name>
              <bitOffset>9</bitOffset>
              <bitWidth>1</bitWidth>
            </field>
            <field>
              <name>ID10</name>
              <bitOffset>10</bitOffset>
              <bitWidth>1</bitWidth>
            </field>
            <field>
              <name>ID11</name>
              <bitOffset>11</bitOffset>
              <bitWidth>1</bitWidth>
            </field>
            <field>
              <name>ID12</name>
              <bitOffset>12</bitOffset>
              <bitWidth>1</bitWidth>
            </field>
            <field>
              <name>ID13</name>
              <bitOffset>13</bitOffset>
              <bitWidth>1</bitWidth>
            </field>
            <field>
              <name>ID14</name>
              <bitOffset>14</bitOffset>
              <bitWidth>1</bitWidth>
            </field>
            <field>
              <name>ID15</name>
              <bitOffset>15</bitOffset>
              <bitWidth>1</bitWidth>
            </field>
          </fields>
        </register>
        <register>
          <name>ODR</name>
          <addressOffset>0x14</addressOffset>
          <size>0x20</size>
          <fields>
            <field>
              <name>OD0</name>
              <bitOffset>0</bitOffset>
              <bitWidth>1</bitWidth>
            </field>
            <field>
              <name>OD1</name>
              <bitOffset>1</bitOffset>
              <bitWidth>1</bitWidth>
            </field>
            <field>
              <name>OD2</name>
              <bitOffset>2</bitOffset>
              <bitWidth>1</bitWidth>
            </field>
            <field>
              <name>OD3</name>
              <bitOffset>3</bitOffset>
              <bitWidth>1</bitWidth>
            </field>
            <field>
              <name>OD4</name>
              <bitOffset>4</bitOffset>
              <bitWidth>1</bitWidth>
            </field>
            <field>
              <name>OD5</name>
              <bitOffset>5</bitOffset>
              <bitWidth>1</bitWidth>
            </field>
            <field>
              <name>OD6</name>
              <bitOffset>6</bitOffset>
              <bitWidth>1</bitWidth>
            </field>
            <field>
              <name>OD7</name>
              <bitOffset>7</bitOffset>
              <bitWidth>1</bitWidth>
            </field>
            <field>
              <name>OD8</name>
              <bitOffset>8</bitOffset>
              <bitWidth>1</bitWidth>
            </field>
            <field>
              <name>OD9</name>
              <bitOffset>9</bitOffset>
              <bitWidth>1</bitWidth>
            </field>
            <field>
              <name>OD10</name>
              <bitOffset>10</bitOffset>
              <bitWidth>1</bitWidth>
            </field>
            <field>
              <name>OD11</name>
              <bitOffset>11</bitOffset>
              <bitWidth>1</bitWidth>
            </field>
            <field>
              <name>OD12</name>
              <bitOffset>12</bitOffset>
              <bitWidth>1</bitWidth>
            </field>
            <field>
              <name>OD13</name>
              <bitOffset>13</bitOffset>
              <bitWidth>1</bitWidth>
            </field>
            <field>
              <name>OD14</name>
              <bitOffset>14</bitOffset>
              <bitWidth>1</bitWidth>
            </field>
            <field>
              <name>OD15</name>
              <bitOffset>15</bitOffset>
              <bitWidth>1</bitWidth>
            </field>
          </fields>
        </register>
        <register>
          <name>BSRR</name>
          <addressOffset>0x18</addressOffset>
          <size>0x20</size>
          <fields>
            <field>
              <name>BS0</name>
              <bitOffset>0</bitOffset>
              <bitWidth>1</bitWidth>
            </field>
            <field>
              <name>BS1</name>
              <bitOffset>1</bitOffset>
              <bitWidth>1</bitWidth>
            </field>
            <field>
              <name>BS2</name>
              <bitOffset>2</bitOffset>
              <bitWidth>1</bitWidth>
            </field>
            <field>
              <name>BS3</name>
              <bitOffset>3</bitOffset>
              <bitWidth>1</bitWidth>
            </field>
            <field>
              <name>BS4</name>
              <bitOffset>4</bitOffset>
              <bitWidth>1</bitWidth>
            </field>
            <field>
              <name>BS5</name>
              <bitOffset>5</bitOffset>
              <bitWidth>1</bitWidth>
            </field>
            <field>
              <name>BS6</name>
              <bitOffset>6</bitOffset>
              <bitWidth>1</bitWidth>
            </field>
            <field>
              <name>BS7</name>
              <bitOffset>7</bitOffset>
              <bitWidth>1</bitWidth>
            </field>
            <field>
              <name>BS8</name>
              <bitOffset>8</bitOffset>
              <bitWidth>1</bitWidth>
            </field>
            <field>
              <name>BS9</name>
              <bitOffset>9</bitOffset>
              <bitWidth>1</bitWidth>
            </field>
            <field>
              <name>BS10</name>
              <bitOffset>10</bitOffset>
              <bitWidth>1</bitWidth>
            </field>
            <field>
              <name>BS11</name>
              <bitOffset>11</bitOffset>
              <bitWidth>1</bitWidth>
            </field>
            <field>
              <name>BS12</name>
              <bitOffset>12</bitOffset>
              <bitWidth>1</bitWidth>
            </field>
            <field>
              <name>BS13</name>
              <bitOffset>13</bitOffset>
              <bitWidth>1</bitWidth>
            </field>
            <field>
              <name>BS14</name>
              <bitOffset>14</bitOffset>
              <bitWidth>1</bitWidth>
            </field>
            <field>
              <name>BS15</name>
              <bitOffset>15</bitOffset>
              <bitWidth>1</bitWidth>
            </field>
            <field>
              <name>BR0</name>
              <bitOffset>16</bitOffset>
              <bitWidth>1</bitWidth>
            </field>
            <field>
              <name>BR1</name>
              <bitOffset>17</bitOffset>
              <bitWidth>1</bitWidth>
            </field>
            <field>
              <name>BR2</name>
              <bitOffset>18</bitOffset>
              <bitWidth>1</bitWidth>
            </field>
            <field>
              <name>BR3</name>
              <bitOffset>19</bitOffset>
              <bitWidth>1</bitWidth>
            </field>
            <field>
              <name>BR4</name>
              <bitOffset>20</bitOffset>
              <bitWidth>1</bitWidth>
            </field>
            <field>
              <name>BR5</name>
              <bitOffset>21</bitOffset>
              <bitWidth>1</bitWidth>
            </field>
            <field>
              <name>BR6</name>
              <bitOffset>22</bitOffset>
              <bitWidth>1</bitWidth>
            </field>
            <field>
              <name>BR7</name>
              <bitOffset>23</bitOffset>
              <bitWidth>1</bitWidth>
            </field>
            <field>
              <name>BR8</name>
              <bitOffset>24</bitOffset>
              <bitWidth>1</bitWidth>
            </field>
            <field>
              <name>BR9</name>
              <bitOffset>25</bitOffset>
              <bitWidth>1</bitWidth>
            </field>
            <field>
              <name>BR10</name>
              <bitOffset>26</bitOffset>
              <bitWidth>1</bitWidth>
            </field>
            <field>
              <name>BR11</name>
              <bitOffset>27</bitOffset>
              <bitWidth>1</bitWidth>
            </field>
            <field>
              <name>BR12</name>
              <bitOffset>28</bitOffset>
              <bitWidth>1</bitWidth>
            </field>
            <field>
              <name>BR13</name>
              <bitOffset>29</bitOffset>
              <bitWidth>1</bitWidth>
            </field>
            <field>
              <name>BR14</name>
              <bitOffset>30</bitOffset>
              <bitWidth>1</bitWidth>
            </field>
            <field>
              <name>BR15</name>
              <bitOffset>31</bitOffset>
              <bitWidth>1</bitWidth>
            </field>
          </fields>
        </register>
        <register>
          <name>LCKR</name>
          <addressOffset>0x1c</addressOffset>
          <size>0x20</size>
          <fields>
            <field>
              <name>LCK0</name>
              <bitOffset>0</bitOffset>
              <bitWidth>1</bitWidth>
            </field>
            <field>
              <name>LCK1</name>
              <bitOffset>1</bitOffset>
              <bitWidth>1</bitWidth>
            </field>
            <field>
              <name>LCK2</name>
              <bitOffset>2</bitOffset>
              <bitWidth>1</bitWidth>
            </field>
            <field>
              <name>LCK3</name>
              <bitOffset>3</bitOffset>
              <bitWidth>1</bitWidth>
            </field>
            <field>
              <name>LCK4</name>
              <bitOffset>4</bitOffset>
              <bitWidth>1</bitWidth>
            </field>
            <field>
              <name>LCK5</name>
              <bitOffset>5</bitOffset>
              <bitWidth>1</bitWidth>
            </field>
            <field>
              <name>LCK6</name>
              <bitOffset>6</bitOffset>
              <bitWidth>1</bitWidth>
            </field>
            <field>
              <name>LCK7</name>
              <bitOffset>7</bitOffset>
              <bitWidth>1</bitWidth>
            </field>
            <field>
              <name>LCK8</name>
              <bitOffset>8</bitOffset>
              <bitWidth>1</bitWidth>
            </field>
            <field>
              <name>LCK9</name>
              <bitOffset>9</bitOffset>
              <bitWidth>1</bitWidth>
            </field>
            <field>
              <name>LCK10</name>
              <bitOffset>10</bitOffset>
              <bitWidth>1</bitWidth>
            </field>
            <field>
              <name>LCK11</name>
              <bitOffset>11</bitOffset>
              <bitWidth>1</bitWidth>
            </field>
            <field>
              <name>LCK12</name>
              <bitOffset>12</bitOffset>
              <bitWidth>1</bitWidth>
            </field>
            <field>
              <name>LCK13</name>
              <bitOffset>13</bitOffset>
              <bitWidth>1</bitWidth>
            </field>
            <field>
              <name>LCK14</name>
              <bitOffset>14</bitOffset>
              <bitWidth>1</bitWidth>
            </field>
            <field>
              <name>LCK15</name>
              <bitOffset>15</bitOffset>
              <bitWidth>1</bitWidth>
            </field>
            <field>
              <name>LCKK</name>
              <bitOffset>16</bitOffset>
              <bitWidth>1</bitWidth>
            </field>
          </fields>
        </register>
        <register>
          <name>AFR.0</name>
          <addressOffset>0x20</addressOffset>
          <size>0x20</size>
          <fields>
            <field>
              <name>AFSEL0</name>
              <bitOffset>0</bitOffset>
              <bitWidth>4</bitWidth>
            </field>
            <field>
              <name>AFSEL1</name>
              <bitOffset>4</bitOffset>
              <bitWidth>4</bitWidth>
            </field>
            <field>
              <name>AFSEL2</name>
              <bitOffset>8</bitOffset>
              <bitWidth>4</bitWidth>
            </field>
            <field>
              <name>AFSEL3</name>
              <bitOffset>12</bitOffset>
              <bitWidth>4</bitWidth>
            </field>
            <field>
              <name>AFSEL4</name>
              <bitOffset>16</bitOffset>
              <bitWidth>4</bitWidth>
            </field>
            <field>
              <name>AFSEL5</name>
              <bitOffset>20</bitOffset>
              <bitWidth>4</bitWidth>
            </field>
            <field>
              <name>AFSEL6</name>
              <bitOffset>24</bitOffset>
              <bitWidth>4</bitWidth>
            </field>
            <field>
              <name>AFSEL7</name>
              <bitOffset>28</bitOffset>
              <bitWidth>4</bitWidth>
            </field>
          </fields>
        </register>
        <register>
          <name>AFR.1</name>
          <addressOffset>0x24</addressOffset>
          <size>0x20</size>
          <fields>
            <field>
              <name>AFSEL8</name>
              <bitOffset>0</bitOffset>
              <bitWidth>4</bitWidth>
            </field>
            <field>
              <name>AFSEL9</name>
              <bitOffset>4</bitOffset>
              <bitWidth>4</bitWidth>
            </field>
            <field>
              <name>AFSEL10</name>
              <bitOffset>8</bitOffset>
              <bitWidth>4</bitWidth>
            </field>
            <field>
              <name>AFSEL11</name>
              <bitOffset>12</bitOffset>
              <bitWidth>4</bitWidth>
            </field>
            <field>
              <name>AFSEL12</name>
              <bitOffset>16</bitOffset>
              <bitWidth>4</bitWidth>
            </field>
            <field>
              <name>AFSEL13</name>
              <bitOffset>20</bitOffset>
              <bitWidth>4</bitWidth>
            </field>
            <field>
              <name>AFSEL14</name>
              <bitOffset>24</bitOffset>
              <bitWidth>4</bitWidth>
            </field>
            <field>
              <name>AFSEL15</name>
              <bitOffset>28</bitOffset>
              <bitWidth>4</bitWidth>
            </field>
          </fields>
        </register>
      </registers>
    </peripheral>
    <peripheral>
      <name>GPIOI</name>
      <baseAddress>0x58022000</baseAddress>
      <registers>
        <register>
          <name>MODER</name>
          <addressOffset>0x0</addressOffset>
          <size>0x20</size>
          <fields>
            <field>
              <name>MODE0</name>
              <bitOffset>0</bitOffset>
              <bitWidth>2</bitWidth>
            </field>
            <field>
              <name>MODE1</name>
              <bitOffset>2</bitOffset>
              <bitWidth>2</bitWidth>
            </field>
            <field>
              <name>MODE2</name>
              <bitOffset>4</bitOffset>
              <bitWidth>2</bitWidth>
            </field>
            <field>
              <name>MODE3</name>
              <bitOffset>6</bitOffset>
              <bitWidth>2</bitWidth>
            </field>
            <field>
              <name>MODE4</name>
              <bitOffset>8</bitOffset>
              <bitWidth>2</bitWidth>
            </field>
            <field>
              <name>MODE5</name>
              <bitOffset>10</bitOffset>
              <bitWidth>2</bitWidth>
            </field>
            <field>
              <name>MODE6</name>
              <bitOffset>12</bitOffset>
              <bitWidth>2</bitWidth>
            </field>
            <field>
              <name>MODE7</name>
              <bitOffset>14</bitOffset>
              <bitWidth>2</bitWidth>
            </field>
            <field>
              <name>MODE8</name>
              <bitOffset>16</bitOffset>
              <bitWidth>2</bitWidth>
            </field>
            <field>
              <name>MODE9</name>
              <bitOffset>18</bitOffset>
              <bitWidth>2</bitWidth>
            </field>
            <field>
              <name>MODE10</name>
              <bitOffset>20</bitOffset>
              <bitWidth>2</bitWidth>
            </field>
            <field>
              <name>MODE11</name>
              <bitOffset>22</bitOffset>
              <bitWidth>2</bitWidth>
            </field>
            <field>
              <name>MODE12</name>
              <bitOffset>24</bitOffset>
              <bitWidth>2</bitWidth>
            </field>
            <field>
              <name>MODE13</name>
              <bitOffset>26</bitOffset>
              <bitWidth>2</bitWidth>
            </field>
            <field>
              <name>MODE14</name>
              <bitOffset>28</bitOffset>
              <bitWidth>2</bitWidth>
            </field>
            <field>
              <name>MODE15</name>
              <bitOffset>30</bitOffset>
              <bitWidth>2</bitWidth>
            </field>
          </fields>
        </register>
        <register>
          <name>OTYPER</name>
          <addressOffset>0x4</addressOffset>
          <size>0x20</size>
          <fields>
            <field>
              <name>OT0</name>
              <bitOffset>0</bitOffset>
              <bitWidth>1</bitWidth>
            </field>
            <field>
              <name>OT1</name>
              <bitOffset>1</bitOffset>
              <bitWidth>1</bitWidth>
            </field>
            <field>
              <name>OT2</name>
              <bitOffset>2</bitOffset>
              <bitWidth>1</bitWidth>
            </field>
            <field>
              <name>OT3</name>
              <bitOffset>3</bitOffset>
              <bitWidth>1</bitWidth>
            </field>
            <field>
              <name>OT4</name>
              <bitOffset>4</bitOffset>
              <bitWidth>1</bitWidth>
            </field>
            <field>
              <name>OT5</name>
              <bitOffset>5</bitOffset>
              <bitWidth>1</bitWidth>
            </field>
            <field>
              <name>OT6</name>
              <bitOffset>6</bitOffset>
              <bitWidth>1</bitWidth>
            </field>
            <field>
              <name>OT7</name>
              <bitOffset>7</bitOffset>
              <bitWidth>1</bitWidth>
            </field>
            <field>
              <name>OT8</name>
              <bitOffset>8</bitOffset>
              <bitWidth>1</bitWidth>
            </field>
            <field>
              <name>OT9</name>
              <bitOffset>9</bitOffset>
              <bitWidth>1</bitWidth>
            </field>
            <field>
              <name>OT10</name>
              <bitOffset>10</bitOffset>
              <bitWidth>1</bitWidth>
            </field>
            <field>
              <name>OT11</name>
              <bitOffset>11</bitOffset>
              <bitWidth>1</bitWidth>
            </field>
            <field>
              <name>OT12</name>
              <bitOffset>12</bitOffset>
              <bitWidth>1</bitWidth>
            </field>
            <field>
              <name>OT13</name>
              <bitOffset>13</bitOffset>
              <bitWidth>1</bitWidth>
            </field>
            <field>
              <name>OT14</name>
              <bitOffset>14</bitOffset>
              <bitWidth>1</bitWidth>
            </field>
            <field>
              <name>OT15</name>
              <bitOffset>15</bitOffset>
              <bitWidth>1</bitWidth>
            </field>
          </fields>
        </register>
        <register>
          <name>OSPEEDR</name>
          <addressOffset>0x8</addressOffset>
          <size>0x20</size>
          <fields>
            <field>
              <name>OSPEED0</name>
              <bitOffset>0</bitOffset>
              <bitWidth>2</bitWidth>
            </field>
            <field>
              <name>OSPEED1</name>
              <bitOffset>2</bitOffset>
              <bitWidth>2</bitWidth>
            </field>
            <field>
              <name>OSPEED2</name>
              <bitOffset>4</bitOffset>
              <bitWidth>2</bitWidth>
            </field>
            <field>
              <name>OSPEED3</name>
              <bitOffset>6</bitOffset>
              <bitWidth>2</bitWidth>
            </field>
            <field>
              <name>OSPEED4</name>
              <bitOffset>8</bitOffset>
              <bitWidth>2</bitWidth>
            </field>
            <field>
              <name>OSPEED5</name>
              <bitOffset>10</bitOffset>
              <bitWidth>2</bitWidth>
            </field>
            <field>
              <name>OSPEED6</name>
              <bitOffset>12</bitOffset>
              <bitWidth>2</bitWidth>
            </field>
            <field>
              <name>OSPEED7</name>
              <bitOffset>14</bitOffset>
              <bitWidth>2</bitWidth>
            </field>
            <field>
              <name>OSPEED8</name>
              <bitOffset>16</bitOffset>
              <bitWidth>2</bitWidth>
            </field>
            <field>
              <name>OSPEED9</name>
              <bitOffset>18</bitOffset>
              <bitWidth>2</bitWidth>
            </field>
            <field>
              <name>OSPEED10</name>
              <bitOffset>20</bitOffset>
              <bitWidth>2</bitWidth>
            </field>
            <field>
              <name>OSPEED11</name>
              <bitOffset>22</bitOffset>
              <bitWidth>2</bitWidth>
            </field>
            <field>
              <name>OSPEED12</name>
              <bitOffset>24</bitOffset>
              <bitWidth>2</bitWidth>
            </field>
            <field>
              <name>OSPEED13</name>
              <bitOffset>26</bitOffset>
              <bitWidth>2</bitWidth>
            </field>
            <field>
              <name>OSPEED14</name>
              <bitOffset>28</bitOffset>
              <bitWidth>2</bitWidth>
            </field>
            <field>
              <name>OSPEED15</name>
              <bitOffset>30</bitOffset>
              <bitWidth>2</bitWidth>
            </field>
          </fields>
        </register>
        <register>
          <name>PUPDR</name>
          <addressOffset>0xc</addressOffset>
          <size>0x20</size>
          <fields>
            <field>
              <name>PUPD0</name>
              <bitOffset>0</bitOffset>
              <bitWidth>2</bitWidth>
            </field>
            <field>
              <name>PUPD1</name>
              <bitOffset>2</bitOffset>
              <bitWidth>2</bitWidth>
            </field>
            <field>
              <name>PUPD2</name>
              <bitOffset>4</bitOffset>
              <bitWidth>2</bitWidth>
            </field>
            <field>
              <name>PUPD3</name>
              <bitOffset>6</bitOffset>
              <bitWidth>2</bitWidth>
            </field>
            <field>
              <name>PUPD4</name>
              <bitOffset>8</bitOffset>
              <bitWidth>2</bitWidth>
            </field>
            <field>
              <name>PUPD5</name>
              <bitOffset>10</bitOffset>
              <bitWidth>2</bitWidth>
            </field>
            <field>
              <name>PUPD6</name>
              <bitOffset>12</bitOffset>
              <bitWidth>2</bitWidth>
            </field>
            <field>
              <name>PUPD7</name>
              <bitOffset>14</bitOffset>
              <bitWidth>2</bitWidth>
            </field>
            <field>
              <name>PUPD8</name>
              <bitOffset>16</bitOffset>
              <bitWidth>2</bitWidth>
            </field>
            <field>
              <name>PUPD9</name>
              <bitOffset>18</bitOffset>
              <bitWidth>2</bitWidth>
            </field>
            <field>
              <name>PUPD10</name>
              <bitOffset>20</bitOffset>
              <bitWidth>2</bitWidth>
            </field>
            <field>
              <name>PUPD11</name>
              <bitOffset>22</bitOffset>
              <bitWidth>2</bitWidth>
            </field>
            <field>
              <name>PUPD12</name>
              <bitOffset>24</bitOffset>
              <bitWidth>2</bitWidth>
            </field>
            <field>
              <name>PUPD13</name>
              <bitOffset>26</bitOffset>
              <bitWidth>2</bitWidth>
            </field>
            <field>
              <name>PUPD14</name>
              <bitOffset>28</bitOffset>
              <bitWidth>2</bitWidth>
            </field>
            <field>
              <name>PUPD15</name>
              <bitOffset>30</bitOffset>
              <bitWidth>2</bitWidth>
            </field>
          </fields>
        </register>
        <register>
          <name>IDR</name>
          <addressOffset>0x10</addressOffset>
          <size>0x20</size>
          <fields>
            <field>
              <name>ID0</name>
              <bitOffset>0</bitOffset>
              <bitWidth>1</bitWidth>
            </field>
            <field>
              <name>ID1</name>
              <bitOffset>1</bitOffset>
              <bitWidth>1</bitWidth>
            </field>
            <field>
              <name>ID2</name>
              <bitOffset>2</bitOffset>
              <bitWidth>1</bitWidth>
            </field>
            <field>
              <name>ID3</name>
              <bitOffset>3</bitOffset>
              <bitWidth>1</bitWidth>
            </field>
            <field>
              <name>ID4</name>
              <bitOffset>4</bitOffset>
              <bitWidth>1</bitWidth>
            </field>
            <field>
              <name>ID5</name>
              <bitOffset>5</bitOffset>
              <bitWidth>1</bitWidth>
            </field>
            <field>
              <name>ID6</name>
              <bitOffset>6</bitOffset>
              <bitWidth>1</bitWidth>
            </field>
            <field>
              <name>ID7</name>
              <bitOffset>7</bitOffset>
              <bitWidth>1</bitWidth>
            </field>
            <field>
              <name>ID8</name>
              <bitOffset>8</bitOffset>
              <bitWidth>1</bitWidth>
            </field>
            <field>
              <name>ID9</name>
              <bitOffset>9</bitOffset>
              <bitWidth>1</bitWidth>
            </field>
            <field>
              <name>ID10</name>
              <bitOffset>10</bitOffset>
              <bitWidth>1</bitWidth>
            </field>
            <field>
              <name>ID11</name>
              <bitOffset>11</bitOffset>
              <bitWidth>1</bitWidth>
            </field>
            <field>
              <name>ID12</name>
              <bitOffset>12</bitOffset>
              <bitWidth>1</bitWidth>
            </field>
            <field>
              <name>ID13</name>
              <bitOffset>13</bitOffset>
              <bitWidth>1</bitWidth>
            </field>
            <field>
              <name>ID14</name>
              <bitOffset>14</bitOffset>
              <bitWidth>1</bitWidth>
            </field>
            <field>
              <name>ID15</name>
              <bitOffset>15</bitOffset>
              <bitWidth>1</bitWidth>
            </field>
          </fields>
        </register>
        <register>
          <name>ODR</name>
          <addressOffset>0x14</addressOffset>
          <size>0x20</size>
          <fields>
            <field>
              <name>OD0</name>
              <bitOffset>0</bitOffset>
              <bitWidth>1</bitWidth>
            </field>
            <field>
              <name>OD1</name>
              <bitOffset>1</bitOffset>
              <bitWidth>1</bitWidth>
            </field>
            <field>
              <name>OD2</name>
              <bitOffset>2</bitOffset>
              <bitWidth>1</bitWidth>
            </field>
            <field>
              <name>OD3</name>
              <bitOffset>3</bitOffset>
              <bitWidth>1</bitWidth>
            </field>
            <field>
              <name>OD4</name>
              <bitOffset>4</bitOffset>
              <bitWidth>1</bitWidth>
            </field>
            <field>
              <name>OD5</name>
              <bitOffset>5</bitOffset>
              <bitWidth>1</bitWidth>
            </field>
            <field>
              <name>OD6</name>
              <bitOffset>6</bitOffset>
              <bitWidth>1</bitWidth>
            </field>
            <field>
              <name>OD7</name>
              <bitOffset>7</bitOffset>
              <bitWidth>1</bitWidth>
            </field>
            <field>
              <name>OD8</name>
              <bitOffset>8</bitOffset>
              <bitWidth>1</bitWidth>
            </field>
            <field>
              <name>OD9</name>
              <bitOffset>9</bitOffset>
              <bitWidth>1</bitWidth>
            </field>
            <field>
              <name>OD10</name>
              <bitOffset>10</bitOffset>
              <bitWidth>1</bitWidth>
            </field>
            <field>
              <name>OD11</name>
              <bitOffset>11</bitOffset>
              <bitWidth>1</bitWidth>
            </field>
            <field>
              <name>OD12</name>
              <bitOffset>12</bitOffset>
              <bitWidth>1</bitWidth>
            </field>
            <field>
              <name>OD13</name>
              <bitOffset>13</bitOffset>
              <bitWidth>1</bitWidth>
            </field>
            <field>
              <name>OD14</name>
              <bitOffset>14</bitOffset>
              <bitWidth>1</bitWidth>
            </field>
            <field>
              <name>OD15</name>
              <bitOffset>15</bitOffset>
              <bitWidth>1</bitWidth>
            </field>
          </fields>
        </register>
        <register>
          <name>BSRR</name>
          <addressOffset>0x18</addressOffset>
          <size>0x20</size>
          <fields>
            <field>
              <name>BS0</name>
              <bitOffset>0</bitOffset>
              <bitWidth>1</bitWidth>
            </field>
            <field>
              <name>BS1</name>
              <bitOffset>1</bitOffset>
              <bitWidth>1</bitWidth>
            </field>
            <field>
              <name>BS2</name>
              <bitOffset>2</bitOffset>
              <bitWidth>1</bitWidth>
            </field>
            <field>
              <name>BS3</name>
              <bitOffset>3</bitOffset>
              <bitWidth>1</bitWidth>
            </field>
            <field>
              <name>BS4</name>
              <bitOffset>4</bitOffset>
              <bitWidth>1</bitWidth>
            </field>
            <field>
              <name>BS5</name>
              <bitOffset>5</bitOffset>
              <bitWidth>1</bitWidth>
            </field>
            <field>
              <name>BS6</name>
              <bitOffset>6</bitOffset>
              <bitWidth>1</bitWidth>
            </field>
            <field>
              <name>BS7</name>
              <bitOffset>7</bitOffset>
              <bitWidth>1</bitWidth>
            </field>
            <field>
              <name>BS8</name>
              <bitOffset>8</bitOffset>
              <bitWidth>1</bitWidth>
            </field>
            <field>
              <name>BS9</name>
              <bitOffset>9</bitOffset>
              <bitWidth>1</bitWidth>
            </field>
            <field>
              <name>BS10</name>
              <bitOffset>10</bitOffset>
              <bitWidth>1</bitWidth>
            </field>
            <field>
              <name>BS11</name>
              <bitOffset>11</bitOffset>
              <bitWidth>1</bitWidth>
            </field>
            <field>
              <name>BS12</name>
              <bitOffset>12</bitOffset>
              <bitWidth>1</bitWidth>
            </field>
            <field>
              <name>BS13</name>
              <bitOffset>13</bitOffset>
              <bitWidth>1</bitWidth>
            </field>
            <field>
              <name>BS14</name>
              <bitOffset>14</bitOffset>
              <bitWidth>1</bitWidth>
            </field>
            <field>
              <name>BS15</name>
              <bitOffset>15</bitOffset>
              <bitWidth>1</bitWidth>
            </field>
            <field>
              <name>BR0</name>
              <bitOffset>16</bitOffset>
              <bitWidth>1</bitWidth>
            </field>
            <field>
              <name>BR1</name>
              <bitOffset>17</bitOffset>
              <bitWidth>1</bitWidth>
            </field>
            <field>
              <name>BR2</name>
              <bitOffset>18</bitOffset>
              <bitWidth>1</bitWidth>
            </field>
            <field>
              <name>BR3</name>
              <bitOffset>19</bitOffset>
              <bitWidth>1</bitWidth>
            </field>
            <field>
              <name>BR4</name>
              <bitOffset>20</bitOffset>
              <bitWidth>1</bitWidth>
            </field>
            <field>
              <name>BR5</name>
              <bitOffset>21</bitOffset>
              <bitWidth>1</bitWidth>
            </field>
            <field>
              <name>BR6</name>
              <bitOffset>22</bitOffset>
              <bitWidth>1</bitWidth>
            </field>
            <field>
              <name>BR7</name>
              <bitOffset>23</bitOffset>
              <bitWidth>1</bitWidth>
            </field>
            <field>
              <name>BR8</name>
              <bitOffset>24</bitOffset>
              <bitWidth>1</bitWidth>
            </field>
            <field>
              <name>BR9</name>
              <bitOffset>25</bitOffset>
              <bitWidth>1</bitWidth>
            </field>
            <field>
              <name>BR10</name>
              <bitOffset>26</bitOffset>
              <bitWidth>1</bitWidth>
            </field>
            <field>
              <name>BR11</name>
              <bitOffset>27</bitOffset>
              <bitWidth>1</bitWidth>
            </field>
            <field>
              <name>BR12</name>
              <bitOffset>28</bitOffset>
              <bitWidth>1</bitWidth>
            </field>
            <field>
              <name>BR13</name>
              <bitOffset>29</bitOffset>
              <bitWidth>1</bitWidth>
            </field>
            <field>
              <name>BR14</name>
              <bitOffset>30</bitOffset>
              <bitWidth>1</bitWidth>
            </field>
            <field>
              <name>BR15</name>
              <bitOffset>31</bitOffset>
              <bitWidth>1</bitWidth>
            </field>
          </fields>
        </register>
        <register>
          <name>LCKR</name>
          <addressOffset>0x1c</addressOffset>
          <size>0x20</size>
          <fields>
            <field>
              <name>LCK0</name>
              <bitOffset>0</bitOffset>
              <bitWidth>1</bitWidth>
            </field>
            <field>
              <name>LCK1</name>
              <bitOffset>1</bitOffset>
              <bitWidth>1</bitWidth>
            </field>
            <field>
              <name>LCK2</name>
              <bitOffset>2</bitOffset>
              <bitWidth>1</bitWidth>
            </field>
            <field>
              <name>LCK3</name>
              <bitOffset>3</bitOffset>
              <bitWidth>1</bitWidth>
            </field>
            <field>
              <name>LCK4</name>
              <bitOffset>4</bitOffset>
              <bitWidth>1</bitWidth>
            </field>
            <field>
              <name>LCK5</name>
              <bitOffset>5</bitOffset>
              <bitWidth>1</bitWidth>
            </field>
            <field>
              <name>LCK6</name>
              <bitOffset>6</bitOffset>
              <bitWidth>1</bitWidth>
            </field>
            <field>
              <name>LCK7</name>
              <bitOffset>7</bitOffset>
              <bitWidth>1</bitWidth>
            </field>
            <field>
              <name>LCK8</name>
              <bitOffset>8</bitOffset>
              <bitWidth>1</bitWidth>
            </field>
            <field>
              <name>LCK9</name>
              <bitOffset>9</bitOffset>
              <bitWidth>1</bitWidth>
            </field>
            <field>
              <name>LCK10</name>
              <bitOffset>10</bitOffset>
              <bitWidth>1</bitWidth>
            </field>
            <field>
              <name>LCK11</name>
              <bitOffset>11</bitOffset>
              <bitWidth>1</bitWidth>
            </field>
            <field>
              <name>LCK12</name>
              <bitOffset>12</bitOffset>
              <bitWidth>1</bitWidth>
            </field>
            <field>
              <name>LCK13</name>
              <bitOffset>13</bitOffset>
              <bitWidth>1</bitWidth>
            </field>
            <field>
              <name>LCK14</name>
              <bitOffset>14</bitOffset>
              <bitWidth>1</bitWidth>
            </field>
            <field>
              <name>LCK15</name>
              <bitOffset>15</bitOffset>
              <bitWidth>1</bitWidth>
            </field>
            <field>
              <name>LCKK</name>
              <bitOffset>16</bitOffset>
              <bitWidth>1</bitWidth>
            </field>
          </fields>
        </register>
        <register>
          <name>AFR.0</name>
          <addressOffset>0x20</addressOffset>
          <size>0x20</size>
          <fields>
            <field>
              <name>AFSEL0</name>
              <bitOffset>0</bitOffset>
              <bitWidth>4</bitWidth>
            </field>
            <field>
              <name>AFSEL1</name>
              <bitOffset>4</bitOffset>
              <bitWidth>4</bitWidth>
            </field>
            <field>
              <name>AFSEL2</name>
              <bitOffset>8</bitOffset>
              <bitWidth>4</bitWidth>
            </field>
            <field>
              <name>AFSEL3</name>
              <bitOffset>12</bitOffset>
              <bitWidth>4</bitWidth>
            </field>
            <field>
              <name>AFSEL4</name>
              <bitOffset>16</bitOffset>
              <bitWidth>4</bitWidth>
            </field>
            <field>
              <name>AFSEL5</name>
              <bitOffset>20</bitOffset>
              <bitWidth>4</bitWidth>
            </field>
            <field>
              <name>AFSEL6</name>
              <bitOffset>24</bitOffset>
              <bitWidth>4</bitWidth>
            </field>
            <field>
              <name>AFSEL7</name>
              <bitOffset>28</bitOffset>
              <bitWidth>4</bitWidth>
            </field>
          </fields>
        </register>
        <register>
          <name>AFR.1</name>
          <addressOffset>0x24</addressOffset>
          <size>0x20</size>
          <fields>
            <field>
              <name>AFSEL8</name>
              <bitOffset>0</bitOffset>
              <bitWidth>4</bitWidth>
            </field>
            <field>
              <name>AFSEL9</name>
              <bitOffset>4</bitOffset>
              <bitWidth>4</bitWidth>
            </field>
            <field>
              <name>AFSEL10</name>
              <bitOffset>8</bitOffset>
              <bitWidth>4</bitWidth>
            </field>
            <field>
              <name>AFSEL11</name>
              <bitOffset>12</bitOffset>
              <bitWidth>4</bitWidth>
            </field>
            <field>
              <name>AFSEL12</name>
              <bitOffset>16</bitOffset>
              <bitWidth>4</bitWidth>
            </field>
            <field>
              <name>AFSEL13</name>
              <bitOffset>20</bitOffset>
              <bitWidth>4</bitWidth>
            </field>
            <field>
              <name>AFSEL14</name>
              <bitOffset>24</bitOffset>
              <bitWidth>4</bitWidth>
            </field>
            <field>
              <name>AFSEL15</name>
              <bitOffset>28</bitOffset>
              <bitWidth>4</bitWidth>
            </field>
          </fields>
        </register>
      </registers>
    </peripheral>
    <peripheral>
      <name>GPIOJ</name>
      <baseAddress>0x58022400</baseAddress>
      <registers>
        <register>
          <name>MODER</name>
          <addressOffset>0x0</addressOffset>
          <size>0x20</size>
          <fields>
            <field>
              <name>MODE0</name>
              <bitOffset>0</bitOffset>
              <bitWidth>2</bitWidth>
            </field>
            <field>
              <name>MODE1</name>
              <bitOffset>2</bitOffset>
              <bitWidth>2</bitWidth>
            </field>
            <field>
              <name>MODE2</name>
              <bitOffset>4</bitOffset>
              <bitWidth>2</bitWidth>
            </field>
            <field>
              <name>MODE3</name>
              <bitOffset>6</bitOffset>
              <bitWidth>2</bitWidth>
            </field>
            <field>
              <name>MODE4</name>
              <bitOffset>8</bitOffset>
              <bitWidth>2</bitWidth>
            </field>
            <field>
              <name>MODE5</name>
              <bitOffset>10</bitOffset>
              <bitWidth>2</bitWidth>
            </field>
            <field>
              <name>MODE6</name>
              <bitOffset>12</bitOffset>
              <bitWidth>2</bitWidth>
            </field>
            <field>
              <name>MODE7</name>
              <bitOffset>14</bitOffset>
              <bitWidth>2</bitWidth>
            </field>
            <field>
              <name>MODE8</name>
              <bitOffset>16</bitOffset>
              <bitWidth>2</bitWidth>
            </field>
            <field>
              <name>MODE9</name>
              <bitOffset>18</bitOffset>
              <bitWidth>2</bitWidth>
            </field>
            <field>
              <name>MODE10</name>
              <bitOffset>20</bitOffset>
              <bitWidth>2</bitWidth>
            </field>
            <field>
              <name>MODE11</name>
              <bitOffset>22</bitOffset>
              <bitWidth>2</bitWidth>
            </field>
            <field>
              <name>MODE12</name>
              <bitOffset>24</bitOffset>
              <bitWidth>2</bitWidth>
            </field>
            <field>
              <name>MODE13</name>
              <bitOffset>26</bitOffset>
              <bitWidth>2</bitWidth>
            </field>
            <field>
              <name>MODE14</name>
              <bitOffset>28</bitOffset>
              <bitWidth>2</bitWidth>
            </field>
            <field>
              <name>MODE15</name>
              <bitOffset>30</bitOffset>
              <bitWidth>2</bitWidth>
            </field>
          </fields>
        </register>
        <register>
          <name>OTYPER</name>
          <addressOffset>0x4</addressOffset>
          <size>0x20</size>
          <fields>
            <field>
              <name>OT0</name>
              <bitOffset>0</bitOffset>
              <bitWidth>1</bitWidth>
            </field>
            <field>
              <name>OT1</name>
              <bitOffset>1</bitOffset>
              <bitWidth>1</bitWidth>
            </field>
            <field>
              <name>OT2</name>
              <bitOffset>2</bitOffset>
              <bitWidth>1</bitWidth>
            </field>
            <field>
              <name>OT3</name>
              <bitOffset>3</bitOffset>
              <bitWidth>1</bitWidth>
            </field>
            <field>
              <name>OT4</name>
              <bitOffset>4</bitOffset>
              <bitWidth>1</bitWidth>
            </field>
            <field>
              <name>OT5</name>
              <bitOffset>5</bitOffset>
              <bitWidth>1</bitWidth>
            </field>
            <field>
              <name>OT6</name>
              <bitOffset>6</bitOffset>
              <bitWidth>1</bitWidth>
            </field>
            <field>
              <name>OT7</name>
              <bitOffset>7</bitOffset>
              <bitWidth>1</bitWidth>
            </field>
            <field>
              <name>OT8</name>
              <bitOffset>8</bitOffset>
              <bitWidth>1</bitWidth>
            </field>
            <field>
              <name>OT9</name>
              <bitOffset>9</bitOffset>
              <bitWidth>1</bitWidth>
            </field>
            <field>
              <name>OT10</name>
              <bitOffset>10</bitOffset>
              <bitWidth>1</bitWidth>
            </field>
            <field>
              <name>OT11</name>
              <bitOffset>11</bitOffset>
              <bitWidth>1</bitWidth>
            </field>
            <field>
              <name>OT12</name>
              <bitOffset>12</bitOffset>
              <bitWidth>1</bitWidth>
            </field>
            <field>
              <name>OT13</name>
              <bitOffset>13</bitOffset>
              <bitWidth>1</bitWidth>
            </field>
            <field>
              <name>OT14</name>
              <bitOffset>14</bitOffset>
              <bitWidth>1</bitWidth>
            </field>
            <field>
              <name>OT15</name>
              <bitOffset>15</bitOffset>
              <bitWidth>1</bitWidth>
            </field>
          </fields>
        </register>
        <register>
          <name>OSPEEDR</name>
          <addressOffset>0x8</addressOffset>
          <size>0x20</size>
          <fields>
            <field>
              <name>OSPEED0</name>
              <bitOffset>0</bitOffset>
              <bitWidth>2</bitWidth>
            </field>
            <field>
              <name>OSPEED1</name>
              <bitOffset>2</bitOffset>
              <bitWidth>2</bitWidth>
            </field>
            <field>
              <name>OSPEED2</name>
              <bitOffset>4</bitOffset>
              <bitWidth>2</bitWidth>
            </field>
            <field>
              <name>OSPEED3</name>
              <bitOffset>6</bitOffset>
              <bitWidth>2</bitWidth>
            </field>
            <field>
              <name>OSPEED4</name>
              <bitOffset>8</bitOffset>
              <bitWidth>2</bitWidth>
            </field>
            <field>
              <name>OSPEED5</name>
              <bitOffset>10</bitOffset>
              <bitWidth>2</bitWidth>
            </field>
            <field>
              <name>OSPEED6</name>
              <bitOffset>12</bitOffset>
              <bitWidth>2</bitWidth>
            </field>
            <field>
              <name>OSPEED7</name>
              <bitOffset>14</bitOffset>
              <bitWidth>2</bitWidth>
            </field>
            <field>
              <name>OSPEED8</name>
              <bitOffset>16</bitOffset>
              <bitWidth>2</bitWidth>
            </field>
            <field>
              <name>OSPEED9</name>
              <bitOffset>18</bitOffset>
              <bitWidth>2</bitWidth>
            </field>
            <field>
              <name>OSPEED10</name>
              <bitOffset>20</bitOffset>
              <bitWidth>2</bitWidth>
            </field>
            <field>
              <name>OSPEED11</name>
              <bitOffset>22</bitOffset>
              <bitWidth>2</bitWidth>
            </field>
            <field>
              <name>OSPEED12</name>
              <bitOffset>24</bitOffset>
              <bitWidth>2</bitWidth>
            </field>
            <field>
              <name>OSPEED13</name>
              <bitOffset>26</bitOffset>
              <bitWidth>2</bitWidth>
            </field>
            <field>
              <name>OSPEED14</name>
              <bitOffset>28</bitOffset>
              <bitWidth>2</bitWidth>
            </field>
            <field>
              <name>OSPEED15</name>
              <bitOffset>30</bitOffset>
              <bitWidth>2</bitWidth>
            </field>
          </fields>
        </register>
        <register>
          <name>PUPDR</name>
          <addressOffset>0xc</addressOffset>
          <size>0x20</size>
          <fields>
            <field>
              <name>PUPD0</name>
              <bitOffset>0</bitOffset>
              <bitWidth>2</bitWidth>
            </field>
            <field>
              <name>PUPD1</name>
              <bitOffset>2</bitOffset>
              <bitWidth>2</bitWidth>
            </field>
            <field>
              <name>PUPD2</name>
              <bitOffset>4</bitOffset>
              <bitWidth>2</bitWidth>
            </field>
            <field>
              <name>PUPD3</name>
              <bitOffset>6</bitOffset>
              <bitWidth>2</bitWidth>
            </field>
            <field>
              <name>PUPD4</name>
              <bitOffset>8</bitOffset>
              <bitWidth>2</bitWidth>
            </field>
            <field>
              <name>PUPD5</name>
              <bitOffset>10</bitOffset>
              <bitWidth>2</bitWidth>
            </field>
            <field>
              <name>PUPD6</name>
              <bitOffset>12</bitOffset>
              <bitWidth>2</bitWidth>
            </field>
            <field>
              <name>PUPD7</name>
              <bitOffset>14</bitOffset>
              <bitWidth>2</bitWidth>
            </field>
            <field>
              <name>PUPD8</name>
              <bitOffset>16</bitOffset>
              <bitWidth>2</bitWidth>
            </field>
            <field>
              <name>PUPD9</name>
              <bitOffset>18</bitOffset>
              <bitWidth>2</bitWidth>
            </field>
            <field>
              <name>PUPD10</name>
              <bitOffset>20</bitOffset>
              <bitWidth>2</bitWidth>
            </field>
            <field>
              <name>PUPD11</name>
              <bitOffset>22</bitOffset>
              <bitWidth>2</bitWidth>
            </field>
            <field>
              <name>PUPD12</name>
              <bitOffset>24</bitOffset>
              <bitWidth>2</bitWidth>
            </field>
            <field>
              <name>PUPD13</name>
              <bitOffset>26</bitOffset>
              <bitWidth>2</bitWidth>
            </field>
            <field>
              <name>PUPD14</name>
              <bitOffset>28</bitOffset>
              <bitWidth>2</bitWidth>
            </field>
            <field>
              <name>PUPD15</name>
              <bitOffset>30</bitOffset>
              <bitWidth>2</bitWidth>
            </field>
          </fields>
        </register>
        <register>
          <name>IDR</name>
          <addressOffset>0x10</addressOffset>
          <size>0x20</size>
          <fields>
            <field>
              <name>ID0</name>
              <bitOffset>0</bitOffset>
              <bitWidth>1</bitWidth>
            </field>
            <field>
              <name>ID1</name>
              <bitOffset>1</bitOffset>
              <bitWidth>1</bitWidth>
            </field>
            <field>
              <name>ID2</name>
              <bitOffset>2</bitOffset>
              <bitWidth>1</bitWidth>
            </field>
            <field>
              <name>ID3</name>
              <bitOffset>3</bitOffset>
              <bitWidth>1</bitWidth>
            </field>
            <field>
              <name>ID4</name>
              <bitOffset>4</bitOffset>
              <bitWidth>1</bitWidth>
            </field>
            <field>
              <name>ID5</name>
              <bitOffset>5</bitOffset>
              <bitWidth>1</bitWidth>
            </field>
            <field>
              <name>ID6</name>
              <bitOffset>6</bitOffset>
              <bitWidth>1</bitWidth>
            </field>
            <field>
              <name>ID7</name>
              <bitOffset>7</bitOffset>
              <bitWidth>1</bitWidth>
            </field>
            <field>
              <name>ID8</name>
              <bitOffset>8</bitOffset>
              <bitWidth>1</bitWidth>
            </field>
            <field>
              <name>ID9</name>
              <bitOffset>9</bitOffset>
              <bitWidth>1</bitWidth>
            </field>
            <field>
              <name>ID10</name>
              <bitOffset>10</bitOffset>
              <bitWidth>1</bitWidth>
            </field>
            <field>
              <name>ID11</name>
              <bitOffset>11</bitOffset>
              <bitWidth>1</bitWidth>
            </field>
            <field>
              <name>ID12</name>
              <bitOffset>12</bitOffset>
              <bitWidth>1</bitWidth>
            </field>
            <field>
              <name>ID13</name>
              <bitOffset>13</bitOffset>
              <bitWidth>1</bitWidth>
            </field>
            <field>
              <name>ID14</name>
              <bitOffset>14</bitOffset>
              <bitWidth>1</bitWidth>
            </field>
            <field>
              <name>ID15</name>
              <bitOffset>15</bitOffset>
              <bitWidth>1</bitWidth>
            </field>
          </fields>
        </register>
        <register>
          <name>ODR</name>
          <addressOffset>0x14</addressOffset>
          <size>0x20</size>
          <fields>
            <field>
              <name>OD0</name>
              <bitOffset>0</bitOffset>
              <bitWidth>1</bitWidth>
            </field>
            <field>
              <name>OD1</name>
              <bitOffset>1</bitOffset>
              <bitWidth>1</bitWidth>
            </field>
            <field>
              <name>OD2</name>
              <bitOffset>2</bitOffset>
              <bitWidth>1</bitWidth>
            </field>
            <field>
              <name>OD3</name>
              <bitOffset>3</bitOffset>
              <bitWidth>1</bitWidth>
            </field>
            <field>
              <name>OD4</name>
              <bitOffset>4</bitOffset>
              <bitWidth>1</bitWidth>
            </field>
            <field>
              <name>OD5</name>
              <bitOffset>5</bitOffset>
              <bitWidth>1</bitWidth>
            </field>
            <field>
              <name>OD6</name>
              <bitOffset>6</bitOffset>
              <bitWidth>1</bitWidth>
            </field>
            <field>
              <name>OD7</name>
              <bitOffset>7</bitOffset>
              <bitWidth>1</bitWidth>
            </field>
            <field>
              <name>OD8</name>
              <bitOffset>8</bitOffset>
              <bitWidth>1</bitWidth>
            </field>
            <field>
              <name>OD9</name>
              <bitOffset>9</bitOffset>
              <bitWidth>1</bitWidth>
            </field>
            <field>
              <name>OD10</name>
              <bitOffset>10</bitOffset>
              <bitWidth>1</bitWidth>
            </field>
            <field>
              <name>OD11</name>
              <bitOffset>11</bitOffset>
              <bitWidth>1</bitWidth>
            </field>
            <field>
              <name>OD12</name>
              <bitOffset>12</bitOffset>
              <bitWidth>1</bitWidth>
            </field>
            <field>
              <name>OD13</name>
              <bitOffset>13</bitOffset>
              <bitWidth>1</bitWidth>
            </field>
            <field>
              <name>OD14</name>
              <bitOffset>14</bitOffset>
              <bitWidth>1</bitWidth>
            </field>
            <field>
              <name>OD15</name>
              <bitOffset>15</bitOffset>
              <bitWidth>1</bitWidth>
            </field>
          </fields>
        </register>
        <register>
          <name>BSRR</name>
          <addressOffset>0x18</addressOffset>
          <size>0x20</size>
          <fields>
            <field>
              <name>BS0</name>
              <bitOffset>0</bitOffset>
              <bitWidth>1</bitWidth>
            </field>
            <field>
              <name>BS1</name>
              <bitOffset>1</bitOffset>
              <bitWidth>1</bitWidth>
            </field>
            <field>
              <name>BS2</name>
              <bitOffset>2</bitOffset>
              <bitWidth>1</bitWidth>
            </field>
            <field>
              <name>BS3</name>
              <bitOffset>3</bitOffset>
              <bitWidth>1</bitWidth>
            </field>
            <field>
              <name>BS4</name>
              <bitOffset>4</bitOffset>
              <bitWidth>1</bitWidth>
            </field>
            <field>
              <name>BS5</name>
              <bitOffset>5</bitOffset>
              <bitWidth>1</bitWidth>
            </field>
            <field>
              <name>BS6</name>
              <bitOffset>6</bitOffset>
              <bitWidth>1</bitWidth>
            </field>
            <field>
              <name>BS7</name>
              <bitOffset>7</bitOffset>
              <bitWidth>1</bitWidth>
            </field>
            <field>
              <name>BS8</name>
              <bitOffset>8</bitOffset>
              <bitWidth>1</bitWidth>
            </field>
            <field>
              <name>BS9</name>
              <bitOffset>9</bitOffset>
              <bitWidth>1</bitWidth>
            </field>
            <field>
              <name>BS10</name>
              <bitOffset>10</bitOffset>
              <bitWidth>1</bitWidth>
            </field>
            <field>
              <name>BS11</name>
              <bitOffset>11</bitOffset>
              <bitWidth>1</bitWidth>
            </field>
            <field>
              <name>BS12</name>
              <bitOffset>12</bitOffset>
              <bitWidth>1</bitWidth>
            </field>
            <field>
              <name>BS13</name>
              <bitOffset>13</bitOffset>
              <bitWidth>1</bitWidth>
            </field>
            <field>
              <name>BS14</name>
              <bitOffset>14</bitOffset>
              <bitWidth>1</bitWidth>
            </field>
            <field>
              <name>BS15</name>
              <bitOffset>15</bitOffset>
              <bitWidth>1</bitWidth>
            </field>
            <field>
              <name>BR0</name>
              <bitOffset>16</bitOffset>
              <bitWidth>1</bitWidth>
            </field>
            <field>
              <name>BR1</name>
              <bitOffset>17</bitOffset>
              <bitWidth>1</bitWidth>
            </field>
            <field>
              <name>BR2</name>
              <bitOffset>18</bitOffset>
              <bitWidth>1</bitWidth>
            </field>
            <field>
              <name>BR3</name>
              <bitOffset>19</bitOffset>
              <bitWidth>1</bitWidth>
            </field>
            <field>
              <name>BR4</name>
              <bitOffset>20</bitOffset>
              <bitWidth>1</bitWidth>
            </field>
            <field>
              <name>BR5</name>
              <bitOffset>21</bitOffset>
              <bitWidth>1</bitWidth>
            </field>
            <field>
              <name>BR6</name>
              <bitOffset>22</bitOffset>
              <bitWidth>1</bitWidth>
            </field>
            <field>
              <name>BR7</name>
              <bitOffset>23</bitOffset>
              <bitWidth>1</bitWidth>
            </field>
            <field>
              <name>BR8</name>
              <bitOffset>24</bitOffset>
              <bitWidth>1</bitWidth>
            </field>
            <field>
              <name>BR9</name>
              <bitOffset>25</bitOffset>
              <bitWidth>1</bitWidth>
            </field>
            <field>
              <name>BR10</name>
              <bitOffset>26</bitOffset>
              <bitWidth>1</bitWidth>
            </field>
            <field>
              <name>BR11</name>
              <bitOffset>27</bitOffset>
              <bitWidth>1</bitWidth>
            </field>
            <field>
              <name>BR12</name>
              <bitOffset>28</bitOffset>
              <bitWidth>1</bitWidth>
            </field>
            <field>
              <name>BR13</name>
              <bitOffset>29</bitOffset>
              <bitWidth>1</bitWidth>
            </field>
            <field>
              <name>BR14</name>
              <bitOffset>30</bitOffset>
              <bitWidth>1</bitWidth>
            </field>
            <field>
              <name>BR15</name>
              <bitOffset>31</bitOffset>
              <bitWidth>1</bitWidth>
            </field>
          </fields>
        </register>
        <register>
          <name>LCKR</name>
          <addressOffset>0x1c</addressOffset>
          <size>0x20</size>
          <fields>
            <field>
              <name>LCK0</name>
              <bitOffset>0</bitOffset>
              <bitWidth>1</bitWidth>
            </field>
            <field>
              <name>LCK1</name>
              <bitOffset>1</bitOffset>
              <bitWidth>1</bitWidth>
            </field>
            <field>
              <name>LCK2</name>
              <bitOffset>2</bitOffset>
              <bitWidth>1</bitWidth>
            </field>
            <field>
              <name>LCK3</name>
              <bitOffset>3</bitOffset>
              <bitWidth>1</bitWidth>
            </field>
            <field>
              <name>LCK4</name>
              <bitOffset>4</bitOffset>
              <bitWidth>1</bitWidth>
            </field>
            <field>
              <name>LCK5</name>
              <bitOffset>5</bitOffset>
              <bitWidth>1</bitWidth>
            </field>
            <field>
              <name>LCK6</name>
              <bitOffset>6</bitOffset>
              <bitWidth>1</bitWidth>
            </field>
            <field>
              <name>LCK7</name>
              <bitOffset>7</bitOffset>
              <bitWidth>1</bitWidth>
            </field>
            <field>
              <name>LCK8</name>
              <bitOffset>8</bitOffset>
              <bitWidth>1</bitWidth>
            </field>
            <field>
              <name>LCK9</name>
              <bitOffset>9</bitOffset>
              <bitWidth>1</bitWidth>
            </field>
            <field>
              <name>LCK10</name>
              <bitOffset>10</bitOffset>
              <bitWidth>1</bitWidth>
            </field>
            <field>
              <name>LCK11</name>
              <bitOffset>11</bitOffset>
              <bitWidth>1</bitWidth>
            </field>
            <field>
              <name>LCK12</name>
              <bitOffset>12</bitOffset>
              <bitWidth>1</bitWidth>
            </field>
            <field>
              <name>LCK13</name>
              <bitOffset>13</bitOffset>
              <bitWidth>1</bitWidth>
            </field>
            <field>
              <name>LCK14</name>
              <bitOffset>14</bitOffset>
              <bitWidth>1</bitWidth>
            </field>
            <field>
              <name>LCK15</name>
              <bitOffset>15</bitOffset>
              <bitWidth>1</bitWidth>
            </field>
            <field>
              <name>LCKK</name>
              <bitOffset>16</bitOffset>
              <bitWidth>1</bitWidth>
            </field>
          </fields>
        </register>
        <register>
          <name>AFR.0</name>
          <addressOffset>0x20</addressOffset>
          <size>0x20</size>
          <fields>
            <field>
              <name>AFSEL0</name>
              <bitOffset>0</bitOffset>
              <bitWidth>4</bitWidth>
            </field>
            <field>
              <name>AFSEL1</name>
              <bitOffset>4</bitOffset>
              <bitWidth>4</bitWidth>
            </field>
            <field>
              <name>AFSEL2</name>
              <bitOffset>8</bitOffset>
              <bitWidth>4</bitWidth>
            </field>
            <field>
              <name>AFSEL3</name>
              <bitOffset>12</bitOffset>
              <bitWidth>4</bitWidth>
            </field>
            <field>
              <name>AFSEL4</name>
              <bitOffset>16</bitOffset>
              <bitWidth>4</bitWidth>
            </field>
            <field>
              <name>AFSEL5</name>
              <bitOffset>20</bitOffset>
              <bitWidth>4</bitWidth>
            </field>
            <field>
              <name>AFSEL6</name>
              <bitOffset>24</bitOffset>
              <bitWidth>4</bitWidth>
            </field>
            <field>
              <name>AFSEL7</name>
              <bitOffset>28</bitOffset>
              <bitWidth>4</bitWidth>
            </field>
          </fields>
        </register>
        <register>
          <name>AFR.1</name>
          <addressOffset>0x24</addressOffset>
          <size>0x20</size>
          <fields>
            <field>
              <name>AFSEL8</name>
              <bitOffset>0</bitOffset>
              <bitWidth>4</bitWidth>
            </field>
            <field>
              <name>AFSEL9</name>
              <bitOffset>4</bitOffset>
              <bitWidth>4</bitWidth>
            </field>
            <field>
              <name>AFSEL10</name>
              <bitOffset>8</bitOffset>
              <bitWidth>4</bitWidth>
            </field>
            <field>
              <name>AFSEL11</name>
              <bitOffset>12</bitOffset>
              <bitWidth>4</bitWidth>
            </field>
            <field>
              <name>AFSEL12</name>
              <bitOffset>16</bitOffset>
              <bitWidth>4</bitWidth>
            </field>
            <field>
              <name>AFSEL13</name>
              <bitOffset>20</bitOffset>
              <bitWidth>4</bitWidth>
            </field>
            <field>
              <name>AFSEL14</name>
              <bitOffset>24</bitOffset>
              <bitWidth>4</bitWidth>
            </field>
            <field>
              <name>AFSEL15</name>
              <bitOffset>28</bitOffset>
              <bitWidth>4</bitWidth>
            </field>
          </fields>
        </register>
      </registers>
    </peripheral>
    <peripheral>
      <name>GPIOK</name>
      <baseAddress>0x58022800</baseAddress>
      <registers>
        <register>
          <name>MODER</name>
          <addressOffset>0x0</addressOffset>
          <size>0x20</size>
          <fields>
            <field>
              <name>MODE0</name>
              <bitOffset>0</bitOffset>
              <bitWidth>2</bitWidth>
            </field>
            <field>
              <name>MODE1</name>
              <bitOffset>2</bitOffset>
              <bitWidth>2</bitWidth>
            </field>
            <field>
              <name>MODE2</name>
              <bitOffset>4</bitOffset>
              <bitWidth>2</bitWidth>
            </field>
            <field>
              <name>MODE3</name>
              <bitOffset>6</bitOffset>
              <bitWidth>2</bitWidth>
            </field>
            <field>
              <name>MODE4</name>
              <bitOffset>8</bitOffset>
              <bitWidth>2</bitWidth>
            </field>
            <field>
              <name>MODE5</name>
              <bitOffset>10</bitOffset>
              <bitWidth>2</bitWidth>
            </field>
            <field>
              <name>MODE6</name>
              <bitOffset>12</bitOffset>
              <bitWidth>2</bitWidth>
            </field>
            <field>
              <name>MODE7</name>
              <bitOffset>14</bitOffset>
              <bitWidth>2</bitWidth>
            </field>
            <field>
              <name>MODE8</name>
              <bitOffset>16</bitOffset>
              <bitWidth>2</bitWidth>
            </field>
            <field>
              <name>MODE9</name>
              <bitOffset>18</bitOffset>
              <bitWidth>2</bitWidth>
            </field>
            <field>
              <name>MODE10</name>
              <bitOffset>20</bitOffset>
              <bitWidth>2</bitWidth>
            </field>
            <field>
              <name>MODE11</name>
              <bitOffset>22</bitOffset>
              <bitWidth>2</bitWidth>
            </field>
            <field>
              <name>MODE12</name>
              <bitOffset>24</bitOffset>
              <bitWidth>2</bitWidth>
            </field>
            <field>
              <name>MODE13</name>
              <bitOffset>26</bitOffset>
              <bitWidth>2</bitWidth>
            </field>
            <field>
              <name>MODE14</name>
              <bitOffset>28</bitOffset>
              <bitWidth>2</bitWidth>
            </field>
            <field>
              <name>MODE15</name>
              <bitOffset>30</bitOffset>
              <bitWidth>2</bitWidth>
            </field>
          </fields>
        </register>
        <register>
          <name>OTYPER</name>
          <addressOffset>0x4</addressOffset>
          <size>0x20</size>
          <fields>
            <field>
              <name>OT0</name>
              <bitOffset>0</bitOffset>
              <bitWidth>1</bitWidth>
            </field>
            <field>
              <name>OT1</name>
              <bitOffset>1</bitOffset>
              <bitWidth>1</bitWidth>
            </field>
            <field>
              <name>OT2</name>
              <bitOffset>2</bitOffset>
              <bitWidth>1</bitWidth>
            </field>
            <field>
              <name>OT3</name>
              <bitOffset>3</bitOffset>
              <bitWidth>1</bitWidth>
            </field>
            <field>
              <name>OT4</name>
              <bitOffset>4</bitOffset>
              <bitWidth>1</bitWidth>
            </field>
            <field>
              <name>OT5</name>
              <bitOffset>5</bitOffset>
              <bitWidth>1</bitWidth>
            </field>
            <field>
              <name>OT6</name>
              <bitOffset>6</bitOffset>
              <bitWidth>1</bitWidth>
            </field>
            <field>
              <name>OT7</name>
              <bitOffset>7</bitOffset>
              <bitWidth>1</bitWidth>
            </field>
            <field>
              <name>OT8</name>
              <bitOffset>8</bitOffset>
              <bitWidth>1</bitWidth>
            </field>
            <field>
              <name>OT9</name>
              <bitOffset>9</bitOffset>
              <bitWidth>1</bitWidth>
            </field>
            <field>
              <name>OT10</name>
              <bitOffset>10</bitOffset>
              <bitWidth>1</bitWidth>
            </field>
            <field>
              <name>OT11</name>
              <bitOffset>11</bitOffset>
              <bitWidth>1</bitWidth>
            </field>
            <field>
              <name>OT12</name>
              <bitOffset>12</bitOffset>
              <bitWidth>1</bitWidth>
            </field>
            <field>
              <name>OT13</name>
              <bitOffset>13</bitOffset>
              <bitWidth>1</bitWidth>
            </field>
            <field>
              <name>OT14</name>
              <bitOffset>14</bitOffset>
              <bitWidth>1</bitWidth>
            </field>
            <field>
              <name>OT15</name>
              <bitOffset>15</bitOffset>
              <bitWidth>1</bitWidth>
            </field>
          </fields>
        </register>
        <register>
          <name>OSPEEDR</name>
          <addressOffset>0x8</addressOffset>
          <size>0x20</size>
          <fields>
            <field>
              <name>OSPEED0</name>
              <bitOffset>0</bitOffset>
              <bitWidth>2</bitWidth>
            </field>
            <field>
              <name>OSPEED1</name>
              <bitOffset>2</bitOffset>
              <bitWidth>2</bitWidth>
            </field>
            <field>
              <name>OSPEED2</name>
              <bitOffset>4</bitOffset>
              <bitWidth>2</bitWidth>
            </field>
            <field>
              <name>OSPEED3</name>
              <bitOffset>6</bitOffset>
              <bitWidth>2</bitWidth>
            </field>
            <field>
              <name>OSPEED4</name>
              <bitOffset>8</bitOffset>
              <bitWidth>2</bitWidth>
            </field>
            <field>
              <name>OSPEED5</name>
              <bitOffset>10</bitOffset>
              <bitWidth>2</bitWidth>
            </field>
            <field>
              <name>OSPEED6</name>
              <bitOffset>12</bitOffset>
              <bitWidth>2</bitWidth>
            </field>
            <field>
              <name>OSPEED7</name>
              <bitOffset>14</bitOffset>
              <bitWidth>2</bitWidth>
            </field>
            <field>
              <name>OSPEED8</name>
              <bitOffset>16</bitOffset>
              <bitWidth>2</bitWidth>
            </field>
            <field>
              <name>OSPEED9</name>
              <bitOffset>18</bitOffset>
              <bitWidth>2</bitWidth>
            </field>
            <field>
              <name>OSPEED10</name>
              <bitOffset>20</bitOffset>
              <bitWidth>2</bitWidth>
            </field>
            <field>
              <name>OSPEED11</name>
              <bitOffset>22</bitOffset>
              <bitWidth>2</bitWidth>
            </field>
            <field>
              <name>OSPEED12</name>
              <bitOffset>24</bitOffset>
              <bitWidth>2</bitWidth>
            </field>
            <field>
              <name>OSPEED13</name>
              <bitOffset>26</bitOffset>
              <bitWidth>2</bitWidth>
            </field>
            <field>
              <name>OSPEED14</name>
              <bitOffset>28</bitOffset>
              <bitWidth>2</bitWidth>
            </field>
            <field>
              <name>OSPEED15</name>
              <bitOffset>30</bitOffset>
              <bitWidth>2</bitWidth>
            </field>
          </fields>
        </register>
        <register>
          <name>PUPDR</name>
          <addressOffset>0xc</addressOffset>
          <size>0x20</size>
          <fields>
            <field>
              <name>PUPD0</name>
              <bitOffset>0</bitOffset>
              <bitWidth>2</bitWidth>
            </field>
            <field>
              <name>PUPD1</name>
              <bitOffset>2</bitOffset>
              <bitWidth>2</bitWidth>
            </field>
            <field>
              <name>PUPD2</name>
              <bitOffset>4</bitOffset>
              <bitWidth>2</bitWidth>
            </field>
            <field>
              <name>PUPD3</name>
              <bitOffset>6</bitOffset>
              <bitWidth>2</bitWidth>
            </field>
            <field>
              <name>PUPD4</name>
              <bitOffset>8</bitOffset>
              <bitWidth>2</bitWidth>
            </field>
            <field>
              <name>PUPD5</name>
              <bitOffset>10</bitOffset>
              <bitWidth>2</bitWidth>
            </field>
            <field>
              <name>PUPD6</name>
              <bitOffset>12</bitOffset>
              <bitWidth>2</bitWidth>
            </field>
            <field>
              <name>PUPD7</name>
              <bitOffset>14</bitOffset>
              <bitWidth>2</bitWidth>
            </field>
            <field>
              <name>PUPD8</name>
              <bitOffset>16</bitOffset>
              <bitWidth>2</bitWidth>
            </field>
            <field>
              <name>PUPD9</name>
              <bitOffset>18</bitOffset>
              <bitWidth>2</bitWidth>
            </field>
            <field>
              <name>PUPD10</name>
              <bitOffset>20</bitOffset>
              <bitWidth>2</bitWidth>
            </field>
            <field>
              <name>PUPD11</name>
              <bitOffset>22</bitOffset>
              <bitWidth>2</bitWidth>
            </field>
            <field>
              <name>PUPD12</name>
              <bitOffset>24</bitOffset>
              <bitWidth>2</bitWidth>
            </field>
            <field>
              <name>PUPD13</name>
              <bitOffset>26</bitOffset>
              <bitWidth>2</bitWidth>
            </field>
            <field>
              <name>PUPD14</name>
              <bitOffset>28</bitOffset>
              <bitWidth>2</bitWidth>
            </field>
            <field>
              <name>PUPD15</name>
              <bitOffset>30</bitOffset>
              <bitWidth>2</bitWidth>
            </field>
          </fields>
        </register>
        <register>
          <name>IDR</name>
          <addressOffset>0x10</addressOffset>
          <size>0x20</size>
          <fields>
            <field>
              <name>ID0</name>
              <bitOffset>0</bitOffset>
              <bitWidth>1</bitWidth>
            </field>
            <field>
              <name>ID1</name>
              <bitOffset>1</bitOffset>
              <bitWidth>1</bitWidth>
            </field>
            <field>
              <name>ID2</name>
              <bitOffset>2</bitOffset>
              <bitWidth>1</bitWidth>
            </field>
            <field>
              <name>ID3</name>
              <bitOffset>3</bitOffset>
              <bitWidth>1</bitWidth>
            </field>
            <field>
              <name>ID4</name>
              <bitOffset>4</bitOffset>
              <bitWidth>1</bitWidth>
            </field>
            <field>
              <name>ID5</name>
              <bitOffset>5</bitOffset>
              <bitWidth>1</bitWidth>
            </field>
            <field>
              <name>ID6</name>
              <bitOffset>6</bitOffset>
              <bitWidth>1</bitWidth>
            </field>
            <field>
              <name>ID7</name>
              <bitOffset>7</bitOffset>
              <bitWidth>1</bitWidth>
            </field>
            <field>
              <name>ID8</name>
              <bitOffset>8</bitOffset>
              <bitWidth>1</bitWidth>
            </field>
            <field>
              <name>ID9</name>
              <bitOffset>9</bitOffset>
              <bitWidth>1</bitWidth>
            </field>
            <field>
              <name>ID10</name>
              <bitOffset>10</bitOffset>
              <bitWidth>1</bitWidth>
            </field>
            <field>
              <name>ID11</name>
              <bitOffset>11</bitOffset>
              <bitWidth>1</bitWidth>
            </field>
            <field>
              <name>ID12</name>
              <bitOffset>12</bitOffset>
              <bitWidth>1</bitWidth>
            </field>
            <field>
              <name>ID13</name>
              <bitOffset>13</bitOffset>
              <bitWidth>1</bitWidth>
            </field>
            <field>
              <name>ID14</name>
              <bitOffset>14</bitOffset>
              <bitWidth>1</bitWidth>
            </field>
            <field>
              <name>ID15</name>
              <bitOffset>15</bitOffset>
              <bitWidth>1</bitWidth>
            </field>
          </fields>
        </register>
        <register>
          <name>ODR</name>
          <addressOffset>0x14</addressOffset>
          <size>0x20</size>
          <fields>
            <field>
              <name>OD0</name>
              <bitOffset>0</bitOffset>
              <bitWidth>1</bitWidth>
            </field>
            <field>
              <name>OD1</name>
              <bitOffset>1</bitOffset>
              <bitWidth>1</bitWidth>
            </field>
            <field>
              <name>OD2</name>
              <bitOffset>2</bitOffset>
              <bitWidth>1</bitWidth>
            </field>
            <field>
              <name>OD3</name>
              <bitOffset>3</bitOffset>
              <bitWidth>1</bitWidth>
            </field>
            <field>
              <name>OD4</name>
              <bitOffset>4</bitOffset>
              <bitWidth>1</bitWidth>
            </field>
            <field>
              <name>OD5</name>
              <bitOffset>5</bitOffset>
              <bitWidth>1</bitWidth>
            </field>
            <field>
              <name>OD6</name>
              <bitOffset>6</bitOffset>
              <bitWidth>1</bitWidth>
            </field>
            <field>
              <name>OD7</name>
              <bitOffset>7</bitOffset>
              <bitWidth>1</bitWidth>
            </field>
            <field>
              <name>OD8</name>
              <bitOffset>8</bitOffset>
              <bitWidth>1</bitWidth>
            </field>
            <field>
              <name>OD9</name>
              <bitOffset>9</bitOffset>
              <bitWidth>1</bitWidth>
            </field>
            <field>
              <name>OD10</name>
              <bitOffset>10</bitOffset>
              <bitWidth>1</bitWidth>
            </field>
            <field>
              <name>OD11</name>
              <bitOffset>11</bitOffset>
              <bitWidth>1</bitWidth>
            </field>
            <field>
              <name>OD12</name>
              <bitOffset>12</bitOffset>
              <bitWidth>1</bitWidth>
            </field>
            <field>
              <name>OD13</name>
              <bitOffset>13</bitOffset>
              <bitWidth>1</bitWidth>
            </field>
            <field>
              <name>OD14</name>
              <bitOffset>14</bitOffset>
              <bitWidth>1</bitWidth>
            </field>
            <field>
              <name>OD15</name>
              <bitOffset>15</bitOffset>
              <bitWidth>1</bitWidth>
            </field>
          </fields>
        </register>
        <register>
          <name>BSRR</name>
          <addressOffset>0x18</addressOffset>
          <size>0x20</size>
          <fields>
            <field>
              <name>BS0</name>
              <bitOffset>0</bitOffset>
              <bitWidth>1</bitWidth>
            </field>
            <field>
              <name>BS1</name>
              <bitOffset>1</bitOffset>
              <bitWidth>1</bitWidth>
            </field>
            <field>
              <name>BS2</name>
              <bitOffset>2</bitOffset>
              <bitWidth>1</bitWidth>
            </field>
            <field>
              <name>BS3</name>
              <bitOffset>3</bitOffset>
              <bitWidth>1</bitWidth>
            </field>
            <field>
              <name>BS4</name>
              <bitOffset>4</bitOffset>
              <bitWidth>1</bitWidth>
            </field>
            <field>
              <name>BS5</name>
              <bitOffset>5</bitOffset>
              <bitWidth>1</bitWidth>
            </field>
            <field>
              <name>BS6</name>
              <bitOffset>6</bitOffset>
              <bitWidth>1</bitWidth>
            </field>
            <field>
              <name>BS7</name>
              <bitOffset>7</bitOffset>
              <bitWidth>1</bitWidth>
            </field>
            <field>
              <name>BS8</name>
              <bitOffset>8</bitOffset>
              <bitWidth>1</bitWidth>
            </field>
            <field>
              <name>BS9</name>
              <bitOffset>9</bitOffset>
              <bitWidth>1</bitWidth>
            </field>
            <field>
              <name>BS10</name>
              <bitOffset>10</bitOffset>
              <bitWidth>1</bitWidth>
            </field>
            <field>
              <name>BS11</name>
              <bitOffset>11</bitOffset>
              <bitWidth>1</bitWidth>
            </field>
            <field>
              <name>BS12</name>
              <bitOffset>12</bitOffset>
              <bitWidth>1</bitWidth>
            </field>
            <field>
              <name>BS13</name>
              <bitOffset>13</bitOffset>
              <bitWidth>1</bitWidth>
            </field>
            <field>
              <name>BS14</name>
              <bitOffset>14</bitOffset>
              <bitWidth>1</bitWidth>
            </field>
            <field>
              <name>BS15</name>
              <bitOffset>15</bitOffset>
              <bitWidth>1</bitWidth>
            </field>
            <field>
              <name>BR0</name>
              <bitOffset>16</bitOffset>
              <bitWidth>1</bitWidth>
            </field>
            <field>
              <name>BR1</name>
              <bitOffset>17</bitOffset>
              <bitWidth>1</bitWidth>
            </field>
            <field>
              <name>BR2</name>
              <bitOffset>18</bitOffset>
              <bitWidth>1</bitWidth>
            </field>
            <field>
              <name>BR3</name>
              <bitOffset>19</bitOffset>
              <bitWidth>1</bitWidth>
            </field>
            <field>
              <name>BR4</name>
              <bitOffset>20</bitOffset>
              <bitWidth>1</bitWidth>
            </field>
            <field>
              <name>BR5</name>
              <bitOffset>21</bitOffset>
              <bitWidth>1</bitWidth>
            </field>
            <field>
              <name>BR6</name>
              <bitOffset>22</bitOffset>
              <bitWidth>1</bitWidth>
            </field>
            <field>
              <name>BR7</name>
              <bitOffset>23</bitOffset>
              <bitWidth>1</bitWidth>
            </field>
            <field>
              <name>BR8</name>
              <bitOffset>24</bitOffset>
              <bitWidth>1</bitWidth>
            </field>
            <field>
              <name>BR9</name>
              <bitOffset>25</bitOffset>
              <bitWidth>1</bitWidth>
            </field>
            <field>
              <name>BR10</name>
              <bitOffset>26</bitOffset>
              <bitWidth>1</bitWidth>
            </field>
            <field>
              <name>BR11</name>
              <bitOffset>27</bitOffset>
              <bitWidth>1</bitWidth>
            </field>
            <field>
              <name>BR12</name>
              <bitOffset>28</bitOffset>
              <bitWidth>1</bitWidth>
            </field>
            <field>
              <name>BR13</name>
              <bitOffset>29</bitOffset>
              <bitWidth>1</bitWidth>
            </field>
            <field>
              <name>BR14</name>
              <bitOffset>30</bitOffset>
              <bitWidth>1</bitWidth>
            </field>
            <field>
              <name>BR15</name>
              <bitOffset>31</bitOffset>
              <bitWidth>1</bitWidth>
            </field>
          </fields>
        </register>
        <register>
          <name>LCKR</name>
          <addressOffset>0x1c</addressOffset>
          <size>0x20</size>
          <fields>
            <field>
              <name>LCK0</name>
              <bitOffset>0</bitOffset>
              <bitWidth>1</bitWidth>
            </field>
            <field>
              <name>LCK1</name>
              <bitOffset>1</bitOffset>
              <bitWidth>1</bitWidth>
            </field>
            <field>
              <name>LCK2</name>
              <bitOffset>2</bitOffset>
              <bitWidth>1</bitWidth>
            </field>
            <field>
              <name>LCK3</name>
              <bitOffset>3</bitOffset>
              <bitWidth>1</bitWidth>
            </field>
            <field>
              <name>LCK4</name>
              <bitOffset>4</bitOffset>
              <bitWidth>1</bitWidth>
            </field>
            <field>
              <name>LCK5</name>
              <bitOffset>5</bitOffset>
              <bitWidth>1</bitWidth>
            </field>
            <field>
              <name>LCK6</name>
              <bitOffset>6</bitOffset>
              <bitWidth>1</bitWidth>
            </field>
            <field>
              <name>LCK7</name>
              <bitOffset>7</bitOffset>
              <bitWidth>1</bitWidth>
            </field>
            <field>
              <name>LCK8</name>
              <bitOffset>8</bitOffset>
              <bitWidth>1</bitWidth>
            </field>
            <field>
              <name>LCK9</name>
              <bitOffset>9</bitOffset>
              <bitWidth>1</bitWidth>
            </field>
            <field>
              <name>LCK10</name>
              <bitOffset>10</bitOffset>
              <bitWidth>1</bitWidth>
            </field>
            <field>
              <name>LCK11</name>
              <bitOffset>11</bitOffset>
              <bitWidth>1</bitWidth>
            </field>
            <field>
              <name>LCK12</name>
              <bitOffset>12</bitOffset>
              <bitWidth>1</bitWidth>
            </field>
            <field>
              <name>LCK13</name>
              <bitOffset>13</bitOffset>
              <bitWidth>1</bitWidth>
            </field>
            <field>
              <name>LCK14</name>
              <bitOffset>14</bitOffset>
              <bitWidth>1</bitWidth>
            </field>
            <field>
              <name>LCK15</name>
              <bitOffset>15</bitOffset>
              <bitWidth>1</bitWidth>
            </field>
            <field>
              <name>LCKK</name>
              <bitOffset>16</bitOffset>
              <bitWidth>1</bitWidth>
            </field>
          </fields>
        </register>
        <register>
          <name>AFR.0</name>
          <addressOffset>0x20</addressOffset>
          <size>0x20</size>
          <fields>
            <field>
              <name>AFSEL0</name>
              <bitOffset>0</bitOffset>
              <bitWidth>4</bitWidth>
            </field>
            <field>
              <name>AFSEL1</name>
              <bitOffset>4</bitOffset>
              <bitWidth>4</bitWidth>
            </field>
            <field>
              <name>AFSEL2</name>
              <bitOffset>8</bitOffset>
              <bitWidth>4</bitWidth>
            </field>
            <field>
              <name>AFSEL3</name>
              <bitOffset>12</bitOffset>
              <bitWidth>4</bitWidth>
            </field>
            <field>
              <name>AFSEL4</name>
              <bitOffset>16</bitOffset>
              <bitWidth>4</bitWidth>
            </field>
            <field>
              <name>AFSEL5</name>
              <bitOffset>20</bitOffset>
              <bitWidth>4</bitWidth>
            </field>
            <field>
              <name>AFSEL6</name>
              <bitOffset>24</bitOffset>
              <bitWidth>4</bitWidth>
            </field>
            <field>
              <name>AFSEL7</name>
              <bitOffset>28</bitOffset>
              <bitWidth>4</bitWidth>
            </field>
          </fields>
        </register>
        <register>
          <name>AFR.1</name>
          <addressOffset>0x24</addressOffset>
          <size>0x20</size>
          <fields>
            <field>
              <name>AFSEL8</name>
              <bitOffset>0</bitOffset>
              <bitWidth>4</bitWidth>
            </field>
            <field>
              <name>AFSEL9</name>
              <bitOffset>4</bitOffset>
              <bitWidth>4</bitWidth>
            </field>
            <field>
              <name>AFSEL10</name>
              <bitOffset>8</bitOffset>
              <bitWidth>4</bitWidth>
            </field>
            <field>
              <name>AFSEL11</name>
              <bitOffset>12</bitOffset>
              <bitWidth>4</bitWidth>
            </field>
            <field>
              <name>AFSEL12</name>
              <bitOffset>16</bitOffset>
              <bitWidth>4</bitWidth>
            </field>
            <field>
              <name>AFSEL13</name>
              <bitOffset>20</bitOffset>
              <bitWidth>4</bitWidth>
            </field>
            <field>
              <name>AFSEL14</name>
              <bitOffset>24</bitOffset>
              <bitWidth>4</bitWidth>
            </field>
            <field>
              <name>AFSEL15</name>
              <bitOffset>28</bitOffset>
              <bitWidth>4</bitWidth>
            </field>
          </fields>
        </register>
      </registers>
    </peripheral>
    <peripheral>
      <name>RCC</name>
      <baseAddress>0x58024400</baseAddress>
      <registers>
        <register>
          <name>CR</name>
          <addressOffset>0x0</addressOffset>
          <size>0x20</size>
          <fields>
            <field>
              <name>HSION</name>
              <bitOffset>0</bitOffset>
              <bitWidth>1</bitWidth>
            </field>
            <field>
              <name>HSIKERON</name>
              <bitOffset>1</bitOffset>
              <bitWidth>1</bitWidth>
            </field>
            <field>
              <name>HSIRDY</name>
              <bitOffset>2</bitOffset>
              <bitWidth>1</bitWidth>
            </field>
            <field>
              <name>HSIDIV</name>
              <bitOffset>3</bitOffset>
              <bitWidth>2</bitWidth>
            </field>
            <field>
              <name>HSIDIVF</name>
              <bitOffset>5</bitOffset>
              <bitWidth>1</bitWidth>
            </field>
            <field>
              <name>CSION</name>
              <bitOffset>7</bitOffset>
              <bitWidth>1</bitWidth>
            </field>
            <field>
              <name>CSIRDY</name>
              <bitOffset>8</bitOffset>
              <bitWidth>1</bitWidth>
            </field>
            <field>
              <name>CSIKERON</name>
              <bitOffset>9</bitOffset>
              <bitWidth>1</bitWidth>
            </field>
            <field>
              <name>HSI48ON</name>
              <bitOffset>12</bitOffset>
              <bitWidth>1</bitWidth>
            </field>
            <field>
              <name>HSI48RDY</name>
              <bitOffset>13</bitOffset>
              <bitWidth>1</bitWidth>
            </field>
            <field>
              <name>D1CKRDY</name>
              <bitOffset>14</bitOffset>
              <bitWidth>1</bitWidth>
            </field>
            <field>
              <name>D2CKRDY</name>
              <bitOffset>15</bitOffset>
              <bitWidth>1</bitWidth>
            </field>
            <field>
              <name>HSEON</name>
              <bitOffset>16</bitOffset>
              <bitWidth>1</bitWidth>
            </field>
            <field>
              <name>HSERDY</name>
              <bitOffset>17</bitOffset>
              <bitWidth>1</bitWidth>
            </field>
            <field>
              <name>HSEBYP</name>
              <bitOffset>18</bitOffset>
              <bitWidth>1</bitWidth>
            </field>
            <field>
              <name>CSSHSEON</name>
              <bitOffset>19</bitOffset>
              <bitWidth>1</bitWidth>
            </field>
            <field>
              <name>PLLON</name>
              <bitOffset>24</bitOffset>
              <bitWidth>1</bitWidth>
            </field>
            <field>
              <name>PLLRDY</name>
              <bitOffset>25</bitOffset>
              <bitWidth>1</bitWidth>
            </field>
            <field>
              <name>PLL2ON</name>
              <bitOffset>26</bitOffset>
              <bitWidth>1</bitWidth>
            </field>
            <field>
              <name>PLL2RDY</name>
              <bitOffset>27</bitOffset>
              <bitWidth>1</bitWidth>
            </field>
            <field>
              <name>PLL3ON</name>
              <bitOffset>28</bitOffset>
              <bitWidth>1</bitWidth>
            </field>
            <field>
              <name>PLL3RDY</name>
              <bitOffset>29</bitOffset>
              <bitWidth>1</bitWidth>
            </field>
          </fields>
        </register>
        <register>
          <name>HSICFGR</name>
          <addressOffset>0x4</addressOffset>
          <size>0x20</size>
          <fields>
            <field>
              <name>HSICAL</name>
              <bitOffset>0</bitOffset>
              <bitWidth>12</bitWidth>
            </field>
            <field>
              <name>HSITRIM</name>
              <bitOffset>24</bitOffset>
              <bitWidth>7</bitWidth>
            </field>
          </fields>
        </register>
        <register>
          <name>CRRCR</name>
          <addressOffset>0x8</addressOffset>
          <size>0x20</size>
          <fields>
            <field>
              <name>HSI48CAL</name>
              <bitOffset>0</bitOffset>
              <bitWidth>10</bitWidth>
            </field>
          </fields>
        </register>
        <register>
          <name>CSICFGR</name>
          <addressOffset>0xc</addressOffset>
          <size>0x20</size>
          <fields>
            <field>
              <name>CSICAL</name>
              <bitOffset>0</bitOffset>
              <bitWidth>8</bitWidth>
            </field>
            <field>
              <name>CSITRIM</name>
              <bitOffset>24</bitOffset>
              <bitWidth>6</bitWidth>
            </field>
          </fields>
        </register>
        <register>
          <name>CFGR</name>
          <addressOffset>0x10</addressOffset>
          <size>0x20</size>
          <fields>
            <field>
              <name>SW</name>
              <bitOffset>0</bitOffset>
              <bitWidth>3</bitWidth>
            </field>
            <field>
              <name>SWS</name>
              <bitOffset>3</bitOffset>
              <bitWidth>3</bitWidth>
            </field>
            <field>
              <name>STOPWUCK</name>
              <bitOffset>6</bitOffset>
              <bitWidth>1</bitWidth>
            </field>
            <field>
              <name>STOPKERWUCK</name>
              <bitOffset>7</bitOffset>
              <bitWidth>1</bitWidth>
            </field>
            <field>
              <name>RTCPRE</name>
              <bitOffset>8</bitOffset>
              <bitWidth>6</bitWidth>
            </field>
            <field>
              <name>HRTIMSEL</name>
              <bitOffset>14</bitOffset>
              <bitWidth>1</bitWidth>
            </field>
            <field>
              <name>TIMPRE</name>
              <bitOffset>15</bitOffset>
              <bitWidth>1</bitWidth>
            </field>
            <field>
              <name>MCO1PRE</name>
              <bitOffset>18</bitOffset>
              <bitWidth>4</bitWidth>
            </field>
            <field>
              <name>MCO1</name>
              <bitOffset>22</bitOffset>
              <bitWidth>3</bitWidth>
            </field>
            <field>
              <name>MCO2PRE</name>
              <bitOffset>25</bitOffset>
              <bitWidth>4</bitWidth>
            </field>
            <field>
              <name>MCO2</name>
              <bitOffset>29</bitOffset>
              <bitWidth>3</bitWidth>
            </field>
          </fields>
        </register>
        <register>
          <name>D1CFGR</name>
          <addressOffset>0x18</addressOffset>
          <size>0x20</size>
          <fields>
            <field>
              <name>HPRE_DIV512</name>
              <bitOffset>0</bitOffset>
              <bitWidth>4</bitWidth>
            </field>
            <field>
              <name>HPRE_DIV8</name>
              <bitOffset>1</bitOffset>
              <bitWidth>3</bitWidth>
            </field>
            <field>
              <name>HPRE_DIV64</name>
              <bitOffset>2</bitOffset>
              <bitWidth>2</bitWidth>
            </field>
            <field>
              <name>HPRE_DIV2</name>
              <bitOffset>3</bitOffset>
              <bitWidth>1</bitWidth>
            </field>
            <field>
              <name>D1PPRE_DIV4</name>
              <bitOffset>4</bitOffset>
              <bitWidth>3</bitWidth>
            </field>
            <field>
              <name>D1PPRE_DIV8</name>
              <bitOffset>5</bitOffset>
              <bitWidth>2</bitWidth>
            </field>
            <field>
              <name>D1PPRE_DIV2</name>
              <bitOffset>6</bitOffset>
              <bitWidth>1</bitWidth>
            </field>
            <field>
              <name>D1CPRE_DIV512</name>
              <bitOffset>8</bitOffset>
              <bitWidth>4</bitWidth>
            </field>
            <field>
              <name>D1CPRE_DIV8</name>
              <bitOffset>9</bitOffset>
              <bitWidth>3</bitWidth>
            </field>
            <field>
              <name>D1CPRE_DIV64</name>
              <bitOffset>10</bitOffset>
              <bitWidth>2</bitWidth>
            </field>
            <field>
              <name>D1CPRE_DIV2</name>
              <bitOffset>11</bitOffset>
              <bitWidth>1</bitWidth>
            </field>
          </fields>
        </register>
        <register>
          <name>D2CFGR</name>
          <addressOffset>0x1c</addressOffset>
          <size>0x20</size>
          <fields>
            <field>
              <name>D2PPRE1_DIV4</name>
              <bitOffset>4</bitOffset>
              <bitWidth>3</bitWidth>
            </field>
            <field>
              <name>D2PPRE1_DIV8</name>
              <bitOffset>5</bitOffset>
              <bitWidth>2</bitWidth>
            </field>
            <field>
              <name>D2PPRE1_DIV2</name>
              <bitOffset>6</bitOffset>
              <bitWidth>1</bitWidth>
            </field>
            <field>
              <name>D2PPRE2_DIV4</name>
              <bitOffset>8</bitOffset>
              <bitWidth>3</bitWidth>
            </field>
            <field>
              <name>D2PPRE2_DIV8</name>
              <bitOffset>9</bitOffset>
              <bitWidth>2</bitWidth>
            </field>
            <field>
              <name>D2PPRE2_DIV2</name>
              <bitOffset>10</bitOffset>
              <bitWidth>1</bitWidth>
            </field>
          </fields>
        </register>
        <register>
          <name>D3CFGR</name>
          <addressOffset>0x20</addressOffset>
          <size>0x20</size>
          <fields>
            <field>
              <name>D3PPRE_DIV4</name>
              <bitOffset>4</bitOffset>
              <bitWidth>3</bitWidth>
            </field>
            <field>
              <name>D3PPRE_DIV8</name>
              <bitOffset>5</bitOffset>
              <bitWidth>2</bitWidth>
            </field>
            <field>
              <name>D3PPRE_DIV2</name>
              <bitOffset>6</bitOffset>
              <bitWidth>1</bitWidth>
            </field>
          </fields>
        </register>
        <register>
          <name>PLLCKSELR</name>
          <addressOffset>0x28</addressOffset>
          <size>0x20</size>
          <fields>
            <field>
              <name>PLLSRC_NONE</name>
              <bitOffset>0</bitOffset>
              <bitWidth>2</bitWidth>
            </field>
            <field>
              <name>PLLSRC_HSE</name>
              <bitOffset>1</bitOffset>
              <bitWidth>1</bitWidth>
            </field>
            <field>
              <name>DIVM1</name>
              <bitOffset>4</bitOffset>
              <bitWidth>6</bitWidth>
            </field>
            <field>
              <name>DIVM2</name>
              <bitOffset>12</bitOffset>
              <bitWidth>6</bitWidth>
            </field>
            <field>
              <name>DIVM3</name>
              <bitOffset>20</bitOffset>
              <bitWidth>6</bitWidth>
            </field>
          </fields>
        </register>
        <register>
          <name>PLLCFGR</name>
          <addressOffset>0x2c</addressOffset>
          <size>0x20</size>
          <fields>
            <field>
              <name>PLL1FRACEN</name>
              <bitOffset>0</bitOffset>
              <bitWidth>1</bitWidth>
            </field>
            <field>
              <name>PLL1VCOSEL</name>
              <bitOffset>1</bitOffset>
              <bitWidth>1</bitWidth>
            </field>
            <field>
              <name>PLL1RGE</name>
              <bitOffset>2</bitOffset>
              <bitWidth>2</bitWidth>
            </field>
            <field>
              <name>PLL2FRACEN</name>
              <bitOffset>4</bitOffset>
              <bitWidth>1</bitWidth>
            </field>
            <field>
              <name>PLL2VCOSEL</name>
              <bitOffset>5</bitOffset>
              <bitWidth>1</bitWidth>
            </field>
            <field>
              <name>PLL2RGE</name>
              <bitOffset>6</bitOffset>
              <bitWidth>2</bitWidth>
            </field>
            <field>
              <name>PLL3FRACEN</name>
              <bitOffset>8</bitOffset>
              <bitWidth>1</bitWidth>
            </field>
            <field>
              <name>PLL3VCOSEL</name>
              <bitOffset>9</bitOffset>
              <bitWidth>1</bitWidth>
            </field>
            <field>
              <name>PLL3RGE</name>
              <bitOffset>10</bitOffset>
              <bitWidth>2</bitWidth>
            </field>
            <field>
              <name>DIVP1EN</name>
              <bitOffset>16</bitOffset>
              <bitWidth>1</bitWidth>
            </field>
            <field>
              <name>DIVQ1EN</name>
              <bitOffset>17</bitOffset>
              <bitWidth>1</bitWidth>
            </field>
            <field>
              <name>DIVR1EN</name>
              <bitOffset>18</bitOffset>
              <bitWidth>1</bitWidth>
            </field>
            <field>
              <name>DIVP2EN</name>
              <bitOffset>19</bitOffset>
              <bitWidth>1</bitWidth>
            </field>
            <field>
              <name>DIVQ2EN</name>
              <bitOffset>20</bitOffset>
              <bitWidth>1</bitWidth>
            </field>
            <field>
              <name>DIVR2EN</name>
              <bitOffset>21</bitOffset>
              <bitWidth>1</bitWidth>
            </field>
            <field>
              <name>DIVP3EN</name>
              <bitOffset>22</bitOffset>
              <bitWidth>1</bitWidth>
            </field>
            <field>
              <name>DIVQ3EN</name>
              <bitOffset>23</bitOffset>
              <bitWidth>1</bitWidth>
            </field>
            <field>
              <name>DIVR3EN</name>
              <bitOffset>24</bitOffset>
              <bitWidth>1</bitWidth>
            </field>
          </fields>
        </register>
        <register>
          <name>PLL1DIVR</name>
          <addressOffset>0x30</addressOffset>
          <size>0x20</size>
          <fields>
            <field>
              <name>N1</name>
              <bitOffset>0</bitOffset>
              <bitWidth>9</bitWidth>
            </field>
            <field>
              <name>P1</name>
              <bitOffset>9</bitOffset>
              <bitWidth>7</bitWidth>
            </field>
            <field>
              <name>Q1</name>
              <bitOffset>16</bitOffset>
              <bitWidth>7</bitWidth>
            </field>
            <field>
              <name>R1</name>
              <bitOffset>24</bitOffset>
              <bitWidth>7</bitWidth>
            </field>
          </fields>
        </register>
        <register>
          <name>PLL1FRACR</name>
          <addressOffset>0x34</addressOffset>
          <size>0x20</size>
          <fields>
            <field>
              <name>FRACN1</name>
              <bitOffset>3</bitOffset>
              <bitWidth>13</bitWidth>
            </field>
          </fields>
        </register>
        <register>
          <name>PLL2DIVR</name>
          <addressOffset>0x38</addressOffset>
          <size>0x20</size>
          <fields>
            <field>
              <name>N2</name>
              <bitOffset>0</bitOffset>
              <bitWidth>9</bitWidth>
            </field>
            <field>
              <name>P2</name>
              <bitOffset>9</bitOffset>
              <bitWidth>7</bitWidth>
            </field>
            <field>
              <name>Q2</name>
              <bitOffset>16</bitOffset>
              <bitWidth>7</bitWidth>
            </field>
            <field>
              <name>R2</name>
              <bitOffset>24</bitOffset>
              <bitWidth>7</bitWidth>
            </field>
          </fields>
        </register>
        <register>
          <name>PLL2FRACR</name>
          <addressOffset>0x3c</addressOffset>
          <size>0x20</size>
          <fields>
            <field>
              <name>FRACN2</name>
              <bitOffset>3</bitOffset>
              <bitWidth>13</bitWidth>
            </field>
          </fields>
        </register>
        <register>
          <name>PLL3DIVR</name>
          <addressOffset>0x40</addressOffset>
          <size>0x20</size>
          <fields>
            <field>
              <name>N3</name>
              <bitOffset>0</bitOffset>
              <bitWidth>9</bitWidth>
            </field>
            <field>
              <name>P3</name>
              <bitOffset>9</bitOffset>
              <bitWidth>7</bitWidth>
            </field>
            <field>
              <name>Q3</name>
              <bitOffset>16</bitOffset>
              <bitWidth>7</bitWidth>
            </field>
            <field>
              <name>R3</name>
              <bitOffset>24</bitOffset>
              <bitWidth>7</bitWidth>
            </field>
          </fields>
        </register>
        <register>
          <name>PLL3FRACR</name>
          <addressOffset>0x44</addressOffset>
          <size>0x20</size>
          <fields>
            <field>
              <name>FRACN3</name>
              <bitOffset>3</bitOffset>
              <bitWidth>13</bitWidth>
            </field>
          </fields>
        </register>
        <register>
          <name>D1CCIPR</name>
          <addressOffset>0x4c</addressOffset>
          <size>0x20</size>
          <fields>
            <field>
              <name>FMCSEL</name>
              <bitOffset>0</bitOffset>
              <bitWidth>2</bitWidth>
            </field>
            <field>
              <name>QSPISEL</name>
              <bitOffset>4</bitOffset>
              <bitWidth>2</bitWidth>
            </field>
            <field>
              <name>DSISRC</name>
              <bitOffset>8</bitOffset>
              <bitWidth>1</bitWidth>
            </field>
            <field>
              <name>SDMMCSEL</name>
              <bitOffset>16</bitOffset>
              <bitWidth>1</bitWidth>
            </field>
            <field>
              <name>CKPERSEL</name>
              <bitOffset>28</bitOffset>
              <bitWidth>2</bitWidth>
            </field>
          </fields>
        </register>
        <register>
          <name>D2CCIP1R</name>
          <addressOffset>0x50</addressOffset>
          <size>0x20</size>
          <fields>
            <field>
              <name>SAI1SEL</name>
              <bitOffset>0</bitOffset>
              <bitWidth>3</bitWidth>
            </field>
            <field>
              <name>SAI23SEL</name>
              <bitOffset>6</bitOffset>
              <bitWidth>3</bitWidth>
            </field>
            <field>
              <name>SPI123SEL</name>
              <bitOffset>12</bitOffset>
              <bitWidth>3</bitWidth>
            </field>
            <field>
              <name>SPI45SEL</name>
              <bitOffset>16</bitOffset>
              <bitWidth>3</bitWidth>
            </field>
            <field>
              <name>SPDIFSEL</name>
              <bitOffset>20</bitOffset>
              <bitWidth>2</bitWidth>
            </field>
            <field>
              <name>DFSDM1SEL</name>
              <bitOffset>24</bitOffset>
              <bitWidth>1</bitWidth>
            </field>
            <field>
              <name>FDCANSEL</name>
              <bitOffset>28</bitOffset>
              <bitWidth>2</bitWidth>
            </field>
            <field>
              <name>SWPSEL</name>
              <bitOffset>31</bitOffset>
              <bitWidth>1</bitWidth>
            </field>
          </fields>
        </register>
        <register>
          <name>D2CCIP2R</name>
          <addressOffset>0x54</addressOffset>
          <size>0x20</size>
          <fields>
            <field>
              <name>USART28SEL</name>
              <bitOffset>0</bitOffset>
              <bitWidth>3</bitWidth>
            </field>
            <field>
              <name>USART16SEL</name>
              <bitOffset>3</bitOffset>
              <bitWidth>3</bitWidth>
            </field>
            <field>
              <name>RNGSEL</name>
              <bitOffset>8</bitOffset>
              <bitWidth>2</bitWidth>
            </field>
            <field>
              <name>I2C123SEL</name>
              <bitOffset>12</bitOffset>
              <bitWidth>2</bitWidth>
            </field>
            <field>
              <name>USBSEL</name>
              <bitOffset>20</bitOffset>
              <bitWidth>2</bitWidth>
            </field>
            <field>
              <name>CECSEL</name>
              <bitOffset>22</bitOffset>
              <bitWidth>2</bitWidth>
            </field>
            <field>
              <name>LPTIM1SEL</name>
              <bitOffset>28</bitOffset>
              <bitWidth>3</bitWidth>
            </field>
          </fields>
        </register>
        <register>
          <name>D3CCIPR</name>
          <addressOffset>0x58</addressOffset>
          <size>0x20</size>
          <fields>
            <field>
              <name>LPUART1SEL</name>
              <bitOffset>0</bitOffset>
              <bitWidth>3</bitWidth>
            </field>
            <field>
              <name>I2C4SEL</name>
              <bitOffset>8</bitOffset>
              <bitWidth>2</bitWidth>
            </field>
            <field>
              <name>LPTIM2SEL</name>
              <bitOffset>10</bitOffset>
              <bitWidth>3</bitWidth>
            </field>
            <field>
              <name>LPTIM345SEL</name>
              <bitOffset>13</bitOffset>
              <bitWidth>3</bitWidth>
            </field>
            <field>
              <name>ADCSEL</name>
              <bitOffset>16</bitOffset>
              <bitWidth>2</bitWidth>
            </field>
            <field>
              <name>SAI4ASEL</name>
              <bitOffset>21</bitOffset>
              <bitWidth>3</bitWidth>
            </field>
            <field>
              <name>SAI4BSEL</name>
              <bitOffset>24</bitOffset>
              <bitWidth>3</bitWidth>
            </field>
            <field>
              <name>SPI6SEL</name>
              <bitOffset>28</bitOffset>
              <bitWidth>3</bitWidth>
            </field>
          </fields>
        </register>
        <register>
          <name>CIER</name>
          <addressOffset>0x60</addressOffset>
          <size>0x20</size>
          <fields>
            <field>
              <name>LSIRDYIE</name>
              <bitOffset>0</bitOffset>
              <bitWidth>1</bitWidth>
            </field>
            <field>
              <name>LSERDYIE</name>
              <bitOffset>1</bitOffset>
              <bitWidth>1</bitWidth>
            </field>
            <field>
              <name>HSIRDYIE</name>
              <bitOffset>2</bitOffset>
              <bitWidth>1</bitWidth>
            </field>
            <field>
              <name>HSERDYIE</name>
              <bitOffset>3</bitOffset>
              <bitWidth>1</bitWidth>
            </field>
            <field>
              <name>CSIRDYIE</name>
              <bitOffset>4</bitOffset>
              <bitWidth>1</bitWidth>
            </field>
            <field>
              <name>HSI48RDYIE</name>
              <bitOffset>5</bitOffset>
              <bitWidth>1</bitWidth>
            </field>
            <field>
              <name>PLL1RDYIE</name>
              <bitOffset>6</bitOffset>
              <bitWidth>1</bitWidth>
            </field>
            <field>
              <name>PLL2RDYIE</name>
              <bitOffset>7</bitOffset>
              <bitWidth>1</bitWidth>
            </field>
            <field>
              <name>PLL3RDYIE</name>
              <bitOffset>8</bitOffset>
              <bitWidth>1</bitWidth>
            </field>
            <field>
              <name>LSECSSIE</name>
              <bitOffset>9</bitOffset>
              <bitWidth>1</bitWidth>
            </field>
          </fields>
        </register>
        <register>
          <name>CIFR</name>
          <addressOffset>0x64</addressOffset>
          <size>0x20</size>
          <fields>
            <field>
              <name>LSIRDYF</name>
              <bitOffset>0</bitOffset>
              <bitWidth>1</bitWidth>
            </field>
            <field>
              <name>LSERDYF</name>
              <bitOffset>1</bitOffset>
              <bitWidth>1</bitWidth>
            </field>
            <field>
              <name>HSIRDYF</name>
              <bitOffset>2</bitOffset>
              <bitWidth>1</bitWidth>
            </field>
            <field>
              <name>HSERDYF</name>
              <bitOffset>3</bitOffset>
              <bitWidth>1</bitWidth>
            </field>
            <field>
              <name>CSIRDYF</name>
              <bitOffset>4</bitOffset>
              <bitWidth>1</bitWidth>
            </field>
            <field>
              <name>HSI48RDYF</name>
              <bitOffset>5</bitOffset>
              <bitWidth>1</bitWidth>
            </field>
            <field>
              <name>PLLRDYF</name>
              <bitOffset>6</bitOffset>
              <bitWidth>1</bitWidth>
            </field>
            <field>
              <name>PLL2RDYF</name>
              <bitOffset>7</bitOffset>
              <bitWidth>1</bitWidth>
            </field>
            <field>
              <name>PLL3RDYF</name>
              <bitOffset>8</bitOffset>
              <bitWidth>1</bitWidth>
            </field>
            <field>
              <name>LSECSSF</name>
              <bitOffset>9</bitOffset>
              <bitWidth>1</bitWidth>
            </field>
            <field>
              <name>HSECSSF</name>
              <bitOffset>10</bitOffset>
              <bitWidth>1</bitWidth>
            </field>
          </fields>
        </register>
        <register>
          <name>CICR</name>
          <addressOffset>0x68</addressOffset>
          <size>0x20</size>
          <fields>
            <field>
              <name>LSIRDYC</name>
              <bitOffset>0</bitOffset>
              <bitWidth>1</bitWidth>
            </field>
            <field>
              <name>LSERDYC</name>
              <bitOffset>1</bitOffset>
              <bitWidth>1</bitWidth>
            </field>
            <field>
              <name>HSIRDYC</name>
              <bitOffset>2</bitOffset>
              <bitWidth>1</bitWidth>
            </field>
            <field>
              <name>HSERDYC</name>
              <bitOffset>3</bitOffset>
              <bitWidth>1</bitWidth>
            </field>
            <field>
              <name>CSIRDYC</name>
              <bitOffset>4</bitOffset>
              <bitWidth>1</bitWidth>
            </field>
            <field>
              <name>HSI48RDYC</name>
              <bitOffset>5</bitOffset>
              <bitWidth>1</bitWidth>
            </field>
            <field>
              <name>PLLRDYC</name>
              <bitOffset>6</bitOffset>
              <bitWidth>1</bitWidth>
            </field>
            <field>
              <name>PLL2RDYC</name>
              <bitOffset>7</bitOffset>
              <bitWidth>1</bitWidth>
            </field>
            <field>
              <name>PLL3RDYC</name>
              <bitOffset>8</bitOffset>
              <bitWidth>1</bitWidth>
            </field>
            <field>
              <name>LSECSSC</name>
              <bitOffset>9</bitOffset>
              <bitWidth>1</bitWidth>
            </field>
            <field>
              <name>HSECSSC</name>
              <bitOffset>10</bitOffset>
              <bitWidth>1</bitWidth>
            </field>
          </fields>
        </register>
        <register>
          <name>BDCR</name>
          <addressOffset>0x70</addressOffset>
          <size>0x20</size>
          <fields>
            <field>
              <name>LSEON</name>
              <bitOffset>0</bitOffset>
              <bitWidth>1</bitWidth>
            </field>
            <field>
              <name>LSERDY</name>
              <bitOffset>1</bitOffset>
              <bitWidth>1</bitWidth>
            </field>
            <field>
              <name>LSEBYP</name>
              <bitOffset>2</bitOffset>
              <bitWidth>1</bitWidth>
            </field>
            <field>
              <name>LSEDRV</name>
              <bitOffset>3</bitOffset>
              <bitWidth>2</bitWidth>
            </field>
            <field>
              <name>LSECSSON</name>
              <bitOffset>5</bitOffset>
              <bitWidth>1</bitWidth>
            </field>
            <field>
              <name>LSECSSD</name>
              <bitOffset>6</bitOffset>
              <bitWidth>1</bitWidth>
            </field>
            <field>
              <name>RTCSEL</name>
              <bitOffset>8</bitOffset>
              <bitWidth>2</bitWidth>
            </field>
            <field>
              <name>RTCEN</name>
              <bitOffset>15</bitOffset>
              <bitWidth>1</bitWidth>
            </field>
            <field>
              <name>BDRST</name>
              <bitOffset>16</bitOffset>
              <bitWidth>1</bitWidth>
            </field>
          </fields>
        </register>
        <register>
          <name>CSR</name>
          <addressOffset>0x74</addressOffset>
          <size>0x20</size>
          <fields>
            <field>
              <name>LSION</name>
              <bitOffset>0</bitOffset>
              <bitWidth>1</bitWidth>
            </field>
            <field>
              <name>LSIRDY</name>
              <bitOffset>1</bitOffset>
              <bitWidth>1</bitWidth>
            </field>
          </fields>
        </register>
        <register>
          <name>AHB3RSTR</name>
          <addressOffset>0x7c</addressOffset>
          <size>0x20</size>
          <fields>
            <field>
              <name>MDMARST</name>
              <bitOffset>0</bitOffset>
              <bitWidth>1</bitWidth>
            </field>
            <field>
              <name>DMA2DRST</name>
              <bitOffset>4</bitOffset>
              <bitWidth>1</bitWidth>
            </field>
            <field>
              <name>JPGDECRST</name>
              <bitOffset>5</bitOffset>
              <bitWidth>1</bitWidth>
            </field>
            <field>
              <name>FMCRST</name>
              <bitOffset>12</bitOffset>
              <bitWidth>1</bitWidth>
            </field>
            <field>
              <name>QSPIRST</name>
              <bitOffset>14</bitOffset>
              <bitWidth>1</bitWidth>
            </field>
            <field>
              <name>SDMMC1RST</name>
              <bitOffset>16</bitOffset>
              <bitWidth>1</bitWidth>
            </field>
          </fields>
        </register>
        <register>
          <name>AHB1RSTR</name>
          <addressOffset>0x80</addressOffset>
          <size>0x20</size>
          <fields>
            <field>
              <name>DMA1RST</name>
              <bitOffset>0</bitOffset>
              <bitWidth>1</bitWidth>
            </field>
            <field>
              <name>DMA2RST</name>
              <bitOffset>1</bitOffset>
              <bitWidth>1</bitWidth>
            </field>
            <field>
              <name>ADC12RST</name>
              <bitOffset>5</bitOffset>
              <bitWidth>1</bitWidth>
            </field>
            <field>
              <name>ARTRST</name>
              <bitOffset>14</bitOffset>
              <bitWidth>1</bitWidth>
            </field>
            <field>
              <name>ETH1MACRST</name>
              <bitOffset>15</bitOffset>
              <bitWidth>1</bitWidth>
            </field>
            <field>
              <name>USB1OTGHSRST</name>
              <bitOffset>25</bitOffset>
              <bitWidth>1</bitWidth>
            </field>
            <field>
              <name>USB2OTGHSRST</name>
              <bitOffset>27</bitOffset>
              <bitWidth>1</bitWidth>
            </field>
          </fields>
        </register>
        <register>
          <name>AHB2RSTR</name>
          <addressOffset>0x84</addressOffset>
          <size>0x20</size>
          <fields>
            <field>
              <name>DCMIRST</name>
              <bitOffset>0</bitOffset>
              <bitWidth>1</bitWidth>
            </field>
            <field>
              <name>CRYPRST</name>
              <bitOffset>4</bitOffset>
              <bitWidth>1</bitWidth>
            </field>
            <field>
              <name>HASHRST</name>
              <bitOffset>5</bitOffset>
              <bitWidth>1</bitWidth>
            </field>
            <field>
              <name>RNGRST</name>
              <bitOffset>6</bitOffset>
              <bitWidth>1</bitWidth>
            </field>
            <field>
              <name>SDMMC2RST</name>
              <bitOffset>9</bitOffset>
              <bitWidth>1</bitWidth>
            </field>
          </fields>
        </register>
        <register>
          <name>AHB4RSTR</name>
          <addressOffset>0x88</addressOffset>
          <size>0x20</size>
          <fields>
            <field>
              <name>GPIOARST</name>
              <bitOffset>0</bitOffset>
              <bitWidth>1</bitWidth>
            </field>
            <field>
              <name>GPIOBRST</name>
              <bitOffset>1</bitOffset>
              <bitWidth>1</bitWidth>
            </field>
            <field>
              <name>GPIOCRST</name>
              <bitOffset>2</bitOffset>
              <bitWidth>1</bitWidth>
            </field>
            <field>
              <name>GPIODRST</name>
              <bitOffset>3</bitOffset>
              <bitWidth>1</bitWidth>
            </field>
            <field>
              <name>GPIOERST</name>
              <bitOffset>4</bitOffset>
              <bitWidth>1</bitWidth>
            </field>
            <field>
              <name>GPIOFRST</name>
              <bitOffset>5</bitOffset>
              <bitWidth>1</bitWidth>
            </field>
            <field>
              <name>GPIOGRST</name>
              <bitOffset>6</bitOffset>
              <bitWidth>1</bitWidth>
            </field>
            <field>
              <name>GPIOHRST</name>
              <bitOffset>7</bitOffset>
              <bitWidth>1</bitWidth>
            </field>
            <field>
              <name>GPIOIRST</name>
              <bitOffset>8</bitOffset>
              <bitWidth>1</bitWidth>
            </field>
            <field>
              <name>GPIOJRST</name>
              <bitOffset>9</bitOffset>
              <bitWidth>1</bitWidth>
            </field>
            <field>
              <name>GPIOKRST</name>
              <bitOffset>10</bitOffset>
              <bitWidth>1</bitWidth>
            </field>
            <field>
              <name>CRCRST</name>
              <bitOffset>19</bitOffset>
              <bitWidth>1</bitWidth>
            </field>
            <field>
              <name>BDMARST</name>
              <bitOffset>21</bitOffset>
              <bitWidth>1</bitWidth>
            </field>
            <field>
              <name>ADC3RST</name>
              <bitOffset>24</bitOffset>
              <bitWidth>1</bitWidth>
            </field>
            <field>
              <name>HSEMRST</name>
              <bitOffset>25</bitOffset>
              <bitWidth>1</bitWidth>
            </field>
          </fields>
        </register>
        <register>
          <name>APB3RSTR</name>
          <addressOffset>0x8c</addressOffset>
          <size>0x20</size>
          <fields>
            <field>
              <name>LTDCRST</name>
              <bitOffset>3</bitOffset>
              <bitWidth>1</bitWidth>
            </field>
            <field>
              <name>DSIRST</name>
              <bitOffset>4</bitOffset>
              <bitWidth>1</bitWidth>
            </field>
          </fields>
        </register>
        <register>
          <name>APB1LRSTR</name>
          <addressOffset>0x90</addressOffset>
          <size>0x20</size>
          <fields>
            <field>
              <name>TIM2RST</name>
              <bitOffset>0</bitOffset>
              <bitWidth>1</bitWidth>
            </field>
            <field>
              <name>TIM3RST</name>
              <bitOffset>1</bitOffset>
              <bitWidth>1</bitWidth>
            </field>
            <field>
              <name>TIM4RST</name>
              <bitOffset>2</bitOffset>
              <bitWidth>1</bitWidth>
            </field>
            <field>
              <name>TIM5RST</name>
              <bitOffset>3</bitOffset>
              <bitWidth>1</bitWidth>
            </field>
            <field>
              <name>TIM6RST</name>
              <bitOffset>4</bitOffset>
              <bitWidth>1</bitWidth>
            </field>
            <field>
              <name>TIM7RST</name>
              <bitOffset>5</bitOffset>
              <bitWidth>1</bitWidth>
            </field>
            <field>
              <name>TIM12RST</name>
              <bitOffset>6</bitOffset>
              <bitWidth>1</bitWidth>
            </field>
            <field>
              <name>TIM13RST</name>
              <bitOffset>7</bitOffset>
              <bitWidth>1</bitWidth>
            </field>
            <field>
              <name>TIM14RST</name>
              <bitOffset>8</bitOffset>
              <bitWidth>1</bitWidth>
            </field>
            <field>
              <name>LPTIM1RST</name>
              <bitOffset>9</bitOffset>
              <bitWidth>1</bitWidth>
            </field>
            <field>
              <name>SPI2RST</name>
              <bitOffset>14</bitOffset>
              <bitWidth>1</bitWidth>
            </field>
            <field>
              <name>SPI3RST</name>
              <bitOffset>15</bitOffset>
              <bitWidth>1</bitWidth>
            </field>
            <field>
              <name>SPDIFRXRST</name>
              <bitOffset>16</bitOffset>
              <bitWidth>1</bitWidth>
            </field>
            <field>
              <name>USART2RST</name>
              <bitOffset>17</bitOffset>
              <bitWidth>1</bitWidth>
            </field>
            <field>
              <name>USART3RST</name>
              <bitOffset>18</bitOffset>
              <bitWidth>1</bitWidth>
            </field>
            <field>
              <name>UART4RST</name>
              <bitOffset>19</bitOffset>
              <bitWidth>1</bitWidth>
            </field>
            <field>
              <name>UART5RST</name>
              <bitOffset>20</bitOffset>
              <bitWidth>1</bitWidth>
            </field>
            <field>
              <name>I2C1RST</name>
              <bitOffset>21</bitOffset>
              <bitWidth>1</bitWidth>
            </field>
            <field>
              <name>I2C2RST</name>
              <bitOffset>22</bitOffset>
              <bitWidth>1</bitWidth>
            </field>
            <field>
              <name>I2C3RST</name>
              <bitOffset>23</bitOffset>
              <bitWidth>1</bitWidth>
            </field>
            <field>
              <name>HDMICECRST</name>
              <bitOffset>27</bitOffset>
              <bitWidth>1</bitWidth>
            </field>
            <field>
              <name>DAC12RST</name>
              <bitOffset>29</bitOffset>
              <bitWidth>1</bitWidth>
            </field>
            <field>
              <name>UART7RST</name>
              <bitOffset>30</bitOffset>
              <bitWidth>1</bitWidth>
            </field>
            <field>
              <name>UART8RST</name>
              <bitOffset>31</bitOffset>
              <bitWidth>1</bitWidth>
            </field>
          </fields>
        </register>
        <register>
          <name>APB1HRSTR</name>
          <addressOffset>0x94</addressOffset>
          <size>0x20</size>
          <fields>
            <field>
              <name>CRSRST</name>
              <bitOffset>1</bitOffset>
              <bitWidth>1</bitWidth>
            </field>
            <field>
              <name>SWPMIRST</name>
              <bitOffset>2</bitOffset>
              <bitWidth>1</bitWidth>
            </field>
            <field>
              <name>OPAMPRST</name>
              <bitOffset>4</bitOffset>
              <bitWidth>1</bitWidth>
            </field>
            <field>
              <name>MDIOSRST</name>
              <bitOffset>5</bitOffset>
              <bitWidth>1</bitWidth>
            </field>
            <field>
              <name>FDCANRST</name>
              <bitOffset>8</bitOffset>
              <bitWidth>1</bitWidth>
            </field>
          </fields>
        </register>
        <register>
          <name>APB2RSTR</name>
          <addressOffset>0x98</addressOffset>
          <size>0x20</size>
          <fields>
            <field>
              <name>TIM1RST</name>
              <bitOffset>0</bitOffset>
              <bitWidth>1</bitWidth>
            </field>
            <field>
              <name>TIM8RST</name>
              <bitOffset>1</bitOffset>
              <bitWidth>1</bitWidth>
            </field>
            <field>
              <name>USART1RST</name>
              <bitOffset>4</bitOffset>
              <bitWidth>1</bitWidth>
            </field>
            <field>
              <name>USART6RST</name>
              <bitOffset>5</bitOffset>
              <bitWidth>1</bitWidth>
            </field>
            <field>
              <name>SPI1RST</name>
              <bitOffset>12</bitOffset>
              <bitWidth>1</bitWidth>
            </field>
            <field>
              <name>SPI4RST</name>
              <bitOffset>13</bitOffset>
              <bitWidth>1</bitWidth>
            </field>
            <field>
              <name>TIM15RST</name>
              <bitOffset>16</bitOffset>
              <bitWidth>1</bitWidth>
            </field>
            <field>
              <name>TIM16RST</name>
              <bitOffset>17</bitOffset>
              <bitWidth>1</bitWidth>
            </field>
            <field>
              <name>TIM17RST</name>
              <bitOffset>18</bitOffset>
              <bitWidth>1</bitWidth>
            </field>
            <field>
              <name>SPI5RST</name>
              <bitOffset>20</bitOffset>
              <bitWidth>1</bitWidth>
            </field>
            <field>
              <name>SAI1RST</name>
              <bitOffset>22</bitOffset>
              <bitWidth>1</bitWidth>
            </field>
            <field>
              <name>SAI2RST</name>
              <bitOffset>23</bitOffset>
              <bitWidth>1</bitWidth>
            </field>
            <field>
              <name>SAI3RST</name>
              <bitOffset>24</bitOffset>
              <bitWidth>1</bitWidth>
            </field>
            <field>
              <name>DFSDM1RST</name>
              <bitOffset>28</bitOffset>
              <bitWidth>1</bitWidth>
            </field>
            <field>
              <name>HRTIMRST</name>
              <bitOffset>29</bitOffset>
              <bitWidth>1</bitWidth>
            </field>
          </fields>
        </register>
        <register>
          <name>APB4RSTR</name>
          <addressOffset>0x9c</addressOffset>
          <size>0x20</size>
          <fields>
            <field>
              <name>SYSCFGRST</name>
              <bitOffset>1</bitOffset>
              <bitWidth>1</bitWidth>
            </field>
            <field>
              <name>LPUART1RST</name>
              <bitOffset>3</bitOffset>
              <bitWidth>1</bitWidth>
            </field>
            <field>
              <name>SPI6RST</name>
              <bitOffset>5</bitOffset>
              <bitWidth>1</bitWidth>
            </field>
            <field>
              <name>I2C4RST</name>
              <bitOffset>7</bitOffset>
              <bitWidth>1</bitWidth>
            </field>
            <field>
              <name>LPTIM2RST</name>
              <bitOffset>9</bitOffset>
              <bitWidth>1</bitWidth>
            </field>
            <field>
              <name>LPTIM3RST</name>
              <bitOffset>10</bitOffset>
              <bitWidth>1</bitWidth>
            </field>
            <field>
              <name>LPTIM4RST</name>
              <bitOffset>11</bitOffset>
              <bitWidth>1</bitWidth>
            </field>
            <field>
              <name>LPTIM5RST</name>
              <bitOffset>12</bitOffset>
              <bitWidth>1</bitWidth>
            </field>
            <field>
              <name>COMP12RST</name>
              <bitOffset>14</bitOffset>
              <bitWidth>1</bitWidth>
            </field>
            <field>
              <name>VREFRST</name>
              <bitOffset>15</bitOffset>
              <bitWidth>1</bitWidth>
            </field>
            <field>
              <name>SAI4RST</name>
              <bitOffset>21</bitOffset>
              <bitWidth>1</bitWidth>
            </field>
          </fields>
        </register>
        <register>
          <name>GCR</name>
          <addressOffset>0xa0</addressOffset>
          <size>0x20</size>
          <fields>
            <field>
              <name>WW1RSC</name>
              <bitOffset>0</bitOffset>
              <bitWidth>1</bitWidth>
            </field>
            <field>
              <name>WW2RSC</name>
              <bitOffset>1</bitOffset>
              <bitWidth>1</bitWidth>
            </field>
            <field>
              <name>BOOT_C1</name>
              <bitOffset>2</bitOffset>
              <bitWidth>1</bitWidth>
            </field>
            <field>
              <name>BOOT_C2</name>
              <bitOffset>3</bitOffset>
              <bitWidth>1</bitWidth>
            </field>
          </fields>
        </register>
        <register>
          <name>D3AMR</name>
          <addressOffset>0xa8</addressOffset>
          <size>0x20</size>
          <fields>
            <field>
              <name>BDMAAMEN</name>
              <bitOffset>0</bitOffset>
              <bitWidth>1</bitWidth>
            </field>
            <field>
              <name>LPUART1AMEN</name>
              <bitOffset>3</bitOffset>
              <bitWidth>1</bitWidth>
            </field>
            <field>
              <name>SPI6AMEN</name>
              <bitOffset>5</bitOffset>
              <bitWidth>1</bitWidth>
            </field>
            <field>
              <name>I2C4AMEN</name>
              <bitOffset>7</bitOffset>
              <bitWidth>1</bitWidth>
            </field>
            <field>
              <name>LPTIM2AMEN</name>
              <bitOffset>9</bitOffset>
              <bitWidth>1</bitWidth>
            </field>
            <field>
              <name>LPTIM3AMEN</name>
              <bitOffset>10</bitOffset>
              <bitWidth>1</bitWidth>
            </field>
            <field>
              <name>LPTIM4AMEN</name>
              <bitOffset>11</bitOffset>
              <bitWidth>1</bitWidth>
            </field>
            <field>
              <name>LPTIM5AMEN</name>
              <bitOffset>12</bitOffset>
              <bitWidth>1</bitWidth>
            </field>
            <field>
              <name>COMP12AMEN</name>
              <bitOffset>14</bitOffset>
              <bitWidth>1</bitWidth>
            </field>
            <field>
              <name>VREFAMEN</name>
              <bitOffset>15</bitOffset>
              <bitWidth>1</bitWidth>
            </field>
            <field>
              <name>RTCAMEN</name>
              <bitOffset>16</bitOffset>
              <bitWidth>1</bitWidth>
            </field>
            <field>
              <name>CRCAMEN</name>
              <bitOffset>19</bitOffset>
              <bitWidth>1</bitWidth>
            </field>
            <field>
              <name>SAI4AMEN</name>
              <bitOffset>21</bitOffset>
              <bitWidth>1</bitWidth>
            </field>
            <field>
              <name>ADC3AMEN</name>
              <bitOffset>24</bitOffset>
              <bitWidth>1</bitWidth>
            </field>
            <field>
              <name>BKPRAMAMEN</name>
              <bitOffset>28</bitOffset>
              <bitWidth>1</bitWidth>
            </field>
            <field>
              <name>SRAM4AMEN</name>
              <bitOffset>29</bitOffset>
              <bitWidth>1</bitWidth>
            </field>
          </fields>
        </register>
        <register>
          <name>RSR</name>
          <addressOffset>0xd0</addressOffset>
          <size>0x20</size>
          <fields>
            <field>
              <name>RMVF</name>
              <bitOffset>16</bitOffset>
              <bitWidth>1</bitWidth>
            </field>
            <field>
              <name>C1RSTF</name>
              <bitOffset>17</bitOffset>
              <bitWidth>1</bitWidth>
            </field>
            <field>
              <name>C2RSTF</name>
              <bitOffset>18</bitOffset>
              <bitWidth>1</bitWidth>
            </field>
            <field>
              <name>D1RSTF</name>
              <bitOffset>19</bitOffset>
              <bitWidth>1</bitWidth>
            </field>
            <field>
              <name>D2RSTF</name>
              <bitOffset>20</bitOffset>
              <bitWidth>1</bitWidth>
            </field>
            <field>
              <name>BORRSTF</name>
              <bitOffset>21</bitOffset>
              <bitWidth>1</bitWidth>
            </field>
            <field>
              <name>PINRSTF</name>
              <bitOffset>22</bitOffset>
              <bitWidth>1</bitWidth>
            </field>
            <field>
              <name>PORRSTF</name>
              <bitOffset>23</bitOffset>
              <bitWidth>1</bitWidth>
            </field>
            <field>
              <name>SFT1RSTF</name>
              <bitOffset>24</bitOffset>
              <bitWidth>1</bitWidth>
            </field>
            <field>
              <name>SFT2RSTF</name>
              <bitOffset>25</bitOffset>
              <bitWidth>1</bitWidth>
            </field>
            <field>
              <name>IWDG1RSTF</name>
              <bitOffset>26</bitOffset>
              <bitWidth>1</bitWidth>
            </field>
            <field>
              <name>IWDG2RSTF</name>
              <bitOffset>27</bitOffset>
              <bitWidth>1</bitWidth>
            </field>
            <field>
              <name>WWDG1RSTF</name>
              <bitOffset>28</bitOffset>
              <bitWidth>1</bitWidth>
            </field>
            <field>
              <name>WWDG2RSTF</name>
              <bitOffset>29</bitOffset>
              <bitWidth>1</bitWidth>
            </field>
            <field>
              <name>LPWR1RSTF</name>
              <bitOffset>30</bitOffset>
              <bitWidth>1</bitWidth>
            </field>
            <field>
              <name>LPWR2RSTF</name>
              <bitOffset>31</bitOffset>
              <bitWidth>1</bitWidth>
            </field>
          </fields>
        </register>
        <register>
          <name>AHB3ENR</name>
          <addressOffset>0xd4</addressOffset>
          <size>0x20</size>
          <fields>
            <field>
              <name>MDMAEN</name>
              <bitOffset>0</bitOffset>
              <bitWidth>1</bitWidth>
            </field>
            <field>
              <name>DMA2DEN</name>
              <bitOffset>4</bitOffset>
              <bitWidth>1</bitWidth>
            </field>
            <field>
              <name>JPGDECEN</name>
              <bitOffset>5</bitOffset>
              <bitWidth>1</bitWidth>
            </field>
            <field>
              <name>FLASHEN</name>
              <bitOffset>8</bitOffset>
              <bitWidth>1</bitWidth>
            </field>
            <field>
              <name>FMCEN</name>
              <bitOffset>12</bitOffset>
              <bitWidth>1</bitWidth>
            </field>
            <field>
              <name>QSPIEN</name>
              <bitOffset>14</bitOffset>
              <bitWidth>1</bitWidth>
            </field>
            <field>
              <name>SDMMC1EN</name>
              <bitOffset>16</bitOffset>
              <bitWidth>1</bitWidth>
            </field>
            <field>
              <name>DTCM1EN</name>
              <bitOffset>28</bitOffset>
              <bitWidth>1</bitWidth>
            </field>
            <field>
              <name>DTCM2EN</name>
              <bitOffset>29</bitOffset>
              <bitWidth>1</bitWidth>
            </field>
            <field>
              <name>ITCMEN</name>
              <bitOffset>30</bitOffset>
              <bitWidth>1</bitWidth>
            </field>
            <field>
              <name>D1SRAM1EN</name>
              <bitOffset>31</bitOffset>
              <bitWidth>1</bitWidth>
            </field>
          </fields>
        </register>
        <register>
          <name>AHB1ENR</name>
          <addressOffset>0xd8</addressOffset>
          <size>0x20</size>
          <fields>
            <field>
              <name>DMA1EN</name>
              <bitOffset>0</bitOffset>
              <bitWidth>1</bitWidth>
            </field>
            <field>
              <name>DMA2EN</name>
              <bitOffset>1</bitOffset>
              <bitWidth>1</bitWidth>
            </field>
            <field>
              <name>ADC12EN</name>
              <bitOffset>5</bitOffset>
              <bitWidth>1</bitWidth>
            </field>
            <field>
              <name>ARTEN</name>
              <bitOffset>14</bitOffset>
              <bitWidth>1</bitWidth>
            </field>
            <field>
              <name>ETH1MACEN</name>
              <bitOffset>15</bitOffset>
              <bitWidth>1</bitWidth>
            </field>
            <field>
              <name>ETH1TXEN</name>
              <bitOffset>16</bitOffset>
              <bitWidth>1</bitWidth>
            </field>
            <field>
              <name>ETH1RXEN</name>
              <bitOffset>17</bitOffset>
              <bitWidth>1</bitWidth>
            </field>
            <field>
              <name>USB1OTGHSEN</name>
              <bitOffset>25</bitOffset>
              <bitWidth>1</bitWidth>
            </field>
            <field>
              <name>USB1OTGHSULPIEN</name>
              <bitOffset>26</bitOffset>
              <bitWidth>1</bitWidth>
            </field>
            <field>
              <name>USB2OTGHSEN</name>
              <bitOffset>27</bitOffset>
              <bitWidth>1</bitWidth>
            </field>
            <field>
              <name>USB2OTGHSULPIEN</name>
              <bitOffset>28</bitOffset>
              <bitWidth>1</bitWidth>
            </field>
          </fields>
        </register>
        <register>
          <name>AHB2ENR</name>
          <addressOffset>0xdc</addressOffset>
          <size>0x20</size>
          <fields>
            <field>
              <name>DCMIEN</name>
              <bitOffset>0</bitOffset>
              <bitWidth>1</bitWidth>
            </field>
            <field>
              <name>CRYPEN</name>
              <bitOffset>4</bitOffset>
              <bitWidth>1</bitWidth>
            </field>
            <field>
              <name>HASHEN</name>
              <bitOffset>5</bitOffset>
              <bitWidth>1</bitWidth>
            </field>
            <field>
              <name>RNGEN</name>
              <bitOffset>6</bitOffset>
              <bitWidth>1</bitWidth>
            </field>
            <field>
              <name>SDMMC2EN</name>
              <bitOffset>9</bitOffset>
              <bitWidth>1</bitWidth>
            </field>
            <field>
              <name>SRAM1EN</name>
              <bitOffset>29</bitOffset>
              <bitWidth>1</bitWidth>
            </field>
            <field>
              <name>SRAM2EN</name>
              <bitOffset>30</bitOffset>
              <bitWidth>1</bitWidth>
            </field>
            <field>
              <name>SRAM3EN</name>
              <bitOffset>31</bitOffset>
              <bitWidth>1</bitWidth>
            </field>
          </fields>
        </register>
        <register>
          <name>AHB4ENR</name>
          <addressOffset>0xe0</addressOffset>
          <size>0x20</size>
          <fields>
            <field>
              <name>GPIOAEN</name>
              <bitOffset>0</bitOffset>
              <bitWidth>1</bitWidth>
            </field>
            <field>
              <name>GPIOBEN</name>
              <bitOffset>1</bitOffset>
              <bitWidth>1</bitWidth>
            </field>
            <field>
              <name>GPIOCEN</name>
              <bitOffset>2</bitOffset>
              <bitWidth>1</bitWidth>
            </field>
            <field>
              <name>GPIODEN</name>
              <bitOffset>3</bitOffset>
              <bitWidth>1</bitWidth>
            </field>
            <field>
              <name>GPIOEEN</name>
              <bitOffset>4</bitOffset>
              <bitWidth>1</bitWidth>
            </field>
            <field>
              <name>GPIOFEN</name>
              <bitOffset>5</bitOffset>
              <bitWidth>1</bitWidth>
            </field>
            <field>
              <name>GPIOGEN</name>
              <bitOffset>6</bitOffset>
              <bitWidth>1</bitWidth>
            </field>
            <field>
              <name>GPIOHEN</name>
              <bitOffset>7</bitOffset>
              <bitWidth>1</bitWidth>
            </field>
            <field>
              <name>GPIOIEN</name>
              <bitOffset>8</bitOffset>
              <bitWidth>1</bitWidth>
            </field>
            <field>
              <name>GPIOJEN</name>
              <bitOffset>9</bitOffset>
              <bitWidth>1</bitWidth>
            </field>
            <field>
              <name>GPIOKEN</name>
              <bitOffset>10</bitOffset>
              <bitWidth>1</bitWidth>
            </field>
            <field>
              <name>CRCEN</name>
              <bitOffset>19</bitOffset>
              <bitWidth>1</bitWidth>
            </field>
            <field>
              <name>BDMAEN</name>
              <bitOffset>21</bitOffset>
              <bitWidth>1</bitWidth>
            </field>
            <field>
              <name>ADC3EN</name>
              <bitOffset>24</bitOffset>
              <bitWidth>1</bitWidth>
            </field>
            <field>
              <name>HSEMEN</name>
              <bitOffset>25</bitOffset>
              <bitWidth>1</bitWidth>
            </field>
            <field>
              <name>BKPRAMEN</name>
              <bitOffset>28</bitOffset>
              <bitWidth>1</bitWidth>
            </field>
          </fields>
        </register>
        <register>
          <name>APB3ENR</name>
          <addressOffset>0xe4</addressOffset>
          <size>0x20</size>
          <fields>
            <field>
              <name>LTDCEN</name>
              <bitOffset>3</bitOffset>
              <bitWidth>1</bitWidth>
            </field>
            <field>
              <name>DSIEN</name>
              <bitOffset>4</bitOffset>
              <bitWidth>1</bitWidth>
            </field>
            <field>
              <name>WWDG1EN</name>
              <bitOffset>6</bitOffset>
              <bitWidth>1</bitWidth>
            </field>
          </fields>
        </register>
        <register>
          <name>APB1LENR</name>
          <addressOffset>0xe8</addressOffset>
          <size>0x20</size>
          <fields>
            <field>
              <name>TIM2EN</name>
              <bitOffset>0</bitOffset>
              <bitWidth>1</bitWidth>
            </field>
            <field>
              <name>TIM3EN</name>
              <bitOffset>1</bitOffset>
              <bitWidth>1</bitWidth>
            </field>
            <field>
              <name>TIM4EN</name>
              <bitOffset>2</bitOffset>
              <bitWidth>1</bitWidth>
            </field>
            <field>
              <name>TIM5EN</name>
              <bitOffset>3</bitOffset>
              <bitWidth>1</bitWidth>
            </field>
            <field>
              <name>TIM6EN</name>
              <bitOffset>4</bitOffset>
              <bitWidth>1</bitWidth>
            </field>
            <field>
              <name>TIM7EN</name>
              <bitOffset>5</bitOffset>
              <bitWidth>1</bitWidth>
            </field>
            <field>
              <name>TIM12EN</name>
              <bitOffset>6</bitOffset>
              <bitWidth>1</bitWidth>
            </field>
            <field>
              <name>TIM13EN</name>
              <bitOffset>7</bitOffset>
              <bitWidth>1</bitWidth>
            </field>
            <field>
              <name>TIM14EN</name>
              <bitOffset>8</bitOffset>
              <bitWidth>1</bitWidth>
            </field>
            <field>
              <name>LPTIM1EN</name>
              <bitOffset>9</bitOffset>
              <bitWidth>1</bitWidth>
            </field>
            <field>
              <name>WWDG2EN</name>
              <bitOffset>11</bitOffset>
              <bitWidth>1</bitWidth>
            </field>
            <field>
              <name>SPI2EN</name>
              <bitOffset>14</bitOffset>
              <bitWidth>1</bitWidth>
            </field>
            <field>
              <name>SPI3EN</name>
              <bitOffset>15</bitOffset>
              <bitWidth>1</bitWidth>
            </field>
            <field>
              <name>SPDIFRXEN</name>
              <bitOffset>16</bitOffset>
              <bitWidth>1</bitWidth>
            </field>
            <field>
              <name>USART2EN</name>
              <bitOffset>17</bitOffset>
              <bitWidth>1</bitWidth>
            </field>
            <field>
              <name>USART3EN</name>
              <bitOffset>18</bitOffset>
              <bitWidth>1</bitWidth>
            </field>
            <field>
              <name>UART4EN</name>
              <bitOffset>19</bitOffset>
              <bitWidth>1</bitWidth>
            </field>
            <field>
              <name>UART5EN</name>
              <bitOffset>20</bitOffset>
              <bitWidth>1</bitWidth>
            </field>
            <field>
              <name>I2C1EN</name>
              <bitOffset>21</bitOffset>
              <bitWidth>1</bitWidth>
            </field>
            <field>
              <name>I2C2EN</name>
              <bitOffset>22</bitOffset>
              <bitWidth>1</bitWidth>
            </field>
            <field>
              <name>I2C3EN</name>
              <bitOffset>23</bitOffset>
              <bitWidth>1</bitWidth>
            </field>
            <field>
              <name>HDMICECEN</name>
              <bitOffset>27</bitOffset>
              <bitWidth>1</bitWidth>
            </field>
            <field>
              <name>DAC12EN</name>
              <bitOffset>29</bitOffset>
              <bitWidth>1</bitWidth>
            </field>
            <field>
              <name>UART7EN</name>
              <bitOffset>30</bitOffset>
              <bitWidth>1</bitWidth>
            </field>
            <field>
              <name>UART8EN</name>
              <bitOffset>31</bitOffset>
              <bitWidth>1</bitWidth>
            </field>
          </fields>
        </register>
        <register>
          <name>APB1HENR</name>
          <addressOffset>0xec</addressOffset>
          <size>0x20</size>
          <fields>
            <field>
              <name>CRSEN</name>
              <bitOffset>1</bitOffset>
              <bitWidth>1</bitWidth>
            </field>
            <field>
              <name>SWPMIEN</name>
              <bitOffset>2</bitOffset>
              <bitWidth>1</bitWidth>
            </field>
            <field>
              <name>OPAMPEN</name>
              <bitOffset>4</bitOffset>
              <bitWidth>1</bitWidth>
            </field>
            <field>
              <name>MDIOSEN</name>
              <bitOffset>5</bitOffset>
              <bitWidth>1</bitWidth>
            </field>
            <field>
              <name>FDCANEN</name>
              <bitOffset>8</bitOffset>
              <bitWidth>1</bitWidth>
            </field>
          </fields>
        </register>
        <register>
          <name>APB2ENR</name>
          <addressOffset>0xf0</addressOffset>
          <size>0x20</size>
          <fields>
            <field>
              <name>TIM1EN</name>
              <bitOffset>0</bitOffset>
              <bitWidth>1</bitWidth>
            </field>
            <field>
              <name>TIM8EN</name>
              <bitOffset>1</bitOffset>
              <bitWidth>1</bitWidth>
            </field>
            <field>
              <name>USART1EN</name>
              <bitOffset>4</bitOffset>
              <bitWidth>1</bitWidth>
            </field>
            <field>
              <name>USART6EN</name>
              <bitOffset>5</bitOffset>
              <bitWidth>1</bitWidth>
            </field>
            <field>
              <name>SPI1EN</name>
              <bitOffset>12</bitOffset>
              <bitWidth>1</bitWidth>
            </field>
            <field>
              <name>SPI4EN</name>
              <bitOffset>13</bitOffset>
              <bitWidth>1</bitWidth>
            </field>
            <field>
              <name>TIM15EN</name>
              <bitOffset>16</bitOffset>
              <bitWidth>1</bitWidth>
            </field>
            <field>
              <name>TIM16EN</name>
              <bitOffset>17</bitOffset>
              <bitWidth>1</bitWidth>
            </field>
            <field>
              <name>TIM17EN</name>
              <bitOffset>18</bitOffset>
              <bitWidth>1</bitWidth>
            </field>
            <field>
              <name>SPI5EN</name>
              <bitOffset>20</bitOffset>
              <bitWidth>1</bitWidth>
            </field>
            <field>
              <name>SAI1EN</name>
              <bitOffset>22</bitOffset>
              <bitWidth>1</bitWidth>
            </field>
            <field>
              <name>SAI2EN</name>
              <bitOffset>23</bitOffset>
              <bitWidth>1</bitWidth>
            </field>
            <field>
              <name>SAI3EN</name>
              <bitOffset>24</bitOffset>
              <bitWidth>1</bitWidth>
            </field>
            <field>
              <name>DFSDM1EN</name>
              <bitOffset>28</bitOffset>
              <bitWidth>1</bitWidth>
            </field>
            <field>
              <name>HRTIMEN</name>
              <bitOffset>29</bitOffset>
              <bitWidth>1</bitWidth>
            </field>
          </fields>
        </register>
        <register>
          <name>APB4ENR</name>
          <addressOffset>0xf4</addressOffset>
          <size>0x20</size>
          <fields>
            <field>
              <name>SYSCFGEN</name>
              <bitOffset>1</bitOffset>
              <bitWidth>1</bitWidth>
            </field>
            <field>
              <name>LPUART1EN</name>
              <bitOffset>3</bitOffset>
              <bitWidth>1</bitWidth>
            </field>
            <field>
              <name>SPI6EN</name>
              <bitOffset>5</bitOffset>
              <bitWidth>1</bitWidth>
            </field>
            <field>
              <name>I2C4EN</name>
              <bitOffset>7</bitOffset>
              <bitWidth>1</bitWidth>
            </field>
            <field>
              <name>LPTIM2EN</name>
              <bitOffset>9</bitOffset>
              <bitWidth>1</bitWidth>
            </field>
            <field>
              <name>LPTIM3EN</name>
              <bitOffset>10</bitOffset>
              <bitWidth>1</bitWidth>
            </field>
            <field>
              <name>LPTIM4EN</name>
              <bitOffset>11</bitOffset>
              <bitWidth>1</bitWidth>
            </field>
            <field>
              <name>LPTIM5EN</name>
              <bitOffset>12</bitOffset>
              <bitWidth>1</bitWidth>
            </field>
            <field>
              <name>COMP12EN</name>
              <bitOffset>14</bitOffset>
              <bitWidth>1</bitWidth>
            </field>
            <field>
              <name>VREFEN</name>
              <bitOffset>15</bitOffset>
              <bitWidth>1</bitWidth>
            </field>
            <field>
              <name>RTCAPBEN</name>
              <bitOffset>16</bitOffset>
              <bitWidth>1</bitWidth>
            </field>
            <field>
              <name>SAI4EN</name>
              <bitOffset>21</bitOffset>
              <bitWidth>1</bitWidth>
            </field>
          </fields>
        </register>
        <register>
          <name>AHB3LPENR</name>
          <addressOffset>0xfc</addressOffset>
          <size>0x20</size>
          <fields>
            <field>
              <name>MDMALPEN</name>
              <bitOffset>0</bitOffset>
              <bitWidth>1</bitWidth>
            </field>
            <field>
              <name>DMA2DLPEN</name>
              <bitOffset>4</bitOffset>
              <bitWidth>1</bitWidth>
            </field>
            <field>
              <name>JPGDECLPEN</name>
              <bitOffset>5</bitOffset>
              <bitWidth>1</bitWidth>
            </field>
            <field>
              <name>FLASHLPEN</name>
              <bitOffset>8</bitOffset>
              <bitWidth>1</bitWidth>
            </field>
            <field>
              <name>FMCLPEN</name>
              <bitOffset>12</bitOffset>
              <bitWidth>1</bitWidth>
            </field>
            <field>
              <name>QSPILPEN</name>
              <bitOffset>14</bitOffset>
              <bitWidth>1</bitWidth>
            </field>
            <field>
              <name>SDMMC1LPEN</name>
              <bitOffset>16</bitOffset>
              <bitWidth>1</bitWidth>
            </field>
            <field>
              <name>DTCM1LPEN</name>
              <bitOffset>28</bitOffset>
              <bitWidth>1</bitWidth>
            </field>
            <field>
              <name>DTCM2LPEN</name>
              <bitOffset>29</bitOffset>
              <bitWidth>1</bitWidth>
            </field>
            <field>
              <name>ITCMLPEN</name>
              <bitOffset>30</bitOffset>
              <bitWidth>1</bitWidth>
            </field>
            <field>
              <name>AXISRAMLPEN</name>
              <bitOffset>31</bitOffset>
              <bitWidth>1</bitWidth>
            </field>
          </fields>
        </register>
        <register>
          <name>AHB1LPENR</name>
          <addressOffset>0x100</addressOffset>
          <size>0x20</size>
          <fields>
            <field>
              <name>DMA1LPEN</name>
              <bitOffset>0</bitOffset>
              <bitWidth>1</bitWidth>
            </field>
            <field>
              <name>DMA2LPEN</name>
              <bitOffset>1</bitOffset>
              <bitWidth>1</bitWidth>
            </field>
            <field>
              <name>ADC12LPEN</name>
              <bitOffset>5</bitOffset>
              <bitWidth>1</bitWidth>
            </field>
            <field>
              <name>ARTLPEN</name>
              <bitOffset>14</bitOffset>
              <bitWidth>1</bitWidth>
            </field>
            <field>
              <name>ETH1MACLPEN</name>
              <bitOffset>15</bitOffset>
              <bitWidth>1</bitWidth>
            </field>
            <field>
              <name>ETH1TXLPEN</name>
              <bitOffset>16</bitOffset>
              <bitWidth>1</bitWidth>
            </field>
            <field>
              <name>ETH1RXLPEN</name>
              <bitOffset>17</bitOffset>
              <bitWidth>1</bitWidth>
            </field>
            <field>
              <name>USB1OTGHSLPEN</name>
              <bitOffset>25</bitOffset>
              <bitWidth>1</bitWidth>
            </field>
            <field>
              <name>USB1OTGHSULPILPEN</name>
              <bitOffset>26</bitOffset>
              <bitWidth>1</bitWidth>
            </field>
            <field>
              <name>USB2OTGHSLPEN</name>
              <bitOffset>27</bitOffset>
              <bitWidth>1</bitWidth>
            </field>
            <field>
              <name>USB2OTGHSULPILPEN</name>
              <bitOffset>28</bitOffset>
              <bitWidth>1</bitWidth>
            </field>
          </fields>
        </register>
        <register>
          <name>AHB2LPENR</name>
          <addressOffset>0x104</addressOffset>
          <size>0x20</size>
          <fields>
            <field>
              <name>DCMILPEN</name>
              <bitOffset>0</bitOffset>
              <bitWidth>1</bitWidth>
            </field>
            <field>
              <name>CRYPLPEN</name>
              <bitOffset>4</bitOffset>
              <bitWidth>1</bitWidth>
            </field>
            <field>
              <name>HASHLPEN</name>
              <bitOffset>5</bitOffset>
              <bitWidth>1</bitWidth>
            </field>
            <field>
              <name>RNGLPEN</name>
              <bitOffset>6</bitOffset>
              <bitWidth>1</bitWidth>
            </field>
            <field>
              <name>SDMMC2LPEN</name>
              <bitOffset>9</bitOffset>
              <bitWidth>1</bitWidth>
            </field>
            <field>
              <name>SRAM1LPEN</name>
              <bitOffset>29</bitOffset>
              <bitWidth>1</bitWidth>
            </field>
            <field>
              <name>SRAM2LPEN</name>
              <bitOffset>30</bitOffset>
              <bitWidth>1</bitWidth>
            </field>
            <field>
              <name>SRAM3LPEN</name>
              <bitOffset>31</bitOffset>
              <bitWidth>1</bitWidth>
            </field>
          </fields>
        </register>
        <register>
          <name>AHB4LPENR</name>
          <addressOffset>0x108</addressOffset>
          <size>0x20</size>
          <fields>
            <field>
              <name>GPIOALPEN</name>
              <bitOffset>0</bitOffset>
              <bitWidth>1</bitWidth>
            </field>
            <field>
              <name>GPIOBLPEN</name>
              <bitOffset>1</bitOffset>
              <bitWidth>1</bitWidth>
            </field>
            <field>
              <name>GPIOCLPEN</name>
              <bitOffset>2</bitOffset>
              <bitWidth>1</bitWidth>
            </field>
            <field>
              <name>GPIODLPEN</name>
              <bitOffset>3</bitOffset>
              <bitWidth>1</bitWidth>
            </field>
            <field>
              <name>GPIOELPEN</name>
              <bitOffset>4</bitOffset>
              <bitWidth>1</bitWidth>
            </field>
            <field>
              <name>GPIOFLPEN</name>
              <bitOffset>5</bitOffset>
              <bitWidth>1</bitWidth>
            </field>
            <field>
              <name>GPIOGLPEN</name>
              <bitOffset>6</bitOffset>
              <bitWidth>1</bitWidth>
            </field>
            <field>
              <name>GPIOHLPEN</name>
              <bitOffset>7</bitOffset>
              <bitWidth>1</bitWidth>
            </field>
            <field>
              <name>GPIOILPEN</name>
              <bitOffset>8</bitOffset>
              <bitWidth>1</bitWidth>
            </field>
            <field>
              <name>GPIOJLPEN</name>
              <bitOffset>9</bitOffset>
              <bitWidth>1</bitWidth>
            </field>
            <field>
              <name>GPIOKLPEN</name>
              <bitOffset>10</bitOffset>
              <bitWidth>1</bitWidth>
            </field>
            <field>
              <name>CRCLPEN</name>
              <bitOffset>19</bitOffset>
              <bitWidth>1</bitWidth>
            </field>
            <field>
              <name>BDMALPEN</name>
              <bitOffset>21</bitOffset>
              <bitWidth>1</bitWidth>
            </field>
            <field>
              <name>ADC3LPEN</name>
              <bitOffset>24</bitOffset>
              <bitWidth>1</bitWidth>
            </field>
            <field>
              <name>BKPRAMLPEN</name>
              <bitOffset>28</bitOffset>
              <bitWidth>1</bitWidth>
            </field>
            <field>
              <name>SRAM4LPEN</name>
              <bitOffset>29</bitOffset>
              <bitWidth>1</bitWidth>
            </field>
          </fields>
        </register>
        <register>
          <name>APB3LPENR</name>
          <addressOffset>0x10c</addressOffset>
          <size>0x20</size>
          <fields>
            <field>
              <name>LTDCLPEN</name>
              <bitOffset>3</bitOffset>
              <bitWidth>1</bitWidth>
            </field>
            <field>
              <name>DSILPEN</name>
              <bitOffset>4</bitOffset>
              <bitWidth>1</bitWidth>
            </field>
            <field>
              <name>WWDG1LPEN</name>
              <bitOffset>6</bitOffset>
              <bitWidth>1</bitWidth>
            </field>
          </fields>
        </register>
        <register>
          <name>APB1LLPENR</name>
          <addressOffset>0x110</addressOffset>
          <size>0x20</size>
          <fields>
            <field>
              <name>TIM2LPEN</name>
              <bitOffset>0</bitOffset>
              <bitWidth>1</bitWidth>
            </field>
            <field>
              <name>TIM3LPEN</name>
              <bitOffset>1</bitOffset>
              <bitWidth>1</bitWidth>
            </field>
            <field>
              <name>TIM4LPEN</name>
              <bitOffset>2</bitOffset>
              <bitWidth>1</bitWidth>
            </field>
            <field>
              <name>TIM5LPEN</name>
              <bitOffset>3</bitOffset>
              <bitWidth>1</bitWidth>
            </field>
            <field>
              <name>TIM6LPEN</name>
              <bitOffset>4</bitOffset>
              <bitWidth>1</bitWidth>
            </field>
            <field>
              <name>TIM7LPEN</name>
              <bitOffset>5</bitOffset>
              <bitWidth>1</bitWidth>
            </field>
            <field>
              <name>TIM12LPEN</name>
              <bitOffset>6</bitOffset>
              <bitWidth>1</bitWidth>
            </field>
            <field>
              <name>TIM13LPEN</name>
              <bitOffset>7</bitOffset>
              <bitWidth>1</bitWidth>
            </field>
            <field>
              <name>TIM14LPEN</name>
              <bitOffset>8</bitOffset>
              <bitWidth>1</bitWidth>
            </field>
            <field>
              <name>LPTIM1LPEN</name>
              <bitOffset>9</bitOffset>
              <bitWidth>1</bitWidth>
            </field>
            <field>
              <name>WWDG2LPEN</name>
              <bitOffset>11</bitOffset>
              <bitWidth>1</bitWidth>
            </field>
            <field>
              <name>SPI2LPEN</name>
              <bitOffset>14</bitOffset>
              <bitWidth>1</bitWidth>
            </field>
            <field>
              <name>SPI3LPEN</name>
              <bitOffset>15</bitOffset>
              <bitWidth>1</bitWidth>
            </field>
            <field>
              <name>SPDIFRXLPEN</name>
              <bitOffset>16</bitOffset>
              <bitWidth>1</bitWidth>
            </field>
            <field>
              <name>USART2LPEN</name>
              <bitOffset>17</bitOffset>
              <bitWidth>1</bitWidth>
            </field>
            <field>
              <name>USART3LPEN</name>
              <bitOffset>18</bitOffset>
              <bitWidth>1</bitWidth>
            </field>
            <field>
              <name>UART4LPEN</name>
              <bitOffset>19</bitOffset>
              <bitWidth>1</bitWidth>
            </field>
            <field>
              <name>UART5LPEN</name>
              <bitOffset>20</bitOffset>
              <bitWidth>1</bitWidth>
            </field>
            <field>
              <name>I2C1LPEN</name>
              <bitOffset>21</bitOffset>
              <bitWidth>1</bitWidth>
            </field>
            <field>
              <name>I2C2LPEN</name>
              <bitOffset>22</bitOffset>
              <bitWidth>1</bitWidth>
            </field>
            <field>
              <name>I2C3LPEN</name>
              <bitOffset>23</bitOffset>
              <bitWidth>1</bitWidth>
            </field>
            <field>
              <name>HDMICECEN</name>
              <bitOffset>27</bitOffset>
              <bitWidth>1</bitWidth>
            </field>
            <field>
              <name>DAC12LPEN</name>
              <bitOffset>29</bitOffset>
              <bitWidth>1</bitWidth>
            </field>
            <field>
              <name>UART7LPEN</name>
              <bitOffset>30</bitOffset>
              <bitWidth>1</bitWidth>
            </field>
            <field>
              <name>UART8LPEN</name>
              <bitOffset>31</bitOffset>
              <bitWidth>1</bitWidth>
            </field>
          </fields>
        </register>
        <register>
          <name>APB1HLPENR</name>
          <addressOffset>0x114</addressOffset>
          <size>0x20</size>
          <fields>
            <field>
              <name>CRSLPEN</name>
              <bitOffset>1</bitOffset>
              <bitWidth>1</bitWidth>
            </field>
            <field>
              <name>SWPMILPEN</name>
              <bitOffset>2</bitOffset>
              <bitWidth>1</bitWidth>
            </field>
            <field>
              <name>OPAMPLPEN</name>
              <bitOffset>4</bitOffset>
              <bitWidth>1</bitWidth>
            </field>
            <field>
              <name>MDIOSLPEN</name>
              <bitOffset>5</bitOffset>
              <bitWidth>1</bitWidth>
            </field>
            <field>
              <name>FDCANLPEN</name>
              <bitOffset>8</bitOffset>
              <bitWidth>1</bitWidth>
            </field>
          </fields>
        </register>
        <register>
          <name>APB2LPENR</name>
          <addressOffset>0x118</addressOffset>
          <size>0x20</size>
          <fields>
            <field>
              <name>TIM1LPEN</name>
              <bitOffset>0</bitOffset>
              <bitWidth>1</bitWidth>
            </field>
            <field>
              <name>TIM8LPEN</name>
              <bitOffset>1</bitOffset>
              <bitWidth>1</bitWidth>
            </field>
            <field>
              <name>USART1LPEN</name>
              <bitOffset>4</bitOffset>
              <bitWidth>1</bitWidth>
            </field>
            <field>
              <name>USART6LPEN</name>
              <bitOffset>5</bitOffset>
              <bitWidth>1</bitWidth>
            </field>
            <field>
              <name>SPI1LPEN</name>
              <bitOffset>12</bitOffset>
              <bitWidth>1</bitWidth>
            </field>
            <field>
              <name>SPI4LPEN</name>
              <bitOffset>13</bitOffset>
              <bitWidth>1</bitWidth>
            </field>
            <field>
              <name>TIM15LPEN</name>
              <bitOffset>16</bitOffset>
              <bitWidth>1</bitWidth>
            </field>
            <field>
              <name>TIM16LPEN</name>
              <bitOffset>17</bitOffset>
              <bitWidth>1</bitWidth>
            </field>
            <field>
              <name>TIM17LPEN</name>
              <bitOffset>18</bitOffset>
              <bitWidth>1</bitWidth>
            </field>
            <field>
              <name>SPI5LPEN</name>
              <bitOffset>20</bitOffset>
              <bitWidth>1</bitWidth>
            </field>
            <field>
              <name>SAI1LPEN</name>
              <bitOffset>22</bitOffset>
              <bitWidth>1</bitWidth>
            </field>
            <field>
              <name>SAI2LPEN</name>
              <bitOffset>23</bitOffset>
              <bitWidth>1</bitWidth>
            </field>
            <field>
              <name>SAI3LPEN</name>
              <bitOffset>24</bitOffset>
              <bitWidth>1</bitWidth>
            </field>
            <field>
              <name>DFSDM1LPEN</name>
              <bitOffset>28</bitOffset>
              <bitWidth>1</bitWidth>
            </field>
            <field>
              <name>HRTIMLPEN</name>
              <bitOffset>29</bitOffset>
              <bitWidth>1</bitWidth>
            </field>
          </fields>
        </register>
        <register>
          <name>APB4LPENR</name>
          <addressOffset>0x11c</addressOffset>
          <size>0x20</size>
          <fields>
            <field>
              <name>SYSCFGLPEN</name>
              <bitOffset>1</bitOffset>
              <bitWidth>1</bitWidth>
            </field>
            <field>
              <name>LPUART1LPEN</name>
              <bitOffset>3</bitOffset>
              <bitWidth>1</bitWidth>
            </field>
            <field>
              <name>SPI6LPEN</name>
              <bitOffset>5</bitOffset>
              <bitWidth>1</bitWidth>
            </field>
            <field>
              <name>I2C4LPEN</name>
              <bitOffset>7</bitOffset>
              <bitWidth>1</bitWidth>
            </field>
            <field>
              <name>LPTIM2LPEN</name>
              <bitOffset>9</bitOffset>
              <bitWidth>1</bitWidth>
            </field>
            <field>
              <name>LPTIM3LPEN</name>
              <bitOffset>10</bitOffset>
              <bitWidth>1</bitWidth>
            </field>
            <field>
              <name>LPTIM4LPEN</name>
              <bitOffset>11</bitOffset>
              <bitWidth>1</bitWidth>
            </field>
            <field>
              <name>LPTIM5LPEN</name>
              <bitOffset>12</bitOffset>
              <bitWidth>1</bitWidth>
            </field>
            <field>
              <name>COMP12LPEN</name>
              <bitOffset>14</bitOffset>
              <bitWidth>1</bitWidth>
            </field>
            <field>
              <name>VREFLPEN</name>
              <bitOffset>15</bitOffset>
              <bitWidth>1</bitWidth>
            </field>
            <field>
              <name>RTCAPBLPEN</name>
              <bitOffset>16</bitOffset>
              <bitWidth>1</bitWidth>
            </field>
            <field>
              <name>SAI4LPEN</name>
              <bitOffset>21</bitOffset>
              <bitWidth>1</bitWidth>
            </field>
          </fields>
        </register>
      </registers>
    </peripheral>
    <peripheral>
      <name>RCC_C1</name>
      <baseAddress>0x58024530</baseAddress>
      <registers>
        <register>
          <name>RSR</name>
          <addressOffset>0x0</addressOffset>
          <size>0x20</size>
          <fields>
            <field>
              <name>RMVF</name>
              <bitOffset>16</bitOffset>
              <bitWidth>1</bitWidth>
            </field>
            <field>
              <name>C1RSTF</name>
              <bitOffset>17</bitOffset>
              <bitWidth>1</bitWidth>
            </field>
            <field>
              <name>C2RSTF</name>
              <bitOffset>18</bitOffset>
              <bitWidth>1</bitWidth>
            </field>
            <field>
              <name>D1RSTF</name>
              <bitOffset>19</bitOffset>
              <bitWidth>1</bitWidth>
            </field>
            <field>
              <name>D2RSTF</name>
              <bitOffset>20</bitOffset>
              <bitWidth>1</bitWidth>
            </field>
            <field>
              <name>BORRSTF</name>
              <bitOffset>21</bitOffset>
              <bitWidth>1</bitWidth>
            </field>
            <field>
              <name>PINRSTF</name>
              <bitOffset>22</bitOffset>
              <bitWidth>1</bitWidth>
            </field>
            <field>
              <name>PORRSTF</name>
              <bitOffset>23</bitOffset>
              <bitWidth>1</bitWidth>
            </field>
            <field>
              <name>SFT1RSTF</name>
              <bitOffset>24</bitOffset>
              <bitWidth>1</bitWidth>
            </field>
            <field>
              <name>SFT2RSTF</name>
              <bitOffset>25</bitOffset>
              <bitWidth>1</bitWidth>
            </field>
            <field>
              <name>IWDG1RSTF</name>
              <bitOffset>26</bitOffset>
              <bitWidth>1</bitWidth>
            </field>
            <field>
              <name>IWDG2RSTF</name>
              <bitOffset>27</bitOffset>
              <bitWidth>1</bitWidth>
            </field>
            <field>
              <name>WWDG1RSTF</name>
              <bitOffset>28</bitOffset>
              <bitWidth>1</bitWidth>
            </field>
            <field>
              <name>WWDG2RSTF</name>
              <bitOffset>29</bitOffset>
              <bitWidth>1</bitWidth>
            </field>
            <field>
              <name>LPWR1RSTF</name>
              <bitOffset>30</bitOffset>
              <bitWidth>1</bitWidth>
            </field>
            <field>
              <name>LPWR2RSTF</name>
              <bitOffset>31</bitOffset>
              <bitWidth>1</bitWidth>
            </field>
          </fields>
        </register>
        <register>
          <name>AHB3ENR</name>
          <addressOffset>0x4</addressOffset>
          <size>0x20</size>
          <fields>
            <field>
              <name>MDMAEN</name>
              <bitOffset>0</bitOffset>
              <bitWidth>1</bitWidth>
            </field>
            <field>
              <name>DMA2DEN</name>
              <bitOffset>4</bitOffset>
              <bitWidth>1</bitWidth>
            </field>
            <field>
              <name>JPGDECEN</name>
              <bitOffset>5</bitOffset>
              <bitWidth>1</bitWidth>
            </field>
            <field>
              <name>FLASHEN</name>
              <bitOffset>8</bitOffset>
              <bitWidth>1</bitWidth>
            </field>
            <field>
              <name>FMCEN</name>
              <bitOffset>12</bitOffset>
              <bitWidth>1</bitWidth>
            </field>
            <field>
              <name>QSPIEN</name>
              <bitOffset>14</bitOffset>
              <bitWidth>1</bitWidth>
            </field>
            <field>
              <name>SDMMC1EN</name>
              <bitOffset>16</bitOffset>
              <bitWidth>1</bitWidth>
            </field>
            <field>
              <name>DTCM1EN</name>
              <bitOffset>28</bitOffset>
              <bitWidth>1</bitWidth>
            </field>
            <field>
              <name>DTCM2EN</name>
              <bitOffset>29</bitOffset>
              <bitWidth>1</bitWidth>
            </field>
            <field>
              <name>ITCMEN</name>
              <bitOffset>30</bitOffset>
              <bitWidth>1</bitWidth>
            </field>
            <field>
              <name>D1SRAM1EN</name>
              <bitOffset>31</bitOffset>
              <bitWidth>1</bitWidth>
            </field>
          </fields>
        </register>
        <register>
          <name>AHB1ENR</name>
          <addressOffset>0x8</addressOffset>
          <size>0x20</size>
          <fields>
            <field>
              <name>DMA1EN</name>
              <bitOffset>0</bitOffset>
              <bitWidth>1</bitWidth>
            </field>
            <field>
              <name>DMA2EN</name>
              <bitOffset>1</bitOffset>
              <bitWidth>1</bitWidth>
            </field>
            <field>
              <name>ADC12EN</name>
              <bitOffset>5</bitOffset>
              <bitWidth>1</bitWidth>
            </field>
            <field>
              <name>ARTEN</name>
              <bitOffset>14</bitOffset>
              <bitWidth>1</bitWidth>
            </field>
            <field>
              <name>ETH1MACEN</name>
              <bitOffset>15</bitOffset>
              <bitWidth>1</bitWidth>
            </field>
            <field>
              <name>ETH1TXEN</name>
              <bitOffset>16</bitOffset>
              <bitWidth>1</bitWidth>
            </field>
            <field>
              <name>ETH1RXEN</name>
              <bitOffset>17</bitOffset>
              <bitWidth>1</bitWidth>
            </field>
            <field>
              <name>USB1OTGHSEN</name>
              <bitOffset>25</bitOffset>
              <bitWidth>1</bitWidth>
            </field>
            <field>
              <name>USB1OTGHSULPIEN</name>
              <bitOffset>26</bitOffset>
              <bitWidth>1</bitWidth>
            </field>
            <field>
              <name>USB2OTGHSEN</name>
              <bitOffset>27</bitOffset>
              <bitWidth>1</bitWidth>
            </field>
            <field>
              <name>USB2OTGHSULPIEN</name>
              <bitOffset>28</bitOffset>
              <bitWidth>1</bitWidth>
            </field>
          </fields>
        </register>
        <register>
          <name>AHB2ENR</name>
          <addressOffset>0xc</addressOffset>
          <size>0x20</size>
          <fields>
            <field>
              <name>DCMIEN</name>
              <bitOffset>0</bitOffset>
              <bitWidth>1</bitWidth>
            </field>
            <field>
              <name>CRYPEN</name>
              <bitOffset>4</bitOffset>
              <bitWidth>1</bitWidth>
            </field>
            <field>
              <name>HASHEN</name>
              <bitOffset>5</bitOffset>
              <bitWidth>1</bitWidth>
            </field>
            <field>
              <name>RNGEN</name>
              <bitOffset>6</bitOffset>
              <bitWidth>1</bitWidth>
            </field>
            <field>
              <name>SDMMC2EN</name>
              <bitOffset>9</bitOffset>
              <bitWidth>1</bitWidth>
            </field>
            <field>
              <name>SRAM1EN</name>
              <bitOffset>29</bitOffset>
              <bitWidth>1</bitWidth>
            </field>
            <field>
              <name>SRAM2EN</name>
              <bitOffset>30</bitOffset>
              <bitWidth>1</bitWidth>
            </field>
            <field>
              <name>SRAM3EN</name>
              <bitOffset>31</bitOffset>
              <bitWidth>1</bitWidth>
            </field>
          </fields>
        </register>
        <register>
          <name>AHB4ENR</name>
          <addressOffset>0x10</addressOffset>
          <size>0x20</size>
          <fields>
            <field>
              <name>GPIOAEN</name>
              <bitOffset>0</bitOffset>
              <bitWidth>1</bitWidth>
            </field>
            <field>
              <name>GPIOBEN</name>
              <bitOffset>1</bitOffset>
              <bitWidth>1</bitWidth>
            </field>
            <field>
              <name>GPIOCEN</name>
              <bitOffset>2</bitOffset>
              <bitWidth>1</bitWidth>
            </field>
            <field>
              <name>GPIODEN</name>
              <bitOffset>3</bitOffset>
              <bitWidth>1</bitWidth>
            </field>
            <field>
              <name>GPIOEEN</name>
              <bitOffset>4</bitOffset>
              <bitWidth>1</bitWidth>
            </field>
            <field>
              <name>GPIOFEN</name>
              <bitOffset>5</bitOffset>
              <bitWidth>1</bitWidth>
            </field>
            <field>
              <name>GPIOGEN</name>
              <bitOffset>6</bitOffset>
              <bitWidth>1</bitWidth>
            </field>
            <field>
              <name>GPIOHEN</name>
              <bitOffset>7</bitOffset>
              <bitWidth>1</bitWidth>
            </field>
            <field>
              <name>GPIOIEN</name>
              <bitOffset>8</bitOffset>
              <bitWidth>1</bitWidth>
            </field>
            <field>
              <name>GPIOJEN</name>
              <bitOffset>9</bitOffset>
              <bitWidth>1</bitWidth>
            </field>
            <field>
              <name>GPIOKEN</name>
              <bitOffset>10</bitOffset>
              <bitWidth>1</bitWidth>
            </field>
            <field>
              <name>CRCEN</name>
              <bitOffset>19</bitOffset>
              <bitWidth>1</bitWidth>
            </field>
            <field>
              <name>BDMAEN</name>
              <bitOffset>21</bitOffset>
              <bitWidth>1</bitWidth>
            </field>
            <field>
              <name>ADC3EN</name>
              <bitOffset>24</bitOffset>
              <bitWidth>1</bitWidth>
            </field>
            <field>
              <name>HSEMEN</name>
              <bitOffset>25</bitOffset>
              <bitWidth>1</bitWidth>
            </field>
            <field>
              <name>BKPRAMEN</name>
              <bitOffset>28</bitOffset>
              <bitWidth>1</bitWidth>
            </field>
          </fields>
        </register>
        <register>
          <name>APB3ENR</name>
          <addressOffset>0x14</addressOffset>
          <size>0x20</size>
          <fields>
            <field>
              <name>LTDCEN</name>
              <bitOffset>3</bitOffset>
              <bitWidth>1</bitWidth>
            </field>
            <field>
              <name>DSIEN</name>
              <bitOffset>4</bitOffset>
              <bitWidth>1</bitWidth>
            </field>
            <field>
              <name>WWDG1EN</name>
              <bitOffset>6</bitOffset>
              <bitWidth>1</bitWidth>
            </field>
          </fields>
        </register>
        <register>
          <name>APB1LENR</name>
          <addressOffset>0x18</addressOffset>
          <size>0x20</size>
          <fields>
            <field>
              <name>TIM2EN</name>
              <bitOffset>0</bitOffset>
              <bitWidth>1</bitWidth>
            </field>
            <field>
              <name>TIM3EN</name>
              <bitOffset>1</bitOffset>
              <bitWidth>1</bitWidth>
            </field>
            <field>
              <name>TIM4EN</name>
              <bitOffset>2</bitOffset>
              <bitWidth>1</bitWidth>
            </field>
            <field>
              <name>TIM5EN</name>
              <bitOffset>3</bitOffset>
              <bitWidth>1</bitWidth>
            </field>
            <field>
              <name>TIM6EN</name>
              <bitOffset>4</bitOffset>
              <bitWidth>1</bitWidth>
            </field>
            <field>
              <name>TIM7EN</name>
              <bitOffset>5</bitOffset>
              <bitWidth>1</bitWidth>
            </field>
            <field>
              <name>TIM12EN</name>
              <bitOffset>6</bitOffset>
              <bitWidth>1</bitWidth>
            </field>
            <field>
              <name>TIM13EN</name>
              <bitOffset>7</bitOffset>
              <bitWidth>1</bitWidth>
            </field>
            <field>
              <name>TIM14EN</name>
              <bitOffset>8</bitOffset>
              <bitWidth>1</bitWidth>
            </field>
            <field>
              <name>LPTIM1EN</name>
              <bitOffset>9</bitOffset>
              <bitWidth>1</bitWidth>
            </field>
            <field>
              <name>WWDG2EN</name>
              <bitOffset>11</bitOffset>
              <bitWidth>1</bitWidth>
            </field>
            <field>
              <name>SPI2EN</name>
              <bitOffset>14</bitOffset>
              <bitWidth>1</bitWidth>
            </field>
            <field>
              <name>SPI3EN</name>
              <bitOffset>15</bitOffset>
              <bitWidth>1</bitWidth>
            </field>
            <field>
              <name>SPDIFRXEN</name>
              <bitOffset>16</bitOffset>
              <bitWidth>1</bitWidth>
            </field>
            <field>
              <name>USART2EN</name>
              <bitOffset>17</bitOffset>
              <bitWidth>1</bitWidth>
            </field>
            <field>
              <name>USART3EN</name>
              <bitOffset>18</bitOffset>
              <bitWidth>1</bitWidth>
            </field>
            <field>
              <name>UART4EN</name>
              <bitOffset>19</bitOffset>
              <bitWidth>1</bitWidth>
            </field>
            <field>
              <name>UART5EN</name>
              <bitOffset>20</bitOffset>
              <bitWidth>1</bitWidth>
            </field>
            <field>
              <name>I2C1EN</name>
              <bitOffset>21</bitOffset>
              <bitWidth>1</bitWidth>
            </field>
            <field>
              <name>I2C2EN</name>
              <bitOffset>22</bitOffset>
              <bitWidth>1</bitWidth>
            </field>
            <field>
              <name>I2C3EN</name>
              <bitOffset>23</bitOffset>
              <bitWidth>1</bitWidth>
            </field>
            <field>
              <name>HDMICECEN</name>
              <bitOffset>27</bitOffset>
              <bitWidth>1</bitWidth>
            </field>
            <field>
              <name>DAC12EN</name>
              <bitOffset>29</bitOffset>
              <bitWidth>1</bitWidth>
            </field>
            <field>
              <name>UART7EN</name>
              <bitOffset>30</bitOffset>
              <bitWidth>1</bitWidth>
            </field>
            <field>
              <name>UART8EN</name>
              <bitOffset>31</bitOffset>
              <bitWidth>1</bitWidth>
            </field>
          </fields>
        </register>
        <register>
          <name>APB1HENR</name>
          <addressOffset>0x1c</addressOffset>
          <size>0x20</size>
          <fields>
            <field>
              <name>CRSEN</name>
              <bitOffset>1</bitOffset>
              <bitWidth>1</bitWidth>
            </field>
            <field>
              <name>SWPMIEN</name>
              <bitOffset>2</bitOffset>
              <bitWidth>1</bitWidth>
            </field>
            <field>
              <name>OPAMPEN</name>
              <bitOffset>4</bitOffset>
              <bitWidth>1</bitWidth>
            </field>
            <field>
              <name>MDIOSEN</name>
              <bitOffset>5</bitOffset>
              <bitWidth>1</bitWidth>
            </field>
            <field>
              <name>FDCANEN</name>
              <bitOffset>8</bitOffset>
              <bitWidth>1</bitWidth>
            </field>
          </fields>
        </register>
        <register>
          <name>APB2ENR</name>
          <addressOffset>0x20</addressOffset>
          <size>0x20</size>
          <fields>
            <field>
              <name>TIM1EN</name>
              <bitOffset>0</bitOffset>
              <bitWidth>1</bitWidth>
            </field>
            <field>
              <name>TIM8EN</name>
              <bitOffset>1</bitOffset>
              <bitWidth>1</bitWidth>
            </field>
            <field>
              <name>USART1EN</name>
              <bitOffset>4</bitOffset>
              <bitWidth>1</bitWidth>
            </field>
            <field>
              <name>USART6EN</name>
              <bitOffset>5</bitOffset>
              <bitWidth>1</bitWidth>
            </field>
            <field>
              <name>SPI1EN</name>
              <bitOffset>12</bitOffset>
              <bitWidth>1</bitWidth>
            </field>
            <field>
              <name>SPI4EN</name>
              <bitOffset>13</bitOffset>
              <bitWidth>1</bitWidth>
            </field>
            <field>
              <name>TIM15EN</name>
              <bitOffset>16</bitOffset>
              <bitWidth>1</bitWidth>
            </field>
            <field>
              <name>TIM16EN</name>
              <bitOffset>17</bitOffset>
              <bitWidth>1</bitWidth>
            </field>
            <field>
              <name>TIM17EN</name>
              <bitOffset>18</bitOffset>
              <bitWidth>1</bitWidth>
            </field>
            <field>
              <name>SPI5EN</name>
              <bitOffset>20</bitOffset>
              <bitWidth>1</bitWidth>
            </field>
            <field>
              <name>SAI1EN</name>
              <bitOffset>22</bitOffset>
              <bitWidth>1</bitWidth>
            </field>
            <field>
              <name>SAI2EN</name>
              <bitOffset>23</bitOffset>
              <bitWidth>1</bitWidth>
            </field>
            <field>
              <name>SAI3EN</name>
              <bitOffset>24</bitOffset>
              <bitWidth>1</bitWidth>
            </field>
            <field>
              <name>DFSDM1EN</name>
              <bitOffset>28</bitOffset>
              <bitWidth>1</bitWidth>
            </field>
            <field>
              <name>HRTIMEN</name>
              <bitOffset>29</bitOffset>
              <bitWidth>1</bitWidth>
            </field>
          </fields>
        </register>
        <register>
          <name>APB4ENR</name>
          <addressOffset>0x24</addressOffset>
          <size>0x20</size>
          <fields>
            <field>
              <name>SYSCFGEN</name>
              <bitOffset>1</bitOffset>
              <bitWidth>1</bitWidth>
            </field>
            <field>
              <name>LPUART1EN</name>
              <bitOffset>3</bitOffset>
              <bitWidth>1</bitWidth>
            </field>
            <field>
              <name>SPI6EN</name>
              <bitOffset>5</bitOffset>
              <bitWidth>1</bitWidth>
            </field>
            <field>
              <name>I2C4EN</name>
              <bitOffset>7</bitOffset>
              <bitWidth>1</bitWidth>
            </field>
            <field>
              <name>LPTIM2EN</name>
              <bitOffset>9</bitOffset>
              <bitWidth>1</bitWidth>
            </field>
            <field>
              <name>LPTIM3EN</name>
              <bitOffset>10</bitOffset>
              <bitWidth>1</bitWidth>
            </field>
            <field>
              <name>LPTIM4EN</name>
              <bitOffset>11</bitOffset>
              <bitWidth>1</bitWidth>
            </field>
            <field>
              <name>LPTIM5EN</name>
              <bitOffset>12</bitOffset>
              <bitWidth>1</bitWidth>
            </field>
            <field>
              <name>COMP12EN</name>
              <bitOffset>14</bitOffset>
              <bitWidth>1</bitWidth>
            </field>
            <field>
              <name>VREFEN</name>
              <bitOffset>15</bitOffset>
              <bitWidth>1</bitWidth>
            </field>
            <field>
              <name>RTCAPBEN</name>
              <bitOffset>16</bitOffset>
              <bitWidth>1</bitWidth>
            </field>
            <field>
              <name>SAI4EN</name>
              <bitOffset>21</bitOffset>
              <bitWidth>1</bitWidth>
            </field>
          </fields>
        </register>
        <register>
          <name>AHB3LPENR</name>
          <addressOffset>0x2c</addressOffset>
          <size>0x20</size>
          <fields>
            <field>
              <name>MDMALPEN</name>
              <bitOffset>0</bitOffset>
              <bitWidth>1</bitWidth>
            </field>
            <field>
              <name>DMA2DLPEN</name>
              <bitOffset>4</bitOffset>
              <bitWidth>1</bitWidth>
            </field>
            <field>
              <name>JPGDECLPEN</name>
              <bitOffset>5</bitOffset>
              <bitWidth>1</bitWidth>
            </field>
            <field>
              <name>FLASHLPEN</name>
              <bitOffset>8</bitOffset>
              <bitWidth>1</bitWidth>
            </field>
            <field>
              <name>FMCLPEN</name>
              <bitOffset>12</bitOffset>
              <bitWidth>1</bitWidth>
            </field>
            <field>
              <name>QSPILPEN</name>
              <bitOffset>14</bitOffset>
              <bitWidth>1</bitWidth>
            </field>
            <field>
              <name>SDMMC1LPEN</name>
              <bitOffset>16</bitOffset>
              <bitWidth>1</bitWidth>
            </field>
            <field>
              <name>DTCM1LPEN</name>
              <bitOffset>28</bitOffset>
              <bitWidth>1</bitWidth>
            </field>
            <field>
              <name>DTCM2LPEN</name>
              <bitOffset>29</bitOffset>
              <bitWidth>1</bitWidth>
            </field>
            <field>
              <name>ITCMLPEN</name>
              <bitOffset>30</bitOffset>
              <bitWidth>1</bitWidth>
            </field>
            <field>
              <name>AXISRAMLPEN</name>
              <bitOffset>31</bitOffset>
              <bitWidth>1</bitWidth>
            </field>
          </fields>
        </register>
        <register>
          <name>AHB1LPENR</name>
          <addressOffset>0x30</addressOffset>
          <size>0x20</size>
          <fields>
            <field>
              <name>DMA1LPEN</name>
              <bitOffset>0</bitOffset>
              <bitWidth>1</bitWidth>
            </field>
            <field>
              <name>DMA2LPEN</name>
              <bitOffset>1</bitOffset>
              <bitWidth>1</bitWidth>
            </field>
            <field>
              <name>ADC12LPEN</name>
              <bitOffset>5</bitOffset>
              <bitWidth>1</bitWidth>
            </field>
            <field>
              <name>ARTLPEN</name>
              <bitOffset>14</bitOffset>
              <bitWidth>1</bitWidth>
            </field>
            <field>
              <name>ETH1MACLPEN</name>
              <bitOffset>15</bitOffset>
              <bitWidth>1</bitWidth>
            </field>
            <field>
              <name>ETH1TXLPEN</name>
              <bitOffset>16</bitOffset>
              <bitWidth>1</bitWidth>
            </field>
            <field>
              <name>ETH1RXLPEN</name>
              <bitOffset>17</bitOffset>
              <bitWidth>1</bitWidth>
            </field>
            <field>
              <name>USB1OTGHSLPEN</name>
              <bitOffset>25</bitOffset>
              <bitWidth>1</bitWidth>
            </field>
            <field>
              <name>USB1OTGHSULPILPEN</name>
              <bitOffset>26</bitOffset>
              <bitWidth>1</bitWidth>
            </field>
            <field>
              <name>USB2OTGHSLPEN</name>
              <bitOffset>27</bitOffset>
              <bitWidth>1</bitWidth>
            </field>
            <field>
              <name>USB2OTGHSULPILPEN</name>
              <bitOffset>28</bitOffset>
              <bitWidth>1</bitWidth>
            </field>
          </fields>
        </register>
        <register>
          <name>AHB2LPENR</name>
          <addressOffset>0x34</addressOffset>
          <size>0x20</size>
          <fields>
            <field>
              <name>DCMILPEN</name>
              <bitOffset>0</bitOffset>
              <bitWidth>1</bitWidth>
            </field>
            <field>
              <name>CRYPLPEN</name>
              <bitOffset>4</bitOffset>
              <bitWidth>1</bitWidth>
            </field>
            <field>
              <name>HASHLPEN</name>
              <bitOffset>5</bitOffset>
              <bitWidth>1</bitWidth>
            </field>
            <field>
              <name>RNGLPEN</name>
              <bitOffset>6</bitOffset>
              <bitWidth>1</bitWidth>
            </field>
            <field>
              <name>SDMMC2LPEN</name>
              <bitOffset>9</bitOffset>
              <bitWidth>1</bitWidth>
            </field>
            <field>
              <name>SRAM1LPEN</name>
              <bitOffset>29</bitOffset>
              <bitWidth>1</bitWidth>
            </field>
            <field>
              <name>SRAM2LPEN</name>
              <bitOffset>30</bitOffset>
              <bitWidth>1</bitWidth>
            </field>
            <field>
              <name>SRAM3LPEN</name>
              <bitOffset>31</bitOffset>
              <bitWidth>1</bitWidth>
            </field>
          </fields>
        </register>
        <register>
          <name>AHB4LPENR</name>
          <addressOffset>0x38</addressOffset>
          <size>0x20</size>
          <fields>
            <field>
              <name>GPIOALPEN</name>
              <bitOffset>0</bitOffset>
              <bitWidth>1</bitWidth>
            </field>
            <field>
              <name>GPIOBLPEN</name>
              <bitOffset>1</bitOffset>
              <bitWidth>1</bitWidth>
            </field>
            <field>
              <name>GPIOCLPEN</name>
              <bitOffset>2</bitOffset>
              <bitWidth>1</bitWidth>
            </field>
            <field>
              <name>GPIODLPEN</name>
              <bitOffset>3</bitOffset>
              <bitWidth>1</bitWidth>
            </field>
            <field>
              <name>GPIOELPEN</name>
              <bitOffset>4</bitOffset>
              <bitWidth>1</bitWidth>
            </field>
            <field>
              <name>GPIOFLPEN</name>
              <bitOffset>5</bitOffset>
              <bitWidth>1</bitWidth>
            </field>
            <field>
              <name>GPIOGLPEN</name>
              <bitOffset>6</bitOffset>
              <bitWidth>1</bitWidth>
            </field>
            <field>
              <name>GPIOHLPEN</name>
              <bitOffset>7</bitOffset>
              <bitWidth>1</bitWidth>
            </field>
            <field>
              <name>GPIOILPEN</name>
              <bitOffset>8</bitOffset>
              <bitWidth>1</bitWidth>
            </field>
            <field>
              <name>GPIOJLPEN</name>
              <bitOffset>9</bitOffset>
              <bitWidth>1</bitWidth>
            </field>
            <field>
              <name>GPIOKLPEN</name>
              <bitOffset>10</bitOffset>
              <bitWidth>1</bitWidth>
            </field>
            <field>
              <name>CRCLPEN</name>
              <bitOffset>19</bitOffset>
              <bitWidth>1</bitWidth>
            </field>
            <field>
              <name>BDMALPEN</name>
              <bitOffset>21</bitOffset>
              <bitWidth>1</bitWidth>
            </field>
            <field>
              <name>ADC3LPEN</name>
              <bitOffset>24</bitOffset>
              <bitWidth>1</bitWidth>
            </field>
            <field>
              <name>BKPRAMLPEN</name>
              <bitOffset>28</bitOffset>
              <bitWidth>1</bitWidth>
            </field>
            <field>
              <name>SRAM4LPEN</name>
              <bitOffset>29</bitOffset>
              <bitWidth>1</bitWidth>
            </field>
          </fields>
        </register>
        <register>
          <name>APB3LPENR</name>
          <addressOffset>0x3c</addressOffset>
          <size>0x20</size>
          <fields>
            <field>
              <name>LTDCLPEN</name>
              <bitOffset>3</bitOffset>
              <bitWidth>1</bitWidth>
            </field>
            <field>
              <name>DSILPEN</name>
              <bitOffset>4</bitOffset>
              <bitWidth>1</bitWidth>
            </field>
            <field>
              <name>WWDG1LPEN</name>
              <bitOffset>6</bitOffset>
              <bitWidth>1</bitWidth>
            </field>
          </fields>
        </register>
        <register>
          <name>APB1LLPENR</name>
          <addressOffset>0x40</addressOffset>
          <size>0x20</size>
          <fields>
            <field>
              <name>TIM2LPEN</name>
              <bitOffset>0</bitOffset>
              <bitWidth>1</bitWidth>
            </field>
            <field>
              <name>TIM3LPEN</name>
              <bitOffset>1</bitOffset>
              <bitWidth>1</bitWidth>
            </field>
            <field>
              <name>TIM4LPEN</name>
              <bitOffset>2</bitOffset>
              <bitWidth>1</bitWidth>
            </field>
            <field>
              <name>TIM5LPEN</name>
              <bitOffset>3</bitOffset>
              <bitWidth>1</bitWidth>
            </field>
            <field>
              <name>TIM6LPEN</name>
              <bitOffset>4</bitOffset>
              <bitWidth>1</bitWidth>
            </field>
            <field>
              <name>TIM7LPEN</name>
              <bitOffset>5</bitOffset>
              <bitWidth>1</bitWidth>
            </field>
            <field>
              <name>TIM12LPEN</name>
              <bitOffset>6</bitOffset>
              <bitWidth>1</bitWidth>
            </field>
            <field>
              <name>TIM13LPEN</name>
              <bitOffset>7</bitOffset>
              <bitWidth>1</bitWidth>
            </field>
            <field>
              <name>TIM14LPEN</name>
              <bitOffset>8</bitOffset>
              <bitWidth>1</bitWidth>
            </field>
            <field>
              <name>LPTIM1LPEN</name>
              <bitOffset>9</bitOffset>
              <bitWidth>1</bitWidth>
            </field>
            <field>
              <name>WWDG2LPEN</name>
              <bitOffset>11</bitOffset>
              <bitWidth>1</bitWidth>
            </field>
            <field>
              <name>SPI2LPEN</name>
              <bitOffset>14</bitOffset>
              <bitWidth>1</bitWidth>
            </field>
            <field>
              <name>SPI3LPEN</name>
              <bitOffset>15</bitOffset>
              <bitWidth>1</bitWidth>
            </field>
            <field>
              <name>SPDIFRXLPEN</name>
              <bitOffset>16</bitOffset>
              <bitWidth>1</bitWidth>
            </field>
            <field>
              <name>USART2LPEN</name>
              <bitOffset>17</bitOffset>
              <bitWidth>1</bitWidth>
            </field>
            <field>
              <name>USART3LPEN</name>
              <bitOffset>18</bitOffset>
              <bitWidth>1</bitWidth>
            </field>
            <field>
              <name>UART4LPEN</name>
              <bitOffset>19</bitOffset>
              <bitWidth>1</bitWidth>
            </field>
            <field>
              <name>UART5LPEN</name>
              <bitOffset>20</bitOffset>
              <bitWidth>1</bitWidth>
            </field>
            <field>
              <name>I2C1LPEN</name>
              <bitOffset>21</bitOffset>
              <bitWidth>1</bitWidth>
            </field>
            <field>
              <name>I2C2LPEN</name>
              <bitOffset>22</bitOffset>
              <bitWidth>1</bitWidth>
            </field>
            <field>
              <name>I2C3LPEN</name>
              <bitOffset>23</bitOffset>
              <bitWidth>1</bitWidth>
            </field>
            <field>
              <name>HDMICECEN</name>
              <bitOffset>27</bitOffset>
              <bitWidth>1</bitWidth>
            </field>
            <field>
              <name>DAC12LPEN</name>
              <bitOffset>29</bitOffset>
              <bitWidth>1</bitWidth>
            </field>
            <field>
              <name>UART7LPEN</name>
              <bitOffset>30</bitOffset>
              <bitWidth>1</bitWidth>
            </field>
            <field>
              <name>UART8LPEN</name>
              <bitOffset>31</bitOffset>
              <bitWidth>1</bitWidth>
            </field>
          </fields>
        </register>
        <register>
          <name>APB1HLPENR</name>
          <addressOffset>0x44</addressOffset>
          <size>0x20</size>
          <fields>
            <field>
              <name>CRSLPEN</name>
              <bitOffset>1</bitOffset>
              <bitWidth>1</bitWidth>
            </field>
            <field>
              <name>SWPMILPEN</name>
              <bitOffset>2</bitOffset>
              <bitWidth>1</bitWidth>
            </field>
            <field>
              <name>OPAMPLPEN</name>
              <bitOffset>4</bitOffset>
              <bitWidth>1</bitWidth>
            </field>
            <field>
              <name>MDIOSLPEN</name>
              <bitOffset>5</bitOffset>
              <bitWidth>1</bitWidth>
            </field>
            <field>
              <name>FDCANLPEN</name>
              <bitOffset>8</bitOffset>
              <bitWidth>1</bitWidth>
            </field>
          </fields>
        </register>
        <register>
          <name>APB2LPENR</name>
          <addressOffset>0x48</addressOffset>
          <size>0x20</size>
          <fields>
            <field>
              <name>TIM1LPEN</name>
              <bitOffset>0</bitOffset>
              <bitWidth>1</bitWidth>
            </field>
            <field>
              <name>TIM8LPEN</name>
              <bitOffset>1</bitOffset>
              <bitWidth>1</bitWidth>
            </field>
            <field>
              <name>USART1LPEN</name>
              <bitOffset>4</bitOffset>
              <bitWidth>1</bitWidth>
            </field>
            <field>
              <name>USART6LPEN</name>
              <bitOffset>5</bitOffset>
              <bitWidth>1</bitWidth>
            </field>
            <field>
              <name>SPI1LPEN</name>
              <bitOffset>12</bitOffset>
              <bitWidth>1</bitWidth>
            </field>
            <field>
              <name>SPI4LPEN</name>
              <bitOffset>13</bitOffset>
              <bitWidth>1</bitWidth>
            </field>
            <field>
              <name>TIM15LPEN</name>
              <bitOffset>16</bitOffset>
              <bitWidth>1</bitWidth>
            </field>
            <field>
              <name>TIM16LPEN</name>
              <bitOffset>17</bitOffset>
              <bitWidth>1</bitWidth>
            </field>
            <field>
              <name>TIM17LPEN</name>
              <bitOffset>18</bitOffset>
              <bitWidth>1</bitWidth>
            </field>
            <field>
              <name>SPI5LPEN</name>
              <bitOffset>20</bitOffset>
              <bitWidth>1</bitWidth>
            </field>
            <field>
              <name>SAI1LPEN</name>
              <bitOffset>22</bitOffset>
              <bitWidth>1</bitWidth>
            </field>
            <field>
              <name>SAI2LPEN</name>
              <bitOffset>23</bitOffset>
              <bitWidth>1</bitWidth>
            </field>
            <field>
              <name>SAI3LPEN</name>
              <bitOffset>24</bitOffset>
              <bitWidth>1</bitWidth>
            </field>
            <field>
              <name>DFSDM1LPEN</name>
              <bitOffset>28</bitOffset>
              <bitWidth>1</bitWidth>
            </field>
            <field>
              <name>HRTIMLPEN</name>
              <bitOffset>29</bitOffset>
              <bitWidth>1</bitWidth>
            </field>
          </fields>
        </register>
        <register>
          <name>APB4LPENR</name>
          <addressOffset>0x4c</addressOffset>
          <size>0x20</size>
          <fields>
            <field>
              <name>SYSCFGLPEN</name>
              <bitOffset>1</bitOffset>
              <bitWidth>1</bitWidth>
            </field>
            <field>
              <name>LPUART1LPEN</name>
              <bitOffset>3</bitOffset>
              <bitWidth>1</bitWidth>
            </field>
            <field>
              <name>SPI6LPEN</name>
              <bitOffset>5</bitOffset>
              <bitWidth>1</bitWidth>
            </field>
            <field>
              <name>I2C4LPEN</name>
              <bitOffset>7</bitOffset>
              <bitWidth>1</bitWidth>
            </field>
            <field>
              <name>LPTIM2LPEN</name>
              <bitOffset>9</bitOffset>
              <bitWidth>1</bitWidth>
            </field>
            <field>
              <name>LPTIM3LPEN</name>
              <bitOffset>10</bitOffset>
              <bitWidth>1</bitWidth>
            </field>
            <field>
              <name>LPTIM4LPEN</name>
              <bitOffset>11</bitOffset>
              <bitWidth>1</bitWidth>
            </field>
            <field>
              <name>LPTIM5LPEN</name>
              <bitOffset>12</bitOffset>
              <bitWidth>1</bitWidth>
            </field>
            <field>
              <name>COMP12LPEN</name>
              <bitOffset>14</bitOffset>
              <bitWidth>1</bitWidth>
            </field>
            <field>
              <name>VREFLPEN</name>
              <bitOffset>15</bitOffset>
              <bitWidth>1</bitWidth>
            </field>
            <field>
              <name>RTCAPBLPEN</name>
              <bitOffset>16</bitOffset>
              <bitWidth>1</bitWidth>
            </field>
            <field>
              <name>SAI4LPEN</name>
              <bitOffset>21</bitOffset>
              <bitWidth>1</bitWidth>
            </field>
          </fields>
        </register>
      </registers>
    </peripheral>
    <peripheral>
      <name>RCC_C2</name>
      <baseAddress>0x58024590</baseAddress>
      <registers>
        <register>
          <name>RSR</name>
          <addressOffset>0x0</addressOffset>
          <size>0x20</size>
          <fields>
            <field>
              <name>RMVF</name>
              <bitOffset>16</bitOffset>
              <bitWidth>1</bitWidth>
            </field>
            <field>
              <name>C1RSTF</name>
              <bitOffset>17</bitOffset>
              <bitWidth>1</bitWidth>
            </field>
            <field>
              <name>C2RSTF</name>
              <bitOffset>18</bitOffset>
              <bitWidth>1</bitWidth>
            </field>
            <field>
              <name>D1RSTF</name>
              <bitOffset>19</bitOffset>
              <bitWidth>1</bitWidth>
            </field>
            <field>
              <name>D2RSTF</name>
              <bitOffset>20</bitOffset>
              <bitWidth>1</bitWidth>
            </field>
            <field>
              <name>BORRSTF</name>
              <bitOffset>21</bitOffset>
              <bitWidth>1</bitWidth>
            </field>
            <field>
              <name>PINRSTF</name>
              <bitOffset>22</bitOffset>
              <bitWidth>1</bitWidth>
            </field>
            <field>
              <name>PORRSTF</name>
              <bitOffset>23</bitOffset>
              <bitWidth>1</bitWidth>
            </field>
            <field>
              <name>SFT1RSTF</name>
              <bitOffset>24</bitOffset>
              <bitWidth>1</bitWidth>
            </field>
            <field>
              <name>SFT2RSTF</name>
              <bitOffset>25</bitOffset>
              <bitWidth>1</bitWidth>
            </field>
            <field>
              <name>IWDG1RSTF</name>
              <bitOffset>26</bitOffset>
              <bitWidth>1</bitWidth>
            </field>
            <field>
              <name>IWDG2RSTF</name>
              <bitOffset>27</bitOffset>
              <bitWidth>1</bitWidth>
            </field>
            <field>
              <name>WWDG1RSTF</name>
              <bitOffset>28</bitOffset>
              <bitWidth>1</bitWidth>
            </field>
            <field>
              <name>WWDG2RSTF</name>
              <bitOffset>29</bitOffset>
              <bitWidth>1</bitWidth>
            </field>
            <field>
              <name>LPWR1RSTF</name>
              <bitOffset>30</bitOffset>
              <bitWidth>1</bitWidth>
            </field>
            <field>
              <name>LPWR2RSTF</name>
              <bitOffset>31</bitOffset>
              <bitWidth>1</bitWidth>
            </field>
          </fields>
        </register>
        <register>
          <name>AHB3ENR</name>
          <addressOffset>0x4</addressOffset>
          <size>0x20</size>
          <fields>
            <field>
              <name>MDMAEN</name>
              <bitOffset>0</bitOffset>
              <bitWidth>1</bitWidth>
            </field>
            <field>
              <name>DMA2DEN</name>
              <bitOffset>4</bitOffset>
              <bitWidth>1</bitWidth>
            </field>
            <field>
              <name>JPGDECEN</name>
              <bitOffset>5</bitOffset>
              <bitWidth>1</bitWidth>
            </field>
            <field>
              <name>FLASHEN</name>
              <bitOffset>8</bitOffset>
              <bitWidth>1</bitWidth>
            </field>
            <field>
              <name>FMCEN</name>
              <bitOffset>12</bitOffset>
              <bitWidth>1</bitWidth>
            </field>
            <field>
              <name>QSPIEN</name>
              <bitOffset>14</bitOffset>
              <bitWidth>1</bitWidth>
            </field>
            <field>
              <name>SDMMC1EN</name>
              <bitOffset>16</bitOffset>
              <bitWidth>1</bitWidth>
            </field>
            <field>
              <name>DTCM1EN</name>
              <bitOffset>28</bitOffset>
              <bitWidth>1</bitWidth>
            </field>
            <field>
              <name>DTCM2EN</name>
              <bitOffset>29</bitOffset>
              <bitWidth>1</bitWidth>
            </field>
            <field>
              <name>ITCMEN</name>
              <bitOffset>30</bitOffset>
              <bitWidth>1</bitWidth>
            </field>
            <field>
              <name>D1SRAM1EN</name>
              <bitOffset>31</bitOffset>
              <bitWidth>1</bitWidth>
            </field>
          </fields>
        </register>
        <register>
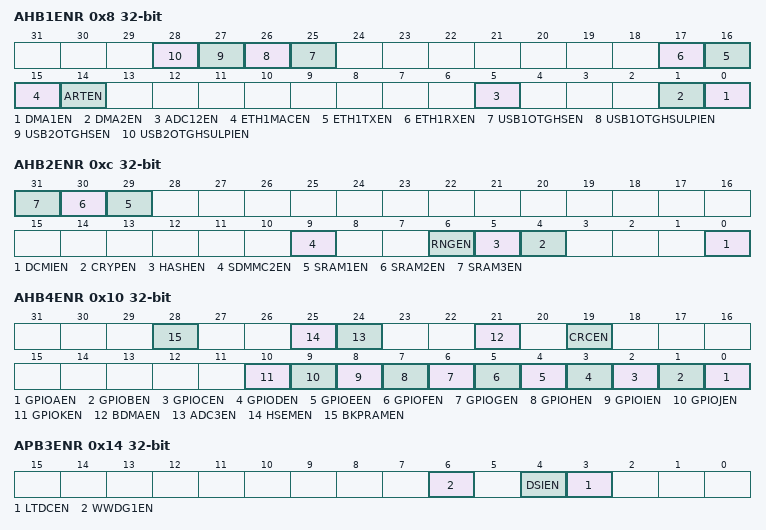
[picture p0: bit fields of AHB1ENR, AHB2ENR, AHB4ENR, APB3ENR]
          <name>AHB1ENR</name>
          <addressOffset>0x8</addressOffset>
          <size>0x20</size>
          <fields>
            <field>
              <name>DMA1EN</name>
              <bitOffset>0</bitOffset>
              <bitWidth>1</bitWidth>
            </field>
            <field>
              <name>DMA2EN</name>
              <bitOffset>1</bitOffset>
              <bitWidth>1</bitWidth>
            </field>
            <field>
              <name>ADC12EN</name>
              <bitOffset>5</bitOffset>
              <bitWidth>1</bitWidth>
            </field>
            <field>
              <name>ARTEN</name>
              <bitOffset>14</bitOffset>
              <bitWidth>1</bitWidth>
            </field>
            <field>
              <name>ETH1MACEN</name>
              <bitOffset>15</bitOffset>
              <bitWidth>1</bitWidth>
            </field>
            <field>
              <name>ETH1TXEN</name>
              <bitOffset>16</bitOffset>
              <bitWidth>1</bitWidth>
            </field>
            <field>
              <name>ETH1RXEN</name>
              <bitOffset>17</bitOffset>
              <bitWidth>1</bitWidth>
            </field>
            <field>
              <name>USB1OTGHSEN</name>
              <bitOffset>25</bitOffset>
              <bitWidth>1</bitWidth>
            </field>
            <field>
              <name>USB1OTGHSULPIEN</name>
              <bitOffset>26</bitOffset>
              <bitWidth>1</bitWidth>
            </field>
            <field>
              <name>USB2OTGHSEN</name>
              <bitOffset>27</bitOffset>
              <bitWidth>1</bitWidth>
            </field>
            <field>
              <name>USB2OTGHSULPIEN</name>
              <bitOffset>28</bitOffset>
              <bitWidth>1</bitWidth>
            </field>
          </fields>
        </register>
        <register>
          <name>AHB2ENR</name>
          <addressOffset>0xc</addressOffset>
          <size>0x20</size>
          <fields>
            <field>
              <name>DCMIEN</name>
              <bitOffset>0</bitOffset>
              <bitWidth>1</bitWidth>
            </field>
            <field>
              <name>CRYPEN</name>
              <bitOffset>4</bitOffset>
              <bitWidth>1</bitWidth>
            </field>
            <field>
              <name>HASHEN</name>
              <bitOffset>5</bitOffset>
              <bitWidth>1</bitWidth>
            </field>
            <field>
              <name>RNGEN</name>
              <bitOffset>6</bitOffset>
              <bitWidth>1</bitWidth>
            </field>
            <field>
              <name>SDMMC2EN</name>
              <bitOffset>9</bitOffset>
              <bitWidth>1</bitWidth>
            </field>
            <field>
              <name>SRAM1EN</name>
              <bitOffset>29</bitOffset>
              <bitWidth>1</bitWidth>
            </field>
            <field>
              <name>SRAM2EN</name>
              <bitOffset>30</bitOffset>
              <bitWidth>1</bitWidth>
            </field>
            <field>
              <name>SRAM3EN</name>
              <bitOffset>31</bitOffset>
              <bitWidth>1</bitWidth>
            </field>
          </fields>
        </register>
        <register>
          <name>AHB4ENR</name>
          <addressOffset>0x10</addressOffset>
          <size>0x20</size>
          <fields>
            <field>
              <name>GPIOAEN</name>
              <bitOffset>0</bitOffset>
              <bitWidth>1</bitWidth>
            </field>
            <field>
              <name>GPIOBEN</name>
              <bitOffset>1</bitOffset>
              <bitWidth>1</bitWidth>
            </field>
            <field>
              <name>GPIOCEN</name>
              <bitOffset>2</bitOffset>
              <bitWidth>1</bitWidth>
            </field>
            <field>
              <name>GPIODEN</name>
              <bitOffset>3</bitOffset>
              <bitWidth>1</bitWidth>
            </field>
            <field>
              <name>GPIOEEN</name>
              <bitOffset>4</bitOffset>
              <bitWidth>1</bitWidth>
            </field>
            <field>
              <name>GPIOFEN</name>
              <bitOffset>5</bitOffset>
              <bitWidth>1</bitWidth>
            </field>
            <field>
              <name>GPIOGEN</name>
              <bitOffset>6</bitOffset>
              <bitWidth>1</bitWidth>
            </field>
            <field>
              <name>GPIOHEN</name>
              <bitOffset>7</bitOffset>
              <bitWidth>1</bitWidth>
            </field>
            <field>
              <name>GPIOIEN</name>
              <bitOffset>8</bitOffset>
              <bitWidth>1</bitWidth>
            </field>
            <field>
              <name>GPIOJEN</name>
              <bitOffset>9</bitOffset>
              <bitWidth>1</bitWidth>
            </field>
            <field>
              <name>GPIOKEN</name>
              <bitOffset>10</bitOffset>
              <bitWidth>1</bitWidth>
            </field>
            <field>
              <name>CRCEN</name>
              <bitOffset>19</bitOffset>
              <bitWidth>1</bitWidth>
            </field>
            <field>
              <name>BDMAEN</name>
              <bitOffset>21</bitOffset>
              <bitWidth>1</bitWidth>
            </field>
            <field>
              <name>ADC3EN</name>
              <bitOffset>24</bitOffset>
              <bitWidth>1</bitWidth>
            </field>
            <field>
              <name>HSEMEN</name>
              <bitOffset>25</bitOffset>
              <bitWidth>1</bitWidth>
            </field>
            <field>
              <name>BKPRAMEN</name>
              <bitOffset>28</bitOffset>
              <bitWidth>1</bitWidth>
            </field>
          </fields>
        </register>
        <register>
          <name>APB3ENR</name>
          <addressOffset>0x14</addressOffset>
          <size>0x20</size>
          <fields>
            <field>
              <name>LTDCEN</name>
              <bitOffset>3</bitOffset>
              <bitWidth>1</bitWidth>
            </field>
            <field>
              <name>DSIEN</name>
              <bitOffset>4</bitOffset>
              <bitWidth>1</bitWidth>
            </field>
            <field>
              <name>WWDG1EN</name>
              <bitOffset>6</bitOffset>
              <bitWidth>1</bitWidth>
            </field>
          </fields>
        </register>
        <register>
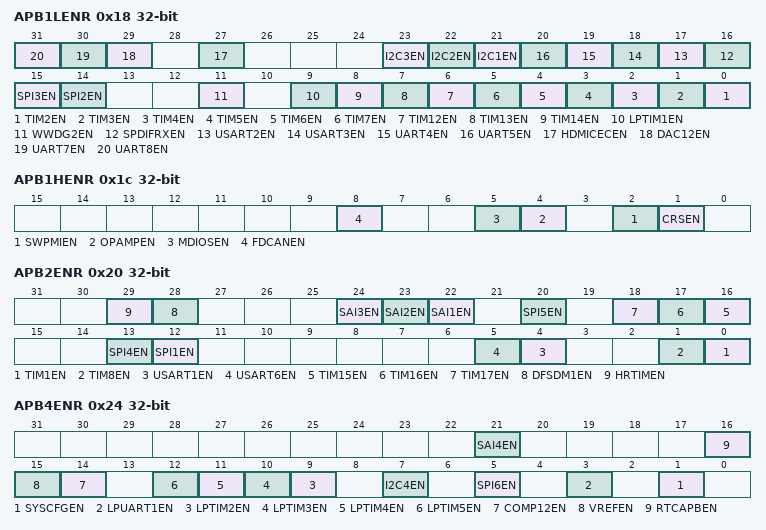
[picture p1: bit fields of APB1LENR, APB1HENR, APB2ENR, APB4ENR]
          <name>APB1LENR</name>
          <addressOffset>0x18</addressOffset>
          <size>0x20</size>
          <fields>
            <field>
              <name>TIM2EN</name>
              <bitOffset>0</bitOffset>
              <bitWidth>1</bitWidth>
            </field>
            <field>
              <name>TIM3EN</name>
              <bitOffset>1</bitOffset>
              <bitWidth>1</bitWidth>
            </field>
            <field>
              <name>TIM4EN</name>
              <bitOffset>2</bitOffset>
              <bitWidth>1</bitWidth>
            </field>
            <field>
              <name>TIM5EN</name>
              <bitOffset>3</bitOffset>
              <bitWidth>1</bitWidth>
            </field>
            <field>
              <name>TIM6EN</name>
              <bitOffset>4</bitOffset>
              <bitWidth>1</bitWidth>
            </field>
            <field>
              <name>TIM7EN</name>
              <bitOffset>5</bitOffset>
              <bitWidth>1</bitWidth>
            </field>
            <field>
              <name>TIM12EN</name>
              <bitOffset>6</bitOffset>
              <bitWidth>1</bitWidth>
            </field>
            <field>
              <name>TIM13EN</name>
              <bitOffset>7</bitOffset>
              <bitWidth>1</bitWidth>
            </field>
            <field>
              <name>TIM14EN</name>
              <bitOffset>8</bitOffset>
              <bitWidth>1</bitWidth>
            </field>
            <field>
              <name>LPTIM1EN</name>
              <bitOffset>9</bitOffset>
              <bitWidth>1</bitWidth>
            </field>
            <field>
              <name>WWDG2EN</name>
              <bitOffset>11</bitOffset>
              <bitWidth>1</bitWidth>
            </field>
            <field>
              <name>SPI2EN</name>
              <bitOffset>14</bitOffset>
              <bitWidth>1</bitWidth>
            </field>
            <field>
              <name>SPI3EN</name>
              <bitOffset>15</bitOffset>
              <bitWidth>1</bitWidth>
            </field>
            <field>
              <name>SPDIFRXEN</name>
              <bitOffset>16</bitOffset>
              <bitWidth>1</bitWidth>
            </field>
            <field>
              <name>USART2EN</name>
              <bitOffset>17</bitOffset>
              <bitWidth>1</bitWidth>
            </field>
            <field>
              <name>USART3EN</name>
              <bitOffset>18</bitOffset>
              <bitWidth>1</bitWidth>
            </field>
            <field>
              <name>UART4EN</name>
              <bitOffset>19</bitOffset>
              <bitWidth>1</bitWidth>
            </field>
            <field>
              <name>UART5EN</name>
              <bitOffset>20</bitOffset>
              <bitWidth>1</bitWidth>
            </field>
            <field>
              <name>I2C1EN</name>
              <bitOffset>21</bitOffset>
              <bitWidth>1</bitWidth>
            </field>
            <field>
              <name>I2C2EN</name>
              <bitOffset>22</bitOffset>
              <bitWidth>1</bitWidth>
            </field>
            <field>
              <name>I2C3EN</name>
              <bitOffset>23</bitOffset>
              <bitWidth>1</bitWidth>
            </field>
            <field>
              <name>HDMICECEN</name>
              <bitOffset>27</bitOffset>
              <bitWidth>1</bitWidth>
            </field>
            <field>
              <name>DAC12EN</name>
              <bitOffset>29</bitOffset>
              <bitWidth>1</bitWidth>
            </field>
            <field>
              <name>UART7EN</name>
              <bitOffset>30</bitOffset>
              <bitWidth>1</bitWidth>
            </field>
            <field>
              <name>UART8EN</name>
              <bitOffset>31</bitOffset>
              <bitWidth>1</bitWidth>
            </field>
          </fields>
        </register>
        <register>
          <name>APB1HENR</name>
          <addressOffset>0x1c</addressOffset>
          <size>0x20</size>
          <fields>
            <field>
              <name>CRSEN</name>
              <bitOffset>1</bitOffset>
              <bitWidth>1</bitWidth>
            </field>
            <field>
              <name>SWPMIEN</name>
              <bitOffset>2</bitOffset>
              <bitWidth>1</bitWidth>
            </field>
            <field>
              <name>OPAMPEN</name>
              <bitOffset>4</bitOffset>
              <bitWidth>1</bitWidth>
            </field>
            <field>
              <name>MDIOSEN</name>
              <bitOffset>5</bitOffset>
              <bitWidth>1</bitWidth>
            </field>
            <field>
              <name>FDCANEN</name>
              <bitOffset>8</bitOffset>
              <bitWidth>1</bitWidth>
            </field>
          </fields>
        </register>
        <register>
          <name>APB2ENR</name>
          <addressOffset>0x20</addressOffset>
          <size>0x20</size>
          <fields>
            <field>
              <name>TIM1EN</name>
              <bitOffset>0</bitOffset>
              <bitWidth>1</bitWidth>
            </field>
            <field>
              <name>TIM8EN</name>
              <bitOffset>1</bitOffset>
              <bitWidth>1</bitWidth>
            </field>
            <field>
              <name>USART1EN</name>
              <bitOffset>4</bitOffset>
              <bitWidth>1</bitWidth>
            </field>
            <field>
              <name>USART6EN</name>
              <bitOffset>5</bitOffset>
              <bitWidth>1</bitWidth>
            </field>
            <field>
              <name>SPI1EN</name>
              <bitOffset>12</bitOffset>
              <bitWidth>1</bitWidth>
            </field>
            <field>
              <name>SPI4EN</name>
              <bitOffset>13</bitOffset>
              <bitWidth>1</bitWidth>
            </field>
            <field>
              <name>TIM15EN</name>
              <bitOffset>16</bitOffset>
              <bitWidth>1</bitWidth>
            </field>
            <field>
              <name>TIM16EN</name>
              <bitOffset>17</bitOffset>
              <bitWidth>1</bitWidth>
            </field>
            <field>
              <name>TIM17EN</name>
              <bitOffset>18</bitOffset>
              <bitWidth>1</bitWidth>
            </field>
            <field>
              <name>SPI5EN</name>
              <bitOffset>20</bitOffset>
              <bitWidth>1</bitWidth>
            </field>
            <field>
              <name>SAI1EN</name>
              <bitOffset>22</bitOffset>
              <bitWidth>1</bitWidth>
            </field>
            <field>
              <name>SAI2EN</name>
              <bitOffset>23</bitOffset>
              <bitWidth>1</bitWidth>
            </field>
            <field>
              <name>SAI3EN</name>
              <bitOffset>24</bitOffset>
              <bitWidth>1</bitWidth>
            </field>
            <field>
              <name>DFSDM1EN</name>
              <bitOffset>28</bitOffset>
              <bitWidth>1</bitWidth>
            </field>
            <field>
              <name>HRTIMEN</name>
              <bitOffset>29</bitOffset>
              <bitWidth>1</bitWidth>
            </field>
          </fields>
        </register>
        <register>
          <name>APB4ENR</name>
          <addressOffset>0x24</addressOffset>
          <size>0x20</size>
          <fields>
            <field>
              <name>SYSCFGEN</name>
              <bitOffset>1</bitOffset>
              <bitWidth>1</bitWidth>
            </field>
            <field>
              <name>LPUART1EN</name>
              <bitOffset>3</bitOffset>
              <bitWidth>1</bitWidth>
            </field>
            <field>
              <name>SPI6EN</name>
              <bitOffset>5</bitOffset>
              <bitWidth>1</bitWidth>
            </field>
            <field>
              <name>I2C4EN</name>
              <bitOffset>7</bitOffset>
              <bitWidth>1</bitWidth>
            </field>
            <field>
              <name>LPTIM2EN</name>
              <bitOffset>9</bitOffset>
              <bitWidth>1</bitWidth>
            </field>
            <field>
              <name>LPTIM3EN</name>
              <bitOffset>10</bitOffset>
              <bitWidth>1</bitWidth>
            </field>
            <field>
              <name>LPTIM4EN</name>
              <bitOffset>11</bitOffset>
              <bitWidth>1</bitWidth>
            </field>
            <field>
              <name>LPTIM5EN</name>
              <bitOffset>12</bitOffset>
              <bitWidth>1</bitWidth>
            </field>
            <field>
              <name>COMP12EN</name>
              <bitOffset>14</bitOffset>
              <bitWidth>1</bitWidth>
            </field>
            <field>
              <name>VREFEN</name>
              <bitOffset>15</bitOffset>
              <bitWidth>1</bitWidth>
            </field>
            <field>
              <name>RTCAPBEN</name>
              <bitOffset>16</bitOffset>
              <bitWidth>1</bitWidth>
            </field>
            <field>
              <name>SAI4EN</name>
              <bitOffset>21</bitOffset>
              <bitWidth>1</bitWidth>
            </field>
          </fields>
        </register>
        <register>
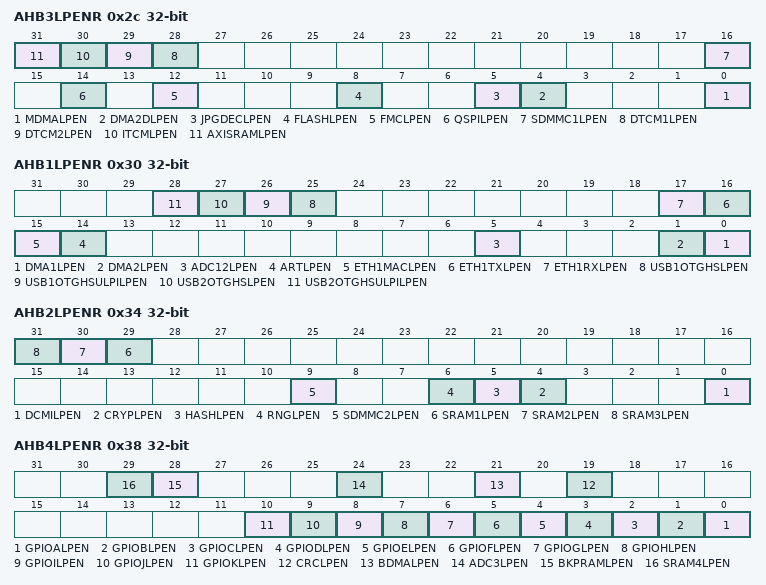
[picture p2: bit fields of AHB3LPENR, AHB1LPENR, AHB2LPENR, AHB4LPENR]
          <name>AHB3LPENR</name>
          <addressOffset>0x2c</addressOffset>
          <size>0x20</size>
          <fields>
            <field>
              <name>MDMALPEN</name>
              <bitOffset>0</bitOffset>
              <bitWidth>1</bitWidth>
            </field>
            <field>
              <name>DMA2DLPEN</name>
              <bitOffset>4</bitOffset>
              <bitWidth>1</bitWidth>
            </field>
            <field>
              <name>JPGDECLPEN</name>
              <bitOffset>5</bitOffset>
              <bitWidth>1</bitWidth>
            </field>
            <field>
              <name>FLASHLPEN</name>
              <bitOffset>8</bitOffset>
              <bitWidth>1</bitWidth>
            </field>
            <field>
              <name>FMCLPEN</name>
              <bitOffset>12</bitOffset>
              <bitWidth>1</bitWidth>
            </field>
            <field>
              <name>QSPILPEN</name>
              <bitOffset>14</bitOffset>
              <bitWidth>1</bitWidth>
            </field>
            <field>
              <name>SDMMC1LPEN</name>
              <bitOffset>16</bitOffset>
              <bitWidth>1</bitWidth>
            </field>
            <field>
              <name>DTCM1LPEN</name>
              <bitOffset>28</bitOffset>
              <bitWidth>1</bitWidth>
            </field>
            <field>
              <name>DTCM2LPEN</name>
              <bitOffset>29</bitOffset>
              <bitWidth>1</bitWidth>
            </field>
            <field>
              <name>ITCMLPEN</name>
              <bitOffset>30</bitOffset>
              <bitWidth>1</bitWidth>
            </field>
            <field>
              <name>AXISRAMLPEN</name>
              <bitOffset>31</bitOffset>
              <bitWidth>1</bitWidth>
            </field>
          </fields>
        </register>
        <register>
          <name>AHB1LPENR</name>
          <addressOffset>0x30</addressOffset>
          <size>0x20</size>
          <fields>
            <field>
              <name>DMA1LPEN</name>
              <bitOffset>0</bitOffset>
              <bitWidth>1</bitWidth>
            </field>
            <field>
              <name>DMA2LPEN</name>
              <bitOffset>1</bitOffset>
              <bitWidth>1</bitWidth>
            </field>
            <field>
              <name>ADC12LPEN</name>
              <bitOffset>5</bitOffset>
              <bitWidth>1</bitWidth>
            </field>
            <field>
              <name>ARTLPEN</name>
              <bitOffset>14</bitOffset>
              <bitWidth>1</bitWidth>
            </field>
            <field>
              <name>ETH1MACLPEN</name>
              <bitOffset>15</bitOffset>
              <bitWidth>1</bitWidth>
            </field>
            <field>
              <name>ETH1TXLPEN</name>
              <bitOffset>16</bitOffset>
              <bitWidth>1</bitWidth>
            </field>
            <field>
              <name>ETH1RXLPEN</name>
              <bitOffset>17</bitOffset>
              <bitWidth>1</bitWidth>
            </field>
            <field>
              <name>USB1OTGHSLPEN</name>
              <bitOffset>25</bitOffset>
              <bitWidth>1</bitWidth>
            </field>
            <field>
              <name>USB1OTGHSULPILPEN</name>
              <bitOffset>26</bitOffset>
              <bitWidth>1</bitWidth>
            </field>
            <field>
              <name>USB2OTGHSLPEN</name>
              <bitOffset>27</bitOffset>
              <bitWidth>1</bitWidth>
            </field>
            <field>
              <name>USB2OTGHSULPILPEN</name>
              <bitOffset>28</bitOffset>
              <bitWidth>1</bitWidth>
            </field>
          </fields>
        </register>
        <register>
          <name>AHB2LPENR</name>
          <addressOffset>0x34</addressOffset>
          <size>0x20</size>
          <fields>
            <field>
              <name>DCMILPEN</name>
              <bitOffset>0</bitOffset>
              <bitWidth>1</bitWidth>
            </field>
            <field>
              <name>CRYPLPEN</name>
              <bitOffset>4</bitOffset>
              <bitWidth>1</bitWidth>
            </field>
            <field>
              <name>HASHLPEN</name>
              <bitOffset>5</bitOffset>
              <bitWidth>1</bitWidth>
            </field>
            <field>
              <name>RNGLPEN</name>
              <bitOffset>6</bitOffset>
              <bitWidth>1</bitWidth>
            </field>
            <field>
              <name>SDMMC2LPEN</name>
              <bitOffset>9</bitOffset>
              <bitWidth>1</bitWidth>
            </field>
            <field>
              <name>SRAM1LPEN</name>
              <bitOffset>29</bitOffset>
              <bitWidth>1</bitWidth>
            </field>
            <field>
              <name>SRAM2LPEN</name>
              <bitOffset>30</bitOffset>
              <bitWidth>1</bitWidth>
            </field>
            <field>
              <name>SRAM3LPEN</name>
              <bitOffset>31</bitOffset>
              <bitWidth>1</bitWidth>
            </field>
          </fields>
        </register>
        <register>
          <name>AHB4LPENR</name>
          <addressOffset>0x38</addressOffset>
          <size>0x20</size>
          <fields>
            <field>
              <name>GPIOALPEN</name>
              <bitOffset>0</bitOffset>
              <bitWidth>1</bitWidth>
            </field>
            <field>
              <name>GPIOBLPEN</name>
              <bitOffset>1</bitOffset>
              <bitWidth>1</bitWidth>
            </field>
            <field>
              <name>GPIOCLPEN</name>
              <bitOffset>2</bitOffset>
              <bitWidth>1</bitWidth>
            </field>
            <field>
              <name>GPIODLPEN</name>
              <bitOffset>3</bitOffset>
              <bitWidth>1</bitWidth>
            </field>
            <field>
              <name>GPIOELPEN</name>
              <bitOffset>4</bitOffset>
              <bitWidth>1</bitWidth>
            </field>
            <field>
              <name>GPIOFLPEN</name>
              <bitOffset>5</bitOffset>
              <bitWidth>1</bitWidth>
            </field>
            <field>
              <name>GPIOGLPEN</name>
              <bitOffset>6</bitOffset>
              <bitWidth>1</bitWidth>
            </field>
            <field>
              <name>GPIOHLPEN</name>
              <bitOffset>7</bitOffset>
              <bitWidth>1</bitWidth>
            </field>
            <field>
              <name>GPIOILPEN</name>
              <bitOffset>8</bitOffset>
              <bitWidth>1</bitWidth>
            </field>
            <field>
              <name>GPIOJLPEN</name>
              <bitOffset>9</bitOffset>
              <bitWidth>1</bitWidth>
            </field>
            <field>
              <name>GPIOKLPEN</name>
              <bitOffset>10</bitOffset>
              <bitWidth>1</bitWidth>
            </field>
            <field>
              <name>CRCLPEN</name>
              <bitOffset>19</bitOffset>
              <bitWidth>1</bitWidth>
            </field>
            <field>
              <name>BDMALPEN</name>
              <bitOffset>21</bitOffset>
              <bitWidth>1</bitWidth>
            </field>
            <field>
              <name>ADC3LPEN</name>
              <bitOffset>24</bitOffset>
              <bitWidth>1</bitWidth>
            </field>
            <field>
              <name>BKPRAMLPEN</name>
              <bitOffset>28</bitOffset>
              <bitWidth>1</bitWidth>
            </field>
            <field>
              <name>SRAM4LPEN</name>
              <bitOffset>29</bitOffset>
              <bitWidth>1</bitWidth>
            </field>
          </fields>
        </register>
        <register>
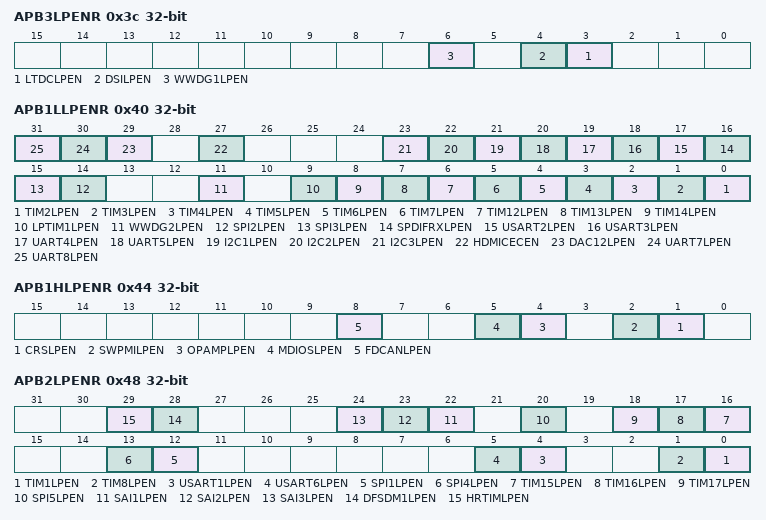
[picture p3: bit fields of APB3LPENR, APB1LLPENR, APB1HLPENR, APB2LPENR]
          <name>APB3LPENR</name>
          <addressOffset>0x3c</addressOffset>
          <size>0x20</size>
          <fields>
            <field>
              <name>LTDCLPEN</name>
              <bitOffset>3</bitOffset>
              <bitWidth>1</bitWidth>
            </field>
            <field>
              <name>DSILPEN</name>
              <bitOffset>4</bitOffset>
              <bitWidth>1</bitWidth>
            </field>
            <field>
              <name>WWDG1LPEN</name>
              <bitOffset>6</bitOffset>
              <bitWidth>1</bitWidth>
            </field>
          </fields>
        </register>
        <register>
          <name>APB1LLPENR</name>
          <addressOffset>0x40</addressOffset>
          <size>0x20</size>
          <fields>
            <field>
              <name>TIM2LPEN</name>
              <bitOffset>0</bitOffset>
              <bitWidth>1</bitWidth>
            </field>
            <field>
              <name>TIM3LPEN</name>
              <bitOffset>1</bitOffset>
              <bitWidth>1</bitWidth>
            </field>
            <field>
              <name>TIM4LPEN</name>
              <bitOffset>2</bitOffset>
              <bitWidth>1</bitWidth>
            </field>
            <field>
              <name>TIM5LPEN</name>
              <bitOffset>3</bitOffset>
              <bitWidth>1</bitWidth>
            </field>
            <field>
              <name>TIM6LPEN</name>
              <bitOffset>4</bitOffset>
              <bitWidth>1</bitWidth>
            </field>
            <field>
              <name>TIM7LPEN</name>
              <bitOffset>5</bitOffset>
              <bitWidth>1</bitWidth>
            </field>
            <field>
              <name>TIM12LPEN</name>
              <bitOffset>6</bitOffset>
              <bitWidth>1</bitWidth>
            </field>
            <field>
              <name>TIM13LPEN</name>
              <bitOffset>7</bitOffset>
              <bitWidth>1</bitWidth>
            </field>
            <field>
              <name>TIM14LPEN</name>
              <bitOffset>8</bitOffset>
              <bitWidth>1</bitWidth>
            </field>
            <field>
              <name>LPTIM1LPEN</name>
              <bitOffset>9</bitOffset>
              <bitWidth>1</bitWidth>
            </field>
            <field>
              <name>WWDG2LPEN</name>
              <bitOffset>11</bitOffset>
              <bitWidth>1</bitWidth>
            </field>
            <field>
              <name>SPI2LPEN</name>
              <bitOffset>14</bitOffset>
              <bitWidth>1</bitWidth>
            </field>
            <field>
              <name>SPI3LPEN</name>
              <bitOffset>15</bitOffset>
              <bitWidth>1</bitWidth>
            </field>
            <field>
              <name>SPDIFRXLPEN</name>
              <bitOffset>16</bitOffset>
              <bitWidth>1</bitWidth>
            </field>
            <field>
              <name>USART2LPEN</name>
              <bitOffset>17</bitOffset>
              <bitWidth>1</bitWidth>
            </field>
            <field>
              <name>USART3LPEN</name>
              <bitOffset>18</bitOffset>
              <bitWidth>1</bitWidth>
            </field>
            <field>
              <name>UART4LPEN</name>
              <bitOffset>19</bitOffset>
              <bitWidth>1</bitWidth>
            </field>
            <field>
              <name>UART5LPEN</name>
              <bitOffset>20</bitOffset>
              <bitWidth>1</bitWidth>
            </field>
            <field>
              <name>I2C1LPEN</name>
              <bitOffset>21</bitOffset>
              <bitWidth>1</bitWidth>
            </field>
            <field>
              <name>I2C2LPEN</name>
              <bitOffset>22</bitOffset>
              <bitWidth>1</bitWidth>
            </field>
            <field>
              <name>I2C3LPEN</name>
              <bitOffset>23</bitOffset>
              <bitWidth>1</bitWidth>
            </field>
            <field>
              <name>HDMICECEN</name>
              <bitOffset>27</bitOffset>
              <bitWidth>1</bitWidth>
            </field>
            <field>
              <name>DAC12LPEN</name>
              <bitOffset>29</bitOffset>
              <bitWidth>1</bitWidth>
            </field>
            <field>
              <name>UART7LPEN</name>
              <bitOffset>30</bitOffset>
              <bitWidth>1</bitWidth>
            </field>
            <field>
              <name>UART8LPEN</name>
              <bitOffset>31</bitOffset>
              <bitWidth>1</bitWidth>
            </field>
          </fields>
        </register>
        <register>
          <name>APB1HLPENR</name>
          <addressOffset>0x44</addressOffset>
          <size>0x20</size>
          <fields>
            <field>
              <name>CRSLPEN</name>
              <bitOffset>1</bitOffset>
              <bitWidth>1</bitWidth>
            </field>
            <field>
              <name>SWPMILPEN</name>
              <bitOffset>2</bitOffset>
              <bitWidth>1</bitWidth>
            </field>
            <field>
              <name>OPAMPLPEN</name>
              <bitOffset>4</bitOffset>
              <bitWidth>1</bitWidth>
            </field>
            <field>
              <name>MDIOSLPEN</name>
              <bitOffset>5</bitOffset>
              <bitWidth>1</bitWidth>
            </field>
            <field>
              <name>FDCANLPEN</name>
              <bitOffset>8</bitOffset>
              <bitWidth>1</bitWidth>
            </field>
          </fields>
        </register>
        <register>
          <name>APB2LPENR</name>
          <addressOffset>0x48</addressOffset>
          <size>0x20</size>
          <fields>
            <field>
              <name>TIM1LPEN</name>
              <bitOffset>0</bitOffset>
              <bitWidth>1</bitWidth>
            </field>
            <field>
              <name>TIM8LPEN</name>
              <bitOffset>1</bitOffset>
              <bitWidth>1</bitWidth>
            </field>
            <field>
              <name>USART1LPEN</name>
              <bitOffset>4</bitOffset>
              <bitWidth>1</bitWidth>
            </field>
            <field>
              <name>USART6LPEN</name>
              <bitOffset>5</bitOffset>
              <bitWidth>1</bitWidth>
            </field>
            <field>
              <name>SPI1LPEN</name>
              <bitOffset>12</bitOffset>
              <bitWidth>1</bitWidth>
            </field>
            <field>
              <name>SPI4LPEN</name>
              <bitOffset>13</bitOffset>
              <bitWidth>1</bitWidth>
            </field>
            <field>
              <name>TIM15LPEN</name>
              <bitOffset>16</bitOffset>
              <bitWidth>1</bitWidth>
            </field>
            <field>
              <name>TIM16LPEN</name>
              <bitOffset>17</bitOffset>
              <bitWidth>1</bitWidth>
            </field>
            <field>
              <name>TIM17LPEN</name>
              <bitOffset>18</bitOffset>
              <bitWidth>1</bitWidth>
            </field>
            <field>
              <name>SPI5LPEN</name>
              <bitOffset>20</bitOffset>
              <bitWidth>1</bitWidth>
            </field>
            <field>
              <name>SAI1LPEN</name>
              <bitOffset>22</bitOffset>
              <bitWidth>1</bitWidth>
            </field>
            <field>
              <name>SAI2LPEN</name>
              <bitOffset>23</bitOffset>
              <bitWidth>1</bitWidth>
            </field>
            <field>
              <name>SAI3LPEN</name>
              <bitOffset>24</bitOffset>
              <bitWidth>1</bitWidth>
            </field>
            <field>
              <name>DFSDM1LPEN</name>
              <bitOffset>28</bitOffset>
              <bitWidth>1</bitWidth>
            </field>
            <field>
              <name>HRTIMLPEN</name>
              <bitOffset>29</bitOffset>
              <bitWidth>1</bitWidth>
            </field>
          </fields>
        </register>
        <register>
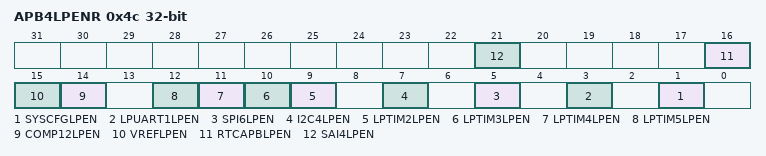
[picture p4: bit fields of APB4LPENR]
          <name>APB4LPENR</name>
          <addressOffset>0x4c</addressOffset>
          <size>0x20</size>
          <fields>
            <field>
              <name>SYSCFGLPEN</name>
              <bitOffset>1</bitOffset>
              <bitWidth>1</bitWidth>
            </field>
            <field>
              <name>LPUART1LPEN</name>
              <bitOffset>3</bitOffset>
              <bitWidth>1</bitWidth>
            </field>
            <field>
              <name>SPI6LPEN</name>
              <bitOffset>5</bitOffset>
              <bitWidth>1</bitWidth>
            </field>
            <field>
              <name>I2C4LPEN</name>
              <bitOffset>7</bitOffset>
              <bitWidth>1</bitWidth>
            </field>
            <field>
              <name>LPTIM2LPEN</name>
              <bitOffset>9</bitOffset>
              <bitWidth>1</bitWidth>
            </field>
            <field>
              <name>LPTIM3LPEN</name>
              <bitOffset>10</bitOffset>
              <bitWidth>1</bitWidth>
            </field>
            <field>
              <name>LPTIM4LPEN</name>
              <bitOffset>11</bitOffset>
              <bitWidth>1</bitWidth>
            </field>
            <field>
              <name>LPTIM5LPEN</name>
              <bitOffset>12</bitOffset>
              <bitWidth>1</bitWidth>
            </field>
            <field>
              <name>COMP12LPEN</name>
              <bitOffset>14</bitOffset>
              <bitWidth>1</bitWidth>
            </field>
            <field>
              <name>VREFLPEN</name>
              <bitOffset>15</bitOffset>
              <bitWidth>1</bitWidth>
            </field>
            <field>
              <name>RTCAPBLPEN</name>
              <bitOffset>16</bitOffset>
              <bitWidth>1</bitWidth>
            </field>
            <field>
              <name>SAI4LPEN</name>
              <bitOffset>21</bitOffset>
              <bitWidth>1</bitWidth>
            </field>
          </fields>
        </register>
      </registers>
    </peripheral>
    <peripheral>
      <name>PWR</name>
      <baseAddress>0x58024800</baseAddress>
      <registers>
        <register>
          <name>CR1</name>
          <addressOffset>0x0</addressOffset>
          <size>0x20</size>
          <fields>
            <field>
              <name>LPDS</name>
              <bitOffset>0</bitOffset>
              <bitWidth>1</bitWidth>
            </field>
            <field>
              <name>PVDEN</name>
              <bitOffset>4</bitOffset>
              <bitWidth>1</bitWidth>
            </field>
            <field>
              <name>PLS_LEV7</name>
              <bitOffset>5</bitOffset>
              <bitWidth>3</bitWidth>
            </field>
            <field>
              <name>PLS_LEV6</name>
              <bitOffset>6</bitOffset>
              <bitWidth>2</bitWidth>
            </field>
            <field>
              <name>PLS_LEV4</name>
              <bitOffset>7</bitOffset>
              <bitWidth>1</bitWidth>
            </field>
            <field>
              <name>DBP</name>
              <bitOffset>8</bitOffset>
              <bitWidth>1</bitWidth>
            </field>
            <field>
              <name>FLPS</name>
              <bitOffset>9</bitOffset>
              <bitWidth>1</bitWidth>
            </field>
            <field>
              <name>SVOS</name>
              <bitOffset>14</bitOffset>
              <bitWidth>2</bitWidth>
            </field>
            <field>
              <name>AVDEN</name>
              <bitOffset>16</bitOffset>
              <bitWidth>1</bitWidth>
            </field>
            <field>
              <name>ALS_LEV3</name>
              <bitOffset>17</bitOffset>
              <bitWidth>2</bitWidth>
            </field>
            <field>
              <name>ALS_LEV2</name>
              <bitOffset>18</bitOffset>
              <bitWidth>1</bitWidth>
            </field>
          </fields>
        </register>
        <register>
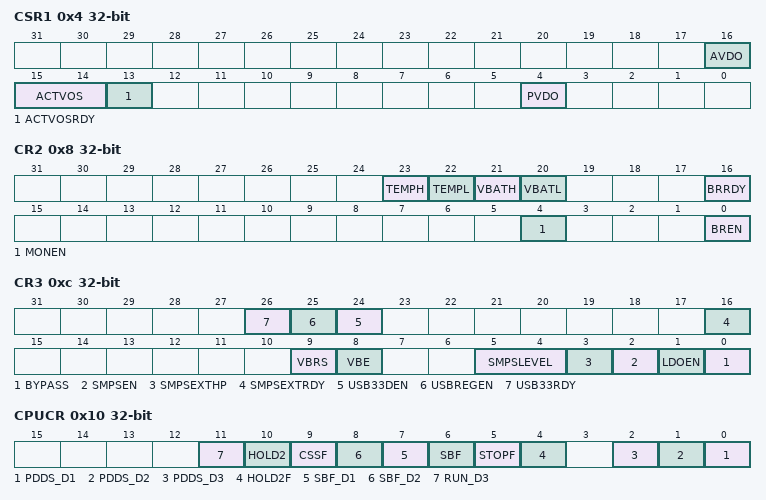
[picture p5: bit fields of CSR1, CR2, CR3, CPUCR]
          <name>CSR1</name>
          <addressOffset>0x4</addressOffset>
          <size>0x20</size>
          <fields>
            <field>
              <name>PVDO</name>
              <bitOffset>4</bitOffset>
              <bitWidth>1</bitWidth>
            </field>
            <field>
              <name>ACTVOSRDY</name>
              <bitOffset>13</bitOffset>
              <bitWidth>1</bitWidth>
            </field>
            <field>
              <name>ACTVOS</name>
              <bitOffset>14</bitOffset>
              <bitWidth>2</bitWidth>
            </field>
            <field>
              <name>AVDO</name>
              <bitOffset>16</bitOffset>
              <bitWidth>1</bitWidth>
            </field>
          </fields>
        </register>
        <register>
          <name>CR2</name>
          <addressOffset>0x8</addressOffset>
          <size>0x20</size>
          <fields>
            <field>
              <name>BREN</name>
              <bitOffset>0</bitOffset>
              <bitWidth>1</bitWidth>
            </field>
            <field>
              <name>MONEN</name>
              <bitOffset>4</bitOffset>
              <bitWidth>1</bitWidth>
            </field>
            <field>
              <name>BRRDY</name>
              <bitOffset>16</bitOffset>
              <bitWidth>1</bitWidth>
            </field>
            <field>
              <name>VBATL</name>
              <bitOffset>20</bitOffset>
              <bitWidth>1</bitWidth>
            </field>
            <field>
              <name>VBATH</name>
              <bitOffset>21</bitOffset>
              <bitWidth>1</bitWidth>
            </field>
            <field>
              <name>TEMPL</name>
              <bitOffset>22</bitOffset>
              <bitWidth>1</bitWidth>
            </field>
            <field>
              <name>TEMPH</name>
              <bitOffset>23</bitOffset>
              <bitWidth>1</bitWidth>
            </field>
          </fields>
        </register>
        <register>
          <name>CR3</name>
          <addressOffset>0xc</addressOffset>
          <size>0x20</size>
          <fields>
            <field>
              <name>BYPASS</name>
              <bitOffset>0</bitOffset>
              <bitWidth>1</bitWidth>
            </field>
            <field>
              <name>LDOEN</name>
              <bitOffset>1</bitOffset>
              <bitWidth>1</bitWidth>
            </field>
            <field>
              <name>SMPSEN</name>
              <bitOffset>2</bitOffset>
              <bitWidth>1</bitWidth>
            </field>
            <field>
              <name>SMPSEXTHP</name>
              <bitOffset>3</bitOffset>
              <bitWidth>1</bitWidth>
            </field>
            <field>
              <name>SMPSLEVEL</name>
              <bitOffset>4</bitOffset>
              <bitWidth>2</bitWidth>
            </field>
            <field>
              <name>VBE</name>
              <bitOffset>8</bitOffset>
              <bitWidth>1</bitWidth>
            </field>
            <field>
              <name>VBRS</name>
              <bitOffset>9</bitOffset>
              <bitWidth>1</bitWidth>
            </field>
            <field>
              <name>SMPSEXTRDY</name>
              <bitOffset>16</bitOffset>
              <bitWidth>1</bitWidth>
            </field>
            <field>
              <name>USB33DEN</name>
              <bitOffset>24</bitOffset>
              <bitWidth>1</bitWidth>
            </field>
            <field>
              <name>USBREGEN</name>
              <bitOffset>25</bitOffset>
              <bitWidth>1</bitWidth>
            </field>
            <field>
              <name>USB33RDY</name>
              <bitOffset>26</bitOffset>
              <bitWidth>1</bitWidth>
            </field>
          </fields>
        </register>
        <register>
          <name>CPUCR</name>
          <addressOffset>0x10</addressOffset>
          <size>0x20</size>
          <fields>
            <field>
              <name>PDDS_D1</name>
              <bitOffset>0</bitOffset>
              <bitWidth>1</bitWidth>
            </field>
            <field>
              <name>PDDS_D2</name>
              <bitOffset>1</bitOffset>
              <bitWidth>1</bitWidth>
            </field>
            <field>
              <name>PDDS_D3</name>
              <bitOffset>2</bitOffset>
              <bitWidth>1</bitWidth>
            </field>
            <field>
              <name>HOLD2F</name>
              <bitOffset>4</bitOffset>
              <bitWidth>1</bitWidth>
            </field>
            <field>
              <name>STOPF</name>
              <bitOffset>5</bitOffset>
              <bitWidth>1</bitWidth>
            </field>
            <field>
              <name>SBF</name>
              <bitOffset>6</bitOffset>
              <bitWidth>1</bitWidth>
            </field>
            <field>
              <name>SBF_D1</name>
              <bitOffset>7</bitOffset>
              <bitWidth>1</bitWidth>
            </field>
            <field>
              <name>SBF_D2</name>
              <bitOffset>8</bitOffset>
              <bitWidth>1</bitWidth>
            </field>
            <field>
              <name>CSSF</name>
              <bitOffset>9</bitOffset>
              <bitWidth>1</bitWidth>
            </field>
            <field>
              <name>HOLD2</name>
              <bitOffset>10</bitOffset>
              <bitWidth>1</bitWidth>
            </field>
            <field>
              <name>RUN_D3</name>
              <bitOffset>11</bitOffset>
              <bitWidth>1</bitWidth>
            </field>
          </fields>
        </register>
        <register>
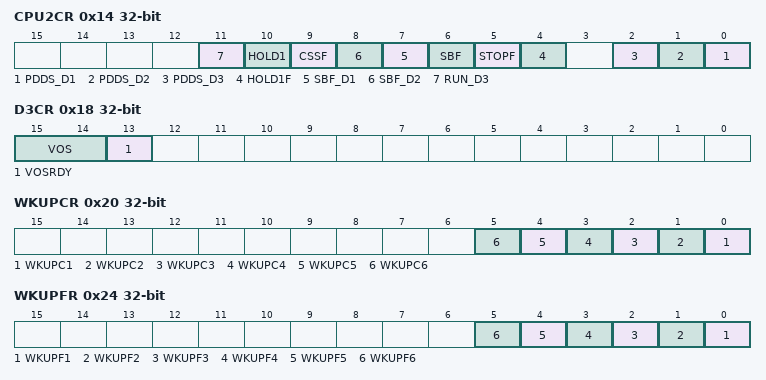
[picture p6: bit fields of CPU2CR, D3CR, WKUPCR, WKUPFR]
          <name>CPU2CR</name>
          <addressOffset>0x14</addressOffset>
          <size>0x20</size>
          <fields>
            <field>
              <name>PDDS_D1</name>
              <bitOffset>0</bitOffset>
              <bitWidth>1</bitWidth>
            </field>
            <field>
              <name>PDDS_D2</name>
              <bitOffset>1</bitOffset>
              <bitWidth>1</bitWidth>
            </field>
            <field>
              <name>PDDS_D3</name>
              <bitOffset>2</bitOffset>
              <bitWidth>1</bitWidth>
            </field>
            <field>
              <name>HOLD1F</name>
              <bitOffset>4</bitOffset>
              <bitWidth>1</bitWidth>
            </field>
            <field>
              <name>STOPF</name>
              <bitOffset>5</bitOffset>
              <bitWidth>1</bitWidth>
            </field>
            <field>
              <name>SBF</name>
              <bitOffset>6</bitOffset>
              <bitWidth>1</bitWidth>
            </field>
            <field>
              <name>SBF_D1</name>
              <bitOffset>7</bitOffset>
              <bitWidth>1</bitWidth>
            </field>
            <field>
              <name>SBF_D2</name>
              <bitOffset>8</bitOffset>
              <bitWidth>1</bitWidth>
            </field>
            <field>
              <name>CSSF</name>
              <bitOffset>9</bitOffset>
              <bitWidth>1</bitWidth>
            </field>
            <field>
              <name>HOLD1</name>
              <bitOffset>10</bitOffset>
              <bitWidth>1</bitWidth>
            </field>
            <field>
              <name>RUN_D3</name>
              <bitOffset>11</bitOffset>
              <bitWidth>1</bitWidth>
            </field>
          </fields>
        </register>
        <register>
          <name>D3CR</name>
          <addressOffset>0x18</addressOffset>
          <size>0x20</size>
          <fields>
            <field>
              <name>VOSRDY</name>
              <bitOffset>13</bitOffset>
              <bitWidth>1</bitWidth>
            </field>
            <field>
              <name>VOS</name>
              <bitOffset>14</bitOffset>
              <bitWidth>2</bitWidth>
            </field>
          </fields>
        </register>
        <register>
          <name>WKUPCR</name>
          <addressOffset>0x20</addressOffset>
          <size>0x20</size>
          <fields>
            <field>
              <name>WKUPC1</name>
              <bitOffset>0</bitOffset>
              <bitWidth>1</bitWidth>
            </field>
            <field>
              <name>WKUPC2</name>
              <bitOffset>1</bitOffset>
              <bitWidth>1</bitWidth>
            </field>
            <field>
              <name>WKUPC3</name>
              <bitOffset>2</bitOffset>
              <bitWidth>1</bitWidth>
            </field>
            <field>
              <name>WKUPC4</name>
              <bitOffset>3</bitOffset>
              <bitWidth>1</bitWidth>
            </field>
            <field>
              <name>WKUPC5</name>
              <bitOffset>4</bitOffset>
              <bitWidth>1</bitWidth>
            </field>
            <field>
              <name>WKUPC6</name>
              <bitOffset>5</bitOffset>
              <bitWidth>1</bitWidth>
            </field>
          </fields>
        </register>
        <register>
          <name>WKUPFR</name>
          <addressOffset>0x24</addressOffset>
          <size>0x20</size>
          <fields>
            <field>
              <name>WKUPF1</name>
              <bitOffset>0</bitOffset>
              <bitWidth>1</bitWidth>
            </field>
            <field>
              <name>WKUPF2</name>
              <bitOffset>1</bitOffset>
              <bitWidth>1</bitWidth>
            </field>
            <field>
              <name>WKUPF3</name>
              <bitOffset>2</bitOffset>
              <bitWidth>1</bitWidth>
            </field>
            <field>
              <name>WKUPF4</name>
              <bitOffset>3</bitOffset>
              <bitWidth>1</bitWidth>
            </field>
            <field>
              <name>WKUPF5</name>
              <bitOffset>4</bitOffset>
              <bitWidth>1</bitWidth>
            </field>
            <field>
              <name>WKUPF6</name>
              <bitOffset>5</bitOffset>
              <bitWidth>1</bitWidth>
            </field>
          </fields>
        </register>
        <register>
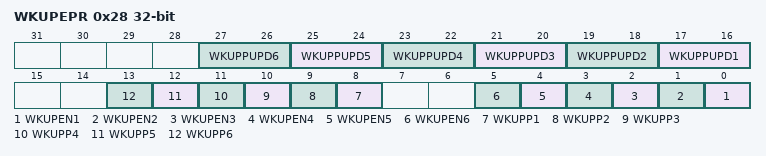
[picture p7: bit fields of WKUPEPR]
          <name>WKUPEPR</name>
          <addressOffset>0x28</addressOffset>
          <size>0x20</size>
          <fields>
            <field>
              <name>WKUPEN1</name>
              <bitOffset>0</bitOffset>
              <bitWidth>1</bitWidth>
            </field>
            <field>
              <name>WKUPEN2</name>
              <bitOffset>1</bitOffset>
              <bitWidth>1</bitWidth>
            </field>
            <field>
              <name>WKUPEN3</name>
              <bitOffset>2</bitOffset>
              <bitWidth>1</bitWidth>
            </field>
            <field>
              <name>WKUPEN4</name>
              <bitOffset>3</bitOffset>
              <bitWidth>1</bitWidth>
            </field>
            <field>
              <name>WKUPEN5</name>
              <bitOffset>4</bitOffset>
              <bitWidth>1</bitWidth>
            </field>
            <field>
              <name>WKUPEN6</name>
              <bitOffset>5</bitOffset>
              <bitWidth>1</bitWidth>
            </field>
            <field>
              <name>WKUPP1</name>
              <bitOffset>8</bitOffset>
              <bitWidth>1</bitWidth>
            </field>
            <field>
              <name>WKUPP2</name>
              <bitOffset>9</bitOffset>
              <bitWidth>1</bitWidth>
            </field>
            <field>
              <name>WKUPP3</name>
              <bitOffset>10</bitOffset>
              <bitWidth>1</bitWidth>
            </field>
            <field>
              <name>WKUPP4</name>
              <bitOffset>11</bitOffset>
              <bitWidth>1</bitWidth>
            </field>
            <field>
              <name>WKUPP5</name>
              <bitOffset>12</bitOffset>
              <bitWidth>1</bitWidth>
            </field>
            <field>
              <name>WKUPP6</name>
              <bitOffset>13</bitOffset>
              <bitWidth>1</bitWidth>
            </field>
            <field>
              <name>WKUPPUPD1</name>
              <bitOffset>16</bitOffset>
              <bitWidth>2</bitWidth>
            </field>
            <field>
              <name>WKUPPUPD2</name>
              <bitOffset>18</bitOffset>
              <bitWidth>2</bitWidth>
            </field>
            <field>
              <name>WKUPPUPD3</name>
              <bitOffset>20</bitOffset>
              <bitWidth>2</bitWidth>
            </field>
            <field>
              <name>WKUPPUPD4</name>
              <bitOffset>22</bitOffset>
              <bitWidth>2</bitWidth>
            </field>
            <field>
              <name>WKUPPUPD5</name>
              <bitOffset>24</bitOffset>
              <bitWidth>2</bitWidth>
            </field>
            <field>
              <name>WKUPPUPD6</name>
              <bitOffset>26</bitOffset>
              <bitWidth>2</bitWidth>
            </field>
          </fields>
        </register>
      </registers>
    </peripheral>
    <peripheral>
      <name>CRC</name>
      <baseAddress>0x58024c00</baseAddress>
      <registers>
        <register>
          <name>DR</name>
          <addressOffset>0x0</addressOffset>
          <size>0x20</size>
          <fields>
            <field>
              <name>DR</name>
              <bitOffset>0</bitOffset>
              <bitWidth>32</bitWidth>
            </field>
          </fields>
        </register>
        <register>
          <name>IDR</name>
          <addressOffset>0x4</addressOffset>
          <size>0x20</size>
          <fields>
            <field>
              <name>IDR</name>
              <bitOffset>0</bitOffset>
              <bitWidth>32</bitWidth>
            </field>
          </fields>
        </register>
        <register>
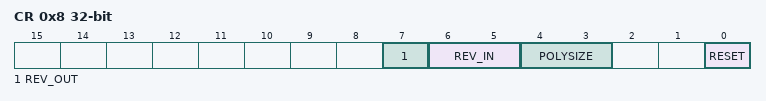
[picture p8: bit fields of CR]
          <name>CR</name>
          <addressOffset>0x8</addressOffset>
          <size>0x20</size>
          <fields>
            <field>
              <name>RESET</name>
              <bitOffset>0</bitOffset>
              <bitWidth>1</bitWidth>
            </field>
            <field>
              <name>POLYSIZE</name>
              <bitOffset>3</bitOffset>
              <bitWidth>2</bitWidth>
            </field>
            <field>
              <name>REV_IN</name>
              <bitOffset>5</bitOffset>
              <bitWidth>2</bitWidth>
            </field>
            <field>
              <name>REV_OUT</name>
              <bitOffset>7</bitOffset>
              <bitWidth>1</bitWidth>
            </field>
          </fields>
        </register>
        <register>
          <name>INIT</name>
          <addressOffset>0x10</addressOffset>
          <size>0x20</size>
          <fields>
            <field>
              <name>INIT</name>
              <bitOffset>0</bitOffset>
              <bitWidth>32</bitWidth>
            </field>
          </fields>
        </register>
        <register>
          <name>POL</name>
          <addressOffset>0x14</addressOffset>
          <size>0x20</size>
          <fields>
            <field>
              <name>POL</name>
              <bitOffset>0</bitOffset>
              <bitWidth>32</bitWidth>
            </field>
          </fields>
        </register>
      </registers>
    </peripheral>
    <peripheral>
      <name>BDMA</name>
      <baseAddress>0x58025400</baseAddress>
      <registers>
        <register>
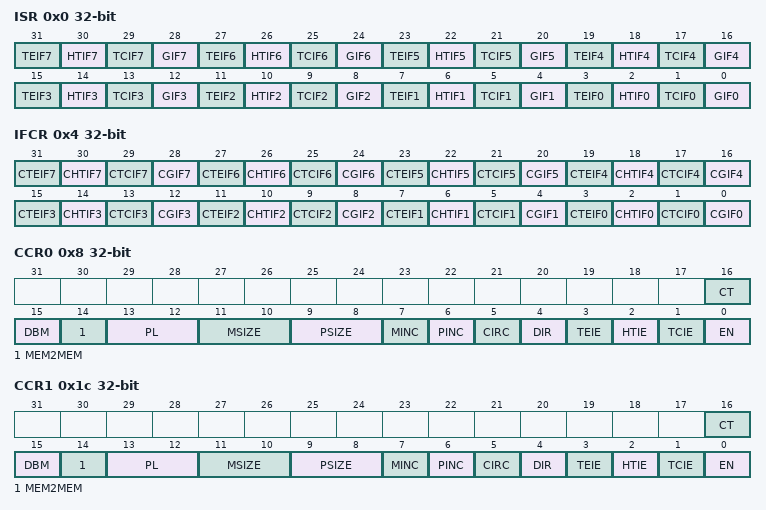
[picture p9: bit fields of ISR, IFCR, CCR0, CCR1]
          <name>ISR</name>
          <addressOffset>0x0</addressOffset>
          <size>0x20</size>
          <fields>
            <field>
              <name>GIF0</name>
              <bitOffset>0</bitOffset>
              <bitWidth>1</bitWidth>
            </field>
            <field>
              <name>TCIF0</name>
              <bitOffset>1</bitOffset>
              <bitWidth>1</bitWidth>
            </field>
            <field>
              <name>HTIF0</name>
              <bitOffset>2</bitOffset>
              <bitWidth>1</bitWidth>
            </field>
            <field>
              <name>TEIF0</name>
              <bitOffset>3</bitOffset>
              <bitWidth>1</bitWidth>
            </field>
            <field>
              <name>GIF1</name>
              <bitOffset>4</bitOffset>
              <bitWidth>1</bitWidth>
            </field>
            <field>
              <name>TCIF1</name>
              <bitOffset>5</bitOffset>
              <bitWidth>1</bitWidth>
            </field>
            <field>
              <name>HTIF1</name>
              <bitOffset>6</bitOffset>
              <bitWidth>1</bitWidth>
            </field>
            <field>
              <name>TEIF1</name>
              <bitOffset>7</bitOffset>
              <bitWidth>1</bitWidth>
            </field>
            <field>
              <name>GIF2</name>
              <bitOffset>8</bitOffset>
              <bitWidth>1</bitWidth>
            </field>
            <field>
              <name>TCIF2</name>
              <bitOffset>9</bitOffset>
              <bitWidth>1</bitWidth>
            </field>
            <field>
              <name>HTIF2</name>
              <bitOffset>10</bitOffset>
              <bitWidth>1</bitWidth>
            </field>
            <field>
              <name>TEIF2</name>
              <bitOffset>11</bitOffset>
              <bitWidth>1</bitWidth>
            </field>
            <field>
              <name>GIF3</name>
              <bitOffset>12</bitOffset>
              <bitWidth>1</bitWidth>
            </field>
            <field>
              <name>TCIF3</name>
              <bitOffset>13</bitOffset>
              <bitWidth>1</bitWidth>
            </field>
            <field>
              <name>HTIF3</name>
              <bitOffset>14</bitOffset>
              <bitWidth>1</bitWidth>
            </field>
            <field>
              <name>TEIF3</name>
              <bitOffset>15</bitOffset>
              <bitWidth>1</bitWidth>
            </field>
            <field>
              <name>GIF4</name>
              <bitOffset>16</bitOffset>
              <bitWidth>1</bitWidth>
            </field>
            <field>
              <name>TCIF4</name>
              <bitOffset>17</bitOffset>
              <bitWidth>1</bitWidth>
            </field>
            <field>
              <name>HTIF4</name>
              <bitOffset>18</bitOffset>
              <bitWidth>1</bitWidth>
            </field>
            <field>
              <name>TEIF4</name>
              <bitOffset>19</bitOffset>
              <bitWidth>1</bitWidth>
            </field>
            <field>
              <name>GIF5</name>
              <bitOffset>20</bitOffset>
              <bitWidth>1</bitWidth>
            </field>
            <field>
              <name>TCIF5</name>
              <bitOffset>21</bitOffset>
              <bitWidth>1</bitWidth>
            </field>
            <field>
              <name>HTIF5</name>
              <bitOffset>22</bitOffset>
              <bitWidth>1</bitWidth>
            </field>
            <field>
              <name>TEIF5</name>
              <bitOffset>23</bitOffset>
              <bitWidth>1</bitWidth>
            </field>
            <field>
              <name>GIF6</name>
              <bitOffset>24</bitOffset>
              <bitWidth>1</bitWidth>
            </field>
            <field>
              <name>TCIF6</name>
              <bitOffset>25</bitOffset>
              <bitWidth>1</bitWidth>
            </field>
            <field>
              <name>HTIF6</name>
              <bitOffset>26</bitOffset>
              <bitWidth>1</bitWidth>
            </field>
            <field>
              <name>TEIF6</name>
              <bitOffset>27</bitOffset>
              <bitWidth>1</bitWidth>
            </field>
            <field>
              <name>GIF7</name>
              <bitOffset>28</bitOffset>
              <bitWidth>1</bitWidth>
            </field>
            <field>
              <name>TCIF7</name>
              <bitOffset>29</bitOffset>
              <bitWidth>1</bitWidth>
            </field>
            <field>
              <name>HTIF7</name>
              <bitOffset>30</bitOffset>
              <bitWidth>1</bitWidth>
            </field>
            <field>
              <name>TEIF7</name>
              <bitOffset>31</bitOffset>
              <bitWidth>1</bitWidth>
            </field>
          </fields>
        </register>
        <register>
          <name>IFCR</name>
          <addressOffset>0x4</addressOffset>
          <size>0x20</size>
          <fields>
            <field>
              <name>CGIF0</name>
              <bitOffset>0</bitOffset>
              <bitWidth>1</bitWidth>
            </field>
            <field>
              <name>CTCIF0</name>
              <bitOffset>1</bitOffset>
              <bitWidth>1</bitWidth>
            </field>
            <field>
              <name>CHTIF0</name>
              <bitOffset>2</bitOffset>
              <bitWidth>1</bitWidth>
            </field>
            <field>
              <name>CTEIF0</name>
              <bitOffset>3</bitOffset>
              <bitWidth>1</bitWidth>
            </field>
            <field>
              <name>CGIF1</name>
              <bitOffset>4</bitOffset>
              <bitWidth>1</bitWidth>
            </field>
            <field>
              <name>CTCIF1</name>
              <bitOffset>5</bitOffset>
              <bitWidth>1</bitWidth>
            </field>
            <field>
              <name>CHTIF1</name>
              <bitOffset>6</bitOffset>
              <bitWidth>1</bitWidth>
            </field>
            <field>
              <name>CTEIF1</name>
              <bitOffset>7</bitOffset>
              <bitWidth>1</bitWidth>
            </field>
            <field>
              <name>CGIF2</name>
              <bitOffset>8</bitOffset>
              <bitWidth>1</bitWidth>
            </field>
            <field>
              <name>CTCIF2</name>
              <bitOffset>9</bitOffset>
              <bitWidth>1</bitWidth>
            </field>
            <field>
              <name>CHTIF2</name>
              <bitOffset>10</bitOffset>
              <bitWidth>1</bitWidth>
            </field>
            <field>
              <name>CTEIF2</name>
              <bitOffset>11</bitOffset>
              <bitWidth>1</bitWidth>
            </field>
            <field>
              <name>CGIF3</name>
              <bitOffset>12</bitOffset>
              <bitWidth>1</bitWidth>
            </field>
            <field>
              <name>CTCIF3</name>
              <bitOffset>13</bitOffset>
              <bitWidth>1</bitWidth>
            </field>
            <field>
              <name>CHTIF3</name>
              <bitOffset>14</bitOffset>
              <bitWidth>1</bitWidth>
            </field>
            <field>
              <name>CTEIF3</name>
              <bitOffset>15</bitOffset>
              <bitWidth>1</bitWidth>
            </field>
            <field>
              <name>CGIF4</name>
              <bitOffset>16</bitOffset>
              <bitWidth>1</bitWidth>
            </field>
            <field>
              <name>CTCIF4</name>
              <bitOffset>17</bitOffset>
              <bitWidth>1</bitWidth>
            </field>
            <field>
              <name>CHTIF4</name>
              <bitOffset>18</bitOffset>
              <bitWidth>1</bitWidth>
            </field>
            <field>
              <name>CTEIF4</name>
              <bitOffset>19</bitOffset>
              <bitWidth>1</bitWidth>
            </field>
            <field>
              <name>CGIF5</name>
              <bitOffset>20</bitOffset>
              <bitWidth>1</bitWidth>
            </field>
            <field>
              <name>CTCIF5</name>
              <bitOffset>21</bitOffset>
              <bitWidth>1</bitWidth>
            </field>
            <field>
              <name>CHTIF5</name>
              <bitOffset>22</bitOffset>
              <bitWidth>1</bitWidth>
            </field>
            <field>
              <name>CTEIF5</name>
              <bitOffset>23</bitOffset>
              <bitWidth>1</bitWidth>
            </field>
            <field>
              <name>CGIF6</name>
              <bitOffset>24</bitOffset>
              <bitWidth>1</bitWidth>
            </field>
            <field>
              <name>CTCIF6</name>
              <bitOffset>25</bitOffset>
              <bitWidth>1</bitWidth>
            </field>
            <field>
              <name>CHTIF6</name>
              <bitOffset>26</bitOffset>
              <bitWidth>1</bitWidth>
            </field>
            <field>
              <name>CTEIF6</name>
              <bitOffset>27</bitOffset>
              <bitWidth>1</bitWidth>
            </field>
            <field>
              <name>CGIF7</name>
              <bitOffset>28</bitOffset>
              <bitWidth>1</bitWidth>
            </field>
            <field>
              <name>CTCIF7</name>
              <bitOffset>29</bitOffset>
              <bitWidth>1</bitWidth>
            </field>
            <field>
              <name>CHTIF7</name>
              <bitOffset>30</bitOffset>
              <bitWidth>1</bitWidth>
            </field>
            <field>
              <name>CTEIF7</name>
              <bitOffset>31</bitOffset>
              <bitWidth>1</bitWidth>
            </field>
          </fields>
        </register>
        <register>
          <name>CCR0</name>
          <addressOffset>0x8</addressOffset>
          <size>0x20</size>
          <fields>
            <field>
              <name>EN</name>
              <bitOffset>0</bitOffset>
              <bitWidth>1</bitWidth>
            </field>
            <field>
              <name>TCIE</name>
              <bitOffset>1</bitOffset>
              <bitWidth>1</bitWidth>
            </field>
            <field>
              <name>HTIE</name>
              <bitOffset>2</bitOffset>
              <bitWidth>1</bitWidth>
            </field>
            <field>
              <name>TEIE</name>
              <bitOffset>3</bitOffset>
              <bitWidth>1</bitWidth>
            </field>
            <field>
              <name>DIR</name>
              <bitOffset>4</bitOffset>
              <bitWidth>1</bitWidth>
            </field>
            <field>
              <name>CIRC</name>
              <bitOffset>5</bitOffset>
              <bitWidth>1</bitWidth>
            </field>
            <field>
              <name>PINC</name>
              <bitOffset>6</bitOffset>
              <bitWidth>1</bitWidth>
            </field>
            <field>
              <name>MINC</name>
              <bitOffset>7</bitOffset>
              <bitWidth>1</bitWidth>
            </field>
            <field>
              <name>PSIZE</name>
              <bitOffset>8</bitOffset>
              <bitWidth>2</bitWidth>
            </field>
            <field>
              <name>MSIZE</name>
              <bitOffset>10</bitOffset>
              <bitWidth>2</bitWidth>
            </field>
            <field>
              <name>PL</name>
              <bitOffset>12</bitOffset>
              <bitWidth>2</bitWidth>
            </field>
            <field>
              <name>MEM2MEM</name>
              <bitOffset>14</bitOffset>
              <bitWidth>1</bitWidth>
            </field>
            <field>
              <name>DBM</name>
              <bitOffset>15</bitOffset>
              <bitWidth>1</bitWidth>
            </field>
            <field>
              <name>CT</name>
              <bitOffset>16</bitOffset>
              <bitWidth>1</bitWidth>
            </field>
          </fields>
        </register>
        <register>
          <name>CNDTR0</name>
          <addressOffset>0xc</addressOffset>
          <size>0x20</size>
          <fields>
            <field>
              <name>NDT</name>
              <bitOffset>0</bitOffset>
              <bitWidth>16</bitWidth>
            </field>
          </fields>
        </register>
        <register>
          <name>CPAR0</name>
          <addressOffset>0x10</addressOffset>
          <size>0x20</size>
          <fields>
            <field>
              <name>PA</name>
              <bitOffset>0</bitOffset>
              <bitWidth>32</bitWidth>
            </field>
          </fields>
        </register>
        <register>
          <name>CM0AR0</name>
          <addressOffset>0x14</addressOffset>
          <size>0x20</size>
          <fields>
            <field>
              <name>MA</name>
              <bitOffset>0</bitOffset>
              <bitWidth>32</bitWidth>
            </field>
          </fields>
        </register>
        <register>
          <name>CM1AR0</name>
          <addressOffset>0x18</addressOffset>
          <size>0x20</size>
          <fields>
            <field>
              <name>MA</name>
              <bitOffset>0</bitOffset>
              <bitWidth>32</bitWidth>
            </field>
          </fields>
        </register>
        <register>
          <name>CCR1</name>
          <addressOffset>0x1c</addressOffset>
          <size>0x20</size>
          <fields>
            <field>
              <name>EN</name>
              <bitOffset>0</bitOffset>
              <bitWidth>1</bitWidth>
            </field>
            <field>
              <name>TCIE</name>
              <bitOffset>1</bitOffset>
              <bitWidth>1</bitWidth>
            </field>
            <field>
              <name>HTIE</name>
              <bitOffset>2</bitOffset>
              <bitWidth>1</bitWidth>
            </field>
            <field>
              <name>TEIE</name>
              <bitOffset>3</bitOffset>
              <bitWidth>1</bitWidth>
            </field>
            <field>
              <name>DIR</name>
              <bitOffset>4</bitOffset>
              <bitWidth>1</bitWidth>
            </field>
            <field>
              <name>CIRC</name>
              <bitOffset>5</bitOffset>
              <bitWidth>1</bitWidth>
            </field>
            <field>
              <name>PINC</name>
              <bitOffset>6</bitOffset>
              <bitWidth>1</bitWidth>
            </field>
            <field>
              <name>MINC</name>
              <bitOffset>7</bitOffset>
              <bitWidth>1</bitWidth>
            </field>
            <field>
              <name>PSIZE</name>
              <bitOffset>8</bitOffset>
              <bitWidth>2</bitWidth>
            </field>
            <field>
              <name>MSIZE</name>
              <bitOffset>10</bitOffset>
              <bitWidth>2</bitWidth>
            </field>
            <field>
              <name>PL</name>
              <bitOffset>12</bitOffset>
              <bitWidth>2</bitWidth>
            </field>
            <field>
              <name>MEM2MEM</name>
              <bitOffset>14</bitOffset>
              <bitWidth>1</bitWidth>
            </field>
            <field>
              <name>DBM</name>
              <bitOffset>15</bitOffset>
              <bitWidth>1</bitWidth>
            </field>
            <field>
              <name>CT</name>
              <bitOffset>16</bitOffset>
              <bitWidth>1</bitWidth>
            </field>
          </fields>
        </register>
        <register>
          <name>CNDTR1</name>
          <addressOffset>0x20</addressOffset>
          <size>0x20</size>
          <fields>
            <field>
              <name>NDT</name>
              <bitOffset>0</bitOffset>
              <bitWidth>16</bitWidth>
            </field>
          </fields>
        </register>
        <register>
          <name>CPAR1</name>
          <addressOffset>0x24</addressOffset>
          <size>0x20</size>
          <fields>
            <field>
              <name>PA</name>
              <bitOffset>0</bitOffset>
              <bitWidth>32</bitWidth>
            </field>
          </fields>
        </register>
        <register>
          <name>CM0AR1</name>
          <addressOffset>0x28</addressOffset>
          <size>0x20</size>
          <fields>
            <field>
              <name>MA</name>
              <bitOffset>0</bitOffset>
              <bitWidth>32</bitWidth>
            </field>
          </fields>
        </register>
        <register>
          <name>CM1AR1</name>
          <addressOffset>0x2c</addressOffset>
          <size>0x20</size>
          <fields>
            <field>
              <name>MA</name>
              <bitOffset>0</bitOffset>
              <bitWidth>32</bitWidth>
            </field>
          </fields>
        </register>
        <register>
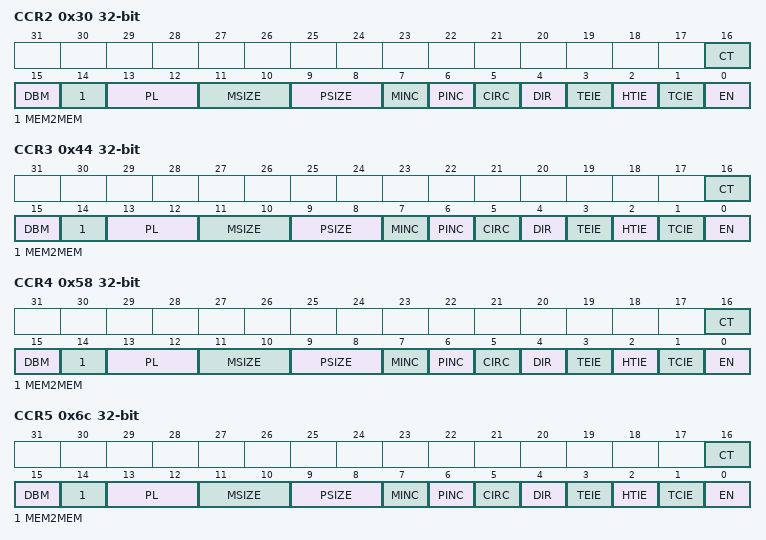
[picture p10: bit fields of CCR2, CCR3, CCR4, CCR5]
          <name>CCR2</name>
          <addressOffset>0x30</addressOffset>
          <size>0x20</size>
          <fields>
            <field>
              <name>EN</name>
              <bitOffset>0</bitOffset>
              <bitWidth>1</bitWidth>
            </field>
            <field>
              <name>TCIE</name>
              <bitOffset>1</bitOffset>
              <bitWidth>1</bitWidth>
            </field>
            <field>
              <name>HTIE</name>
              <bitOffset>2</bitOffset>
              <bitWidth>1</bitWidth>
            </field>
            <field>
              <name>TEIE</name>
              <bitOffset>3</bitOffset>
              <bitWidth>1</bitWidth>
            </field>
            <field>
              <name>DIR</name>
              <bitOffset>4</bitOffset>
              <bitWidth>1</bitWidth>
            </field>
            <field>
              <name>CIRC</name>
              <bitOffset>5</bitOffset>
              <bitWidth>1</bitWidth>
            </field>
            <field>
              <name>PINC</name>
              <bitOffset>6</bitOffset>
              <bitWidth>1</bitWidth>
            </field>
            <field>
              <name>MINC</name>
              <bitOffset>7</bitOffset>
              <bitWidth>1</bitWidth>
            </field>
            <field>
              <name>PSIZE</name>
              <bitOffset>8</bitOffset>
              <bitWidth>2</bitWidth>
            </field>
            <field>
              <name>MSIZE</name>
              <bitOffset>10</bitOffset>
              <bitWidth>2</bitWidth>
            </field>
            <field>
              <name>PL</name>
              <bitOffset>12</bitOffset>
              <bitWidth>2</bitWidth>
            </field>
            <field>
              <name>MEM2MEM</name>
              <bitOffset>14</bitOffset>
              <bitWidth>1</bitWidth>
            </field>
            <field>
              <name>DBM</name>
              <bitOffset>15</bitOffset>
              <bitWidth>1</bitWidth>
            </field>
            <field>
              <name>CT</name>
              <bitOffset>16</bitOffset>
              <bitWidth>1</bitWidth>
            </field>
          </fields>
        </register>
        <register>
          <name>CNDTR2</name>
          <addressOffset>0x34</addressOffset>
          <size>0x20</size>
          <fields>
            <field>
              <name>NDT</name>
              <bitOffset>0</bitOffset>
              <bitWidth>16</bitWidth>
            </field>
          </fields>
        </register>
        <register>
          <name>CPAR2</name>
          <addressOffset>0x38</addressOffset>
          <size>0x20</size>
          <fields>
            <field>
              <name>PA</name>
              <bitOffset>0</bitOffset>
              <bitWidth>32</bitWidth>
            </field>
          </fields>
        </register>
        <register>
          <name>CM0AR2</name>
          <addressOffset>0x3c</addressOffset>
          <size>0x20</size>
          <fields>
            <field>
              <name>MA</name>
              <bitOffset>0</bitOffset>
              <bitWidth>32</bitWidth>
            </field>
          </fields>
        </register>
        <register>
          <name>CM1AR2</name>
          <addressOffset>0x40</addressOffset>
          <size>0x20</size>
          <fields>
            <field>
              <name>MA</name>
              <bitOffset>0</bitOffset>
              <bitWidth>32</bitWidth>
            </field>
          </fields>
        </register>
        <register>
          <name>CCR3</name>
          <addressOffset>0x44</addressOffset>
          <size>0x20</size>
          <fields>
            <field>
              <name>EN</name>
              <bitOffset>0</bitOffset>
              <bitWidth>1</bitWidth>
            </field>
            <field>
              <name>TCIE</name>
              <bitOffset>1</bitOffset>
              <bitWidth>1</bitWidth>
            </field>
            <field>
              <name>HTIE</name>
              <bitOffset>2</bitOffset>
              <bitWidth>1</bitWidth>
            </field>
            <field>
              <name>TEIE</name>
              <bitOffset>3</bitOffset>
              <bitWidth>1</bitWidth>
            </field>
            <field>
              <name>DIR</name>
              <bitOffset>4</bitOffset>
              <bitWidth>1</bitWidth>
            </field>
            <field>
              <name>CIRC</name>
              <bitOffset>5</bitOffset>
              <bitWidth>1</bitWidth>
            </field>
            <field>
              <name>PINC</name>
              <bitOffset>6</bitOffset>
              <bitWidth>1</bitWidth>
            </field>
            <field>
              <name>MINC</name>
              <bitOffset>7</bitOffset>
              <bitWidth>1</bitWidth>
            </field>
            <field>
              <name>PSIZE</name>
              <bitOffset>8</bitOffset>
              <bitWidth>2</bitWidth>
            </field>
            <field>
              <name>MSIZE</name>
              <bitOffset>10</bitOffset>
              <bitWidth>2</bitWidth>
            </field>
            <field>
              <name>PL</name>
              <bitOffset>12</bitOffset>
              <bitWidth>2</bitWidth>
            </field>
            <field>
              <name>MEM2MEM</name>
              <bitOffset>14</bitOffset>
              <bitWidth>1</bitWidth>
            </field>
            <field>
              <name>DBM</name>
              <bitOffset>15</bitOffset>
              <bitWidth>1</bitWidth>
            </field>
            <field>
              <name>CT</name>
              <bitOffset>16</bitOffset>
              <bitWidth>1</bitWidth>
            </field>
          </fields>
        </register>
        <register>
          <name>CNDTR3</name>
          <addressOffset>0x48</addressOffset>
          <size>0x20</size>
          <fields>
            <field>
              <name>NDT</name>
              <bitOffset>0</bitOffset>
              <bitWidth>16</bitWidth>
            </field>
          </fields>
        </register>
        <register>
          <name>CPAR3</name>
          <addressOffset>0x4c</addressOffset>
          <size>0x20</size>
          <fields>
            <field>
              <name>PA</name>
              <bitOffset>0</bitOffset>
              <bitWidth>32</bitWidth>
            </field>
          </fields>
        </register>
        <register>
          <name>CM0AR3</name>
          <addressOffset>0x50</addressOffset>
          <size>0x20</size>
          <fields>
            <field>
              <name>MA</name>
              <bitOffset>0</bitOffset>
              <bitWidth>32</bitWidth>
            </field>
          </fields>
        </register>
        <register>
          <name>CM1AR3</name>
          <addressOffset>0x54</addressOffset>
          <size>0x20</size>
          <fields>
            <field>
              <name>MA</name>
              <bitOffset>0</bitOffset>
              <bitWidth>32</bitWidth>
            </field>
          </fields>
        </register>
        <register>
          <name>CCR4</name>
          <addressOffset>0x58</addressOffset>
          <size>0x20</size>
          <fields>
            <field>
              <name>EN</name>
              <bitOffset>0</bitOffset>
              <bitWidth>1</bitWidth>
            </field>
            <field>
              <name>TCIE</name>
              <bitOffset>1</bitOffset>
              <bitWidth>1</bitWidth>
            </field>
            <field>
              <name>HTIE</name>
              <bitOffset>2</bitOffset>
              <bitWidth>1</bitWidth>
            </field>
            <field>
              <name>TEIE</name>
              <bitOffset>3</bitOffset>
              <bitWidth>1</bitWidth>
            </field>
            <field>
              <name>DIR</name>
              <bitOffset>4</bitOffset>
              <bitWidth>1</bitWidth>
            </field>
            <field>
              <name>CIRC</name>
              <bitOffset>5</bitOffset>
              <bitWidth>1</bitWidth>
            </field>
            <field>
              <name>PINC</name>
              <bitOffset>6</bitOffset>
              <bitWidth>1</bitWidth>
            </field>
            <field>
              <name>MINC</name>
              <bitOffset>7</bitOffset>
              <bitWidth>1</bitWidth>
            </field>
            <field>
              <name>PSIZE</name>
              <bitOffset>8</bitOffset>
              <bitWidth>2</bitWidth>
            </field>
            <field>
              <name>MSIZE</name>
              <bitOffset>10</bitOffset>
              <bitWidth>2</bitWidth>
            </field>
            <field>
              <name>PL</name>
              <bitOffset>12</bitOffset>
              <bitWidth>2</bitWidth>
            </field>
            <field>
              <name>MEM2MEM</name>
              <bitOffset>14</bitOffset>
              <bitWidth>1</bitWidth>
            </field>
            <field>
              <name>DBM</name>
              <bitOffset>15</bitOffset>
              <bitWidth>1</bitWidth>
            </field>
            <field>
              <name>CT</name>
              <bitOffset>16</bitOffset>
              <bitWidth>1</bitWidth>
            </field>
          </fields>
        </register>
        <register>
          <name>CNDTR4</name>
          <addressOffset>0x5c</addressOffset>
          <size>0x20</size>
          <fields>
            <field>
              <name>NDT</name>
              <bitOffset>0</bitOffset>
              <bitWidth>16</bitWidth>
            </field>
          </fields>
        </register>
        <register>
          <name>CPAR4</name>
          <addressOffset>0x60</addressOffset>
          <size>0x20</size>
          <fields>
            <field>
              <name>PA</name>
              <bitOffset>0</bitOffset>
              <bitWidth>32</bitWidth>
            </field>
          </fields>
        </register>
        <register>
          <name>CM0AR4</name>
          <addressOffset>0x64</addressOffset>
          <size>0x20</size>
          <fields>
            <field>
              <name>MA</name>
              <bitOffset>0</bitOffset>
              <bitWidth>32</bitWidth>
            </field>
          </fields>
        </register>
        <register>
          <name>CM1AR4</name>
          <addressOffset>0x68</addressOffset>
          <size>0x20</size>
          <fields>
            <field>
              <name>MA</name>
              <bitOffset>0</bitOffset>
              <bitWidth>32</bitWidth>
            </field>
          </fields>
        </register>
        <register>
          <name>CCR5</name>
          <addressOffset>0x6c</addressOffset>
          <size>0x20</size>
          <fields>
            <field>
              <name>EN</name>
              <bitOffset>0</bitOffset>
              <bitWidth>1</bitWidth>
            </field>
            <field>
              <name>TCIE</name>
              <bitOffset>1</bitOffset>
              <bitWidth>1</bitWidth>
            </field>
            <field>
              <name>HTIE</name>
              <bitOffset>2</bitOffset>
              <bitWidth>1</bitWidth>
            </field>
            <field>
              <name>TEIE</name>
              <bitOffset>3</bitOffset>
              <bitWidth>1</bitWidth>
            </field>
            <field>
              <name>DIR</name>
              <bitOffset>4</bitOffset>
              <bitWidth>1</bitWidth>
            </field>
            <field>
              <name>CIRC</name>
              <bitOffset>5</bitOffset>
              <bitWidth>1</bitWidth>
            </field>
            <field>
              <name>PINC</name>
              <bitOffset>6</bitOffset>
              <bitWidth>1</bitWidth>
            </field>
            <field>
              <name>MINC</name>
              <bitOffset>7</bitOffset>
              <bitWidth>1</bitWidth>
            </field>
            <field>
              <name>PSIZE</name>
              <bitOffset>8</bitOffset>
              <bitWidth>2</bitWidth>
            </field>
            <field>
              <name>MSIZE</name>
              <bitOffset>10</bitOffset>
              <bitWidth>2</bitWidth>
            </field>
            <field>
              <name>PL</name>
              <bitOffset>12</bitOffset>
              <bitWidth>2</bitWidth>
            </field>
            <field>
              <name>MEM2MEM</name>
              <bitOffset>14</bitOffset>
              <bitWidth>1</bitWidth>
            </field>
            <field>
              <name>DBM</name>
              <bitOffset>15</bitOffset>
              <bitWidth>1</bitWidth>
            </field>
            <field>
              <name>CT</name>
              <bitOffset>16</bitOffset>
              <bitWidth>1</bitWidth>
            </field>
          </fields>
        </register>
        <register>
          <name>CNDTR5</name>
          <addressOffset>0x70</addressOffset>
          <size>0x20</size>
          <fields>
            <field>
              <name>NDT</name>
              <bitOffset>0</bitOffset>
              <bitWidth>16</bitWidth>
            </field>
          </fields>
        </register>
        <register>
          <name>CPAR5</name>
          <addressOffset>0x74</addressOffset>
          <size>0x20</size>
          <fields>
            <field>
              <name>PA</name>
              <bitOffset>0</bitOffset>
              <bitWidth>32</bitWidth>
            </field>
          </fields>
        </register>
        <register>
          <name>CM0AR5</name>
          <addressOffset>0x78</addressOffset>
          <size>0x20</size>
          <fields>
            <field>
              <name>MA</name>
              <bitOffset>0</bitOffset>
              <bitWidth>32</bitWidth>
            </field>
          </fields>
        </register>
        <register>
          <name>CM1AR5</name>
          <addressOffset>0x7c</addressOffset>
          <size>0x20</size>
          <fields>
            <field>
              <name>MA</name>
              <bitOffset>0</bitOffset>
              <bitWidth>32</bitWidth>
            </field>
          </fields>
        </register>
        <register>
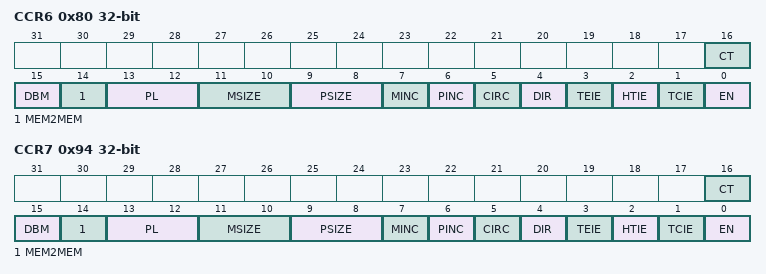
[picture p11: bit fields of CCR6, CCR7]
          <name>CCR6</name>
          <addressOffset>0x80</addressOffset>
          <size>0x20</size>
          <fields>
            <field>
              <name>EN</name>
              <bitOffset>0</bitOffset>
              <bitWidth>1</bitWidth>
            </field>
            <field>
              <name>TCIE</name>
              <bitOffset>1</bitOffset>
              <bitWidth>1</bitWidth>
            </field>
            <field>
              <name>HTIE</name>
              <bitOffset>2</bitOffset>
              <bitWidth>1</bitWidth>
            </field>
            <field>
              <name>TEIE</name>
              <bitOffset>3</bitOffset>
              <bitWidth>1</bitWidth>
            </field>
            <field>
              <name>DIR</name>
              <bitOffset>4</bitOffset>
              <bitWidth>1</bitWidth>
            </field>
            <field>
              <name>CIRC</name>
              <bitOffset>5</bitOffset>
              <bitWidth>1</bitWidth>
            </field>
            <field>
              <name>PINC</name>
              <bitOffset>6</bitOffset>
              <bitWidth>1</bitWidth>
            </field>
            <field>
              <name>MINC</name>
              <bitOffset>7</bitOffset>
              <bitWidth>1</bitWidth>
            </field>
            <field>
              <name>PSIZE</name>
              <bitOffset>8</bitOffset>
              <bitWidth>2</bitWidth>
            </field>
            <field>
              <name>MSIZE</name>
              <bitOffset>10</bitOffset>
              <bitWidth>2</bitWidth>
            </field>
            <field>
              <name>PL</name>
              <bitOffset>12</bitOffset>
              <bitWidth>2</bitWidth>
            </field>
            <field>
              <name>MEM2MEM</name>
              <bitOffset>14</bitOffset>
              <bitWidth>1</bitWidth>
            </field>
            <field>
              <name>DBM</name>
              <bitOffset>15</bitOffset>
              <bitWidth>1</bitWidth>
            </field>
            <field>
              <name>CT</name>
              <bitOffset>16</bitOffset>
              <bitWidth>1</bitWidth>
            </field>
          </fields>
        </register>
        <register>
          <name>CNDTR6</name>
          <addressOffset>0x84</addressOffset>
          <size>0x20</size>
          <fields>
            <field>
              <name>NDT</name>
              <bitOffset>0</bitOffset>
              <bitWidth>16</bitWidth>
            </field>
          </fields>
        </register>
        <register>
          <name>CPAR6</name>
          <addressOffset>0x88</addressOffset>
          <size>0x20</size>
          <fields>
            <field>
              <name>PA</name>
              <bitOffset>0</bitOffset>
              <bitWidth>32</bitWidth>
            </field>
          </fields>
        </register>
        <register>
          <name>CM0AR6</name>
          <addressOffset>0x8c</addressOffset>
          <size>0x20</size>
          <fields>
            <field>
              <name>MA</name>
              <bitOffset>0</bitOffset>
              <bitWidth>32</bitWidth>
            </field>
          </fields>
        </register>
        <register>
          <name>CM1AR6</name>
          <addressOffset>0x90</addressOffset>
          <size>0x20</size>
          <fields>
            <field>
              <name>MA</name>
              <bitOffset>0</bitOffset>
              <bitWidth>32</bitWidth>
            </field>
          </fields>
        </register>
        <register>
          <name>CCR7</name>
          <addressOffset>0x94</addressOffset>
          <size>0x20</size>
          <fields>
            <field>
              <name>EN</name>
              <bitOffset>0</bitOffset>
              <bitWidth>1</bitWidth>
            </field>
            <field>
              <name>TCIE</name>
              <bitOffset>1</bitOffset>
              <bitWidth>1</bitWidth>
            </field>
            <field>
              <name>HTIE</name>
              <bitOffset>2</bitOffset>
              <bitWidth>1</bitWidth>
            </field>
            <field>
              <name>TEIE</name>
              <bitOffset>3</bitOffset>
              <bitWidth>1</bitWidth>
            </field>
            <field>
              <name>DIR</name>
              <bitOffset>4</bitOffset>
              <bitWidth>1</bitWidth>
            </field>
            <field>
              <name>CIRC</name>
              <bitOffset>5</bitOffset>
              <bitWidth>1</bitWidth>
            </field>
            <field>
              <name>PINC</name>
              <bitOffset>6</bitOffset>
              <bitWidth>1</bitWidth>
            </field>
            <field>
              <name>MINC</name>
              <bitOffset>7</bitOffset>
              <bitWidth>1</bitWidth>
            </field>
            <field>
              <name>PSIZE</name>
              <bitOffset>8</bitOffset>
              <bitWidth>2</bitWidth>
            </field>
            <field>
              <name>MSIZE</name>
              <bitOffset>10</bitOffset>
              <bitWidth>2</bitWidth>
            </field>
            <field>
              <name>PL</name>
              <bitOffset>12</bitOffset>
              <bitWidth>2</bitWidth>
            </field>
            <field>
              <name>MEM2MEM</name>
              <bitOffset>14</bitOffset>
              <bitWidth>1</bitWidth>
            </field>
            <field>
              <name>DBM</name>
              <bitOffset>15</bitOffset>
              <bitWidth>1</bitWidth>
            </field>
            <field>
              <name>CT</name>
              <bitOffset>16</bitOffset>
              <bitWidth>1</bitWidth>
            </field>
          </fields>
        </register>
        <register>
          <name>CNDTR7</name>
          <addressOffset>0x98</addressOffset>
          <size>0x20</size>
          <fields>
            <field>
              <name>NDT</name>
              <bitOffset>0</bitOffset>
              <bitWidth>16</bitWidth>
            </field>
          </fields>
        </register>
        <register>
          <name>CPAR7</name>
          <addressOffset>0x9c</addressOffset>
          <size>0x20</size>
          <fields>
            <field>
              <name>PA</name>
              <bitOffset>0</bitOffset>
              <bitWidth>32</bitWidth>
            </field>
          </fields>
        </register>
        <register>
          <name>CM0AR7</name>
          <addressOffset>0xa0</addressOffset>
          <size>0x20</size>
          <fields>
            <field>
              <name>MA</name>
              <bitOffset>0</bitOffset>
              <bitWidth>32</bitWidth>
            </field>
          </fields>
        </register>
        <register>
          <name>CM1AR7</name>
          <addressOffset>0xa4</addressOffset>
          <size>0x20</size>
          <fields>
            <field>
              <name>MA</name>
              <bitOffset>0</bitOffset>
              <bitWidth>32</bitWidth>
            </field>
          </fields>
        </register>
      </registers>
    </peripheral>
    <peripheral>
      <name>DMAMUX2</name>
      <baseAddress>0x58025800</baseAddress>
      <registers>
        <register>
          <name>CCR0</name>
          <addressOffset>0x0</addressOffset>
          <size>0x20</size>
        </register>
        <register>
          <name>CCR0</name>
          <addressOffset>0x0</addressOffset>
          <size>0x20</size>
        </register>
        <register>
          <name>CCR1</name>
          <addressOffset>0x4</addressOffset>
          <size>0x20</size>
        </register>
        <register>
          <name>CCR1</name>
          <addressOffset>0x4</addressOffset>
          <size>0x20</size>
        </register>
        <register>
          <name>CCR2</name>
          <addressOffset>0x8</addressOffset>
          <size>0x20</size>
        </register>
        <register>
          <name>CCR2</name>
          <addressOffset>0x8</addressOffset>
          <size>0x20</size>
        </register>
        <register>
          <name>CCR3</name>
          <addressOffset>0xc</addressOffset>
          <size>0x20</size>
        </register>
        <register>
          <name>CCR3</name>
          <addressOffset>0xc</addressOffset>
          <size>0x20</size>
        </register>
        <register>
          <name>CCR4</name>
          <addressOffset>0x10</addressOffset>
          <size>0x20</size>
        </register>
        <register>
          <name>CCR4</name>
          <addressOffset>0x10</addressOffset>
          <size>0x20</size>
        </register>
        <register>
          <name>CCR5</name>
          <addressOffset>0x14</addressOffset>
          <size>0x20</size>
        </register>
        <register>
          <name>CCR5</name>
          <addressOffset>0x14</addressOffset>
          <size>0x20</size>
        </register>
        <register>
          <name>CCR6</name>
          <addressOffset>0x18</addressOffset>
          <size>0x20</size>
        </register>
        <register>
          <name>CCR6</name>
          <addressOffset>0x18</addressOffset>
          <size>0x20</size>
        </register>
        <register>
          <name>CCR7</name>
          <addressOffset>0x1c</addressOffset>
          <size>0x20</size>
        </register>
        <register>
          <name>CCR7</name>
          <addressOffset>0x1c</addressOffset>
          <size>0x20</size>
        </register>
        <register>
          <name>CCR8</name>
          <addressOffset>0x20</addressOffset>
          <size>0x20</size>
        </register>
        <register>
          <name>CCR9</name>
          <addressOffset>0x24</addressOffset>
          <size>0x20</size>
        </register>
        <register>
          <name>CCR0</name>
          <addressOffset>0x28</addressOffset>
          <size>0x20</size>
        </register>
        <register>
          <name>CCR1</name>
          <addressOffset>0x2c</addressOffset>
          <size>0x20</size>
        </register>
        <register>
          <name>CCR2</name>
          <addressOffset>0x30</addressOffset>
          <size>0x20</size>
        </register>
        <register>
          <name>CCR3</name>
          <addressOffset>0x34</addressOffset>
          <size>0x20</size>
        </register>
        <register>
          <name>CCR4</name>
          <addressOffset>0x38</addressOffset>
          <size>0x20</size>
        </register>
        <register>
          <name>CCR5</name>
          <addressOffset>0x3c</addressOffset>
          <size>0x20</size>
        </register>
        <register>
          <name>CCRs</name>
          <addressOffset>0x80</addressOffset>
          <size>0x20</size>
        </register>
        <register>
          <name>CCRs</name>
          <addressOffset>0x80</addressOffset>
          <size>0x20</size>
        </register>
        <register>
          <name>CCR0</name>
          <addressOffset>0x100</addressOffset>
          <size>0x20</size>
        </register>
        <register>
          <name>CCR0</name>
          <addressOffset>0x100</addressOffset>
          <size>0x20</size>
        </register>
        <register>
          <name>CCR1</name>
          <addressOffset>0x104</addressOffset>
          <size>0x20</size>
        </register>
        <register>
          <name>CCR1</name>
          <addressOffset>0x104</addressOffset>
          <size>0x20</size>
        </register>
        <register>
          <name>CCR2</name>
          <addressOffset>0x108</addressOffset>
          <size>0x20</size>
        </register>
        <register>
          <name>CCR2</name>
          <addressOffset>0x108</addressOffset>
          <size>0x20</size>
        </register>
        <register>
          <name>CCR3</name>
          <addressOffset>0x10c</addressOffset>
          <size>0x20</size>
        </register>
        <register>
          <name>CCR3</name>
          <addressOffset>0x10c</addressOffset>
          <size>0x20</size>
        </register>
        <register>
          <name>CCR4</name>
          <addressOffset>0x110</addressOffset>
          <size>0x20</size>
        </register>
        <register>
          <name>CCR4</name>
          <addressOffset>0x110</addressOffset>
          <size>0x20</size>
        </register>
        <register>
          <name>CCR5</name>
          <addressOffset>0x114</addressOffset>
          <size>0x20</size>
        </register>
        <register>
          <name>CCR5</name>
          <addressOffset>0x114</addressOffset>
          <size>0x20</size>
        </register>
        <register>
          <name>CCR6</name>
          <addressOffset>0x118</addressOffset>
          <size>0x20</size>
        </register>
        <register>
          <name>CCR6</name>
          <addressOffset>0x118</addressOffset>
          <size>0x20</size>
        </register>
        <register>
          <name>CCR7</name>
          <addressOffset>0x11c</addressOffset>
          <size>0x20</size>
        </register>
        <register>
          <name>CCR7</name>
          <addressOffset>0x11c</addressOffset>
          <size>0x20</size>
        </register>
        <register>
          <name>CCRs</name>
          <addressOffset>0x140</addressOffset>
          <size>0x20</size>
        </register>
        <register>
          <name>CCRs</name>
          <addressOffset>0x140</addressOffset>
          <size>0x20</size>
        </register>
      </registers>
    </peripheral>
    <peripheral>
      <name>ADC3</name>
      <baseAddress>0x58026000</baseAddress>
      <registers>
        <register>
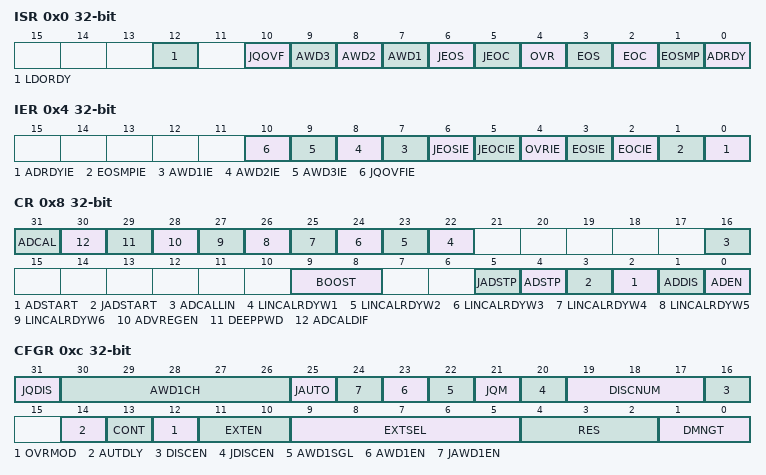
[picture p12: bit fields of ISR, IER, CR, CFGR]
          <name>ISR</name>
          <addressOffset>0x0</addressOffset>
          <size>0x20</size>
          <fields>
            <field>
              <name>ADRDY</name>
              <bitOffset>0</bitOffset>
              <bitWidth>1</bitWidth>
            </field>
            <field>
              <name>EOSMP</name>
              <bitOffset>1</bitOffset>
              <bitWidth>1</bitWidth>
            </field>
            <field>
              <name>EOC</name>
              <bitOffset>2</bitOffset>
              <bitWidth>1</bitWidth>
            </field>
            <field>
              <name>EOS</name>
              <bitOffset>3</bitOffset>
              <bitWidth>1</bitWidth>
            </field>
            <field>
              <name>OVR</name>
              <bitOffset>4</bitOffset>
              <bitWidth>1</bitWidth>
            </field>
            <field>
              <name>JEOC</name>
              <bitOffset>5</bitOffset>
              <bitWidth>1</bitWidth>
            </field>
            <field>
              <name>JEOS</name>
              <bitOffset>6</bitOffset>
              <bitWidth>1</bitWidth>
            </field>
            <field>
              <name>AWD1</name>
              <bitOffset>7</bitOffset>
              <bitWidth>1</bitWidth>
            </field>
            <field>
              <name>AWD2</name>
              <bitOffset>8</bitOffset>
              <bitWidth>1</bitWidth>
            </field>
            <field>
              <name>AWD3</name>
              <bitOffset>9</bitOffset>
              <bitWidth>1</bitWidth>
            </field>
            <field>
              <name>JQOVF</name>
              <bitOffset>10</bitOffset>
              <bitWidth>1</bitWidth>
            </field>
            <field>
              <name>LDORDY</name>
              <bitOffset>12</bitOffset>
              <bitWidth>1</bitWidth>
            </field>
          </fields>
        </register>
        <register>
          <name>IER</name>
          <addressOffset>0x4</addressOffset>
          <size>0x20</size>
          <fields>
            <field>
              <name>ADRDYIE</name>
              <bitOffset>0</bitOffset>
              <bitWidth>1</bitWidth>
            </field>
            <field>
              <name>EOSMPIE</name>
              <bitOffset>1</bitOffset>
              <bitWidth>1</bitWidth>
            </field>
            <field>
              <name>EOCIE</name>
              <bitOffset>2</bitOffset>
              <bitWidth>1</bitWidth>
            </field>
            <field>
              <name>EOSIE</name>
              <bitOffset>3</bitOffset>
              <bitWidth>1</bitWidth>
            </field>
            <field>
              <name>OVRIE</name>
              <bitOffset>4</bitOffset>
              <bitWidth>1</bitWidth>
            </field>
            <field>
              <name>JEOCIE</name>
              <bitOffset>5</bitOffset>
              <bitWidth>1</bitWidth>
            </field>
            <field>
              <name>JEOSIE</name>
              <bitOffset>6</bitOffset>
              <bitWidth>1</bitWidth>
            </field>
            <field>
              <name>AWD1IE</name>
              <bitOffset>7</bitOffset>
              <bitWidth>1</bitWidth>
            </field>
            <field>
              <name>AWD2IE</name>
              <bitOffset>8</bitOffset>
              <bitWidth>1</bitWidth>
            </field>
            <field>
              <name>AWD3IE</name>
              <bitOffset>9</bitOffset>
              <bitWidth>1</bitWidth>
            </field>
            <field>
              <name>JQOVFIE</name>
              <bitOffset>10</bitOffset>
              <bitWidth>1</bitWidth>
            </field>
          </fields>
        </register>
        <register>
          <name>CR</name>
          <addressOffset>0x8</addressOffset>
          <size>0x20</size>
          <fields>
            <field>
              <name>ADEN</name>
              <bitOffset>0</bitOffset>
              <bitWidth>1</bitWidth>
            </field>
            <field>
              <name>ADDIS</name>
              <bitOffset>1</bitOffset>
              <bitWidth>1</bitWidth>
            </field>
            <field>
              <name>ADSTART</name>
              <bitOffset>2</bitOffset>
              <bitWidth>1</bitWidth>
            </field>
            <field>
              <name>JADSTART</name>
              <bitOffset>3</bitOffset>
              <bitWidth>1</bitWidth>
            </field>
            <field>
              <name>ADSTP</name>
              <bitOffset>4</bitOffset>
              <bitWidth>1</bitWidth>
            </field>
            <field>
              <name>JADSTP</name>
              <bitOffset>5</bitOffset>
              <bitWidth>1</bitWidth>
            </field>
            <field>
              <name>BOOST</name>
              <bitOffset>8</bitOffset>
              <bitWidth>2</bitWidth>
            </field>
            <field>
              <name>ADCALLIN</name>
              <bitOffset>16</bitOffset>
              <bitWidth>1</bitWidth>
            </field>
            <field>
              <name>LINCALRDYW1</name>
              <bitOffset>22</bitOffset>
              <bitWidth>1</bitWidth>
            </field>
            <field>
              <name>LINCALRDYW2</name>
              <bitOffset>23</bitOffset>
              <bitWidth>1</bitWidth>
            </field>
            <field>
              <name>LINCALRDYW3</name>
              <bitOffset>24</bitOffset>
              <bitWidth>1</bitWidth>
            </field>
            <field>
              <name>LINCALRDYW4</name>
              <bitOffset>25</bitOffset>
              <bitWidth>1</bitWidth>
            </field>
            <field>
              <name>LINCALRDYW5</name>
              <bitOffset>26</bitOffset>
              <bitWidth>1</bitWidth>
            </field>
            <field>
              <name>LINCALRDYW6</name>
              <bitOffset>27</bitOffset>
              <bitWidth>1</bitWidth>
            </field>
            <field>
              <name>ADVREGEN</name>
              <bitOffset>28</bitOffset>
              <bitWidth>1</bitWidth>
            </field>
            <field>
              <name>DEEPPWD</name>
              <bitOffset>29</bitOffset>
              <bitWidth>1</bitWidth>
            </field>
            <field>
              <name>ADCALDIF</name>
              <bitOffset>30</bitOffset>
              <bitWidth>1</bitWidth>
            </field>
            <field>
              <name>ADCAL</name>
              <bitOffset>31</bitOffset>
              <bitWidth>1</bitWidth>
            </field>
          </fields>
        </register>
        <register>
          <name>CFGR</name>
          <addressOffset>0xc</addressOffset>
          <size>0x20</size>
          <fields>
            <field>
              <name>DMNGT</name>
              <bitOffset>0</bitOffset>
              <bitWidth>2</bitWidth>
            </field>
            <field>
              <name>RES</name>
              <bitOffset>2</bitOffset>
              <bitWidth>3</bitWidth>
            </field>
            <field>
              <name>EXTSEL</name>
              <bitOffset>5</bitOffset>
              <bitWidth>5</bitWidth>
            </field>
            <field>
              <name>EXTEN</name>
              <bitOffset>10</bitOffset>
              <bitWidth>2</bitWidth>
            </field>
            <field>
              <name>OVRMOD</name>
              <bitOffset>12</bitOffset>
              <bitWidth>1</bitWidth>
            </field>
            <field>
              <name>CONT</name>
              <bitOffset>13</bitOffset>
              <bitWidth>1</bitWidth>
            </field>
            <field>
              <name>AUTDLY</name>
              <bitOffset>14</bitOffset>
              <bitWidth>1</bitWidth>
            </field>
            <field>
              <name>DISCEN</name>
              <bitOffset>16</bitOffset>
              <bitWidth>1</bitWidth>
            </field>
            <field>
              <name>DISCNUM</name>
              <bitOffset>17</bitOffset>
              <bitWidth>3</bitWidth>
            </field>
            <field>
              <name>JDISCEN</name>
              <bitOffset>20</bitOffset>
              <bitWidth>1</bitWidth>
            </field>
            <field>
              <name>JQM</name>
              <bitOffset>21</bitOffset>
              <bitWidth>1</bitWidth>
            </field>
            <field>
              <name>AWD1SGL</name>
              <bitOffset>22</bitOffset>
              <bitWidth>1</bitWidth>
            </field>
            <field>
              <name>AWD1EN</name>
              <bitOffset>23</bitOffset>
              <bitWidth>1</bitWidth>
            </field>
            <field>
              <name>JAWD1EN</name>
              <bitOffset>24</bitOffset>
              <bitWidth>1</bitWidth>
            </field>
            <field>
              <name>JAUTO</name>
              <bitOffset>25</bitOffset>
              <bitWidth>1</bitWidth>
            </field>
            <field>
              <name>AWD1CH</name>
              <bitOffset>26</bitOffset>
              <bitWidth>5</bitWidth>
            </field>
            <field>
              <name>JQDIS</name>
              <bitOffset>31</bitOffset>
              <bitWidth>1</bitWidth>
            </field>
          </fields>
        </register>
        <register>
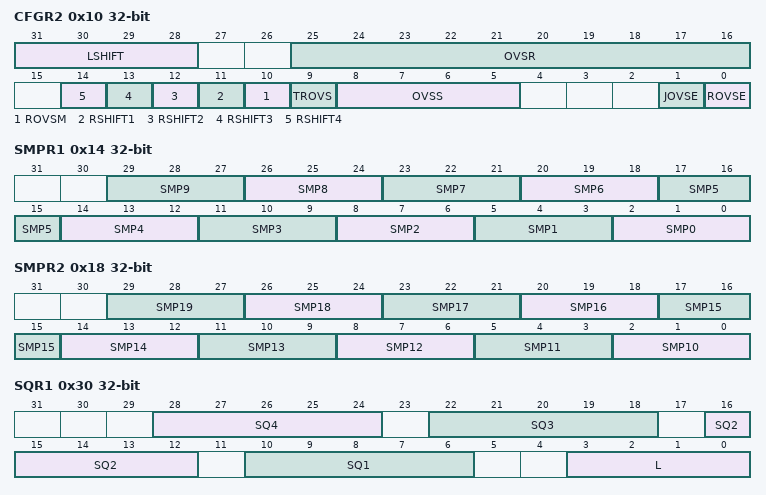
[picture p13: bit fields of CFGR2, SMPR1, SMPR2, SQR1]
          <name>CFGR2</name>
          <addressOffset>0x10</addressOffset>
          <size>0x20</size>
          <fields>
            <field>
              <name>ROVSE</name>
              <bitOffset>0</bitOffset>
              <bitWidth>1</bitWidth>
            </field>
            <field>
              <name>JOVSE</name>
              <bitOffset>1</bitOffset>
              <bitWidth>1</bitWidth>
            </field>
            <field>
              <name>OVSS</name>
              <bitOffset>5</bitOffset>
              <bitWidth>4</bitWidth>
            </field>
            <field>
              <name>TROVS</name>
              <bitOffset>9</bitOffset>
              <bitWidth>1</bitWidth>
            </field>
            <field>
              <name>ROVSM</name>
              <bitOffset>10</bitOffset>
              <bitWidth>1</bitWidth>
            </field>
            <field>
              <name>RSHIFT1</name>
              <bitOffset>11</bitOffset>
              <bitWidth>1</bitWidth>
            </field>
            <field>
              <name>RSHIFT2</name>
              <bitOffset>12</bitOffset>
              <bitWidth>1</bitWidth>
            </field>
            <field>
              <name>RSHIFT3</name>
              <bitOffset>13</bitOffset>
              <bitWidth>1</bitWidth>
            </field>
            <field>
              <name>RSHIFT4</name>
              <bitOffset>14</bitOffset>
              <bitWidth>1</bitWidth>
            </field>
            <field>
              <name>OVSR</name>
              <bitOffset>16</bitOffset>
              <bitWidth>10</bitWidth>
            </field>
            <field>
              <name>LSHIFT</name>
              <bitOffset>28</bitOffset>
              <bitWidth>4</bitWidth>
            </field>
          </fields>
        </register>
        <register>
          <name>SMPR1</name>
          <addressOffset>0x14</addressOffset>
          <size>0x20</size>
          <fields>
            <field>
              <name>SMP0</name>
              <bitOffset>0</bitOffset>
              <bitWidth>3</bitWidth>
            </field>
            <field>
              <name>SMP1</name>
              <bitOffset>3</bitOffset>
              <bitWidth>3</bitWidth>
            </field>
            <field>
              <name>SMP2</name>
              <bitOffset>6</bitOffset>
              <bitWidth>3</bitWidth>
            </field>
            <field>
              <name>SMP3</name>
              <bitOffset>9</bitOffset>
              <bitWidth>3</bitWidth>
            </field>
            <field>
              <name>SMP4</name>
              <bitOffset>12</bitOffset>
              <bitWidth>3</bitWidth>
            </field>
            <field>
              <name>SMP5</name>
              <bitOffset>15</bitOffset>
              <bitWidth>3</bitWidth>
            </field>
            <field>
              <name>SMP6</name>
              <bitOffset>18</bitOffset>
              <bitWidth>3</bitWidth>
            </field>
            <field>
              <name>SMP7</name>
              <bitOffset>21</bitOffset>
              <bitWidth>3</bitWidth>
            </field>
            <field>
              <name>SMP8</name>
              <bitOffset>24</bitOffset>
              <bitWidth>3</bitWidth>
            </field>
            <field>
              <name>SMP9</name>
              <bitOffset>27</bitOffset>
              <bitWidth>3</bitWidth>
            </field>
          </fields>
        </register>
        <register>
          <name>SMPR2</name>
          <addressOffset>0x18</addressOffset>
          <size>0x20</size>
          <fields>
            <field>
              <name>SMP10</name>
              <bitOffset>0</bitOffset>
              <bitWidth>3</bitWidth>
            </field>
            <field>
              <name>SMP11</name>
              <bitOffset>3</bitOffset>
              <bitWidth>3</bitWidth>
            </field>
            <field>
              <name>SMP12</name>
              <bitOffset>6</bitOffset>
              <bitWidth>3</bitWidth>
            </field>
            <field>
              <name>SMP13</name>
              <bitOffset>9</bitOffset>
              <bitWidth>3</bitWidth>
            </field>
            <field>
              <name>SMP14</name>
              <bitOffset>12</bitOffset>
              <bitWidth>3</bitWidth>
            </field>
            <field>
              <name>SMP15</name>
              <bitOffset>15</bitOffset>
              <bitWidth>3</bitWidth>
            </field>
            <field>
              <name>SMP16</name>
              <bitOffset>18</bitOffset>
              <bitWidth>3</bitWidth>
            </field>
            <field>
              <name>SMP17</name>
              <bitOffset>21</bitOffset>
              <bitWidth>3</bitWidth>
            </field>
            <field>
              <name>SMP18</name>
              <bitOffset>24</bitOffset>
              <bitWidth>3</bitWidth>
            </field>
            <field>
              <name>SMP19</name>
              <bitOffset>27</bitOffset>
              <bitWidth>3</bitWidth>
            </field>
          </fields>
        </register>
        <register>
          <name>PCSEL</name>
          <addressOffset>0x1c</addressOffset>
          <size>0x20</size>
          <fields>
            <field>
              <name>PCSEL</name>
              <bitOffset>0</bitOffset>
              <bitWidth>20</bitWidth>
            </field>
          </fields>
        </register>
        <register>
          <name>LTR1</name>
          <addressOffset>0x20</addressOffset>
          <size>0x20</size>
        </register>
        <register>
          <name>HTR1</name>
          <addressOffset>0x24</addressOffset>
          <size>0x20</size>
        </register>
        <register>
          <name>SQR1</name>
          <addressOffset>0x30</addressOffset>
          <size>0x20</size>
          <fields>
            <field>
              <name>L</name>
              <bitOffset>0</bitOffset>
              <bitWidth>4</bitWidth>
            </field>
            <field>
              <name>SQ1</name>
              <bitOffset>6</bitOffset>
              <bitWidth>5</bitWidth>
            </field>
            <field>
              <name>SQ2</name>
              <bitOffset>12</bitOffset>
              <bitWidth>5</bitWidth>
            </field>
            <field>
              <name>SQ3</name>
              <bitOffset>18</bitOffset>
              <bitWidth>5</bitWidth>
            </field>
            <field>
              <name>SQ4</name>
              <bitOffset>24</bitOffset>
              <bitWidth>5</bitWidth>
            </field>
          </fields>
        </register>
        <register>
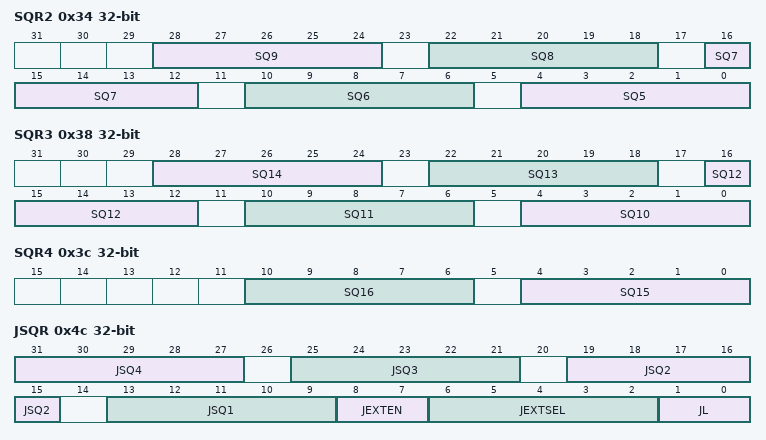
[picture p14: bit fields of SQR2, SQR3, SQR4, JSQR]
          <name>SQR2</name>
          <addressOffset>0x34</addressOffset>
          <size>0x20</size>
          <fields>
            <field>
              <name>SQ5</name>
              <bitOffset>0</bitOffset>
              <bitWidth>5</bitWidth>
            </field>
            <field>
              <name>SQ6</name>
              <bitOffset>6</bitOffset>
              <bitWidth>5</bitWidth>
            </field>
            <field>
              <name>SQ7</name>
              <bitOffset>12</bitOffset>
              <bitWidth>5</bitWidth>
            </field>
            <field>
              <name>SQ8</name>
              <bitOffset>18</bitOffset>
              <bitWidth>5</bitWidth>
            </field>
            <field>
              <name>SQ9</name>
              <bitOffset>24</bitOffset>
              <bitWidth>5</bitWidth>
            </field>
          </fields>
        </register>
        <register>
          <name>SQR3</name>
          <addressOffset>0x38</addressOffset>
          <size>0x20</size>
          <fields>
            <field>
              <name>SQ10</name>
              <bitOffset>0</bitOffset>
              <bitWidth>5</bitWidth>
            </field>
            <field>
              <name>SQ11</name>
              <bitOffset>6</bitOffset>
              <bitWidth>5</bitWidth>
            </field>
            <field>
              <name>SQ12</name>
              <bitOffset>12</bitOffset>
              <bitWidth>5</bitWidth>
            </field>
            <field>
              <name>SQ13</name>
              <bitOffset>18</bitOffset>
              <bitWidth>5</bitWidth>
            </field>
            <field>
              <name>SQ14</name>
              <bitOffset>24</bitOffset>
              <bitWidth>5</bitWidth>
            </field>
          </fields>
        </register>
        <register>
          <name>SQR4</name>
          <addressOffset>0x3c</addressOffset>
          <size>0x20</size>
          <fields>
            <field>
              <name>SQ15</name>
              <bitOffset>0</bitOffset>
              <bitWidth>5</bitWidth>
            </field>
            <field>
              <name>SQ16</name>
              <bitOffset>6</bitOffset>
              <bitWidth>5</bitWidth>
            </field>
          </fields>
        </register>
        <register>
          <name>DR</name>
          <addressOffset>0x40</addressOffset>
          <size>0x20</size>
          <fields>
            <field>
              <name>RDATA</name>
              <bitOffset>0</bitOffset>
              <bitWidth>32</bitWidth>
            </field>
          </fields>
        </register>
        <register>
          <name>JSQR</name>
          <addressOffset>0x4c</addressOffset>
          <size>0x20</size>
          <fields>
            <field>
              <name>JL</name>
              <bitOffset>0</bitOffset>
              <bitWidth>2</bitWidth>
            </field>
            <field>
              <name>JEXTSEL</name>
              <bitOffset>2</bitOffset>
              <bitWidth>5</bitWidth>
            </field>
            <field>
              <name>JEXTEN</name>
              <bitOffset>7</bitOffset>
              <bitWidth>2</bitWidth>
            </field>
            <field>
              <name>JSQ1</name>
              <bitOffset>9</bitOffset>
              <bitWidth>5</bitWidth>
            </field>
            <field>
              <name>JSQ2</name>
              <bitOffset>15</bitOffset>
              <bitWidth>5</bitWidth>
            </field>
            <field>
              <name>JSQ3</name>
              <bitOffset>21</bitOffset>
              <bitWidth>5</bitWidth>
            </field>
            <field>
              <name>JSQ4</name>
              <bitOffset>27</bitOffset>
              <bitWidth>5</bitWidth>
            </field>
          </fields>
        </register>
        <register>
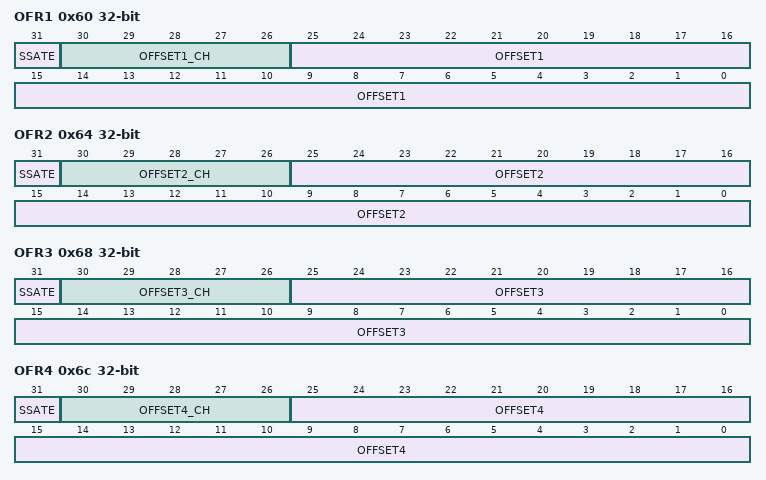
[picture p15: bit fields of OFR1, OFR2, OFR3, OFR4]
          <name>OFR1</name>
          <addressOffset>0x60</addressOffset>
          <size>0x20</size>
          <fields>
            <field>
              <name>OFFSET1</name>
              <bitOffset>0</bitOffset>
              <bitWidth>26</bitWidth>
            </field>
            <field>
              <name>OFFSET1_CH</name>
              <bitOffset>26</bitOffset>
              <bitWidth>5</bitWidth>
            </field>
            <field>
              <name>SSATE</name>
              <bitOffset>31</bitOffset>
              <bitWidth>1</bitWidth>
            </field>
          </fields>
        </register>
        <register>
          <name>OFR2</name>
          <addressOffset>0x64</addressOffset>
          <size>0x20</size>
          <fields>
            <field>
              <name>OFFSET2</name>
              <bitOffset>0</bitOffset>
              <bitWidth>26</bitWidth>
            </field>
            <field>
              <name>OFFSET2_CH</name>
              <bitOffset>26</bitOffset>
              <bitWidth>5</bitWidth>
            </field>
            <field>
              <name>SSATE</name>
              <bitOffset>31</bitOffset>
              <bitWidth>1</bitWidth>
            </field>
          </fields>
        </register>
        <register>
          <name>OFR3</name>
          <addressOffset>0x68</addressOffset>
          <size>0x20</size>
          <fields>
            <field>
              <name>OFFSET3</name>
              <bitOffset>0</bitOffset>
              <bitWidth>26</bitWidth>
            </field>
            <field>
              <name>OFFSET3_CH</name>
              <bitOffset>26</bitOffset>
              <bitWidth>5</bitWidth>
            </field>
            <field>
              <name>SSATE</name>
              <bitOffset>31</bitOffset>
              <bitWidth>1</bitWidth>
            </field>
          </fields>
        </register>
        <register>
          <name>OFR4</name>
          <addressOffset>0x6c</addressOffset>
          <size>0x20</size>
          <fields>
            <field>
              <name>OFFSET4</name>
              <bitOffset>0</bitOffset>
              <bitWidth>26</bitWidth>
            </field>
            <field>
              <name>OFFSET4_CH</name>
              <bitOffset>26</bitOffset>
              <bitWidth>5</bitWidth>
            </field>
            <field>
              <name>SSATE</name>
              <bitOffset>31</bitOffset>
              <bitWidth>1</bitWidth>
            </field>
          </fields>
        </register>
        <register>
          <name>JDR1</name>
          <addressOffset>0x80</addressOffset>
          <size>0x20</size>
          <fields>
            <field>
              <name>JDATA</name>
              <bitOffset>0</bitOffset>
              <bitWidth>32</bitWidth>
            </field>
          </fields>
        </register>
        <register>
          <name>JDR2</name>
          <addressOffset>0x84</addressOffset>
          <size>0x20</size>
          <fields>
            <field>
              <name>JDATA</name>
              <bitOffset>0</bitOffset>
              <bitWidth>32</bitWidth>
            </field>
          </fields>
        </register>
        <register>
          <name>JDR3</name>
          <addressOffset>0x88</addressOffset>
          <size>0x20</size>
          <fields>
            <field>
              <name>JDATA</name>
              <bitOffset>0</bitOffset>
              <bitWidth>32</bitWidth>
            </field>
          </fields>
        </register>
        <register>
          <name>JDR4</name>
          <addressOffset>0x8c</addressOffset>
          <size>0x20</size>
          <fields>
            <field>
              <name>JDATA</name>
              <bitOffset>0</bitOffset>
              <bitWidth>32</bitWidth>
            </field>
          </fields>
        </register>
        <register>
          <name>AWD2CR</name>
          <addressOffset>0xa0</addressOffset>
          <size>0x20</size>
          <fields>
            <field>
              <name>AWD2CH</name>
              <bitOffset>0</bitOffset>
              <bitWidth>20</bitWidth>
            </field>
          </fields>
        </register>
        <register>
          <name>AWD3CR</name>
          <addressOffset>0xa4</addressOffset>
          <size>0x20</size>
          <fields>
            <field>
              <name>AWD3CH</name>
              <bitOffset>0</bitOffset>
              <bitWidth>20</bitWidth>
            </field>
          </fields>
        </register>
        <register>
          <name>LTR2</name>
          <addressOffset>0xb0</addressOffset>
          <size>0x20</size>
        </register>
        <register>
          <name>HTR2</name>
          <addressOffset>0xb4</addressOffset>
          <size>0x20</size>
        </register>
        <register>
          <name>LTR3</name>
          <addressOffset>0xb8</addressOffset>
          <size>0x20</size>
        </register>
        <register>
          <name>HTR3</name>
          <addressOffset>0xbc</addressOffset>
          <size>0x20</size>
        </register>
        <register>
          <name>DIFSEL</name>
          <addressOffset>0xc0</addressOffset>
          <size>0x20</size>
          <fields>
            <field>
              <name>DIFSEL</name>
              <bitOffset>0</bitOffset>
              <bitWidth>20</bitWidth>
            </field>
          </fields>
        </register>
        <register>
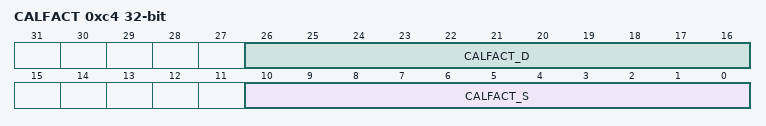
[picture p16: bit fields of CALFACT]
          <name>CALFACT</name>
          <addressOffset>0xc4</addressOffset>
          <size>0x20</size>
          <fields>
            <field>
              <name>CALFACT_S</name>
              <bitOffset>0</bitOffset>
              <bitWidth>11</bitWidth>
            </field>
            <field>
              <name>CALFACT_D</name>
              <bitOffset>16</bitOffset>
              <bitWidth>11</bitWidth>
            </field>
          </fields>
        </register>
        <register>
          <name>CALFACT2</name>
          <addressOffset>0xc8</addressOffset>
          <size>0x20</size>
          <fields>
            <field>
              <name>LINCALFACT</name>
              <bitOffset>0</bitOffset>
              <bitWidth>30</bitWidth>
            </field>
          </fields>
        </register>
      </registers>
    </peripheral>
    <peripheral>
      <name>ADC3_COMMON</name>
      <baseAddress>0x58026300</baseAddress>
      <registers>
        <register>
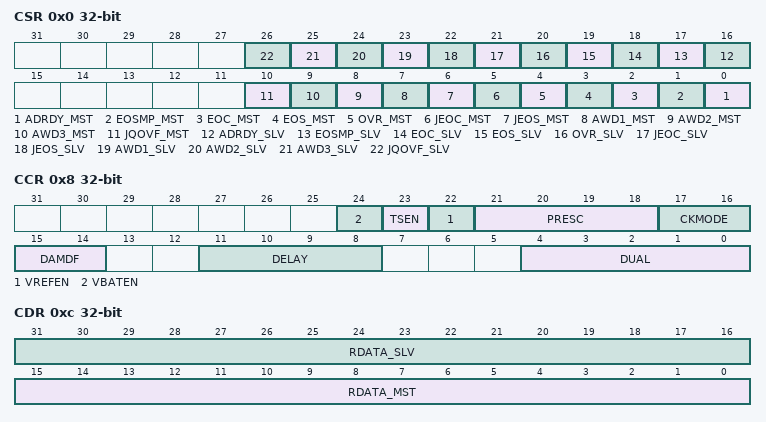
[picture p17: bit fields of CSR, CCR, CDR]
          <name>CSR</name>
          <addressOffset>0x0</addressOffset>
          <size>0x20</size>
          <fields>
            <field>
              <name>ADRDY_MST</name>
              <bitOffset>0</bitOffset>
              <bitWidth>1</bitWidth>
            </field>
            <field>
              <name>EOSMP_MST</name>
              <bitOffset>1</bitOffset>
              <bitWidth>1</bitWidth>
            </field>
            <field>
              <name>EOC_MST</name>
              <bitOffset>2</bitOffset>
              <bitWidth>1</bitWidth>
            </field>
            <field>
              <name>EOS_MST</name>
              <bitOffset>3</bitOffset>
              <bitWidth>1</bitWidth>
            </field>
            <field>
              <name>OVR_MST</name>
              <bitOffset>4</bitOffset>
              <bitWidth>1</bitWidth>
            </field>
            <field>
              <name>JEOC_MST</name>
              <bitOffset>5</bitOffset>
              <bitWidth>1</bitWidth>
            </field>
            <field>
              <name>JEOS_MST</name>
              <bitOffset>6</bitOffset>
              <bitWidth>1</bitWidth>
            </field>
            <field>
              <name>AWD1_MST</name>
              <bitOffset>7</bitOffset>
              <bitWidth>1</bitWidth>
            </field>
            <field>
              <name>AWD2_MST</name>
              <bitOffset>8</bitOffset>
              <bitWidth>1</bitWidth>
            </field>
            <field>
              <name>AWD3_MST</name>
              <bitOffset>9</bitOffset>
              <bitWidth>1</bitWidth>
            </field>
            <field>
              <name>JQOVF_MST</name>
              <bitOffset>10</bitOffset>
              <bitWidth>1</bitWidth>
            </field>
            <field>
              <name>ADRDY_SLV</name>
              <bitOffset>16</bitOffset>
              <bitWidth>1</bitWidth>
            </field>
            <field>
              <name>EOSMP_SLV</name>
              <bitOffset>17</bitOffset>
              <bitWidth>1</bitWidth>
            </field>
            <field>
              <name>EOC_SLV</name>
              <bitOffset>18</bitOffset>
              <bitWidth>1</bitWidth>
            </field>
            <field>
              <name>EOS_SLV</name>
              <bitOffset>19</bitOffset>
              <bitWidth>1</bitWidth>
            </field>
            <field>
              <name>OVR_SLV</name>
              <bitOffset>20</bitOffset>
              <bitWidth>1</bitWidth>
            </field>
            <field>
              <name>JEOC_SLV</name>
              <bitOffset>21</bitOffset>
              <bitWidth>1</bitWidth>
            </field>
            <field>
              <name>JEOS_SLV</name>
              <bitOffset>22</bitOffset>
              <bitWidth>1</bitWidth>
            </field>
            <field>
              <name>AWD1_SLV</name>
              <bitOffset>23</bitOffset>
              <bitWidth>1</bitWidth>
            </field>
            <field>
              <name>AWD2_SLV</name>
              <bitOffset>24</bitOffset>
              <bitWidth>1</bitWidth>
            </field>
            <field>
              <name>AWD3_SLV</name>
              <bitOffset>25</bitOffset>
              <bitWidth>1</bitWidth>
            </field>
            <field>
              <name>JQOVF_SLV</name>
              <bitOffset>26</bitOffset>
              <bitWidth>1</bitWidth>
            </field>
          </fields>
        </register>
        <register>
          <name>CCR</name>
          <addressOffset>0x8</addressOffset>
          <size>0x20</size>
          <fields>
            <field>
              <name>DUAL</name>
              <bitOffset>0</bitOffset>
              <bitWidth>5</bitWidth>
            </field>
            <field>
              <name>DELAY</name>
              <bitOffset>8</bitOffset>
              <bitWidth>4</bitWidth>
            </field>
            <field>
              <name>DAMDF</name>
              <bitOffset>14</bitOffset>
              <bitWidth>2</bitWidth>
            </field>
            <field>
              <name>CKMODE</name>
              <bitOffset>16</bitOffset>
              <bitWidth>2</bitWidth>
            </field>
            <field>
              <name>PRESC</name>
              <bitOffset>18</bitOffset>
              <bitWidth>4</bitWidth>
            </field>
            <field>
              <name>VREFEN</name>
              <bitOffset>22</bitOffset>
              <bitWidth>1</bitWidth>
            </field>
            <field>
              <name>TSEN</name>
              <bitOffset>23</bitOffset>
              <bitWidth>1</bitWidth>
            </field>
            <field>
              <name>VBATEN</name>
              <bitOffset>24</bitOffset>
              <bitWidth>1</bitWidth>
            </field>
          </fields>
        </register>
        <register>
          <name>CDR</name>
          <addressOffset>0xc</addressOffset>
          <size>0x20</size>
          <fields>
            <field>
              <name>RDATA_MST</name>
              <bitOffset>0</bitOffset>
              <bitWidth>16</bitWidth>
            </field>
            <field>
              <name>RDATA_SLV</name>
              <bitOffset>16</bitOffset>
              <bitWidth>16</bitWidth>
            </field>
          </fields>
        </register>
        <register>
          <name>CDR2</name>
          <addressOffset>0x10</addressOffset>
          <size>0x20</size>
          <fields>
            <field>
              <name>RDATA_ALT</name>
              <bitOffset>0</bitOffset>
              <bitWidth>32</bitWidth>
            </field>
          </fields>
        </register>
      </registers>
    </peripheral>
    <peripheral>
      <name>HSEM</name>
      <baseAddress>0x58026400</baseAddress>
      <registers>
        <register>
          <name>R.0</name>
          <addressOffset>0x0</addressOffset>
          <size>0x20</size>
          <fields>
            <field>
              <name>PROCID</name>
              <bitOffset>0</bitOffset>
              <bitWidth>8</bitWidth>
            </field>
            <field>
              <name>COREID</name>
              <bitOffset>8</bitOffset>
              <bitWidth>8</bitWidth>
            </field>
            <field>
              <name>LOCK</name>
              <bitOffset>31</bitOffset>
              <bitWidth>1</bitWidth>
            </field>
          </fields>
        </register>
        <register>
          <name>R.1</name>
          <addressOffset>0x4</addressOffset>
          <size>0x20</size>
          <fields>
            <field>
              <name>PROCID</name>
              <bitOffset>0</bitOffset>
              <bitWidth>8</bitWidth>
            </field>
            <field>
              <name>COREID</name>
              <bitOffset>8</bitOffset>
              <bitWidth>8</bitWidth>
            </field>
            <field>
              <name>LOCK</name>
              <bitOffset>31</bitOffset>
              <bitWidth>1</bitWidth>
            </field>
          </fields>
        </register>
        <register>
          <name>R.2</name>
          <addressOffset>0x8</addressOffset>
          <size>0x20</size>
          <fields>
            <field>
              <name>PROCID</name>
              <bitOffset>0</bitOffset>
              <bitWidth>8</bitWidth>
            </field>
            <field>
              <name>COREID</name>
              <bitOffset>8</bitOffset>
              <bitWidth>8</bitWidth>
            </field>
            <field>
              <name>LOCK</name>
              <bitOffset>31</bitOffset>
              <bitWidth>1</bitWidth>
            </field>
          </fields>
        </register>
        <register>
          <name>R.3</name>
          <addressOffset>0xc</addressOffset>
          <size>0x20</size>
          <fields>
            <field>
              <name>PROCID</name>
              <bitOffset>0</bitOffset>
              <bitWidth>8</bitWidth>
            </field>
            <field>
              <name>COREID</name>
              <bitOffset>8</bitOffset>
              <bitWidth>8</bitWidth>
            </field>
            <field>
              <name>LOCK</name>
              <bitOffset>31</bitOffset>
              <bitWidth>1</bitWidth>
            </field>
          </fields>
        </register>
        <register>
          <name>R.4</name>
          <addressOffset>0x10</addressOffset>
          <size>0x20</size>
          <fields>
            <field>
              <name>PROCID</name>
              <bitOffset>0</bitOffset>
              <bitWidth>8</bitWidth>
            </field>
            <field>
              <name>COREID</name>
              <bitOffset>8</bitOffset>
              <bitWidth>8</bitWidth>
            </field>
            <field>
              <name>LOCK</name>
              <bitOffset>31</bitOffset>
              <bitWidth>1</bitWidth>
            </field>
          </fields>
        </register>
        <register>
          <name>R.5</name>
          <addressOffset>0x14</addressOffset>
          <size>0x20</size>
          <fields>
            <field>
              <name>PROCID</name>
              <bitOffset>0</bitOffset>
              <bitWidth>8</bitWidth>
            </field>
            <field>
              <name>COREID</name>
              <bitOffset>8</bitOffset>
              <bitWidth>8</bitWidth>
            </field>
            <field>
              <name>LOCK</name>
              <bitOffset>31</bitOffset>
              <bitWidth>1</bitWidth>
            </field>
          </fields>
        </register>
        <register>
          <name>R.6</name>
          <addressOffset>0x18</addressOffset>
          <size>0x20</size>
          <fields>
            <field>
              <name>PROCID</name>
              <bitOffset>0</bitOffset>
              <bitWidth>8</bitWidth>
            </field>
            <field>
              <name>COREID</name>
              <bitOffset>8</bitOffset>
              <bitWidth>8</bitWidth>
            </field>
            <field>
              <name>LOCK</name>
              <bitOffset>31</bitOffset>
              <bitWidth>1</bitWidth>
            </field>
          </fields>
        </register>
        <register>
          <name>R.7</name>
          <addressOffset>0x1c</addressOffset>
          <size>0x20</size>
          <fields>
            <field>
              <name>PROCID</name>
              <bitOffset>0</bitOffset>
              <bitWidth>8</bitWidth>
            </field>
            <field>
              <name>COREID</name>
              <bitOffset>8</bitOffset>
              <bitWidth>8</bitWidth>
            </field>
            <field>
              <name>LOCK</name>
              <bitOffset>31</bitOffset>
              <bitWidth>1</bitWidth>
            </field>
          </fields>
        </register>
        <register>
          <name>R.8</name>
          <addressOffset>0x20</addressOffset>
          <size>0x20</size>
          <fields>
            <field>
              <name>PROCID</name>
              <bitOffset>0</bitOffset>
              <bitWidth>8</bitWidth>
            </field>
            <field>
              <name>COREID</name>
              <bitOffset>8</bitOffset>
              <bitWidth>8</bitWidth>
            </field>
            <field>
              <name>LOCK</name>
              <bitOffset>31</bitOffset>
              <bitWidth>1</bitWidth>
            </field>
          </fields>
        </register>
        <register>
          <name>R.9</name>
          <addressOffset>0x24</addressOffset>
          <size>0x20</size>
          <fields>
            <field>
              <name>PROCID</name>
              <bitOffset>0</bitOffset>
              <bitWidth>8</bitWidth>
            </field>
            <field>
              <name>COREID</name>
              <bitOffset>8</bitOffset>
              <bitWidth>8</bitWidth>
            </field>
            <field>
              <name>LOCK</name>
              <bitOffset>31</bitOffset>
              <bitWidth>1</bitWidth>
            </field>
          </fields>
        </register>
        <register>
          <name>R.10</name>
          <addressOffset>0x28</addressOffset>
          <size>0x20</size>
          <fields>
            <field>
              <name>PROCID</name>
              <bitOffset>0</bitOffset>
              <bitWidth>8</bitWidth>
            </field>
            <field>
              <name>COREID</name>
              <bitOffset>8</bitOffset>
              <bitWidth>8</bitWidth>
            </field>
            <field>
              <name>LOCK</name>
              <bitOffset>31</bitOffset>
              <bitWidth>1</bitWidth>
            </field>
          </fields>
        </register>
        <register>
          <name>R.11</name>
          <addressOffset>0x2c</addressOffset>
          <size>0x20</size>
          <fields>
            <field>
              <name>PROCID</name>
              <bitOffset>0</bitOffset>
              <bitWidth>8</bitWidth>
            </field>
            <field>
              <name>COREID</name>
              <bitOffset>8</bitOffset>
              <bitWidth>8</bitWidth>
            </field>
            <field>
              <name>LOCK</name>
              <bitOffset>31</bitOffset>
              <bitWidth>1</bitWidth>
            </field>
          </fields>
        </register>
        <register>
          <name>R.12</name>
          <addressOffset>0x30</addressOffset>
          <size>0x20</size>
          <fields>
            <field>
              <name>PROCID</name>
              <bitOffset>0</bitOffset>
              <bitWidth>8</bitWidth>
            </field>
            <field>
              <name>COREID</name>
              <bitOffset>8</bitOffset>
              <bitWidth>8</bitWidth>
            </field>
            <field>
              <name>LOCK</name>
              <bitOffset>31</bitOffset>
              <bitWidth>1</bitWidth>
            </field>
          </fields>
        </register>
        <register>
          <name>R.13</name>
          <addressOffset>0x34</addressOffset>
          <size>0x20</size>
          <fields>
            <field>
              <name>PROCID</name>
              <bitOffset>0</bitOffset>
              <bitWidth>8</bitWidth>
            </field>
            <field>
              <name>COREID</name>
              <bitOffset>8</bitOffset>
              <bitWidth>8</bitWidth>
            </field>
            <field>
              <name>LOCK</name>
              <bitOffset>31</bitOffset>
              <bitWidth>1</bitWidth>
            </field>
          </fields>
        </register>
        <register>
          <name>R.14</name>
          <addressOffset>0x38</addressOffset>
          <size>0x20</size>
          <fields>
            <field>
              <name>PROCID</name>
              <bitOffset>0</bitOffset>
              <bitWidth>8</bitWidth>
            </field>
            <field>
              <name>COREID</name>
              <bitOffset>8</bitOffset>
              <bitWidth>8</bitWidth>
            </field>
            <field>
              <name>LOCK</name>
              <bitOffset>31</bitOffset>
              <bitWidth>1</bitWidth>
            </field>
          </fields>
        </register>
        <register>
          <name>R.15</name>
          <addressOffset>0x3c</addressOffset>
          <size>0x20</size>
          <fields>
            <field>
              <name>PROCID</name>
              <bitOffset>0</bitOffset>
              <bitWidth>8</bitWidth>
            </field>
            <field>
              <name>COREID</name>
              <bitOffset>8</bitOffset>
              <bitWidth>8</bitWidth>
            </field>
            <field>
              <name>LOCK</name>
              <bitOffset>31</bitOffset>
              <bitWidth>1</bitWidth>
            </field>
          </fields>
        </register>
        <register>
          <name>R.16</name>
          <addressOffset>0x40</addressOffset>
          <size>0x20</size>
          <fields>
            <field>
              <name>PROCID</name>
              <bitOffset>0</bitOffset>
              <bitWidth>8</bitWidth>
            </field>
            <field>
              <name>COREID</name>
              <bitOffset>8</bitOffset>
              <bitWidth>8</bitWidth>
            </field>
            <field>
              <name>LOCK</name>
              <bitOffset>31</bitOffset>
              <bitWidth>1</bitWidth>
            </field>
          </fields>
        </register>
        <register>
          <name>R.17</name>
          <addressOffset>0x44</addressOffset>
          <size>0x20</size>
          <fields>
            <field>
              <name>PROCID</name>
              <bitOffset>0</bitOffset>
              <bitWidth>8</bitWidth>
            </field>
            <field>
              <name>COREID</name>
              <bitOffset>8</bitOffset>
              <bitWidth>8</bitWidth>
            </field>
            <field>
              <name>LOCK</name>
              <bitOffset>31</bitOffset>
              <bitWidth>1</bitWidth>
            </field>
          </fields>
        </register>
        <register>
          <name>R.18</name>
          <addressOffset>0x48</addressOffset>
          <size>0x20</size>
          <fields>
            <field>
              <name>PROCID</name>
              <bitOffset>0</bitOffset>
              <bitWidth>8</bitWidth>
            </field>
            <field>
              <name>COREID</name>
              <bitOffset>8</bitOffset>
              <bitWidth>8</bitWidth>
            </field>
            <field>
              <name>LOCK</name>
              <bitOffset>31</bitOffset>
              <bitWidth>1</bitWidth>
            </field>
          </fields>
        </register>
        <register>
          <name>R.19</name>
          <addressOffset>0x4c</addressOffset>
          <size>0x20</size>
          <fields>
            <field>
              <name>PROCID</name>
              <bitOffset>0</bitOffset>
              <bitWidth>8</bitWidth>
            </field>
            <field>
              <name>COREID</name>
              <bitOffset>8</bitOffset>
              <bitWidth>8</bitWidth>
            </field>
            <field>
              <name>LOCK</name>
              <bitOffset>31</bitOffset>
              <bitWidth>1</bitWidth>
            </field>
          </fields>
        </register>
        <register>
          <name>R.20</name>
          <addressOffset>0x50</addressOffset>
          <size>0x20</size>
          <fields>
            <field>
              <name>PROCID</name>
              <bitOffset>0</bitOffset>
              <bitWidth>8</bitWidth>
            </field>
            <field>
              <name>COREID</name>
              <bitOffset>8</bitOffset>
              <bitWidth>8</bitWidth>
            </field>
            <field>
              <name>LOCK</name>
              <bitOffset>31</bitOffset>
              <bitWidth>1</bitWidth>
            </field>
          </fields>
        </register>
        <register>
          <name>R.21</name>
          <addressOffset>0x54</addressOffset>
          <size>0x20</size>
          <fields>
            <field>
              <name>PROCID</name>
              <bitOffset>0</bitOffset>
              <bitWidth>8</bitWidth>
            </field>
            <field>
              <name>COREID</name>
              <bitOffset>8</bitOffset>
              <bitWidth>8</bitWidth>
            </field>
            <field>
              <name>LOCK</name>
              <bitOffset>31</bitOffset>
              <bitWidth>1</bitWidth>
            </field>
          </fields>
        </register>
        <register>
          <name>R.22</name>
          <addressOffset>0x58</addressOffset>
          <size>0x20</size>
          <fields>
            <field>
              <name>PROCID</name>
              <bitOffset>0</bitOffset>
              <bitWidth>8</bitWidth>
            </field>
            <field>
              <name>COREID</name>
              <bitOffset>8</bitOffset>
              <bitWidth>8</bitWidth>
            </field>
            <field>
              <name>LOCK</name>
              <bitOffset>31</bitOffset>
              <bitWidth>1</bitWidth>
            </field>
          </fields>
        </register>
        <register>
          <name>R.23</name>
          <addressOffset>0x5c</addressOffset>
          <size>0x20</size>
          <fields>
            <field>
              <name>PROCID</name>
              <bitOffset>0</bitOffset>
              <bitWidth>8</bitWidth>
            </field>
            <field>
              <name>COREID</name>
              <bitOffset>8</bitOffset>
              <bitWidth>8</bitWidth>
            </field>
            <field>
              <name>LOCK</name>
              <bitOffset>31</bitOffset>
              <bitWidth>1</bitWidth>
            </field>
          </fields>
        </register>
        <register>
          <name>R.24</name>
          <addressOffset>0x60</addressOffset>
          <size>0x20</size>
          <fields>
            <field>
              <name>PROCID</name>
              <bitOffset>0</bitOffset>
              <bitWidth>8</bitWidth>
            </field>
            <field>
              <name>COREID</name>
              <bitOffset>8</bitOffset>
              <bitWidth>8</bitWidth>
            </field>
            <field>
              <name>LOCK</name>
              <bitOffset>31</bitOffset>
              <bitWidth>1</bitWidth>
            </field>
          </fields>
        </register>
        <register>
          <name>R.25</name>
          <addressOffset>0x64</addressOffset>
          <size>0x20</size>
          <fields>
            <field>
              <name>PROCID</name>
              <bitOffset>0</bitOffset>
              <bitWidth>8</bitWidth>
            </field>
            <field>
              <name>COREID</name>
              <bitOffset>8</bitOffset>
              <bitWidth>8</bitWidth>
            </field>
            <field>
              <name>LOCK</name>
              <bitOffset>31</bitOffset>
              <bitWidth>1</bitWidth>
            </field>
          </fields>
        </register>
        <register>
          <name>R.26</name>
          <addressOffset>0x68</addressOffset>
          <size>0x20</size>
          <fields>
            <field>
              <name>PROCID</name>
              <bitOffset>0</bitOffset>
              <bitWidth>8</bitWidth>
            </field>
            <field>
              <name>COREID</name>
              <bitOffset>8</bitOffset>
              <bitWidth>8</bitWidth>
            </field>
            <field>
              <name>LOCK</name>
              <bitOffset>31</bitOffset>
              <bitWidth>1</bitWidth>
            </field>
          </fields>
        </register>
        <register>
          <name>R.27</name>
          <addressOffset>0x6c</addressOffset>
          <size>0x20</size>
          <fields>
            <field>
              <name>PROCID</name>
              <bitOffset>0</bitOffset>
              <bitWidth>8</bitWidth>
            </field>
            <field>
              <name>COREID</name>
              <bitOffset>8</bitOffset>
              <bitWidth>8</bitWidth>
            </field>
            <field>
              <name>LOCK</name>
              <bitOffset>31</bitOffset>
              <bitWidth>1</bitWidth>
            </field>
          </fields>
        </register>
        <register>
          <name>R.28</name>
          <addressOffset>0x70</addressOffset>
          <size>0x20</size>
          <fields>
            <field>
              <name>PROCID</name>
              <bitOffset>0</bitOffset>
              <bitWidth>8</bitWidth>
            </field>
            <field>
              <name>COREID</name>
              <bitOffset>8</bitOffset>
              <bitWidth>8</bitWidth>
            </field>
            <field>
              <name>LOCK</name>
              <bitOffset>31</bitOffset>
              <bitWidth>1</bitWidth>
            </field>
          </fields>
        </register>
        <register>
          <name>R.29</name>
          <addressOffset>0x74</addressOffset>
          <size>0x20</size>
          <fields>
            <field>
              <name>PROCID</name>
              <bitOffset>0</bitOffset>
              <bitWidth>8</bitWidth>
            </field>
            <field>
              <name>COREID</name>
              <bitOffset>8</bitOffset>
              <bitWidth>8</bitWidth>
            </field>
            <field>
              <name>LOCK</name>
              <bitOffset>31</bitOffset>
              <bitWidth>1</bitWidth>
            </field>
          </fields>
        </register>
        <register>
          <name>R.30</name>
          <addressOffset>0x78</addressOffset>
          <size>0x20</size>
          <fields>
            <field>
              <name>PROCID</name>
              <bitOffset>0</bitOffset>
              <bitWidth>8</bitWidth>
            </field>
            <field>
              <name>COREID</name>
              <bitOffset>8</bitOffset>
              <bitWidth>8</bitWidth>
            </field>
            <field>
              <name>LOCK</name>
              <bitOffset>31</bitOffset>
              <bitWidth>1</bitWidth>
            </field>
          </fields>
        </register>
        <register>
          <name>R.31</name>
          <addressOffset>0x7c</addressOffset>
          <size>0x20</size>
          <fields>
            <field>
              <name>PROCID</name>
              <bitOffset>0</bitOffset>
              <bitWidth>8</bitWidth>
            </field>
            <field>
              <name>COREID</name>
              <bitOffset>8</bitOffset>
              <bitWidth>8</bitWidth>
            </field>
            <field>
              <name>LOCK</name>
              <bitOffset>31</bitOffset>
              <bitWidth>1</bitWidth>
            </field>
          </fields>
        </register>
        <register>
          <name>RLR.0</name>
          <addressOffset>0x80</addressOffset>
          <size>0x20</size>
          <fields>
            <field>
              <name>PROCID</name>
              <bitOffset>0</bitOffset>
              <bitWidth>8</bitWidth>
            </field>
            <field>
              <name>COREID</name>
              <bitOffset>8</bitOffset>
              <bitWidth>8</bitWidth>
            </field>
            <field>
              <name>LOCK</name>
              <bitOffset>31</bitOffset>
              <bitWidth>1</bitWidth>
            </field>
          </fields>
        </register>
        <register>
          <name>RLR.1</name>
          <addressOffset>0x84</addressOffset>
          <size>0x20</size>
          <fields>
            <field>
              <name>PROCID</name>
              <bitOffset>0</bitOffset>
              <bitWidth>8</bitWidth>
            </field>
            <field>
              <name>COREID</name>
              <bitOffset>8</bitOffset>
              <bitWidth>8</bitWidth>
            </field>
            <field>
              <name>LOCK</name>
              <bitOffset>31</bitOffset>
              <bitWidth>1</bitWidth>
            </field>
          </fields>
        </register>
        <register>
          <name>RLR.2</name>
          <addressOffset>0x88</addressOffset>
          <size>0x20</size>
          <fields>
            <field>
              <name>PROCID</name>
              <bitOffset>0</bitOffset>
              <bitWidth>8</bitWidth>
            </field>
            <field>
              <name>COREID</name>
              <bitOffset>8</bitOffset>
              <bitWidth>8</bitWidth>
            </field>
            <field>
              <name>LOCK</name>
              <bitOffset>31</bitOffset>
              <bitWidth>1</bitWidth>
            </field>
          </fields>
        </register>
        <register>
          <name>RLR.3</name>
          <addressOffset>0x8c</addressOffset>
          <size>0x20</size>
          <fields>
            <field>
              <name>PROCID</name>
              <bitOffset>0</bitOffset>
              <bitWidth>8</bitWidth>
            </field>
            <field>
              <name>COREID</name>
              <bitOffset>8</bitOffset>
              <bitWidth>8</bitWidth>
            </field>
            <field>
              <name>LOCK</name>
              <bitOffset>31</bitOffset>
              <bitWidth>1</bitWidth>
            </field>
          </fields>
        </register>
        <register>
          <name>RLR.4</name>
          <addressOffset>0x90</addressOffset>
          <size>0x20</size>
          <fields>
            <field>
              <name>PROCID</name>
              <bitOffset>0</bitOffset>
              <bitWidth>8</bitWidth>
            </field>
            <field>
              <name>COREID</name>
              <bitOffset>8</bitOffset>
              <bitWidth>8</bitWidth>
            </field>
            <field>
              <name>LOCK</name>
              <bitOffset>31</bitOffset>
              <bitWidth>1</bitWidth>
            </field>
          </fields>
        </register>
        <register>
          <name>RLR.5</name>
          <addressOffset>0x94</addressOffset>
          <size>0x20</size>
          <fields>
            <field>
              <name>PROCID</name>
              <bitOffset>0</bitOffset>
              <bitWidth>8</bitWidth>
            </field>
            <field>
              <name>COREID</name>
              <bitOffset>8</bitOffset>
              <bitWidth>8</bitWidth>
            </field>
            <field>
              <name>LOCK</name>
              <bitOffset>31</bitOffset>
              <bitWidth>1</bitWidth>
            </field>
          </fields>
        </register>
        <register>
          <name>RLR.6</name>
          <addressOffset>0x98</addressOffset>
          <size>0x20</size>
          <fields>
            <field>
              <name>PROCID</name>
              <bitOffset>0</bitOffset>
              <bitWidth>8</bitWidth>
            </field>
            <field>
              <name>COREID</name>
              <bitOffset>8</bitOffset>
              <bitWidth>8</bitWidth>
            </field>
            <field>
              <name>LOCK</name>
              <bitOffset>31</bitOffset>
              <bitWidth>1</bitWidth>
            </field>
          </fields>
        </register>
        <register>
          <name>RLR.7</name>
          <addressOffset>0x9c</addressOffset>
          <size>0x20</size>
          <fields>
            <field>
              <name>PROCID</name>
              <bitOffset>0</bitOffset>
              <bitWidth>8</bitWidth>
            </field>
            <field>
              <name>COREID</name>
              <bitOffset>8</bitOffset>
              <bitWidth>8</bitWidth>
            </field>
            <field>
              <name>LOCK</name>
              <bitOffset>31</bitOffset>
              <bitWidth>1</bitWidth>
            </field>
          </fields>
        </register>
        <register>
          <name>RLR.8</name>
          <addressOffset>0xa0</addressOffset>
          <size>0x20</size>
          <fields>
            <field>
              <name>PROCID</name>
              <bitOffset>0</bitOffset>
              <bitWidth>8</bitWidth>
            </field>
            <field>
              <name>COREID</name>
              <bitOffset>8</bitOffset>
              <bitWidth>8</bitWidth>
            </field>
            <field>
              <name>LOCK</name>
              <bitOffset>31</bitOffset>
              <bitWidth>1</bitWidth>
            </field>
          </fields>
        </register>
        <register>
          <name>RLR.9</name>
          <addressOffset>0xa4</addressOffset>
          <size>0x20</size>
          <fields>
            <field>
              <name>PROCID</name>
              <bitOffset>0</bitOffset>
              <bitWidth>8</bitWidth>
            </field>
            <field>
              <name>COREID</name>
              <bitOffset>8</bitOffset>
              <bitWidth>8</bitWidth>
            </field>
            <field>
              <name>LOCK</name>
              <bitOffset>31</bitOffset>
              <bitWidth>1</bitWidth>
            </field>
          </fields>
        </register>
        <register>
          <name>RLR.10</name>
          <addressOffset>0xa8</addressOffset>
          <size>0x20</size>
          <fields>
            <field>
              <name>PROCID</name>
              <bitOffset>0</bitOffset>
              <bitWidth>8</bitWidth>
            </field>
            <field>
              <name>COREID</name>
              <bitOffset>8</bitOffset>
              <bitWidth>8</bitWidth>
            </field>
            <field>
              <name>LOCK</name>
              <bitOffset>31</bitOffset>
              <bitWidth>1</bitWidth>
            </field>
          </fields>
        </register>
        <register>
          <name>RLR.11</name>
          <addressOffset>0xac</addressOffset>
          <size>0x20</size>
          <fields>
            <field>
              <name>PROCID</name>
              <bitOffset>0</bitOffset>
              <bitWidth>8</bitWidth>
            </field>
            <field>
              <name>COREID</name>
              <bitOffset>8</bitOffset>
              <bitWidth>8</bitWidth>
            </field>
            <field>
              <name>LOCK</name>
              <bitOffset>31</bitOffset>
              <bitWidth>1</bitWidth>
            </field>
          </fields>
        </register>
        <register>
          <name>RLR.12</name>
          <addressOffset>0xb0</addressOffset>
          <size>0x20</size>
          <fields>
            <field>
              <name>PROCID</name>
              <bitOffset>0</bitOffset>
              <bitWidth>8</bitWidth>
            </field>
            <field>
              <name>COREID</name>
              <bitOffset>8</bitOffset>
              <bitWidth>8</bitWidth>
            </field>
            <field>
              <name>LOCK</name>
              <bitOffset>31</bitOffset>
              <bitWidth>1</bitWidth>
            </field>
          </fields>
        </register>
        <register>
          <name>RLR.13</name>
          <addressOffset>0xb4</addressOffset>
          <size>0x20</size>
          <fields>
            <field>
              <name>PROCID</name>
              <bitOffset>0</bitOffset>
              <bitWidth>8</bitWidth>
            </field>
            <field>
              <name>COREID</name>
              <bitOffset>8</bitOffset>
              <bitWidth>8</bitWidth>
            </field>
            <field>
              <name>LOCK</name>
              <bitOffset>31</bitOffset>
              <bitWidth>1</bitWidth>
            </field>
          </fields>
        </register>
        <register>
          <name>RLR.14</name>
          <addressOffset>0xb8</addressOffset>
          <size>0x20</size>
          <fields>
            <field>
              <name>PROCID</name>
              <bitOffset>0</bitOffset>
              <bitWidth>8</bitWidth>
            </field>
            <field>
              <name>COREID</name>
              <bitOffset>8</bitOffset>
              <bitWidth>8</bitWidth>
            </field>
            <field>
              <name>LOCK</name>
              <bitOffset>31</bitOffset>
              <bitWidth>1</bitWidth>
            </field>
          </fields>
        </register>
        <register>
          <name>RLR.15</name>
          <addressOffset>0xbc</addressOffset>
          <size>0x20</size>
          <fields>
            <field>
              <name>PROCID</name>
              <bitOffset>0</bitOffset>
              <bitWidth>8</bitWidth>
            </field>
            <field>
              <name>COREID</name>
              <bitOffset>8</bitOffset>
              <bitWidth>8</bitWidth>
            </field>
            <field>
              <name>LOCK</name>
              <bitOffset>31</bitOffset>
              <bitWidth>1</bitWidth>
            </field>
          </fields>
        </register>
        <register>
          <name>RLR.16</name>
          <addressOffset>0xc0</addressOffset>
          <size>0x20</size>
          <fields>
            <field>
              <name>PROCID</name>
              <bitOffset>0</bitOffset>
              <bitWidth>8</bitWidth>
            </field>
            <field>
              <name>COREID</name>
              <bitOffset>8</bitOffset>
              <bitWidth>8</bitWidth>
            </field>
            <field>
              <name>LOCK</name>
              <bitOffset>31</bitOffset>
              <bitWidth>1</bitWidth>
            </field>
          </fields>
        </register>
        <register>
          <name>RLR.17</name>
          <addressOffset>0xc4</addressOffset>
          <size>0x20</size>
          <fields>
            <field>
              <name>PROCID</name>
              <bitOffset>0</bitOffset>
              <bitWidth>8</bitWidth>
            </field>
            <field>
              <name>COREID</name>
              <bitOffset>8</bitOffset>
              <bitWidth>8</bitWidth>
            </field>
            <field>
              <name>LOCK</name>
              <bitOffset>31</bitOffset>
              <bitWidth>1</bitWidth>
            </field>
          </fields>
        </register>
        <register>
          <name>RLR.18</name>
          <addressOffset>0xc8</addressOffset>
          <size>0x20</size>
          <fields>
            <field>
              <name>PROCID</name>
              <bitOffset>0</bitOffset>
              <bitWidth>8</bitWidth>
            </field>
            <field>
              <name>COREID</name>
              <bitOffset>8</bitOffset>
              <bitWidth>8</bitWidth>
            </field>
            <field>
              <name>LOCK</name>
              <bitOffset>31</bitOffset>
              <bitWidth>1</bitWidth>
            </field>
          </fields>
        </register>
        <register>
          <name>RLR.19</name>
          <addressOffset>0xcc</addressOffset>
          <size>0x20</size>
          <fields>
            <field>
              <name>PROCID</name>
              <bitOffset>0</bitOffset>
              <bitWidth>8</bitWidth>
            </field>
            <field>
              <name>COREID</name>
              <bitOffset>8</bitOffset>
              <bitWidth>8</bitWidth>
            </field>
            <field>
              <name>LOCK</name>
              <bitOffset>31</bitOffset>
              <bitWidth>1</bitWidth>
            </field>
          </fields>
        </register>
        <register>
          <name>RLR.20</name>
          <addressOffset>0xd0</addressOffset>
          <size>0x20</size>
          <fields>
            <field>
              <name>PROCID</name>
              <bitOffset>0</bitOffset>
              <bitWidth>8</bitWidth>
            </field>
            <field>
              <name>COREID</name>
              <bitOffset>8</bitOffset>
              <bitWidth>8</bitWidth>
            </field>
            <field>
              <name>LOCK</name>
              <bitOffset>31</bitOffset>
              <bitWidth>1</bitWidth>
            </field>
          </fields>
        </register>
        <register>
          <name>RLR.21</name>
          <addressOffset>0xd4</addressOffset>
          <size>0x20</size>
          <fields>
            <field>
              <name>PROCID</name>
              <bitOffset>0</bitOffset>
              <bitWidth>8</bitWidth>
            </field>
            <field>
              <name>COREID</name>
              <bitOffset>8</bitOffset>
              <bitWidth>8</bitWidth>
            </field>
            <field>
              <name>LOCK</name>
              <bitOffset>31</bitOffset>
              <bitWidth>1</bitWidth>
            </field>
          </fields>
        </register>
        <register>
          <name>RLR.22</name>
          <addressOffset>0xd8</addressOffset>
          <size>0x20</size>
          <fields>
            <field>
              <name>PROCID</name>
              <bitOffset>0</bitOffset>
              <bitWidth>8</bitWidth>
            </field>
            <field>
              <name>COREID</name>
              <bitOffset>8</bitOffset>
              <bitWidth>8</bitWidth>
            </field>
            <field>
              <name>LOCK</name>
              <bitOffset>31</bitOffset>
              <bitWidth>1</bitWidth>
            </field>
          </fields>
        </register>
        <register>
          <name>RLR.23</name>
          <addressOffset>0xdc</addressOffset>
          <size>0x20</size>
          <fields>
            <field>
              <name>PROCID</name>
              <bitOffset>0</bitOffset>
              <bitWidth>8</bitWidth>
            </field>
            <field>
              <name>COREID</name>
              <bitOffset>8</bitOffset>
              <bitWidth>8</bitWidth>
            </field>
            <field>
              <name>LOCK</name>
              <bitOffset>31</bitOffset>
              <bitWidth>1</bitWidth>
            </field>
          </fields>
        </register>
        <register>
          <name>RLR.24</name>
          <addressOffset>0xe0</addressOffset>
          <size>0x20</size>
          <fields>
            <field>
              <name>PROCID</name>
              <bitOffset>0</bitOffset>
              <bitWidth>8</bitWidth>
            </field>
            <field>
              <name>COREID</name>
              <bitOffset>8</bitOffset>
              <bitWidth>8</bitWidth>
            </field>
            <field>
              <name>LOCK</name>
              <bitOffset>31</bitOffset>
              <bitWidth>1</bitWidth>
            </field>
          </fields>
        </register>
        <register>
          <name>RLR.25</name>
          <addressOffset>0xe4</addressOffset>
          <size>0x20</size>
          <fields>
            <field>
              <name>PROCID</name>
              <bitOffset>0</bitOffset>
              <bitWidth>8</bitWidth>
            </field>
            <field>
              <name>COREID</name>
              <bitOffset>8</bitOffset>
              <bitWidth>8</bitWidth>
            </field>
            <field>
              <name>LOCK</name>
              <bitOffset>31</bitOffset>
              <bitWidth>1</bitWidth>
            </field>
          </fields>
        </register>
        <register>
          <name>RLR.26</name>
          <addressOffset>0xe8</addressOffset>
          <size>0x20</size>
          <fields>
            <field>
              <name>PROCID</name>
              <bitOffset>0</bitOffset>
              <bitWidth>8</bitWidth>
            </field>
            <field>
              <name>COREID</name>
              <bitOffset>8</bitOffset>
              <bitWidth>8</bitWidth>
            </field>
            <field>
              <name>LOCK</name>
              <bitOffset>31</bitOffset>
              <bitWidth>1</bitWidth>
            </field>
          </fields>
        </register>
        <register>
          <name>RLR.27</name>
          <addressOffset>0xec</addressOffset>
          <size>0x20</size>
          <fields>
            <field>
              <name>PROCID</name>
              <bitOffset>0</bitOffset>
              <bitWidth>8</bitWidth>
            </field>
            <field>
              <name>COREID</name>
              <bitOffset>8</bitOffset>
              <bitWidth>8</bitWidth>
            </field>
            <field>
              <name>LOCK</name>
              <bitOffset>31</bitOffset>
              <bitWidth>1</bitWidth>
            </field>
          </fields>
        </register>
        <register>
          <name>RLR.28</name>
          <addressOffset>0xf0</addressOffset>
          <size>0x20</size>
          <fields>
            <field>
              <name>PROCID</name>
              <bitOffset>0</bitOffset>
              <bitWidth>8</bitWidth>
            </field>
            <field>
              <name>COREID</name>
              <bitOffset>8</bitOffset>
              <bitWidth>8</bitWidth>
            </field>
            <field>
              <name>LOCK</name>
              <bitOffset>31</bitOffset>
              <bitWidth>1</bitWidth>
            </field>
          </fields>
        </register>
        <register>
          <name>RLR.29</name>
          <addressOffset>0xf4</addressOffset>
          <size>0x20</size>
          <fields>
            <field>
              <name>PROCID</name>
              <bitOffset>0</bitOffset>
              <bitWidth>8</bitWidth>
            </field>
            <field>
              <name>COREID</name>
              <bitOffset>8</bitOffset>
              <bitWidth>8</bitWidth>
            </field>
            <field>
              <name>LOCK</name>
              <bitOffset>31</bitOffset>
              <bitWidth>1</bitWidth>
            </field>
          </fields>
        </register>
        <register>
          <name>RLR.30</name>
          <addressOffset>0xf8</addressOffset>
          <size>0x20</size>
          <fields>
            <field>
              <name>PROCID</name>
              <bitOffset>0</bitOffset>
              <bitWidth>8</bitWidth>
            </field>
            <field>
              <name>COREID</name>
              <bitOffset>8</bitOffset>
              <bitWidth>8</bitWidth>
            </field>
            <field>
              <name>LOCK</name>
              <bitOffset>31</bitOffset>
              <bitWidth>1</bitWidth>
            </field>
          </fields>
        </register>
        <register>
          <name>RLR.31</name>
          <addressOffset>0xfc</addressOffset>
          <size>0x20</size>
          <fields>
            <field>
              <name>PROCID</name>
              <bitOffset>0</bitOffset>
              <bitWidth>8</bitWidth>
            </field>
            <field>
              <name>COREID</name>
              <bitOffset>8</bitOffset>
              <bitWidth>8</bitWidth>
            </field>
            <field>
              <name>LOCK</name>
              <bitOffset>31</bitOffset>
              <bitWidth>1</bitWidth>
            </field>
          </fields>
        </register>
        <register>
          <name>C1IER</name>
          <addressOffset>0x100</addressOffset>
          <size>0x20</size>
          <fields>
            <field>
              <name>ISE0</name>
              <bitOffset>0</bitOffset>
              <bitWidth>1</bitWidth>
            </field>
            <field>
              <name>ISE1</name>
              <bitOffset>1</bitOffset>
              <bitWidth>1</bitWidth>
            </field>
            <field>
              <name>ISE2</name>
              <bitOffset>2</bitOffset>
              <bitWidth>1</bitWidth>
            </field>
            <field>
              <name>ISE3</name>
              <bitOffset>3</bitOffset>
              <bitWidth>1</bitWidth>
            </field>
            <field>
              <name>ISE4</name>
              <bitOffset>4</bitOffset>
              <bitWidth>1</bitWidth>
            </field>
            <field>
              <name>ISE5</name>
              <bitOffset>5</bitOffset>
              <bitWidth>1</bitWidth>
            </field>
            <field>
              <name>ISE6</name>
              <bitOffset>6</bitOffset>
              <bitWidth>1</bitWidth>
            </field>
            <field>
              <name>ISE7</name>
              <bitOffset>7</bitOffset>
              <bitWidth>1</bitWidth>
            </field>
            <field>
              <name>ISE8</name>
              <bitOffset>8</bitOffset>
              <bitWidth>1</bitWidth>
            </field>
            <field>
              <name>ISE9</name>
              <bitOffset>9</bitOffset>
              <bitWidth>1</bitWidth>
            </field>
            <field>
              <name>ISE10</name>
              <bitOffset>10</bitOffset>
              <bitWidth>1</bitWidth>
            </field>
            <field>
              <name>ISE11</name>
              <bitOffset>11</bitOffset>
              <bitWidth>1</bitWidth>
            </field>
            <field>
              <name>ISE12</name>
              <bitOffset>12</bitOffset>
              <bitWidth>1</bitWidth>
            </field>
            <field>
              <name>ISE13</name>
              <bitOffset>13</bitOffset>
              <bitWidth>1</bitWidth>
            </field>
            <field>
              <name>ISE14</name>
              <bitOffset>14</bitOffset>
              <bitWidth>1</bitWidth>
            </field>
            <field>
              <name>ISE15</name>
              <bitOffset>15</bitOffset>
              <bitWidth>1</bitWidth>
            </field>
            <field>
              <name>ISE16</name>
              <bitOffset>16</bitOffset>
              <bitWidth>1</bitWidth>
            </field>
            <field>
              <name>ISE17</name>
              <bitOffset>17</bitOffset>
              <bitWidth>1</bitWidth>
            </field>
            <field>
              <name>ISE18</name>
              <bitOffset>18</bitOffset>
              <bitWidth>1</bitWidth>
            </field>
            <field>
              <name>ISE19</name>
              <bitOffset>19</bitOffset>
              <bitWidth>1</bitWidth>
            </field>
            <field>
              <name>ISE20</name>
              <bitOffset>20</bitOffset>
              <bitWidth>1</bitWidth>
            </field>
            <field>
              <name>ISE21</name>
              <bitOffset>21</bitOffset>
              <bitWidth>1</bitWidth>
            </field>
            <field>
              <name>ISE22</name>
              <bitOffset>22</bitOffset>
              <bitWidth>1</bitWidth>
            </field>
            <field>
              <name>ISE23</name>
              <bitOffset>23</bitOffset>
              <bitWidth>1</bitWidth>
            </field>
            <field>
              <name>ISE24</name>
              <bitOffset>24</bitOffset>
              <bitWidth>1</bitWidth>
            </field>
            <field>
              <name>ISE25</name>
              <bitOffset>25</bitOffset>
              <bitWidth>1</bitWidth>
            </field>
            <field>
              <name>ISE26</name>
              <bitOffset>26</bitOffset>
              <bitWidth>1</bitWidth>
            </field>
            <field>
              <name>ISE27</name>
              <bitOffset>27</bitOffset>
              <bitWidth>1</bitWidth>
            </field>
            <field>
              <name>ISE28</name>
              <bitOffset>28</bitOffset>
              <bitWidth>1</bitWidth>
            </field>
            <field>
              <name>ISE29</name>
              <bitOffset>29</bitOffset>
              <bitWidth>1</bitWidth>
            </field>
            <field>
              <name>ISE30</name>
              <bitOffset>30</bitOffset>
              <bitWidth>1</bitWidth>
            </field>
            <field>
              <name>ISE31</name>
              <bitOffset>31</bitOffset>
              <bitWidth>1</bitWidth>
            </field>
          </fields>
        </register>
        <register>
          <name>C1ICR</name>
          <addressOffset>0x104</addressOffset>
          <size>0x20</size>
          <fields>
            <field>
              <name>ISC0</name>
              <bitOffset>0</bitOffset>
              <bitWidth>1</bitWidth>
            </field>
            <field>
              <name>ISC1</name>
              <bitOffset>1</bitOffset>
              <bitWidth>1</bitWidth>
            </field>
            <field>
              <name>ISC2</name>
              <bitOffset>2</bitOffset>
              <bitWidth>1</bitWidth>
            </field>
            <field>
              <name>ISC3</name>
              <bitOffset>3</bitOffset>
              <bitWidth>1</bitWidth>
            </field>
            <field>
              <name>ISC4</name>
              <bitOffset>4</bitOffset>
              <bitWidth>1</bitWidth>
            </field>
            <field>
              <name>ISC5</name>
              <bitOffset>5</bitOffset>
              <bitWidth>1</bitWidth>
            </field>
            <field>
              <name>ISC6</name>
              <bitOffset>6</bitOffset>
              <bitWidth>1</bitWidth>
            </field>
            <field>
              <name>ISC7</name>
              <bitOffset>7</bitOffset>
              <bitWidth>1</bitWidth>
            </field>
            <field>
              <name>ISC8</name>
              <bitOffset>8</bitOffset>
              <bitWidth>1</bitWidth>
            </field>
            <field>
              <name>ISC9</name>
              <bitOffset>9</bitOffset>
              <bitWidth>1</bitWidth>
            </field>
            <field>
              <name>ISC10</name>
              <bitOffset>10</bitOffset>
              <bitWidth>1</bitWidth>
            </field>
            <field>
              <name>ISC11</name>
              <bitOffset>11</bitOffset>
              <bitWidth>1</bitWidth>
            </field>
            <field>
              <name>ISC12</name>
              <bitOffset>12</bitOffset>
              <bitWidth>1</bitWidth>
            </field>
            <field>
              <name>ISC13</name>
              <bitOffset>13</bitOffset>
              <bitWidth>1</bitWidth>
            </field>
            <field>
              <name>ISC14</name>
              <bitOffset>14</bitOffset>
              <bitWidth>1</bitWidth>
            </field>
            <field>
              <name>ISC15</name>
              <bitOffset>15</bitOffset>
              <bitWidth>1</bitWidth>
            </field>
            <field>
              <name>ISC16</name>
              <bitOffset>16</bitOffset>
              <bitWidth>1</bitWidth>
            </field>
            <field>
              <name>ISC17</name>
              <bitOffset>17</bitOffset>
              <bitWidth>1</bitWidth>
            </field>
            <field>
              <name>ISC18</name>
              <bitOffset>18</bitOffset>
              <bitWidth>1</bitWidth>
            </field>
            <field>
              <name>ISC19</name>
              <bitOffset>19</bitOffset>
              <bitWidth>1</bitWidth>
            </field>
            <field>
              <name>ISC20</name>
              <bitOffset>20</bitOffset>
              <bitWidth>1</bitWidth>
            </field>
            <field>
              <name>ISC21</name>
              <bitOffset>21</bitOffset>
              <bitWidth>1</bitWidth>
            </field>
            <field>
              <name>ISC22</name>
              <bitOffset>22</bitOffset>
              <bitWidth>1</bitWidth>
            </field>
            <field>
              <name>ISC23</name>
              <bitOffset>23</bitOffset>
              <bitWidth>1</bitWidth>
            </field>
            <field>
              <name>ISC24</name>
              <bitOffset>24</bitOffset>
              <bitWidth>1</bitWidth>
            </field>
            <field>
              <name>ISC25</name>
              <bitOffset>25</bitOffset>
              <bitWidth>1</bitWidth>
            </field>
            <field>
              <name>ISC26</name>
              <bitOffset>26</bitOffset>
              <bitWidth>1</bitWidth>
            </field>
            <field>
              <name>ISC27</name>
              <bitOffset>27</bitOffset>
              <bitWidth>1</bitWidth>
            </field>
            <field>
              <name>ISC28</name>
              <bitOffset>28</bitOffset>
              <bitWidth>1</bitWidth>
            </field>
            <field>
              <name>ISC29</name>
              <bitOffset>29</bitOffset>
              <bitWidth>1</bitWidth>
            </field>
            <field>
              <name>ISC30</name>
              <bitOffset>30</bitOffset>
              <bitWidth>1</bitWidth>
            </field>
            <field>
              <name>ISC31</name>
              <bitOffset>31</bitOffset>
              <bitWidth>1</bitWidth>
            </field>
          </fields>
        </register>
        <register>
          <name>C1ISR</name>
          <addressOffset>0x108</addressOffset>
          <size>0x20</size>
          <fields>
            <field>
              <name>ISF0</name>
              <bitOffset>0</bitOffset>
              <bitWidth>1</bitWidth>
            </field>
            <field>
              <name>ISF1</name>
              <bitOffset>1</bitOffset>
              <bitWidth>1</bitWidth>
            </field>
            <field>
              <name>ISF2</name>
              <bitOffset>2</bitOffset>
              <bitWidth>1</bitWidth>
            </field>
            <field>
              <name>ISF3</name>
              <bitOffset>3</bitOffset>
              <bitWidth>1</bitWidth>
            </field>
            <field>
              <name>ISF4</name>
              <bitOffset>4</bitOffset>
              <bitWidth>1</bitWidth>
            </field>
            <field>
              <name>ISF5</name>
              <bitOffset>5</bitOffset>
              <bitWidth>1</bitWidth>
            </field>
            <field>
              <name>ISF6</name>
              <bitOffset>6</bitOffset>
              <bitWidth>1</bitWidth>
            </field>
            <field>
              <name>ISF7</name>
              <bitOffset>7</bitOffset>
              <bitWidth>1</bitWidth>
            </field>
            <field>
              <name>ISF8</name>
              <bitOffset>8</bitOffset>
              <bitWidth>1</bitWidth>
            </field>
            <field>
              <name>ISF9</name>
              <bitOffset>9</bitOffset>
              <bitWidth>1</bitWidth>
            </field>
            <field>
              <name>ISF10</name>
              <bitOffset>10</bitOffset>
              <bitWidth>1</bitWidth>
            </field>
            <field>
              <name>ISF11</name>
              <bitOffset>11</bitOffset>
              <bitWidth>1</bitWidth>
            </field>
            <field>
              <name>ISF12</name>
              <bitOffset>12</bitOffset>
              <bitWidth>1</bitWidth>
            </field>
            <field>
              <name>ISF13</name>
              <bitOffset>13</bitOffset>
              <bitWidth>1</bitWidth>
            </field>
            <field>
              <name>ISF14</name>
              <bitOffset>14</bitOffset>
              <bitWidth>1</bitWidth>
            </field>
            <field>
              <name>ISF15</name>
              <bitOffset>15</bitOffset>
              <bitWidth>1</bitWidth>
            </field>
            <field>
              <name>ISF16</name>
              <bitOffset>16</bitOffset>
              <bitWidth>1</bitWidth>
            </field>
            <field>
              <name>ISF17</name>
              <bitOffset>17</bitOffset>
              <bitWidth>1</bitWidth>
            </field>
            <field>
              <name>ISF18</name>
              <bitOffset>18</bitOffset>
              <bitWidth>1</bitWidth>
            </field>
            <field>
              <name>ISF19</name>
              <bitOffset>19</bitOffset>
              <bitWidth>1</bitWidth>
            </field>
            <field>
              <name>ISF20</name>
              <bitOffset>20</bitOffset>
              <bitWidth>1</bitWidth>
            </field>
            <field>
              <name>ISF21</name>
              <bitOffset>21</bitOffset>
              <bitWidth>1</bitWidth>
            </field>
            <field>
              <name>ISF22</name>
              <bitOffset>22</bitOffset>
              <bitWidth>1</bitWidth>
            </field>
            <field>
              <name>ISF23</name>
              <bitOffset>23</bitOffset>
              <bitWidth>1</bitWidth>
            </field>
            <field>
              <name>ISF24</name>
              <bitOffset>24</bitOffset>
              <bitWidth>1</bitWidth>
            </field>
            <field>
              <name>ISF25</name>
              <bitOffset>25</bitOffset>
              <bitWidth>1</bitWidth>
            </field>
            <field>
              <name>ISF26</name>
              <bitOffset>26</bitOffset>
              <bitWidth>1</bitWidth>
            </field>
            <field>
              <name>ISF27</name>
              <bitOffset>27</bitOffset>
              <bitWidth>1</bitWidth>
            </field>
            <field>
              <name>ISF28</name>
              <bitOffset>28</bitOffset>
              <bitWidth>1</bitWidth>
            </field>
            <field>
              <name>ISF29</name>
              <bitOffset>29</bitOffset>
              <bitWidth>1</bitWidth>
            </field>
            <field>
              <name>ISF30</name>
              <bitOffset>30</bitOffset>
              <bitWidth>1</bitWidth>
            </field>
            <field>
              <name>ISF31</name>
              <bitOffset>31</bitOffset>
              <bitWidth>1</bitWidth>
            </field>
          </fields>
        </register>
        <register>
          <name>C1MISR</name>
          <addressOffset>0x10c</addressOffset>
          <size>0x20</size>
          <fields>
            <field>
              <name>MISF0</name>
              <bitOffset>0</bitOffset>
              <bitWidth>1</bitWidth>
            </field>
            <field>
              <name>MISF1</name>
              <bitOffset>1</bitOffset>
              <bitWidth>1</bitWidth>
            </field>
            <field>
              <name>MISF2</name>
              <bitOffset>2</bitOffset>
              <bitWidth>1</bitWidth>
            </field>
            <field>
              <name>MISF3</name>
              <bitOffset>3</bitOffset>
              <bitWidth>1</bitWidth>
            </field>
            <field>
              <name>MISF4</name>
              <bitOffset>4</bitOffset>
              <bitWidth>1</bitWidth>
            </field>
            <field>
              <name>MISF5</name>
              <bitOffset>5</bitOffset>
              <bitWidth>1</bitWidth>
            </field>
            <field>
              <name>MISF6</name>
              <bitOffset>6</bitOffset>
              <bitWidth>1</bitWidth>
            </field>
            <field>
              <name>MISF7</name>
              <bitOffset>7</bitOffset>
              <bitWidth>1</bitWidth>
            </field>
            <field>
              <name>MISF8</name>
              <bitOffset>8</bitOffset>
              <bitWidth>1</bitWidth>
            </field>
            <field>
              <name>MISF9</name>
              <bitOffset>9</bitOffset>
              <bitWidth>1</bitWidth>
            </field>
            <field>
              <name>MISF10</name>
              <bitOffset>10</bitOffset>
              <bitWidth>1</bitWidth>
            </field>
            <field>
              <name>MISF11</name>
              <bitOffset>11</bitOffset>
              <bitWidth>1</bitWidth>
            </field>
            <field>
              <name>MISF12</name>
              <bitOffset>12</bitOffset>
              <bitWidth>1</bitWidth>
            </field>
            <field>
              <name>MISF13</name>
              <bitOffset>13</bitOffset>
              <bitWidth>1</bitWidth>
            </field>
            <field>
              <name>MISF14</name>
              <bitOffset>14</bitOffset>
              <bitWidth>1</bitWidth>
            </field>
            <field>
              <name>MISF15</name>
              <bitOffset>15</bitOffset>
              <bitWidth>1</bitWidth>
            </field>
            <field>
              <name>MISF16</name>
              <bitOffset>16</bitOffset>
              <bitWidth>1</bitWidth>
            </field>
            <field>
              <name>MISF17</name>
              <bitOffset>17</bitOffset>
              <bitWidth>1</bitWidth>
            </field>
            <field>
              <name>MISF18</name>
              <bitOffset>18</bitOffset>
              <bitWidth>1</bitWidth>
            </field>
            <field>
              <name>MISF19</name>
              <bitOffset>19</bitOffset>
              <bitWidth>1</bitWidth>
            </field>
            <field>
              <name>MISF20</name>
              <bitOffset>20</bitOffset>
              <bitWidth>1</bitWidth>
            </field>
            <field>
              <name>MISF21</name>
              <bitOffset>21</bitOffset>
              <bitWidth>1</bitWidth>
            </field>
            <field>
              <name>MISF22</name>
              <bitOffset>22</bitOffset>
              <bitWidth>1</bitWidth>
            </field>
            <field>
              <name>MISF23</name>
              <bitOffset>23</bitOffset>
              <bitWidth>1</bitWidth>
            </field>
            <field>
              <name>MISF24</name>
              <bitOffset>24</bitOffset>
              <bitWidth>1</bitWidth>
            </field>
            <field>
              <name>MISF25</name>
              <bitOffset>25</bitOffset>
              <bitWidth>1</bitWidth>
            </field>
            <field>
              <name>MISF26</name>
              <bitOffset>26</bitOffset>
              <bitWidth>1</bitWidth>
            </field>
            <field>
              <name>MISF27</name>
              <bitOffset>27</bitOffset>
              <bitWidth>1</bitWidth>
            </field>
            <field>
              <name>MISF28</name>
              <bitOffset>28</bitOffset>
              <bitWidth>1</bitWidth>
            </field>
            <field>
              <name>MISF29</name>
              <bitOffset>29</bitOffset>
              <bitWidth>1</bitWidth>
            </field>
            <field>
              <name>MISF30</name>
              <bitOffset>30</bitOffset>
              <bitWidth>1</bitWidth>
            </field>
            <field>
              <name>MISF31</name>
              <bitOffset>31</bitOffset>
              <bitWidth>1</bitWidth>
            </field>
          </fields>
        </register>
        <register>
          <name>C2IER</name>
          <addressOffset>0x110</addressOffset>
          <size>0x20</size>
          <fields>
            <field>
              <name>ISE0</name>
              <bitOffset>0</bitOffset>
              <bitWidth>1</bitWidth>
            </field>
            <field>
              <name>ISE1</name>
              <bitOffset>1</bitOffset>
              <bitWidth>1</bitWidth>
            </field>
            <field>
              <name>ISE2</name>
              <bitOffset>2</bitOffset>
              <bitWidth>1</bitWidth>
            </field>
            <field>
              <name>ISE3</name>
              <bitOffset>3</bitOffset>
              <bitWidth>1</bitWidth>
            </field>
            <field>
              <name>ISE4</name>
              <bitOffset>4</bitOffset>
              <bitWidth>1</bitWidth>
            </field>
            <field>
              <name>ISE5</name>
              <bitOffset>5</bitOffset>
              <bitWidth>1</bitWidth>
            </field>
            <field>
              <name>ISE6</name>
              <bitOffset>6</bitOffset>
              <bitWidth>1</bitWidth>
            </field>
            <field>
              <name>ISE7</name>
              <bitOffset>7</bitOffset>
              <bitWidth>1</bitWidth>
            </field>
            <field>
              <name>ISE8</name>
              <bitOffset>8</bitOffset>
              <bitWidth>1</bitWidth>
            </field>
            <field>
              <name>ISE9</name>
              <bitOffset>9</bitOffset>
              <bitWidth>1</bitWidth>
            </field>
            <field>
              <name>ISE10</name>
              <bitOffset>10</bitOffset>
              <bitWidth>1</bitWidth>
            </field>
            <field>
              <name>ISE11</name>
              <bitOffset>11</bitOffset>
              <bitWidth>1</bitWidth>
            </field>
            <field>
              <name>ISE12</name>
              <bitOffset>12</bitOffset>
              <bitWidth>1</bitWidth>
            </field>
            <field>
              <name>ISE13</name>
              <bitOffset>13</bitOffset>
              <bitWidth>1</bitWidth>
            </field>
            <field>
              <name>ISE14</name>
              <bitOffset>14</bitOffset>
              <bitWidth>1</bitWidth>
            </field>
            <field>
              <name>ISE15</name>
              <bitOffset>15</bitOffset>
              <bitWidth>1</bitWidth>
            </field>
            <field>
              <name>ISE16</name>
              <bitOffset>16</bitOffset>
              <bitWidth>1</bitWidth>
            </field>
            <field>
              <name>ISE17</name>
              <bitOffset>17</bitOffset>
              <bitWidth>1</bitWidth>
            </field>
            <field>
              <name>ISE18</name>
              <bitOffset>18</bitOffset>
              <bitWidth>1</bitWidth>
            </field>
            <field>
              <name>ISE19</name>
              <bitOffset>19</bitOffset>
              <bitWidth>1</bitWidth>
            </field>
            <field>
              <name>ISE20</name>
              <bitOffset>20</bitOffset>
              <bitWidth>1</bitWidth>
            </field>
            <field>
              <name>ISE21</name>
              <bitOffset>21</bitOffset>
              <bitWidth>1</bitWidth>
            </field>
            <field>
              <name>ISE22</name>
              <bitOffset>22</bitOffset>
              <bitWidth>1</bitWidth>
            </field>
            <field>
              <name>ISE23</name>
              <bitOffset>23</bitOffset>
              <bitWidth>1</bitWidth>
            </field>
            <field>
              <name>ISE24</name>
              <bitOffset>24</bitOffset>
              <bitWidth>1</bitWidth>
            </field>
            <field>
              <name>ISE25</name>
              <bitOffset>25</bitOffset>
              <bitWidth>1</bitWidth>
            </field>
            <field>
              <name>ISE26</name>
              <bitOffset>26</bitOffset>
              <bitWidth>1</bitWidth>
            </field>
            <field>
              <name>ISE27</name>
              <bitOffset>27</bitOffset>
              <bitWidth>1</bitWidth>
            </field>
            <field>
              <name>ISE28</name>
              <bitOffset>28</bitOffset>
              <bitWidth>1</bitWidth>
            </field>
            <field>
              <name>ISE29</name>
              <bitOffset>29</bitOffset>
              <bitWidth>1</bitWidth>
            </field>
            <field>
              <name>ISE30</name>
              <bitOffset>30</bitOffset>
              <bitWidth>1</bitWidth>
            </field>
            <field>
              <name>ISE31</name>
              <bitOffset>31</bitOffset>
              <bitWidth>1</bitWidth>
            </field>
          </fields>
        </register>
        <register>
          <name>C2ICR</name>
          <addressOffset>0x114</addressOffset>
          <size>0x20</size>
          <fields>
            <field>
              <name>ISC0</name>
              <bitOffset>0</bitOffset>
              <bitWidth>1</bitWidth>
            </field>
            <field>
              <name>ISC1</name>
              <bitOffset>1</bitOffset>
              <bitWidth>1</bitWidth>
            </field>
            <field>
              <name>ISC2</name>
              <bitOffset>2</bitOffset>
              <bitWidth>1</bitWidth>
            </field>
            <field>
              <name>ISC3</name>
              <bitOffset>3</bitOffset>
              <bitWidth>1</bitWidth>
            </field>
            <field>
              <name>ISC4</name>
              <bitOffset>4</bitOffset>
              <bitWidth>1</bitWidth>
            </field>
            <field>
              <name>ISC5</name>
              <bitOffset>5</bitOffset>
              <bitWidth>1</bitWidth>
            </field>
            <field>
              <name>ISC6</name>
              <bitOffset>6</bitOffset>
              <bitWidth>1</bitWidth>
            </field>
            <field>
              <name>ISC7</name>
              <bitOffset>7</bitOffset>
              <bitWidth>1</bitWidth>
            </field>
            <field>
              <name>ISC8</name>
              <bitOffset>8</bitOffset>
              <bitWidth>1</bitWidth>
            </field>
            <field>
              <name>ISC9</name>
              <bitOffset>9</bitOffset>
              <bitWidth>1</bitWidth>
            </field>
            <field>
              <name>ISC10</name>
              <bitOffset>10</bitOffset>
              <bitWidth>1</bitWidth>
            </field>
            <field>
              <name>ISC11</name>
              <bitOffset>11</bitOffset>
              <bitWidth>1</bitWidth>
            </field>
            <field>
              <name>ISC12</name>
              <bitOffset>12</bitOffset>
              <bitWidth>1</bitWidth>
            </field>
            <field>
              <name>ISC13</name>
              <bitOffset>13</bitOffset>
              <bitWidth>1</bitWidth>
            </field>
            <field>
              <name>ISC14</name>
              <bitOffset>14</bitOffset>
              <bitWidth>1</bitWidth>
            </field>
            <field>
              <name>ISC15</name>
              <bitOffset>15</bitOffset>
              <bitWidth>1</bitWidth>
            </field>
            <field>
              <name>ISC16</name>
              <bitOffset>16</bitOffset>
              <bitWidth>1</bitWidth>
            </field>
            <field>
              <name>ISC17</name>
              <bitOffset>17</bitOffset>
              <bitWidth>1</bitWidth>
            </field>
            <field>
              <name>ISC18</name>
              <bitOffset>18</bitOffset>
              <bitWidth>1</bitWidth>
            </field>
            <field>
              <name>ISC19</name>
              <bitOffset>19</bitOffset>
              <bitWidth>1</bitWidth>
            </field>
            <field>
              <name>ISC20</name>
              <bitOffset>20</bitOffset>
              <bitWidth>1</bitWidth>
            </field>
            <field>
              <name>ISC21</name>
              <bitOffset>21</bitOffset>
              <bitWidth>1</bitWidth>
            </field>
            <field>
              <name>ISC22</name>
              <bitOffset>22</bitOffset>
              <bitWidth>1</bitWidth>
            </field>
            <field>
              <name>ISC23</name>
              <bitOffset>23</bitOffset>
              <bitWidth>1</bitWidth>
            </field>
            <field>
              <name>ISC24</name>
              <bitOffset>24</bitOffset>
              <bitWidth>1</bitWidth>
            </field>
            <field>
              <name>ISC25</name>
              <bitOffset>25</bitOffset>
              <bitWidth>1</bitWidth>
            </field>
            <field>
              <name>ISC26</name>
              <bitOffset>26</bitOffset>
              <bitWidth>1</bitWidth>
            </field>
            <field>
              <name>ISC27</name>
              <bitOffset>27</bitOffset>
              <bitWidth>1</bitWidth>
            </field>
            <field>
              <name>ISC28</name>
              <bitOffset>28</bitOffset>
              <bitWidth>1</bitWidth>
            </field>
            <field>
              <name>ISC29</name>
              <bitOffset>29</bitOffset>
              <bitWidth>1</bitWidth>
            </field>
            <field>
              <name>ISC30</name>
              <bitOffset>30</bitOffset>
              <bitWidth>1</bitWidth>
            </field>
            <field>
              <name>ISC31</name>
              <bitOffset>31</bitOffset>
              <bitWidth>1</bitWidth>
            </field>
          </fields>
        </register>
        <register>
          <name>C2ISR</name>
          <addressOffset>0x118</addressOffset>
          <size>0x20</size>
          <fields>
            <field>
              <name>ISF0</name>
              <bitOffset>0</bitOffset>
              <bitWidth>1</bitWidth>
            </field>
            <field>
              <name>ISF1</name>
              <bitOffset>1</bitOffset>
              <bitWidth>1</bitWidth>
            </field>
            <field>
              <name>ISF2</name>
              <bitOffset>2</bitOffset>
              <bitWidth>1</bitWidth>
            </field>
            <field>
              <name>ISF3</name>
              <bitOffset>3</bitOffset>
              <bitWidth>1</bitWidth>
            </field>
            <field>
              <name>ISF4</name>
              <bitOffset>4</bitOffset>
              <bitWidth>1</bitWidth>
            </field>
            <field>
              <name>ISF5</name>
              <bitOffset>5</bitOffset>
              <bitWidth>1</bitWidth>
            </field>
            <field>
              <name>ISF6</name>
              <bitOffset>6</bitOffset>
              <bitWidth>1</bitWidth>
            </field>
            <field>
              <name>ISF7</name>
              <bitOffset>7</bitOffset>
              <bitWidth>1</bitWidth>
            </field>
            <field>
              <name>ISF8</name>
              <bitOffset>8</bitOffset>
              <bitWidth>1</bitWidth>
            </field>
            <field>
              <name>ISF9</name>
              <bitOffset>9</bitOffset>
              <bitWidth>1</bitWidth>
            </field>
            <field>
              <name>ISF10</name>
              <bitOffset>10</bitOffset>
              <bitWidth>1</bitWidth>
            </field>
            <field>
              <name>ISF11</name>
              <bitOffset>11</bitOffset>
              <bitWidth>1</bitWidth>
            </field>
            <field>
              <name>ISF12</name>
              <bitOffset>12</bitOffset>
              <bitWidth>1</bitWidth>
            </field>
            <field>
              <name>ISF13</name>
              <bitOffset>13</bitOffset>
              <bitWidth>1</bitWidth>
            </field>
            <field>
              <name>ISF14</name>
              <bitOffset>14</bitOffset>
              <bitWidth>1</bitWidth>
            </field>
            <field>
              <name>ISF15</name>
              <bitOffset>15</bitOffset>
              <bitWidth>1</bitWidth>
            </field>
            <field>
              <name>ISF16</name>
              <bitOffset>16</bitOffset>
              <bitWidth>1</bitWidth>
            </field>
            <field>
              <name>ISF17</name>
              <bitOffset>17</bitOffset>
              <bitWidth>1</bitWidth>
            </field>
            <field>
              <name>ISF18</name>
              <bitOffset>18</bitOffset>
              <bitWidth>1</bitWidth>
            </field>
            <field>
              <name>ISF19</name>
              <bitOffset>19</bitOffset>
              <bitWidth>1</bitWidth>
            </field>
            <field>
              <name>ISF20</name>
              <bitOffset>20</bitOffset>
              <bitWidth>1</bitWidth>
            </field>
            <field>
              <name>ISF21</name>
              <bitOffset>21</bitOffset>
              <bitWidth>1</bitWidth>
            </field>
            <field>
              <name>ISF22</name>
              <bitOffset>22</bitOffset>
              <bitWidth>1</bitWidth>
            </field>
            <field>
              <name>ISF23</name>
              <bitOffset>23</bitOffset>
              <bitWidth>1</bitWidth>
            </field>
            <field>
              <name>ISF24</name>
              <bitOffset>24</bitOffset>
              <bitWidth>1</bitWidth>
            </field>
            <field>
              <name>ISF25</name>
              <bitOffset>25</bitOffset>
              <bitWidth>1</bitWidth>
            </field>
            <field>
              <name>ISF26</name>
              <bitOffset>26</bitOffset>
              <bitWidth>1</bitWidth>
            </field>
            <field>
              <name>ISF27</name>
              <bitOffset>27</bitOffset>
              <bitWidth>1</bitWidth>
            </field>
            <field>
              <name>ISF28</name>
              <bitOffset>28</bitOffset>
              <bitWidth>1</bitWidth>
            </field>
            <field>
              <name>ISF29</name>
              <bitOffset>29</bitOffset>
              <bitWidth>1</bitWidth>
            </field>
            <field>
              <name>ISF30</name>
              <bitOffset>30</bitOffset>
              <bitWidth>1</bitWidth>
            </field>
            <field>
              <name>ISF31</name>
              <bitOffset>31</bitOffset>
              <bitWidth>1</bitWidth>
            </field>
          </fields>
        </register>
        <register>
          <name>C2MISR</name>
          <addressOffset>0x11c</addressOffset>
          <size>0x20</size>
          <fields>
            <field>
              <name>MISF0</name>
              <bitOffset>0</bitOffset>
              <bitWidth>1</bitWidth>
            </field>
            <field>
              <name>MISF1</name>
              <bitOffset>1</bitOffset>
              <bitWidth>1</bitWidth>
            </field>
            <field>
              <name>MISF2</name>
              <bitOffset>2</bitOffset>
              <bitWidth>1</bitWidth>
            </field>
            <field>
              <name>MISF3</name>
              <bitOffset>3</bitOffset>
              <bitWidth>1</bitWidth>
            </field>
            <field>
              <name>MISF4</name>
              <bitOffset>4</bitOffset>
              <bitWidth>1</bitWidth>
            </field>
            <field>
              <name>MISF5</name>
              <bitOffset>5</bitOffset>
              <bitWidth>1</bitWidth>
            </field>
            <field>
              <name>MISF6</name>
              <bitOffset>6</bitOffset>
              <bitWidth>1</bitWidth>
            </field>
            <field>
              <name>MISF7</name>
              <bitOffset>7</bitOffset>
              <bitWidth>1</bitWidth>
            </field>
            <field>
              <name>MISF8</name>
              <bitOffset>8</bitOffset>
              <bitWidth>1</bitWidth>
            </field>
            <field>
              <name>MISF9</name>
              <bitOffset>9</bitOffset>
              <bitWidth>1</bitWidth>
            </field>
            <field>
              <name>MISF10</name>
              <bitOffset>10</bitOffset>
              <bitWidth>1</bitWidth>
            </field>
            <field>
              <name>MISF11</name>
              <bitOffset>11</bitOffset>
              <bitWidth>1</bitWidth>
            </field>
            <field>
              <name>MISF12</name>
              <bitOffset>12</bitOffset>
              <bitWidth>1</bitWidth>
            </field>
            <field>
              <name>MISF13</name>
              <bitOffset>13</bitOffset>
              <bitWidth>1</bitWidth>
            </field>
            <field>
              <name>MISF14</name>
              <bitOffset>14</bitOffset>
              <bitWidth>1</bitWidth>
            </field>
            <field>
              <name>MISF15</name>
              <bitOffset>15</bitOffset>
              <bitWidth>1</bitWidth>
            </field>
            <field>
              <name>MISF16</name>
              <bitOffset>16</bitOffset>
              <bitWidth>1</bitWidth>
            </field>
            <field>
              <name>MISF17</name>
              <bitOffset>17</bitOffset>
              <bitWidth>1</bitWidth>
            </field>
            <field>
              <name>MISF18</name>
              <bitOffset>18</bitOffset>
              <bitWidth>1</bitWidth>
            </field>
            <field>
              <name>MISF19</name>
              <bitOffset>19</bitOffset>
              <bitWidth>1</bitWidth>
            </field>
            <field>
              <name>MISF20</name>
              <bitOffset>20</bitOffset>
              <bitWidth>1</bitWidth>
            </field>
            <field>
              <name>MISF21</name>
              <bitOffset>21</bitOffset>
              <bitWidth>1</bitWidth>
            </field>
            <field>
              <name>MISF22</name>
              <bitOffset>22</bitOffset>
              <bitWidth>1</bitWidth>
            </field>
            <field>
              <name>MISF23</name>
              <bitOffset>23</bitOffset>
              <bitWidth>1</bitWidth>
            </field>
            <field>
              <name>MISF24</name>
              <bitOffset>24</bitOffset>
              <bitWidth>1</bitWidth>
            </field>
            <field>
              <name>MISF25</name>
              <bitOffset>25</bitOffset>
              <bitWidth>1</bitWidth>
            </field>
            <field>
              <name>MISF26</name>
              <bitOffset>26</bitOffset>
              <bitWidth>1</bitWidth>
            </field>
            <field>
              <name>MISF27</name>
              <bitOffset>27</bitOffset>
              <bitWidth>1</bitWidth>
            </field>
            <field>
              <name>MISF28</name>
              <bitOffset>28</bitOffset>
              <bitWidth>1</bitWidth>
            </field>
            <field>
              <name>MISF29</name>
              <bitOffset>29</bitOffset>
              <bitWidth>1</bitWidth>
            </field>
            <field>
              <name>MISF30</name>
              <bitOffset>30</bitOffset>
              <bitWidth>1</bitWidth>
            </field>
            <field>
              <name>MISF31</name>
              <bitOffset>31</bitOffset>
              <bitWidth>1</bitWidth>
            </field>
          </fields>
        </register>
        <register>
          <name>CR</name>
          <addressOffset>0x140</addressOffset>
          <size>0x20</size>
          <fields>
            <field>
              <name>COREID</name>
              <bitOffset>8</bitOffset>
              <bitWidth>8</bitWidth>
            </field>
            <field>
              <name>KEY</name>
              <bitOffset>16</bitOffset>
              <bitWidth>16</bitWidth>
            </field>
          </fields>
        </register>
        <register>
          <name>KEYR</name>
          <addressOffset>0x144</addressOffset>
          <size>0x20</size>
          <fields>
            <field>
              <name>KEY</name>
              <bitOffset>16</bitOffset>
              <bitWidth>16</bitWidth>
            </field>
          </fields>
        </register>
      </registers>
    </peripheral>
    <peripheral>
      <name>HSEM_COMMON</name>
      <baseAddress>0x58026510</baseAddress>
      <registers>
        <register>
          <name>IER</name>
          <addressOffset>0x0</addressOffset>
          <size>0x20</size>
        </register>
        <register>
          <name>ICR</name>
          <addressOffset>0x4</addressOffset>
          <size>0x20</size>
        </register>
        <register>
          <name>ISR</name>
          <addressOffset>0x8</addressOffset>
          <size>0x20</size>
        </register>
        <register>
          <name>MISR</name>
          <addressOffset>0xc</addressOffset>
          <size>0x20</size>
        </register>
      </registers>
    </peripheral>
    <peripheral>
      <name>RAMECC3</name>
      <baseAddress>0x58027000</baseAddress>
      <registers>
        <register>
          <name>IER</name>
          <addressOffset>0x0</addressOffset>
          <size>0x20</size>
          <fields>
            <field>
              <name>GIE</name>
              <bitOffset>0</bitOffset>
              <bitWidth>1</bitWidth>
            </field>
            <field>
              <name>GECCSEIE</name>
              <bitOffset>1</bitOffset>
              <bitWidth>1</bitWidth>
            </field>
            <field>
              <name>GECCDEIE</name>
              <bitOffset>2</bitOffset>
              <bitWidth>1</bitWidth>
            </field>
            <field>
              <name>GECCDEBWIE</name>
              <bitOffset>3</bitOffset>
              <bitWidth>1</bitWidth>
            </field>
          </fields>
        </register>
        <register>
          <name>CR1</name>
          <addressOffset>0x20</addressOffset>
          <size>0x20</size>
          <fields>
            <field>
              <name>ECCSEIE</name>
              <bitOffset>2</bitOffset>
              <bitWidth>1</bitWidth>
            </field>
            <field>
              <name>ECCDEIE</name>
              <bitOffset>3</bitOffset>
              <bitWidth>1</bitWidth>
            </field>
            <field>
              <name>ECCDEBWIE</name>
              <bitOffset>4</bitOffset>
              <bitWidth>1</bitWidth>
            </field>
            <field>
              <name>ECCELEN</name>
              <bitOffset>5</bitOffset>
              <bitWidth>1</bitWidth>
            </field>
          </fields>
        </register>
        <register>
          <name>CR1</name>
          <addressOffset>0x20</addressOffset>
          <size>0x20</size>
          <fields>
            <field>
              <name>ECCSEIE</name>
              <bitOffset>2</bitOffset>
              <bitWidth>1</bitWidth>
            </field>
            <field>
              <name>ECCDEIE</name>
              <bitOffset>3</bitOffset>
              <bitWidth>1</bitWidth>
            </field>
            <field>
              <name>ECCDEBWIE</name>
              <bitOffset>4</bitOffset>
              <bitWidth>1</bitWidth>
            </field>
            <field>
              <name>ECCELEN</name>
              <bitOffset>5</bitOffset>
              <bitWidth>1</bitWidth>
            </field>
          </fields>
        </register>
        <register>
          <name>CR1</name>
          <addressOffset>0x20</addressOffset>
          <size>0x20</size>
          <fields>
            <field>
              <name>ECCSEIE</name>
              <bitOffset>2</bitOffset>
              <bitWidth>1</bitWidth>
            </field>
            <field>
              <name>ECCDEIE</name>
              <bitOffset>3</bitOffset>
              <bitWidth>1</bitWidth>
            </field>
            <field>
              <name>ECCDEBWIE</name>
              <bitOffset>4</bitOffset>
              <bitWidth>1</bitWidth>
            </field>
            <field>
              <name>ECCELEN</name>
              <bitOffset>5</bitOffset>
              <bitWidth>1</bitWidth>
            </field>
          </fields>
        </register>
        <register>
          <name>SR1</name>
          <addressOffset>0x24</addressOffset>
          <size>0x20</size>
          <fields>
            <field>
              <name>SEDCF</name>
              <bitOffset>0</bitOffset>
              <bitWidth>1</bitWidth>
            </field>
            <field>
              <name>DEDF</name>
              <bitOffset>1</bitOffset>
              <bitWidth>1</bitWidth>
            </field>
            <field>
              <name>DEBWDF</name>
              <bitOffset>2</bitOffset>
              <bitWidth>1</bitWidth>
            </field>
          </fields>
        </register>
        <register>
          <name>SR1</name>
          <addressOffset>0x24</addressOffset>
          <size>0x20</size>
          <fields>
            <field>
              <name>SEDCF</name>
              <bitOffset>0</bitOffset>
              <bitWidth>1</bitWidth>
            </field>
            <field>
              <name>DEDF</name>
              <bitOffset>1</bitOffset>
              <bitWidth>1</bitWidth>
            </field>
            <field>
              <name>DEBWDF</name>
              <bitOffset>2</bitOffset>
              <bitWidth>1</bitWidth>
            </field>
          </fields>
        </register>
        <register>
          <name>SR1</name>
          <addressOffset>0x24</addressOffset>
          <size>0x20</size>
          <fields>
            <field>
              <name>SEDCF</name>
              <bitOffset>0</bitOffset>
              <bitWidth>1</bitWidth>
            </field>
            <field>
              <name>DEDF</name>
              <bitOffset>1</bitOffset>
              <bitWidth>1</bitWidth>
            </field>
            <field>
              <name>DEBWDF</name>
              <bitOffset>2</bitOffset>
              <bitWidth>1</bitWidth>
            </field>
          </fields>
        </register>
        <register>
          <name>FAR1</name>
          <addressOffset>0x28</addressOffset>
          <size>0x20</size>
          <fields>
            <field>
              <name>FDATAL</name>
              <bitOffset>0</bitOffset>
              <bitWidth>32</bitWidth>
            </field>
          </fields>
        </register>
        <register>
          <name>FAR1</name>
          <addressOffset>0x28</addressOffset>
          <size>0x20</size>
          <fields>
            <field>
              <name>FDATAL</name>
              <bitOffset>0</bitOffset>
              <bitWidth>32</bitWidth>
            </field>
          </fields>
        </register>
        <register>
          <name>FAR1</name>
          <addressOffset>0x28</addressOffset>
          <size>0x20</size>
          <fields>
            <field>
              <name>FDATAL</name>
              <bitOffset>0</bitOffset>
              <bitWidth>32</bitWidth>
            </field>
          </fields>
        </register>
        <register>
          <name>FDRL1</name>
          <addressOffset>0x2c</addressOffset>
          <size>0x20</size>
        </register>
        <register>
          <name>FDRL1</name>
          <addressOffset>0x2c</addressOffset>
          <size>0x20</size>
        </register>
        <register>
          <name>FDRL1</name>
          <addressOffset>0x2c</addressOffset>
          <size>0x20</size>
        </register>
        <register>
          <name>FDRH1</name>
          <addressOffset>0x30</addressOffset>
          <size>0x20</size>
        </register>
        <register>
          <name>FDRH1</name>
          <addressOffset>0x30</addressOffset>
          <size>0x20</size>
        </register>
        <register>
          <name>FDRH1</name>
          <addressOffset>0x30</addressOffset>
          <size>0x20</size>
        </register>
        <register>
          <name>FECR1</name>
          <addressOffset>0x34</addressOffset>
          <size>0x20</size>
          <fields>
            <field>
              <name>FEC</name>
              <bitOffset>0</bitOffset>
              <bitWidth>32</bitWidth>
            </field>
          </fields>
        </register>
        <register>
          <name>FECR1</name>
          <addressOffset>0x34</addressOffset>
          <size>0x20</size>
          <fields>
            <field>
              <name>FEC</name>
              <bitOffset>0</bitOffset>
              <bitWidth>32</bitWidth>
            </field>
          </fields>
        </register>
        <register>
          <name>FECR1</name>
          <addressOffset>0x34</addressOffset>
          <size>0x20</size>
          <fields>
            <field>
              <name>FEC</name>
              <bitOffset>0</bitOffset>
              <bitWidth>32</bitWidth>
            </field>
          </fields>
        </register>
        <register>
          <name>CR2</name>
          <addressOffset>0x40</addressOffset>
          <size>0x20</size>
          <fields>
            <field>
              <name>ECCSEIE</name>
              <bitOffset>2</bitOffset>
              <bitWidth>1</bitWidth>
            </field>
            <field>
              <name>ECCDEIE</name>
              <bitOffset>3</bitOffset>
              <bitWidth>1</bitWidth>
            </field>
            <field>
              <name>ECCDEBWIE</name>
              <bitOffset>4</bitOffset>
              <bitWidth>1</bitWidth>
            </field>
            <field>
              <name>ECCELEN</name>
              <bitOffset>5</bitOffset>
              <bitWidth>1</bitWidth>
            </field>
          </fields>
        </register>
        <register>
          <name>CR2</name>
          <addressOffset>0x40</addressOffset>
          <size>0x20</size>
          <fields>
            <field>
              <name>ECCSEIE</name>
              <bitOffset>2</bitOffset>
              <bitWidth>1</bitWidth>
            </field>
            <field>
              <name>ECCDEIE</name>
              <bitOffset>3</bitOffset>
              <bitWidth>1</bitWidth>
            </field>
            <field>
              <name>ECCDEBWIE</name>
              <bitOffset>4</bitOffset>
              <bitWidth>1</bitWidth>
            </field>
            <field>
              <name>ECCELEN</name>
              <bitOffset>5</bitOffset>
              <bitWidth>1</bitWidth>
            </field>
          </fields>
        </register>
        <register>
          <name>CR2</name>
          <addressOffset>0x40</addressOffset>
          <size>0x20</size>
          <fields>
            <field>
              <name>ECCSEIE</name>
              <bitOffset>2</bitOffset>
              <bitWidth>1</bitWidth>
            </field>
            <field>
              <name>ECCDEIE</name>
              <bitOffset>3</bitOffset>
              <bitWidth>1</bitWidth>
            </field>
            <field>
              <name>ECCDEBWIE</name>
              <bitOffset>4</bitOffset>
              <bitWidth>1</bitWidth>
            </field>
            <field>
              <name>ECCELEN</name>
              <bitOffset>5</bitOffset>
              <bitWidth>1</bitWidth>
            </field>
          </fields>
        </register>
        <register>
          <name>SR2</name>
          <addressOffset>0x44</addressOffset>
          <size>0x20</size>
          <fields>
            <field>
              <name>SEDCF</name>
              <bitOffset>0</bitOffset>
              <bitWidth>1</bitWidth>
            </field>
            <field>
              <name>DEDF</name>
              <bitOffset>1</bitOffset>
              <bitWidth>1</bitWidth>
            </field>
            <field>
              <name>DEBWDF</name>
              <bitOffset>2</bitOffset>
              <bitWidth>1</bitWidth>
            </field>
          </fields>
        </register>
        <register>
          <name>SR2</name>
          <addressOffset>0x44</addressOffset>
          <size>0x20</size>
          <fields>
            <field>
              <name>SEDCF</name>
              <bitOffset>0</bitOffset>
              <bitWidth>1</bitWidth>
            </field>
            <field>
              <name>DEDF</name>
              <bitOffset>1</bitOffset>
              <bitWidth>1</bitWidth>
            </field>
            <field>
              <name>DEBWDF</name>
              <bitOffset>2</bitOffset>
              <bitWidth>1</bitWidth>
            </field>
          </fields>
        </register>
        <register>
          <name>SR2</name>
          <addressOffset>0x44</addressOffset>
          <size>0x20</size>
          <fields>
            <field>
              <name>SEDCF</name>
              <bitOffset>0</bitOffset>
              <bitWidth>1</bitWidth>
            </field>
            <field>
              <name>DEDF</name>
              <bitOffset>1</bitOffset>
              <bitWidth>1</bitWidth>
            </field>
            <field>
              <name>DEBWDF</name>
              <bitOffset>2</bitOffset>
              <bitWidth>1</bitWidth>
            </field>
          </fields>
        </register>
        <register>
          <name>FAR2</name>
          <addressOffset>0x48</addressOffset>
          <size>0x20</size>
          <fields>
            <field>
              <name>FDATAL</name>
              <bitOffset>0</bitOffset>
              <bitWidth>32</bitWidth>
            </field>
          </fields>
        </register>
        <register>
          <name>FAR2</name>
          <addressOffset>0x48</addressOffset>
          <size>0x20</size>
          <fields>
            <field>
              <name>FDATAL</name>
              <bitOffset>0</bitOffset>
              <bitWidth>32</bitWidth>
            </field>
          </fields>
        </register>
        <register>
          <name>FAR2</name>
          <addressOffset>0x48</addressOffset>
          <size>0x20</size>
          <fields>
            <field>
              <name>FDATAL</name>
              <bitOffset>0</bitOffset>
              <bitWidth>32</bitWidth>
            </field>
          </fields>
        </register>
        <register>
          <name>FDRL2</name>
          <addressOffset>0x4c</addressOffset>
          <size>0x20</size>
        </register>
        <register>
          <name>FDRL2</name>
          <addressOffset>0x4c</addressOffset>
          <size>0x20</size>
        </register>
        <register>
          <name>FDRL2</name>
          <addressOffset>0x4c</addressOffset>
          <size>0x20</size>
        </register>
        <register>
          <name>FDRH2</name>
          <addressOffset>0x50</addressOffset>
          <size>0x20</size>
        </register>
        <register>
          <name>FDRH2</name>
          <addressOffset>0x50</addressOffset>
          <size>0x20</size>
        </register>
        <register>
          <name>FDRH2</name>
          <addressOffset>0x50</addressOffset>
          <size>0x20</size>
        </register>
        <register>
          <name>FECR2</name>
          <addressOffset>0x54</addressOffset>
          <size>0x20</size>
          <fields>
            <field>
              <name>FEC</name>
              <bitOffset>0</bitOffset>
              <bitWidth>32</bitWidth>
            </field>
          </fields>
        </register>
        <register>
          <name>FECR2</name>
          <addressOffset>0x54</addressOffset>
          <size>0x20</size>
          <fields>
            <field>
              <name>FEC</name>
              <bitOffset>0</bitOffset>
              <bitWidth>32</bitWidth>
            </field>
          </fields>
        </register>
        <register>
          <name>FECR2</name>
          <addressOffset>0x54</addressOffset>
          <size>0x20</size>
          <fields>
            <field>
              <name>FEC</name>
              <bitOffset>0</bitOffset>
              <bitWidth>32</bitWidth>
            </field>
          </fields>
        </register>
        <register>
          <name>CR3</name>
          <addressOffset>0x60</addressOffset>
          <size>0x20</size>
          <fields>
            <field>
              <name>ECCSEIE</name>
              <bitOffset>2</bitOffset>
              <bitWidth>1</bitWidth>
            </field>
            <field>
              <name>ECCDEIE</name>
              <bitOffset>3</bitOffset>
              <bitWidth>1</bitWidth>
            </field>
            <field>
              <name>ECCDEBWIE</name>
              <bitOffset>4</bitOffset>
              <bitWidth>1</bitWidth>
            </field>
            <field>
              <name>ECCELEN</name>
              <bitOffset>5</bitOffset>
              <bitWidth>1</bitWidth>
            </field>
          </fields>
        </register>
        <register>
          <name>CR3</name>
          <addressOffset>0x60</addressOffset>
          <size>0x20</size>
          <fields>
            <field>
              <name>ECCSEIE</name>
              <bitOffset>2</bitOffset>
              <bitWidth>1</bitWidth>
            </field>
            <field>
              <name>ECCDEIE</name>
              <bitOffset>3</bitOffset>
              <bitWidth>1</bitWidth>
            </field>
            <field>
              <name>ECCDEBWIE</name>
              <bitOffset>4</bitOffset>
              <bitWidth>1</bitWidth>
            </field>
            <field>
              <name>ECCELEN</name>
              <bitOffset>5</bitOffset>
              <bitWidth>1</bitWidth>
            </field>
          </fields>
        </register>
        <register>
          <name>SR3</name>
          <addressOffset>0x64</addressOffset>
          <size>0x20</size>
          <fields>
            <field>
              <name>SEDCF</name>
              <bitOffset>0</bitOffset>
              <bitWidth>1</bitWidth>
            </field>
            <field>
              <name>DEDF</name>
              <bitOffset>1</bitOffset>
              <bitWidth>1</bitWidth>
            </field>
            <field>
              <name>DEBWDF</name>
              <bitOffset>2</bitOffset>
              <bitWidth>1</bitWidth>
            </field>
          </fields>
        </register>
        <register>
          <name>SR3</name>
          <addressOffset>0x64</addressOffset>
          <size>0x20</size>
          <fields>
            <field>
              <name>SEDCF</name>
              <bitOffset>0</bitOffset>
              <bitWidth>1</bitWidth>
            </field>
            <field>
              <name>DEDF</name>
              <bitOffset>1</bitOffset>
              <bitWidth>1</bitWidth>
            </field>
            <field>
              <name>DEBWDF</name>
              <bitOffset>2</bitOffset>
              <bitWidth>1</bitWidth>
            </field>
          </fields>
        </register>
        <register>
          <name>FAR3</name>
          <addressOffset>0x68</addressOffset>
          <size>0x20</size>
          <fields>
            <field>
              <name>FDATAL</name>
              <bitOffset>0</bitOffset>
              <bitWidth>32</bitWidth>
            </field>
          </fields>
        </register>
        <register>
          <name>FAR3</name>
          <addressOffset>0x68</addressOffset>
          <size>0x20</size>
          <fields>
            <field>
              <name>FDATAL</name>
              <bitOffset>0</bitOffset>
              <bitWidth>32</bitWidth>
            </field>
          </fields>
        </register>
        <register>
          <name>FDRL3</name>
          <addressOffset>0x6c</addressOffset>
          <size>0x20</size>
        </register>
        <register>
          <name>FDRL3</name>
          <addressOffset>0x6c</addressOffset>
          <size>0x20</size>
        </register>
        <register>
          <name>FDRH3</name>
          <addressOffset>0x70</addressOffset>
          <size>0x20</size>
        </register>
        <register>
          <name>FDRH3</name>
          <addressOffset>0x70</addressOffset>
          <size>0x20</size>
        </register>
        <register>
          <name>FECR3</name>
          <addressOffset>0x74</addressOffset>
          <size>0x20</size>
          <fields>
            <field>
              <name>FEC</name>
              <bitOffset>0</bitOffset>
              <bitWidth>32</bitWidth>
            </field>
          </fields>
        </register>
        <register>
          <name>FECR3</name>
          <addressOffset>0x74</addressOffset>
          <size>0x20</size>
          <fields>
            <field>
              <name>FEC</name>
              <bitOffset>0</bitOffset>
              <bitWidth>32</bitWidth>
            </field>
          </fields>
        </register>
        <register>
          <name>CR4</name>
          <addressOffset>0x80</addressOffset>
          <size>0x20</size>
          <fields>
            <field>
              <name>ECCSEIE</name>
              <bitOffset>2</bitOffset>
              <bitWidth>1</bitWidth>
            </field>
            <field>
              <name>ECCDEIE</name>
              <bitOffset>3</bitOffset>
              <bitWidth>1</bitWidth>
            </field>
            <field>
              <name>ECCDEBWIE</name>
              <bitOffset>4</bitOffset>
              <bitWidth>1</bitWidth>
            </field>
            <field>
              <name>ECCELEN</name>
              <bitOffset>5</bitOffset>
              <bitWidth>1</bitWidth>
            </field>
          </fields>
        </register>
        <register>
          <name>CR4</name>
          <addressOffset>0x80</addressOffset>
          <size>0x20</size>
          <fields>
            <field>
              <name>ECCSEIE</name>
              <bitOffset>2</bitOffset>
              <bitWidth>1</bitWidth>
            </field>
            <field>
              <name>ECCDEIE</name>
              <bitOffset>3</bitOffset>
              <bitWidth>1</bitWidth>
            </field>
            <field>
              <name>ECCDEBWIE</name>
              <bitOffset>4</bitOffset>
              <bitWidth>1</bitWidth>
            </field>
            <field>
              <name>ECCELEN</name>
              <bitOffset>5</bitOffset>
              <bitWidth>1</bitWidth>
            </field>
          </fields>
        </register>
        <register>
          <name>SR4</name>
          <addressOffset>0x84</addressOffset>
          <size>0x20</size>
          <fields>
            <field>
              <name>SEDCF</name>
              <bitOffset>0</bitOffset>
              <bitWidth>1</bitWidth>
            </field>
            <field>
              <name>DEDF</name>
              <bitOffset>1</bitOffset>
              <bitWidth>1</bitWidth>
            </field>
            <field>
              <name>DEBWDF</name>
              <bitOffset>2</bitOffset>
              <bitWidth>1</bitWidth>
            </field>
          </fields>
        </register>
        <register>
          <name>SR4</name>
          <addressOffset>0x84</addressOffset>
          <size>0x20</size>
          <fields>
            <field>
              <name>SEDCF</name>
              <bitOffset>0</bitOffset>
              <bitWidth>1</bitWidth>
            </field>
            <field>
              <name>DEDF</name>
              <bitOffset>1</bitOffset>
              <bitWidth>1</bitWidth>
            </field>
            <field>
              <name>DEBWDF</name>
              <bitOffset>2</bitOffset>
              <bitWidth>1</bitWidth>
            </field>
          </fields>
        </register>
        <register>
          <name>FAR4</name>
          <addressOffset>0x88</addressOffset>
          <size>0x20</size>
          <fields>
            <field>
              <name>FDATAL</name>
              <bitOffset>0</bitOffset>
              <bitWidth>32</bitWidth>
            </field>
          </fields>
        </register>
        <register>
          <name>FAR4</name>
          <addressOffset>0x88</addressOffset>
          <size>0x20</size>
          <fields>
            <field>
              <name>FDATAL</name>
              <bitOffset>0</bitOffset>
              <bitWidth>32</bitWidth>
            </field>
          </fields>
        </register>
        <register>
          <name>FDRL4</name>
          <addressOffset>0x8c</addressOffset>
          <size>0x20</size>
        </register>
        <register>
          <name>FDRL4</name>
          <addressOffset>0x8c</addressOffset>
          <size>0x20</size>
        </register>
        <register>
          <name>FDRH4</name>
          <addressOffset>0x90</addressOffset>
          <size>0x20</size>
        </register>
        <register>
          <name>FDRH4</name>
          <addressOffset>0x90</addressOffset>
          <size>0x20</size>
        </register>
        <register>
          <name>FECR4</name>
          <addressOffset>0x94</addressOffset>
          <size>0x20</size>
          <fields>
            <field>
              <name>FEC</name>
              <bitOffset>0</bitOffset>
              <bitWidth>32</bitWidth>
            </field>
          </fields>
        </register>
        <register>
          <name>FECR4</name>
          <addressOffset>0x94</addressOffset>
          <size>0x20</size>
          <fields>
            <field>
              <name>FEC</name>
              <bitOffset>0</bitOffset>
              <bitWidth>32</bitWidth>
            </field>
          </fields>
        </register>
        <register>
          <name>CR5</name>
          <addressOffset>0xa0</addressOffset>
          <size>0x20</size>
          <fields>
            <field>
              <name>ECCSEIE</name>
              <bitOffset>2</bitOffset>
              <bitWidth>1</bitWidth>
            </field>
            <field>
              <name>ECCDEIE</name>
              <bitOffset>3</bitOffset>
              <bitWidth>1</bitWidth>
            </field>
            <field>
              <name>ECCDEBWIE</name>
              <bitOffset>4</bitOffset>
              <bitWidth>1</bitWidth>
            </field>
            <field>
              <name>ECCELEN</name>
              <bitOffset>5</bitOffset>
              <bitWidth>1</bitWidth>
            </field>
          </fields>
        </register>
        <register>
          <name>CR5</name>
          <addressOffset>0xa0</addressOffset>
          <size>0x20</size>
          <fields>
            <field>
              <name>ECCSEIE</name>
              <bitOffset>2</bitOffset>
              <bitWidth>1</bitWidth>
            </field>
            <field>
              <name>ECCDEIE</name>
              <bitOffset>3</bitOffset>
              <bitWidth>1</bitWidth>
            </field>
            <field>
              <name>ECCDEBWIE</name>
              <bitOffset>4</bitOffset>
              <bitWidth>1</bitWidth>
            </field>
            <field>
              <name>ECCELEN</name>
              <bitOffset>5</bitOffset>
              <bitWidth>1</bitWidth>
            </field>
          </fields>
        </register>
        <register>
          <name>SR5</name>
          <addressOffset>0xa4</addressOffset>
          <size>0x20</size>
          <fields>
            <field>
              <name>SEDCF</name>
              <bitOffset>0</bitOffset>
              <bitWidth>1</bitWidth>
            </field>
            <field>
              <name>DEDF</name>
              <bitOffset>1</bitOffset>
              <bitWidth>1</bitWidth>
            </field>
            <field>
              <name>DEBWDF</name>
              <bitOffset>2</bitOffset>
              <bitWidth>1</bitWidth>
            </field>
          </fields>
        </register>
        <register>
          <name>SR5</name>
          <addressOffset>0xa4</addressOffset>
          <size>0x20</size>
          <fields>
            <field>
              <name>SEDCF</name>
              <bitOffset>0</bitOffset>
              <bitWidth>1</bitWidth>
            </field>
            <field>
              <name>DEDF</name>
              <bitOffset>1</bitOffset>
              <bitWidth>1</bitWidth>
            </field>
            <field>
              <name>DEBWDF</name>
              <bitOffset>2</bitOffset>
              <bitWidth>1</bitWidth>
            </field>
          </fields>
        </register>
        <register>
          <name>FAR5</name>
          <addressOffset>0xa8</addressOffset>
          <size>0x20</size>
          <fields>
            <field>
              <name>FDATAL</name>
              <bitOffset>0</bitOffset>
              <bitWidth>32</bitWidth>
            </field>
          </fields>
        </register>
        <register>
          <name>FAR5</name>
          <addressOffset>0xa8</addressOffset>
          <size>0x20</size>
          <fields>
            <field>
              <name>FDATAL</name>
              <bitOffset>0</bitOffset>
              <bitWidth>32</bitWidth>
            </field>
          </fields>
        </register>
        <register>
          <name>FDRL5</name>
          <addressOffset>0xac</addressOffset>
          <size>0x20</size>
        </register>
        <register>
          <name>FDRL5</name>
          <addressOffset>0xac</addressOffset>
          <size>0x20</size>
        </register>
        <register>
          <name>FDRH5</name>
          <addressOffset>0xb0</addressOffset>
          <size>0x20</size>
        </register>
        <register>
          <name>FDRH5</name>
          <addressOffset>0xb0</addressOffset>
          <size>0x20</size>
        </register>
        <register>
          <name>FECR5</name>
          <addressOffset>0xb4</addressOffset>
          <size>0x20</size>
          <fields>
            <field>
              <name>FEC</name>
              <bitOffset>0</bitOffset>
              <bitWidth>32</bitWidth>
            </field>
          </fields>
        </register>
        <register>
          <name>FECR5</name>
          <addressOffset>0xb4</addressOffset>
          <size>0x20</size>
          <fields>
            <field>
              <name>FEC</name>
              <bitOffset>0</bitOffset>
              <bitWidth>32</bitWidth>
            </field>
          </fields>
        </register>
      </registers>
    </peripheral>
    <peripheral>
      <name>DBGMCU</name>
      <baseAddress>0x5c001000</baseAddress>
      <registers>
        <register>
          <name>IDCODE</name>
          <addressOffset>0x0</addressOffset>
          <size>0x20</size>
          <fields>
            <field>
              <name>DEV_ID</name>
              <bitOffset>0</bitOffset>
              <bitWidth>12</bitWidth>
            </field>
            <field>
              <name>REV_ID</name>
              <bitOffset>16</bitOffset>
              <bitWidth>16</bitWidth>
            </field>
          </fields>
        </register>
        <register>
          <name>CR</name>
          <addressOffset>0x4</addressOffset>
          <size>0x20</size>
          <fields>
            <field>
              <name>DBG_SLEEPD1</name>
              <bitOffset>0</bitOffset>
              <bitWidth>1</bitWidth>
            </field>
            <field>
              <name>DBG_STOPD1</name>
              <bitOffset>1</bitOffset>
              <bitWidth>1</bitWidth>
            </field>
            <field>
              <name>DBG_STANDBYD1</name>
              <bitOffset>2</bitOffset>
              <bitWidth>1</bitWidth>
            </field>
            <field>
              <name>DBG_SLEEPD2</name>
              <bitOffset>3</bitOffset>
              <bitWidth>1</bitWidth>
            </field>
            <field>
              <name>DBG_STOPD2</name>
              <bitOffset>4</bitOffset>
              <bitWidth>1</bitWidth>
            </field>
            <field>
              <name>DBG_STANDBYD2</name>
              <bitOffset>5</bitOffset>
              <bitWidth>1</bitWidth>
            </field>
            <field>
              <name>DBG_TRACECKEN</name>
              <bitOffset>20</bitOffset>
              <bitWidth>1</bitWidth>
            </field>
            <field>
              <name>DBG_CKD1EN</name>
              <bitOffset>21</bitOffset>
              <bitWidth>1</bitWidth>
            </field>
            <field>
              <name>DBG_CKD3EN</name>
              <bitOffset>22</bitOffset>
              <bitWidth>1</bitWidth>
            </field>
            <field>
              <name>DBG_TRGOEN</name>
              <bitOffset>28</bitOffset>
              <bitWidth>1</bitWidth>
            </field>
          </fields>
        </register>
        <register>
          <name>APB3FZ1</name>
          <addressOffset>0x34</addressOffset>
          <size>0x20</size>
          <fields>
            <field>
              <name>DBG_WWDG1</name>
              <bitOffset>6</bitOffset>
              <bitWidth>1</bitWidth>
            </field>
          </fields>
        </register>
        <register>
          <name>APB3FZ2</name>
          <addressOffset>0x38</addressOffset>
          <size>0x20</size>
          <fields>
            <field>
              <name>DBG_WWDG1</name>
              <bitOffset>6</bitOffset>
              <bitWidth>1</bitWidth>
            </field>
          </fields>
        </register>
        <register>
          <name>APB1LFZ1</name>
          <addressOffset>0x3c</addressOffset>
          <size>0x20</size>
          <fields>
            <field>
              <name>DBG_TIM2</name>
              <bitOffset>0</bitOffset>
              <bitWidth>1</bitWidth>
            </field>
            <field>
              <name>DBG_TIM3</name>
              <bitOffset>1</bitOffset>
              <bitWidth>1</bitWidth>
            </field>
            <field>
              <name>DBG_TIM4</name>
              <bitOffset>2</bitOffset>
              <bitWidth>1</bitWidth>
            </field>
            <field>
              <name>DBG_TIM5</name>
              <bitOffset>3</bitOffset>
              <bitWidth>1</bitWidth>
            </field>
            <field>
              <name>DBG_TIM6</name>
              <bitOffset>4</bitOffset>
              <bitWidth>1</bitWidth>
            </field>
            <field>
              <name>DBG_TIM7</name>
              <bitOffset>5</bitOffset>
              <bitWidth>1</bitWidth>
            </field>
            <field>
              <name>DBG_TIM12</name>
              <bitOffset>6</bitOffset>
              <bitWidth>1</bitWidth>
            </field>
            <field>
              <name>DBG_TIM13</name>
              <bitOffset>7</bitOffset>
              <bitWidth>1</bitWidth>
            </field>
            <field>
              <name>DBG_TIM14</name>
              <bitOffset>8</bitOffset>
              <bitWidth>1</bitWidth>
            </field>
            <field>
              <name>DBG_LPTIM1</name>
              <bitOffset>9</bitOffset>
              <bitWidth>1</bitWidth>
            </field>
            <field>
              <name>DBG_WWDG2</name>
              <bitOffset>11</bitOffset>
              <bitWidth>1</bitWidth>
            </field>
            <field>
              <name>DBG_I2C1</name>
              <bitOffset>21</bitOffset>
              <bitWidth>1</bitWidth>
            </field>
            <field>
              <name>DBG_I2C2</name>
              <bitOffset>22</bitOffset>
              <bitWidth>1</bitWidth>
            </field>
            <field>
              <name>DBG_I2C3</name>
              <bitOffset>23</bitOffset>
              <bitWidth>1</bitWidth>
            </field>
          </fields>
        </register>
        <register>
          <name>APB1LFZ2</name>
          <addressOffset>0x40</addressOffset>
          <size>0x20</size>
          <fields>
            <field>
              <name>DBG_TIM2</name>
              <bitOffset>0</bitOffset>
              <bitWidth>1</bitWidth>
            </field>
            <field>
              <name>DBG_TIM3</name>
              <bitOffset>1</bitOffset>
              <bitWidth>1</bitWidth>
            </field>
            <field>
              <name>DBG_TIM4</name>
              <bitOffset>2</bitOffset>
              <bitWidth>1</bitWidth>
            </field>
            <field>
              <name>DBG_TIM5</name>
              <bitOffset>3</bitOffset>
              <bitWidth>1</bitWidth>
            </field>
            <field>
              <name>DBG_TIM6</name>
              <bitOffset>4</bitOffset>
              <bitWidth>1</bitWidth>
            </field>
            <field>
              <name>DBG_TIM7</name>
              <bitOffset>5</bitOffset>
              <bitWidth>1</bitWidth>
            </field>
            <field>
              <name>DBG_TIM12</name>
              <bitOffset>6</bitOffset>
              <bitWidth>1</bitWidth>
            </field>
            <field>
              <name>DBG_TIM13</name>
              <bitOffset>7</bitOffset>
              <bitWidth>1</bitWidth>
            </field>
            <field>
              <name>DBG_TIM14</name>
              <bitOffset>8</bitOffset>
              <bitWidth>1</bitWidth>
            </field>
            <field>
              <name>DBG_LPTIM1</name>
              <bitOffset>9</bitOffset>
              <bitWidth>1</bitWidth>
            </field>
            <field>
              <name>DBG_WWDG2</name>
              <bitOffset>11</bitOffset>
              <bitWidth>1</bitWidth>
            </field>
            <field>
              <name>DBG_I2C1</name>
              <bitOffset>21</bitOffset>
              <bitWidth>1</bitWidth>
            </field>
            <field>
              <name>DBG_I2C2</name>
              <bitOffset>22</bitOffset>
              <bitWidth>1</bitWidth>
            </field>
            <field>
              <name>DBG_I2C3</name>
              <bitOffset>23</bitOffset>
              <bitWidth>1</bitWidth>
            </field>
          </fields>
        </register>
        <register>
          <name>APB1HFZ1</name>
          <addressOffset>0x44</addressOffset>
          <size>0x20</size>
          <fields>
            <field>
              <name>DBG_FDCAN</name>
              <bitOffset>8</bitOffset>
              <bitWidth>1</bitWidth>
            </field>
          </fields>
        </register>
        <register>
          <name>APB1HFZ2</name>
          <addressOffset>0x48</addressOffset>
          <size>0x20</size>
          <fields>
            <field>
              <name>DBG_FDCAN</name>
              <bitOffset>8</bitOffset>
              <bitWidth>1</bitWidth>
            </field>
          </fields>
        </register>
        <register>
          <name>APB2FZ1</name>
          <addressOffset>0x4c</addressOffset>
          <size>0x20</size>
          <fields>
            <field>
              <name>DBG_TIM1</name>
              <bitOffset>0</bitOffset>
              <bitWidth>1</bitWidth>
            </field>
            <field>
              <name>DBG_TIM8</name>
              <bitOffset>1</bitOffset>
              <bitWidth>1</bitWidth>
            </field>
            <field>
              <name>DBG_TIM15</name>
              <bitOffset>16</bitOffset>
              <bitWidth>1</bitWidth>
            </field>
            <field>
              <name>DBG_TIM16</name>
              <bitOffset>17</bitOffset>
              <bitWidth>1</bitWidth>
            </field>
            <field>
              <name>DBG_TIM17</name>
              <bitOffset>18</bitOffset>
              <bitWidth>1</bitWidth>
            </field>
            <field>
              <name>DBG_HRTIM</name>
              <bitOffset>29</bitOffset>
              <bitWidth>1</bitWidth>
            </field>
          </fields>
        </register>
        <register>
          <name>APB2FZ2</name>
          <addressOffset>0x50</addressOffset>
          <size>0x20</size>
          <fields>
            <field>
              <name>DBG_TIM1</name>
              <bitOffset>0</bitOffset>
              <bitWidth>1</bitWidth>
            </field>
            <field>
              <name>DBG_TIM8</name>
              <bitOffset>1</bitOffset>
              <bitWidth>1</bitWidth>
            </field>
            <field>
              <name>DBG_TIM15</name>
              <bitOffset>16</bitOffset>
              <bitWidth>1</bitWidth>
            </field>
            <field>
              <name>DBG_TIM16</name>
              <bitOffset>17</bitOffset>
              <bitWidth>1</bitWidth>
            </field>
            <field>
              <name>DBG_TIM17</name>
              <bitOffset>18</bitOffset>
              <bitWidth>1</bitWidth>
            </field>
            <field>
              <name>DBG_HRTIM</name>
              <bitOffset>29</bitOffset>
              <bitWidth>1</bitWidth>
            </field>
          </fields>
        </register>
        <register>
          <name>APB4FZ1</name>
          <addressOffset>0x54</addressOffset>
          <size>0x20</size>
          <fields>
            <field>
              <name>DBG_I2C4</name>
              <bitOffset>7</bitOffset>
              <bitWidth>1</bitWidth>
            </field>
            <field>
              <name>DBG_LPTIM2</name>
              <bitOffset>9</bitOffset>
              <bitWidth>1</bitWidth>
            </field>
            <field>
              <name>DBG_LPTIM3</name>
              <bitOffset>10</bitOffset>
              <bitWidth>1</bitWidth>
            </field>
            <field>
              <name>DBG_LPTIM4</name>
              <bitOffset>11</bitOffset>
              <bitWidth>1</bitWidth>
            </field>
            <field>
              <name>DBG_LPTIM5</name>
              <bitOffset>12</bitOffset>
              <bitWidth>1</bitWidth>
            </field>
            <field>
              <name>DBG_RTC</name>
              <bitOffset>16</bitOffset>
              <bitWidth>1</bitWidth>
            </field>
            <field>
              <name>DBG_IWDG1</name>
              <bitOffset>18</bitOffset>
              <bitWidth>1</bitWidth>
            </field>
            <field>
              <name>DBG_IWDG2</name>
              <bitOffset>19</bitOffset>
              <bitWidth>1</bitWidth>
            </field>
          </fields>
        </register>
        <register>
          <name>APB4FZ2</name>
          <addressOffset>0x58</addressOffset>
          <size>0x20</size>
          <fields>
            <field>
              <name>DBG_I2C4</name>
              <bitOffset>7</bitOffset>
              <bitWidth>1</bitWidth>
            </field>
            <field>
              <name>DBG_LPTIM2</name>
              <bitOffset>9</bitOffset>
              <bitWidth>1</bitWidth>
            </field>
            <field>
              <name>DBG_LPTIM3</name>
              <bitOffset>10</bitOffset>
              <bitWidth>1</bitWidth>
            </field>
            <field>
              <name>DBG_LPTIM4</name>
              <bitOffset>11</bitOffset>
              <bitWidth>1</bitWidth>
            </field>
            <field>
              <name>DBG_LPTIM5</name>
              <bitOffset>12</bitOffset>
              <bitWidth>1</bitWidth>
            </field>
            <field>
              <name>DBG_RTC</name>
              <bitOffset>16</bitOffset>
              <bitWidth>1</bitWidth>
            </field>
            <field>
              <name>DBG_IWDG1</name>
              <bitOffset>18</bitOffset>
              <bitWidth>1</bitWidth>
            </field>
            <field>
              <name>DBG_IWDG2</name>
              <bitOffset>19</bitOffset>
              <bitWidth>1</bitWidth>
            </field>
          </fields>
        </register>
      </registers>
    </peripheral>
  </peripherals>
</device>
